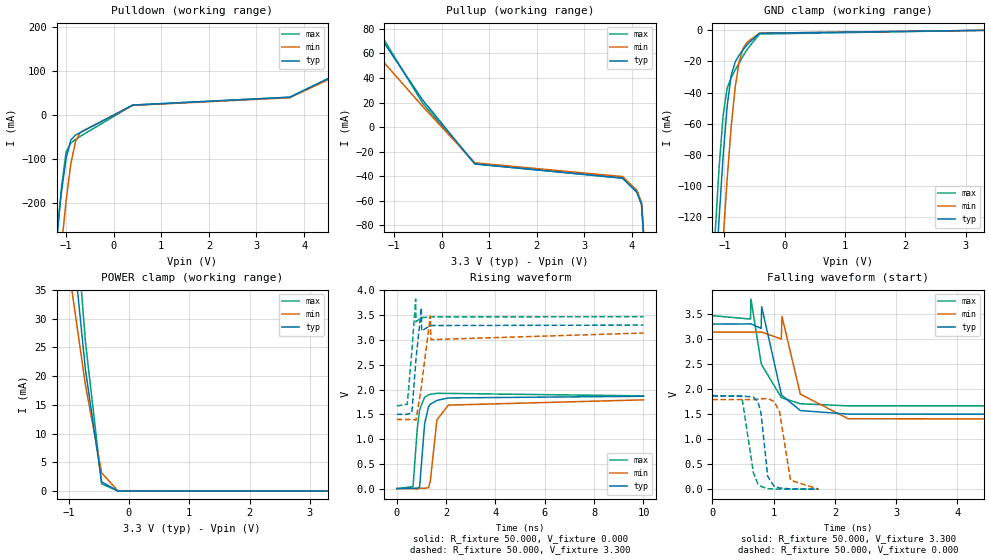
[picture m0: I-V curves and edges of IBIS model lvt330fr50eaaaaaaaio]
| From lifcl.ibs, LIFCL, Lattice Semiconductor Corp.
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[Model] lvt330fr50eaaaaaaaio
Model_type I/O
Polarity   Non-Inverting
Enable   Active-Low
Vinl =  0.800V
Vinh =  2.000V
Vmeas =  1.650V
Cref =  0.0F
Rref =  1.000M
Vref =  0.0V
C_comp   5.000pF   4.000pF   5.500pF
[Temperature Range]   25.000   0.125k   -40.000
[Voltage Range]   3.300V   3.140V   3.470V
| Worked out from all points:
|   slope of the pulldown table from 0 to 0.495 V, typ, clamps not added: 18.8 ohm
|   slope of the pullup table from 0 to 0.495 V, typ, clamps not added: 21.2 ohm
|   GND clamp passes 1 mA (typ) near -0.37 V on its own axis
|   POWER clamp passes 1 mA (typ) near -0.42 V on its own axis
|   rising waveform, R_fixture 50.000, V_fixture 0.000: 20-80 % time 189ps typ, 251ps min, 172ps max; typ from 0 V to 1.86 V
|   rising waveform, R_fixture 50.000, V_fixture 3.300: 20-80 % time 158ps typ, 181ps min, 159ps max; typ from 1.5 V to 3.3 V
|   falling waveform, R_fixture 50.000, V_fixture 3.300: 20-80 % time 246ps typ, 273ps min, 273ps max; typ from 3.3 V to 1.5 V
|   falling waveform, R_fixture 50.000, V_fixture 0.000: 20-80 % time 90.5ps typ, 117ps min, 120ps max; typ from 1.86 V to 0 V
[GND_clamp]
|Voltage   I(typ)   I(min)   I(max)
-3.3V     -1.887A    -1.873A    -1.902A
-1.156V   -166.9mA   -224mA     -132.1mA
-1.089V   -121.5mA   -178.4mA   -88.64mA
-1.022V   -81.05mA   -135.2mA   -54.94mA
-955mV    -48.98mA   -95.79mA   -37.15mA
-888mV    -28.98mA   -62.05mA   -30.42mA
-821mV    -20.23mA   -36.35mA   -25.49mA
-754mV    -15.89mA   -19.89mA   -20.81mA
-687mV    -12.34mA   -11.44mA   -16.31mA
-620mV    -9.094mA   -7.515mA   -12.09mA
-419mV    -1.869mA   -1.836mA   -2.383mA
3.3V      0A         0A         0A
[POWER_clamp]
|Voltage   I(typ)   I(min)   I(max)
-3.3V     170.3mA    115.9mA    227.4mA
-2.998V   139.6mA    100.3mA    196.3mA
-2.797V   125.9mA    92.2mA     179.4mA
-2.596V   123.5mA    86.45mA    171.5mA
-1.993V   123.5mA    84.93mA    171.5mA
-1.792V   123.5mA    84.93mA    159.6mA
-1.658V   116.4mA    83.68mA    147.1mA
-1.457V   98.28mA    72.65mA    124.1mA
-720mV    21.08mA    18.41mA    25.96mA
-452mV    1.573mA    3.148mA    1.229mA
-184mV    5.589uA    37.85uA    1.612uA
3.3V      0A         0A         0A
[Pulldown]
|Voltage   I(typ)   I(min)   I(max)
-3.3V     -2.705A    -3.161A    -3.578A
-1.2V     -276.6mA   -417.7mA   -294.4mA
-1.1V     -178.2mA   -301.6mA   -167mA
-1V       -98.8mA    -195.7mA   -84.47mA
-900mV    -56.61mA   -110.6mA   -63.45mA
-800mV    -45.22mA   -59.56mA   -55.68mA
-700mV    -39.68mA   -39.07mA   -48.23mA
400mV     22.65mA    21.97mA    22.65mA
3.7V      40.5mA     39.29mA    40.5mA
5.4V      129.6mA    125.7mA    129.6mA
6.1V      147.3mA    142.9mA    147.3mA
6.6V      199.6mA    193.6mA    199.6mA
[Pullup]
|Voltage   I(typ)   I(min)   I(max)
-3.3V     145.8mA    91.6mA     185mA
-2.8V     101.3mA    78.1mA     135.2mA
-2.7V     97.9mA     76.3mA     125.2mA
-2.5V     97mA       74.2mA     108.2mA
-1.7V     97mA       74.2mA     102.6mA
-400mV    22.21mA    16.98mA    19.58mA
700mV     -29.95mA   -29.05mA   -29.95mA
3.8V      -41.5mA    -40.26mA   -41.5mA
4.1V      -52.86mA   -51.28mA   -52.86mA
4.2V      -62.95mA   -61.07mA   -62.95mA
4.4V      -181.4mA   -176mA     -181.4mA
6.6V      -2.716A    -2.634A    -2.716A
[Ramp]
| variable   typ   min   max
dV/dt_r   1.114/0.188n   1.042/0.252n   1.122/0.171n
dV/dt_f   1.080/0.258n   1.047/0.280n   1.051/0.261n
R_load = 50.000
[Rising Waveform]
R_fixture = 50.000
V_fixture = 0.000
V_fixture_min = 0.000
V_fixture_max = 0.000
|  time   V(typ)   V(min)   V(max)
0s        377.2uV    1.038mV    347.4uV
659ps     7.312mV    1.207mV    39.78mV
830ps     10.37mV    -11.19mV   1.209V
925ps     30.48mV    9.316mV    1.594V
1.129ns   1.308V     5.562mV    1.843V
1.285ns   1.649V     19.08mV    1.892V
1.358ns   1.702V     145.7mV    1.904V
1.627ns   1.78V      1.387V     1.922V
2.092ns   1.83V      1.685V     1.921V
10ns      1.863V     1.791V     1.871V
[Rising Waveform]
R_fixture = 50.000
V_fixture = 3.300
V_fixture_min = 3.140
V_fixture_max = 3.470
|  time   V(typ)   V(min)   V(max)
0s        1.499V     1.395V     1.668V
425ps     1.5V       1.395V     1.702V
609ps     1.528V     1.396V     2.758V
766ps     2.524V     1.387V     3.825V
776ps     2.601V     1.382V     3.365V
996ps     3.649V     2.042V     3.449V
1.006ns   3.184V     2.104V     3.45V
1.361ns   3.291V     3.482V     3.464V
1.381ns   3.291V     3.007V     3.464V
10ns      3.3V       3.14V      3.47V
[Falling Waveform]
R_fixture = 50.000
V_fixture = 3.300
V_fixture_min = 3.140
V_fixture_max = 3.470
|  time   V(typ)   V(min)   V(max)
0s        3.3V       3.14V      3.47V
622ps     3.305V     3.141V     3.401V
630ps     3.305V     3.141V     3.801V
796ps     3.215V     3.141V     2.519V
805ps     3.648V     3.142V     2.487V
1.126ns   1.898V     3.002V     1.832V
1.136ns   1.875V     3.455V     1.825V
1.436ns   1.572V     1.9V       1.708V
2.215ns   1.501V     1.409V     1.666V
10ns      1.499V     1.395V     1.668V
[Falling Waveform]
R_fixture = 50.000
V_fixture = 0.000
V_fixture_min = 0.000
V_fixture_max = 0.000
|  time   V(typ)   V(min)   V(max)
0s        1.863V     1.791V     1.871V
480ps     1.864V     1.791V     1.854V
671ps     1.839V     1.792V     324mV
744ps     1.749V     1.798V     101.3mV
794ps     1.52V      1.806V     54.95mV
903ps     259mV      1.812V     11.54mV
1.006ns   60.22mV    1.757V     3.574mV
1.096ns   24.66mV    1.552V     1.787mV
1.276ns   4.022mV    178.9mV    677.5uV
1.731ns   377.2uV    1.038mV    347.4uV
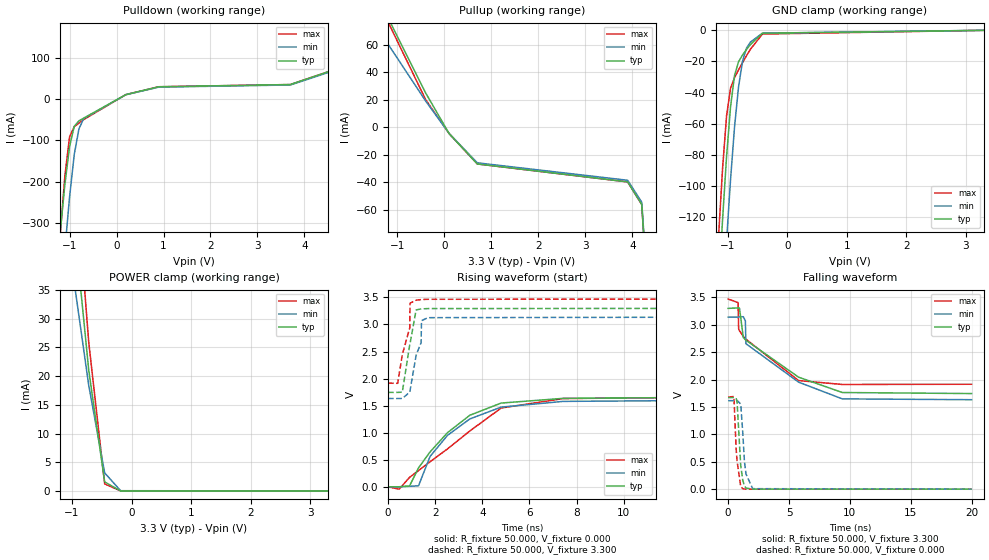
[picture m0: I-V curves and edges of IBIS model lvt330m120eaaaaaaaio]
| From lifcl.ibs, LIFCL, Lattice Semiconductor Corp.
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[Model] lvt330m120eaaaaaaaio
Model_type I/O
Polarity   Non-Inverting
Enable   Active-Low
Vinl =  0.800V
Vinh =  2.000V
Vmeas =  1.650V
Cref =  0.0F
Rref =  1.000M
Vref =  0.0V
C_comp   5.000pF   4.000pF   5.500pF
[Temperature Range]   25.000   0.125k   -40.000
[Voltage Range]   3.300V   3.140V   3.470V
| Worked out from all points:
|   slope of the pulldown table from 0 to 0.495 V, typ, clamps not added: 21.8 ohm
|   slope of the pullup table from 0 to 0.495 V, typ, clamps not added: 23.8 ohm
|   GND clamp passes 1 mA (typ) near -0.37 V on its own axis
|   POWER clamp passes 1 mA (typ) near -0.42 V on its own axis
|   rising waveform, R_fixture 50.000, V_fixture 0.000: 20-80 % time 2.26ns typ, 2.11ns min, 3ns max; typ from 0 V to 1.67 V
|   rising waveform, R_fixture 50.000, V_fixture 3.300: 20-80 % time 367ps typ, 414ps min, 378ps max; typ from 1.75 V to 3.3 V
|   falling waveform, R_fixture 50.000, V_fixture 3.300: 20-80 % time 4.62ns typ, 4.49ns min, 3.17ns max; typ from 3.3 V to 1.75 V
|   falling waveform, R_fixture 50.000, V_fixture 0.000: 20-80 % time 264ps typ, 296ps min, 268ps max; typ from 1.67 V to 0 V
[GND_clamp]
|Voltage   I(typ)   I(min)   I(max)
-3.3V     -1.887A    -1.873A    -1.902A
-1.156V   -166.9mA   -224mA     -132.1mA
-1.089V   -121.5mA   -178.4mA   -88.64mA
-1.022V   -81.05mA   -135.2mA   -54.94mA
-955mV    -48.98mA   -95.79mA   -37.15mA
-888mV    -28.98mA   -62.05mA   -30.42mA
-821mV    -20.23mA   -36.35mA   -25.49mA
-754mV    -15.89mA   -19.89mA   -20.81mA
-687mV    -12.34mA   -11.44mA   -16.31mA
-620mV    -9.094mA   -7.515mA   -12.09mA
-419mV    -1.869mA   -1.836mA   -2.383mA
3.3V      0A         0A         0A
[POWER_clamp]
|Voltage   I(typ)   I(min)   I(max)
-3.3V     170.3mA    115.9mA    227.4mA
-2.998V   139.6mA    100.3mA    196.3mA
-2.797V   125.9mA    92.2mA     179.4mA
-2.596V   123.5mA    86.45mA    171.5mA
-1.993V   123.5mA    84.93mA    171.5mA
-1.792V   123.5mA    84.93mA    159.6mA
-1.658V   116.4mA    83.68mA    147.1mA
-1.457V   98.28mA    72.65mA    124.1mA
-720mV    21.08mA    18.41mA    25.96mA
-452mV    1.573mA    3.148mA    1.229mA
-184mV    5.589uA    37.85uA    1.612uA
3.3V      0A         0A         0A
[Pulldown]
|Voltage   I(typ)   I(min)   I(max)
-3.3V     -3.149A    -3.823A    -4.032A
-1.2V     -321.9mA   -505.2mA   -330.2mA
-1.1V     -207.3mA   -364.7mA   -186.1mA
-1V       -114.9mA   -236.7mA   -91.33mA
-900mV    -65.88mA   -133.8mA   -66.67mA
-800mV    -52.62mA   -72.03mA   -57.94mA
-700mV    -46.18mA   -47.25mA   -49.68mA
200mV     10.72mA    10.4mA     10.72mA
900mV     29.61mA    28.72mA    29.61mA
3.7V      34.93mA    33.89mA    34.93mA
6.1V      127.1mA    123.3mA    127.1mA
6.6V      172.1mA    166.9mA    172.1mA
[Pullup]
|Voltage   I(typ)   I(min)   I(max)
-3.3V     163.1mA    102.5mA    206.9mA
-2.9V     119.9mA    89.7mA     162.7mA
-2.6V     108.3mA    84mA       129.4mA
-1.8V     108.3mA    83mA       117.8mA
-1.5V     99.9mA     75.77mA    97.6mA
-400mV    24.85mA    19mA       19.99mA
100mV     -4.725mA   -4.584mA   -4.725mA
700mV     -26.75mA   -25.94mA   -26.75mA
3.9V      -39.8mA    -38.61mA   -39.8mA
4.2V      -56.21mA   -54.53mA   -56.21mA
4.4V      -161.9mA   -157mA     -161.9mA
6.6V      -2.425A    -2.352A    -2.425A
[Ramp]
| variable   typ   min   max
dV/dt_r   1.003/2.268n   0.993/2.123n   1.008/3.000n
dV/dt_f   0.933/4.538n   0.904/4.241n   0.901/3.309n
R_load = 50.000
[Rising Waveform]
R_fixture = 50.000
V_fixture = 0.000
V_fixture_min = 0.000
V_fixture_max = 0.000
|  time   V(typ)   V(min)   V(max)
0s        336.5uV    1.157mV    387.9uV
472ps     567.3uV    1.185mV    -43.33mV
913ps     16.38mV    9.563mV    175.1mV
1.293ns   350.5mV    18.77mV    300.4mV
1.783ns   645.1mV    561.7mV    463.4mV
2.523ns   1.001V     951.4mV    700.8mV
3.472ns   1.323V     1.255V     1.032V
4.8ns     1.548V     1.473V     1.456V
7.436ns   1.635V     1.579V     1.631V
20ns      1.672V     1.615V     1.681V
[Rising Waveform]
R_fixture = 50.000
V_fixture = 3.300
V_fixture_min = 3.140
V_fixture_max = 3.470
|  time   V(typ)   V(min)   V(max)
0s        1.745V     1.633V     1.915V
408ps     1.745V     1.632V     1.913V
605ps     1.75V      1.633V     2.443V
921ps     2.629V     1.75V      2.94V
933ps     2.648V     1.776V     3.394V
1.191ns   3.269V     2.433V     3.449V
1.401ns   3.288V     2.663V     3.46V
1.421ns   3.289V     3.071V     3.461V
1.691ns   3.294V     3.126V     3.466V
20ns      3.3V       3.14V      3.47V
[Falling Waveform]
R_fixture = 50.000
V_fixture = 3.300
V_fixture_min = 3.140
V_fixture_max = 3.470
|  time   V(typ)   V(min)   V(max)
0s        3.3V       3.14V      3.47V
812ps     3.308V     3.141V     3.406V
863ps     3.31V      3.142V     2.926V
933ps     3.302V     3.145V     2.89V
1.246ns   2.767V     3.148V     2.789V
1.416ns   2.727V     3.071V     2.748V
1.456ns   2.719V     2.656V     2.738V
5.79ns    2.044V     1.953V     1.982V
9.38ns    1.764V     1.648V     1.911V
20ns      1.745V     1.633V     1.915V
[Falling Waveform]
R_fixture = 50.000
V_fixture = 0.000
V_fixture_min = 0.000
V_fixture_max = 0.000
|  time   V(typ)   V(min)   V(max)
0s        1.672V     1.615V     1.681V
470ps     1.673V     1.615V     1.691V
657ps     1.661V     1.615V     728mV
733ps     1.586V     1.62V      514.9mV
1.033ns   427.1mV    1.554V     47.86mV
1.199ns   165mV      1.034V     9.178mV
1.337ns   58.39mV    506.5mV    2.487mV
1.466ns   19.86mV    276.8mV    860.1uV
2.014ns   960.8uV    8.907mV    -151.5uV
20ns      336.5uV    1.157mV    387.9uV
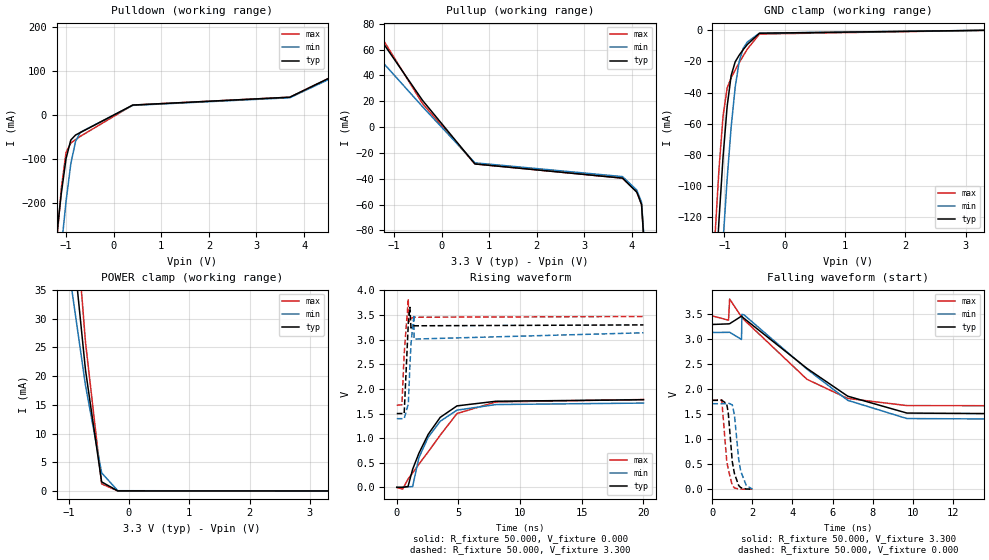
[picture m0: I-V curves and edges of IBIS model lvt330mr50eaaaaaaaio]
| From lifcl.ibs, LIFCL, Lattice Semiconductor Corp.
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[Model] lvt330mr50eaaaaaaaio
Model_type I/O
Polarity   Non-Inverting
Enable   Active-Low
Vinl =  0.800V
Vinh =  2.000V
Vmeas =  1.650V
Cref =  0.0F
Rref =  1.000M
Vref =  0.0V
C_comp   5.000pF   4.000pF   5.500pF
[Temperature Range]   25.000   0.125k   -40.000
[Voltage Range]   3.300V   3.140V   3.470V
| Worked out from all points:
|   slope of the pulldown table from 0 to 0.495 V, typ, clamps not added: 18.8 ohm
|   slope of the pullup table from 0 to 0.495 V, typ, clamps not added: 22.3 ohm
|   GND clamp passes 1 mA (typ) near -0.37 V on its own axis
|   POWER clamp passes 1 mA (typ) near -0.42 V on its own axis
|   rising waveform, R_fixture 50.000, V_fixture 0.000: 20-80 % time 2.26ns typ, 2.11ns min, 3.15ns max; typ from 0 V to 1.78 V
|   rising waveform, R_fixture 50.000, V_fixture 3.300: 20-80 % time 157ps typ, 180ps min, 164ps max; typ from 1.5 V to 3.3 V
|   falling waveform, R_fixture 50.000, V_fixture 3.300: 20-80 % time 3.71ns typ, 3.34ns min, 3.1ns max; typ from 3.3 V to 1.5 V
|   falling waveform, R_fixture 50.000, V_fixture 0.000: 20-80 % time 264ps typ, 292ps min, 265ps max; typ from 1.78 V to 0 V
[GND_clamp]
|Voltage   I(typ)   I(min)   I(max)
-3.3V     -1.887A    -1.873A    -1.902A
-1.156V   -166.9mA   -224mA     -132.1mA
-1.089V   -121.5mA   -178.4mA   -88.64mA
-1.022V   -81.05mA   -135.2mA   -54.94mA
-955mV    -48.98mA   -95.79mA   -37.15mA
-888mV    -28.98mA   -62.05mA   -30.42mA
-821mV    -20.23mA   -36.35mA   -25.49mA
-754mV    -15.89mA   -19.89mA   -20.81mA
-687mV    -12.34mA   -11.44mA   -16.31mA
-620mV    -9.094mA   -7.515mA   -12.09mA
-419mV    -1.869mA   -1.836mA   -2.383mA
3.3V      0A         0A         0A
[POWER_clamp]
|Voltage   I(typ)   I(min)   I(max)
-3.3V     170.3mA    115.9mA    227.4mA
-2.998V   139.6mA    100.3mA    196.3mA
-2.797V   125.9mA    92.2mA     179.4mA
-2.596V   123.5mA    86.45mA    171.5mA
-1.993V   123.5mA    84.93mA    171.5mA
-1.792V   123.5mA    84.93mA    159.6mA
-1.658V   116.4mA    83.68mA    147.1mA
-1.457V   98.28mA    72.65mA    124.1mA
-720mV    21.08mA    18.41mA    25.96mA
-452mV    1.573mA    3.148mA    1.229mA
-184mV    5.589uA    37.85uA    1.612uA
3.3V      0A         0A         0A
[Pulldown]
|Voltage   I(typ)   I(min)   I(max)
-3.3V     -2.705A    -3.161A    -3.578A
-1.2V     -276.6mA   -417.7mA   -294.4mA
-1.1V     -178.2mA   -301.6mA   -167mA
-1V       -98.8mA    -195.7mA   -84.47mA
-900mV    -56.61mA   -110.6mA   -63.45mA
-800mV    -45.22mA   -59.56mA   -55.68mA
-700mV    -39.68mA   -39.07mA   -48.23mA
400mV     22.65mA    21.97mA    22.65mA
3.7V      40.5mA     39.29mA    40.5mA
5.4V      129.6mA    125.7mA    129.6mA
6.1V      147.3mA    142.9mA    147.3mA
6.6V      199.6mA    193.6mA    199.6mA
[Pullup]
|Voltage   I(typ)   I(min)   I(max)
-3.3V     136mA      85.3mA     172.6mA
-2.8V     94.6mA     72.8mA     126.2mA
-2.7V     91.3mA     71.2mA     116.8mA
-2.5V     90.4mA     69.2mA     101mA
-1.7V     90.4mA     69.2mA     95.8mA
-400mV    20.72mA    15.84mA    18.27mA
700mV     -28.48mA   -27.62mA   -28.48mA
3.8V      -39.46mA   -38.28mA   -39.46mA
4.1V      -50.26mA   -48.75mA   -50.26mA
4.2V      -59.86mA   -58.06mA   -59.86mA
4.4V      -172.4mA   -167.2mA   -172.4mA
6.6V      -2.582A    -2.504A    -2.582A
[Ramp]
| variable   typ   min   max
dV/dt_r   1.064/2.268n   0.993/2.123n   1.109/3.147n
dV/dt_f   1.080/4.540n   1.047/4.241n   1.047/3.644n
R_load = 50.000
[Rising Waveform]
R_fixture = 50.000
V_fixture = 0.000
V_fixture_min = 0.000
V_fixture_max = 0.000
|  time   V(typ)   V(min)   V(max)
0s        377.2uV    1.038mV    347.4uV
472ps     569.5uV    1.068mV    -36.95mV
913ps     17.54mV    9.945mV    168.9mV
1.283ns   365.4mV    16.3mV     292.9mV
1.794ns   692.8mV    603.6mV    470.4mV
2.547ns   1.077V     1.018V     721.3mV
3.522ns   1.422V     1.342V     1.06V
4.883ns   1.655V     1.569V     1.5V
8.039ns   1.749V     1.682V     1.735V
20ns      1.78V      1.712V     1.784V
[Rising Waveform]
R_fixture = 50.000
V_fixture = 3.300
V_fixture_min = 3.140
V_fixture_max = 3.470
|  time   V(typ)   V(min)   V(max)
0s        1.499V     1.395V     1.668V
416ps     1.5V       1.395V     1.678V
599ps     1.496V     1.396V     2.705V
934ps     3.327V     1.697V     3.825V
951ps     3.383V     1.779V     3.361V
1.064ns   3.657V     2.476V     3.413V
1.152ns   3.238V     2.912V     3.433V
1.387ns   3.281V     3.506V     3.455V
1.401ns   3.282V     3.012V     3.456V
20ns      3.3V       3.14V      3.47V
[Falling Waveform]
R_fixture = 50.000
V_fixture = 3.300
V_fixture_min = 3.140
V_fixture_max = 3.470
|  time   V(typ)   V(min)   V(max)
0s        3.3V       3.14V      3.47V
808ps     3.312V     3.142V     3.386V
863ps     3.315V     3.144V     3.809V
1.456ns   3.467V     2.999V     3.45V
1.476ns   3.459V     3.503V     3.441V
1.576ns   3.423V     3.494V     3.396V
4.724ns   2.42V      2.405V     2.201V
6.76ns    1.863V     1.78V      1.818V
9.716ns   1.525V     1.415V     1.675V
20ns      1.499V     1.395V     1.668V
[Falling Waveform]
R_fixture = 50.000
V_fixture = 0.000
V_fixture_min = 0.000
V_fixture_max = 0.000
|  time   V(typ)   V(min)   V(max)
0s        1.78V      1.712V     1.784V
469ps     1.78V      1.712V     1.79V
713ps     1.715V     1.715V     584.9mV
793ps     1.533V     1.726V     397.6mV
996ps     547.3mV    1.689V     74.47mV
1.103ns   312.5mV    1.486V     24.8mV
1.314ns   74.44mV    601.1mV    3.478mV
1.414ns   31.93mV    363.3mV    1.641mV
1.694ns   3.358mV    75.28mV    435.7uV
2.005ns   377.2uV    1.038mV    347.4uV
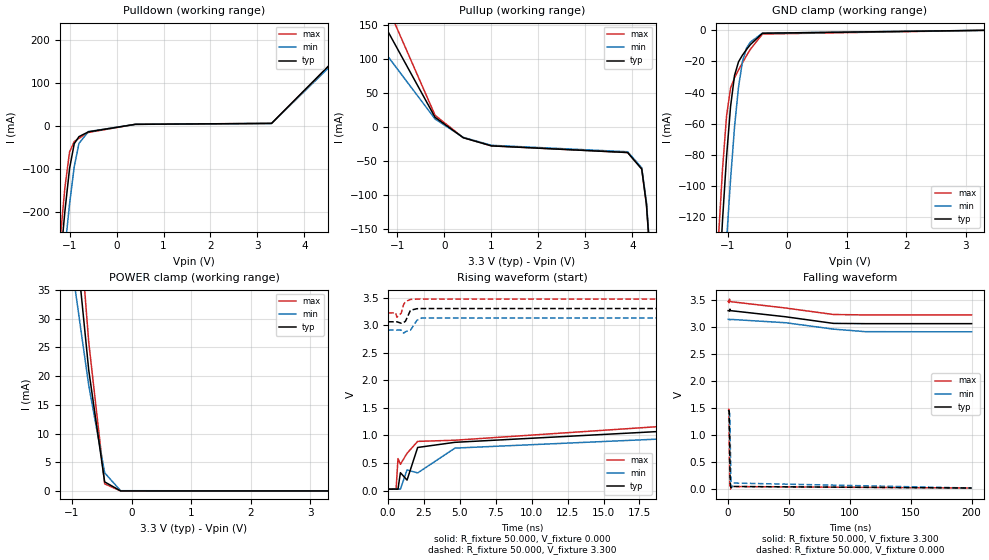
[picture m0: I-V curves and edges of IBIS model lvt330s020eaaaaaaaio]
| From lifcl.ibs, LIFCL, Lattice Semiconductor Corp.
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[Model] lvt330s020eaaaaaaaio
Model_type I/O
Polarity   Non-Inverting
Enable   Active-Low
Vinl =  0.800V
Vinh =  2.000V
Vmeas =  1.650V
Cref =  0.0F
Rref =  1.000M
Vref =  0.0V
C_comp   5.000pF   4.000pF   5.500pF
[Temperature Range]   25.000   0.125k   -40.000
[Voltage Range]   3.300V   3.140V   3.470V
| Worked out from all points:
|   slope of the pulldown table from 0 to 0.495 V, typ, clamps not added: 109 ohm
|   slope of the pullup table from 0 to 0.495 V, typ, clamps not added: 26.9 ohm
|   GND clamp passes 1 mA (typ) near -0.37 V on its own axis
|   POWER clamp passes 1 mA (typ) near -0.42 V on its own axis
|   rising waveform, R_fixture 50.000, V_fixture 0.000: 20-80 % time 24ns typ, 34.7ns min, 18.7ns max; typ from 0.025 V to 1.45 V
|   rising waveform, R_fixture 50.000, V_fixture 3.300: 20-80 % time 218ps typ, 298ps min, 218ps max; typ from 3.06 V to 3.3 V
|   falling waveform, R_fixture 50.000, V_fixture 3.300: 20-80 % time 42.3ns typ, 48.9ns min, 46.8ns max; typ from 3.3 V to 3.06 V
|   falling waveform, R_fixture 50.000, V_fixture 0.000: 20-80 % time 480ps typ, 680ps min, 393ps max; typ from 1.45 V to 0.025 V
[GND_clamp]
|Voltage   I(typ)   I(min)   I(max)
-3.3V     -1.887A    -1.873A    -1.902A
-1.156V   -166.9mA   -224mA     -132.1mA
-1.089V   -121.5mA   -178.4mA   -88.64mA
-1.022V   -81.05mA   -135.2mA   -54.94mA
-955mV    -48.98mA   -95.79mA   -37.15mA
-888mV    -28.98mA   -62.05mA   -30.42mA
-821mV    -20.23mA   -36.35mA   -25.49mA
-754mV    -15.89mA   -19.89mA   -20.81mA
-687mV    -12.34mA   -11.44mA   -16.31mA
-620mV    -9.094mA   -7.515mA   -12.09mA
-419mV    -1.869mA   -1.836mA   -2.383mA
3.3V      0A         0A         0A
[POWER_clamp]
|Voltage   I(typ)   I(min)   I(max)
-3.3V     170.3mA    115.9mA    227.4mA
-2.998V   139.6mA    100.3mA    196.3mA
-2.797V   125.9mA    92.2mA     179.4mA
-2.596V   123.5mA    86.45mA    171.5mA
-1.993V   123.5mA    84.93mA    171.5mA
-1.792V   123.5mA    84.93mA    159.6mA
-1.658V   116.4mA    83.68mA    147.1mA
-1.457V   98.28mA    72.65mA    124.1mA
-720mV    21.08mA    18.41mA    25.96mA
-452mV    1.573mA    3.148mA    1.229mA
-184mV    5.589uA    37.85uA    1.612uA
3.3V      0A         0A         0A
[Pulldown]
|Voltage   I(typ)   I(min)   I(max)
-3.3V     -3.198A    -3.088A    -3.286A
-1.2V     -320.1mA   -403.9mA   -266.3mA
-1.1V     -200.2mA   -288.6mA   -145.1mA
-1V       -99.68mA   -182.4mA   -61.1mA
-900mV    -41.7mA    -95.18mA   -37.11mA
-800mV    -25.46mA   -41.35mA   -29.28mA
-600mV    -14.31mA   -13.67mA   -15.59mA
400mV     3.234mA    3.137mA    3.234mA
3.3V      5.419mA    5.256mA    5.419mA
5V        192.3mA    186.5mA    192.3mA
6.3V      201.8mA    195.7mA    201.8mA
6.6V      230.5mA    223.6mA    230.5mA
[Pullup]
|Voltage   I(typ)   I(min)   I(max)
-3.3V     225.4mA    159.1mA    289.5mA
-2.6V     172mA      126.4mA    227.2mA
-1.5V     172mA      124.8mA    215mA
-1.3V     152.6mA    112.6mA    190.7mA
-200mV    14.46mA    11.99mA    17.47mA
400mV     -15.49mA   -15.03mA   -15.49mA
1V        -27.48mA   -26.65mA   -27.48mA
3.9V      -37.26mA   -36.14mA   -37.26mA
4.2V      -61.49mA   -59.65mA   -61.49mA
4.3V      -113.5mA   -110.1mA   -113.5mA
4.4V      -210.4mA   -204.1mA   -210.4mA
6.6V      -3.205A    -3.109A    -3.205A
[Ramp]
| variable   typ   min   max
dV/dt_r   0.841/24.619n   0.828/35.559n   0.858/18.674n
dV/dt_f   0.144/42.436n   0.139/49.064n   0.150/46.882n
R_load = 50.000
[Rising Waveform]
R_fixture = 50.000
V_fixture = 0.000
V_fixture_min = 0.000
V_fixture_max = 0.000
|  time   V(typ)   V(min)   V(max)
0s        25.4mV     24.94mV    25.4mV
560ps     25.54mV    25.03mV    26.53mV
690ps     24.52mV    24.64mV    578.7mV
860ps     323.5mV    25.32mV    475.7mV
1.32ns    188.9mV    373.3mV    675.2mV
2.06ns    780.8mV    319.1mV    890.8mV
4.66ns    874.3mV    769.4mV    912.3mV
31.5ns    1.245V     1.079V     1.38V
72.96ns   1.432V     1.372V     1.44V
200ns     1.452V     1.405V     1.455V
[Rising Waveform]
R_fixture = 50.000
V_fixture = 3.300
V_fixture_min = 3.140
V_fixture_max = 3.470
|  time   V(typ)   V(min)   V(max)
0s        3.06V      2.909V     3.221V
530ps     3.06V      2.909V     3.223V
610ps     3.06V      2.909V     3.142V
910ps     3.034V     2.91V      3.213V
1.08ns    3.045V     2.854V     3.371V
1.21ns    3.07V      2.88V      3.426V
1.56ns    3.269V     2.908V     3.465V
2.01ns    3.297V     3.087V     3.471V
2.33ns    3.3V       3.128V     3.472V
200ns     3.3V       3.14V      3.47V
[Falling Waveform]
R_fixture = 50.000
V_fixture = 3.300
V_fixture_min = 3.140
V_fixture_max = 3.470
|  time   V(typ)   V(min)   V(max)
0s        3.3V       3.14V      3.47V
680ps     3.3V       3.139V     3.48V
760ps     3.3V       3.141V     3.443V
1.09ns    3.29V      3.14V      3.514V
1.49ns    3.328V     3.126V     3.472V
1.97ns    3.3V       3.139V     3.466V
47.18ns   3.187V     3.077V     3.349V
86.45ns   3.065V     2.959V     3.229V
112.8ns   3.06V      2.912V     3.221V
200ns     3.06V      2.909V     3.221V
[Falling Waveform]
R_fixture = 50.000
V_fixture = 0.000
V_fixture_min = 0.000
V_fixture_max = 0.000
|  time   V(typ)   V(min)   V(max)
0s        1.452V     1.405V     1.455V
630ps     1.452V     1.405V     1.479V
880ps     1.449V     1.406V     916.2mV
1.26ns    742mV      1.407V     205.3mV
1.57ns    250.8mV    1.07V      42.33mV
1.91ns    56.56mV    667mV      4.242mV
2.35ns    33.6mV     130mV      28.17mV
2.71ns    47.45mV    31.11mV    55.71mV
4.91ns    53.88mV    117mV      51.82mV
200ns     25.15mV    24.94mV    25.4mV
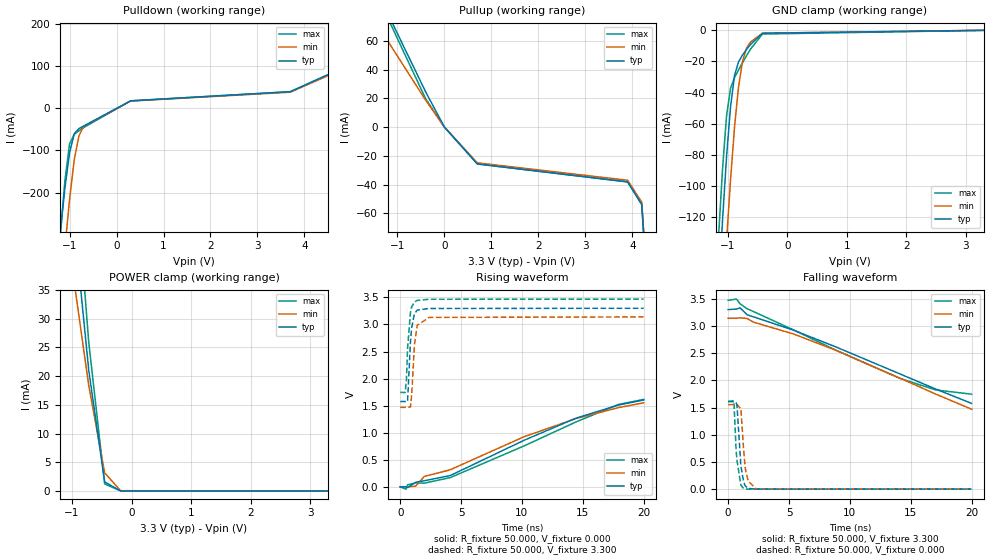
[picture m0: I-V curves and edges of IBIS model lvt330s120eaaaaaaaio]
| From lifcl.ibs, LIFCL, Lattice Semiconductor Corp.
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[Model] lvt330s120eaaaaaaaio
Model_type I/O
Polarity   Non-Inverting
Enable   Active-Low
Vinl =  0.800V
Vinh =  2.000V
Vmeas =  1.650V
Cref =  0.0F
Rref =  1.000M
Vref =  0.0V
C_comp   5.000pF   4.000pF   5.500pF
[Temperature Range]   25.000   0.125k   -40.000
[Voltage Range]   3.300V   3.140V   3.470V
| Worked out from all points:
|   slope of the pulldown table from 0 to 0.495 V, typ, clamps not added: 19.6 ohm
|   slope of the pullup table from 0 to 0.495 V, typ, clamps not added: 24.8 ohm
|   GND clamp passes 1 mA (typ) near -0.37 V on its own axis
|   POWER clamp passes 1 mA (typ) near -0.42 V on its own axis
|   rising waveform, R_fixture 50.000, V_fixture 0.000: 20-80 % time 9.3ns typ, 10.1ns min, 9.69ns max; typ from 0 V to 1.6 V
|   rising waveform, R_fixture 50.000, V_fixture 3.300: 20-80 % time 253ps typ, 287ps min, 249ps max; typ from 1.58 V to 3.3 V
|   falling waveform, R_fixture 50.000, V_fixture 3.300: 20-80 % time 11.2ns typ, 10.5ns min, 10ns max; typ from 3.3 V to 1.58 V
|   falling waveform, R_fixture 50.000, V_fixture 0.000: 20-80 % time 287ps typ, 322ps min, 284ps max; typ from 1.6 V to 0 V
[GND_clamp]
|Voltage   I(typ)   I(min)   I(max)
-3.3V     -1.887A    -1.873A    -1.902A
-1.156V   -166.9mA   -224mA     -132.1mA
-1.089V   -121.5mA   -178.4mA   -88.64mA
-1.022V   -81.05mA   -135.2mA   -54.94mA
-955mV    -48.98mA   -95.79mA   -37.15mA
-888mV    -28.98mA   -62.05mA   -30.42mA
-821mV    -20.23mA   -36.35mA   -25.49mA
-754mV    -15.89mA   -19.89mA   -20.81mA
-687mV    -12.34mA   -11.44mA   -16.31mA
-620mV    -9.094mA   -7.515mA   -12.09mA
-419mV    -1.869mA   -1.836mA   -2.383mA
3.3V      0A         0A         0A
[POWER_clamp]
|Voltage   I(typ)   I(min)   I(max)
-3.3V     170.3mA    115.9mA    227.4mA
-2.998V   139.6mA    100.3mA    196.3mA
-2.797V   125.9mA    92.2mA     179.4mA
-2.596V   123.5mA    86.45mA    171.5mA
-1.993V   123.5mA    84.93mA    171.5mA
-1.792V   123.5mA    84.93mA    159.6mA
-1.658V   116.4mA    83.68mA    147.1mA
-1.457V   98.28mA    72.65mA    124.1mA
-720mV    21.08mA    18.41mA    25.96mA
-452mV    1.573mA    3.148mA    1.229mA
-184mV    5.589uA    37.85uA    1.612uA
3.3V      0A         0A         0A
[Pulldown]
|Voltage   I(typ)   I(min)   I(max)
-3.3V     -2.9A      -3.494A    -3.741A
-1.2V     -296.5mA   -461.8mA   -306.4mA
-1.1V     -190.9mA   -333.3mA   -172.7mA
-1V       -105.8mA   -216.3mA   -84.75mA
-900mV    -60.68mA   -122.3mA   -61.87mA
-800mV    -48.47mA   -65.84mA   -53.77mA
-700mV    -42.53mA   -43.19mA   -46.1mA
300mV     17.14mA    16.62mA    17.14mA
3.7V      38.76mA    37.6mA     38.76mA
5.4V      124mA      120.3mA    124mA
6.1V      141mA      136.8mA    141mA
6.6V      191mA      185.3mA    191mA
[Pullup]
|Voltage   I(typ)   I(min)   I(max)
-3.3V     161.5mA    101.5mA    205mA
-2.9V     118.7mA    88.9mA     161.2mA
-2.6V     107.3mA    83.1mA     128.2mA
-1.8V     107.3mA    82.2mA     116.7mA
-1.5V     99mA       75.05mA    96.6mA
-400mV    24.61mA    18.82mA    19.8mA
0V        28.23nA    226.3nA    28.23nA
700mV     -25.65mA   -24.88mA   -25.65mA
3.9V      -38.17mA   -37.03mA   -38.17mA
4.2V      -53.91mA   -52.29mA   -53.91mA
4.4V      -155.3mA   -150.6mA   -155.3mA
6.6V      -2.325A    -2.256A    -2.325A
[Ramp]
| variable   typ   min   max
dV/dt_r   0.964/9.286n   0.893/10.057n   0.969/9.681n
dV/dt_f   0.993/11.242n   1.003/10.537n   1.035/10.055n
R_load = 50.000
[Rising Waveform]
R_fixture = 50.000
V_fixture = 0.000
V_fixture_min = 0.000
V_fixture_max = 0.000
|  time   V(typ)   V(min)   V(max)
0s        358.2uV    1.072mV    359.1uV
471ps     602.5uV    1.1mV      -43.61mV
605ps     -14.7mV    1.213mV    37.39mV
1.263ns   83.32mV    11.75mV    71.54mV
1.983ns   112.5mV    192.8mV    68.28mV
4.088ns   205.9mV    313.2mV    168.3mV
10.15ns   857.2mV    923.2mV    753.4mV
14.43ns   1.268V     1.261V     1.198V
17.91ns   1.51V      1.462V     1.521V
20ns      1.605V     1.553V     1.615V
[Rising Waveform]
R_fixture = 50.000
V_fixture = 3.300
V_fixture_min = 3.140
V_fixture_max = 3.470
|  time   V(typ)   V(min)   V(max)
0s        1.576V     1.469V     1.745V
408ps     1.576V     1.468V     1.743V
510ps     1.577V     1.469V     1.988V
602ps     1.576V     1.47V      2.565V
843ps     2.692V     1.476V     3.229V
941ps     2.946V     1.712V     3.325V
1.171ns   3.2V       2.634V     3.416V
1.391ns   3.265V     2.984V     3.445V
2.368ns   3.296V     3.131V     3.466V
20ns      3.3V       3.14V      3.47V
[Falling Waveform]
R_fixture = 50.000
V_fixture = 3.300
V_fixture_min = 3.140
V_fixture_max = 3.470
|  time   V(typ)   V(min)   V(max)
0s        3.3V       3.14V      3.47V
688ps     3.309V     3.14V      3.493V
973ps     3.332V     3.149V     3.407V
1.567ns   3.204V     3.136V     3.314V
2.067ns   3.167V     3.07V      3.265V
5.387ns   2.92V      2.85V      2.924V
8.879ns   2.611V     2.549V     2.551V
14.12ns   2.117V     2.039V     2.035V
17.05ns   1.84V      1.747V     1.823V
20ns      1.576V     1.469V     1.745V
[Falling Waveform]
R_fixture = 50.000
V_fixture = 0.000
V_fixture_min = 0.000
V_fixture_max = 0.000
|  time   V(typ)   V(min)   V(max)
0s        1.605V     1.553V     1.615V
471ps     1.606V     1.553V     1.623V
657ps     1.595V     1.553V     704.6mV
726ps     1.532V     1.557V     528.2mV
1.046ns   422.9mV    1.475V     70.42mV
1.278ns   127mV      701mV      10.29mV
1.406ns   59.54mV    380mV      3.453mV
1.636ns   13.28mV    152.4mV    334uV
2.293ns   1.016mV    5.7mV      -310.3uV
20ns      358.2uV    1.072mV    359.1uV
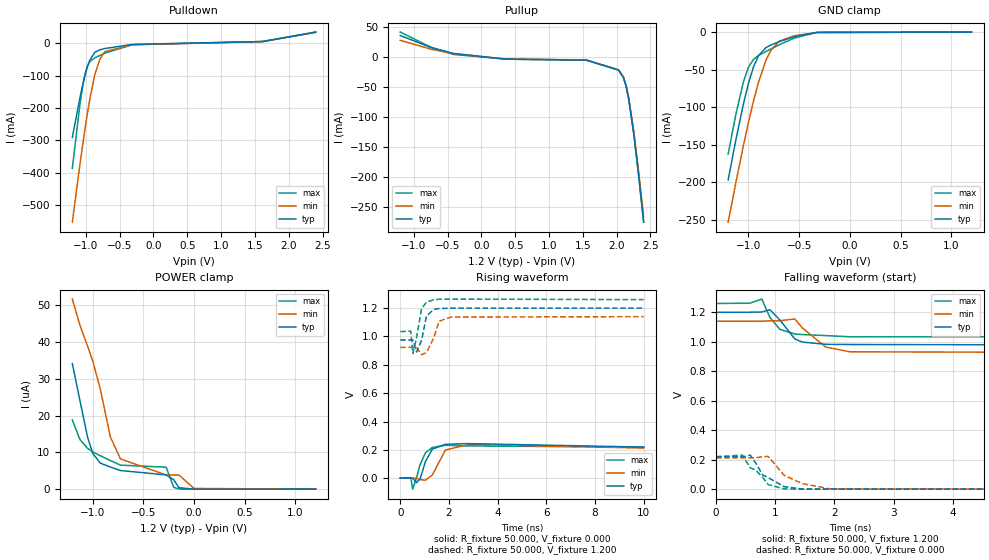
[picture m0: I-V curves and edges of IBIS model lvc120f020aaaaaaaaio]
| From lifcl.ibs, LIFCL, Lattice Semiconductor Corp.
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|Model lvc120f020aaaaaaaaio
[Model] lvc120f020aaaaaaaaio
Model_type I/O
Polarity   Non-Inverting
Enable   Active-Low
Vinl =  0.420V
Vinh =  0.780V
Vmeas =  0.600V
Cref =  0.0F
Rref =  1.000M
Vref =  0.0V
C_comp   5.000pF   4.000pF   5.500pF
[Temperature Range]   25.000   0.125k   -40.000
[Voltage Range]   1.200V   1.140V   1.260V
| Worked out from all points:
|   slope of the pulldown table from 0 to 0.18 V, typ, clamps not added: 97.7 ohm
|   slope of the pullup table from 0 to 0.18 V, typ, clamps not added: 89 ohm
|   GND clamp passes 1 mA (typ) near -0.37 V on its own axis
|   rising waveform, R_fixture 50.000, V_fixture 0.000: 20-80 % time 253ps typ, 327ps min, 285ps max; typ from 0 V to 0.219 V
|   rising waveform, R_fixture 50.000, V_fixture 1.200: 20-80 % time 174ps typ, 208ps min, 198ps max; typ from 0.975 V to 1.2 V
|   falling waveform, R_fixture 50.000, V_fixture 1.200: 20-80 % time 261ps typ, 389ps min, 241ps max; typ from 1.2 V to 0.975 V
|   falling waveform, R_fixture 50.000, V_fixture 0.000: 20-80 % time 370ps typ, 425ps min, 307ps max; typ from 0.219 V to 0 V
[GND_clamp]
|Voltage   I(typ)   I(min)   I(max)
-1.2V     -197mA     -253.2mA   -162.4mA
-1.125V   -144.2mA   -201.1mA   -110.1mA
-1.05V    -95.99mA   -151.4mA   -66.59mA
-1V       -68.36mA   -120.3mA   -46.7mA
-950mV    -46.27mA   -91.66mA   -36.22mA
-900mV    -31.17mA   -66.32mA   -31.23mA
-825mV    -20.42mA   -36.76mA   -25.67mA
-775mV    -17.01mA   -23.52mA   -22.16mA
-700mV    -12.93mA   -12.4mA    -17.08mA
-550mV    -6.031mA   -4.974mA   -8.039mA
-325mV    -407uA     -583.3uA   -420.6uA
1.2V      0A         0A         0A
[POWER_clamp]
|Voltage   I(typ)   I(min)   I(max)
-1.2V     34.12uA    51.64uA    18.84uA
-1.125V   24.08uA    44.51uA    13.48uA
-1.05V    14.15uA    38.9uA     11.09uA
-1V       9.797uA    34.91uA    10.18uA
-925mV    7.083uA    27.3uA     9.093uA
-825mV    6.019uA    14.19uA    7.781uA
-725mV    5.062uA    8.208uA    6.524uA
-275mV    3.872uA    3.86uA     5.968uA
-200mV    2.568uA    3.86uA     486.4nA
-150mV    410.4nA    3.86uA     46.48nA
0V        5.44nA     194.2nA    358.2pA
1.2V      0A         0A         0A
[Pulldown]
|Voltage   I(typ)   I(min)   I(max)
-1.2V     -291.3mA   -552.3mA   -386.2mA
-1.089V   -169.9mA   -376.3mA   -191.3mA
-1.052V   -133.7mA   -320.9mA   -138.7mA
-1.015V   -101mA     -267.7mA   -97.62mA
-978mV    -73.34mA   -217.5mA   -70.42mA
-941mV    -51.81mA   -171.5mA   -56.14mA
-867mV    -27.81mA   -96.38mA   -45.05mA
-793mV    -20.11mA   -48.94mA   -37.59mA
-719mV    -16.32mA   -25.85mA   -30.51mA
-312mV    -3.502mA   -4.516mA   -4.47mA
1.612V    5.286mA    5.127mA    5.286mA
2.4V      34.45mA    33.42mA    34.45mA
[Pullup]
|Voltage   I(typ)   I(min)   I(max)
-1.2V     36.04mA    28.03mA    41.8mA
-745mV    16.04mA    13.23mA    16.4mA
-412mV    6.21mA     5.595mA    4.51mA
365mV     -3.438mA   -3.335mA   -3.438mA
1.549V    -4.915mA   -4.768mA   -4.915mA
2.03V     -21.71mA   -21.06mA   -21.71mA
2.104V    -34.91mA   -33.87mA   -34.91mA
2.141V    -49.04mA   -47.57mA   -49.04mA
2.178V    -69.41mA   -67.32mA   -69.41mA
2.252V    -126.5mA   -122.7mA   -126.5mA
2.326V    -197.6mA   -191.7mA   -197.6mA
2.4V      -275.7mA   -267.4mA   -275.7mA
[Ramp]
| variable   typ   min   max
dV/dt_r   0.132/0.254n   0.127/0.330n   0.131/0.288n
dV/dt_f   0.134/0.264n   0.130/0.386n   0.135/0.242n
R_load = 50.000
[Rising Waveform]
R_fixture = 50.000
V_fixture = 0.000
V_fixture_min = 0.000
V_fixture_max = 0.000
|  time   V(typ)   V(min)   V(max)
0s        23.11uV    696.4uV    1mV
430ps     49.23uV    580.4uV    3.947mV
514ps     57.3uV     684.8uV    -77.41mV
663ps     -31.34mV   774.8uV    -595.1uV
814ps     -6.45mV    -9.582mV   94.96mV
1.033ns   115.9mV    -14.38mV   178.6mV
1.315ns   204.5mV    21.93mV    216.4mV
1.855ns   239.4mV    198.8mV    232.3mV
2.815ns   244.1mV    238.1mV    227.5mV
10ns      219.4mV    212.6mV    219.6mV
[Rising Waveform]
R_fixture = 50.000
V_fixture = 1.200
V_fixture_min = 1.140
V_fixture_max = 1.260
|  time   V(typ)   V(min)   V(max)
0s        975.4mV    923.3mV    1.034V
431ps     975.4mV    923.2mV    1.038V
519ps     975.4mV    923.3mV    879.5mV
667ps     890.2mV    923.4mV    988.8mV
876ps     972mV      871.7mV    1.196V
1.075ns   1.143V     885.7mV    1.242V
1.376ns   1.191V     989.3mV    1.259V
1.596ns   1.197V     1.108V     1.263V
2.085ns   1.2V       1.137V     1.264V
10ns      1.2V       1.14V      1.26V
[Falling Waveform]
R_fixture = 50.000
V_fixture = 1.200
V_fixture_min = 1.140
V_fixture_max = 1.260
|  time   V(typ)   V(min)   V(max)
0s        1.2V       1.14V      1.26V
574ps     1.201V     1.14V      1.262V
774ps     1.202V     1.139V     1.29V
910ps     1.218V     1.143V     1.166V
1.08ns    1.148V     1.143V     1.084V
1.332ns   1.019V     1.155V     1.053V
1.462ns   997.7mV    1.093V     1.049V
1.852ns   982.9mV    964.6mV    1.042V
2.262ns   981.4mV    932mV      1.034V
10ns      975.4mV    923.3mV    1.034V
[Falling Waveform]
R_fixture = 50.000
V_fixture = 0.000
V_fixture_min = 0.000
V_fixture_max = 0.000
|  time   V(typ)   V(min)   V(max)
0s        219.4mV    212.6mV    219.6mV
449ps     218.8mV    212.5mV    230.3mV
580ps     230.7mV    212.3mV    143.8mV
664ps     181mV      211.9mV    131.1mV
789ps     95.53mV    219.8mV    79.36mV
883ps     77.29mV    221.5mV    29.69mV
1.15ns    16.22mV    93.54mV    1.117mV
1.463ns   -280.5uV   36.09mV    -840.7uV
1.932ns   -886.1uV   1.117mV    -695uV
10ns      23.11uV    696.4uV    1mV
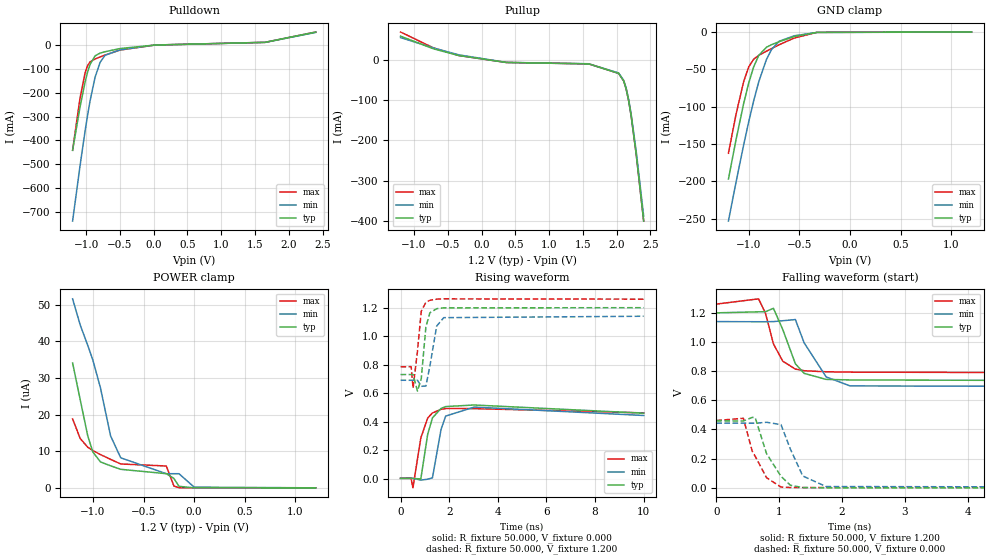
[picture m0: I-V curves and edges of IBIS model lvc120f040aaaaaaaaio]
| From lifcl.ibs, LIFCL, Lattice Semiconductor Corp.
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[Model] lvc120f040aaaaaaaaio
Model_type I/O
Polarity   Non-Inverting
Enable   Active-Low
Vinl =  0.420V
Vinh =  0.780V
Vmeas =  0.600V
Cref =  0.0F
Rref =  1.000M
Vref =  0.0V
C_comp   5.000pF   4.000pF   5.500pF
[Temperature Range]   25.000   0.125k   -40.000
[Voltage Range]   1.200V   1.140V   1.260V
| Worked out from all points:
|   slope of the pulldown table from 0 to 0.18 V, typ, clamps not added: 45.6 ohm
|   slope of the pullup table from 0 to 0.18 V, typ, clamps not added: 43.3 ohm
|   GND clamp passes 1 mA (typ) near -0.37 V on its own axis
|   rising waveform, R_fixture 50.000, V_fixture 0.000: 20-80 % time 246ps typ, 243ps min, 274ps max; typ from 0 V to 0.459 V
|   rising waveform, R_fixture 50.000, V_fixture 1.200: 20-80 % time 156ps typ, 259ps min, 149ps max; typ from 0.731 V to 1.2 V
|   falling waveform, R_fixture 50.000, V_fixture 1.200: 20-80 % time 264ps typ, 350ps min, 232ps max; typ from 1.2 V to 0.731 V
|   falling waveform, R_fixture 50.000, V_fixture 0.000: 20-80 % time 286ps typ, 251ps min, 271ps max; typ from 0.459 V to 0 V
[GND_clamp]
|Voltage   I(typ)   I(min)   I(max)
-1.2V     -197mA     -253.2mA   -162.4mA
-1.125V   -144.2mA   -201.1mA   -110.1mA
-1.05V    -95.99mA   -151.4mA   -66.59mA
-1V       -68.36mA   -120.3mA   -46.7mA
-950mV    -46.27mA   -91.66mA   -36.22mA
-900mV    -31.17mA   -66.32mA   -31.23mA
-825mV    -20.42mA   -36.76mA   -25.67mA
-775mV    -17.01mA   -23.52mA   -22.16mA
-700mV    -12.93mA   -12.4mA    -17.08mA
-550mV    -6.031mA   -4.974mA   -8.039mA
-325mV    -407uA     -583.3uA   -420.6uA
1.2V      0A         0A         0A
[POWER_clamp]
|Voltage   I(typ)   I(min)   I(max)
-1.2V     34.12uA    51.64uA    18.84uA
-1.125V   24.08uA    44.51uA    13.48uA
-1.05V    14.15uA    38.9uA     11.09uA
-1V       9.797uA    34.91uA    10.18uA
-925mV    7.083uA    27.3uA     9.093uA
-825mV    6.019uA    14.19uA    7.781uA
-725mV    5.062uA    8.208uA    6.524uA
-275mV    3.872uA    3.86uA     5.968uA
-200mV    2.568uA    3.86uA     486.4nA
-150mV    410.4nA    3.86uA     46.48nA
0V        5.44nA     194.2nA    358.2pA
1.2V      0A         0A         0A
[Pulldown]
|Voltage   I(typ)   I(min)   I(max)
-1.2V     -441.6mA   -738mA     -440.6mA
-1.089V   -258.3mA   -504.2mA   -220.2mA
-1.015V   -154.4mA   -360.1mA   -115.5mA
-978mV    -112.8mA   -293.7mA   -85.62mA
-941mV    -80.57mA   -233mA     -70.15mA
-867mV    -44.83mA   -134.2mA   -57.93mA
-793mV    -33.38mA   -72.24mA   -49.48mA
-719mV    -27.62mA   -42.24mA   -41.41mA
-497mV    -14.12mA   -19.88mA   -20.43mA
21mV      490.7uA    476uA      490.7uA
1.649V    11.87mA    11.51mA    11.87mA
2.4V      55.07mA    53.42mA    55.07mA
[Pullup]
|Voltage   I(typ)   I(min)   I(max)
-1.2V     57.93mA    54.4mA     68.11mA
-708mV    26.38mA    28.5mA     28.67mA
-338mV    9.973mA    11.7mA     10.05mA
365mV     -7.17mA    -6.955mA   -7.17mA
1.586V    -10.69mA   -10.37mA   -10.69mA
2.03V     -34.23mA   -33.21mA   -34.23mA
2.104V    -52.91mA   -51.32mA   -52.91mA
2.141V    -73.01mA   -70.82mA   -73.01mA
2.178V    -102.1mA   -99.05mA   -102.1mA
2.215V    -139.7mA   -135.5mA   -139.7mA
2.289V    -233.6mA   -226.6mA   -233.6mA
2.4V      -399.4mA   -387.4mA   -399.4mA
[Ramp]
| variable   typ   min   max
dV/dt_r   0.275/0.246n   0.275/0.244n   0.275/0.276n
dV/dt_f   0.282/0.265n   0.267/0.351n   0.285/0.237n
R_load = 50.000
[Rising Waveform]
R_fixture = 50.000
V_fixture = 0.000
V_fixture_min = 0.000
V_fixture_max = 0.000
|  time   V(typ)   V(min)   V(max)
0s        37.02uV    2.19mV     2.165mV
430ps     71.45uV    2.081mV    4.903mV
510ps     14.78uV    2.198mV    -65.43mV
835ps     -2.479mV   -11.13mV   285.2mV
1.117ns   310.6mV    -4.693mV   425.2mV
1.313ns   426.1mV    4.967mV    460.6mV
1.667ns   492.6mV    345.5mV    486.3mV
1.857ns   505.5mV    438.6mV    491.4mV
3.03ns    516.5mV    501.8mV    491.2mV
10ns      458.9mV    442.9mV    461mV
[Rising Waveform]
R_fixture = 50.000
V_fixture = 1.200
V_fixture_min = 1.140
V_fixture_max = 1.260
|  time   V(typ)   V(min)   V(max)
0s        730.5mV    690.3mV    784.2mV
437ps     730.5mV    690.2mV    786mV
517ps     730.5mV    690.3mV    635.7mV
697ps     614.1mV    690.2mV    895.3mV
853ps     701.5mV    647.6mV    1.175V
1.043ns   1.065V     649.8mV    1.238V
1.207ns   1.164V     789.1mV    1.252V
1.487ns   1.193V     1.071V     1.26V
1.777ns   1.199V     1.13V      1.262V
10ns      1.2V       1.14V      1.26V
[Falling Waveform]
R_fixture = 50.000
V_fixture = 1.200
V_fixture_min = 1.140
V_fixture_max = 1.260
|  time   V(typ)   V(min)   V(max)
0s        1.2V       1.14V      1.26V
673ps     1.207V     1.139V     1.296V
783ps     1.208V     1.139V     1.198V
910ps     1.231V     1.14V      986.9mV
1.059ns   1.085V     1.146V     868.1mV
1.259ns   850.8mV    1.154V     814.1mV
1.399ns   784.7mV    994.1mV    802.8mV
1.749ns   743.4mV    760.5mV    795.5mV
2.129ns   739.6mV    698.7mV    793.3mV
10ns      730.5mV    690.3mV    784.2mV
[Falling Waveform]
R_fixture = 50.000
V_fixture = 0.000
V_fixture_min = 0.000
V_fixture_max = 0.000
|  time   V(typ)   V(min)   V(max)
0s        458.9mV    442.9mV    461mV
431ps     457.6mV    442.8mV    476.6mV
573ps     482.8mV    442.7mV    249.8mV
620ps     480.2mV    442.3mV    215.6mV
800ps     234.2mV    449.2mV    68.79mV
1.03ns    78.3mV     433mV      4.543mV
1.179ns   17.01mV    265.5mV    1.624mV
1.377ns   1.122mV    80.43mV    1.049mV
1.747ns   -887.5uV   8.025mV    1.054mV
10ns      37.02uV    2.19mV     2.165mV
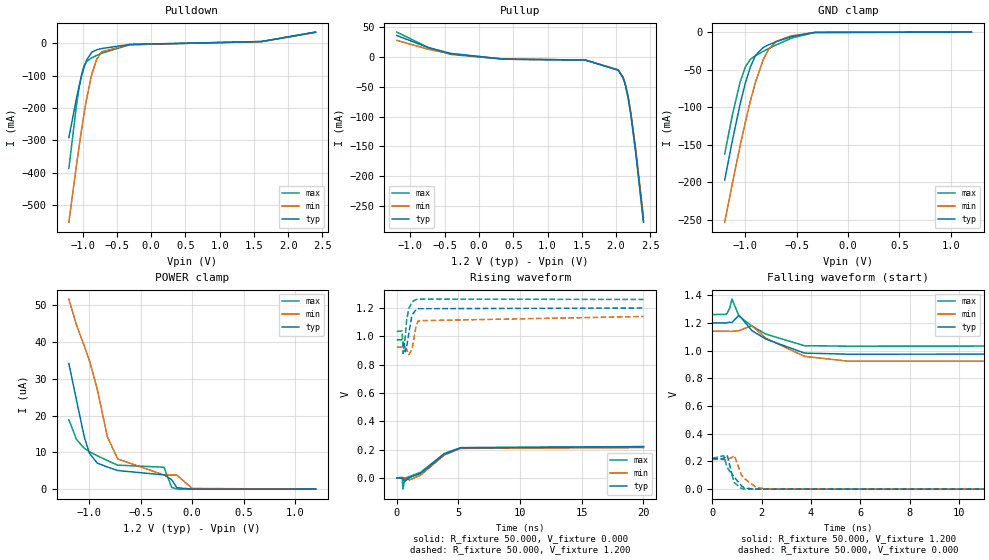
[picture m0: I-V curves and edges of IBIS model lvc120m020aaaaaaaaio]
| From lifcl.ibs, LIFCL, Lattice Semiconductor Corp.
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[Model] lvc120m020aaaaaaaaio
Model_type I/O
Polarity   Non-Inverting
Enable   Active-Low
Vinl =  0.420V
Vinh =  0.780V
Vmeas =  0.600V
Cref =  0.0F
Rref =  1.000M
Vref =  0.0V
C_comp   5.000pF   4.000pF   5.500pF
[Temperature Range]   25.000   0.125k   -40.000
[Voltage Range]   1.200V   1.140V   1.260V
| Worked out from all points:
|   slope of the pulldown table from 0 to 0.18 V, typ, clamps not added: 97.7 ohm
|   slope of the pullup table from 0 to 0.18 V, typ, clamps not added: 88.3 ohm
|   GND clamp passes 1 mA (typ) near -0.37 V on its own axis
|   rising waveform, R_fixture 50.000, V_fixture 0.000: 20-80 % time 1.87ns typ, 1.7ns min, 1.89ns max; typ from 0 V to 0.221 V
|   rising waveform, R_fixture 50.000, V_fixture 1.200: 20-80 % time 290ps typ, 278ps min, 292ps max; typ from 0.975 V to 1.2 V
|   falling waveform, R_fixture 50.000, V_fixture 1.200: 20-80 % time 1.33ns typ, 1.48ns min, 1.34ns max; typ from 1.2 V to 0.975 V
|   falling waveform, R_fixture 50.000, V_fixture 0.000: 20-80 % time 396ps typ, 491ps min, 337ps max; typ from 0.221 V to 0 V
[GND_clamp]
|Voltage   I(typ)   I(min)   I(max)
-1.2V     -197mA     -253.2mA   -162.4mA
-1.125V   -144.2mA   -201.1mA   -110.1mA
-1.05V    -95.99mA   -151.4mA   -66.59mA
-1V       -68.36mA   -120.3mA   -46.7mA
-950mV    -46.27mA   -91.66mA   -36.22mA
-900mV    -31.17mA   -66.32mA   -31.23mA
-825mV    -20.42mA   -36.76mA   -25.67mA
-775mV    -17.01mA   -23.52mA   -22.16mA
-700mV    -12.93mA   -12.4mA    -17.08mA
-550mV    -6.031mA   -4.974mA   -8.039mA
-325mV    -407uA     -583.3uA   -420.6uA
1.2V      0A         0A         0A
[POWER_clamp]
|Voltage   I(typ)   I(min)   I(max)
-1.2V     34.12uA    51.64uA    18.84uA
-1.125V   24.08uA    44.51uA    13.48uA
-1.05V    14.15uA    38.9uA     11.09uA
-1V       9.797uA    34.91uA    10.18uA
-925mV    7.083uA    27.3uA     9.093uA
-825mV    6.019uA    14.19uA    7.781uA
-725mV    5.062uA    8.208uA    6.524uA
-275mV    3.872uA    3.86uA     5.968uA
-200mV    2.568uA    3.86uA     486.4nA
-150mV    410.4nA    3.86uA     46.48nA
0V        5.44nA     194.2nA    358.2pA
1.2V      0A         0A         0A
[Pulldown]
|Voltage   I(typ)   I(min)   I(max)
-1.2V     -291.3mA   -552.3mA   -386.2mA
-1.089V   -169.9mA   -376.3mA   -191.3mA
-1.052V   -133.7mA   -320.9mA   -138.7mA
-1.015V   -101mA     -267.7mA   -97.62mA
-978mV    -73.34mA   -217.5mA   -70.42mA
-941mV    -51.81mA   -171.5mA   -56.14mA
-867mV    -27.81mA   -96.38mA   -45.05mA
-793mV    -20.11mA   -48.94mA   -37.59mA
-719mV    -16.32mA   -25.85mA   -30.51mA
-312mV    -3.502mA   -4.516mA   -4.47mA
1.612V    5.286mA    5.127mA    5.286mA
2.4V      34.45mA    33.42mA    34.45mA
[Pullup]
|Voltage   I(typ)   I(min)   I(max)
-1.2V     36.33mA    28.26mA    42.13mA
-745mV    16.17mA    13.34mA    16.53mA
-412mV    6.26mA     5.639mA    4.545mA
365mV     -3.465mA   -3.361mA   -3.465mA
1.549V    -4.954mA   -4.806mA   -4.954mA
2.03V     -21.89mA   -21.23mA   -21.89mA
2.104V    -35.19mA   -34.14mA   -35.19mA
2.141V    -49.43mA   -47.94mA   -49.43mA
2.178V    -69.96mA   -67.86mA   -69.96mA
2.215V    -96.3mA    -93.4mA    -96.3mA
2.289V    -162.1mA   -157.2mA   -162.1mA
2.4V      -277.9mA   -269.6mA   -277.9mA
[Ramp]
| variable   typ   min   max
dV/dt_r   0.133/1.891n   0.134/1.734n   0.132/1.945n
dV/dt_f   0.134/1.360n   0.130/1.493n   0.135/1.342n
R_load = 50.000
[Rising Waveform]
R_fixture = 50.000
V_fixture = 0.000
V_fixture_min = 0.000
V_fixture_max = 0.000
|  time   V(typ)   V(min)   V(max)
0s        23.11uV    696.4uV    1mV
430ps     49.47uV    576.9uV    3.974mV
504ps     12.32uV    675.6uV    -79.11mV
620ps     -24.34mV   745.3uV    -16.61mV
746ps     -17.36mV   1.473mV    474.1uV
1.026ns   1.478mV    -14.9mV    10.72mV
1.926ns   32.39mV    19.74mV    39.41mV
3.856ns   168.8mV    162.2mV    173.1mV
5.18ns    212.4mV    208.9mV    214.4mV
20ns      221.1mV    214.2mV    221.4mV
[Rising Waveform]
R_fixture = 50.000
V_fixture = 1.200
V_fixture_min = 1.140
V_fixture_max = 1.260
|  time   V(typ)   V(min)   V(max)
0s        975.4mV    923.3mV    1.034V
431ps     975.4mV    923.2mV    1.038V
519ps     975.4mV    923.3mV    879.1mV
683ps     890.9mV    923.3mV    996.2mV
804ps     929.2mV    906mV      1.117V
974ps     1.021V     870.3mV    1.196V
1.239ns   1.15V      908.1mV    1.243V
1.543ns   1.187V     1.062V     1.259V
1.746ns   1.195V     1.11V      1.263V
20ns      1.2V       1.14V      1.26V
[Falling Waveform]
R_fixture = 50.000
V_fixture = 1.200
V_fixture_min = 1.140
V_fixture_max = 1.260
|  time   V(typ)   V(min)   V(max)
0s        1.2V       1.14V      1.26V
574ps     1.2V       1.14V      1.262V
701ps     1.205V     1.139V     1.305V
794ps     1.202V     1.139V     1.372V
1.08ns    1.256V     1.144V     1.249V
1.602ns   1.144V     1.18V      1.177V
2.171ns   1.083V     1.089V     1.119V
3.732ns   982mV      958.1mV    1.035V
5.501ns   973.9mV    923.7mV    1.032V
20ns      975.4mV    923.3mV    1.034V
[Falling Waveform]
R_fixture = 50.000
V_fixture = 0.000
V_fixture_min = 0.000
V_fixture_max = 0.000
|  time   V(typ)   V(min)   V(max)
0s        221.1mV    214.2mV    221.4mV
459ps     220.3mV    214.1mV    241.4mV
600ps     244.4mV    213.7mV    156.5mV
788ps     113.1mV    228mV      105.8mV
893ps     85.36mV    241.1mV    45.8mV
1.183ns   22.38mV    99.22mV    3.626mV
1.323ns   6.618mV    72.68mV    523.7uV
1.783ns   -606.9uV   11.09mV    -712.9uV
2.17ns    -682.9uV   462.8uV    -459.2uV
20ns      23.11uV    696.4uV    1mV
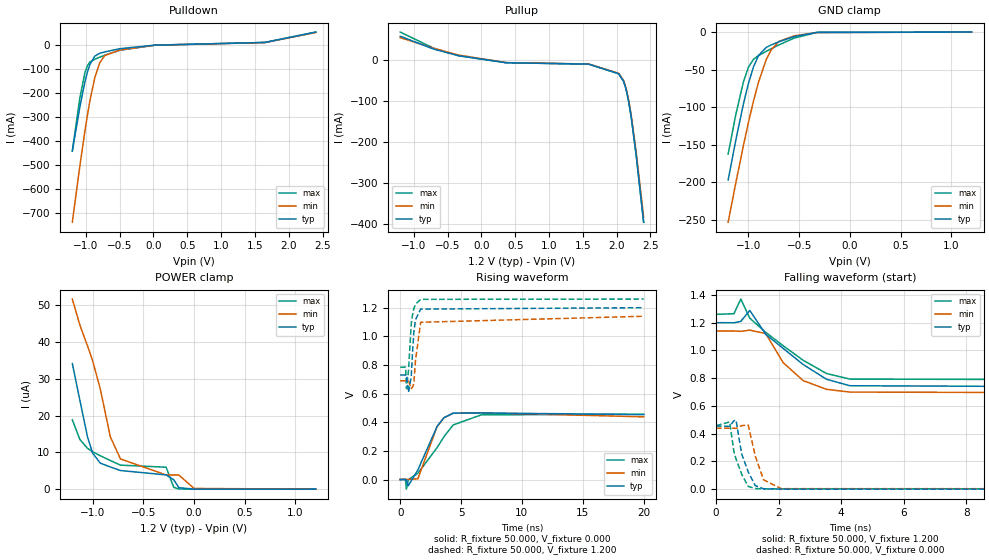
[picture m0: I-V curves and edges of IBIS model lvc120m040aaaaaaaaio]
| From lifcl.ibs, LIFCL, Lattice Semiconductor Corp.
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[Model] lvc120m040aaaaaaaaio
Model_type I/O
Polarity   Non-Inverting
Enable   Active-Low
Vinl =  0.420V
Vinh =  0.780V
Vmeas =  0.600V
Cref =  0.0F
Rref =  1.000M
Vref =  0.0V
C_comp   5.000pF   4.000pF   5.500pF
[Temperature Range]   25.000   0.125k   -40.000
[Voltage Range]   1.200V   1.140V   1.260V
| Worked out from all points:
|   slope of the pulldown table from 0 to 0.18 V, typ, clamps not added: 45.6 ohm
|   slope of the pullup table from 0 to 0.18 V, typ, clamps not added: 43.8 ohm
|   GND clamp passes 1 mA (typ) near -0.37 V on its own axis
|   rising waveform, R_fixture 50.000, V_fixture 0.000: 20-80 % time 1.39ns typ, 1.08ns min, 2.16ns max; typ from 0 V to 0.455 V
|   rising waveform, R_fixture 50.000, V_fixture 1.200: 20-80 % time 259ps typ, 339ps min, 301ps max; typ from 0.731 V to 1.2 V
|   falling waveform, R_fixture 50.000, V_fixture 1.200: 20-80 % time 1.61ns typ, 1.03ns min, 1.73ns max; typ from 1.2 V to 0.731 V
|   falling waveform, R_fixture 50.000, V_fixture 0.000: 20-80 % time 342ps typ, 292ps min, 320ps max; typ from 0.455 V to 0 V
[GND_clamp]
|Voltage   I(typ)   I(min)   I(max)
-1.2V     -197mA     -253.2mA   -162.4mA
-1.125V   -144.2mA   -201.1mA   -110.1mA
-1.05V    -95.99mA   -151.4mA   -66.59mA
-1V       -68.36mA   -120.3mA   -46.7mA
-950mV    -46.27mA   -91.66mA   -36.22mA
-900mV    -31.17mA   -66.32mA   -31.23mA
-825mV    -20.42mA   -36.76mA   -25.67mA
-775mV    -17.01mA   -23.52mA   -22.16mA
-700mV    -12.93mA   -12.4mA    -17.08mA
-550mV    -6.031mA   -4.974mA   -8.039mA
-325mV    -407uA     -583.3uA   -420.6uA
1.2V      0A         0A         0A
[POWER_clamp]
|Voltage   I(typ)   I(min)   I(max)
-1.2V     34.12uA    51.64uA    18.84uA
-1.125V   24.08uA    44.51uA    13.48uA
-1.05V    14.15uA    38.9uA     11.09uA
-1V       9.797uA    34.91uA    10.18uA
-925mV    7.083uA    27.3uA     9.093uA
-825mV    6.019uA    14.19uA    7.781uA
-725mV    5.062uA    8.208uA    6.524uA
-275mV    3.872uA    3.86uA     5.968uA
-200mV    2.568uA    3.86uA     486.4nA
-150mV    410.4nA    3.86uA     46.48nA
0V        5.44nA     194.2nA    358.2pA
1.2V      0A         0A         0A
[Pulldown]
|Voltage   I(typ)   I(min)   I(max)
-1.2V     -441.6mA   -738mA     -440.6mA
-1.089V   -258.3mA   -504.2mA   -220.2mA
-1.015V   -154.4mA   -360.1mA   -115.5mA
-978mV    -112.8mA   -293.7mA   -85.62mA
-941mV    -80.57mA   -233mA     -70.15mA
-867mV    -44.83mA   -134.2mA   -57.93mA
-793mV    -33.38mA   -72.24mA   -49.48mA
-719mV    -27.62mA   -42.24mA   -41.41mA
-497mV    -14.12mA   -19.88mA   -20.43mA
21mV      490.7uA    476uA      490.7uA
1.649V    11.87mA    11.51mA    11.87mA
2.4V      55.07mA    53.42mA    55.07mA
[Pullup]
|Voltage   I(typ)   I(min)   I(max)
-1.2V     57.35mA    53.86mA    67.44mA
-708mV    26.12mA    28.22mA    28.39mA
-338mV    9.874mA    11.59mA    9.954mA
365mV     -7.099mA   -6.886mA   -7.099mA
1.586V    -10.59mA   -10.27mA   -10.59mA
2.03V     -33.9mA    -32.88mA   -33.9mA
2.104V    -52.39mA   -50.81mA   -52.39mA
2.141V    -72.29mA   -70.12mA   -72.29mA
2.178V    -101.1mA   -98.08mA   -101.1mA
2.215V    -138.3mA   -134.2mA   -138.3mA
2.289V    -231.3mA   -224.4mA   -231.3mA
2.4V      -395.4mA   -383.5mA   -395.4mA
[Ramp]
| variable   typ   min   max
dV/dt_r   0.273/1.400n   0.265/1.097n   0.273/2.216n
dV/dt_f   0.282/1.622n   0.266/1.040n   0.285/1.733n
R_load = 50.000
[Rising Waveform]
R_fixture = 50.000
V_fixture = 0.000
V_fixture_min = 0.000
V_fixture_max = 0.000
|  time   V(typ)   V(min)   V(max)
0s        37.02uV    2.19mV     2.165mV
430ps     71.23uV    2.078mV    4.885mV
502ps     33.16uV    2.193mV    -65.77mV
663ps     -41.54mV   2.252mV    518uV
1.447ns   67.82mV    6.419mV    44.92mV
3.03ns    372.5mV    370.8mV    224.1mV
3.59ns    432.6mV    432.7mV    300mV
4.357ns   464.3mV    464.4mV    382.4mV
6.66ns    465.5mV    467.3mV    452.5mV
20ns      454.5mV    438.7mV    456.6mV
[Rising Waveform]
R_fixture = 50.000
V_fixture = 1.200
V_fixture_min = 1.140
V_fixture_max = 1.260
|  time   V(typ)   V(min)   V(max)
0s        730.5mV    690.3mV    784.2mV
437ps     730.5mV    690.2mV    786mV
517ps     730.5mV    690.3mV    635.3mV
682ps     608.9mV    690.3mV    763.7mV
904ps     718.9mV    635.7mV    1.085V
1.002ns   878.4mV    645.2mV    1.146V
1.117ns   1.026V     668.8mV    1.192V
1.252ns   1.115V     830.3mV    1.224V
1.677ns   1.19V      1.098V     1.258V
20ns      1.2V       1.14V      1.26V
[Falling Waveform]
R_fixture = 50.000
V_fixture = 1.200
V_fixture_min = 1.140
V_fixture_max = 1.260
|  time   V(typ)   V(min)   V(max)
0s        1.2V       1.14V      1.26V
573ps     1.199V     1.14V      1.264V
793ps     1.209V     1.137V     1.37V
1.08ns    1.288V     1.146V     1.232V
1.59ns    1.116V     1.121V     1.13V
2.149ns   1.014V     911.2mV    1.033V
2.788ns   897.9mV    781.8mV    928.3mV
3.531ns   792mV      719.3mV    833.4mV
4.279ns   745.1mV    699.3mV    793.1mV
20ns      730.5mV    690.3mV    784.2mV
[Falling Waveform]
R_fixture = 50.000
V_fixture = 0.000
V_fixture_min = 0.000
V_fixture_max = 0.000
|  time   V(typ)   V(min)   V(max)
0s        454.5mV    438.7mV    456.6mV
437ps     452.6mV    438.7mV    484.1mV
573ps     492.8mV    438.5mV    270.2mV
640ps     497.5mV    437.6mV    217.8mV
820ps     254.3mV    457.4mV    107.5mV
1.029ns   124.8mV    462.4mV    19.59mV
1.257ns   24.46mV    237.2mV    3.63mV
1.52ns    2.452mV    66.81mV    1.267mV
2.087ns   -667.8uV   3.037mV    1.259mV
20ns      37.02uV    2.19mV     2.165mV
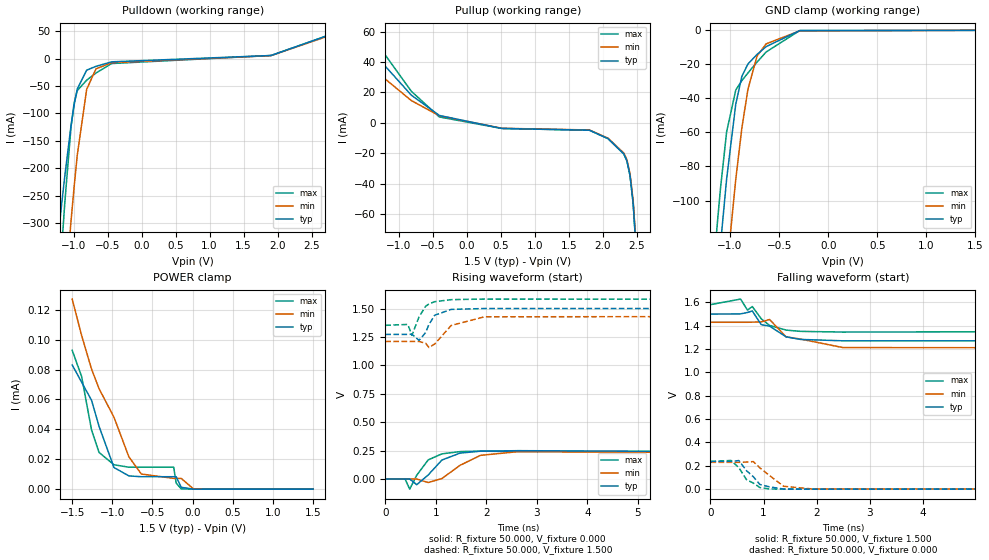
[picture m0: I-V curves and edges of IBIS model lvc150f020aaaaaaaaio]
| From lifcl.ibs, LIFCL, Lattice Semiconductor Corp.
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[Model] lvc150f020aaaaaaaaio
Model_type I/O
Polarity   Non-Inverting
Enable   Active-Low
Vinl =  0.375V
Vinh =  1.125V
Vmeas =  0.750V
Cref =  0.0F
Rref =  1.000M
Vref =  0.0V
C_comp   5.000pF   4.000pF   5.500pF
[Temperature Range]   25.000   0.125k   -40.000
[Voltage Range]   1.500V   1.430V   1.580V
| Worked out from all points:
|   slope of the pulldown table from 0 to 0.225 V, typ, clamps not added: 101 ohm
|   slope of the pullup table from 0 to 0.225 V, typ, clamps not added: 113 ohm
|   GND clamp passes 1 mA (typ) near -0.37 V on its own axis
|   rising waveform, R_fixture 50.000, V_fixture 0.000: 20-80 % time 332ps typ, 430ps min, 283ps max; typ from 0 V to 0.236 V
|   rising waveform, R_fixture 50.000, V_fixture 1.500: 20-80 % time 188ps typ, 227ps min, 198ps max; typ from 1.27 V to 1.5 V
|   falling waveform, R_fixture 50.000, V_fixture 1.500: 20-80 % time 457ps typ, 561ps min, 286ps max; typ from 1.5 V to 1.27 V
|   falling waveform, R_fixture 50.000, V_fixture 0.000: 20-80 % time 274ps typ, 348ps min, 342ps max; typ from 0.236 V to 0 V
[GND_clamp]
|Voltage   I(typ)   I(min)   I(max)
-1.5V     -426.4mA   -473.4mA   -397.9mA
-1.159V   -167.8mA   -224.7mA   -133.2mA
-1.128V   -146.3mA   -203.3mA   -112.2mA
-1.097V   -125.6mA   -182.4mA   -92.52mA
-1.035V   -87.33mA   -142.1mA   -59.66mA
-942mV    -43.38mA   -87.52mA   -35.08mA
-880mV    -27.07mA   -57.47mA   -29.54mA
-818mV    -19.78mA   -34.65mA   -25.05mA
-725mV    -14.16mA   -15.11mA   -18.65mA
-632mV    -9.546mA   -7.937mA   -12.69mA
-291mV    -178.2uA   -331.3uA   -151.3uA
1.5V      0A         0A         0A
[POWER_clamp]
|Voltage   I(typ)   I(min)   I(max)
-1.5V     83.04uA    127.1uA    92.85uA
-1.383V   71.55uA    102.8uA    75.37uA
-1.259V   59.42uA    80.29uA    39.53uA
-1.166V   42.09uA    67.25uA    24.57uA
-980mV    14.48uA    48.12uA    16.31uA
-794mV    8.868uA    21.59uA    14.7uA
-639mV    8.318uA    10.13uA    14.7uA
-236mV    8.318uA    7.207uA    14.7uA
-205mV    8.318uA    7.207uA    4.033uA
-143mV    1.253uA    7.207uA    225nA
12mV      3.591nA    119.8nA    333.5pA
1.5V      0A         0A         0A
[Pulldown]
|Voltage   I(typ)   I(min)   I(max)
-1.5V     -652.2mA   -1.036A    -999mA
-1.224V   -318.3mA   -578.1mA   -434.5mA
-1.178V   -265.7mA   -504.8mA   -346.6mA
-1.132V   -214.8mA   -433.1mA   -263.5mA
-1.04V    -122.4mA   -296.4mA   -124.8mA
-994mV    -84.5mA    -233.5mA   -80.91mA
-948mV    -55.33mA   -176mA     -58.34mA
-810mV    -21.18mA   -56.2mA    -39.43mA
-672mV    -14.17mA   -18.72mA   -26.31mA
-442mV    -5.972mA   -7.548mA   -9.089mA
1.904V    5.551mA    5.384mA    5.551mA
3V        53.44mA    51.84mA    53.44mA
[Pullup]
|Voltage   I(typ)   I(min)   I(max)
-1.5V     52.08mA    39.77mA    63.11mA
-818mV    18.17mA    14.6mA     20.75mA
-404mV    4.77mA     4.559mA    3.77mA
516mV     -3.782mA   -3.668mA   -3.782mA
1.804V    -4.928mA   -4.781mA   -4.928mA
2.08V     -10.53mA   -10.21mA   -10.53mA
2.31V     -20.54mA   -19.93mA   -20.54mA
2.356V    -25.06mA   -24.31mA   -25.06mA
2.402V    -34.81mA   -33.76mA   -34.81mA
2.448V    -53.02mA   -51.42mA   -53.02mA
2.54V     -117mA     -113.5mA   -117mA
3V        -622.5mA   -603.8mA   -622.5mA
[Ramp]
| variable   typ   min   max
dV/dt_r   0.142/0.336n   0.137/0.437n   0.141/0.283n
dV/dt_f   0.137/0.459n   0.132/0.563n   0.137/0.438n
R_load = 50.000
[Rising Waveform]
R_fixture = 50.000
V_fixture = 0.000
V_fixture_min = 0.000
V_fixture_max = 0.000
|  time   V(typ)   V(min)   V(max)
0s        33.82uV    761.7uV    1.217mV
390ps     14.99uV    589.3uV    3.108mV
483ps     112.7uV    722.6uV    -88.44mV
623ps     -48.92mV   815.8uV    34.47mV
850ps     36.61mV    -30.21mV   169mV
1.121ns   167.6mV    5.028mV    222mV
1.481ns   228.8mV    121.4mV    241.9mV
1.884ns   245.4mV    208.7mV    246.2mV
2.624ns   250mV      241.2mV    241.3mV
10ns      236.3mV    229.1mV    236.5mV
[Rising Waveform]
R_fixture = 50.000
V_fixture = 1.500
V_fixture_min = 1.430
V_fixture_max = 1.580
|  time   V(typ)   V(min)   V(max)
0s        1.272V     1.21V      1.352V
446ps     1.272V     1.21V      1.36V
527ps     1.274V     1.21V      1.264V
668ps     1.22V      1.21V      1.426V
798ps     1.288V     1.195V     1.519V
864ps     1.359V     1.157V     1.54V
978ps     1.441V     1.188V     1.56V
1.305ns   1.492V     1.351V     1.578V
1.964ns   1.5V       1.427V     1.583V
10ns      1.5V       1.43V      1.581V
[Falling Waveform]
R_fixture = 50.000
V_fixture = 1.500
V_fixture_min = 1.430
V_fixture_max = 1.580
|  time   V(typ)   V(min)   V(max)
0s        1.5V       1.43V      1.581V
567ps     1.502V     1.43V      1.629V
697ps     1.514V     1.43V      1.534V
787ps     1.527V     1.431V     1.565V
958ps     1.409V     1.433V     1.459V
1.113ns   1.397V     1.454V     1.403V
1.423ns   1.305V     1.305V     1.363V
1.693ns   1.283V     1.286V     1.352V
2.493ns   1.271V     1.213V     1.346V
10ns      1.272V     1.21V      1.352V
[Falling Waveform]
R_fixture = 50.000
V_fixture = 0.000
V_fixture_min = 0.000
V_fixture_max = 0.000
|  time   V(typ)   V(min)   V(max)
0s        236.3mV    229.1mV    236.5mV
388ps     236.1mV    228.9mV    245.2mV
535ps     244.4mV    229mV      182.9mV
680ps     157.2mV    231.3mV    79.78mV
808ps     105.2mV    235.5mV    51.05mV
930ps     39.2mV     182.1mV    12.89mV
1.108ns   19.11mV    117.1mV    857.1uV
1.378ns   113.7uV    23.6mV     -986uV
1.907ns   -939.5uV   1.14mV     -717.3uV
10ns      33.82uV    761.7uV    1.217mV
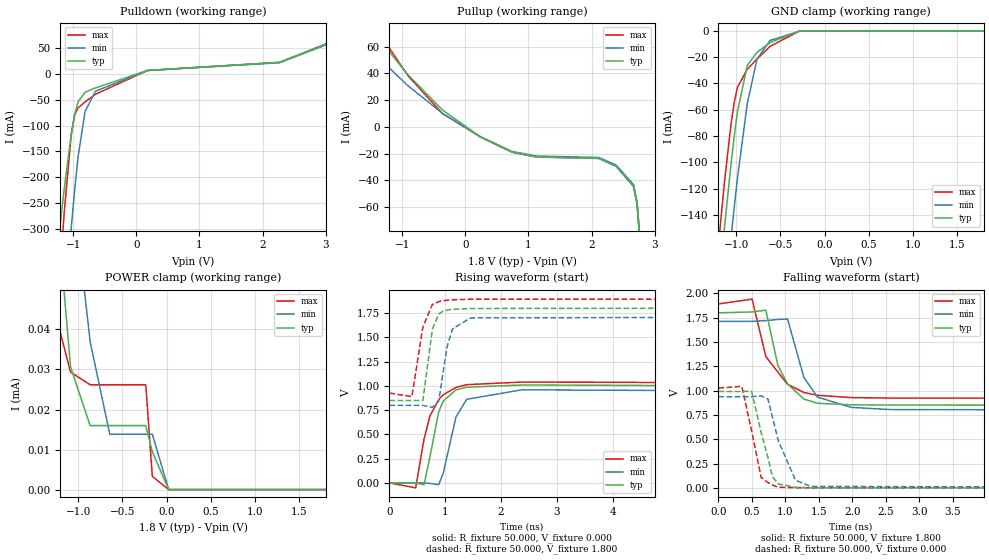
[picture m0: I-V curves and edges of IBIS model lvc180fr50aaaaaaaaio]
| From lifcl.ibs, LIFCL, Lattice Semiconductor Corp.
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[Model] lvc180fr50aaaaaaaaio
Model_type I/O
Polarity   Non-Inverting
Enable   Active-Low
Vinl =  0.630V
Vinh =  1.170V
Vmeas =  0.900V
Cref =  0.0F
Rref =  1.000M
Vref =  0.0V
C_comp   5.000pF   4.000pF   5.500pF
[Temperature Range]   25.000   0.125k   -40.000
[Voltage Range]   1.800V   1.710V   1.890V
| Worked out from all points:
|   slope of the pulldown table from 0 to 0.27 V, typ, clamps not added: 27 ohm
|   slope of the pullup table from 0 to 0.27 V, typ, clamps not added: 32.4 ohm
|   GND clamp passes 1 mA (typ) near -0.37 V on its own axis
|   rising waveform, R_fixture 50.000, V_fixture 0.000: 20-80 % time 217ps typ, 243ps min, 285ps max; typ from 0 V to 0.992 V
|   rising waveform, R_fixture 50.000, V_fixture 1.800: 20-80 % time 128ps typ, 165ps min, 157ps max; typ from 0.849 V to 1.8 V
|   falling waveform, R_fixture 50.000, V_fixture 1.800: 20-80 % time 309ps typ, 273ps min, 374ps max; typ from 1.8 V to 0.849 V
|   falling waveform, R_fixture 50.000, V_fixture 0.000: 20-80 % time 209ps typ, 278ps min, 184ps max; typ from 0.992 V to 0 V
[GND_clamp]
|Voltage   I(typ)   I(min)   I(max)
-1.8V     -665.5mA   -701.9mA   -644.7mA
-1.208V   -203.2mA   -259.3mA   -168.6mA
-1.171V   -176.5mA   -233.3mA   -141.8mA
-1.134V   -150.7mA   -207.7mA   -116.3mA
-1.06V    -102.3mA   -158.3mA   -71.8mA
-1.023V   -80.78mA   -134.8mA   -54.83mA
-986mV    -61.78mA   -112.4mA   -42.93mA
-875mV    -26.33mA   -55.53mA   -29.29mA
-764mV    -16.38mA   -21.41mA   -21.4mA
-616mV    -8.858mA   -7.288mA   -11.79mA
-283mV    -142.7uA   -287uA     -113.6uA
1.8V      1.806nA    0A         -451.7pA
[POWER_clamp]
|Voltage   I(typ)   I(min)   I(max)
-1.8V     186.1uA    259.3uA    183.5uA
-1.382V   94.44uA    136.9uA    91.49uA
-1.345V   89.56uA    127.8uA    77.5uA
-1.308V   84.02uA    119.2uA    62.8uA
-1.234V   68.87uA    103.6uA    41.99uA
-1.086V   30.66uA    80.57uA    29.36uA
-864mV    15.99uA    36.92uA    26.17uA
-642mV    15.99uA    13.83uA    26.17uA
-235mV    15.99uA    13.83uA    26.17uA
-161mV    9.477uA    13.83uA    3.316uA
24mV      0A         0A         261.1pA
1.8V      0A         0A         0A
[Pulldown]
|Voltage   I(typ)   I(min)   I(max)
-1.8V     -1A        -1.601A    -1.545A
-1.25V    -342.7mA   -644.6mA   -462.3mA
-1.195V   -281.2mA   -554mA     -362.1mA
-1.14V    -222.3mA   -465.4mA   -267.8mA
-1.03V    -118.1mA   -298.9mA   -117.7mA
-975mV    -79.04mA   -224.5mA   -79.65mA
-920mV    -53.51mA   -159.6mA   -65.53mA
-810mV    -35.31mA   -72.41mA   -54.01mA
-645mV    -26.81mA   -33.2mA    -39.09mA
180mV     6.979mA    6.77mA     6.979mA
2.27V     22.59mA    21.91mA    22.59mA
3.6V      86.9mA     84.3mA     86.9mA
[Pullup]
|Voltage   I(typ)   I(min)   I(max)
-1.8V     91.5mA     70.91mA    100.9mA
-910mV    39.09mA    30.91mA    38.48mA
-360mV    12.66mA    10.15mA    9.954mA
245mV     -7.622mA   -7.393mA   -7.622mA
740mV     -18.86mA   -18.3mA    -18.86mA
1.125V    -22.44mA   -21.77mA   -22.44mA
2.115V    -23.52mA   -22.82mA   -23.52mA
2.39V     -29.43mA   -28.54mA   -29.43mA
2.665V    -44.52mA   -43.19mA   -44.52mA
2.72V     -57.41mA   -55.69mA   -57.41mA
2.83V     -123.4mA   -119.7mA   -123.4mA
3.6V      -1.037A    -1.006A    -1.037A
[Ramp]
| variable   typ   min   max
dV/dt_r   0.595/0.217n   0.538/0.245n   0.614/0.284n
dV/dt_f   0.570/0.306n   0.533/0.274n   0.580/0.376n
R_load = 50.000
[Rising Waveform]
R_fixture = 50.000
V_fixture = 0.000
V_fixture_min = 0.000
V_fixture_max = 0.000
|  time   V(typ)   V(min)   V(max)
0s        59.69uV    1.079mV    2.375mV
470ps     907.7uV    1.028mV    -49.41mV
620ps     -17.53mV   1.33mV     453.6mV
724ps     264.6mV    -3.623mV   686.6mV
883ps     732.3mV    -17.08mV   858.9mV
964ps     843.2mV    101.8mV    908mV
1.193ns   958.9mV    680.6mV    983.4mV
1.384ns   985.7mV    861.6mV    1.012V
2.378ns   1.009V     959.4mV    1.039V
10ns      991.6mV    937.7mV    1.026V
[Rising Waveform]
R_fixture = 50.000
V_fixture = 1.800
V_fixture_min = 1.710
V_fixture_max = 1.890
|  time   V(typ)   V(min)   V(max)
0s        849.2mV    799.3mV    925.4mV
402ps     849.3mV    798.9mV    889.2mV
599ps     849.7mV    799.5mV    1.605V
770ps     1.584V     778.3mV    1.838V
884ps     1.739V     842.2mV    1.867V
953ps     1.766V     1.105V     1.875V
1.034ns   1.78V      1.405V     1.88V
1.13ns    1.787V     1.586V     1.885V
1.454ns   1.796V     1.698V     1.891V
10ns      1.8V       1.712V     1.892V
[Falling Waveform]
R_fixture = 50.000
V_fixture = 1.800
V_fixture_min = 1.710
V_fixture_max = 1.890
|  time   V(typ)   V(min)   V(max)
0s        1.8V       1.712V     1.892V
502ps     1.809V     1.712V     1.941V
708ps     1.827V     1.72V      1.35V
888ps     1.258V     1.732V     1.191V
1.032ns   1.069V     1.736V     1.065V
1.277ns   913.1mV    1.134V     980.4mV
1.481ns   869.7mV    933mV      951.6mV
1.982ns   854.4mV    827.7mV    928.5mV
2.571ns   851.8mV    804.9mV    923.5mV
10ns      849.2mV    799.3mV    925.4mV
[Falling Waveform]
R_fixture = 50.000
V_fixture = 0.000
V_fixture_min = 0.000
V_fixture_max = 0.000
|  time   V(typ)   V(min)   V(max)
0s        991.6mV    937.7mV    1.026V
349ps     991.3mV    937.4mV    1.044V
495ps     994.2mV    937.5mV    585.2mV
638ps     568.3mV    946mV      107.3mV
738ps     315.4mV    914.7mV    54.74mV
807ps     112.3mV    725.6mV    28.7mV
897ps     38.98mV    478.3mV    6.953mV
1.152ns   5.386mV    78.09mV    1.947mV
1.381ns   417.4uV    14.86mV    1.725mV
10ns      59.69uV    1.079mV    2.375mV
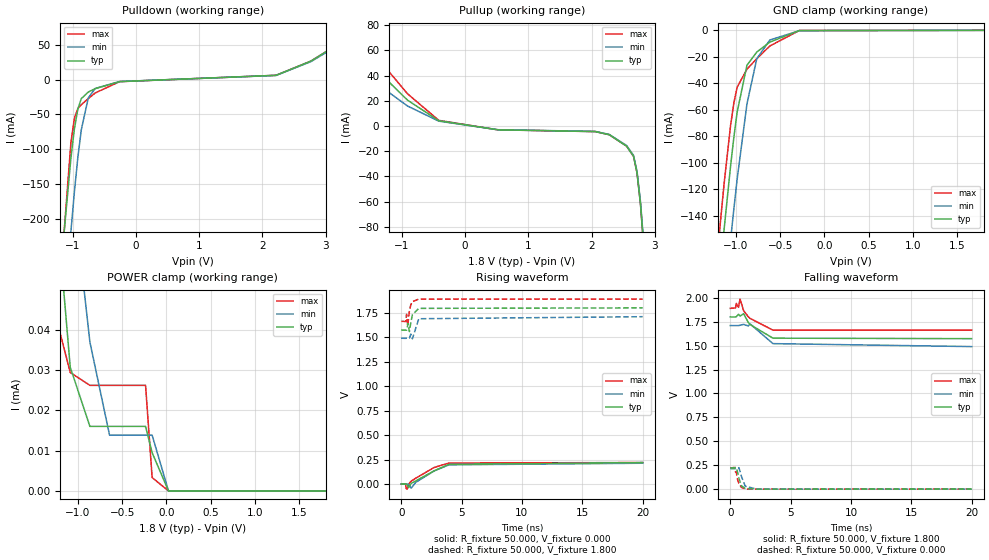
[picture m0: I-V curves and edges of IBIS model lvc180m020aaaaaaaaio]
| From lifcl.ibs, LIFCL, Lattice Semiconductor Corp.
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[Model] lvc180m020aaaaaaaaio
Model_type I/O
Polarity   Non-Inverting
Enable   Active-Low
Vinl =  0.630V
Vinh =  1.170V
Vmeas =  0.900V
Cref =  0.0F
Rref =  1.000M
Vref =  0.0V
C_comp   5.000pF   4.000pF   5.500pF
[Temperature Range]   25.000   0.125k   -40.000
[Voltage Range]   1.800V   1.710V   1.890V
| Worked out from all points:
|   slope of the pulldown table from 0 to 0.27 V, typ, clamps not added: 105 ohm
|   slope of the pullup table from 0 to 0.27 V, typ, clamps not added: 152 ohm
|   GND clamp passes 1 mA (typ) near -0.37 V on its own axis
|   rising waveform, R_fixture 50.000, V_fixture 0.000: 20-80 % time 1.93ns typ, 1.75ns min, 1.83ns max; typ from 0 V to 0.22 V
|   rising waveform, R_fixture 50.000, V_fixture 1.800: 20-80 % time 240ps typ, 265ps min, 221ps max; typ from 1.57 V to 1.8 V
|   falling waveform, R_fixture 50.000, V_fixture 1.800: 20-80 % time 1.23ns typ, 1.36ns min, 1.27ns max; typ from 1.8 V to 1.57 V
|   falling waveform, R_fixture 50.000, V_fixture 0.000: 20-80 % time 306ps typ, 353ps min, 316ps max; typ from 0.22 V to 0 V
[GND_clamp]
|Voltage   I(typ)   I(min)   I(max)
-1.8V     -665.5mA   -701.9mA   -644.7mA
-1.208V   -203.2mA   -259.3mA   -168.6mA
-1.171V   -176.5mA   -233.3mA   -141.8mA
-1.134V   -150.7mA   -207.7mA   -116.3mA
-1.06V    -102.3mA   -158.3mA   -71.8mA
-1.023V   -80.78mA   -134.8mA   -54.83mA
-986mV    -61.78mA   -112.4mA   -42.93mA
-875mV    -26.33mA   -55.53mA   -29.29mA
-764mV    -16.38mA   -21.41mA   -21.4mA
-616mV    -8.858mA   -7.288mA   -11.79mA
-283mV    -142.7uA   -287uA     -113.6uA
1.8V      1.806nA    0A         -451.7pA
[POWER_clamp]
|Voltage   I(typ)   I(min)   I(max)
-1.8V     186.1uA    259.3uA    183.5uA
-1.382V   94.44uA    136.9uA    91.49uA
-1.345V   89.56uA    127.8uA    77.5uA
-1.308V   84.02uA    119.2uA    62.8uA
-1.234V   68.87uA    103.6uA    41.99uA
-1.086V   30.66uA    80.57uA    29.36uA
-864mV    15.99uA    36.92uA    26.17uA
-642mV    15.99uA    13.83uA    26.17uA
-235mV    15.99uA    13.83uA    26.17uA
-161mV    9.477uA    13.83uA    3.316uA
24mV      0A         0A         261.1pA
1.8V      0A         0A         0A
[Pulldown]
|Voltage   I(typ)   I(min)   I(max)
-1.8V     -1.023A    -1.199A    -1.31A
-1.14V    -222.4mA   -344.6mA   -222.3mA
-1.03V    -113.2mA   -218.6mA   -90.97mA
-975mV    -71.04mA   -161.9mA   -55.48mA
-920mV    -42.35mA   -112mA     -41.66mA
-865mV    -27.27mA   -71.92mA   -36.05mA
-755mV    -17.88mA   -26.29mA   -27.26mA
-645mV    -12.94mA   -12.68mA   -19.14mA
-260mV    -2.838mA   -2.717mA   -2.912mA
2.215V    6.236mA    6.049mA    6.236mA
2.765V    26.66mA    25.86mA    26.66mA
3.6V      73.71mA    71.5mA     73.71mA
[Pullup]
|Voltage   I(typ)   I(min)   I(max)
-1.8V     64.13mA    48.54mA    78.9mA
-910mV    20.55mA    15.86mA    25.57mA
-415mV    4.154mA    3.826mA    4.468mA
520mV     -3.053mA   -2.961mA   -3.053mA
2.06V     -4.457mA   -4.323mA   -4.457mA
2.28V     -6.921mA   -6.713mA   -6.921mA
2.555V    -16.01mA   -15.53mA   -16.01mA
2.665V    -24.11mA   -23.39mA   -24.11mA
2.72V     -37.19mA   -36.07mA   -37.19mA
2.775V    -62.11mA   -60.25mA   -62.11mA
2.83V     -98.7mA    -95.7mA    -98.7mA
3.6V      -890.9mA   -864.2mA   -890.9mA
[Ramp]
| variable   typ   min   max
dV/dt_r   0.132/2.002n   0.128/1.818n   0.132/1.853n
dV/dt_f   0.136/1.257n   0.133/1.388n   0.136/1.264n
R_load = 50.000
[Rising Waveform]
R_fixture = 50.000
V_fixture = 0.000
V_fixture_min = 0.000
V_fixture_max = 0.000
|  time   V(typ)   V(min)   V(max)
0s        37.31uV    -194.3uV   289.1uV
354ps     -20.13uV   -323.6uV   1.499mV
407ps     92.33uV    -356.7uV   -45.78mV
482ps     -3.354mV   -246.7uV   -51.59mV
607ps     -36.59mV   -112.9uV   -859.2uV
824ps     7.343mV    -41.53mV   31.18mV
1.204ns   33mV       18.09mV    60.37mV
2.737ns   136.3mV    135.6mV    170.9mV
3.953ns   202.1mV    196.8mV    215.3mV
20ns      220.1mV    213.5mV    220.2mV
[Rising Waveform]
R_fixture = 50.000
V_fixture = 1.800
V_fixture_min = 1.710
V_fixture_max = 1.890
|  time   V(typ)   V(min)   V(max)
0s        1.573V     1.49V      1.663V
363ps     1.573V     1.489V     1.661V
444ps     1.573V     1.49V      1.733V
530ps     1.618V     1.49V      1.616V
566ps     1.642V     1.49V      1.648V
675ps     1.558V     1.49V      1.77V
794ps     1.65V      1.532V     1.832V
924ps     1.73V      1.484V     1.863V
1.454ns   1.795V     1.689V     1.89V
20ns      1.8V       1.71V      1.89V
[Falling Waveform]
R_fixture = 50.000
V_fixture = 1.800
V_fixture_min = 1.710
V_fixture_max = 1.890
|  time   V(typ)   V(min)   V(max)
0s        1.8V       1.71V      1.89V
435ps     1.8V       1.71V      1.894V
501ps     1.802V     1.71V      1.941V
681ps     1.828V     1.71V      1.901V
811ps     1.809V     1.713V     1.987V
1.106ns   1.835V     1.722V     1.866V
1.492ns   1.742V     1.706V     1.802V
1.642ns   1.721V     1.727V     1.785V
3.535ns   1.578V     1.521V     1.662V
20ns      1.573V     1.49V      1.663V
[Falling Waveform]
R_fixture = 50.000
V_fixture = 0.000
V_fixture_min = 0.000
V_fixture_max = 0.000
|  time   V(typ)   V(min)   V(max)
0s        220.1mV    213.5mV    220.2mV
367ps     219.9mV    213.3mV    226.5mV
444ps     226.2mV    213.3mV    176.2mV
492ps     225.4mV    213.3mV    179.2mV
633ps     163.8mV    217mV      83.43mV
717ps     114.2mV    224.2mV    60.12mV
913ps     36.12mV    136.9mV    18.48mV
1.237ns   6.819mV    30.27mV    -86.2uV
2.229ns   -716uV     -981.7uV   -846.4uV
20ns      37.31uV    -194.3uV   289.1uV
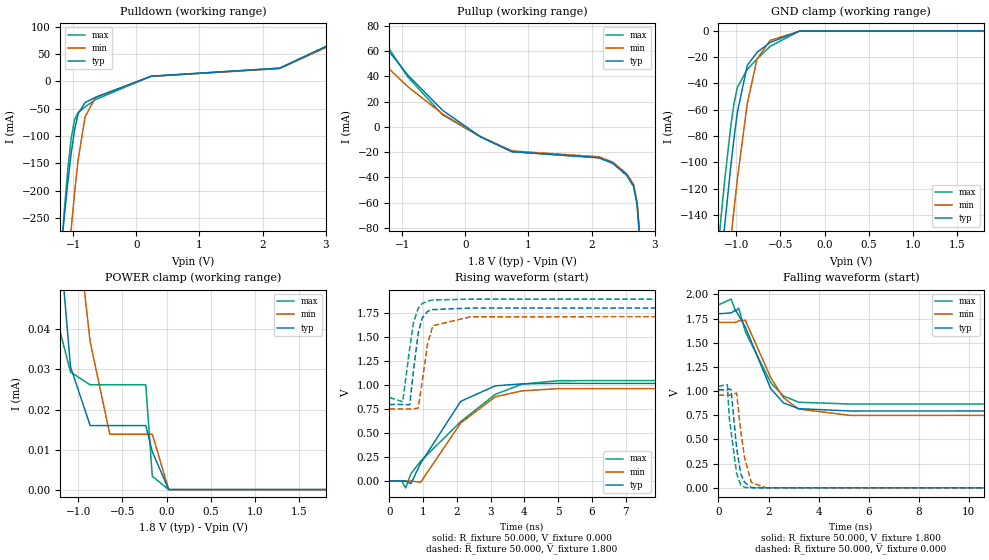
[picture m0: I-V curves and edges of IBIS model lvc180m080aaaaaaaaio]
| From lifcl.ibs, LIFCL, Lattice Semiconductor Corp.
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[Model] lvc180m080aaaaaaaaio
Model_type I/O
Polarity   Non-Inverting
Enable   Active-Low
Vinl =  0.630V
Vinh =  1.170V
Vmeas =  0.900V
Cref =  0.0F
Rref =  1.000M
Vref =  0.0V
C_comp   5.000pF   4.000pF   5.500pF
[Temperature Range]   25.000   0.125k   -40.000
[Voltage Range]   1.800V   1.710V   1.890V
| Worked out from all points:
|   slope of the pulldown table from 0 to 0.27 V, typ, clamps not added: 25.1 ohm
|   slope of the pullup table from 0 to 0.27 V, typ, clamps not added: 31.2 ohm
|   GND clamp passes 1 mA (typ) near -0.37 V on its own axis
|   rising waveform, R_fixture 50.000, V_fixture 0.000: 20-80 % time 1.11ns typ, 1.28ns min, 1.93ns max; typ from 0 V to 1.01 V
|   rising waveform, R_fixture 50.000, V_fixture 1.800: 20-80 % time 215ps typ, 245ps min, 255ps max; typ from 0.796 V to 1.8 V
|   falling waveform, R_fixture 50.000, V_fixture 1.800: 20-80 % time 997ps typ, 1.13ns min, 1.14ns max; typ from 1.8 V to 0.796 V
|   falling waveform, R_fixture 50.000, V_fixture 0.000: 20-80 % time 278ps typ, 308ps min, 261ps max; typ from 1.01 V to 0 V
[GND_clamp]
|Voltage   I(typ)   I(min)   I(max)
-1.8V     -665.5mA   -701.9mA   -644.7mA
-1.208V   -203.2mA   -259.3mA   -168.6mA
-1.171V   -176.5mA   -233.3mA   -141.8mA
-1.134V   -150.7mA   -207.7mA   -116.3mA
-1.06V    -102.3mA   -158.3mA   -71.8mA
-1.023V   -80.78mA   -134.8mA   -54.83mA
-986mV    -61.78mA   -112.4mA   -42.93mA
-875mV    -26.33mA   -55.53mA   -29.29mA
-764mV    -16.38mA   -21.41mA   -21.4mA
-616mV    -8.858mA   -7.288mA   -11.79mA
-283mV    -142.7uA   -287uA     -113.6uA
1.8V      1.806nA    0A         -451.7pA
[POWER_clamp]
|Voltage   I(typ)   I(min)   I(max)
-1.8V     186.1uA    259.3uA    183.5uA
-1.382V   94.44uA    136.9uA    91.49uA
-1.345V   89.56uA    127.8uA    77.5uA
-1.308V   84.02uA    119.2uA    62.8uA
-1.234V   68.87uA    103.6uA    41.99uA
-1.086V   30.66uA    80.57uA    29.36uA
-864mV    15.99uA    36.92uA    26.17uA
-642mV    15.99uA    13.83uA    26.17uA
-235mV    15.99uA    13.83uA    26.17uA
-161mV    9.477uA    13.83uA    3.316uA
24mV      0A         0A         261.1pA
1.8V      0A         0A         0A
[Pulldown]
|Voltage   I(typ)   I(min)   I(max)
-1.8V     -1.123A    -1.448A    -1.379A
-1.195V   -315.4mA   -500.8mA   -322.9mA
-1.14V    -249.2mA   -420.7mA   -238.5mA
-1.085V   -187mA     -343.4mA   -163mA
-1.03V    -131.9mA   -270mA     -104mA
-975mV    -88.04mA   -202.5mA   -69.67mA
-920mV    -59.22mA   -143.8mA   -56.86mA
-810mV    -38.63mA   -64.78mA   -46.55mA
-645mV    -29.15mA   -29.22mA   -33.27mA
235mV     9.566mA    9.279mA    9.566mA
2.27V     24.3mA     23.57mA    24.3mA
3.6V      96.4mA     93.5mA     96.4mA
[Pullup]
|Voltage   I(typ)   I(min)   I(max)
-1.8V     97mA       74.36mA    106.2mA
-910mV    41.1mA     31.86mA    39.59mA
-360mV    13.18mA    10.28mA    9.638mA
245mV     -7.923mA   -7.685mA   -7.923mA
740mV     -19.57mA   -18.99mA   -19.57mA
2.115V    -24.37mA   -23.64mA   -24.37mA
2.335V    -28.69mA   -27.83mA   -28.69mA
2.555V    -38.07mA   -36.93mA   -38.07mA
2.665V    -46.88mA   -45.47mA   -46.88mA
2.72V     -60.75mA   -58.92mA   -60.75mA
2.83V     -131.6mA   -127.7mA   -131.6mA
3.6V      -1.109A    -1.075A    -1.109A
[Ramp]
| variable   typ   min   max
dV/dt_r   0.608/1.109n   0.575/1.282n   0.630/1.934n
dV/dt_f   0.602/0.994n   0.577/1.126n   0.614/1.145n
R_load = 50.000
[Rising Waveform]
R_fixture = 50.000
V_fixture = 0.000
V_fixture_min = 0.000
V_fixture_max = 0.000
|  time   V(typ)   V(min)   V(max)
0s        66.63uV    -469.7uV   428.7uV
355ps     61.49uV    -736.6uV   2.42mV
480ps     -2.166mV   -490.2uV   -72.3mV
634ps     -28.55mV   -238uV     73.73mV
924ps     183.7mV    -13.97mV   206mV
2.111ns   828.7mV    602.8mV    617.7mV
3.134ns   989.9mV    875.9mV    900.7mV
3.931ns   1.011V     937.7mV    1.008V
5.01ns    1.016V     961.2mV    1.044V
20ns      1.014V     958.1mV    1.05V
[Rising Waveform]
R_fixture = 50.000
V_fixture = 1.800
V_fixture_min = 1.710
V_fixture_max = 1.890
|  time   V(typ)   V(min)   V(max)
0s        796mV      750.1mV    868.6mV
393ps     796.1mV    749.8mV    824.2mV
600ps     793.3mV    750.3mV    1.382V
713ps     1.155V     749mV      1.651V
853ps     1.544V     760.2mV    1.799V
970ps     1.697V     1.036V     1.847V
1.13ns    1.766V     1.427V     1.873V
1.284ns   1.784V     1.616V     1.884V
2.403ns   1.8V       1.709V     1.893V
20ns      1.8V       1.712V     1.893V
[Falling Waveform]
R_fixture = 50.000
V_fixture = 1.800
V_fixture_min = 1.710
V_fixture_max = 1.890
|  time   V(typ)   V(min)   V(max)
0s        1.8V       1.712V     1.893V
505ps     1.81V      1.712V     1.952V
684ps     1.837V     1.712V     1.827V
807ps     1.784V     1.727V     1.859V
1.072ns   1.663V     1.733V     1.614V
2.083ns   1.027V     1.141V     1.089V
2.594ns   879.3mV    931.6mV    949.4mV
3.202ns   818.6mV    814.8mV    885.3mV
5.297ns   794.4mV    748.6mV    866.4mV
20ns      796mV      750.1mV    868.6mV
[Falling Waveform]
R_fixture = 50.000
V_fixture = 0.000
V_fixture_min = 0.000
V_fixture_max = 0.000
|  time   V(typ)   V(min)   V(max)
0s        1.014V     958.1mV    1.05V
354ps     1.013V     957.8mV    1.068V
434ps     1.022V     957.9mV    716.1mV
502ps     1.015V     957.8mV    582mV
723ps     413.2mV    979.4mV    149.4mV
887ps     146.4mV    589mV      30.6mV
1.042ns   56.54mV    312.8mV    4.503mV
1.313ns   2.891mV    54.1mV     45.02uV
1.903ns   152uV      808.8uV    -125uV
20ns      66.63uV    -469.7uV   428.7uV
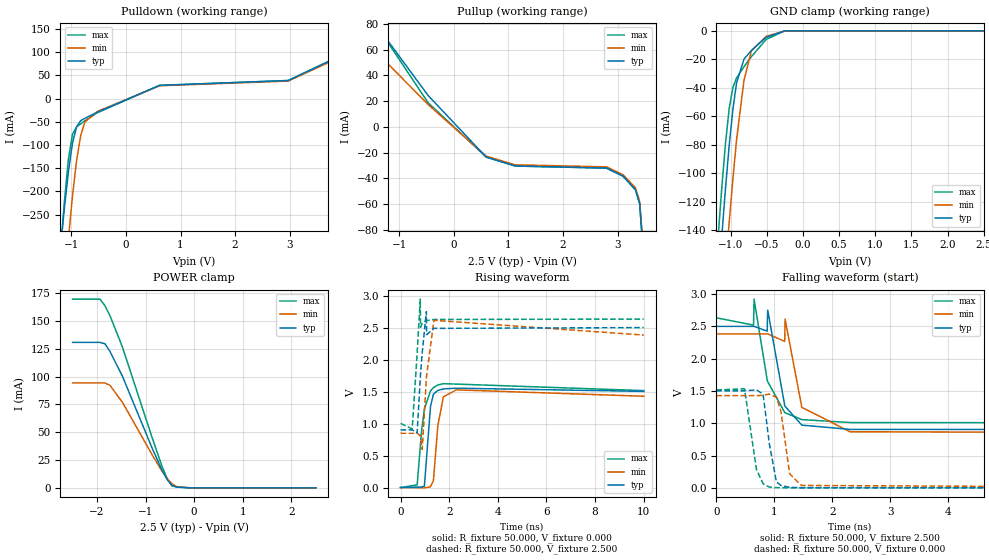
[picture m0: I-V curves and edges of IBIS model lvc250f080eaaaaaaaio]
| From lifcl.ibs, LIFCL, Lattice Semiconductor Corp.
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[Model] lvc250f080eaaaaaaaio
Model_type I/O
Polarity   Non-Inverting
Enable   Active-Low
Vinl =  0.700V
Vinh =  1.700V
Vmeas =  1.250V
Cref =  0.0F
Rref =  1.000M
Vref =  0.0V
C_comp   5.000pF   4.000pF   5.500pF
[Temperature Range]   25.000   0.125k   -40.000
[Voltage Range]   2.500V   2.380V   2.630V
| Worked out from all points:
|   slope of the pulldown table from 0 to 0.375 V, typ, clamps not added: 18.1 ohm
|   slope of the pullup table from 0 to 0.375 V, typ, clamps not added: 23 ohm
|   GND clamp passes 1 mA (typ) near -0.37 V on its own axis
|   POWER clamp passes 1 mA (typ) near -0.40 V on its own axis
|   rising waveform, R_fixture 50.000, V_fixture 0.000: 20-80 % time 157ps typ, 192ps min, 221ps max; typ from 0 V to 1.5 V
|   rising waveform, R_fixture 50.000, V_fixture 2.500: 20-80 % time 161ps typ, 188ps min, 161ps max; typ from 0.901 V to 2.5 V
|   falling waveform, R_fixture 50.000, V_fixture 2.500: 20-80 % time 243ps typ, 310ps min, 317ps max; typ from 2.5 V to 0.901 V
|   falling waveform, R_fixture 50.000, V_fixture 0.000: 20-80 % time 96.4ps typ, 124ps min, 134ps max; typ from 1.5 V to 0 V
[GND_clamp]
|Voltage   I(typ)   I(min)   I(max)
-2.5V     -1.233A    -1.246A    -1.23A
-1.174V   -179.1mA   -235.9mA   -144.4mA
-1.123V   -143.6mA   -200.7mA   -109.5mA
-1.072V   -110.2mA   -166.6mA   -78.57mA
-1.021V   -80.08mA   -134.1mA   -54.34mA
-970mV    -54.89mA   -103.7mA   -39.63mA
-919mV    -36.41mA   -76.3mA    -32.99mA
-817mV    -19.89mA   -34.81mA   -25.2mA
-715mV    -13.78mA   -14.11mA   -18.16mA
-511mV    -4.596mA   -3.904mA   -6.102mA
-256mV    -63.21uA   -177.9uA   -38.32uA
2.5V      -23.56nA   0A         -150.9nA
[POWER_clamp]
|Voltage   I(typ)   I(min)   I(max)
-2.5V     130.9mA    94.41mA    169.8mA
-1.937V   130.9mA    94.41mA    169.8mA
-1.835V   129.6mA    94.41mA    163.9mA
-1.733V   122.8mA    92.29mA    155mA
-1.478V   100.7mA    77.18mA    127mA
-866mV    35.87mA    29.9mA     45.33mA
-662mV    16.03mA    15.02mA    19.46mA
-560mV    7.73mA     8.668mA    8.662mA
-458mV    2.143mA    3.687mA    1.896mA
-356mV    647.1uA    1.015mA    754.8uA
-101mV    23.95uA    66.65uA    14.28uA
2.5V      0A         0A         0A
[Pulldown]
|Voltage   I(typ)   I(min)   I(max)
-2.5V     -2.07A     -2.558A    -2.62A
-1.208V   -331mA     -517.3mA   -342.6mA
-1.132V   -240.7mA   -408mA     -227.5mA
-1.056V   -159.5mA   -304.5mA   -132.1mA
-980mV    -96.2mA    -210.4mA   -76.81mA
-904mV    -60.38mA   -132.7mA   -61.04mA
-828mV    -47.63mA   -79.05mA   -54.22mA
-752mV    -42.4mA    -50.32mA   -47.9mA
-524mV    -29.41mA   -27.7mA    -30.45mA
616mV     28.4mA     27.55mA    28.4mA
2.972V    38.82mA    37.66mA    38.82mA
5V        151.4mA    146.9mA    151.4mA
[Pullup]
|Voltage   I(typ)   I(min)   I(max)
-2.5V     108.7mA    81.9mA     123.6mA
-2.068V   108.3mA    80.8mA     117.5mA
-1.764V   98.8mA     72.95mA    101mA
-472mV    24.44mA    17.38mA    18.79mA
592mV     -23.41mA   -22.7mA    -23.41mA
1.124V    -30.34mA   -29.43mA   -30.34mA
2.796V    -31.97mA   -31.01mA   -31.97mA
3.1V      -38.25mA   -37.1mA    -38.25mA
3.328V    -48.86mA   -47.39mA   -48.86mA
3.404V    -59.62mA   -57.83mA   -59.62mA
3.556V    -147.9mA   -143.5mA   -147.9mA
5V        -1.89A     -1.833A    -1.89A
[Ramp]
| variable   typ   min   max
dV/dt_r   0.894/0.158n   0.857/0.194n   0.909/0.221n
dV/dt_f   0.951/0.249n   0.921/0.263n   0.978/0.297n
R_load = 50.000
[Rising Waveform]
R_fixture = 50.000
V_fixture = 0.000
V_fixture_min = 0.000
V_fixture_max = 0.000
|  time   V(typ)   V(min)   V(max)
0s        64.19uV    -979.4uV   -305.7uV
685ps     7.74mV     -918.2uV   42.65mV
865ps     7.497mV    -5.018mV   880.1mV
982ps     23.58mV    -3.723mV   1.228V
1.232ns   1.266V     10.96mV    1.51V
1.354ns   1.46V      110.3mV    1.562V
1.535ns   1.518V     968mV      1.603V
1.764ns   1.541V     1.418V     1.623V
2.295ns   1.553V     1.527V     1.617V
10ns      1.503V     1.427V     1.515V
[Rising Waveform]
R_fixture = 50.000
V_fixture = 2.500
V_fixture_min = 2.380
V_fixture_max = 2.630
|  time   V(typ)   V(min)   V(max)
0s        901.2mV    848.2mV    1.003V
480ps     901.4mV    847.9mV    916.3mV
684ps     851.6mV    848.6mV    2.099V
812ps     1.707V     810.4mV    2.945V
823ps     1.775V     794.8mV    2.504V
893ps     2.108V     597.7mV    2.57V
1.063ns   2.751V     1.706V     2.609V
1.072ns   2.39V      1.749V     2.61V
1.374ns   2.488V     2.614V     2.627V
10ns      2.5V       2.383V     2.633V
[Falling Waveform]
R_fixture = 50.000
V_fixture = 2.500
V_fixture_min = 2.380
V_fixture_max = 2.630
|  time   V(typ)   V(min)   V(max)
0s        2.5V       2.383V     2.633V
642ps     2.5V       2.384V     2.519V
651ps     2.5V       2.384V     2.922V
876ps     2.426V     2.384V     1.675V
886ps     2.753V     2.384V     1.644V
1.179ns   1.276V     2.267V     1.166V
1.185ns   1.262V     2.614V     1.162V
1.474ns   970.7mV    1.246V     1.056V
2.304ns   904.5mV    868.1mV    1.011V
10ns      901.2mV    848.2mV    1.003V
[Falling Waveform]
R_fixture = 50.000
V_fixture = 0.000
V_fixture_min = 0.000
V_fixture_max = 0.000
|  time   V(typ)   V(min)   V(max)
0s        1.503V     1.427V     1.515V
486ps     1.502V     1.427V     1.534V
693ps     1.516V     1.427V     282.2mV
806ps     1.451V     1.433V     62.77mV
915ps     676.7mV    1.451V     11.28mV
1.036ns   92.02mV    1.403V     2.318mV
1.115ns   34.96mV    1.179V     721.1uV
1.264ns   6.342mV    217.9mV    -309.9uV
1.464ns   1.612mV    36.6mV     -679uV
10ns      64.19uV    -979.4uV   -305.7uV
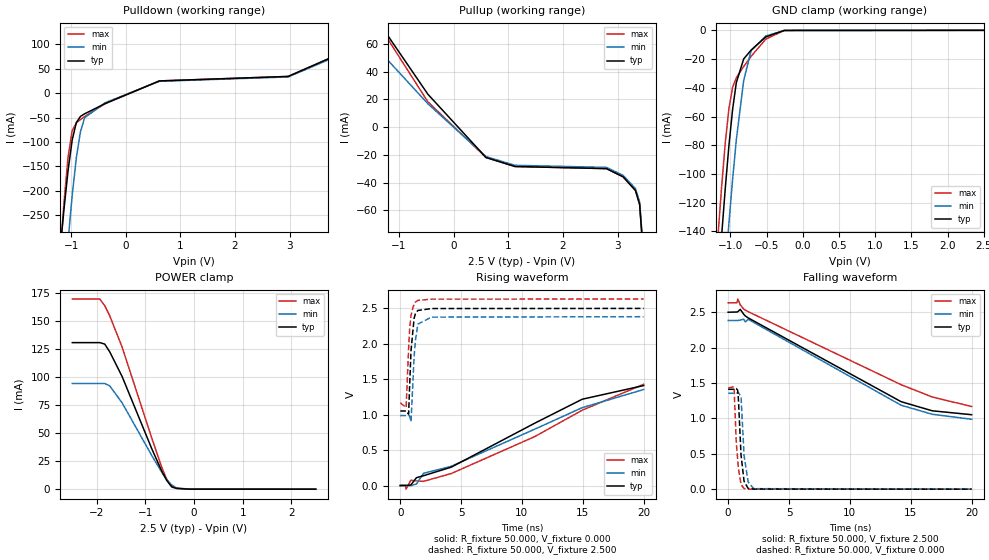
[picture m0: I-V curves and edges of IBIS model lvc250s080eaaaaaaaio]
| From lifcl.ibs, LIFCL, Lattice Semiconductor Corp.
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[Model] lvc250s080eaaaaaaaio
Model_type I/O
Polarity   Non-Inverting
Enable   Active-Low
Vinl =  0.700V
Vinh =  1.700V
Vmeas =  1.250V
Cref =  0.0F
Rref =  1.000M
Vref =  0.0V
C_comp   5.000pF   4.000pF   5.500pF
[Temperature Range]   25.000   0.125k   -40.000
[Voltage Range]   2.500V   2.380V   2.630V
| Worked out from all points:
|   slope of the pulldown table from 0 to 0.375 V, typ, clamps not added: 20.3 ohm
|   slope of the pullup table from 0 to 0.375 V, typ, clamps not added: 24.5 ohm
|   GND clamp passes 1 mA (typ) near -0.37 V on its own axis
|   POWER clamp passes 1 mA (typ) near -0.40 V on its own axis
|   rising waveform, R_fixture 50.000, V_fixture 0.000: 20-80 % time 9.28ns typ, 10.6ns min, 10ns max; typ from 0 V to 1.41 V
|   rising waveform, R_fixture 50.000, V_fixture 2.500: 20-80 % time 263ps typ, 298ps min, 275ps max; typ from 1.05 V to 2.5 V
|   falling waveform, R_fixture 50.000, V_fixture 2.500: 20-80 % time 8.81ns typ, 8.29ns min, 10.6ns max; typ from 2.5 V to 1.05 V
|   falling waveform, R_fixture 50.000, V_fixture 0.000: 20-80 % time 281ps typ, 298ps min, 288ps max; typ from 1.41 V to 0 V
[GND_clamp]
|Voltage   I(typ)   I(min)   I(max)
-2.5V     -1.233A    -1.246A    -1.23A
-1.174V   -179.1mA   -235.9mA   -144.4mA
-1.123V   -143.6mA   -200.7mA   -109.5mA
-1.072V   -110.2mA   -166.6mA   -78.57mA
-1.021V   -80.08mA   -134.1mA   -54.34mA
-970mV    -54.89mA   -103.7mA   -39.63mA
-919mV    -36.41mA   -76.3mA    -32.99mA
-817mV    -19.89mA   -34.81mA   -25.2mA
-715mV    -13.78mA   -14.11mA   -18.16mA
-511mV    -4.596mA   -3.904mA   -6.102mA
-256mV    -63.21uA   -177.9uA   -38.32uA
2.5V      -23.56nA   0A         -150.9nA
[POWER_clamp]
|Voltage   I(typ)   I(min)   I(max)
-2.5V     130.9mA    94.41mA    169.8mA
-1.937V   130.9mA    94.41mA    169.8mA
-1.835V   129.6mA    94.41mA    163.9mA
-1.733V   122.8mA    92.29mA    155mA
-1.478V   100.7mA    77.18mA    127mA
-866mV    35.87mA    29.9mA     45.33mA
-662mV    16.03mA    15.02mA    19.46mA
-560mV    7.73mA     8.668mA    8.662mA
-458mV    2.143mA    3.687mA    1.896mA
-356mV    647.1uA    1.015mA    754.8uA
-101mV    23.95uA    66.65uA    14.28uA
2.5V      0A         0A         0A
[Pulldown]
|Voltage   I(typ)   I(min)   I(max)
-2.5V     -2.07A     -2.558A    -2.62A
-1.208V   -331mA     -517.3mA   -342.6mA
-1.132V   -240.7mA   -408mA     -227.5mA
-1.056V   -159.5mA   -304.5mA   -132.1mA
-980mV    -96.2mA    -210.4mA   -76.81mA
-904mV    -60.38mA   -132.7mA   -61.04mA
-828mV    -47.63mA   -79.05mA   -54.22mA
-752mV    -42.4mA    -50.32mA   -47.9mA
-372mV    -21.13mA   -19.43mA   -21.22mA
616mV     25.13mA    24.38mA    25.13mA
2.972V    34.35mA    33.32mA    34.35mA
5V        134mA      130mA      134mA
[Pullup]
|Voltage   I(typ)   I(min)   I(max)
-2.5V     105.7mA    79.6mA     120.1mA
-1.992V   103.8mA    77.3mA     110.7mA
-1.536V   85mA       62.39mA    83.9mA
-472mV    23.75mA    16.9mA     18.26mA
592mV     -21.87mA   -21.22mA   -21.87mA
1.124V    -28.36mA   -27.51mA   -28.36mA
2.796V    -29.88mA   -28.99mA   -29.88mA
3.1V      -35.75mA   -34.68mA   -35.75mA
3.328V    -45.66mA   -44.29mA   -45.66mA
3.404V    -55.72mA   -54.05mA   -55.72mA
3.556V    -138.2mA   -134.1mA   -138.2mA
5V        -1.766A    -1.713A    -1.766A
[Ramp]
| variable   typ   min   max
dV/dt_r   0.847/9.273n   0.813/10.559n   0.857/10.016n
dV/dt_f   0.868/8.811n   0.837/8.301n   0.878/10.585n
R_load = 50.000
[Rising Waveform]
R_fixture = 50.000
V_fixture = 0.000
V_fixture_min = 0.000
V_fixture_max = 0.000
|  time   V(typ)   V(min)   V(max)
0s        64.19uV    -272.3uV   349.5uV
436ps     151.5uV    -457.7uV   2.678mV
479ps     187.8uV    -278.7uV   -51.51mV
874ps     8.061mV    -1.916mV   74.2mV
1.334ns   110.4mV    21.91mV    65.41mV
1.914ns   138.3mV    172mV      58.59mV
4.194ns   259.4mV    271.8mV    169.3mV
11.03ns   877.9mV    793.8mV    688.9mV
14.95ns   1.218V     1.099V     1.063V
20ns      1.411V     1.355V     1.429V
[Rising Waveform]
R_fixture = 50.000
V_fixture = 2.500
V_fixture_min = 2.380
V_fixture_max = 2.630
|  time   V(typ)   V(min)   V(max)
0s        1.052V     987.3mV    1.168V
483ps     1.052V     987.1mV    1.101V
688ps     1.007V     987.6mV    1.935V
777ps     1.435V     984.6mV    2.221V
887ps     1.908V     899.9mV    2.408V
1.139ns   2.36V      1.82V      2.565V
1.257ns   2.433V     2.059V     2.591V
1.447ns   2.471V     2.278V     2.613V
2.567ns   2.498V     2.377V     2.631V
20ns      2.5V       2.383V     2.632V
[Falling Waveform]
R_fixture = 50.000
V_fixture = 2.500
V_fixture_min = 2.380
V_fixture_max = 2.630
|  time   V(typ)   V(min)   V(max)
0s        2.5V       2.383V     2.632V
721ps     2.503V     2.383V     2.635V
800ps     2.509V     2.383V     2.686V
998ps     2.54V      2.39V      2.603V
1.274ns   2.472V     2.403V     2.546V
1.414ns   2.447V     2.362V     2.529V
1.644ns   2.42V      2.4V       2.508V
14.21ns   1.236V     1.186V     1.476V
16.77ns   1.107V     1.058V     1.302V
20ns      1.052V     987.3mV    1.168V
[Falling Waveform]
R_fixture = 50.000
V_fixture = 0.000
V_fixture_min = 0.000
V_fixture_max = 0.000
|  time   V(typ)   V(min)   V(max)
0s        1.411V     1.355V     1.429V
486ps     1.411V     1.355V     1.449V
657ps     1.421V     1.355V     685.4mV
778ps     1.4V       1.359V     428.4mV
838ps     1.285V     1.367V     297.2mV
1.058ns   482.1mV    1.305V     63.92mV
1.308ns   110.5mV    473.9mV    9.185mV
1.644ns   10.41mV    100.8mV    404.4uV
2.104ns   775.5uV    6.884mV    -241.6uV
20ns      64.19uV    -272.3uV   349.5uV
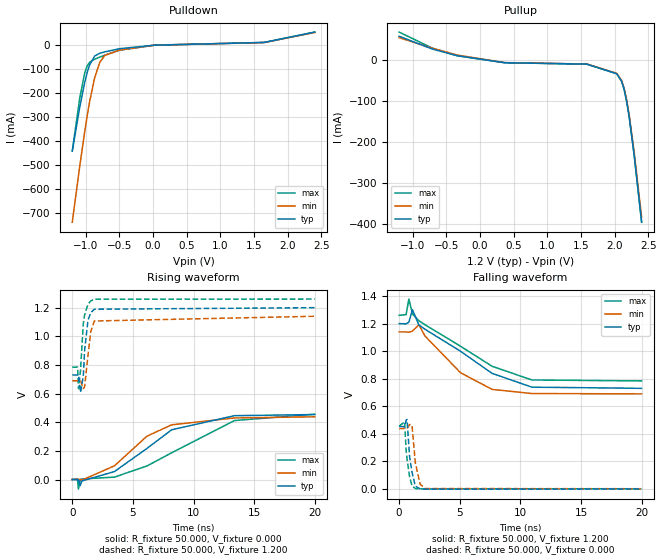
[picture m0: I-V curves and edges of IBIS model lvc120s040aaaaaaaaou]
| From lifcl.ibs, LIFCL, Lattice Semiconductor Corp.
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[Model] lvc120s040aaaaaaaaou
Model_type Output
Polarity   Non-Inverting
Enable   Active-High
Vmeas =  0.600V
Cref =  0.0F
Rref =  1.000M
Vref =  0.0V
C_comp   5.000pF   4.000pF   5.500pF
[Temperature Range]   25.000   0.125k   -40.000
[Voltage Range]   1.200V   1.140V   1.260V
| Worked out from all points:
|   slope of the pulldown table from 0 to 0.18 V, typ, clamps not added: 45.6 ohm
|   slope of the pullup table from 0 to 0.18 V, typ, clamps not added: 43.8 ohm
|   rising waveform, R_fixture 50.000, V_fixture 0.000: 20-80 % time 4.35ns typ, 3.77ns min, 5.72ns max; typ from 0 V to 0.455 V
|   rising waveform, R_fixture 50.000, V_fixture 1.200: 20-80 % time 302ps typ, 365ps min, 312ps max; typ from 0.731 V to 1.2 V
|   falling waveform, R_fixture 50.000, V_fixture 1.200: 20-80 % time 4.76ns typ, 3.21ns min, 5.22ns max; typ from 1.2 V to 0.731 V
|   falling waveform, R_fixture 50.000, V_fixture 0.000: 20-80 % time 350ps typ, 351ps min, 330ps max; typ from 0.455 V to 0 V
[Pulldown]
|Voltage   I(typ)   I(min)   I(max)
-1.2V     -441.6mA   -738mA     -440.6mA
-1.089V   -258.3mA   -504.2mA   -220.2mA
-1.015V   -154.4mA   -360.1mA   -115.5mA
-978mV    -112.8mA   -293.7mA   -85.62mA
-941mV    -80.57mA   -233mA     -70.15mA
-867mV    -44.83mA   -134.2mA   -57.93mA
-793mV    -33.38mA   -72.24mA   -49.48mA
-719mV    -27.62mA   -42.24mA   -41.41mA
-497mV    -14.12mA   -19.88mA   -20.43mA
21mV      490.7uA    476uA      490.7uA
1.649V    11.87mA    11.51mA    11.87mA
2.4V      55.07mA    53.42mA    55.07mA
[Pullup]
|Voltage   I(typ)   I(min)   I(max)
-1.2V     57.35mA    53.86mA    67.44mA
-708mV    26.12mA    28.22mA    28.39mA
-338mV    9.874mA    11.59mA    9.954mA
365mV     -7.099mA   -6.886mA   -7.099mA
1.586V    -10.59mA   -10.27mA   -10.59mA
2.03V     -33.9mA    -32.88mA   -33.9mA
2.104V    -52.39mA   -50.81mA   -52.39mA
2.141V    -72.29mA   -70.12mA   -72.29mA
2.178V    -101.1mA   -98.08mA   -101.1mA
2.215V    -138.3mA   -134.2mA   -138.3mA
2.289V    -231.3mA   -224.4mA   -231.3mA
2.4V      -395.4mA   -383.5mA   -395.4mA
[Ramp]
| variable   typ   min   max
dV/dt_r   0.273/4.348n   0.263/3.796n   0.273/5.783n
dV/dt_f   0.282/4.764n   0.266/3.242n   0.285/5.224n
R_load = 50.000
[Rising Waveform]
R_fixture = 50.000
V_fixture = 0.000
V_fixture_min = 0.000
V_fixture_max = 0.000
|  time   V(typ)   V(min)   V(max)
0s        37.02uV    2.187mV    2.165mV
430ps     71.28uV    2.075mV    4.898mV
503ps     28.81uV    2.191mV    -66.02mV
654ps     -41.63mV   2.252mV    -105.1uV
791ps     -8.962mV   -3.289mV   5.09mV
3.484ns   56.91mV    97.1mV     18.19mV
6.16ns    218.3mV    303.8mV    95.86mV
8.2ns     348.3mV    382.9mV    187.9mV
13.38ns   446.6mV    430.8mV    412.7mV
20ns      454.5mV    438.7mV    456.6mV
[Rising Waveform]
R_fixture = 50.000
V_fixture = 1.200
V_fixture_min = 1.140
V_fixture_max = 1.260
|  time   V(typ)   V(min)   V(max)
0s        730.5mV    690.3mV    784.2mV
437ps     730.5mV    690.2mV    786mV
518ps     730.5mV    690.3mV    635.4mV
683ps     609.3mV    690.3mV    766.3mV
907ps     722.1mV    635.7mV    1.087V
1.017ns   900mV      647.2mV    1.15V
1.297ns   1.113V     866.9mV    1.224V
1.527ns   1.165V     1.033V     1.247V
1.816ns   1.189V     1.107V     1.259V
20ns      1.2V       1.14V      1.26V
[Falling Waveform]
R_fixture = 50.000
V_fixture = 1.200
V_fixture_min = 1.140
V_fixture_max = 1.260
|  time   V(typ)   V(min)   V(max)
0s        1.2V       1.14V      1.26V
573ps     1.198V     1.14V      1.265V
802ps     1.21V      1.137V     1.378V
1.093ns   1.301V     1.146V     1.271V
1.629ns   1.19V      1.191V     1.221V
2.129ns   1.159V     1.11V      1.192V
5.06ns    999.6mV    843.8mV    1.036V
7.66ns    839.3mV    722.9mV    890.6mV
10.95ns   739mV      692.7mV    791.1mV
20ns      730.5mV    690.3mV    784.2mV
[Falling Waveform]
R_fixture = 50.000
V_fixture = 0.000
V_fixture_min = 0.000
V_fixture_max = 0.000
|  time   V(typ)   V(min)   V(max)
0s        454.5mV    438.7mV    456.6mV
446ps     452.4mV    438.7mV    486.7mV
583ps     500.3mV    438.4mV    271.2mV
650ps     504.5mV    437.5mV    220.5mV
860ps     236.3mV    468.2mV    91.09mV
1.057ns   123.5mV    462.9mV    23.24mV
1.336ns   20.59mV    189.9mV    3.681mV
1.737ns   581.3uV    33.02mV    843.7uV
2.177ns   -929.9uV   3.657mV    930.9uV
20ns      37.02uV    2.187mV    2.165mV
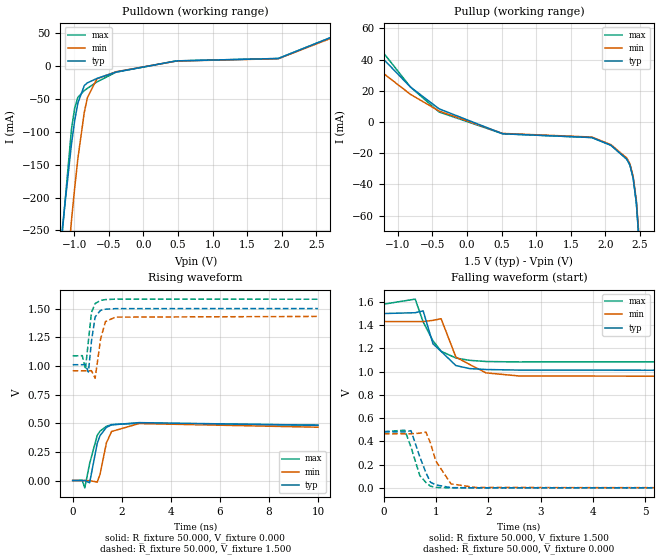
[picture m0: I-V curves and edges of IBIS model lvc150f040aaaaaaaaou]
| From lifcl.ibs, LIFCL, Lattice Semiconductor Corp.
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[Model] lvc150f040aaaaaaaaou
Model_type Output
Polarity   Non-Inverting
Enable   Active-High
Vmeas =  0.750V
Cref =  0.0F
Rref =  1.000M
Vref =  0.0V
C_comp   5.000pF   4.000pF   5.500pF
[Temperature Range]   25.000   0.125k   -40.000
[Voltage Range]   1.500V   1.430V   1.580V
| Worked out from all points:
|   slope of the pulldown table from 0 to 0.225 V, typ, clamps not added: 48.6 ohm
|   slope of the pullup table from 0 to 0.225 V, typ, clamps not added: 58 ohm
|   rising waveform, R_fixture 50.000, V_fixture 0.000: 20-80 % time 298ps typ, 290ps min, 329ps max; typ from 0 V to 0.481 V
|   rising waveform, R_fixture 50.000, V_fixture 1.500: 20-80 % time 165ps typ, 222ps min, 153ps max; typ from 1.01 V to 1.5 V
|   falling waveform, R_fixture 50.000, V_fixture 1.500: 20-80 % time 378ps typ, 479ps min, 385ps max; typ from 1.5 V to 1.01 V
|   falling waveform, R_fixture 50.000, V_fixture 0.000: 20-80 % time 231ps typ, 273ps min, 212ps max; typ from 0.481 V to 0 V
[Pulldown]
|Voltage   I(typ)   I(min)   I(max)
-1.5V     -615.2mA   -812.9mA   -743.9mA
-1.178V   -251.8mA   -397.1mA   -259.2mA
-1.04V    -117.9mA   -234.3mA   -95.39mA
-994mV    -82.8mA    -185.2mA   -63.6mA
-948mV    -56.07mA   -140.5mA   -47.52mA
-856mV    -29.67mA   -70.63mA   -37.24mA
-810mV    -25.39mA   -47.96mA   -33.78mA
-672mV    -18.7mA    -19.23mA   -23.99mA
-396mV    -9.008mA   -8.485mA   -9.129mA
478mV     7.981mA    7.741mA    7.981mA
1.95V     11.62mA    11.28mA    11.62mA
3V        55.78mA    54.1mA     55.78mA
[Pullup]
|Voltage   I(typ)   I(min)   I(max)
-1.5V     53.63mA    41.21mA    60.73mA
-818mV    22.45mA    17.76mA    22.46mA
-404mV    8.467mA    7.042mA    6.425mA
516mV     -7.537mA   -7.311mA   -7.537mA
1.804V    -9.941mA   -9.642mA   -9.941mA
2.08V     -14.9mA    -14.45mA   -14.9mA
2.31V     -23.81mA   -23.09mA   -23.81mA
2.356V    -27.64mA   -26.81mA   -27.64mA
2.402V    -35.88mA   -34.81mA   -35.88mA
2.448V    -51.56mA   -50.02mA   -51.56mA
2.54V     -107.9mA   -104.7mA   -107.9mA
3V        -561.8mA   -544.9mA   -561.8mA
[Ramp]
| variable   typ   min   max
dV/dt_r   0.289/0.299n   0.279/0.291n   0.288/0.329n
dV/dt_f   0.294/0.378n   0.286/0.480n   0.296/0.384n
R_load = 50.000
[Rising Waveform]
R_fixture = 50.000
V_fixture = 0.000
V_fixture_min = 0.000
V_fixture_max = 0.000
|  time   V(typ)   V(min)   V(max)
0s        47.12uV    -564uV     138.4uV
390ps     56.71uV    -860.1uV   1.652mV
492ps     168.6uV    -580.2uV   -64.12mV
690ps     -19.21mV   -465.5uV   147.6mV
1ns       324.1mV    -13.78mV   394.2mV
1.114ns   392.1mV    53.46mV    430.5mV
1.375ns   463.1mV    328.5mV    472.8mV
1.584ns   485.2mV    427.5mV    487.5mV
2.705ns   504.8mV    496.9mV    499.3mV
10ns      481.4mV    464.8mV    483.4mV
[Rising Waveform]
R_fixture = 50.000
V_fixture = 1.500
V_fixture_min = 1.430
V_fixture_max = 1.580
|  time   V(typ)   V(min)   V(max)
0s        1.01V      957.2mV    1.087V
390ps     1.01V      956.9mV    1.089V
519ps     1.011V     957.2mV    970.9mV
640ps     946.2mV    957.3mV    1.217V
765ps     1.216V     957.8mV    1.466V
915ps     1.427V     892.2mV    1.544V
1.139ns   1.485V     1.236V     1.571V
1.335ns   1.494V     1.386V     1.578V
1.745ns   1.499V     1.425V     1.582V
10ns      1.5V       1.431V     1.581V
[Falling Waveform]
R_fixture = 50.000
V_fixture = 1.500
V_fixture_min = 1.430
V_fixture_max = 1.580
|  time   V(typ)   V(min)   V(max)
0s        1.5V       1.431V     1.581V
597ps     1.507V     1.431V     1.624V
750ps     1.523V     1.431V     1.428V
937ps     1.24V      1.441V     1.266V
1.094ns   1.174V     1.455V     1.175V
1.377ns   1.052V     1.125V     1.117V
1.638ns   1.026V     1.062V     1.097V
1.953ns   1.018V     989.2mV    1.087V
2.584ns   1.013V     962.5mV    1.083V
10ns      1.01V      957.2mV    1.087V
[Falling Waveform]
R_fixture = 50.000
V_fixture = 0.000
V_fixture_min = 0.000
V_fixture_max = 0.000
|  time   V(typ)   V(min)   V(max)
0s        481.4mV    464.8mV    483.4mV
398ps     480.9mV    464.5mV    495.4mV
517ps     491.5mV    464.6mV    350.5mV
685ps     267mV      469.6mV    105.5mV
804ps     129mV      479mV      44.91mV
889ps     47.67mV    385.2mV    13.67mV
993ps     24.81mV    229.8mV    2.776mV
1.283ns   700.9uV    33.25mV    -959.9uV
1.763ns   -372.3uV   2.083mV    -984.9uV
10ns      47.12uV    -564uV     138.4uV
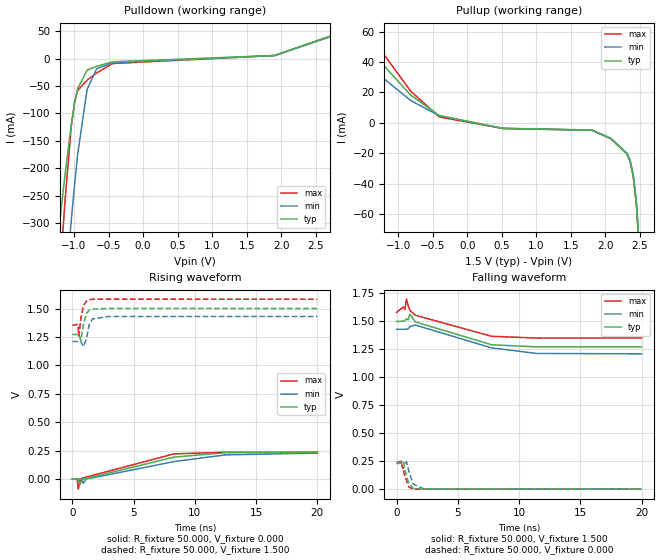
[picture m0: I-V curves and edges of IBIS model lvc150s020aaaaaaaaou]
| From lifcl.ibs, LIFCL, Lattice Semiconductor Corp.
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[Model] lvc150s020aaaaaaaaou
Model_type Output
Polarity   Non-Inverting
Enable   Active-High
Vmeas =  0.750V
Cref =  0.0F
Rref =  1.000M
Vref =  0.0V
C_comp   5.000pF   4.000pF   5.500pF
[Temperature Range]   25.000   0.125k   -40.000
[Voltage Range]   1.500V   1.430V   1.580V
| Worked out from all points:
|   slope of the pulldown table from 0 to 0.225 V, typ, clamps not added: 101 ohm
|   slope of the pullup table from 0 to 0.225 V, typ, clamps not added: 113 ohm
|   rising waveform, R_fixture 50.000, V_fixture 0.000: 20-80 % time 4.36ns typ, 5.38ns min, 3.84ns max; typ from 0 V to 0.236 V
|   rising waveform, R_fixture 50.000, V_fixture 1.500: 20-80 % time 278ps typ, 290ps min, 268ps max; typ from 1.27 V to 1.5 V
|   falling waveform, R_fixture 50.000, V_fixture 1.500: 20-80 % time 4.03ns typ, 4.46ns min, 4.42ns max; typ from 1.5 V to 1.27 V
|   falling waveform, R_fixture 50.000, V_fixture 0.000: 20-80 % time 422ps typ, 384ps min, 321ps max; typ from 0.236 V to 0 V
[Pulldown]
|Voltage   I(typ)   I(min)   I(max)
-1.5V     -652.2mA   -1.036A    -999mA
-1.224V   -318.3mA   -578.1mA   -434.5mA
-1.178V   -265.7mA   -504.8mA   -346.6mA
-1.132V   -214.8mA   -433.1mA   -263.5mA
-1.04V    -122.4mA   -296.4mA   -124.8mA
-994mV    -84.5mA    -233.5mA   -80.91mA
-948mV    -55.33mA   -176mA     -58.34mA
-810mV    -21.18mA   -56.2mA    -39.43mA
-672mV    -14.17mA   -18.72mA   -26.31mA
-442mV    -5.972mA   -7.548mA   -9.089mA
1.904V    5.551mA    5.384mA    5.551mA
3V        53.44mA    51.84mA    53.44mA
[Pullup]
|Voltage   I(typ)   I(min)   I(max)
-1.5V     52.08mA    39.77mA    63.11mA
-818mV    18.17mA    14.6mA     20.75mA
-404mV    4.77mA     4.559mA    3.77mA
516mV     -3.782mA   -3.668mA   -3.782mA
1.804V    -4.928mA   -4.781mA   -4.928mA
2.08V     -10.53mA   -10.21mA   -10.53mA
2.31V     -20.54mA   -19.93mA   -20.54mA
2.356V    -25.06mA   -24.31mA   -25.06mA
2.402V    -34.81mA   -33.76mA   -34.81mA
2.448V    -53.02mA   -51.42mA   -53.02mA
2.54V     -117mA     -113.5mA   -117mA
3V        -622.5mA   -603.8mA   -622.5mA
[Ramp]
| variable   typ   min   max
dV/dt_r   0.142/4.376n   0.137/5.392n   0.141/3.839n
dV/dt_f   0.137/4.046n   0.132/4.463n   0.137/4.421n
R_load = 50.000
[Rising Waveform]
R_fixture = 50.000
V_fixture = 0.000
V_fixture_min = 0.000
V_fixture_max = 0.000
|  time   V(typ)   V(min)   V(max)
0s        33.82uV    750.8uV    1.217mV
390ps     14.96uV    575.7uV    3.108mV
482ps     116.7uV    710uV      -88.07mV
617ps     -48.91mV   799.3uV    -12.89mV
795ps     -3.649mV   -5.2mV     8.069mV
884ps     1.09mV     -36.1mV    11.39mV
1.134ns   5.412mV    669.3uV    18.47mV
8.3ns     193.6mV    154.5mV    222.2mV
12.48ns   232.3mV    213.1mV    236.2mV
20ns      236.3mV    229.1mV    236.5mV
[Rising Waveform]
R_fixture = 50.000
V_fixture = 1.500
V_fixture_min = 1.430
V_fixture_max = 1.580
|  time   V(typ)   V(min)   V(max)
0s        1.272V     1.21V      1.352V
446ps     1.272V     1.21V      1.36V
527ps     1.274V     1.21V      1.258V
685ps     1.219V     1.21V      1.409V
898ps     1.357V     1.165V     1.524V
1.148ns   1.458V     1.232V     1.564V
1.364ns   1.484V     1.355V     1.576V
1.634ns   1.495V     1.408V     1.581V
2.965ns   1.501V     1.43V      1.583V
20ns      1.5V       1.43V      1.581V
[Falling Waveform]
R_fixture = 50.000
V_fixture = 1.500
V_fixture_min = 1.430
V_fixture_max = 1.580
|  time   V(typ)   V(min)   V(max)
0s        1.5V       1.43V      1.581V
555ps     1.502V     1.43V      1.629V
678ps     1.506V     1.43V      1.608V
805ps     1.524V     1.431V     1.7V
948ps     1.515V     1.433V     1.639V
1.098ns   1.565V     1.454V     1.597V
1.543ns   1.495V     1.467V     1.555V
7.76ns    1.291V     1.263V     1.367V
11.46ns   1.272V     1.213V     1.351V
20ns      1.272V     1.21V      1.352V
[Falling Waveform]
R_fixture = 50.000
V_fixture = 0.000
V_fixture_min = 0.000
V_fixture_max = 0.000
|  time   V(typ)   V(min)   V(max)
0s        236.3mV    229.1mV    236.5mV
397ps     235.9mV    228.9mV    248.5mV
495ps     246.6mV    229mV      184mV
545ps     249.1mV    228.9mV    191.8mV
675ps     173.6mV    231.1mV    105.1mV
808ps     115mV      244.2mV    79.55mV
998ps     54.89mV    161.8mV    17.97mV
1.348ns   6.169mV    44.98mV    -69.51uV
2.268ns   -975.2uV   148.4uV    -825.5uV
20ns      33.82uV    750.8uV    1.217mV
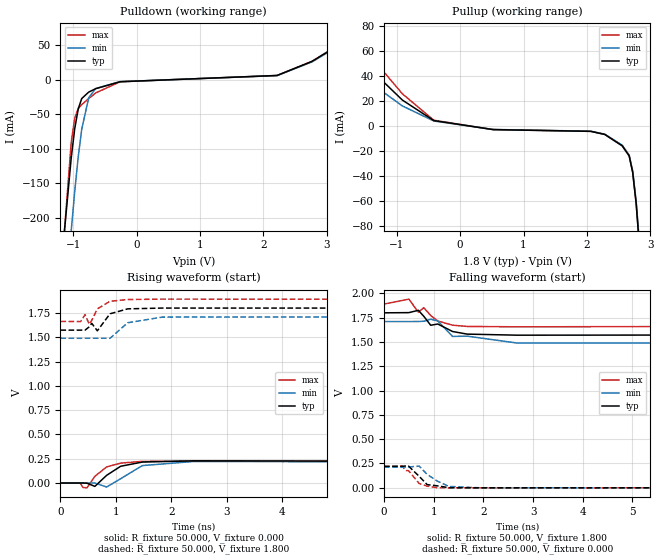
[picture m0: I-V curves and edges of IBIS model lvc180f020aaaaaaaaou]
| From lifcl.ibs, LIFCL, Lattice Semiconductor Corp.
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[Model] lvc180f020aaaaaaaaou
Model_type Output
Polarity   Non-Inverting
Enable   Active-High
Vmeas =  0.900V
Cref =  0.0F
Rref =  1.000M
Vref =  0.0V
C_comp   5.000pF   4.000pF   5.500pF
[Temperature Range]   25.000   0.125k   -40.000
[Voltage Range]   1.800V   1.710V   1.890V
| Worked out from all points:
|   slope of the pulldown table from 0 to 0.27 V, typ, clamps not added: 105 ohm
|   slope of the pullup table from 0 to 0.27 V, typ, clamps not added: 152 ohm
|   rising waveform, R_fixture 50.000, V_fixture 0.000: 20-80 % time 330ps typ, 349ps min, 287ps max; typ from 0 V to 0.22 V
|   rising waveform, R_fixture 50.000, V_fixture 1.800: 20-80 % time 195ps typ, 243ps min, 180ps max; typ from 1.57 V to 1.8 V
|   falling waveform, R_fixture 50.000, V_fixture 1.800: 20-80 % time 511ps typ, 654ps min, 289ps max; typ from 1.8 V to 1.57 V
|   falling waveform, R_fixture 50.000, V_fixture 0.000: 20-80 % time 264ps typ, 330ps min, 201ps max; typ from 0.22 V to 0 V
[Pulldown]
|Voltage   I(typ)   I(min)   I(max)
-1.8V     -1.023A    -1.199A    -1.31A
-1.14V    -222.4mA   -344.6mA   -222.3mA
-1.03V    -113.2mA   -218.6mA   -90.97mA
-975mV    -71.04mA   -161.9mA   -55.48mA
-920mV    -42.35mA   -112mA     -41.66mA
-865mV    -27.27mA   -71.92mA   -36.05mA
-755mV    -17.88mA   -26.29mA   -27.26mA
-645mV    -12.94mA   -12.68mA   -19.14mA
-260mV    -2.838mA   -2.717mA   -2.912mA
2.215V    6.236mA    6.049mA    6.236mA
2.765V    26.66mA    25.86mA    26.66mA
3.6V      73.71mA    71.5mA     73.71mA
[Pullup]
|Voltage   I(typ)   I(min)   I(max)
-1.8V     64.13mA    48.54mA    78.9mA
-910mV    20.55mA    15.86mA    25.57mA
-415mV    4.154mA    3.826mA    4.468mA
520mV     -3.053mA   -2.961mA   -3.053mA
2.06V     -4.457mA   -4.323mA   -4.457mA
2.28V     -6.921mA   -6.713mA   -6.921mA
2.555V    -16.01mA   -15.53mA   -16.01mA
2.665V    -24.11mA   -23.39mA   -24.11mA
2.72V     -37.19mA   -36.07mA   -37.19mA
2.775V    -62.11mA   -60.25mA   -62.11mA
2.83V     -98.7mA    -95.7mA    -98.7mA
3.6V      -890.9mA   -864.2mA   -890.9mA
[Ramp]
| variable   typ   min   max
dV/dt_r   0.132/0.330n   0.128/0.351n   0.132/0.285n
dV/dt_f   0.136/0.509n   0.133/0.659n   0.136/0.475n
R_load = 50.000
[Rising Waveform]
R_fixture = 50.000
V_fixture = 0.000
V_fixture_min = 0.000
V_fixture_max = 0.000
|  time   V(typ)   V(min)   V(max)
0s        42.3uV     -225.7uV   288.9uV
354ps     -15.04uV   -354.2uV   1.5mV
407ps     97.17uV    -387.2uV   -45.82mV
478ps     -1.26mV    -282.2uV   -49.6mV
621ps     -34.38mV   -128.8uV   69.04mV
834ps     79.41mV    -40.9mV    166mV
1.087ns   172.7mV    44.65mV    205mV
1.477ns   215.7mV    179.4mV    222.8mV
2.404ns   228.6mV    221.8mV    226.3mV
10ns      220.1mV    213.4mV    220.2mV
[Rising Waveform]
R_fixture = 50.000
V_fixture = 1.800
V_fixture_min = 1.710
V_fixture_max = 1.890
|  time   V(typ)   V(min)   V(max)
0s        1.573V     1.49V      1.663V
363ps     1.573V     1.489V     1.661V
444ps     1.573V     1.49V      1.733V
520ps     1.607V     1.49V      1.633V
565ps     1.643V     1.49V      1.674V
666ps     1.566V     1.49V      1.792V
894ps     1.741V     1.489V     1.87V
1.214ns   1.792V     1.649V     1.888V
1.834ns   1.8V       1.707V     1.892V
10ns      1.8V       1.71V      1.89V
[Falling Waveform]
R_fixture = 50.000
V_fixture = 1.800
V_fixture_min = 1.710
V_fixture_max = 1.890
|  time   V(typ)   V(min)   V(max)
0s        1.8V       1.71V      1.89V
501ps     1.802V     1.71V      1.941V
691ps     1.826V     1.711V     1.806V
801ps     1.764V     1.713V     1.853V
940ps     1.672V     1.734V     1.772V
1.082ns   1.685V     1.717V     1.716V
1.379ns   1.608V     1.557V     1.673V
1.672ns   1.581V     1.56V      1.66V
2.681ns   1.57V      1.489V     1.656V
10ns      1.573V     1.49V      1.663V
[Falling Waveform]
R_fixture = 50.000
V_fixture = 0.000
V_fixture_min = 0.000
V_fixture_max = 0.000
|  time   V(typ)   V(min)   V(max)
0s        220.1mV    213.4mV    220.2mV
368ps     220mV      213.3mV    224.6mV
436ps     224.7mV    213.3mV    175.9mV
491ps     223.7mV    213.3mV    177mV
708ps     117.6mV    222.8mV    43.57mV
868ps     32.23mV    137.4mV    16.57mV
1.076ns   19.53mV    67.52mV    605.3uV
1.308ns   713.3uV    13.62mV    -1.114mV
1.917ns   -885.1uV   -266.9uV   -1.004mV
10ns      42.3uV     -225.7uV   288.9uV
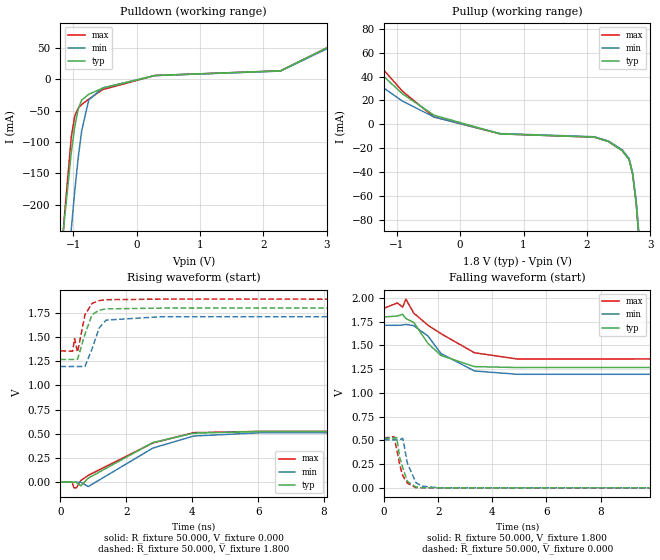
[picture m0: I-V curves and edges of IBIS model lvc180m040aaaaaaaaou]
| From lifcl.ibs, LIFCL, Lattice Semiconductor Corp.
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[Model] lvc180m040aaaaaaaaou
Model_type Output
Polarity   Non-Inverting
Enable   Active-High
Vmeas =  0.900V
Cref =  0.0F
Rref =  1.000M
Vref =  0.0V
C_comp   5.000pF   4.000pF   5.500pF
[Temperature Range]   25.000   0.125k   -40.000
[Voltage Range]   1.800V   1.710V   1.890V
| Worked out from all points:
|   slope of the pulldown table from 0 to 0.27 V, typ, clamps not added: 46.9 ohm
|   slope of the pullup table from 0 to 0.27 V, typ, clamps not added: 66.8 ohm
|   rising waveform, R_fixture 50.000, V_fixture 0.000: 20-80 % time 1.71ns typ, 1.7ns min, 1.85ns max; typ from 0 V to 0.523 V
|   rising waveform, R_fixture 50.000, V_fixture 1.800: 20-80 % time 284ps typ, 313ps min, 217ps max; typ from 1.27 V to 1.8 V
|   falling waveform, R_fixture 50.000, V_fixture 1.800: 20-80 % time 1ns typ, 1.23ns min, 1.73ns max; typ from 1.8 V to 1.27 V
|   falling waveform, R_fixture 50.000, V_fixture 0.000: 20-80 % time 276ps typ, 311ps min, 332ps max; typ from 0.523 V to 0 V
[Pulldown]
|Voltage   I(typ)   I(min)   I(max)
-1.8V     -1.035A    -1.307A    -1.293A
-1.195V   -288.5mA   -449.6mA   -300.7mA
-1.14V    -227mA     -377mA     -221mA
-1.03V    -117.3mA   -240.3mA   -92.67mA
-975mV    -75.6mA    -178.7mA   -58.7mA
-920mV    -47.57mA   -124.9mA   -45.7mA
-865mV    -33.08mA   -81.93mA   -40.28mA
-755mV    -23.91mA   -33.27mA   -31.62mA
-535mV    -14.21mA   -13.63mA   -16.41mA
290mV     6.108mA    5.925mA    6.108mA
2.27V     13.56mA    13.15mA    13.56mA
3.6V      80.37mA    77.96mA    80.37mA
[Pullup]
|Voltage   I(typ)   I(min)   I(max)
-1.8V     69.64mA    52.58mA    81.3mA
-910mV    25.55mA    19.41mA    27.74mA
-415mV    7.654mA    6.149mA    6.163mA
630mV     -8.033mA   -7.792mA   -8.033mA
2.115V    -10.77mA   -10.45mA   -10.77mA
2.335V    -14.38mA   -13.95mA   -14.38mA
2.555V    -22.02mA   -21.36mA   -22.02mA
2.665V    -29.69mA   -28.8mA    -29.69mA
2.72V     -41.99mA   -40.73mA   -41.99mA
2.775V    -65.96mA   -63.98mA   -65.96mA
2.83V     -101.9mA   -98.8mA    -101.9mA
3.6V      -893.2mA   -866.4mA   -893.2mA
[Ramp]
| variable   typ   min   max
dV/dt_r   0.314/1.709n   0.306/1.769n   0.315/1.891n
dV/dt_f   0.319/1.004n   0.309/1.224n   0.320/1.734n
R_load = 50.000
[Rising Waveform]
R_fixture = 50.000
V_fixture = 0.000
V_fixture_min = 0.000
V_fixture_max = 0.000
|  time   V(typ)   V(min)   V(max)
0s        56.24uV    -535uV     108.4uV
354ps     72nV       -803.8uV   1.708mV
407ps     201.7uV    -841uV     -58.31mV
482ps     -2.336mV   -605.5uV   -59mV
616ps     -38.21mV   -321.8uV   16.06mV
844ps     41.49mV    -45.45mV   70.75mV
2.804ns   409.4mV    352.4mV    405.2mV
4.043ns   506.9mV    477mV      512.2mV
6.08ns    524.6mV    511.1mV    525.2mV
20ns      522.7mV    504.6mV    524.5mV
[Rising Waveform]
R_fixture = 50.000
V_fixture = 1.800
V_fixture_min = 1.710
V_fixture_max = 1.890
|  time   V(typ)   V(min)   V(max)
0s        1.269V     1.196V     1.358V
371ps     1.269V     1.196V     1.354V
429ps     1.269V     1.196V     1.486V
520ps     1.272V     1.196V     1.346V
744ps     1.53V      1.197V     1.732V
959ps     1.731V     1.378V     1.848V
1.174ns   1.779V     1.594V     1.878V
1.384ns   1.792V     1.676V     1.887V
3.043ns   1.8V       1.711V     1.893V
20ns      1.8V       1.712V     1.892V
[Falling Waveform]
R_fixture = 50.000
V_fixture = 1.800
V_fixture_min = 1.710
V_fixture_max = 1.890
|  time   V(typ)   V(min)   V(max)
0s        1.8V       1.712V     1.892V
496ps     1.81V      1.712V     1.948V
687ps     1.828V     1.715V     1.903V
807ps     1.783V     1.722V     1.988V
1.1ns     1.743V     1.708V     1.84V
1.623ns   1.521V     1.599V     1.713V
2.102ns   1.395V     1.415V     1.624V
3.339ns   1.277V     1.231V     1.423V
4.92ns    1.267V     1.196V     1.357V
20ns      1.269V     1.196V     1.358V
[Falling Waveform]
R_fixture = 50.000
V_fixture = 0.000
V_fixture_min = 0.000
V_fixture_max = 0.000
|  time   V(typ)   V(min)   V(max)
0s        522.7mV    504.6mV    524.5mV
367ps     522.3mV    504.3mV    538.7mV
472ps     529.7mV    504.4mV    400.4mV
580ps     318.9mV    504.8mV    241.8mV
693ps     212.1mV    521.3mV    125.6mV
863ps     67.55mV    258.2mV    49.8mV
1.173ns   9.54mV     56.67mV    1.575mV
1.383ns   730.6uV    16.96mV    -982.2uV
2.082ns   -248.3uV   -758.8uV   -1.016mV
20ns      56.24uV    -535uV     108.4uV
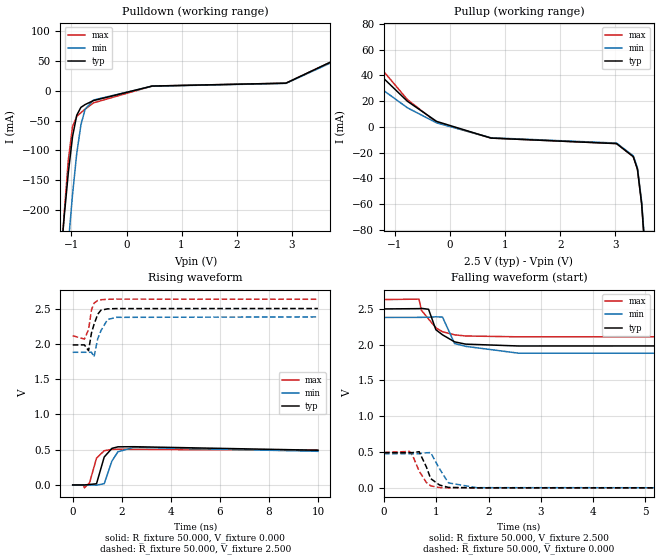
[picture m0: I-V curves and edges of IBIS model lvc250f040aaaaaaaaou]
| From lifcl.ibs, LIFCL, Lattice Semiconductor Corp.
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[Model] lvc250f040aaaaaaaaou
Model_type Output
Polarity   Non-Inverting
Enable   Active-High
Vmeas =  1.250V
Cref =  0.0F
Rref =  1.000M
Vref =  0.0V
C_comp   5.000pF   4.000pF   5.500pF
[Temperature Range]   25.000   0.125k   -40.000
[Voltage Range]   2.500V   2.380V   2.630V
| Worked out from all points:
|   slope of the pulldown table from 0 to 0.375 V, typ, clamps not added: 52.7 ohm
|   slope of the pullup table from 0 to 0.375 V, typ, clamps not added: 69.7 ohm
|   rising waveform, R_fixture 50.000, V_fixture 0.000: 20-80 % time 228ps typ, 265ps min, 242ps max; typ from 0 V to 0.492 V
|   rising waveform, R_fixture 50.000, V_fixture 2.500: 20-80 % time 262ps typ, 325ps min, 146ps max; typ from 1.98 V to 2.5 V
|   falling waveform, R_fixture 50.000, V_fixture 2.500: 20-80 % time 306ps typ, 212ps min, 324ps max; typ from 2.5 V to 1.98 V
|   falling waveform, R_fixture 50.000, V_fixture 0.000: 20-80 % time 162ps typ, 211ps min, 205ps max; typ from 0.492 V to 0 V
[Pulldown]
|Voltage   I(typ)   I(min)   I(max)
-2.5V     -1.868A    -2.199A    -2.434A
-1.208V   -294mA     -440.4mA   -314.4mA
-1.132V   -211.6mA   -345.9mA   -206.4mA
-1.056V   -136.7mA   -256.1mA   -115.2mA
-980mV    -76.7mA    -174.1mA   -59.83mA
-904mV    -40.93mA   -105.3mA   -43.08mA
-828mV    -27.68mA   -57.09mA   -36.64mA
-752mV    -23.03mA   -30.86mA   -30.85mA
-600mV    -16.3mA    -15.39mA   -20.14mA
464mV     8.11mA     7.866mA    8.11mA
2.896V    13.01mA    12.62mA    13.01mA
5V        105mA      101.8mA    105mA
[Pullup]
|Voltage   I(typ)   I(min)   I(max)
-2.5V     75.5mA     58.83mA    92.7mA
-2.22V    74.5mA     56.29mA    90.2mA
-1.84V    63.7mA     47.92mA    75.2mA
-776mV    19.95mA    14.88mA    21.25mA
-244mV    4.29mA     3.122mA    3.448mA
744mV     -8.658mA   -8.398mA   -8.658mA
3.024V    -12.92mA   -12.53mA   -12.92mA
3.328V    -23.07mA   -22.38mA   -23.07mA
3.404V    -32.83mA   -31.85mA   -32.83mA
3.48V     -59.56mA   -57.78mA   -59.56mA
3.556V    -104.9mA   -101.8mA   -104.9mA
5V        -1.421A    -1.378A    -1.421A
[Ramp]
| variable   typ   min   max
dV/dt_r   0.295/0.228n   0.287/0.265n   0.296/0.242n
dV/dt_f   0.309/0.309n   0.297/0.213n   0.310/0.324n
R_load = 50.000
[Rising Waveform]
R_fixture = 50.000
V_fixture = 0.000
V_fixture_min = 0.000
V_fixture_max = 0.000
|  time   V(typ)   V(min)   V(max)
0s        57.33uV    -402.4uV   129.6uV
434ps     110.5uV    -629.6uV   2.083mV
477ps     154.3uV    -480.1uV   -40.68mV
686ps     7.391mV    -357.8uV   30.39mV
970ps     16.91mV    -2.685mV   379.2mV
1.285ns   396.7mV    18.5mV     485.6mV
1.599ns   518.5mV    339.4mV    504.7mV
1.845ns   540.7mV    470.5mV    507.3mV
2.504ns   542.2mV    533mV      504.8mV
10ns      492.3mV    477.1mV    492.8mV
[Rising Waveform]
R_fixture = 50.000
V_fixture = 2.500
V_fixture_min = 2.380
V_fixture_max = 2.630
|  time   V(typ)   V(min)   V(max)
0s        1.984V     1.88V      2.114V
477ps     1.985V     1.88V      2.067V
646ps     1.903V     1.88V      2.201V
766ps     2.155V     1.88V      2.482V
869ps     2.275V     1.816V     2.576V
1.019ns   2.418V     2.071V     2.614V
1.15ns    2.476V     2.185V     2.624V
1.419ns   2.495V     2.343V     2.631V
1.779ns   2.499V     2.375V     2.633V
10ns      2.5V       2.381V     2.631V
[Falling Waveform]
R_fixture = 50.000
V_fixture = 2.500
V_fixture_min = 2.380
V_fixture_max = 2.630
|  time   V(typ)   V(min)   V(max)
0s        2.5V       2.381V     2.631V
668ps     2.504V     2.382V     2.637V
716ps     2.508V     2.382V     2.481V
852ps     2.495V     2.384V     2.359V
992ps     2.209V     2.39V      2.235V
1.119ns   2.138V     2.386V     2.181V
1.349ns   2.04V      2.017V     2.138V
1.56ns    2.008V     1.977V     2.122V
2.579ns   1.982V     1.881V     2.11V
10ns      1.984V     1.88V      2.114V
[Falling Waveform]
R_fixture = 50.000
V_fixture = 0.000
V_fixture_min = 0.000
V_fixture_max = 0.000
|  time   V(typ)   V(min)   V(max)
0s        492.3mV    477.1mV    492.8mV
488ps     491.6mV    477mV      509mV
548ps     491.9mV    477mV      449.8mV
672ps     504.6mV    476.8mV    232.7mV
811ps     290.6mV    489.9mV    73.93mV
892ps     128.7mV    492mV      27.22mV
1.062ns   38.76mV    265.4mV    3.621mV
1.232ns   5.797mV    68.64mV    111.3uV
1.772ns   -112.8uV   2.259mV    -674.1uV
10ns      57.33uV    -402.4uV   129.6uV
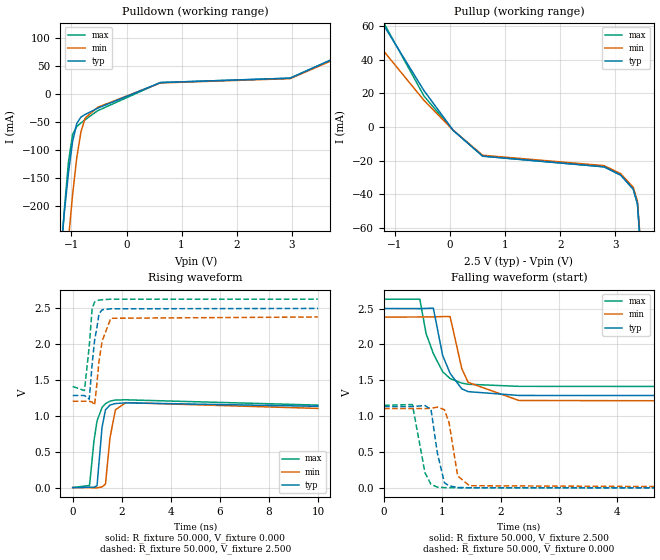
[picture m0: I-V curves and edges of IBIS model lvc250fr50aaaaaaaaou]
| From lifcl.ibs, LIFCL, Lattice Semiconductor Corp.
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[Model] lvc250fr50aaaaaaaaou
Model_type Output
Polarity   Non-Inverting
Enable   Active-High
Vmeas =  1.250V
Cref =  0.0F
Rref =  1.000M
Vref =  0.0V
C_comp   5.000pF   4.000pF   5.500pF
[Temperature Range]   25.000   0.125k   -40.000
[Voltage Range]   2.500V   2.380V   2.630V
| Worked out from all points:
|   slope of the pulldown table from 0 to 0.375 V, typ, clamps not added: 24.3 ohm
|   slope of the pullup table from 0 to 0.375 V, typ, clamps not added: 30.8 ohm
|   rising waveform, R_fixture 50.000, V_fixture 0.000: 20-80 % time 163ps typ, 194ps min, 228ps max; typ from 0 V to 1.13 V
|   rising waveform, R_fixture 50.000, V_fixture 2.500: 20-80 % time 241ps typ, 291ps min, 190ps max; typ from 1.28 V to 2.5 V
|   falling waveform, R_fixture 50.000, V_fixture 2.500: 20-80 % time 257ps typ, 261ps min, 294ps max; typ from 2.5 V to 1.28 V
|   falling waveform, R_fixture 50.000, V_fixture 0.000: 20-80 % time 97ps typ, 122ps min, 138ps max; typ from 1.13 V to 0 V
[Pulldown]
|Voltage   I(typ)   I(min)   I(max)
-2.5V     -1.843A    -2.192A    -2.4A
-1.208V   -294.1mA   -443.2mA   -314.4mA
-1.132V   -213.6mA   -349.4mA   -209mA
-1.056V   -141.1mA   -260.6mA   -121.9mA
-980mV    -84.5mA    -179.9mA   -71.68mA
-904mV    -52.19mA   -113.2mA   -57.43mA
-828mV    -40.67mA   -67.16mA   -51.18mA
-752mV    -36.04mA   -42.47mA   -45.38mA
-524mV    -24.76mA   -23.17mA   -29.26mA
616mV     20.9mA     20.28mA    20.9mA
2.972V    28.74mA    27.88mA    28.74mA
5V        117.5mA    114mA      117.5mA
[Pullup]
|Voltage   I(typ)   I(min)   I(max)
-2.5V     99.5mA     75.5mA     115.7mA
-1.84V    92.3mA     69.19mA    99.1mA
-1.688V   85.9mA     64.27mA    90.6mA
-472mV    21.47mA    15.7mA     18.26mA
60mV      -2.133mA   -2.069mA   -2.133mA
592mV     -17.34mA   -16.82mA   -17.34mA
2.796V    -23.67mA   -22.96mA   -23.67mA
3.1V      -28.61mA   -27.75mA   -28.61mA
3.328V    -36.96mA   -35.85mA   -36.96mA
3.404V    -45.58mA   -44.21mA   -45.58mA
3.556V    -115.5mA   -112mA     -115.5mA
5V        -1.485A    -1.44A     -1.485A
[Ramp]
| variable   typ   min   max
dV/dt_r   0.687/0.163n   0.663/0.195n   0.690/0.228n
dV/dt_f   0.728/0.258n   0.715/0.261n   0.755/0.294n
R_load = 50.000
[Rising Waveform]
R_fixture = 50.000
V_fixture = 0.000
V_fixture_min = 0.000
V_fixture_max = 0.000
|  time   V(typ)   V(min)   V(max)
0s        62.93uV    -430.5uV   1.022mV
686ps     6.027mV    -375uV     29.77mV
866ps     6.205mV    -3.637mV   649.8mV
992ps     25.54mV    -3.202mV   930.5mV
1.196ns   841.3mV    9.582mV    1.118V
1.336ns   1.086V     49.17mV    1.171V
1.521ns   1.152V     696.7mV    1.206V
1.742ns   1.173V     1.085V     1.222V
2.161ns   1.183V     1.185V     1.225V
10ns      1.134V     1.105V     1.151V
[Rising Waveform]
R_fixture = 50.000
V_fixture = 2.500
V_fixture_min = 2.380
V_fixture_max = 2.630
|  time   V(typ)   V(min)   V(max)
0s        1.285V     1.205V     1.411V
480ps     1.285V     1.205V     1.354V
674ps     1.233V     1.205V     1.972V
793ps     1.723V     1.194V     2.499V
893ps     2.056V     1.152V     2.59V
982ps     2.221V     1.436V     2.608V
1.073ns   2.426V     1.77V      2.616V
1.203ns   2.482V     2.048V     2.622V
1.553ns   2.495V     2.363V     2.629V
10ns      2.5V       2.381V     2.63V
[Falling Waveform]
R_fixture = 50.000
V_fixture = 2.500
V_fixture_min = 2.380
V_fixture_max = 2.630
|  time   V(typ)   V(min)   V(max)
0s        2.5V       2.381V     2.63V
615ps     2.499V     2.382V     2.631V
721ps     2.502V     2.382V     2.153V
846ps     2.506V     2.382V     1.872V
1.006ns   1.846V     2.388V     1.619V
1.134ns   1.596V     2.388V     1.524V
1.334ns   1.381V     1.663V     1.46V
1.444ns   1.341V     1.47V      1.444V
2.314ns   1.288V     1.218V     1.415V
10ns      1.285V     1.205V     1.411V
[Falling Waveform]
R_fixture = 50.000
V_fixture = 0.000
V_fixture_min = 0.000
V_fixture_max = 0.000
|  time   V(typ)   V(min)   V(max)
0s        1.134V     1.105V     1.151V
487ps     1.133V     1.105V     1.161V
703ps     1.147V     1.105V     210.9mV
806ps     1.094V     1.11V      48.66mV
916ps     482.8mV    1.125V     9.398mV
1.036ns   71.12mV    1.09V      2.969mV
1.115ns   27.68mV    912.9mV    1.953mV
1.264ns   5.124mV    166.3mV    1.053mV
1.464ns   1.289mV    29.18mV    732.4uV
10ns      62.93uV    -430.5uV   1.022mV
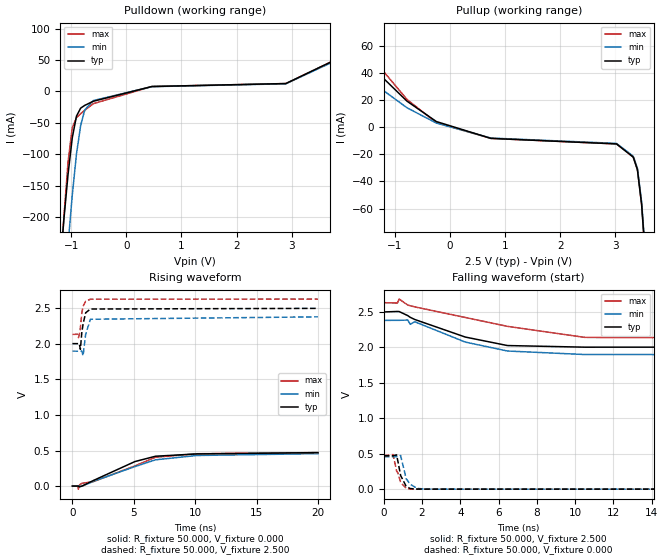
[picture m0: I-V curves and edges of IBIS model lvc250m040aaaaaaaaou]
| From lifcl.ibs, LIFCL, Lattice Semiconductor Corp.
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[Model] lvc250m040aaaaaaaaou
Model_type Output
Polarity   Non-Inverting
Enable   Active-High
Vmeas =  1.250V
Cref =  0.0F
Rref =  1.000M
Vref =  0.0V
C_comp   5.000pF   4.000pF   5.500pF
[Temperature Range]   25.000   0.125k   -40.000
[Voltage Range]   2.500V   2.380V   2.630V
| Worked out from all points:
|   slope of the pulldown table from 0 to 0.375 V, typ, clamps not added: 54.8 ohm
|   slope of the pullup table from 0 to 0.375 V, typ, clamps not added: 72.8 ohm
|   rising waveform, R_fixture 50.000, V_fixture 0.000: 20-80 % time 3.65ns typ, 4.48ns min, 4.05ns max; typ from 0 V to 0.471 V
|   rising waveform, R_fixture 50.000, V_fixture 2.500: 20-80 % time 273ps typ, 326ps min, 218ps max; typ from 2 V to 2.5 V
|   falling waveform, R_fixture 50.000, V_fixture 2.500: 20-80 % time 3.24ns typ, 3.33ns min, 5.31ns max; typ from 2.5 V to 2 V
|   falling waveform, R_fixture 50.000, V_fixture 0.000: 20-80 % time 304ps typ, 319ps min, 303ps max; typ from 0.471 V to 0 V
[Pulldown]
|Voltage   I(typ)   I(min)   I(max)
-2.5V     -1.797A    -2.087A    -2.358A
-1.208V   -282.8mA   -417.9mA   -304.7mA
-1.132V   -203.6mA   -328.3mA   -200mA
-1.056V   -131.5mA   -243mA     -111.6mA
-980mV    -73.79mA   -165.2mA   -57.97mA
-904mV    -39.38mA   -99.9mA    -41.75mA
-828mV    -26.63mA   -54.18mA   -35.5mA
-752mV    -22.15mA   -29.28mA   -29.89mA
-600mV    -15.68mA   -14.6mA    -19.52mA
464mV     7.801mA    7.567mA    7.801mA
2.896V    12.52mA    12.14mA    12.52mA
5V        101mA      98mA       101mA
[Pullup]
|Voltage   I(typ)   I(min)   I(max)
-2.5V     72.2mA     56.29mA    88.7mA
-2.144V   70mA       52.74mA    84.1mA
-1.84V    61mA       45.84mA    71.9mA
-776mV    19.08mA    14.23mA    20.33mA
-244mV    4.104mA    2.987mA    3.299mA
744mV     -8.283mA   -8.035mA   -8.283mA
3.024V    -12.36mA   -11.99mA   -12.36mA
3.328V    -22.07mA   -21.41mA   -22.07mA
3.404V    -31.41mA   -30.47mA   -31.41mA
3.48V     -56.99mA   -55.28mA   -56.99mA
3.556V    -100.3mA   -97.3mA    -100.3mA
5V        -1.359A    -1.318A    -1.359A
[Ramp]
| variable   typ   min   max
dV/dt_r   0.283/3.655n   0.274/4.514n   0.291/4.056n
dV/dt_f   0.298/3.245n   0.295/3.345n   0.298/5.313n
R_load = 50.000
[Rising Waveform]
R_fixture = 50.000
V_fixture = 0.000
V_fixture_min = 0.000
V_fixture_max = 0.000
|  time   V(typ)   V(min)   V(max)
0s        55.81uV    -445uV     154.1uV
434ps     110uV      -669.6uV   2.257mV
486ps     143uV      -502.6uV   -42.96mV
588ps     -10.37mV   -391.9uV   19.5mV
775ps     708.8uV    -2.428mV   39.12mV
1.745ns   81.96mV    69.22mV    65.14mV
5.09ns    345.3mV    274.5mV    284.2mV
6.77ns    420.4mV    369.9mV    406.7mV
10.15ns   452.8mV    430.9mV    455.3mV
20ns      471.1mV    456.6mV    471.6mV
[Rising Waveform]
R_fixture = 50.000
V_fixture = 2.500
V_fixture_min = 2.380
V_fixture_max = 2.630
|  time   V(typ)   V(min)   V(max)
0s        2.004V     1.899V     2.134V
425ps     2.004V     1.898V     2.136V
487ps     2.004V     1.899V     2.089V
557ps     2.004V     1.899V     2.125V
648ps     1.924V     1.899V     2.224V
761ps     2.154V     1.9V       2.431V
869ps     2.282V     1.834V     2.531V
1.079ns   2.438V     2.137V     2.6V
1.468ns   2.491V     2.347V     2.629V
20ns      2.5V       2.381V     2.631V
[Falling Waveform]
R_fixture = 50.000
V_fixture = 2.500
V_fixture_min = 2.380
V_fixture_max = 2.630
|  time   V(typ)   V(min)   V(max)
0s        2.5V       2.381V     2.631V
714ps     2.507V     2.382V     2.626V
804ps     2.506V     2.382V     2.682V
1.252ns   2.449V     2.386V     2.598V
1.389ns   2.424V     2.326V     2.587V
1.621ns   2.394V     2.362V     2.572V
4.261ns   2.146V     2.075V     2.422V
6.463ns   2.026V     1.949V     2.297V
10.52ns   2.003V     1.899V     2.141V
20ns      2.004V     1.899V     2.134V
[Falling Waveform]
R_fixture = 50.000
V_fixture = 0.000
V_fixture_min = 0.000
V_fixture_max = 0.000
|  time   V(typ)   V(min)   V(max)
0s        471.1mV    456.6mV    471.6mV
487ps     470.4mV    456.4mV    487.6mV
672ps     483.4mV    456.3mV    257.2mV
748ps     384.1mV    459.6mV    225.1mV
884ps     191.6mV    474.3mV    95.32mV
1.172ns   40.67mV    147.3mV    11.5mV
1.384ns   7.514mV    67.43mV    1.774mV
1.764ns   392.6uV    8.896mV    -740.8uV
2.251ns   -178.9uV   -277.5uV   -683.3uV
20ns      55.81uV    -445uV     154.1uV
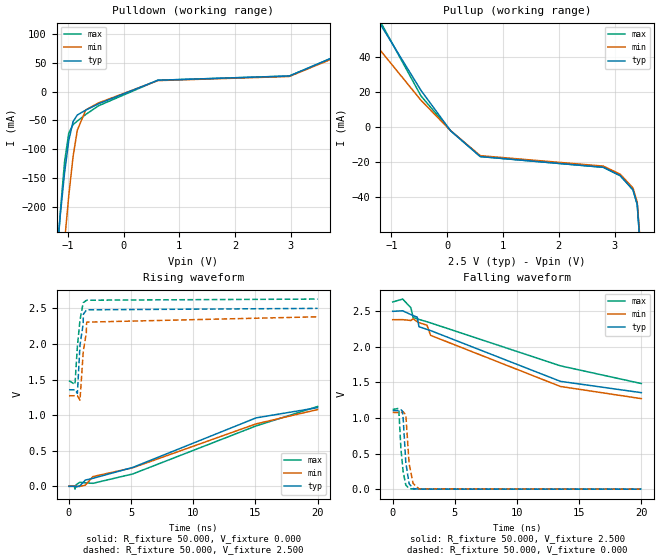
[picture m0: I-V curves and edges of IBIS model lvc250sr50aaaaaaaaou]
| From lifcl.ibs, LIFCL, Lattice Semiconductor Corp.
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[Model] lvc250sr50aaaaaaaaou
Model_type Output
Polarity   Non-Inverting
Enable   Active-High
Vmeas =  1.250V
Cref =  0.0F
Rref =  1.000M
Vref =  0.0V
C_comp   5.000pF   4.000pF   5.500pF
[Temperature Range]   25.000   0.125k   -40.000
[Voltage Range]   2.500V   2.380V   2.630V
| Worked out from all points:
|   slope of the pulldown table from 0 to 0.375 V, typ, clamps not added: 25.8 ohm
|   slope of the pullup table from 0 to 0.375 V, typ, clamps not added: 31.6 ohm
|   rising waveform, R_fixture 50.000, V_fixture 0.000: 20-80 % time 9.37ns typ, 10.6ns min, 9.7ns max; typ from 0 V to 1.11 V
|   rising waveform, R_fixture 50.000, V_fixture 2.500: 20-80 % time 364ps typ, 401ps min, 418ps max; typ from 1.36 V to 2.5 V
|   falling waveform, R_fixture 50.000, V_fixture 2.500: 20-80 % time 10ns typ, 9.58ns min, 12ns max; typ from 2.5 V to 1.36 V
|   falling waveform, R_fixture 50.000, V_fixture 0.000: 20-80 % time 277ps typ, 297ps min, 292ps max; typ from 1.11 V to 0 V
[Pulldown]
|Voltage   I(typ)   I(min)   I(max)
-2.5V     -1.843A    -2.192A    -2.4A
-1.208V   -294.1mA   -443.2mA   -314.4mA
-1.132V   -213.6mA   -349.4mA   -209mA
-1.056V   -141.1mA   -260.6mA   -121.9mA
-980mV    -84.5mA    -179.9mA   -71.68mA
-904mV    -52.18mA   -113.2mA   -57.43mA
-828mV    -40.67mA   -67.16mA   -51.18mA
-676mV    -32.17mA   -31.88mA   -39.73mA
-448mV    -21.22mA   -19.65mA   -24.67mA
616mV     19.65mA    19.06mA    19.65mA
2.972V    27.02mA    26.21mA    27.02mA
5V        110.4mA    107.1mA    110.4mA
[Pullup]
|Voltage   I(typ)   I(min)   I(max)
-2.5V     97.92mA    74.3mA     113.9mA
-2.068V   97.1mA     73.2mA     108.5mA
-1.688V   84.5mA     63.28mA    89.2mA
-472mV    21.14mA    15.46mA    17.98mA
60mV      -2.076mA   -2.014mA   -2.076mA
592mV     -16.88mA   -16.37mA   -16.88mA
2.796V    -23.04mA   -22.35mA   -23.04mA
3.1V      -27.85mA   -27.02mA   -27.85mA
3.328V    -35.98mA   -34.9mA    -35.98mA
3.404V    -44.37mA   -43.04mA   -44.37mA
3.556V    -112.4mA   -109mA     -112.4mA
5V        -1.445A    -1.402A    -1.445A
[Ramp]
| variable   typ   min   max
dV/dt_r   0.669/9.369n   0.647/10.550n   0.672/9.703n
dV/dt_f   0.686/8.733n   0.698/8.218n   0.688/10.584n
R_load = 50.000
[Rising Waveform]
R_fixture = 50.000
V_fixture = 0.000
V_fixture_min = 0.000
V_fixture_max = 0.000
|  time   V(typ)   V(min)   V(max)
0s        62.93uV    -116.1uV   1.29mV
436ps     146uV      -296.7uV   3.128mV
478ps     181.3uV    -127.6uV   -39.95mV
586ps     -9.085mV   -27.91uV   23.37mV
875ps     6.972mV    -1.617mV   56.52mV
1.324ns   88.19mV    16.56mV    48.33mV
1.924ns   112.3mV    137.1mV    42.1mV
5.13ns    265.1mV    260.3mV    173.6mV
15.05ns   961.1mV    876.9mV    848mV
20ns      1.105V     1.078V     1.121V
[Rising Waveform]
R_fixture = 50.000
V_fixture = 2.500
V_fixture_min = 2.380
V_fixture_max = 2.630
|  time   V(typ)   V(min)   V(max)
0s        1.356V     1.272V     1.484V
483ps     1.356V     1.272V     1.431V
678ps     1.305V     1.273V     1.964V
887ps     1.983V     1.21V      2.333V
1.144ns   2.28V      1.879V     2.577V
1.158ns   2.416V     1.903V     2.58V
1.395ns   2.474V     2.152V     2.611V
1.418ns   2.476V     2.292V     2.612V
1.445ns   2.479V     2.306V     2.614V
20ns      2.499V     2.381V     2.63V
[Falling Waveform]
R_fixture = 50.000
V_fixture = 2.500
V_fixture_min = 2.380
V_fixture_max = 2.630
|  time   V(typ)   V(min)   V(max)
0s        2.499V     2.381V     2.63V
800ps     2.506V     2.382V     2.671V
1.464ns   2.453V     2.37V      2.549V
1.644ns   2.438V     2.394V     2.411V
1.974ns   2.417V     2.352V     2.393V
2.114ns   2.282V     2.34V      2.385V
2.758ns   2.245V     2.303V     2.352V
3.05ns    2.228V     2.161V     2.336V
13.49ns   1.515V     1.443V     1.733V
20ns      1.356V     1.272V     1.484V
[Falling Waveform]
R_fixture = 50.000
V_fixture = 0.000
V_fixture_min = 0.000
V_fixture_max = 0.000
|  time   V(typ)   V(min)   V(max)
0s        1.105V     1.078V     1.121V
486ps     1.105V     1.078V     1.135V
661ps     1.115V     1.077V     565.9mV
778ps     1.099V     1.08V      355mV
838ps     1.003V     1.087V     247.3mV
1.055ns   372.3mV    1.045V     56.94mV
1.321ns   76.37mV    352.7mV    8.172mV
1.644ns   8.043mV    79.64mV    1.491mV
2.112ns   653.4uV    5.231mV    837.2uV
20ns      62.93uV    -116.1uV   1.29mV
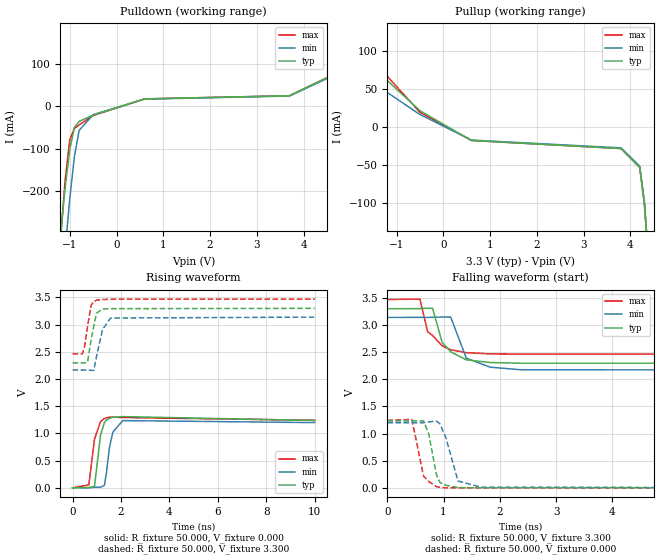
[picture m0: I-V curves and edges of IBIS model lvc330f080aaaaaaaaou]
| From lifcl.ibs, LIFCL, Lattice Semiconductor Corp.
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[Model] lvc330f080aaaaaaaaou
Model_type Output
Polarity   Non-Inverting
Enable   Active-High
Vmeas =  1.650V
Cref =  0.0F
Rref =  1.000M
Vref =  0.0V
C_comp   5.000pF   4.000pF   5.500pF
[Temperature Range]   25.000   0.125k   -40.000
[Voltage Range]   3.300V   3.140V   3.470V
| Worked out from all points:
|   slope of the pulldown table from 0 to 0.495 V, typ, clamps not added: 31.5 ohm
|   slope of the pullup table from 0 to 0.495 V, typ, clamps not added: 32.3 ohm
|   rising waveform, R_fixture 50.000, V_fixture 0.000: 20-80 % time 189ps typ, 233ps min, 215ps max; typ from 0 V to 1.24 V
|   rising waveform, R_fixture 50.000, V_fixture 3.300: 20-80 % time 231ps typ, 297ps min, 205ps max; typ from 2.3 V to 3.3 V
|   falling waveform, R_fixture 50.000, V_fixture 3.300: 20-80 % time 274ps typ, 223ps min, 282ps max; typ from 3.3 V to 2.3 V
|   falling waveform, R_fixture 50.000, V_fixture 0.000: 20-80 % time 135ps typ, 175ps min, 139ps max; typ from 1.23 V to 0 V
[Pulldown]
|Voltage   I(typ)   I(min)   I(max)
-3.3V     -3.025A    -3.614A    -3.918A
-1.2V     -304.3mA   -472.8mA   -317.2mA
-1.1V     -192.9mA   -339.3mA   -175.3mA
-1V       -101.2mA   -217mA     -78.95mA
-900mV    -49.86mA   -117.7mA   -52.21mA
-800mV    -35.81mA   -56.74mA   -43.74mA
-500mV    -20.71mA   -19.77mA   -22.12mA
600mV     17.27mA    16.75mA    17.27mA
3.7V      24.69mA    23.95mA    24.69mA
5.3V      109.4mA    106.1mA    109.4mA
6.1V      131.6mA    127.7mA    131.6mA
6.6V      184.5mA    179mA      184.5mA
[Pullup]
|Voltage   I(typ)   I(min)   I(max)
-3.3V     161.3mA    100.5mA    206.1mA
-3V       127.5mA    90.4mA     173.2mA
-2.7V     107.3mA    82.8mA     139.1mA
-2.4V     105.4mA    78.79mA    116.8mA
-1.9V     100.3mA    74.11mA    113.5mA
-500mV    21.21mA    16.16mA    19.08mA
600mV     -17.75mA   -17.22mA   -17.75mA
3.8V      -28.32mA   -27.47mA   -28.32mA
4.2V      -53.08mA   -51.48mA   -53.08mA
4.3V      -100.7mA   -97.7mA    -100.7mA
4.4V      -187.8mA   -182.2mA   -187.8mA
6.6V      -2.91A     -2.822A    -2.91A
[Ramp]
| variable   typ   min   max
dV/dt_r   0.743/0.189n   0.719/0.239n   0.745/0.215n
dV/dt_f   0.602/0.274n   0.584/0.222n   0.602/0.283n
R_load = 50.000
[Rising Waveform]
R_fixture = 50.000
V_fixture = 0.000
V_fixture_min = 0.000
V_fixture_max = 0.000
|  time   V(typ)   V(min)   V(max)
0s        488.9uV    1.443mV    488.9uV
672ps     6.388mV    1.588mV    55.41mV
906ps     28.26mV    10.39mV    899.6mV
1.155ns   971.4mV    11.11mV    1.218V
1.316ns   1.203V     46.63mV    1.276V
1.396ns   1.246V     271.7mV    1.289V
1.526ns   1.28V      749.1mV    1.299V
1.666ns   1.297V     1.028V     1.302V
2.076ns   1.31V      1.237V     1.294V
10ns      1.239V     1.2V       1.242V
[Rising Waveform]
R_fixture = 50.000
V_fixture = 3.300
V_fixture_min = 3.140
V_fixture_max = 3.470
|  time   V(typ)   V(min)   V(max)
0s        2.297V     2.167V     2.467V
409ps     2.297V     2.166V     2.466V
497ps     2.298V     2.167V     2.603V
618ps     2.305V     2.168V     2.966V
768ps     2.735V     2.161V     3.359V
876ps     2.969V     2.159V     3.429V
988ps     3.213V     2.413V     3.449V
1.236ns   3.288V     2.909V     3.463V
1.566ns   3.295V     3.122V     3.468V
10ns      3.3V       3.14V      3.47V
[Falling Waveform]
R_fixture = 50.000
V_fixture = 3.300
V_fixture_min = 3.140
V_fixture_max = 3.470
|  time   V(typ)   V(min)   V(max)
0s        3.3V       3.14V      3.47V
579ps     3.302V     3.141V     3.477V
716ps     3.309V     3.14V      2.878V
804ps     3.307V     3.142V     2.807V
974ps     2.682V     3.148V     2.618V
1.126ns   2.507V     3.147V     2.545V
1.404ns   2.358V     2.389V     2.491V
1.829ns   2.309V     2.223V     2.468V
2.368ns   2.296V     2.176V     2.463V
10ns      2.297V     2.167V     2.467V
[Falling Waveform]
R_fixture = 50.000
V_fixture = 0.000
V_fixture_min = 0.000
V_fixture_max = 0.000
|  time   V(typ)   V(min)   V(max)
0s        1.234V     1.2V       1.242V
437ps     1.233V     1.199V     1.261V
644ps     1.234V     1.2V       214.2mV
735ps     997.4mV    1.213V     117.2mV
874ps     239.6mV    1.23V      21.7mV
936ps     97.28mV    1.179V     8.907mV
1.042ns   48.18mV    920mV      2.164mV
1.256ns   4.638mV    125.9mV    -164.9uV
1.666ns   265.6uV    11.55mV    -511.1uV
10ns      342.9uV    1.443mV    488.9uV
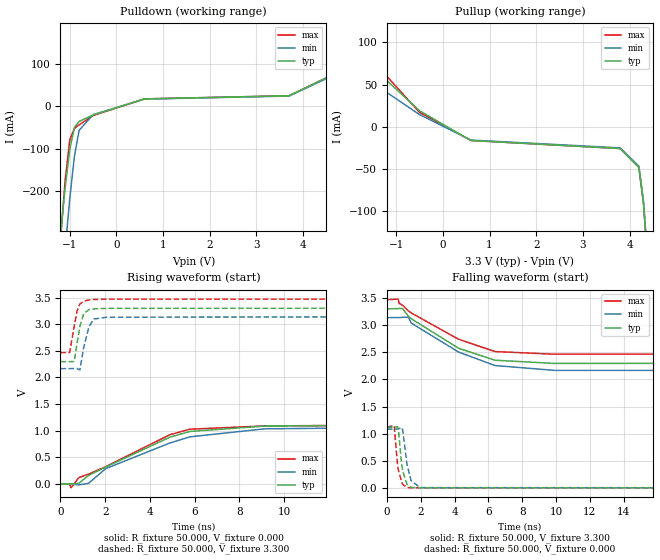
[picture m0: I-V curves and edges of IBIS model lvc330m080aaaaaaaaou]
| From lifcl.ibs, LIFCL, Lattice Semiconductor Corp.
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[Model] lvc330m080aaaaaaaaou
Model_type Output
Polarity   Non-Inverting
Enable   Active-High
Vmeas =  1.650V
Cref =  0.0F
Rref =  1.000M
Vref =  0.0V
C_comp   5.000pF   4.000pF   5.500pF
[Temperature Range]   25.000   0.125k   -40.000
[Voltage Range]   3.300V   3.140V   3.470V
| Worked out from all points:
|   slope of the pulldown table from 0 to 0.495 V, typ, clamps not added: 31.5 ohm
|   slope of the pullup table from 0 to 0.495 V, typ, clamps not added: 35.9 ohm
|   rising waveform, R_fixture 50.000, V_fixture 0.000: 20-80 % time 3.47ns typ, 3.91ns min, 3.27ns max; typ from 0 V to 1.12 V
|   rising waveform, R_fixture 50.000, V_fixture 3.300: 20-80 % time 248ps typ, 295ps min, 236ps max; typ from 2.3 V to 3.3 V
|   falling waveform, R_fixture 50.000, V_fixture 3.300: 20-80 % time 3.22ns typ, 3.2ns min, 3.51ns max; typ from 3.3 V to 2.3 V
|   falling waveform, R_fixture 50.000, V_fixture 0.000: 20-80 % time 273ps typ, 284ps min, 288ps max; typ from 1.12 V to 0 V
[Pulldown]
|Voltage   I(typ)   I(min)   I(max)
-3.3V     -3.025A    -3.614A    -3.918A
-1.2V     -304.3mA   -472.8mA   -317.2mA
-1.1V     -192.9mA   -339.3mA   -175.3mA
-1V       -101.2mA   -217mA     -78.95mA
-900mV    -49.86mA   -117.7mA   -52.21mA
-800mV    -35.81mA   -56.74mA   -43.74mA
-500mV    -20.71mA   -19.77mA   -22.12mA
600mV     17.27mA    16.75mA    17.27mA
3.7V      24.69mA    23.95mA    24.69mA
5.3V      109.4mA    106.1mA    109.4mA
6.1V      131.6mA    127.7mA    131.6mA
6.6V      184.5mA    179mA      184.5mA
[Pullup]
|Voltage   I(typ)   I(min)   I(max)
-3.3V     145.5mA    90.7mA     185.8mA
-3V       114.9mA    81.5mA     156.2mA
-2.7V     96.8mA     74.7mA     125.4mA
-2.4V     95.1mA     71.05mA    105.4mA
-1.9V     90.5mA     66.84mA    102.4mA
-500mV    19.13mA    14.57mA    17.21mA
600mV     -16.01mA   -15.53mA   -16.01mA
3.8V      -25.54mA   -24.77mA   -25.54mA
4.2V      -47.87mA   -46.43mA   -47.87mA
4.3V      -90.8mA    -88.1mA    -90.8mA
4.4V      -169.3mA   -164.2mA   -169.3mA
6.6V      -2.624A    -2.545A    -2.624A
[Ramp]
| variable   typ   min   max
dV/dt_r   0.671/3.474n   0.650/3.936n   0.673/3.276n
dV/dt_f   0.602/3.253n   0.584/3.212n   0.602/3.516n
R_load = 50.000
[Rising Waveform]
R_fixture = 50.000
V_fixture = 0.000
V_fixture_min = 0.000
V_fixture_max = 0.000
|  time   V(typ)   V(min)   V(max)
0s        488.9uV    1.443mV    488.9uV
395ps     637.6uV    952.2uV    3.901mV
475ps     718.1uV    1.451mV    -70.63mV
816ps     13.72mV    -15.69mV   120.4mV
1.256ns   162.7mV    14.22mV    187.3mV
2.016ns   319.3mV    288.2mV    325.9mV
4.885ns   878.7mV    769.5mV    924.9mV
5.78ns    987.4mV    886.1mV    1.03V
9.109ns   1.088V     1.036V     1.091V
20ns      1.119V     1.084V     1.122V
[Rising Waveform]
R_fixture = 50.000
V_fixture = 3.300
V_fixture_min = 3.140
V_fixture_max = 3.470
|  time   V(typ)   V(min)   V(max)
0s        2.297V     2.167V     2.467V
409ps     2.297V     2.166V     2.466V
616ps     2.299V     2.168V     2.961V
734ps     2.622V     2.168V     3.237V
866ps     2.953V     2.141V     3.375V
1.036ns   3.197V     2.555V     3.43V
1.276ns   3.274V     2.953V     3.455V
1.486ns   3.287V     3.096V     3.463V
2.077ns   3.297V     3.131V     3.469V
20ns      3.3V       3.14V      3.47V
[Falling Waveform]
R_fixture = 50.000
V_fixture = 3.300
V_fixture_min = 3.140
V_fixture_max = 3.470
|  time   V(typ)   V(min)   V(max)
0s        3.3V       3.14V      3.47V
666ps     3.307V     3.141V     3.481V
726ps     3.309V     3.14V      3.403V
924ps     3.306V     3.147V     3.369V
1.275ns   3.165V     3.146V     3.261V
1.436ns   3.12V      3.04V      3.227V
4.236ns   2.575V     2.505V     2.741V
6.39ns    2.354V     2.256V     2.514V
9.897ns   2.295V     2.167V     2.465V
20ns      2.297V     2.167V     2.467V
[Falling Waveform]
R_fixture = 50.000
V_fixture = 0.000
V_fixture_min = 0.000
V_fixture_max = 0.000
|  time   V(typ)   V(min)   V(max)
0s        1.119V     1.084V     1.122V
432ps     1.119V     1.083V     1.146V
635ps     1.128V     1.083V     395.6mV
704ps     1.006V     1.09V      298.1mV
846ps     510.1mV    1.117V     138.5mV
936ps     308.8mV    1.065V     61.56mV
1.193ns   62.15mV    421.9mV    5.671mV
1.432ns   8.25mV     133.1mV    217.4uV
1.966ns   398.9uV    4.682mV    -527.1uV
20ns      488.9uV    1.443mV    488.9uV
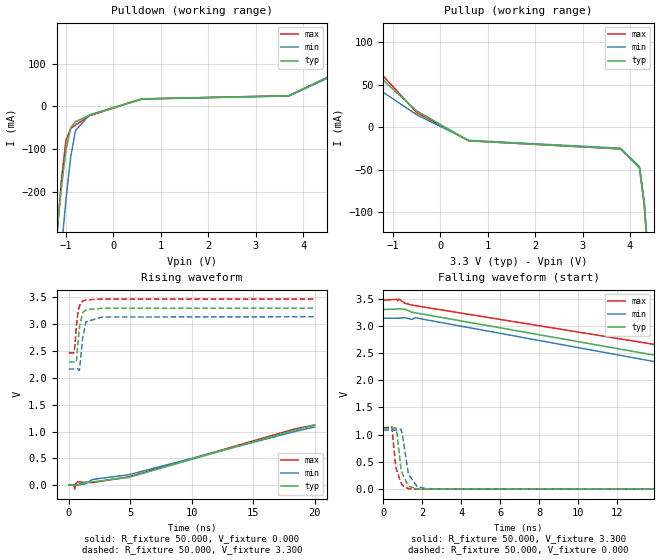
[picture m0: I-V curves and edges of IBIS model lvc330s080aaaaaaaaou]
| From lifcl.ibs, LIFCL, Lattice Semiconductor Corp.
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[Model] lvc330s080aaaaaaaaou
Model_type Output
Polarity   Non-Inverting
Enable   Active-High
Vmeas =  1.650V
Cref =  0.0F
Rref =  1.000M
Vref =  0.0V
C_comp   5.000pF   4.000pF   5.500pF
[Temperature Range]   25.000   0.125k   -40.000
[Voltage Range]   3.300V   3.140V   3.470V
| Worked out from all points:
|   slope of the pulldown table from 0 to 0.495 V, typ, clamps not added: 31.5 ohm
|   slope of the pullup table from 0 to 0.495 V, typ, clamps not added: 35.9 ohm
|   rising waveform, R_fixture 50.000, V_fixture 0.000: 20-80 % time 10.1ns typ, 10.8ns min, 10.1ns max; typ from 0 V to 1.12 V
|   rising waveform, R_fixture 50.000, V_fixture 3.300: 20-80 % time 265ps typ, 295ps min, 259ps max; typ from 2.3 V to 3.3 V
|   falling waveform, R_fixture 50.000, V_fixture 3.300: 20-80 % time 9.12ns typ, 8.53ns min, 10.2ns max; typ from 3.3 V to 2.3 V
|   falling waveform, R_fixture 50.000, V_fixture 0.000: 20-80 % time 306ps typ, 322ps min, 315ps max; typ from 1.12 V to 0 V
[Pulldown]
|Voltage   I(typ)   I(min)   I(max)
-3.3V     -3.025A    -3.614A    -3.918A
-1.2V     -304.3mA   -472.8mA   -317.2mA
-1.1V     -192.9mA   -339.3mA   -175.3mA
-1V       -101.2mA   -217mA     -78.95mA
-900mV    -49.86mA   -117.7mA   -52.21mA
-800mV    -35.81mA   -56.74mA   -43.74mA
-500mV    -20.71mA   -19.76mA   -22.12mA
600mV     17.27mA    16.75mA    17.27mA
3.7V      24.69mA    23.95mA    24.69mA
5.3V      109.4mA    106.1mA    109.4mA
6.1V      131.6mA    127.7mA    131.6mA
6.6V      184.5mA    179mA      184.5mA
[Pullup]
|Voltage   I(typ)   I(min)   I(max)
-3.3V     145.5mA    90.7mA     185.8mA
-3V       114.9mA    81.5mA     156.2mA
-2.7V     96.8mA     74.7mA     125.4mA
-2.4V     95.1mA     71.05mA    105.4mA
-1.9V     90.5mA     66.84mA    102.4mA
-500mV    19.13mA    14.57mA    17.21mA
600mV     -16.01mA   -15.53mA   -16.01mA
3.8V      -25.54mA   -24.77mA   -25.54mA
4.2V      -47.87mA   -46.43mA   -47.87mA
4.3V      -90.8mA    -88.1mA    -90.8mA
4.4V      -169.3mA   -164.2mA   -169.3mA
6.6V      -2.624A    -2.545A    -2.624A
[Ramp]
| variable   typ   min   max
dV/dt_r   0.690/10.154n   0.650/10.738n   0.673/10.105n
dV/dt_f   0.602/9.145n   0.584/8.567n   0.602/10.251n
R_load = 50.000
[Rising Waveform]
R_fixture = 50.000
V_fixture = 0.000
V_fixture_min = 0.000
V_fixture_max = 0.000
|  time   V(typ)   V(min)   V(max)
0s        488.9uV    1.443mV    488.9uV
395ps     658.9uV    831.3uV    4.121mV
476ps     748.1uV    1.458mV    -75.06mV
567ps     -9.748mV   1.629mV    30.57mV
756ps     9.529mV    3.988mV    63.46mV
1.276ns   53.06mV    19.21mV    47.44mV
1.915ns   60.52mV    105.6mV    47.56mV
4.871ns   145.2mV    193.8mV    154.5mV
18.34ns   1.028V     996.8mV    1.045V
20ns      1.119V     1.084V     1.122V
[Rising Waveform]
R_fixture = 50.000
V_fixture = 3.300
V_fixture_min = 3.140
V_fixture_max = 3.470
|  time   V(typ)   V(min)   V(max)
0s        2.297V     2.167V     2.467V
409ps     2.297V     2.166V     2.466V
495ps     2.298V     2.167V     2.59V
617ps     2.297V     2.168V     2.964V
732ps     2.615V     2.168V     3.208V
866ps     2.954V     2.137V     3.345V
1.122ns   3.215V     2.737V     3.43V
1.393ns   3.272V     3.045V     3.454V
2.705ns   3.298V     3.135V     3.469V
20ns      3.3V       3.14V      3.47V
[Falling Waveform]
R_fixture = 50.000
V_fixture = 3.300
V_fixture_min = 3.140
V_fixture_max = 3.470
|  time   V(typ)   V(min)   V(max)
0s        3.3V       3.14V      3.47V
688ps     3.308V     3.14V      3.488V
728ps     3.309V     3.14V      3.458V
798ps     3.311V     3.142V     3.492V
1.104ns   3.305V     3.151V     3.415V
1.456ns   3.252V     3.118V     3.382V
1.635ns   3.24V      3.148V     3.371V
14.38ns   2.432V     2.313V     2.632V
17.15ns   2.336V     2.218V     2.518V
20ns      2.297V     2.167V     2.467V
[Falling Waveform]
R_fixture = 50.000
V_fixture = 0.000
V_fixture_min = 0.000
V_fixture_max = 0.000
|  time   V(typ)   V(min)   V(max)
0s        1.119V     1.084V     1.122V
432ps     1.119V     1.083V     1.146V
635ps     1.128V     1.083V     409.9mV
704ps     1.006V     1.09V      325.8mV
894ps     392.5mV    1.102V     128.6mV
976ps     284.1mV    1.002V     70.9mV
1.286ns   53.13mV    272.9mV    6.471mV
1.736ns   2.839mV    45mV       -635.9uV
2.289ns   60.46uV    2.344mV    -757.1uV
20ns      488.9uV    1.443mV    488.9uV
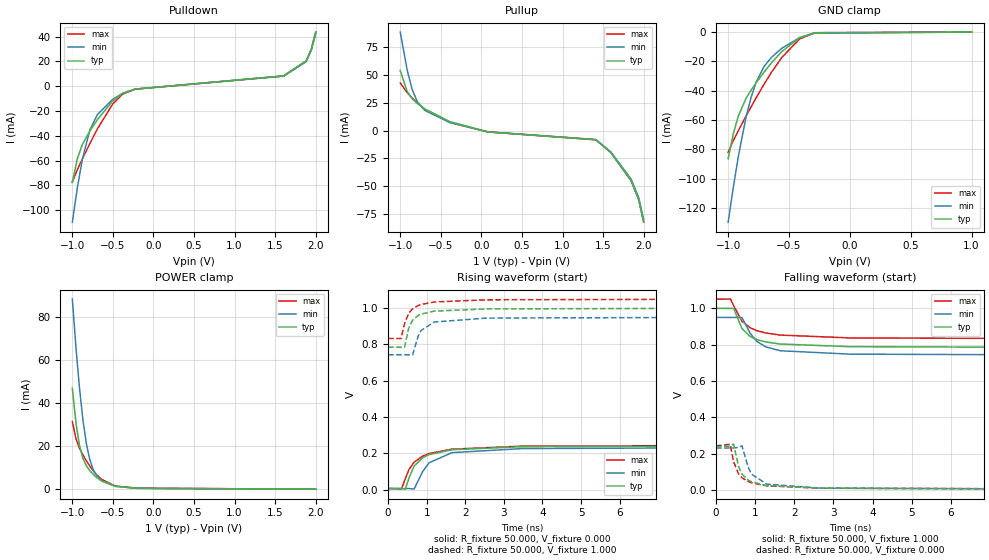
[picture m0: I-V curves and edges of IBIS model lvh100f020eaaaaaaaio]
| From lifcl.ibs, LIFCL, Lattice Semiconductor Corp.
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[Model] lvh100f020eaaaaaaaio
Model_type I/O
Polarity   Non-Inverting
Enable   Active-Low
Vinl =  0.350V
Vinh =  0.650V
Vmeas =  0.500V
Cref =  0.0F
Rref =  1.000M
Vref =  0.0V
C_comp   5.000pF   4.000pF   5.500pF
[Temperature Range]   25.000   0.125k   -40.000
[Voltage Range]   1.000V   0.950V   1.050V
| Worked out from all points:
|   slope of the pulldown table from 0 to 0.15 V, typ, clamps not added: 107 ohm
|   slope of the pullup table from 0 to 0.15 V, typ, clamps not added: 74.6 ohm
|   GND clamp passes 1 mA (typ) near -0.32 V on its own axis
|   POWER clamp passes 1 mA (typ) near -0.46 V on its own axis
|   rising waveform, R_fixture 50.000, V_fixture 0.000: 20-80 % time 556ps typ, 572ps min, 594ps max; typ from 0.006 V to 0.242 V
|   rising waveform, R_fixture 50.000, V_fixture 1.000: 20-80 % time 284ps typ, 317ps min, 313ps max; typ from 0.784 V to 1 V
|   falling waveform, R_fixture 50.000, V_fixture 1.000: 20-80 % time 528ps typ, 552ps min, 590ps max; typ from 1 V to 0.784 V
|   falling waveform, R_fixture 50.000, V_fixture 0.000: 20-80 % time 330ps typ, 348ps min, 350ps max; typ from 0.242 V to 0.006 V
[GND_clamp]
|Voltage   I(typ)   I(min)   I(max)
-1V       -86.39mA   -129.8mA   -82.1mA
-958mV    -69.62mA   -106.1mA   -74.12mA
-916mV    -57.21mA   -84.7mA    -67.22mA
-853mV    -45.26mA   -58.07mA   -57.38mA
-811mV    -39.58mA   -44.43mA   -50.99mA
-769mV    -34.5mA    -34.04mA   -44.75mA
-706mV    -27.42mA   -23.61mA   -35.76mA
-643mV    -20.91mA   -17.14mA   -27.32mA
-559mV    -13.28mA   -11.04mA   -17.29mA
-412mV    -3.804mA   -3.723mA   -4.655mA
-286mV    -477.7uA   -703.7uA   -396.2uA
1V        0A         0A         0A
[POWER_clamp]
|Voltage   I(typ)   I(min)   I(max)
-1V       46.74mA    88.29mA    31.25mA
-953mV    29.96mA    64.69mA    22.99mA
-911mV    20.02mA    46.58mA    18.81mA
-869mV    14.14mA    31.9mA     15.73mA
-827mV    10.71mA    20.96mA    13.03mA
-785mV    8.459mA    13.56mA    10.59mA
-743mV    6.733mA    8.952mA    8.425mA
-701mV    5.305mA    6.142mA    6.561mA
-638mV    3.604mA    3.771mA    4.35mA
-470mV    1.11mA     1.202mA    1.272mA
-197mV    214.8uA    168.4uA    281.4uA
2V        -171.9uA   -171.2uA   -177.1uA
[Pulldown]
|Voltage   I(typ)   I(min)   I(max)
-1V       -77.67mA   -109.7mA   -77.1mA
-938mV    -58.53mA   -81.92mA   -67.33mA
-876mV    -46.89mA   -58.86mA   -58.63mA
-783mV    -36mA      -35.1mA    -46.09mA
-690mV    -26.86mA   -22.73mA   -34.26mA
-504mV    -11.96mA   -10.67mA   -14.5mA
-380mV    -5.675mA   -5.627mA   -6.286mA
-225mV    -2.256mA   -2.289mA   -2.368mA
1.604V    8.365mA    8.114mA    8.365mA
1.883V    20.45mA    19.84mA    20.45mA
1.945V    29.87mA    28.98mA    29.87mA
2V        43.72mA    42.41mA    43.72mA
[Pullup]
|Voltage   I(typ)   I(min)   I(max)
-1V       54.04mA    88.72mA    42.94mA
-914mV    35.21mA    54.31mA    34.1mA
-852mV    28.59mA    36.79mA    29.36mA
-790mV    24.45mA    26.08mA    25.03mA
-697mV    19.52mA    18.1mA     19.35mA
-387mV    8.066mA    7.264mA    7.319mA
78mV      -1.134mA   -1.1mA     -1.134mA
1.411V    -8.238mA   -7.991mA   -8.238mA
1.597V    -19.87mA   -19.28mA   -19.87mA
1.845V    -45.03mA   -43.68mA   -45.03mA
1.938V    -61.85mA   -59.99mA   -61.85mA
2V        -82.45mA   -79.98mA   -82.45mA
[Ramp]
| variable   typ   min   max
dV/dt_r   0.142/0.565n   0.132/0.577n   0.146/0.602n
dV/dt_f   0.129/0.532n   0.125/0.548n   0.130/0.585n
R_load = 50.000
[Rising Waveform]
R_fixture = 50.000
V_fixture = 0.000
V_fixture_min = 0.000
V_fixture_max = 0.000
|  time   V(typ)   V(min)   V(max)
0s        5.984mV    5.696mV    6.291mV
345ps     6.254mV    5.807mV    3.656mV
446ps     2.414mV    5.732mV    58.64mV
548ps     66.86mV    6.059mV    112.9mV
675ps     129.5mV    2.671mV    150.7mV
895ps     175.2mV    99.39mV    184.5mV
1.065ns   193.1mV    148mV      199.1mV
1.656ns   219.8mV    203.7mV    222.9mV
3.469ns   236.5mV    226mV      239.7mV
10ns      241.9mV    232.1mV    244.4mV
[Rising Waveform]
R_fixture = 50.000
V_fixture = 1.000
V_fixture_min = 0.950
V_fixture_max = 1.050
|  time   V(typ)   V(min)   V(max)
0s        784.5mV    743.1mV    833mV
336ps     784.7mV    743.2mV    832.7mV
424ps     783.4mV    743.2mV    911.7mV
534ps     888.7mV    742.9mV    972.1mV
635ps     933.4mV    742mV      996.3mV
775ps     959mV      842.6mV    1.014V
855ps     967.2mV    876.7mV    1.02V
1.195ns   983.7mV    923.6mV    1.034V
2.555ns   995.8mV    945.2mV    1.046V
10ns      999.9mV    949.9mV    1.05V
[Falling Waveform]
R_fixture = 50.000
V_fixture = 1.000
V_fixture_min = 0.950
V_fixture_max = 1.050
|  time   V(typ)   V(min)   V(max)
0s        999.9mV    949.9mV    1.05V
370ps     999.5mV    949.8mV    1.051V
452ps     999.2mV    949.9mV    1.014V
663ps     888.8mV    949.3mV    929.6mV
873ps     845.5mV    863.2mV    893.2mV
1.043ns   828.3mV    818.2mV    877.3mV
1.274ns   814.9mV    788mV      864.4mV
1.641ns   803.8mV    766.8mV    853mV
3.421ns   789.3mV    748.1mV    837.3mV
10ns      784.5mV    743.1mV    833mV
[Falling Waveform]
R_fixture = 50.000
V_fixture = 0.000
V_fixture_min = 0.000
V_fixture_max = 0.000
|  time   V(typ)   V(min)   V(max)
0s        241.9mV    232.1mV    244.4mV
362ps     242mV      231.8mV    252.3mV
449ps     253.7mV    232mV      156.8mV
577ps     130.8mV    235.6mV    89.72mV
664ps     88.64mV    243.9mV    68.83mV
814ps     56.93mV    131.4mV    48.28mV
904ps     46.47mV    88.93mV    40.72mV
1.297ns   25.42mV    33.48mV    24.16mV
2.673ns   11.24mV    11.27mV    10.69mV
10ns      5.984mV    5.696mV    6.291mV
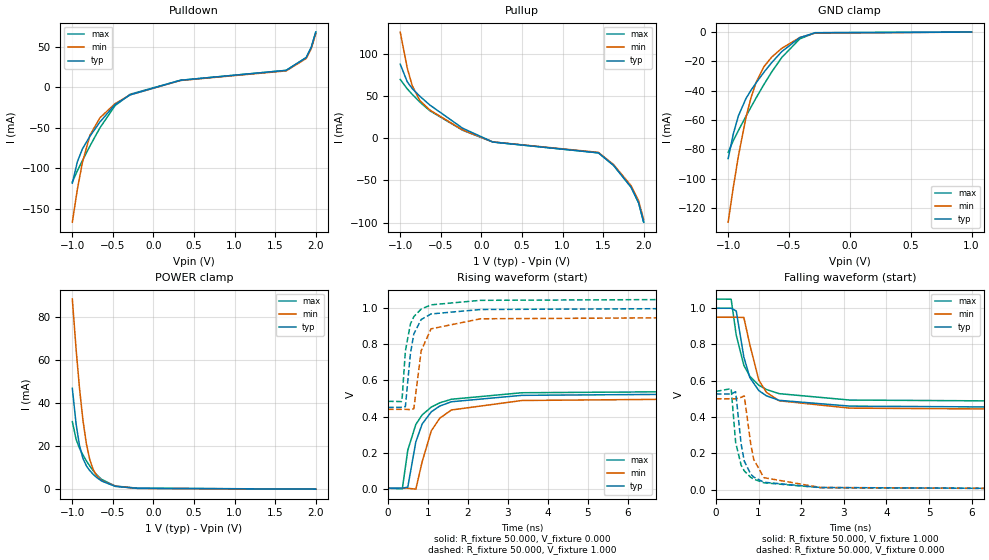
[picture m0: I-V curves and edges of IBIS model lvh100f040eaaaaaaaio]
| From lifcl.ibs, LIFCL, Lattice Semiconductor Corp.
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[Model] lvh100f040eaaaaaaaio
Model_type I/O
Polarity   Non-Inverting
Enable   Active-Low
Vinl =  0.350V
Vinh =  0.650V
Vmeas =  0.500V
Cref =  0.0F
Rref =  1.000M
Vref =  0.0V
C_comp   5.000pF   4.000pF   5.500pF
[Temperature Range]   25.000   0.125k   -40.000
[Voltage Range]   1.000V   0.950V   1.050V
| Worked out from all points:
|   slope of the pulldown table from 0 to 0.15 V, typ, clamps not added: 34.6 ohm
|   slope of the pullup table from 0 to 0.15 V, typ, clamps not added: 29.9 ohm
|   GND clamp passes 1 mA (typ) near -0.32 V on its own axis
|   POWER clamp passes 1 mA (typ) near -0.46 V on its own axis
|   rising waveform, R_fixture 50.000, V_fixture 0.000: 20-80 % time 496ps typ, 533ps min, 542ps max; typ from 0.003 V to 0.527 V
|   rising waveform, R_fixture 50.000, V_fixture 1.000: 20-80 % time 210ps typ, 247ps min, 226ps max; typ from 0.451 V to 1 V
|   falling waveform, R_fixture 50.000, V_fixture 1.000: 20-80 % time 403ps typ, 408ps min, 468ps max; typ from 1 V to 0.451 V
|   falling waveform, R_fixture 50.000, V_fixture 0.000: 20-80 % time 229ps typ, 255ps min, 244ps max; typ from 0.527 V to 0.003 V
[GND_clamp]
|Voltage   I(typ)   I(min)   I(max)
-1V       -86.39mA   -129.8mA   -82.1mA
-958mV    -69.62mA   -106.1mA   -74.12mA
-916mV    -57.21mA   -84.7mA    -67.22mA
-853mV    -45.26mA   -58.07mA   -57.38mA
-811mV    -39.58mA   -44.43mA   -50.99mA
-769mV    -34.5mA    -34.04mA   -44.75mA
-706mV    -27.42mA   -23.61mA   -35.76mA
-643mV    -20.91mA   -17.14mA   -27.32mA
-559mV    -13.28mA   -11.04mA   -17.29mA
-412mV    -3.804mA   -3.723mA   -4.655mA
-286mV    -477.7uA   -703.7uA   -396.2uA
1V        0A         0A         0A
[POWER_clamp]
|Voltage   I(typ)   I(min)   I(max)
-1V       46.74mA    88.29mA    31.25mA
-953mV    29.96mA    64.69mA    22.99mA
-911mV    20.02mA    46.58mA    18.81mA
-869mV    14.14mA    31.9mA     15.73mA
-827mV    10.71mA    20.96mA    13.03mA
-785mV    8.459mA    13.56mA    10.59mA
-743mV    6.733mA    8.952mA    8.425mA
-701mV    5.305mA    6.142mA    6.561mA
-638mV    3.604mA    3.771mA    4.35mA
-470mV    1.11mA     1.202mA    1.272mA
-197mV    214.8uA    168.4uA    281.4uA
2V        -171.9uA   -171.2uA   -177.1uA
[Pulldown]
|Voltage   I(typ)   I(min)   I(max)
-1V       -118.4mA   -166.7mA   -117mA
-938mV    -92.07mA   -126.1mA   -103.2mA
-876mV    -76.13mA   -92.99mA   -90.66mA
-783mV    -60.46mA   -59.19mA   -72.49mA
-659mV    -42.67mA   -37.52mA   -49.88mA
-473mV    -21.27mA   -20.11mA   -22.48mA
-287mV    -9.194mA   -9.165mA   -8.478mA
333mV     8.82mA     8.556mA    8.82mA
1.635V    21.06mA    20.43mA    21.06mA
1.883V    36.89mA    35.78mA    36.89mA
1.945V    49.53mA    48.04mA    49.53mA
2V        68.4mA     66.35mA    68.4mA
[Pullup]
|Voltage   I(typ)   I(min)   I(max)
-1V       87.31mA    125.4mA    69.34mA
-914mV    66.65mA    82.99mA    58.26mA
-852mV    58.48mA    61.88mA    51.68mA
-759mV    49.52mA    44.49mA    42.61mA
-635mV    39.08mA    33.14mA    32.31mA
-232mV    11.7mA     9.634mA    9.279mA
140mV     -4.706mA   -4.564mA   -4.706mA
1.442V    -17.51mA   -16.98mA   -17.51mA
1.628V    -32.26mA   -31.3mA    -32.26mA
1.845V    -58.14mA   -56.4mA    -58.14mA
1.938V    -76.72mA   -74.42mA   -76.72mA
2V        -99.59mA   -96.6mA    -99.59mA
[Ramp]
| variable   typ   min   max
dV/dt_r   0.314/0.491n   0.299/0.534n   0.323/0.551n
dV/dt_f   0.326/0.404n   0.308/0.408n   0.340/0.474n
R_load = 50.000
[Rising Waveform]
R_fixture = 50.000
V_fixture = 0.000
V_fixture_min = 0.000
V_fixture_max = 0.000
|  time   V(typ)   V(min)   V(max)
0s        3.422mV    3.197mV    3.396mV
356ps     4.108mV    3.258mV    -999.8nV
493ps     9.225mV    3.496mV    214mV
695ps     260.3mV    -1.669mV   356.6mV
853ps     358.7mV    150.1mV    409.1mV
1.082ns   426.3mV    321.2mV    452.5mV
1.293ns   458.1mV    390.9mV    476mV
1.585ns   481.9mV    436.4mV    495.8mV
3.35ns    517.4mV    488.9mV    531.8mV
10ns      527.4mV    501mV      541.5mV
[Rising Waveform]
R_fixture = 50.000
V_fixture = 1.000
V_fixture_min = 0.950
V_fixture_max = 1.050
|  time   V(typ)   V(min)   V(max)
0s        450.7mV    439.9mV    484.3mV
336ps     451mV      440mV      482.9mV
355ps     450.7mV    440mV      510.2mV
433ps     454.8mV    440mV      762.4mV
559ps     747.6mV    438.5mV    912.4mV
645ps     857.3mV    443.6mV    953mV
829ps     937mV      764.5mV    994.8mV
1.075ns   967.6mV    885.3mV    1.018V
2.317ns   992.3mV    940.9mV    1.043V
10ns      999.9mV    949.9mV    1.05V
[Falling Waveform]
R_fixture = 50.000
V_fixture = 1.000
V_fixture_min = 0.950
V_fixture_max = 1.050
|  time   V(typ)   V(min)   V(max)
0s        999.9mV    949.9mV    1.05V
356ps     999.5mV    949.8mV    1.049V
475ps     984.4mV    949.9mV    851.6mV
654ps     730.5mV    948.7mV    685mV
795ps     617.2mV    798.1mV    624.5mV
1.004ns   546.5mV    604.4mV    575.6mV
1.184ns   517.1mV    536.1mV    551.9mV
1.484ns   492.3mV    489.8mV    529mV
3.142ns   460.5mV    449.4mV    493.9mV
10ns      450.7mV    439.9mV    484.3mV
[Falling Waveform]
R_fixture = 50.000
V_fixture = 0.000
V_fixture_min = 0.000
V_fixture_max = 0.000
|  time   V(typ)   V(min)   V(max)
0s        527.4mV    501mV      541.5mV
356ps     527.1mV    500.7mV    556.7mV
461ps     539.9mV    500.7mV    261.2mV
590ps     251.9mV    509.1mV    135mV
664ps     158mV      516.8mV    103.8mV
814ps     86.18mV    254.6mV    68.39mV
884ps     70.05mV    168.3mV    58.45mV
1.124ns   41.21mV    66.45mV    38.33mV
2.453ns   12.39mV    12.44mV    11.37mV
10ns      3.422mV    3.197mV    3.396mV
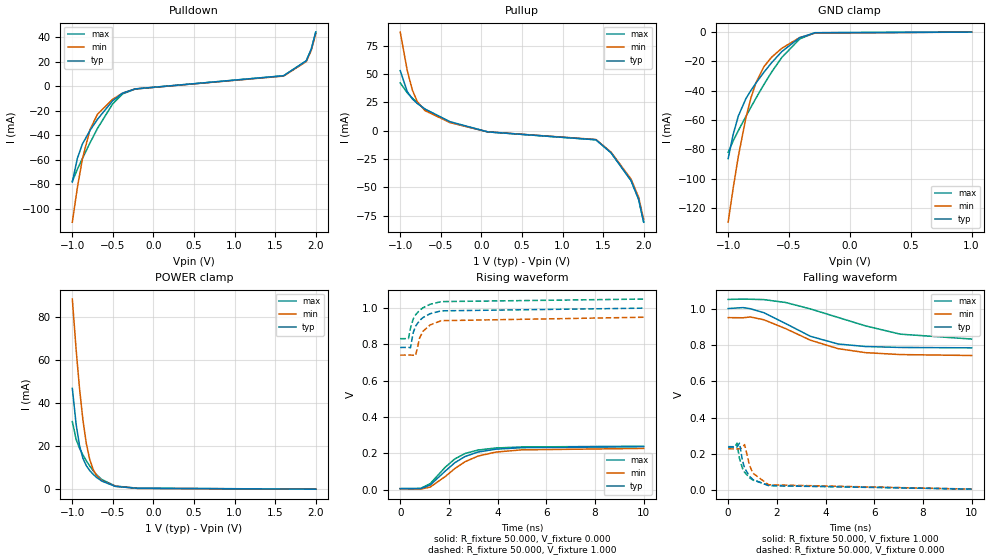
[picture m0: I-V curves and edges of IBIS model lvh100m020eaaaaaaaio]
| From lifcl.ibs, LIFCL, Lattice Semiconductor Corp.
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[Model] lvh100m020eaaaaaaaio
Model_type I/O
Polarity   Non-Inverting
Enable   Active-Low
Vinl =  0.350V
Vinh =  0.650V
Vmeas =  0.500V
Cref =  0.0F
Rref =  1.000M
Vref =  0.0V
C_comp   5.000pF   4.000pF   5.500pF
[Temperature Range]   25.000   0.125k   -40.000
[Voltage Range]   1.000V   0.950V   1.050V
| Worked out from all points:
|   slope of the pulldown table from 0 to 0.15 V, typ, clamps not added: 107 ohm
|   slope of the pullup table from 0 to 0.15 V, typ, clamps not added: 76.2 ohm
|   GND clamp passes 1 mA (typ) near -0.32 V on its own axis
|   POWER clamp passes 1 mA (typ) near -0.46 V on its own axis
|   rising waveform, R_fixture 50.000, V_fixture 0.000: 20-80 % time 1.33ns typ, 1.5ns min, 1.17ns max; typ from 0.006 V to 0.237 V
|   rising waveform, R_fixture 50.000, V_fixture 1.000: 20-80 % time 550ps typ, 523ps min, 586ps max; typ from 0.783 V to 1 V
|   falling waveform, R_fixture 50.000, V_fixture 1.000: 20-80 % time 1.99ns typ, 2.32ns min, 3.29ns max; typ from 1 V to 0.783 V
|   falling waveform, R_fixture 50.000, V_fixture 0.000: 20-80 % time 532ps typ, 524ps min, 612ps max; typ from 0.237 V to 0.006 V
[GND_clamp]
|Voltage   I(typ)   I(min)   I(max)
-1V       -86.39mA   -129.8mA   -82.1mA
-958mV    -69.62mA   -106.1mA   -74.12mA
-916mV    -57.21mA   -84.7mA    -67.22mA
-853mV    -45.26mA   -58.07mA   -57.38mA
-811mV    -39.58mA   -44.43mA   -50.99mA
-769mV    -34.5mA    -34.04mA   -44.75mA
-706mV    -27.42mA   -23.61mA   -35.76mA
-643mV    -20.91mA   -17.14mA   -27.32mA
-559mV    -13.28mA   -11.04mA   -17.29mA
-412mV    -3.804mA   -3.723mA   -4.655mA
-286mV    -477.7uA   -703.7uA   -396.2uA
1V        0A         0A         0A
[POWER_clamp]
|Voltage   I(typ)   I(min)   I(max)
-1V       46.74mA    88.29mA    31.25mA
-953mV    29.96mA    64.69mA    22.99mA
-911mV    20.02mA    46.58mA    18.81mA
-869mV    14.14mA    31.9mA     15.73mA
-827mV    10.71mA    20.96mA    13.03mA
-785mV    8.459mA    13.56mA    10.59mA
-743mV    6.733mA    8.952mA    8.425mA
-701mV    5.305mA    6.142mA    6.561mA
-638mV    3.604mA    3.771mA    4.35mA
-470mV    1.11mA     1.202mA    1.272mA
-197mV    214.8uA    168.4uA    281.4uA
2V        -171.9uA   -171.2uA   -177.1uA
[Pulldown]
|Voltage   I(typ)   I(min)   I(max)
-1V       -78.05mA   -110.7mA   -77.47mA
-938mV    -58.82mA   -82.64mA   -67.66mA
-876mV    -47.13mA   -59.37mA   -58.92mA
-783mV    -36.18mA   -35.41mA   -46.31mA
-690mV    -27mA      -22.92mA   -34.43mA
-504mV    -12.02mA   -10.77mA   -14.57mA
-380mV    -5.703mA   -5.676mA   -6.316mA
-225mV    -2.268mA   -2.309mA   -2.379mA
1.604V    8.407mA    8.155mA    8.407mA
1.883V    20.55mA    19.94mA    20.55mA
1.945V    30.02mA    29.12mA    30.02mA
2V        43.93mA    42.62mA    43.93mA
[Pullup]
|Voltage   I(typ)   I(min)   I(max)
-1V       52.89mA    86.84mA    42.03mA
-914mV    34.47mA    53.16mA    33.37mA
-852mV    27.99mA    36.01mA    28.73mA
-790mV    23.94mA    25.53mA    24.5mA
-697mV    19.11mA    17.71mA    18.94mA
-387mV    7.895mA    7.11mA     7.164mA
78mV      -1.11mA    -1.077mA   -1.11mA
1.411V    -8.064mA   -7.822mA   -8.064mA
1.597V    -19.45mA   -18.87mA   -19.45mA
1.845V    -44.07mA   -42.75mA   -44.07mA
1.938V    -60.54mA   -58.72mA   -60.54mA
2V        -80.71mA   -78.29mA   -80.71mA
[Ramp]
| variable   typ   min   max
dV/dt_r   0.139/1.333n   0.132/1.513n   0.146/1.189n
dV/dt_f   0.130/2.036n   0.125/2.409n   0.131/3.308n
R_load = 50.000
[Rising Waveform]
R_fixture = 50.000
V_fixture = 0.000
V_fixture_min = 0.000
V_fixture_max = 0.000
|  time   V(typ)   V(min)   V(max)
0s        5.967mV    5.681mV    6.274mV
834ps     6.138mV    3.185mV    7.337mV
1.232ns   26.08mV    14.74mV    33.46mV
1.852ns   103.2mV    73.07mV    124.6mV
2.244ns   149mV      116.8mV    169.8mV
2.662ns   182.9mV    154.1mV    199.5mV
3.189ns   207.5mV    185.1mV    218.6mV
3.933ns   223.4mV    207.5mV    229.9mV
4.991ns   231.5mV    219.7mV    235.6mV
10ns      237.2mV    227.6mV    239.6mV
[Rising Waveform]
R_fixture = 50.000
V_fixture = 1.000
V_fixture_min = 0.950
V_fixture_max = 1.050
|  time   V(typ)   V(min)   V(max)
0s        783.5mV    741.4mV    831.9mV
336ps     783.8mV    741.5mV    832.2mV
422ps     782mV      741.5mV    890.4mV
530ps     864.1mV    741.2mV    939.3mV
632ps     901.1mV    739mV      963.5mV
795ps     931.8mV    835.5mV    987.9mV
934ps     948.1mV    872.3mV    1.002V
1.225ns   969.2mV    907.4mV    1.021V
1.681ns   985.1mV    931mV      1.036V
10ns      999.9mV    949.9mV    1.05V
[Falling Waveform]
R_fixture = 50.000
V_fixture = 1.000
V_fixture_min = 0.950
V_fixture_max = 1.050
|  time   V(typ)   V(min)   V(max)
0s        999.9mV    949.9mV    1.05V
613ps     1.005V     949mV      1.052V
904ps     999.1mV    953.6mV    1.051V
1.464ns   977mV      938.2mV    1.049V
2.365ns   916.9mV    889.1mV    1.033V
3.377ns   847.2mV    825.7mV    997.8mV
4.519ns   804.6mV    778.9mV    950.7mV
5.641ns   790.8mV    757.1mV    904.5mV
7.067ns   785.7mV    746.5mV    858.9mV
10ns      783.5mV    741.4mV    831.9mV
[Falling Waveform]
R_fixture = 50.000
V_fixture = 0.000
V_fixture_min = 0.000
V_fixture_max = 0.000
|  time   V(typ)   V(min)   V(max)
0s        237.2mV    227.6mV    239.6mV
283ps     237.1mV    227.3mV    239.2mV
362ps     237.2mV    227.3mV    259.4mV
466ps     258.6mV    227.3mV    174.5mV
586ps     164.7mV    234.5mV    121.2mV
676ps     121.8mV    251.4mV    98.67mV
874ps     77.02mV    138.7mV    68.69mV
1.013ns   59.05mV    93.9mV     55.91mV
1.664ns   24.68mV    29.74mV    27.51mV
10ns      5.967mV    5.681mV    6.274mV
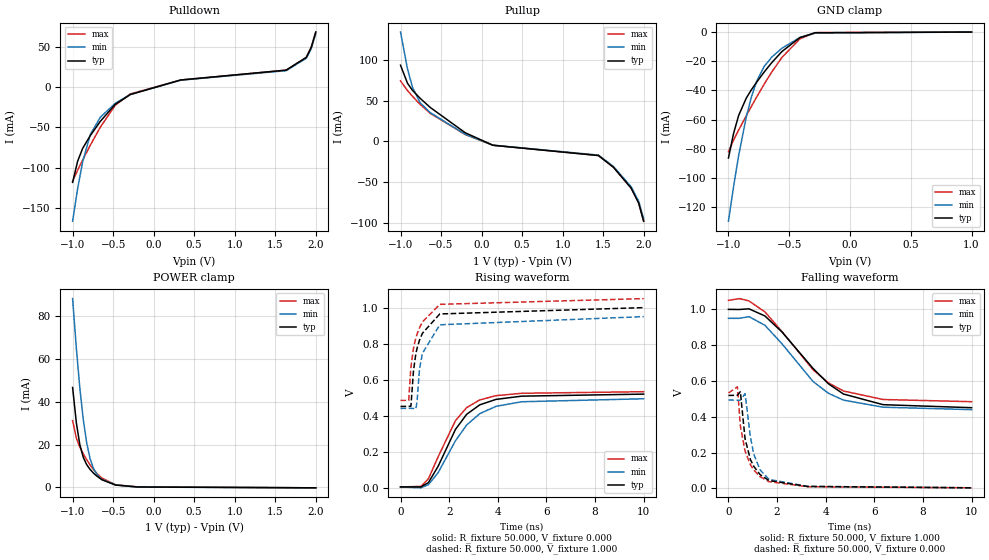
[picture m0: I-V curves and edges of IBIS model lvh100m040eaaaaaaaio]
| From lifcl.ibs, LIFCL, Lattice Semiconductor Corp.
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[Model] lvh100m040eaaaaaaaio
Model_type I/O
Polarity   Non-Inverting
Enable   Active-Low
Vinl =  0.350V
Vinh =  0.650V
Vmeas =  0.500V
Cref =  0.0F
Rref =  1.000M
Vref =  0.0V
C_comp   5.000pF   4.000pF   5.500pF
[Temperature Range]   25.000   0.125k   -40.000
[Voltage Range]   1.000V   0.950V   1.050V
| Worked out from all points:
|   slope of the pulldown table from 0 to 0.15 V, typ, clamps not added: 34.6 ohm
|   slope of the pullup table from 0 to 0.15 V, typ, clamps not added: 30.4 ohm
|   GND clamp passes 1 mA (typ) near -0.32 V on its own axis
|   POWER clamp passes 1 mA (typ) near -0.46 V on its own axis
|   rising waveform, R_fixture 50.000, V_fixture 0.000: 20-80 % time 1.28ns typ, 1.47ns min, 1.22ns max; typ from 0.003 V to 0.519 V
|   rising waveform, R_fixture 50.000, V_fixture 1.000: 20-80 % time 550ps typ, 509ps min, 584ps max; typ from 0.451 V to 1 V
|   falling waveform, R_fixture 50.000, V_fixture 1.000: 20-80 % time 2.25ns typ, 2.03ns min, 2.19ns max; typ from 1 V to 0.451 V
|   falling waveform, R_fixture 50.000, V_fixture 0.000: 20-80 % time 544ps typ, 498ps min, 565ps max; typ from 0.519 V to 0.003 V
[GND_clamp]
|Voltage   I(typ)   I(min)   I(max)
-1V       -86.39mA   -129.8mA   -82.1mA
-958mV    -69.62mA   -106.1mA   -74.12mA
-916mV    -57.21mA   -84.7mA    -67.22mA
-853mV    -45.26mA   -58.07mA   -57.38mA
-811mV    -39.58mA   -44.43mA   -50.99mA
-769mV    -34.5mA    -34.04mA   -44.75mA
-706mV    -27.42mA   -23.61mA   -35.76mA
-643mV    -20.91mA   -17.14mA   -27.32mA
-559mV    -13.28mA   -11.04mA   -17.29mA
-412mV    -3.804mA   -3.723mA   -4.655mA
-286mV    -477.7uA   -703.7uA   -396.2uA
1V        0A         0A         0A
[POWER_clamp]
|Voltage   I(typ)   I(min)   I(max)
-1V       46.74mA    88.29mA    31.25mA
-953mV    29.96mA    64.69mA    22.99mA
-911mV    20.02mA    46.58mA    18.81mA
-869mV    14.14mA    31.9mA     15.73mA
-827mV    10.71mA    20.96mA    13.03mA
-785mV    8.459mA    13.56mA    10.59mA
-743mV    6.733mA    8.952mA    8.425mA
-701mV    5.305mA    6.142mA    6.561mA
-638mV    3.604mA    3.771mA    4.35mA
-470mV    1.11mA     1.202mA    1.272mA
-197mV    214.8uA    168.4uA    281.4uA
2V        -171.9uA   -171.2uA   -177.1uA
[Pulldown]
|Voltage   I(typ)   I(min)   I(max)
-1V       -118.4mA   -166.7mA   -117mA
-938mV    -92.07mA   -126.1mA   -103.2mA
-876mV    -76.13mA   -92.99mA   -90.66mA
-783mV    -60.46mA   -59.19mA   -72.49mA
-659mV    -42.67mA   -37.52mA   -49.88mA
-473mV    -21.27mA   -20.11mA   -22.48mA
-287mV    -9.194mA   -9.165mA   -8.478mA
333mV     8.82mA     8.556mA    8.82mA
1.635V    21.06mA    20.43mA    21.06mA
1.883V    36.89mA    35.78mA    36.89mA
1.945V    49.53mA    48.04mA    49.53mA
2V        68.4mA     66.35mA    68.4mA
[Pullup]
|Voltage   I(typ)   I(min)   I(max)
-1V       93.11mA    133.6mA    73.95mA
-914mV    71.08mA    88.51mA    62.13mA
-852mV    62.37mA    66mA       55.11mA
-759mV    52.81mA    47.45mA    45.45mA
-635mV    41.68mA    35.34mA    34.45mA
-201mV    10.63mA    8.725mA    8.452mA
140mV     -4.601mA   -4.463mA   -4.601mA
1.442V    -17.12mA   -16.61mA   -17.12mA
1.628V    -31.55mA   -30.6mA    -31.55mA
1.845V    -56.85mA   -55.15mA   -56.85mA
1.938V    -75.02mA   -72.77mA   -75.02mA
2V        -97.38mA   -94.46mA   -97.38mA
[Ramp]
| variable   typ   min   max
dV/dt_r   0.297/1.289n   0.294/1.487n   0.318/1.225n
dV/dt_f   0.326/2.344n   0.308/2.071n   0.339/2.247n
R_load = 50.000
[Rising Waveform]
R_fixture = 50.000
V_fixture = 0.000
V_fixture_min = 0.000
V_fixture_max = 0.000
|  time   V(typ)   V(min)   V(max)
0s        3.422mV    3.194mV    3.396mV
837ps     3.285mV    -1.744mV   5.956mV
1.147ns   27.21mV    15.71mV    48.46mV
1.548ns   118.4mV    82.85mV    171.2mV
2.258ns   322.7mV    259.8mV    371.5mV
2.721ns   407.1mV    347.8mV    444.3mV
3.261ns   459.7mV    410.9mV    487.2mV
3.93ns    489.9mV    451.3mV    510.5mV
4.981ns   507.8mV    476.7mV    523.8mV
10ns      519.2mV    493.3mV    532.6mV
[Rising Waveform]
R_fixture = 50.000
V_fixture = 1.000
V_fixture_min = 0.950
V_fixture_max = 1.050
|  time   V(typ)   V(min)   V(max)
0s        450.7mV    439.9mV    484.3mV
336ps     451.1mV    440mV      484mV
427ps     451.9mV    440.1mV    668.7mV
534ps     650.5mV    439.2mV    775.3mV
630ps     743.5mV    436.7mV    830.7mV
681ps     774.4mV    478.8mV    852.9mV
781ps     819.3mV    659.5mV    887.8mV
901ps     857.4mV    746.3mV    920.1mV
1.615ns   964.7mV    904.4mV    1.018V
10ns      999.9mV    949.9mV    1.05V
[Falling Waveform]
R_fixture = 50.000
V_fixture = 1.000
V_fixture_min = 0.950
V_fixture_max = 1.050
|  time   V(typ)   V(min)   V(max)
0s        999.9mV    949.9mV    1.05V
449ps     999.2mV    949.9mV    1.06V
844ps     1.003V     959.3mV    1.047V
1.501ns   962.9mV    911mV      985.7mV
2.2ns     873.8mV    808mV      876.5mV
3.481ns   669.8mV    596.8mV    662.4mV
4.121ns   583.3mV    530.5mV    588.6mV
4.73ns    527.2mV    493.1mV    544.1mV
6.36ns    467.6mV    453.5mV    496.5mV
10ns      450.7mV    439.9mV    484.3mV
[Falling Waveform]
R_fixture = 50.000
V_fixture = 0.000
V_fixture_min = 0.000
V_fixture_max = 0.000
|  time   V(typ)   V(min)   V(max)
0s        519.2mV    493.3mV    532.6mV
369ps     520mV      492.8mV    567.8mV
490ps     540.4mV    492.4mV    349.4mV
684ps     276mV      528.5mV    207.6mV
904ps     161.2mV    287.2mV    132.8mV
1.041ns   123.2mV    191.5mV    102.6mV
1.304ns   76.64mV    102.9mV    65.14mV
1.671ns   43.79mV    50.26mV    37.77mV
3.251ns   11.07mV    11.23mV    9.382mV
10ns      3.422mV    3.194mV    3.396mV
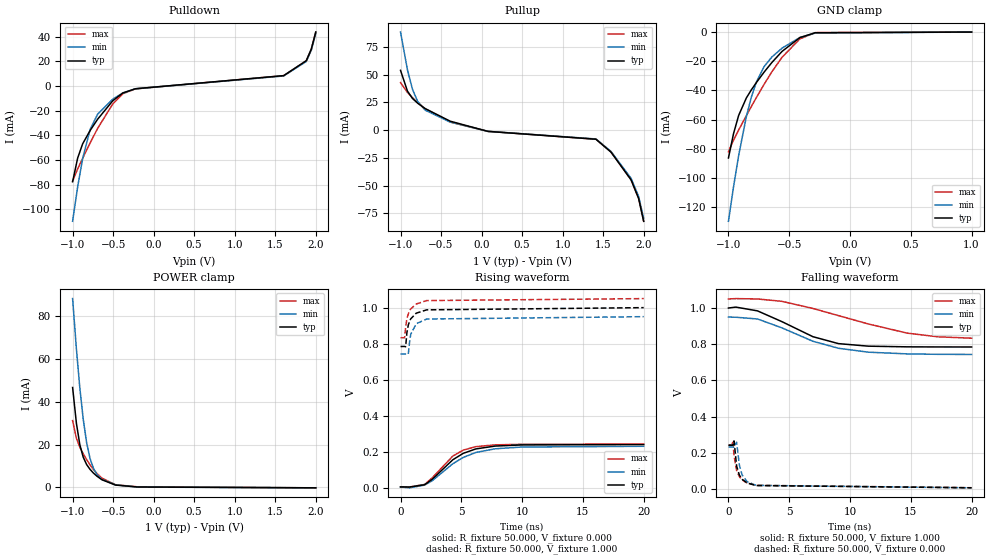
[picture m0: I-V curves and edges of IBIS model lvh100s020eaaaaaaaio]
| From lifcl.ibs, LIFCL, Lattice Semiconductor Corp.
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[Model] lvh100s020eaaaaaaaio
Model_type I/O
Polarity   Non-Inverting
Enable   Active-Low
Vinl =  0.350V
Vinh =  0.650V
Vmeas =  0.500V
Cref =  0.0F
Rref =  1.000M
Vref =  0.0V
C_comp   5.000pF   4.000pF   5.500pF
[Temperature Range]   25.000   0.125k   -40.000
[Voltage Range]   1.000V   0.950V   1.050V
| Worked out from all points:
|   slope of the pulldown table from 0 to 0.15 V, typ, clamps not added: 107 ohm
|   slope of the pullup table from 0 to 0.15 V, typ, clamps not added: 74.9 ohm
|   GND clamp passes 1 mA (typ) near -0.32 V on its own axis
|   POWER clamp passes 1 mA (typ) near -0.46 V on its own axis
|   rising waveform, R_fixture 50.000, V_fixture 0.000: 20-80 % time 2.54ns typ, 2.91ns min, 2.16ns max; typ from 0.006 V to 0.241 V
|   rising waveform, R_fixture 50.000, V_fixture 1.000: 20-80 % time 573ps typ, 548ps min, 612ps max; typ from 0.784 V to 1 V
|   falling waveform, R_fixture 50.000, V_fixture 1.000: 20-80 % time 4.1ns typ, 4.79ns min, 7.13ns max; typ from 1 V to 0.784 V
|   falling waveform, R_fixture 50.000, V_fixture 0.000: 20-80 % time 570ps typ, 561ps min, 616ps max; typ from 0.241 V to 0.006 V
[GND_clamp]
|Voltage   I(typ)   I(min)   I(max)
-1V       -86.39mA   -129.8mA   -82.1mA
-958mV    -69.62mA   -106.1mA   -74.12mA
-916mV    -57.21mA   -84.7mA    -67.22mA
-853mV    -45.26mA   -58.07mA   -57.38mA
-811mV    -39.58mA   -44.43mA   -50.99mA
-769mV    -34.5mA    -34.04mA   -44.75mA
-706mV    -27.42mA   -23.61mA   -35.76mA
-643mV    -20.91mA   -17.14mA   -27.32mA
-559mV    -13.28mA   -11.04mA   -17.29mA
-412mV    -3.804mA   -3.723mA   -4.655mA
-286mV    -477.7uA   -703.7uA   -396.2uA
1V        0A         0A         0A
[POWER_clamp]
|Voltage   I(typ)   I(min)   I(max)
-1V       46.74mA    88.29mA    31.25mA
-953mV    29.96mA    64.69mA    22.99mA
-911mV    20.02mA    46.58mA    18.81mA
-869mV    14.14mA    31.9mA     15.73mA
-827mV    10.71mA    20.96mA    13.03mA
-785mV    8.459mA    13.56mA    10.59mA
-743mV    6.733mA    8.952mA    8.425mA
-701mV    5.305mA    6.142mA    6.561mA
-638mV    3.604mA    3.771mA    4.35mA
-470mV    1.11mA     1.202mA    1.272mA
-197mV    214.8uA    168.4uA    281.4uA
2V        -171.9uA   -171.2uA   -177.1uA
[Pulldown]
|Voltage   I(typ)   I(min)   I(max)
-1V       -77.67mA   -109.7mA   -77.1mA
-938mV    -58.53mA   -81.92mA   -67.33mA
-876mV    -46.89mA   -58.86mA   -58.63mA
-783mV    -36mA      -35.1mA    -46.09mA
-690mV    -26.86mA   -22.73mA   -34.26mA
-504mV    -11.96mA   -10.67mA   -14.5mA
-380mV    -5.675mA   -5.626mA   -6.286mA
-225mV    -2.256mA   -2.289mA   -2.368mA
1.604V    8.365mA    8.114mA    8.365mA
1.883V    20.45mA    19.84mA    20.45mA
1.945V    29.87mA    28.98mA    29.87mA
2V        43.72mA    42.41mA    43.72mA
[Pullup]
|Voltage   I(typ)   I(min)   I(max)
-1V       53.82mA    88.35mA    42.77mA
-914mV    35.07mA    54.09mA    33.96mA
-852mV    28.48mA    36.64mA    29.23mA
-790mV    24.35mA    25.97mA    24.93mA
-697mV    19.44mA    18.02mA    19.27mA
-387mV    8.033mA    7.234mA    7.289mA
78mV      -1.129mA   -1.095mA   -1.129mA
1.411V    -8.204mA   -7.958mA   -8.204mA
1.597V    -19.79mA   -19.2mA    -19.79mA
1.845V    -44.84mA   -43.5mA    -44.84mA
1.938V    -61.59mA   -59.75mA   -61.59mA
2V        -82.12mA   -79.65mA   -82.12mA
[Ramp]
| variable   typ   min   max
dV/dt_r   0.141/2.514n   0.132/2.889n   0.146/2.208n
dV/dt_f   0.129/4.122n   0.125/4.816n   0.130/7.146n
R_load = 50.000
[Rising Waveform]
R_fixture = 50.000
V_fixture = 0.000
V_fixture_min = 0.000
V_fixture_max = 0.000
|  time   V(typ)   V(min)   V(max)
0s        5.984mV    5.696mV    6.291mV
725ps     5.05mV     803uV      5.603mV
1.979ns   17.88mV    15.91mV    19.37mV
2.6ns     47.79mV    39.88mV    55.67mV
4.301ns   156.4mV    134.3mV    176.9mV
5.159ns   192.1mV    169.6mV    210mV
6.191ns   216.5mV    196.8mV    229.2mV
7.787ns   232.4mV    217.3mV    239.1mV
9.95ns    238.6mV    227mV      242.1mV
20ns      241mV      231.3mV    243.4mV
[Rising Waveform]
R_fixture = 50.000
V_fixture = 1.000
V_fixture_min = 0.950
V_fixture_max = 1.050
|  time   V(typ)   V(min)   V(max)
0s        784.5mV    743.1mV    833mV
336ps     784.8mV    743.3mV    833.3mV
422ps     782.9mV    743.2mV    891.2mV
523ps     860.8mV    743.1mV    937.7mV
640ps     903.7mV    741.6mV    965.4mV
761ps     927.1mV    819.9mV    983.8mV
841ps     937.9mV    852mV      992.7mV
1.29ns    969.1mV    910.6mV    1.02V
2.143ns   987.6mV    936.7mV    1.039V
20ns      999.9mV    949.9mV    1.05V
[Falling Waveform]
R_fixture = 50.000
V_fixture = 1.000
V_fixture_min = 0.950
V_fixture_max = 1.050
|  time   V(typ)   V(min)   V(max)
0s        999.9mV    949.9mV    1.05V
613ps     1.005V     948.9mV    1.052V
2.39ns    984.2mV    939.4mV    1.05V
4.39ns    924.9mV    890.5mV    1.037V
6.945ns   841.5mV    816.2mV    997.6mV
9.049ns   803.1mV    777.4mV    958mV
11.51ns   789mV      755.8mV    911.8mV
14.7ns    785.3mV    746.3mV    861.1mV
17.19ns   784.7mV    744mV      841.1mV
20ns      784.5mV    743.1mV    833mV
[Falling Waveform]
R_fixture = 50.000
V_fixture = 0.000
V_fixture_min = 0.000
V_fixture_max = 0.000
|  time   V(typ)   V(min)   V(max)
0s        241mV      231.3mV    243.4mV
283ps     240.9mV    230.9mV    243.1mV
369ps     241.7mV    230.9mV    264.5mV
461ps     265.4mV    231mV      182.5mV
673ps     125.8mV    257.9mV    101.6mV
903ps     75.57mV    130.2mV    67.11mV
1.123ns   53.11mV    76.88mV    49.59mV
1.534ns   32.68mV    39.59mV    32.46mV
2.274ns   18.42mV    19.47mV    19.3mV
20ns      5.984mV    5.696mV    6.291mV
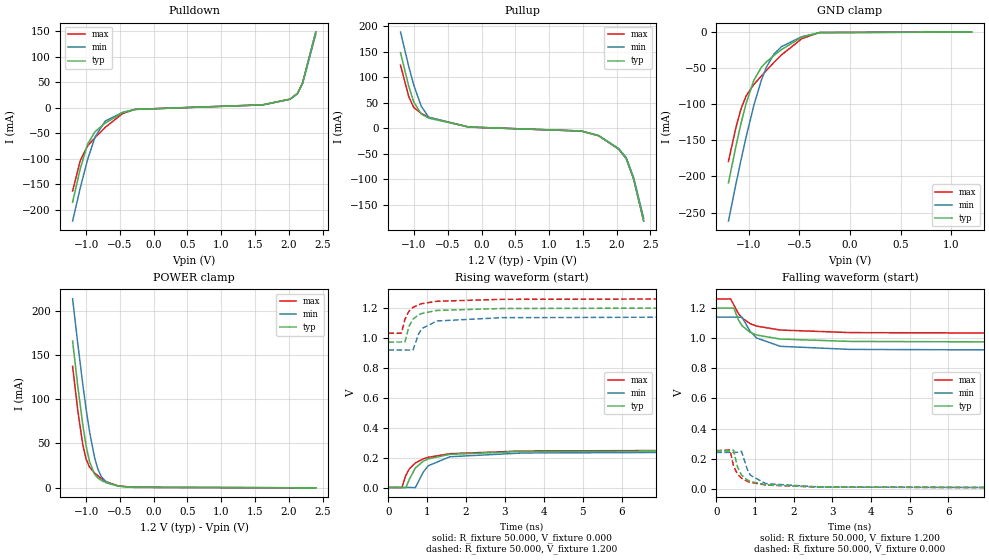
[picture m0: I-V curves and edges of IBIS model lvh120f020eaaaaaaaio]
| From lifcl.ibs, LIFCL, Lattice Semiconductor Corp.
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[Model] lvh120f020eaaaaaaaio
Model_type I/O
Polarity   Non-Inverting
Enable   Active-Low
Vinl =  0.420V
Vinh =  0.780V
Vmeas =  0.600V
Cref =  0.0F
Rref =  1.000M
Vref =  0.0V
C_comp   5.000pF   4.000pF   5.500pF
[Temperature Range]   25.000   0.125k   -40.000
[Voltage Range]   1.200V   1.140V   1.260V
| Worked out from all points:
|   slope of the pulldown table from 0 to 0.18 V, typ, clamps not added: 107 ohm
|   slope of the pullup table from 0 to 0.18 V, typ, clamps not added: 92.2 ohm
|   GND clamp passes 1 mA (typ) near -0.32 V on its own axis
|   POWER clamp passes 1 mA (typ) near -0.45 V on its own axis
|   rising waveform, R_fixture 50.000, V_fixture 0.000: 20-80 % time 558ps typ, 540ps min, 580ps max; typ from 0.006 V to 0.251 V
|   rising waveform, R_fixture 50.000, V_fixture 1.200: 20-80 % time 310ps typ, 328ps min, 324ps max; typ from 0.973 V to 1.2 V
|   falling waveform, R_fixture 50.000, V_fixture 1.200: 20-80 % time 553ps typ, 574ps min, 613ps max; typ from 1.2 V to 0.973 V
|   falling waveform, R_fixture 50.000, V_fixture 0.000: 20-80 % time 332ps typ, 335ps min, 346ps max; typ from 0.251 V to 0.006 V
[GND_clamp]
|Voltage   I(typ)   I(min)   I(max)
-1.2V     -208.9mA   -261.7mA   -179.3mA
-1.125V   -157.4mA   -209.8mA   -131.5mA
-1.075V   -126mA     -176.6mA   -106.1mA
-1.025V   -98.42mA   -145mA     -88.28mA
-950mV    -66.96mA   -101.9mA   -72.76mA
-875mV    -48.78mA   -66.64mA   -60.78mA
-825mV    -41.38mA   -48.67mA   -53.1mA
-750mV    -32.3mA    -30.34mA   -41.99mA
-675mV    -24.14mA   -20.11mA   -31.53mA
-475mV    -7.155mA   -6.375mA   -9.116mA
-300mV    -673.7uA   -900.4uA   -619.4uA
1.2V      0A         0A         0A
[POWER_clamp]
|Voltage   I(typ)   I(min)   I(max)
-1.2V     165.7mA    213.3mA    137.1mA
-1.125V   115.8mA    163.7mA    88.19mA
-1.05V    71.42mA    117.1mA    48.87mA
-1V       47.37mA    88.79mA    32.13mA
-950mV    29.54mA    63.68mA    23.24mA
-875mV    15.17mA    34.1mA     16.62mA
-825mV    10.91mA    20.81mA    13.34mA
-775mV    8.283mA    12.48mA    10.42mA
-700mV    5.463mA    6.247mA    6.777mA
-525mV    1.711mA    1.811mA    1.978mA
-300mV    395.7uA    364.9uA    500.6uA
2.4V      -178.9uA   -186.1uA   -181.3uA
[Pulldown]
|Voltage   I(typ)   I(min)   I(max)
-1.2V     -185.3mA   -222.1mA   -163.3mA
-1.089V   -120.6mA   -158.4mA   -104.5mA
-978mV    -71.42mA   -101.4mA   -74.7mA
-867mV    -46.58mA   -57.11mA   -58.45mA
-719mV    -30.22mA   -26.19mA   -38.55mA
-460mV    -9.51mA    -8.803mA   -11.2mA
-275mV    -3.015mA   -3.114mA   -3.102mA
1.612V    5.843mA    5.667mA    5.843mA
2.019V    17.03mA    16.52mA    17.03mA
2.13V     28.43mA    27.57mA    28.43mA
2.204V    48.5mA     47.04mA    48.5mA
2.4V      148.7mA    144.2mA    148.7mA
[Pullup]
|Voltage   I(typ)   I(min)   I(max)
-1.2V     147.9mA    188.3mA    123.4mA
-1.078V   81.98mA    120.7mA    61.86mA
-1.004V   51.59mA    84.61mA    40.82mA
-893mV    27.85mA    43mA       29.06mA
-782mV    19.86mA    21.61mA    21.61mA
-190mV    2.572mA    2.372mA    2.456mA
1.475V    -5.352mA   -5.192mA   -5.352mA
1.734V    -14.51mA   -14.08mA   -14.51mA
2.03V     -40.75mA   -39.53mA   -40.75mA
2.141V    -58.9mA    -57.14mA   -58.9mA
2.252V    -99.4mA    -96.4mA    -99.4mA
2.4V      -181.3mA   -175.9mA   -181.3mA
[Ramp]
| variable   typ   min   max
dV/dt_r   0.147/0.561n   0.141/0.547n   0.148/0.579n
dV/dt_f   0.136/0.556n   0.132/0.571n   0.136/0.621n
R_load = 50.000
[Rising Waveform]
R_fixture = 50.000
V_fixture = 0.000
V_fixture_min = 0.000
V_fixture_max = 0.000
|  time   V(typ)   V(min)   V(max)
0s        5.991mV    5.971mV    6.261mV
346ps     6.193mV    6.085mV    4.321mV
445ps     3.349mV    6.021mV    83.51mV
543ps     61.25mV    6.205mV    131.1mV
694ps     135.5mV    4.519mV    168.6mV
895ps     180.3mV    107.3mV    195.7mV
1.024ns   196mV      149.9mV    206.6mV
1.584ns   226.3mV    210.2mV    230.5mV
3.44ns    245.5mV    235.1mV    248.7mV
10ns      251.2mV    241.5mV    253.5mV
[Rising Waveform]
R_fixture = 50.000
V_fixture = 1.200
V_fixture_min = 1.140
V_fixture_max = 1.260
|  time   V(typ)   V(min)   V(max)
0s        973mV      919.7mV    1.032V
336ps     973.2mV    919.9mV    1.032V
427ps     974.1mV    919.9mV    1.125V
528ps     1.076V     919.5mV    1.178V
634ps     1.125V     919.7mV    1.203V
775ps     1.153V     1.025V     1.221V
858ps     1.163V     1.062V     1.228V
1.245ns   1.183V     1.113V     1.244V
2.933ns   1.196V     1.135V     1.257V
10ns      1.2V       1.14V      1.26V
[Falling Waveform]
R_fixture = 50.000
V_fixture = 1.200
V_fixture_min = 1.140
V_fixture_max = 1.260
|  time   V(typ)   V(min)   V(max)
0s        1.2V       1.14V      1.26V
370ps     1.2V       1.14V      1.261V
454ps     1.199V     1.14V      1.22V
574ps     1.121V     1.139V     1.163V
663ps     1.083V     1.14V      1.135V
873ps     1.039V     1.047V     1.097V
1.043ns   1.021V     1.001V     1.08V
1.655ns   994.1mV    945.9mV    1.054V
3.459ns   978.4mV    925.3mV    1.037V
10ns      973mV      919.7mV    1.032V
[Falling Waveform]
R_fixture = 50.000
V_fixture = 0.000
V_fixture_min = 0.000
V_fixture_max = 0.000
|  time   V(typ)   V(min)   V(max)
0s        251.2mV    241.5mV    253.5mV
356ps     251mV      241.2mV    257.2mV
446ps     256.5mV    241.4mV    150.9mV
548ps     145.4mV    242mV      97mV
653ps     91.1mV     248.3mV    70.07mV
803ps     58.58mV    127.7mV    49.22mV
883ps     48.74mV    89.75mV    42.28mV
1.278ns   26.22mV    34.2mV     24.85mV
2.673ns   11.39mV    11.62mV    10.76mV
10ns      5.991mV    5.971mV    6.261mV
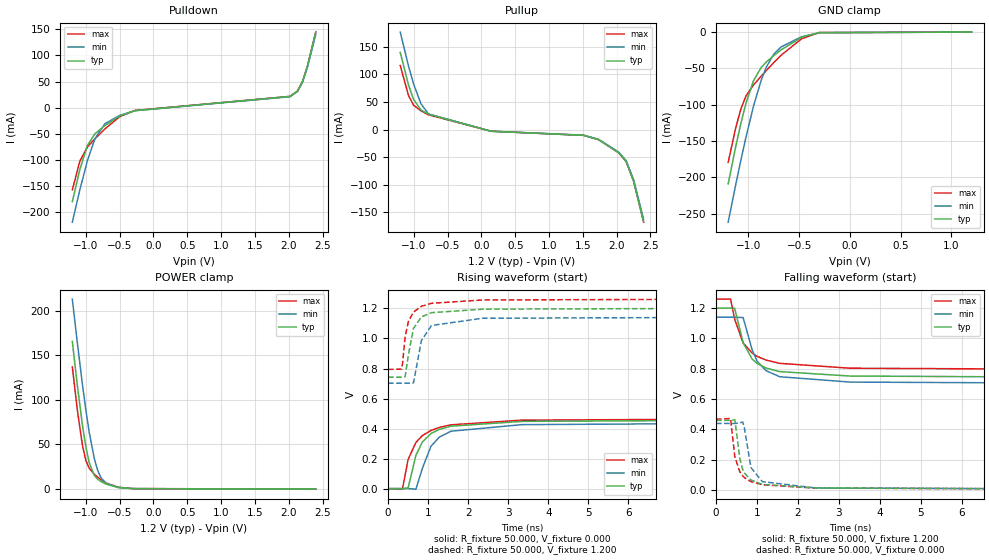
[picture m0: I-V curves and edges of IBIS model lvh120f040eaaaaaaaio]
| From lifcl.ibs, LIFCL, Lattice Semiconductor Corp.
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[Model] lvh120f040eaaaaaaaio
Model_type I/O
Polarity   Non-Inverting
Enable   Active-Low
Vinl =  0.420V
Vinh =  0.780V
Vmeas =  0.600V
Cref =  0.0F
Rref =  1.000M
Vref =  0.0V
C_comp   5.000pF   4.000pF   5.500pF
[Temperature Range]   25.000   0.125k   -40.000
[Voltage Range]   1.200V   1.140V   1.260V
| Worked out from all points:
|   slope of the pulldown table from 0 to 0.18 V, typ, clamps not added: 51.8 ohm
|   slope of the pullup table from 0 to 0.18 V, typ, clamps not added: 47.9 ohm
|   GND clamp passes 1 mA (typ) near -0.32 V on its own axis
|   POWER clamp passes 1 mA (typ) near -0.45 V on its own axis
|   rising waveform, R_fixture 50.000, V_fixture 0.000: 20-80 % time 490ps typ, 501ps min, 533ps max; typ from 0.004 V to 0.459 V
|   rising waveform, R_fixture 50.000, V_fixture 1.200: 20-80 % time 229ps typ, 250ps min, 235ps max; typ from 0.742 V to 1.2 V
|   falling waveform, R_fixture 50.000, V_fixture 1.200: 20-80 % time 467ps typ, 449ps min, 541ps max; typ from 1.2 V to 0.742 V
|   falling waveform, R_fixture 50.000, V_fixture 0.000: 20-80 % time 221ps typ, 234ps min, 242ps max; typ from 0.459 V to 0.004 V
[GND_clamp]
|Voltage   I(typ)   I(min)   I(max)
-1.2V     -208.9mA   -261.7mA   -179.3mA
-1.125V   -157.4mA   -209.8mA   -131.5mA
-1.075V   -126mA     -176.6mA   -106.1mA
-1.025V   -98.42mA   -145mA     -88.28mA
-950mV    -66.96mA   -101.9mA   -72.76mA
-875mV    -48.78mA   -66.64mA   -60.78mA
-825mV    -41.38mA   -48.67mA   -53.1mA
-750mV    -32.3mA    -30.34mA   -41.99mA
-675mV    -24.14mA   -20.11mA   -31.53mA
-475mV    -7.155mA   -6.375mA   -9.116mA
-300mV    -673.7uA   -900.4uA   -619.4uA
1.2V      0A         0A         0A
[POWER_clamp]
|Voltage   I(typ)   I(min)   I(max)
-1.2V     165.7mA    213.3mA    137.1mA
-1.125V   115.8mA    163.7mA    88.19mA
-1.05V    71.42mA    117.1mA    48.87mA
-1V       47.37mA    88.79mA    32.13mA
-950mV    29.54mA    63.68mA    23.24mA
-875mV    15.17mA    34.1mA     16.62mA
-825mV    10.91mA    20.81mA    13.34mA
-775mV    8.283mA    12.48mA    10.42mA
-700mV    5.463mA    6.247mA    6.777mA
-525mV    1.711mA    1.811mA    1.978mA
-300mV    395.7uA    364.9uA    500.6uA
2.4V      -178.9uA   -186.1uA   -181.3uA
[Pulldown]
|Voltage   I(typ)   I(min)   I(max)
-1.2V     -180.2mA   -219.5mA   -157.6mA
-1.089V   -118.7mA   -157.5mA   -102.6mA
-978mV    -72.85mA   -102.3mA   -75.46mA
-867mV    -50.28mA   -60.01mA   -59.99mA
-719mV    -34.47mA   -30.88mA   -40.86mA
-497mV    -15.93mA   -14.83mA   -17.14mA
-275mV    -5.882mA   -5.851mA   -5.411mA
2.019V    21.52mA    20.87mA    21.52mA
2.13V     31.72mA    30.77mA    31.72mA
2.204V    49.93mA    48.43mA    49.93mA
2.278V    79.85mA    77.46mA    79.85mA
2.4V      144.7mA    140.4mA    144.7mA
[Pullup]
|Voltage   I(typ)   I(min)   I(max)
-1.2V     139.7mA    176.6mA    116.1mA
-1.078V   80.9mA     115.4mA    61.64mA
-1.004V   54.85mA    83mA       44.23mA
-893mV    35.47mA    46.56mA    33.97mA
-782mV    27.9mA     28.22mA    26.69mA
143mV     -3.072mA   -2.98mA    -3.072mA
1.512V    -10.52mA   -10.21mA   -10.52mA
1.734V    -18.28mA   -17.73mA   -18.28mA
2.03V     -42.1mA    -40.84mA   -42.1mA
2.141V    -57.94mA   -56.2mA    -57.94mA
2.252V    -93.7mA    -90.9mA    -93.7mA
2.4V      -167.9mA   -162.9mA   -167.9mA
[Ramp]
| variable   typ   min   max
dV/dt_r   0.273/0.491n   0.260/0.509n   0.277/0.541n
dV/dt_f   0.275/0.468n   0.262/0.448n   0.280/0.541n
R_load = 50.000
[Rising Waveform]
R_fixture = 50.000
V_fixture = 0.000
V_fixture_min = 0.000
V_fixture_max = 0.000
|  time   V(typ)   V(min)   V(max)
0s        4.45mV     4.4mV      4.331mV
359ps     4.834mV    4.454mV    803.7uV
500ps     8.303mV    4.561mV    197.2mV
695ps     225mV      816.3uV    310.3mV
855ps     312.6mV    137.3mV    355mV
1.07ns    368.7mV    284.7mV    389.7mV
1.281ns   397.1mV    345.9mV    410mV
1.571ns   418.1mV    384.7mV    427mV
3.343ns   449.7mV    428.2mV    458.1mV
10ns      458.7mV    438.4mV    466.4mV
[Rising Waveform]
R_fixture = 50.000
V_fixture = 1.200
V_fixture_min = 1.140
V_fixture_max = 1.260
|  time   V(typ)   V(min)   V(max)
0s        742.2mV    702.7mV    794.3mV
336ps     742.4mV    702.8mV    795.8mV
359ps     741.7mV    702.8mV    826.3mV
426ps     746.2mV    702.9mV    1.011V
509ps     893.1mV    702.6mV    1.113V
635ps     1.066V     705.1mV    1.174V
832ps     1.142V     985mV      1.212V
1.085ns   1.17V      1.085V     1.232V
2.365ns   1.193V     1.133V     1.254V
10ns      1.2V       1.14V      1.26V
[Falling Waveform]
R_fixture = 50.000
V_fixture = 1.200
V_fixture_min = 1.140
V_fixture_max = 1.260
|  time   V(typ)   V(min)   V(max)
0s        1.2V       1.14V      1.26V
356ps     1.2V       1.14V      1.26V
457ps     1.199V     1.14V      1.126V
663ps     971.5mV    1.138V     970.3mV
883ps     864mV      924.8mV    903.4mV
1.007ns   834.6mV    848.6mV    881.6mV
1.223ns   804.2mV    787.1mV    857mV
1.557ns   780.9mV    747mV      835.4mV
3.271ns   751.6mV    711.7mV    803.3mV
10ns      742.2mV    702.7mV    794.3mV
[Falling Waveform]
R_fixture = 50.000
V_fixture = 0.000
V_fixture_min = 0.000
V_fixture_max = 0.000
|  time   V(typ)   V(min)   V(max)
0s        458.7mV    438.4mV    466.4mV
356ps     458.7mV    438.2mV    471mV
461ps     462.1mV    438.2mV    216.9mV
581ps     208.8mV    442.1mV    119mV
653ps     134mV      448mV      92.05mV
693ps     111.6mV    410.2mV    81.29mV
854ps     64.8mV     147.2mV    54.16mV
1.133ns   35.65mV    53.95mV    33.56mV
2.433ns   12.27mV    12.37mV    11.27mV
10ns      4.45mV     4.4mV      4.331mV
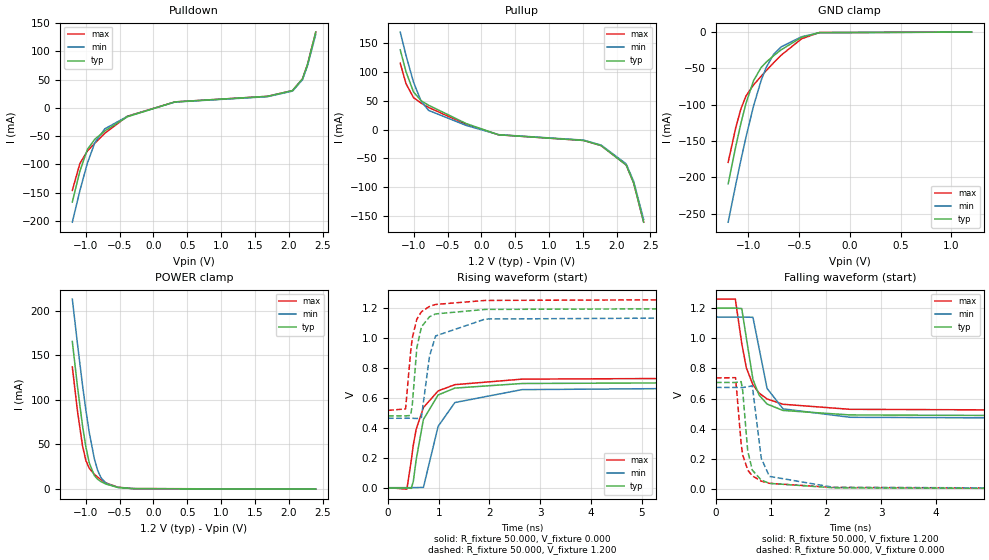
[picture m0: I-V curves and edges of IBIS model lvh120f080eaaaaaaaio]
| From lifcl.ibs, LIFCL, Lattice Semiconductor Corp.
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[Model] lvh120f080eaaaaaaaio
Model_type I/O
Polarity   Non-Inverting
Enable   Active-Low
Vinl =  0.420V
Vinh =  0.780V
Vmeas =  0.600V
Cref =  0.0F
Rref =  1.000M
Vref =  0.0V
C_comp   5.000pF   4.000pF   5.500pF
[Temperature Range]   25.000   0.125k   -40.000
[Voltage Range]   1.200V   1.140V   1.260V
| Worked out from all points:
|   slope of the pulldown table from 0 to 0.18 V, typ, clamps not added: 28.1 ohm
|   slope of the pullup table from 0 to 0.18 V, typ, clamps not added: 26.4 ohm
|   GND clamp passes 1 mA (typ) near -0.32 V on its own axis
|   POWER clamp passes 1 mA (typ) near -0.45 V on its own axis
|   rising waveform, R_fixture 50.000, V_fixture 0.000: 20-80 % time 298ps typ, 418ps min, 351ps max; typ from 0 V to 0.707 V
|   rising waveform, R_fixture 50.000, V_fixture 1.200: 20-80 % time 145ps typ, 200ps min, 165ps max; typ from 0.481 V to 1.2 V
|   falling waveform, R_fixture 50.000, V_fixture 1.200: 20-80 % time 247ps typ, 262ps min, 297ps max; typ from 1.2 V to 0.481 V
|   falling waveform, R_fixture 50.000, V_fixture 0.000: 20-80 % time 137ps typ, 156ps min, 148ps max; typ from 0.707 V to 0 V
[GND_clamp]
|Voltage   I(typ)   I(min)   I(max)
-1.2V     -208.9mA   -261.7mA   -179.3mA
-1.125V   -157.4mA   -209.8mA   -131.5mA
-1.075V   -126mA     -176.6mA   -106.1mA
-1.025V   -98.42mA   -145mA     -88.28mA
-950mV    -66.96mA   -101.9mA   -72.76mA
-875mV    -48.78mA   -66.64mA   -60.78mA
-825mV    -41.38mA   -48.67mA   -53.1mA
-750mV    -32.3mA    -30.34mA   -41.99mA
-675mV    -24.14mA   -20.11mA   -31.53mA
-475mV    -7.155mA   -6.375mA   -9.116mA
-300mV    -673.7uA   -900.4uA   -619.4uA
1.2V      0A         0A         0A
[POWER_clamp]
|Voltage   I(typ)   I(min)   I(max)
-1.2V     165.7mA    213.3mA    137.1mA
-1.125V   115.8mA    163.7mA    88.19mA
-1.05V    71.42mA    117.1mA    48.87mA
-1V       47.37mA    88.79mA    32.13mA
-950mV    29.54mA    63.68mA    23.24mA
-875mV    15.17mA    34.1mA     16.62mA
-825mV    10.91mA    20.81mA    13.34mA
-775mV    8.283mA    12.48mA    10.42mA
-700mV    5.463mA    6.247mA    6.777mA
-525mV    1.711mA    1.811mA    1.978mA
-300mV    395.7uA    364.9uA    500.6uA
2.4V      -178.9uA   -186.1uA   -181.3uA
[Pulldown]
|Voltage   I(typ)   I(min)   I(max)
-1.2V     -166.9mA   -202.6mA   -146.3mA
-1.089V   -112.5mA   -147.1mA   -98.8mA
-978mV    -73.85mA   -98.2mA    -76.62mA
-867mV    -55.49mA   -61.71mA   -62.62mA
-719mV    -40.9mA    -37.09mA   -45mA
-386mV    -15.77mA   -15.06mA   -14.81mA
317mV     10.59mA    10.27mA    10.59mA
1.686V    20.44mA    19.83mA    20.44mA
2.056V    30.64mA    29.72mA    30.64mA
2.204V    51.44mA    49.9mA     51.44mA
2.278V    76.9mA     74.6mA     76.9mA
2.4V      134.3mA    130.3mA    134.3mA
[Pullup]
|Voltage   I(typ)   I(min)   I(max)
-1.2V     138.9mA    169.7mA    115.5mA
-1.115V   100.8mA    129.1mA    80mA
-1.004V   65.58mA    82.7mA     55.68mA
-893mV    50.42mA    49.87mA    46.37mA
-782mV    42.45mA    33.45mA    38.57mA
-227mV    10.6mA     7.326mA    9.265mA
254mV     -9.081mA   -8.809mA   -9.081mA
1.512V    -18.91mA   -18.34mA   -18.91mA
1.771V    -27.88mA   -27.05mA   -27.88mA
2.141V    -61.54mA   -59.7mA    -61.54mA
2.252V    -92.9mA    -90.1mA    -92.9mA
2.4V      -161.2mA   -156.4mA   -161.2mA
[Ramp]
| variable   typ   min   max
dV/dt_r   0.426/0.301n   0.403/0.422n   0.441/0.351n
dV/dt_f   0.428/0.249n   0.405/0.264n   0.445/0.295n
R_load = 50.000
[Rising Waveform]
R_fixture = 50.000
V_fixture = 0.000
V_fixture_min = 0.000
V_fixture_max = 0.000
|  time   V(typ)   V(min)   V(max)
0s        40.99uV    2.932mV    2.858mV
371ps     692.1uV    2.939mV    -7.158mV
457ps     -1.61mV    2.968mV    183.2mV
497ps     43.23mV    3.125mV    285.6mV
554ps     188.2mV    3.515mV    391.8mV
697ps     457.9mV    4.569mV    537mV
987ps     620.8mV    411.5mV    647.7mV
1.317ns   666.6mV    570.2mV    689.4mV
2.64ns    697.2mV    656.3mV    726.2mV
10ns      707.3mV    674.3mV    737.3mV
[Rising Waveform]
R_fixture = 50.000
V_fixture = 1.200
V_fixture_min = 1.140
V_fixture_max = 1.260
|  time   V(typ)   V(min)   V(max)
0s        481.2mV    465.4mV    518mV
345ps     481.3mV    465.5mV    527.6mV
444ps     484.1mV    465.6mV    904mV
477ps     552.1mV    465.6mV    999.8mV
567ps     933.7mV    463.8mV    1.126V
657ps     1.074V     470.6mV    1.175V
817ps     1.142V     878.9mV    1.211V
937ps     1.161V     1.014V     1.224V
1.918ns   1.191V     1.127V     1.251V
10ns      1.2V       1.141V     1.26V
[Falling Waveform]
R_fixture = 50.000
V_fixture = 1.200
V_fixture_min = 1.140
V_fixture_max = 1.260
|  time   V(typ)   V(min)   V(max)
0s        1.2V       1.141V     1.26V
351ps     1.2V       1.141V     1.26V
468ps     1.197V     1.141V     966mV
552ps     1.001V     1.14V      803.5mV
671ps     727.8mV    1.139V     691.8mV
782ps     623.9mV    935.8mV    637.1mV
928ps     564.3mV    667.7mV    597.7mV
1.218ns   521.7mV    532.5mV    562.8mV
2.432ns   492.1mV    476.4mV    529.3mV
10ns      481.2mV    465.4mV    518mV
[Falling Waveform]
R_fixture = 50.000
V_fixture = 0.000
V_fixture_min = 0.000
V_fixture_max = 0.000
|  time   V(typ)   V(min)   V(max)
0s        707.3mV    674.3mV    737.3mV
356ps     707.1mV    674mV      739.1mV
457ps     712.9mV    674.1mV    301mV
486ps     650.5mV    673.8mV    226.7mV
576ps     254.8mV    678.5mV    127.1mV
660ps     126.3mV    684.8mV    87.93mV
822ps     60.22mV    205.5mV    53.22mV
970ps     38.53mV    84.65mV    38.77mV
2.141ns   8.943mV    12.01mV    11.26mV
10ns      40.99uV    2.932mV    2.858mV
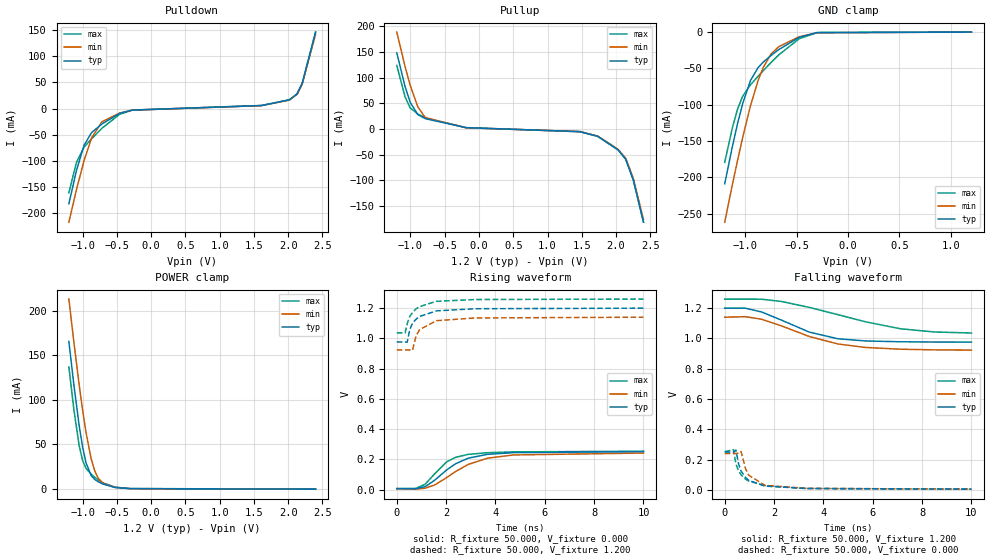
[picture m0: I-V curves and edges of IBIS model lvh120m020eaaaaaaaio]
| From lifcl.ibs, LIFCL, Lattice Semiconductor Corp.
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[Model] lvh120m020eaaaaaaaio
Model_type I/O
Polarity   Non-Inverting
Enable   Active-Low
Vinl =  0.420V
Vinh =  0.780V
Vmeas =  0.600V
Cref =  0.0F
Rref =  1.000M
Vref =  0.0V
C_comp   5.000pF   4.000pF   5.500pF
[Temperature Range]   25.000   0.125k   -40.000
[Voltage Range]   1.200V   1.140V   1.260V
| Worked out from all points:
|   slope of the pulldown table from 0 to 0.18 V, typ, clamps not added: 108 ohm
|   slope of the pullup table from 0 to 0.18 V, typ, clamps not added: 92.2 ohm
|   GND clamp passes 1 mA (typ) near -0.32 V on its own axis
|   POWER clamp passes 1 mA (typ) near -0.45 V on its own axis
|   rising waveform, R_fixture 50.000, V_fixture 0.000: 20-80 % time 1.31ns typ, 1.57ns min, 962ps max; typ from 0.006 V to 0.251 V
|   rising waveform, R_fixture 50.000, V_fixture 1.200: 20-80 % time 547ps typ, 530ps min, 570ps max; typ from 0.976 V to 1.2 V
|   falling waveform, R_fixture 50.000, V_fixture 1.200: 20-80 % time 2.04ns typ, 2.4ns min, 3.35ns max; typ from 1.2 V to 0.976 V
|   falling waveform, R_fixture 50.000, V_fixture 0.000: 20-80 % time 536ps typ, 516ps min, 606ps max; typ from 0.251 V to 0.006 V
[GND_clamp]
|Voltage   I(typ)   I(min)   I(max)
-1.2V     -208.9mA   -261.7mA   -179.3mA
-1.125V   -157.4mA   -209.8mA   -131.5mA
-1.075V   -126mA     -176.6mA   -106.1mA
-1.025V   -98.42mA   -145mA     -88.28mA
-950mV    -66.96mA   -101.9mA   -72.76mA
-875mV    -48.78mA   -66.64mA   -60.78mA
-825mV    -41.38mA   -48.67mA   -53.1mA
-750mV    -32.3mA    -30.34mA   -41.99mA
-675mV    -24.14mA   -20.11mA   -31.53mA
-475mV    -7.155mA   -6.375mA   -9.116mA
-300mV    -673.7uA   -900.4uA   -619.4uA
1.2V      0A         0A         0A
[POWER_clamp]
|Voltage   I(typ)   I(min)   I(max)
-1.2V     165.7mA    213.3mA    137.1mA
-1.125V   115.8mA    163.7mA    88.19mA
-1.05V    71.42mA    117.1mA    48.87mA
-1V       47.37mA    88.79mA    32.13mA
-950mV    29.54mA    63.68mA    23.24mA
-875mV    15.17mA    34.1mA     16.62mA
-825mV    10.91mA    20.81mA    13.34mA
-775mV    8.283mA    12.48mA    10.42mA
-700mV    5.463mA    6.247mA    6.777mA
-525mV    1.711mA    1.811mA    1.978mA
-300mV    395.7uA    364.9uA    500.6uA
2.4V      -178.9uA   -186.1uA   -181.3uA
[Pulldown]
|Voltage   I(typ)   I(min)   I(max)
-1.2V     -182.9mA   -218.3mA   -161.8mA
-1.089V   -119mA     -155.7mA   -103.5mA
-978mV    -70.5mA    -99.7mA    -73.97mA
-867mV    -45.98mA   -56.14mA   -57.88mA
-719mV    -29.83mA   -25.74mA   -38.17mA
-460mV    -9.387mA   -8.653mA   -11.09mA
-275mV    -2.976mA   -3.061mA   -3.072mA
1.612V    5.767mA    5.594mA    5.767mA
2.019V    16.81mA    16.3mA     16.81mA
2.13V     28.06mA    27.22mA    28.06mA
2.204V    47.87mA    46.44mA    47.87mA
2.4V      146.8mA    142.4mA    146.8mA
[Pullup]
|Voltage   I(typ)   I(min)   I(max)
-1.2V     147.9mA    188.3mA    123.4mA
-1.078V   81.98mA    120.7mA    61.86mA
-1.004V   51.59mA    84.61mA    40.82mA
-893mV    27.85mA    43mA       29.06mA
-782mV    19.86mA    21.61mA    21.61mA
-190mV    2.572mA    2.372mA    2.456mA
1.475V    -5.352mA   -5.192mA   -5.352mA
1.734V    -14.51mA   -14.08mA   -14.51mA
2.03V     -40.75mA   -39.53mA   -40.75mA
2.141V    -58.9mA    -57.14mA   -58.9mA
2.252V    -99.4mA    -96.4mA    -99.4mA
2.4V      -181.3mA   -175.9mA   -181.3mA
[Ramp]
| variable   typ   min   max
dV/dt_r   0.147/1.318n   0.141/1.595n   0.148/1.021n
dV/dt_f   0.134/2.068n   0.130/2.485n   0.135/3.372n
R_load = 50.000
[Rising Waveform]
R_fixture = 50.000
V_fixture = 0.000
V_fixture_min = 0.000
V_fixture_max = 0.000
|  time   V(typ)   V(min)   V(max)
0s        6.015mV    5.985mV    6.29mV
775ps     5.907mV    2.681mV    7.694mV
1.145ns   19.23mV    8.986mV    34.91mV
1.534ns   61.43mV    29.97mV    103.8mV
2.029ns   130.8mV    80.02mV    184.2mV
2.39ns    171.2mV    120.1mV    213.7mV
2.903ns   208mV      166.8mV    232.9mV
3.684ns   233.2mV    207.8mV    244mV
4.731ns   244.2mV    229mV      249.3mV
10ns      251.2mV    241.5mV    253.5mV
[Rising Waveform]
R_fixture = 50.000
V_fixture = 1.200
V_fixture_min = 1.140
V_fixture_max = 1.260
|  time   V(typ)   V(min)   V(max)
0s        975.9mV    923.4mV    1.036V
336ps     976.2mV    923.6mV    1.036V
423ps     974.6mV    923.6mV    1.097V
525ps     1.057V     923.2mV    1.144V
635ps     1.099V     921.2mV    1.171V
781ps     1.127V     1.016V     1.195V
925ps     1.145V     1.058V     1.21V
1.605ns   1.182V     1.117V     1.245V
3.169ns   1.196V     1.135V     1.257V
10ns      1.2V       1.14V      1.26V
[Falling Waveform]
R_fixture = 50.000
V_fixture = 1.200
V_fixture_min = 1.140
V_fixture_max = 1.260
|  time   V(typ)   V(min)   V(max)
0s        1.2V       1.14V      1.26V
834ps     1.2V       1.144V     1.26V
1.493ns   1.175V     1.127V     1.259V
2.303ns   1.121V     1.083V     1.244V
3.43ns    1.042V     1.013V     1.205V
4.59ns    998mV      963.7mV    1.157V
5.708ns   983.7mV    940.7mV    1.11V
7.125ns   978.3mV    929.1mV    1.064V
8.487ns   976.6mV    925.1mV    1.043V
10ns      975.9mV    923.4mV    1.036V
[Falling Waveform]
R_fixture = 50.000
V_fixture = 0.000
V_fixture_min = 0.000
V_fixture_max = 0.000
|  time   V(typ)   V(min)   V(max)
0s        251.2mV    241.5mV    253.5mV
356ps     250.7mV    241.2mV    266.4mV
454ps     264.3mV    241.4mV    173.4mV
563ps     172.5mV    243.2mV    125.8mV
663ps     125.3mV    255mV      100.5mV
843ps     82.8mV     141.9mV    72.45mV
973ps     64.39mV    98.32mV    59.61mV
1.633ns   26.07mV    31.11mV    28.91mV
3.31ns    10.29mV    10.9mV     10.61mV
10ns      6.015mV    5.985mV    6.29mV
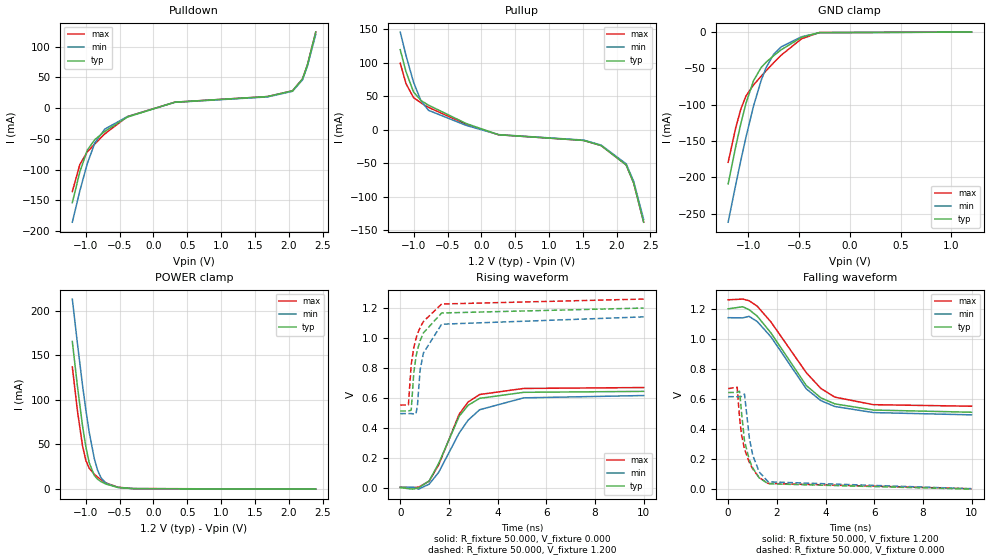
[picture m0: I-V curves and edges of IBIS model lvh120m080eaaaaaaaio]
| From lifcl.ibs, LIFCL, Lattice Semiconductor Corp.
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[Model] lvh120m080eaaaaaaaio
Model_type I/O
Polarity   Non-Inverting
Enable   Active-Low
Vinl =  0.420V
Vinh =  0.780V
Vmeas =  0.600V
Cref =  0.0F
Rref =  1.000M
Vref =  0.0V
C_comp   5.000pF   4.000pF   5.500pF
[Temperature Range]   25.000   0.125k   -40.000
[Voltage Range]   1.200V   1.140V   1.260V
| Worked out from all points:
|   slope of the pulldown table from 0 to 0.18 V, typ, clamps not added: 30.5 ohm
|   slope of the pullup table from 0 to 0.18 V, typ, clamps not added: 30.7 ohm
|   GND clamp passes 1 mA (typ) near -0.32 V on its own axis
|   POWER clamp passes 1 mA (typ) near -0.45 V on its own axis
|   rising waveform, R_fixture 50.000, V_fixture 0.000: 20-80 % time 1.1ns typ, 1.38ns min, 1.06ns max; typ from 0 V to 0.643 V
|   rising waveform, R_fixture 50.000, V_fixture 1.200: 20-80 % time 536ps typ, 505ps min, 594ps max; typ from 0.512 V to 1.2 V
|   falling waveform, R_fixture 50.000, V_fixture 1.200: 20-80 % time 1.8ns typ, 1.73ns min, 1.92ns max; typ from 1.2 V to 0.512 V
|   falling waveform, R_fixture 50.000, V_fixture 0.000: 20-80 % time 502ps typ, 464ps min, 560ps max; typ from 0.643 V to 0 V
[GND_clamp]
|Voltage   I(typ)   I(min)   I(max)
-1.2V     -208.9mA   -261.7mA   -179.3mA
-1.125V   -157.4mA   -209.8mA   -131.5mA
-1.075V   -126mA     -176.6mA   -106.1mA
-1.025V   -98.42mA   -145mA     -88.28mA
-950mV    -66.96mA   -101.9mA   -72.76mA
-875mV    -48.78mA   -66.64mA   -60.78mA
-825mV    -41.38mA   -48.67mA   -53.1mA
-750mV    -32.3mA    -30.34mA   -41.99mA
-675mV    -24.14mA   -20.11mA   -31.53mA
-475mV    -7.155mA   -6.375mA   -9.116mA
-300mV    -673.7uA   -900.4uA   -619.4uA
1.2V      0A         0A         0A
[POWER_clamp]
|Voltage   I(typ)   I(min)   I(max)
-1.2V     165.7mA    213.3mA    137.1mA
-1.125V   115.8mA    163.7mA    88.19mA
-1.05V    71.42mA    117.1mA    48.87mA
-1V       47.37mA    88.79mA    32.13mA
-950mV    29.54mA    63.68mA    23.24mA
-875mV    15.17mA    34.1mA     16.62mA
-825mV    10.91mA    20.81mA    13.34mA
-775mV    8.283mA    12.48mA    10.42mA
-700mV    5.463mA    6.247mA    6.777mA
-525mV    1.711mA    1.811mA    1.978mA
-300mV    395.7uA    364.9uA    500.6uA
2.4V      -178.9uA   -186.1uA   -181.3uA
[Pulldown]
|Voltage   I(typ)   I(min)   I(max)
-1.2V     -153.9mA   -185.6mA   -135.8mA
-1.089V   -103.8mA   -134.7mA   -91.7mA
-978mV    -68.12mA   -90mA      -71.13mA
-867mV    -51.18mA   -56.52mA   -58.14mA
-719mV    -37.72mA   -33.97mA   -41.78mA
-386mV    -14.55mA   -13.79mA   -13.75mA
317mV     9.765mA    9.472mA    9.765mA
1.686V    18.86mA    18.29mA    18.86mA
2.056V    28.26mA    27.41mA    28.26mA
2.204V    47.45mA    46.03mA    47.45mA
2.278V    70.9mA     68.8mA     70.9mA
2.4V      123.8mA    120.1mA    123.8mA
[Pullup]
|Voltage   I(typ)   I(min)   I(max)
-1.2V     119.2mA    145.5mA    99mA
-1.115V   86.4mA     110.6mA    68.6mA
-1.004V   56.25mA    70.9mA     47.76mA
-893mV    43.25mA    42.77mA    39.77mA
-782mV    36.41mA    28.69mA    33.08mA
-227mV    9.091mA    6.284mA    7.947mA
254mV     -7.789mA   -7.556mA   -7.789mA
1.512V    -16.22mA   -15.73mA   -16.22mA
1.771V    -23.91mA   -23.2mA    -23.91mA
2.141V    -52.78mA   -51.2mA    -52.78mA
2.252V    -79.7mA    -77.3mA    -79.7mA
2.4V      -138.3mA   -134.2mA   -138.3mA
[Ramp]
| variable   typ   min   max
dV/dt_r   0.388/1.117n   0.383/1.394n   0.399/1.083n
dV/dt_f   0.410/1.839n   0.388/1.780n   0.425/1.960n
R_load = 50.000
[Rising Waveform]
R_fixture = 50.000
V_fixture = 0.000
V_fixture_min = 0.000
V_fixture_max = 0.000
|  time   V(typ)   V(min)   V(max)
0s        38.48uV    3.07mV     3.068mV
517ps     -10.18mV   3.445mV    -297.1uV
757ps     -781.2uV   -9.905mV   3.294mV
1.187ns   44.7mV     23.19mV    43.29mV
1.576ns   161mV      101.3mV    151.3mV
2.425ns   477.9mV    366.1mV    491.6mV
2.791ns   550.5mV    451.3mV    572.3mV
3.26ns    596.5mV    520.4mV    622.2mV
5.07ns    636.9mV    599.9mV    662.8mV
10ns      643.2mV    615.5mV    668.8mV
[Rising Waveform]
R_fixture = 50.000
V_fixture = 1.200
V_fixture_min = 1.140
V_fixture_max = 1.260
|  time   V(typ)   V(min)   V(max)
0s        511.9mV    494.5mV    551.9mV
336ps     512.2mV    494.6mV    552.6mV
450ps     517.5mV    494.8mV    822.1mV
557ps     767.1mV    492.8mV    936.1mV
647ps     875.8mV    493.9mV    996mV
707ps     921.4mV    549.7mV    1.027V
817ps     981.7mV    786.9mV    1.07V
952ps     1.034V     899mV      1.11V
1.701ns   1.167V     1.092V     1.227V
10ns      1.2V       1.141V     1.26V
[Falling Waveform]
R_fixture = 50.000
V_fixture = 1.200
V_fixture_min = 1.140
V_fixture_max = 1.260
|  time   V(typ)   V(min)   V(max)
0s        1.2V       1.141V     1.26V
601ps     1.214V     1.14V      1.265V
861ps     1.194V     1.15V      1.254V
1.197ns   1.151V     1.115V     1.217V
1.761ns   1.039V     1.013V     1.112V
3.211ns   689.1mV    667.3mV    774.9mV
3.811ns   607.3mV    589mV      669.9mV
4.381ns   567.7mV    550.3mV    612.5mV
5.965ns   526.6mV    509.7mV    562.3mV
10ns      511.9mV    494.5mV    551.9mV
[Falling Waveform]
R_fixture = 50.000
V_fixture = 0.000
V_fixture_min = 0.000
V_fixture_max = 0.000
|  time   V(typ)   V(min)   V(max)
0s        643.2mV    615.5mV    668.8mV
370ps     643.8mV    615.2mV    678.8mV
468ps     651.9mV    615.2mV    477.7mV
548ps     513.4mV    616.7mV    362.6mV
670ps     321.6mV    633.5mV    267mV
871ps     194.4mV    339.7mV    176.8mV
1.011ns   140.9mV    225.3mV    134.2mV
1.277ns   74.91mV    114.3mV    76.61mV
1.647ns   35.83mV    48.79mV    38.23mV
10ns      38.48uV    3.07mV     3.068mV
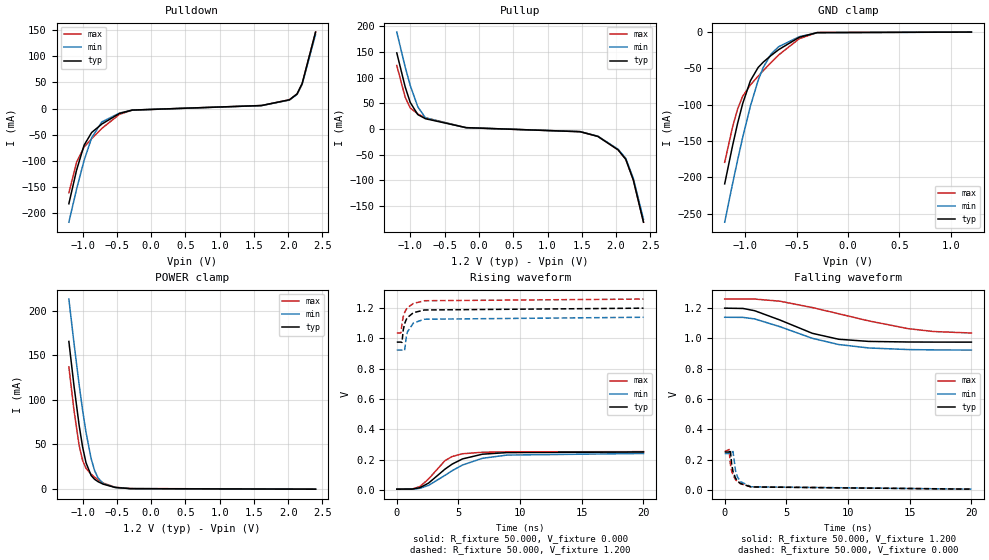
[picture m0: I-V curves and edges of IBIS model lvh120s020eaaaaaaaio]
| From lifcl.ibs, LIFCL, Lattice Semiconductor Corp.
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[Model] lvh120s020eaaaaaaaio
Model_type I/O
Polarity   Non-Inverting
Enable   Active-Low
Vinl =  0.420V
Vinh =  0.780V
Vmeas =  0.600V
Cref =  0.0F
Rref =  1.000M
Vref =  0.0V
C_comp   5.000pF   4.000pF   5.500pF
[Temperature Range]   25.000   0.125k   -40.000
[Voltage Range]   1.200V   1.140V   1.260V
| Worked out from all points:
|   slope of the pulldown table from 0 to 0.18 V, typ, clamps not added: 108 ohm
|   slope of the pullup table from 0 to 0.18 V, typ, clamps not added: 92.2 ohm
|   GND clamp passes 1 mA (typ) near -0.32 V on its own axis
|   POWER clamp passes 1 mA (typ) near -0.45 V on its own axis
|   rising waveform, R_fixture 50.000, V_fixture 0.000: 20-80 % time 2.51ns typ, 3.16ns min, 1.7ns max; typ from 0.006 V to 0.251 V
|   rising waveform, R_fixture 50.000, V_fixture 1.200: 20-80 % time 571ps typ, 548ps min, 611ps max; typ from 0.976 V to 1.2 V
|   falling waveform, R_fixture 50.000, V_fixture 1.200: 20-80 % time 4.2ns typ, 4.96ns min, 7.24ns max; typ from 1.2 V to 0.976 V
|   falling waveform, R_fixture 50.000, V_fixture 0.000: 20-80 % time 571ps typ, 549ps min, 610ps max; typ from 0.251 V to 0.006 V
[GND_clamp]
|Voltage   I(typ)   I(min)   I(max)
-1.2V     -208.9mA   -261.7mA   -179.3mA
-1.125V   -157.4mA   -209.8mA   -131.5mA
-1.075V   -126mA     -176.6mA   -106.1mA
-1.025V   -98.42mA   -145mA     -88.28mA
-950mV    -66.96mA   -101.9mA   -72.76mA
-875mV    -48.78mA   -66.64mA   -60.78mA
-825mV    -41.38mA   -48.67mA   -53.1mA
-750mV    -32.3mA    -30.34mA   -41.99mA
-675mV    -24.14mA   -20.11mA   -31.53mA
-475mV    -7.155mA   -6.375mA   -9.116mA
-300mV    -673.7uA   -900.4uA   -619.4uA
1.2V      0A         0A         0A
[POWER_clamp]
|Voltage   I(typ)   I(min)   I(max)
-1.2V     165.7mA    213.3mA    137.1mA
-1.125V   115.8mA    163.7mA    88.19mA
-1.05V    71.42mA    117.1mA    48.87mA
-1V       47.37mA    88.79mA    32.13mA
-950mV    29.54mA    63.68mA    23.24mA
-875mV    15.17mA    34.1mA     16.62mA
-825mV    10.91mA    20.81mA    13.34mA
-775mV    8.283mA    12.48mA    10.42mA
-700mV    5.463mA    6.247mA    6.777mA
-525mV    1.711mA    1.811mA    1.978mA
-300mV    395.7uA    364.9uA    500.6uA
2.4V      -178.9uA   -186.1uA   -181.3uA
[Pulldown]
|Voltage   I(typ)   I(min)   I(max)
-1.2V     -182.9mA   -218.3mA   -161.8mA
-1.089V   -119mA     -155.7mA   -103.5mA
-978mV    -70.5mA    -99.7mA    -73.97mA
-867mV    -45.98mA   -56.14mA   -57.88mA
-719mV    -29.83mA   -25.74mA   -38.17mA
-460mV    -9.387mA   -8.653mA   -11.09mA
-275mV    -2.976mA   -3.061mA   -3.072mA
1.612V    5.767mA    5.594mA    5.767mA
2.019V    16.81mA    16.3mA     16.81mA
2.13V     28.06mA    27.22mA    28.06mA
2.204V    47.87mA    46.44mA    47.87mA
2.4V      146.8mA    142.4mA    146.8mA
[Pullup]
|Voltage   I(typ)   I(min)   I(max)
-1.2V     147.9mA    188.3mA    123.4mA
-1.078V   81.98mA    120.7mA    61.86mA
-1.004V   51.59mA    84.61mA    40.82mA
-893mV    27.85mA    43mA       29.06mA
-782mV    19.86mA    21.61mA    21.61mA
-190mV    2.572mA    2.372mA    2.456mA
1.475V    -5.352mA   -5.192mA   -5.352mA
1.734V    -14.51mA   -14.08mA   -14.51mA
2.03V     -40.75mA   -39.53mA   -40.75mA
2.141V    -58.9mA    -57.14mA   -58.9mA
2.252V    -99.4mA    -96.4mA    -99.4mA
2.4V      -181.3mA   -175.9mA   -181.3mA
[Ramp]
| variable   typ   min   max
dV/dt_r   0.147/2.498n   0.141/3.174n   0.148/1.768n
dV/dt_f   0.134/4.209n   0.130/4.974n   0.135/7.255n
R_load = 50.000
[Rising Waveform]
R_fixture = 50.000
V_fixture = 0.000
V_fixture_min = 0.000
V_fixture_max = 0.000
|  time   V(typ)   V(min)   V(max)
0s        6.015mV    5.985mV    6.29mV
1.275ns   6.764mV    6.253mV    7.748mV
1.87ns    15.55mV    11.63mV    23.03mV
2.578ns   46.21mV    31.06mV    73.47mV
3.911ns   138.3mV    97.3mV     194.5mV
4.49ns    171.3mV    127.9mV    221.4mV
5.33ns    205.6mV    165.5mV    239.6mV
6.945ns   236.7mV    209.6mV    249.6mV
8.925ns   247.2mV    230.8mV    252mV
20ns      251.2mV    241.5mV    253.5mV
[Rising Waveform]
R_fixture = 50.000
V_fixture = 1.200
V_fixture_min = 1.140
V_fixture_max = 1.260
|  time   V(typ)   V(min)   V(max)
0s        975.9mV    923.5mV    1.036V
335ps     976.2mV    923.6mV    1.036V
421ps     974mV      923.6mV    1.095V
522ps     1.055V     923.3mV    1.143V
635ps     1.098V     921mV      1.171V
774ps     1.126V     1.012V     1.193V
866ps     1.138V     1.044V     1.203V
1.345ns   1.17V      1.102V     1.231V
2.236ns   1.188V     1.127V     1.249V
20ns      1.2V       1.14V      1.26V
[Falling Waveform]
R_fixture = 50.000
V_fixture = 1.200
V_fixture_min = 1.140
V_fixture_max = 1.260
|  time   V(typ)   V(min)   V(max)
0s        1.2V       1.14V      1.26V
1.493ns   1.198V     1.139V     1.26V
2.434ns   1.183V     1.129V     1.26V
4.47ns    1.122V     1.078V     1.246V
7.107ns   1.034V     1.001V     1.204V
9.239ns   994.9mV    960.1mV    1.163V
11.68ns   980.6mV    937.4mV    1.116V
14.86ns   976.8mV    926.9mV    1.065V
16.91ns   976.2mV    924.7mV    1.046V
20ns      975.9mV    923.5mV    1.036V
[Falling Waveform]
R_fixture = 50.000
V_fixture = 0.000
V_fixture_min = 0.000
V_fixture_max = 0.000
|  time   V(typ)   V(min)   V(max)
0s        251.2mV    241.5mV    253.5mV
356ps     250.7mV    241.2mV    267.8mV
454ps     265.7mV    241.4mV    174.5mV
562ps     174.4mV    243.1mV    126.7mV
673ps     122.7mV    254.5mV    98.99mV
874ps     79.14mV    129.4mV    69.38mV
1.043ns   59.62mV    85.45mV    54.62mV
1.273ns   43.74mV    56.43mV    41.8mV
2.123ns   20.56mV    21.88mV    21.29mV
20ns      6.015mV    5.985mV    6.29mV
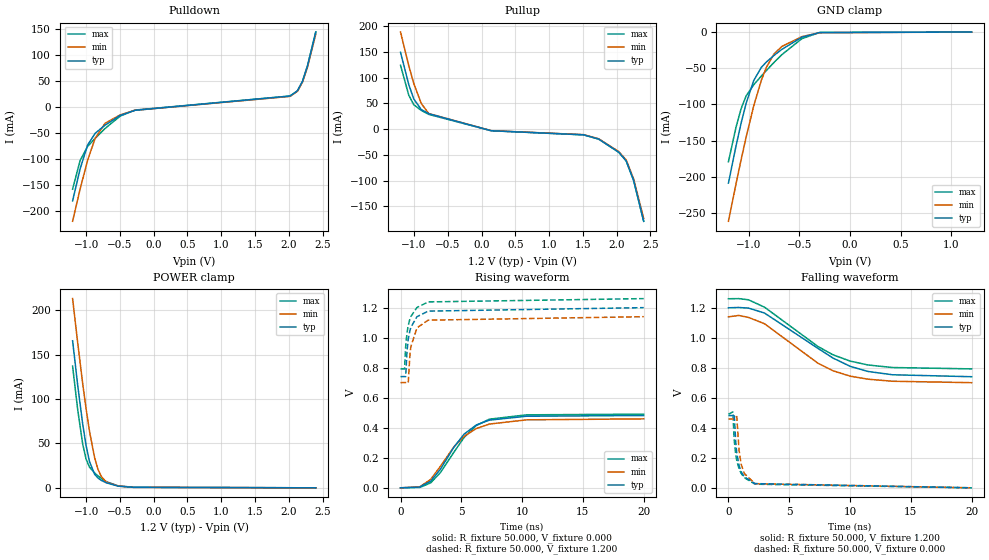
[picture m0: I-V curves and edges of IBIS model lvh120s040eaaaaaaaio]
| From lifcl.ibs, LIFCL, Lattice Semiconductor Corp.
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[Model] lvh120s040eaaaaaaaio
Model_type I/O
Polarity   Non-Inverting
Enable   Active-Low
Vinl =  0.420V
Vinh =  0.780V
Vmeas =  0.600V
Cref =  0.0F
Rref =  1.000M
Vref =  0.0V
C_comp   5.000pF   4.000pF   5.500pF
[Temperature Range]   25.000   0.125k   -40.000
[Voltage Range]   1.200V   1.140V   1.260V
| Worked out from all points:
|   slope of the pulldown table from 0 to 0.18 V, typ, clamps not added: 51.8 ohm
|   slope of the pullup table from 0 to 0.18 V, typ, clamps not added: 44.9 ohm
|   GND clamp passes 1 mA (typ) near -0.32 V on its own axis
|   POWER clamp passes 1 mA (typ) near -0.45 V on its own axis
|   rising waveform, R_fixture 50.000, V_fixture 0.000: 20-80 % time 2.56ns typ, 2.79ns min, 2.63ns max; typ from 0.004 V to 0.484 V
|   rising waveform, R_fixture 50.000, V_fixture 1.200: 20-80 % time 569ps typ, 544ps min, 614ps max; typ from 0.742 V to 1.2 V
|   falling waveform, R_fixture 50.000, V_fixture 1.200: 20-80 % time 5.14ns typ, 4.61ns min, 4.94ns max; typ from 1.2 V to 0.742 V
|   falling waveform, R_fixture 50.000, V_fixture 0.000: 20-80 % time 563ps typ, 547ps min, 607ps max; typ from 0.484 V to 0.004 V
[GND_clamp]
|Voltage   I(typ)   I(min)   I(max)
-1.2V     -208.9mA   -261.7mA   -179.3mA
-1.125V   -157.4mA   -209.8mA   -131.5mA
-1.075V   -126mA     -176.6mA   -106.1mA
-1.025V   -98.42mA   -145mA     -88.28mA
-950mV    -66.96mA   -101.9mA   -72.76mA
-875mV    -48.78mA   -66.64mA   -60.78mA
-825mV    -41.38mA   -48.67mA   -53.1mA
-750mV    -32.3mA    -30.34mA   -41.99mA
-675mV    -24.14mA   -20.11mA   -31.53mA
-475mV    -7.155mA   -6.375mA   -9.116mA
-300mV    -673.7uA   -900.4uA   -619.4uA
1.2V      0A         0A         0A
[POWER_clamp]
|Voltage   I(typ)   I(min)   I(max)
-1.2V     165.7mA    213.3mA    137.1mA
-1.125V   115.8mA    163.7mA    88.19mA
-1.05V    71.42mA    117.1mA    48.87mA
-1V       47.37mA    88.79mA    32.13mA
-950mV    29.54mA    63.68mA    23.24mA
-875mV    15.17mA    34.1mA     16.62mA
-825mV    10.91mA    20.81mA    13.34mA
-775mV    8.283mA    12.48mA    10.42mA
-700mV    5.463mA    6.247mA    6.777mA
-525mV    1.711mA    1.811mA    1.978mA
-300mV    395.7uA    364.9uA    500.6uA
2.4V      -178.9uA   -186.1uA   -181.3uA
[Pulldown]
|Voltage   I(typ)   I(min)   I(max)
-1.2V     -180.2mA   -219.5mA   -157.6mA
-1.089V   -118.7mA   -157.5mA   -102.6mA
-978mV    -72.85mA   -102.3mA   -75.46mA
-867mV    -50.28mA   -60.01mA   -59.99mA
-719mV    -34.47mA   -30.88mA   -40.86mA
-497mV    -15.93mA   -14.83mA   -17.14mA
-275mV    -5.882mA   -5.85mA    -5.411mA
2.019V    21.52mA    20.87mA    21.52mA
2.13V     31.72mA    30.77mA    31.72mA
2.204V    49.93mA    48.43mA    49.93mA
2.278V    79.85mA    77.46mA    79.85mA
2.4V      144.7mA    140.4mA    144.7mA
[Pullup]
|Voltage   I(typ)   I(min)   I(max)
-1.2V     149.1mA    188.4mA    123.9mA
-1.078V   86.3mA     123.1mA    65.77mA
-1.004V   58.53mA    88.6mA     47.2mA
-893mV    37.85mA    49.68mA    36.25mA
-782mV    29.77mA    30.11mA    28.48mA
143mV     -3.278mA   -3.179mA   -3.278mA
1.512V    -11.23mA   -10.89mA   -11.23mA
1.734V    -19.5mA    -18.92mA   -19.5mA
2.03V     -44.92mA   -43.58mA   -44.92mA
2.141V    -61.82mA   -59.96mA   -61.82mA
2.252V    -100mA     -97mA      -100mA
2.4V      -179.1mA   -173.7mA   -179.1mA
[Ramp]
| variable   typ   min   max
dV/dt_r   0.288/2.573n   0.275/2.778n   0.301/2.658n
dV/dt_f   0.275/5.201n   0.262/4.617n   0.280/4.965n
R_load = 50.000
[Rising Waveform]
R_fixture = 50.000
V_fixture = 0.000
V_fixture_min = 0.000
V_fixture_max = 0.000
|  time   V(typ)   V(min)   V(max)
0s        4.45mV     4.4mV      4.331mV
1.585ns   9.495mV    11.23mV    7.008mV
2.478ns   48.39mV    59.93mV    37.2mV
3.275ns   127.2mV    146.5mV    105.2mV
4.391ns   274.2mV    276.4mV    240.9mV
5.23ns    360.8mV    346.6mV    338.8mV
6.234ns   421.6mV    397.9mV    418mV
7.305ns   453.6mV    427.5mV    459.8mV
10.37ns   479.5mV    455.5mV    488.8mV
20ns      484.3mV    462.1mV    493.1mV
[Rising Waveform]
R_fixture = 50.000
V_fixture = 1.200
V_fixture_min = 1.140
V_fixture_max = 1.260
|  time   V(typ)   V(min)   V(max)
0s        742.2mV    702.7mV    794.3mV
333ps     742.6mV    702.8mV    793.1mV
423ps     742.2mV    702.9mV    942.5mV
534ps     911.6mV    701.7mV    1.034V
635ps     990.5mV    701.2mV    1.082V
765ps     1.045V     878.1mV    1.123V
847ps     1.069V     940.7mV    1.141V
1.354ns   1.14V      1.066V     1.201V
2.273ns   1.177V     1.117V     1.238V
20ns      1.2V       1.14V      1.26V
[Falling Waveform]
R_fixture = 50.000
V_fixture = 1.200
V_fixture_min = 1.140
V_fixture_max = 1.260
|  time   V(typ)   V(min)   V(max)
0s        1.2V       1.14V      1.26V
843ps     1.202V     1.149V     1.261V
1.653ns   1.198V     1.136V     1.253V
2.969ns   1.165V     1.094V     1.204V
7.353ns   931.1mV    832.4mV    943.5mV
8.594ns   866.5mV    781.9mV    887.9mV
10.01ns   811.2mV    746.2mV    846.1mV
11.47ns   777.3mV    725.9mV    820.3mV
13.5ns    755.2mV    712.2mV    803.3mV
20ns      742.2mV    702.7mV    794.3mV
[Falling Waveform]
R_fixture = 50.000
V_fixture = 0.000
V_fixture_min = 0.000
V_fixture_max = 0.000
|  time   V(typ)   V(min)   V(max)
0s        484.3mV    462.1mV    493.1mV
362ps     484.5mV    461.8mV    508.6mV
473ps     496mV      461.7mV    323.9mV
603ps     306.6mV    472.5mV    223.1mV
683ps     236mV      478mV      186.4mV
874ps     151.9mV    253.6mV    130.4mV
1.033ns   113.9mV    165.6mV    102.1mV
1.294ns   77.99mV    100.7mV    72.76mV
2.183ns   32.38mV    32.04mV    28.51mV
20ns      4.45mV     4.4mV      4.331mV
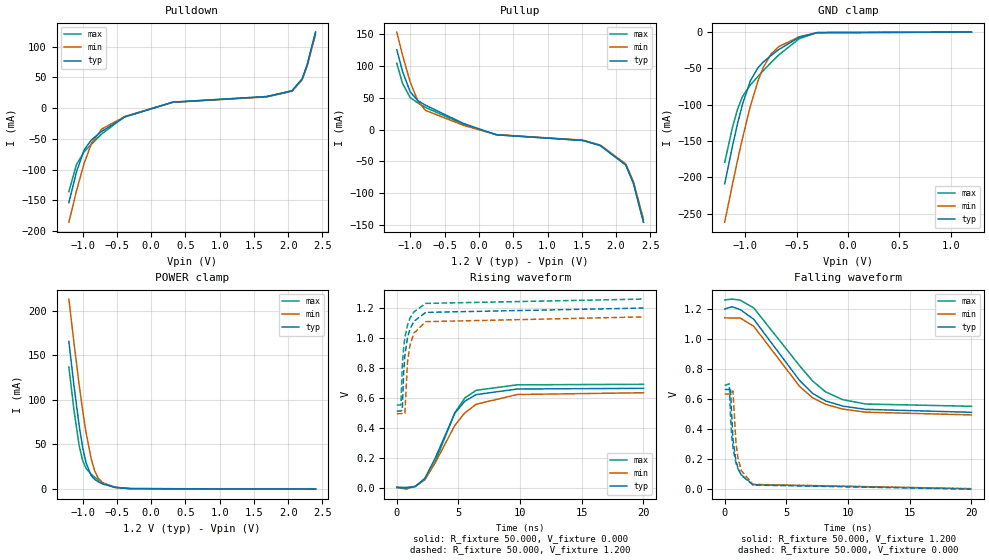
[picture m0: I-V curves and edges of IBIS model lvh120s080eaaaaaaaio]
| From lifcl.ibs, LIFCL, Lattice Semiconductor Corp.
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[Model] lvh120s080eaaaaaaaio
Model_type I/O
Polarity   Non-Inverting
Enable   Active-Low
Vinl =  0.420V
Vinh =  0.780V
Vmeas =  0.600V
Cref =  0.0F
Rref =  1.000M
Vref =  0.0V
C_comp   5.000pF   4.000pF   5.500pF
[Temperature Range]   25.000   0.125k   -40.000
[Voltage Range]   1.200V   1.140V   1.260V
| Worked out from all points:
|   slope of the pulldown table from 0 to 0.18 V, typ, clamps not added: 30.5 ohm
|   slope of the pullup table from 0 to 0.18 V, typ, clamps not added: 29.3 ohm
|   GND clamp passes 1 mA (typ) near -0.32 V on its own axis
|   POWER clamp passes 1 mA (typ) near -0.45 V on its own axis
|   rising waveform, R_fixture 50.000, V_fixture 0.000: 20-80 % time 2.22ns typ, 2.74ns min, 2.13ns max; typ from 0 V to 0.664 V
|   rising waveform, R_fixture 50.000, V_fixture 1.200: 20-80 % time 569ps typ, 542ps min, 612ps max; typ from 0.512 V to 1.2 V
|   falling waveform, R_fixture 50.000, V_fixture 1.200: 20-80 % time 3.85ns typ, 3.69ns min, 4.12ns max; typ from 1.2 V to 0.512 V
|   falling waveform, R_fixture 50.000, V_fixture 0.000: 20-80 % time 561ps typ, 546ps min, 604ps max; typ from 0.664 V to 0 V
[GND_clamp]
|Voltage   I(typ)   I(min)   I(max)
-1.2V     -208.9mA   -261.7mA   -179.3mA
-1.125V   -157.4mA   -209.8mA   -131.5mA
-1.075V   -126mA     -176.6mA   -106.1mA
-1.025V   -98.42mA   -145mA     -88.28mA
-950mV    -66.96mA   -101.9mA   -72.76mA
-875mV    -48.78mA   -66.64mA   -60.78mA
-825mV    -41.38mA   -48.67mA   -53.1mA
-750mV    -32.3mA    -30.34mA   -41.99mA
-675mV    -24.14mA   -20.11mA   -31.53mA
-475mV    -7.155mA   -6.375mA   -9.116mA
-300mV    -673.7uA   -900.4uA   -619.4uA
1.2V      0A         0A         0A
[POWER_clamp]
|Voltage   I(typ)   I(min)   I(max)
-1.2V     165.7mA    213.3mA    137.1mA
-1.125V   115.8mA    163.7mA    88.19mA
-1.05V    71.42mA    117.1mA    48.87mA
-1V       47.37mA    88.79mA    32.13mA
-950mV    29.54mA    63.68mA    23.24mA
-875mV    15.17mA    34.1mA     16.62mA
-825mV    10.91mA    20.81mA    13.34mA
-775mV    8.283mA    12.48mA    10.42mA
-700mV    5.463mA    6.247mA    6.777mA
-525mV    1.711mA    1.811mA    1.978mA
-300mV    395.7uA    364.9uA    500.6uA
2.4V      -178.9uA   -186.1uA   -181.3uA
[Pulldown]
|Voltage   I(typ)   I(min)   I(max)
-1.2V     -153.9mA   -185.6mA   -135.8mA
-1.089V   -103.8mA   -134.7mA   -91.7mA
-978mV    -68.12mA   -90mA      -71.13mA
-867mV    -51.18mA   -56.52mA   -58.14mA
-719mV    -37.72mA   -33.97mA   -41.78mA
-386mV    -14.55mA   -13.79mA   -13.75mA
317mV     9.765mA    9.472mA    9.765mA
1.686V    18.86mA    18.29mA    18.86mA
2.056V    28.26mA    27.41mA    28.26mA
2.204V    47.45mA    46.03mA    47.45mA
2.278V    70.9mA     68.8mA     70.9mA
2.4V      123.8mA    120.1mA    123.8mA
[Pullup]
|Voltage   I(typ)   I(min)   I(max)
-1.2V     125.1mA    152.7mA    103.9mA
-1.115V   90.7mA     116.1mA    72mA
-1.004V   59.02mA    74.4mA     50.12mA
-893mV    45.38mA    44.88mA    41.74mA
-782mV    38.2mA     30.11mA    34.71mA
-227mV    9.539mA    6.593mA    8.339mA
254mV     -8.173mA   -7.928mA   -8.173mA
1.512V    -17.02mA   -16.51mA   -17.02mA
1.771V    -25.09mA   -24.34mA   -25.09mA
2.141V    -55.39mA   -53.73mA   -55.39mA
2.252V    -83.6mA    -81.1mA    -83.6mA
2.4V      -145.1mA   -140.7mA   -145.1mA
[Ramp]
| variable   typ   min   max
dV/dt_r   0.399/2.229n   0.384/2.743n   0.412/2.141n
dV/dt_f   0.410/3.886n   0.388/3.715n   0.425/4.132n
R_load = 50.000
[Rising Waveform]
R_fixture = 50.000
V_fixture = 0.000
V_fixture_min = 0.000
V_fixture_max = 0.000
|  time   V(typ)   V(min)   V(max)
0s        38.48uV    3.07mV     3.068mV
756ps     -2.344mV   -10.02mV   1.596mV
1.497ns   7.524mV    9.694mV    8.288mV
2.277ns   63.05mV    56.24mV    52.8mV
3.098ns   194.8mV    163.5mV    169.1mV
4.711ns   498.2mV    416.8mV    501.2mV
5.516ns   577.9mV    500.1mV    599.5mV
6.435ns   621.7mV    557.3mV    650.6mV
9.776ns   659.2mV    622.4mV    687.1mV
20ns      663.6mV    634.2mV    690.5mV
[Rising Waveform]
R_fixture = 50.000
V_fixture = 1.200
V_fixture_min = 1.140
V_fixture_max = 1.260
|  time   V(typ)   V(min)   V(max)
0s        511.9mV    494.5mV    551.9mV
336ps     512.2mV    494.6mV    552.5mV
449ps     516.9mV    494.8mV    820.6mV
557ps     767.3mV    492.8mV    936.1mV
657ps     884.7mV    497.4mV    1.002V
867ps     1.002V     839.4mV    1.085V
1.069ns   1.06V      951.7mV    1.132V
1.387ns   1.111V     1.032V     1.174V
2.346ns   1.171V     1.109V     1.231V
20ns      1.2V       1.141V     1.26V
[Falling Waveform]
R_fixture = 50.000
V_fixture = 1.200
V_fixture_min = 1.140
V_fixture_max = 1.260
|  time   V(typ)   V(min)   V(max)
0s        1.2V       1.141V     1.26V
592ps     1.215V     1.14V      1.266V
1.252ns   1.196V     1.14V      1.259V
2.351ns   1.132V     1.085V     1.207V
6.09ns    721.9mV    682.6mV    820.2mV
7.133ns   637.3mV    608mV      719.9mV
8.186ns   587.5mV    564.6mV    647.8mV
9.562ns   553.4mV    533.5mV    596.1mV
11.44ns   531.5mV    512.7mV    567.1mV
20ns      511.9mV    494.5mV    551.9mV
[Falling Waveform]
R_fixture = 50.000
V_fixture = 0.000
V_fixture_min = 0.000
V_fixture_max = 0.000
|  time   V(typ)   V(min)   V(max)
0s        663.6mV    634.2mV    690.5mV
370ps     664.1mV    633.9mV    701.6mV
467ps     674.3mV    633.9mV    496.5mV
550ps     526.7mV    635.7mV    372.9mV
670ps     332.8mV    654.3mV    276.2mV
911ps     188.9mV    310.3mV    173.9mV
1.08ns    139.3mV    204.9mV    134.2mV
1.351ns   92.77mV    123mV      94.68mV
2.297ns   27.41mV    31.9mV     30.5mV
20ns      38.48uV    3.07mV     3.068mV
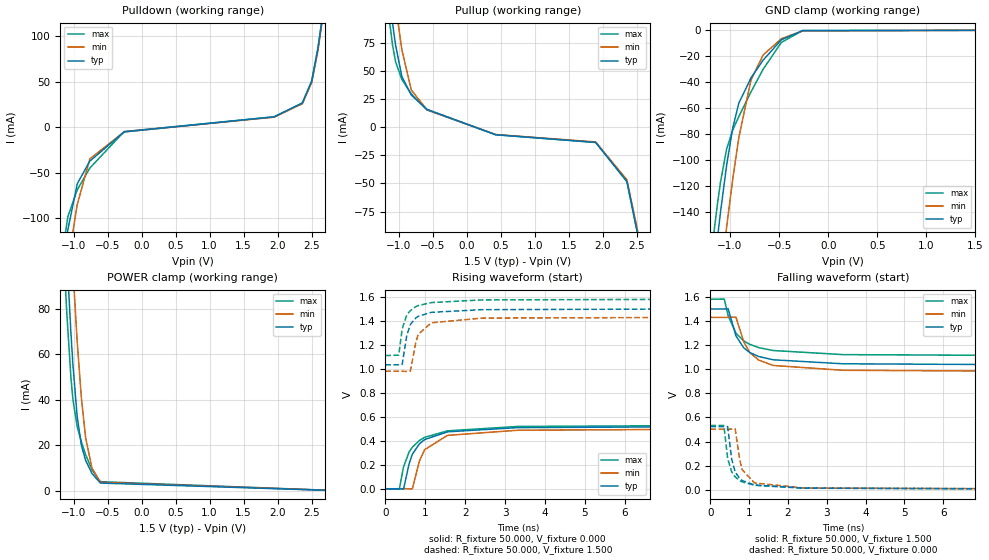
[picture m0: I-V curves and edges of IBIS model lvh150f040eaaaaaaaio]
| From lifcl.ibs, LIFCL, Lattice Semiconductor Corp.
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[Model] lvh150f040eaaaaaaaio
Model_type I/O
Polarity   Non-Inverting
Enable   Active-Low
Vinl =  0.375V
Vinh =  1.125V
Vmeas =  0.750V
Cref =  0.0F
Rref =  1.000M
Vref =  0.0V
C_comp   5.000pF   4.000pF   5.500pF
[Temperature Range]   25.000   0.125k   -40.000
[Voltage Range]   1.500V   1.430V   1.580V
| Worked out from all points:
|   slope of the pulldown table from 0 to 0.225 V, typ, clamps not added: 54.8 ohm
|   slope of the pullup table from 0 to 0.225 V, typ, clamps not added: 56 ohm
|   GND clamp passes 1 mA (typ) near -0.32 V on its own axis
|   POWER clamp passes 1 mA (typ) near -0.45 V on its own axis
|   rising waveform, R_fixture 50.000, V_fixture 0.000: 20-80 % time 484ps typ, 460ps min, 544ps max; typ from 0.005 V to 0.524 V
|   rising waveform, R_fixture 50.000, V_fixture 1.500: 20-80 % time 234ps typ, 238ps min, 259ps max; typ from 1.03 V to 1.5 V
|   falling waveform, R_fixture 50.000, V_fixture 1.500: 20-80 % time 536ps typ, 520ps min, 594ps max; typ from 1.5 V to 1.03 V
|   falling waveform, R_fixture 50.000, V_fixture 0.000: 20-80 % time 220ps typ, 226ps min, 243ps max; typ from 0.524 V to 0.005 V
[GND_clamp]
|Voltage   I(typ)   I(min)   I(max)
-1.5V     -437mA     -482.5mA   -410.7mA
-1.159V   -180.3mA   -233.3mA   -152.2mA
-1.128V   -159.5mA   -212mA     -133.3mA
-1.097V   -139.6mA   -191.2mA   -116.5mA
-1.035V   -103.7mA   -151.3mA   -91.23mA
-973mV    -75.24mA   -114.6mA   -76.75mA
-911mV    -56.05mA   -82.58mA   -66.41mA
-787mV    -36.61mA   -38.2mA    -47.39mA
-663mV    -22.9mA    -18.92mA   -29.92mA
-477mV    -7.274mA   -6.461mA   -9.278mA
-260mV    -227.6uA   -429.8uA   -148.6uA
1.5V      0A         0A         0A
[POWER_clamp]
|Voltage   I(typ)   I(min)   I(max)
-1.5V     391.3mA    429.6mA    369.7mA
-1.166V   144.6mA    192.2mA    117.1mA
-1.135V   124.2mA    171.8mA    97.3mA
-1.104V   104.7mA    152mA      79.15mA
-1.042V   69.75mA    114.3mA    49.91mA
-1.011V   54.95mA    96.78mA    39.84mA
-949mV    32.47mA    65.46mA    28.02mA
-887mV    19.82mA    40.53mA    21.37mA
-825mV    13.31mA    23.23mA    15.79mA
-732mV    7.53mA     9.888mA    9.145mA
-608mV    3.278mA    3.592mA    3.895mA
3V        -183uA     -190.7uA   -185.3uA
[Pulldown]
|Voltage   I(typ)   I(min)   I(max)
-1.5V     -358.2mA   -381.8mA   -344.9mA
-1.224V   -187.6mA   -222.6mA   -167mA
-1.086V   -112.9mA   -148.8mA   -98.5mA
-948mV    -62.28mA   -85.2mA    -69.02mA
-764mV    -37.5mA    -35.09mA   -45.15mA
-258mV    -5.249mA   -5.157mA   -4.87mA
1.95V     11.37mA    11.03mA    11.37mA
2.364V    26.55mA    25.75mA    26.55mA
2.502V    50.62mA    49.1mA     50.62mA
2.594V    86.8mA     84.2mA     86.8mA
2.732V    159.4mA    154.6mA    159.4mA
3V        321.9mA    312.2mA    321.9mA
[Pullup]
|Voltage   I(typ)   I(min)   I(max)
-1.5V     334.2mA    366.8mA    315.2mA
-1.186V   140.5mA    179.9mA    117.2mA
-1.094V   92.7mA     130.5mA    73.11mA
-1.048V   72.68mA    107.9mA    57.95mA
-956mV    44.92mA    68.74mA    42.37mA
-818mV    28.55mA    33.04mA    29.55mA
-588mV    15.88mA    15.55mA    15.32mA
424mV     -6.746mA   -6.543mA   -6.746mA
1.896V    -13.58mA   -13.17mA   -13.58mA
2.356V    -48.31mA   -46.87mA   -48.31mA
2.586V    -116.3mA   -112.8mA   -116.3mA
3V        -369.7mA   -358.6mA   -369.7mA
[Ramp]
| variable   typ   min   max
dV/dt_r   0.311/0.493n   0.298/0.462n   0.332/0.551n
dV/dt_f   0.280/0.532n   0.270/0.520n   0.281/0.596n
R_load = 50.000
[Rising Waveform]
R_fixture = 50.000
V_fixture = 0.000
V_fixture_min = 0.000
V_fixture_max = 0.000
|  time   V(typ)   V(min)   V(max)
0s        4.663mV    5.072mV    4.538mV
351ps     4.928mV    5.131mV    1.564mV
457ps     1.861mV    5.116mV    186.6mV
597ps     213.2mV    4.537mV    310.5mV
677ps     290.3mV    3.722mV    350mV
856ps     378.3mV    236.3mV    406.4mV
988ps     413.9mV    329.8mV    432.3mV
1.557ns   477.6mV    448.1mV    485.7mV
3.321ns   512.7mV    490.9mV    522.3mV
10ns      523.5mV    502.5mV    532.4mV
[Rising Waveform]
R_fixture = 50.000
V_fixture = 1.500
V_fixture_min = 1.430
V_fixture_max = 1.580
|  time   V(typ)   V(min)   V(max)
0s        1.034V     980.4mV    1.111V
336ps     1.034V     980.5mV    1.114V
424ps     1.038V     980.5mV    1.333V
537ps     1.275V     979.1mV    1.446V
627ps     1.369V     981mV      1.484V
766ps     1.423V     1.223V     1.517V
827ps     1.437V     1.288V     1.526V
1.156ns   1.47V      1.383V     1.551V
2.427ns   1.492V     1.422V     1.573V
10ns      1.5V       1.43V      1.58V
[Falling Waveform]
R_fixture = 50.000
V_fixture = 1.500
V_fixture_min = 1.430
V_fixture_max = 1.580
|  time   V(typ)   V(min)   V(max)
0s        1.5V       1.43V      1.58V
356ps     1.5V       1.43V      1.582V
457ps     1.501V     1.43V      1.444V
657ps     1.277V     1.432V     1.299V
857ps     1.178V     1.229V     1.235V
1.01ns    1.139V     1.14V      1.207V
1.246ns   1.105V     1.075V     1.179V
1.619ns   1.078V     1.031V     1.155V
3.416ns   1.045V     991mV      1.121V
10ns      1.034V     980.4mV    1.111V
[Falling Waveform]
R_fixture = 50.000
V_fixture = 0.000
V_fixture_min = 0.000
V_fixture_max = 0.000
|  time   V(typ)   V(min)   V(max)
0s        523.5mV    502.5mV    532.4mV
346ps     523.2mV    502.2mV    533mV
444ps     523.6mV    502.4mV    258.8mV
547ps     255mV      503.4mV    149.5mV
637ps     147.4mV    505.3mV    106.6mV
757ps     92mV       246.5mV    75.11mV
817ps     76.38mV    165.7mV    65mV
1.137ns   38.39mV    56.36mV    37.09mV
2.407ns   13.61mV    14.08mV    12.57mV
10ns      4.663mV    5.072mV    4.538mV
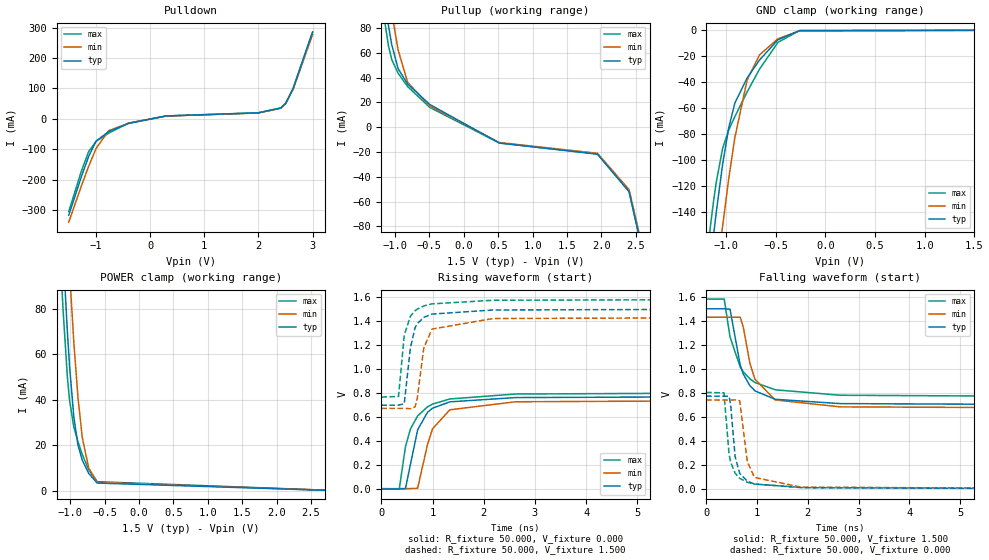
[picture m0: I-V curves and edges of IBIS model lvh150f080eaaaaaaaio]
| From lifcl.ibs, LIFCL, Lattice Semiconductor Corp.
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[Model] lvh150f080eaaaaaaaio
Model_type I/O
Polarity   Non-Inverting
Enable   Active-Low
Vinl =  0.375V
Vinh =  1.125V
Vmeas =  0.750V
Cref =  0.0F
Rref =  1.000M
Vref =  0.0V
C_comp   5.000pF   4.000pF   5.500pF
[Temperature Range]   25.000   0.125k   -40.000
[Voltage Range]   1.500V   1.430V   1.580V
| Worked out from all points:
|   slope of the pulldown table from 0 to 0.225 V, typ, clamps not added: 30.7 ohm
|   slope of the pullup table from 0 to 0.225 V, typ, clamps not added: 34 ohm
|   GND clamp passes 1 mA (typ) near -0.32 V on its own axis
|   POWER clamp passes 1 mA (typ) near -0.45 V on its own axis
|   rising waveform, R_fixture 50.000, V_fixture 0.000: 20-80 % time 311ps typ, 333ps min, 377ps max; typ from 0 V to 0.774 V
|   rising waveform, R_fixture 50.000, V_fixture 1.500: 20-80 % time 163ps typ, 184ps min, 167ps max; typ from 0.698 V to 1.5 V
|   falling waveform, R_fixture 50.000, V_fixture 1.500: 20-80 % time 328ps typ, 329ps min, 417ps max; typ from 1.5 V to 0.698 V
|   falling waveform, R_fixture 50.000, V_fixture 0.000: 20-80 % time 135ps typ, 149ps min, 147ps max; typ from 0.774 V to 0 V
[GND_clamp]
|Voltage   I(typ)   I(min)   I(max)
-1.5V     -437mA     -482.5mA   -410.7mA
-1.159V   -180.3mA   -233.3mA   -152.2mA
-1.128V   -159.5mA   -212mA     -133.3mA
-1.097V   -139.6mA   -191.2mA   -116.5mA
-1.035V   -103.7mA   -151.3mA   -91.23mA
-973mV    -75.24mA   -114.6mA   -76.75mA
-911mV    -56.05mA   -82.58mA   -66.41mA
-787mV    -36.61mA   -38.2mA    -47.39mA
-663mV    -22.9mA    -18.92mA   -29.92mA
-477mV    -7.274mA   -6.461mA   -9.278mA
-260mV    -227.6uA   -429.8uA   -148.6uA
1.5V      0A         0A         0A
[POWER_clamp]
|Voltage   I(typ)   I(min)   I(max)
-1.5V     391.3mA    429.6mA    369.7mA
-1.166V   144.6mA    192.2mA    117.1mA
-1.135V   124.2mA    171.8mA    97.3mA
-1.104V   104.7mA    152mA      79.15mA
-1.042V   69.75mA    114.3mA    49.91mA
-1.011V   54.95mA    96.78mA    39.84mA
-949mV    32.47mA    65.46mA    28.02mA
-887mV    19.82mA    40.53mA    21.37mA
-825mV    13.31mA    23.23mA    15.79mA
-732mV    7.53mA     9.888mA    9.145mA
-608mV    3.278mA    3.592mA    3.895mA
3V        -183uA     -190.7uA   -185.3uA
[Pulldown]
|Voltage   I(typ)   I(min)   I(max)
-1.5V     -317.3mA   -339.9mA   -305.2mA
-1.27V    -191.9mA   -222.5mA   -173.7mA
-1.132V   -123.7mA   -156.1mA   -107.8mA
-994mV    -73mA      -97.2mA    -74.1mA
-764mV    -42.16mA   -39.16mA   -47.27mA
-396mV    -15.24mA   -14.44mA   -14.48mA
294mV     9.291mA    9.012mA    9.291mA
1.996V    19.65mA    19.06mA    19.65mA
2.41V     35.42mA    34.35mA    35.42mA
2.502V    50.45mA    48.93mA    50.45mA
2.64V     99.5mA     96.5mA     99.5mA
3V        285mA      276.4mA    285mA
[Pullup]
|Voltage   I(typ)   I(min)   I(max)
-1.5V     270.5mA    296.8mA    254.1mA
-1.186V   117.5mA    148.3mA    97.8mA
-1.094V   81mA       109.7mA    64.93mA
-1.048V   66.37mA    92mA       54.42mA
-956mV    47.16mA    62.34mA    43.5mA
-818mV    34.79mA    36.11mA    32.74mA
-496mV    18.28mA    17.11mA    15.93mA
516mV     -12.8mA    -12.42mA   -12.8mA
1.942V    -21.71mA   -21.06mA   -21.71mA
2.402V    -51.93mA   -50.37mA   -51.93mA
2.586V    -97.2mA    -94.3mA    -97.2mA
3V        -297.4mA   -288.5mA   -297.4mA
[Ramp]
| variable   typ   min   max
dV/dt_r   0.466/0.312n   0.443/0.337n   0.481/0.376n
dV/dt_f   0.477/0.334n   0.456/0.332n   0.489/0.414n
R_load = 50.000
[Rising Waveform]
R_fixture = 50.000
V_fixture = 0.000
V_fixture_min = 0.000
V_fixture_max = 0.000
|  time   V(typ)   V(min)   V(max)
0s        65.26uV    3.155mV    3.08mV
351ps     378.8uV    3.178mV    -1.352mV
471ps     3.114mV    3.231mV    352.1mV
569ps     205.1mV    3.481mV    499.7mV
710ps     493.4mV    6.335mV    609.1mV
901ps     637.9mV    368.7mV    683.8mV
1ns       672.5mV    501.1mV    706.6mV
1.339ns   725.5mV    659.5mV    749.4mV
2.62ns    761mV      726.2mV    790.6mV
10ns      773.6mV    741.1mV    804.9mV
[Rising Waveform]
R_fixture = 50.000
V_fixture = 1.500
V_fixture_min = 1.430
V_fixture_max = 1.580
|  time   V(typ)   V(min)   V(max)
0s        697.7mV    671mV      765.1mV
336ps     697.8mV    671.1mV    770.5mV
448ps     710.1mV    671.2mV    1.28V
568ps     1.175V     668.4mV    1.438V
659ps     1.342V     683mV      1.484V
701ps     1.376V     753.2mV    1.497V
830ps     1.429V     1.176V     1.524V
990ps     1.456V     1.331V     1.541V
2.179ns   1.49V      1.419V     1.571V
10ns      1.5V       1.43V      1.581V
[Falling Waveform]
R_fixture = 50.000
V_fixture = 1.500
V_fixture_min = 1.430
V_fixture_max = 1.580
|  time   V(typ)   V(min)   V(max)
0s        1.5V       1.43V      1.581V
356ps     1.5V       1.43V      1.581V
471ps     1.496V     1.43V      1.266V
671ps     1.032V     1.43V      1.016V
732ps     957.5mV    1.347V     976.5mV
862ps     860.2mV    1.047V     917.4mV
961ps     817.2mV    913.9mV    887.4mV
1.361ns   747.4mV    741.9mV    826.5mV
2.64ns    711.6mV    684.5mV    781mV
10ns      697.7mV    671mV      765.1mV
[Falling Waveform]
R_fixture = 50.000
V_fixture = 0.000
V_fixture_min = 0.000
V_fixture_max = 0.000
|  time   V(typ)   V(min)   V(max)
0s        773.6mV    741.1mV    804.9mV
351ps     773.5mV    740.9mV    801.3mV
451ps     772.6mV    741mV      295.2mV
481ps     708.1mV    740.8mV    227.5mV
571ps     270.1mV    742.9mV    132.2mV
661ps     131.5mV    735.9mV    90.17mV
811ps     66.54mV    229mV      57.24mV
951ps     43.14mV    97.8mV     42.44mV
1.891ns   12.01mV    15.39mV    14.66mV
10ns      65.26uV    3.155mV    3.08mV
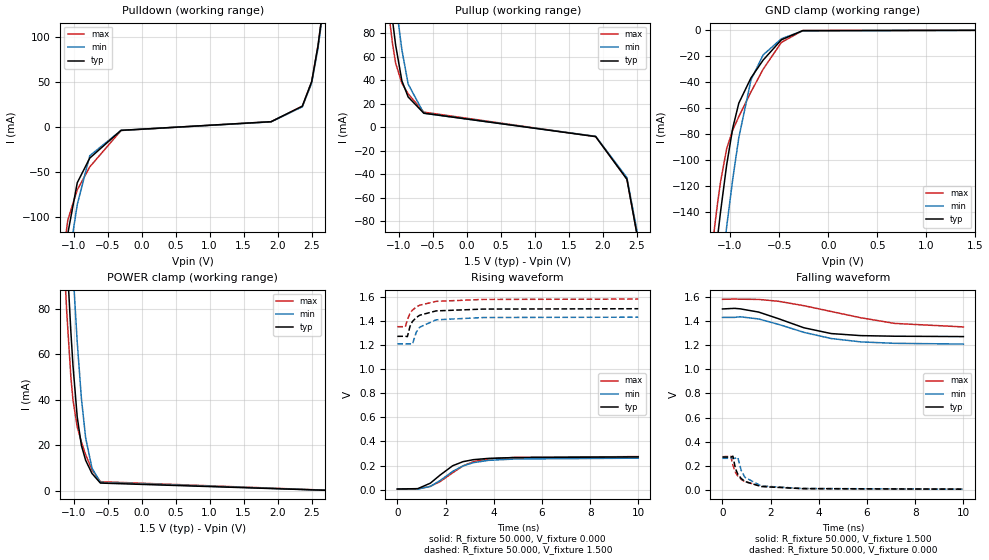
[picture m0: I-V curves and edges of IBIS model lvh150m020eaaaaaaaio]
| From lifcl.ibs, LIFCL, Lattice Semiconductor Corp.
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[Model] lvh150m020eaaaaaaaio
Model_type I/O
Polarity   Non-Inverting
Enable   Active-Low
Vinl =  0.375V
Vinh =  1.125V
Vmeas =  0.750V
Cref =  0.0F
Rref =  1.000M
Vref =  0.0V
C_comp   5.000pF   4.000pF   5.500pF
[Temperature Range]   25.000   0.125k   -40.000
[Voltage Range]   1.500V   1.430V   1.580V
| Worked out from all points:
|   slope of the pulldown table from 0 to 0.225 V, typ, clamps not added: 110 ohm
|   slope of the pullup table from 0 to 0.225 V, typ, clamps not added: 114 ohm
|   GND clamp passes 1 mA (typ) near -0.32 V on its own axis
|   POWER clamp passes 1 mA (typ) near -0.45 V on its own axis
|   rising waveform, R_fixture 50.000, V_fixture 0.000: 20-80 % time 1.11ns typ, 1.27ns min, 1.27ns max; typ from 0.006 V to 0.272 V
|   rising waveform, R_fixture 50.000, V_fixture 1.500: 20-80 % time 536ps typ, 515ps min, 594ps max; typ from 1.27 V to 1.5 V
|   falling waveform, R_fixture 50.000, V_fixture 1.500: 20-80 % time 2.06ns typ, 2.45ns min, 3.37ns max; typ from 1.5 V to 1.27 V
|   falling waveform, R_fixture 50.000, V_fixture 0.000: 20-80 % time 533ps typ, 522ps min, 603ps max; typ from 0.272 V to 0.006 V
[GND_clamp]
|Voltage   I(typ)   I(min)   I(max)
-1.5V     -437mA     -482.5mA   -410.7mA
-1.159V   -180.3mA   -233.3mA   -152.2mA
-1.128V   -159.5mA   -212mA     -133.3mA
-1.097V   -139.6mA   -191.2mA   -116.5mA
-1.035V   -103.7mA   -151.3mA   -91.23mA
-973mV    -75.24mA   -114.6mA   -76.75mA
-911mV    -56.05mA   -82.58mA   -66.41mA
-787mV    -36.61mA   -38.2mA    -47.39mA
-663mV    -22.9mA    -18.92mA   -29.92mA
-477mV    -7.274mA   -6.461mA   -9.278mA
-260mV    -227.6uA   -429.8uA   -148.6uA
1.5V      0A         0A         0A
[POWER_clamp]
|Voltage   I(typ)   I(min)   I(max)
-1.5V     391.3mA    429.6mA    369.7mA
-1.166V   144.6mA    192.2mA    117.1mA
-1.135V   124.2mA    171.8mA    97.3mA
-1.104V   104.7mA    152mA      79.15mA
-1.042V   69.75mA    114.3mA    49.91mA
-1.011V   54.95mA    96.78mA    39.84mA
-949mV    32.47mA    65.46mA    28.02mA
-887mV    19.82mA    40.53mA    21.37mA
-825mV    13.31mA    23.23mA    15.79mA
-732mV    7.53mA     9.888mA    9.145mA
-608mV    3.278mA    3.592mA    3.895mA
3V        -183uA     -190.7uA   -185.3uA
[Pulldown]
|Voltage   I(typ)   I(min)   I(max)
-1.5V     -381.2mA   -398.5mA   -369.5mA
-1.224V   -198.4mA   -231.2mA   -177.7mA
-1.086V   -117.9mA   -153.6mA   -102.9mA
-948mV    -61.75mA   -86mA      -69.76mA
-764mV    -34.4mA    -31.77mA   -44.22mA
-304mV    -3.563mA   -3.619mA   -3.717mA
1.904V    6.038mA    5.856mA    6.038mA
2.364V    23.29mA    22.59mA    23.29mA
2.502V    50.57mA    49.05mA    50.57mA
2.594V    90.1mA     87.4mA     90.1mA
2.732V    168.6mA    163.5mA    168.6mA
3V        342.5mA    332.2mA    342.5mA
[Pullup]
|Voltage   I(typ)   I(min)   I(max)
-1.5V     341.5mA    374.7mA    322.6mA
-1.186V   141.4mA    182mA      117.9mA
-1.14V    115.3mA    155.9mA    92.8mA
-1.094V   91.2mA     130.7mA    71.23mA
-1.048V   69.93mA    107mA      54.61mA
-956mV    39.5mA     65.87mA    37.33mA
-864mV    25.74mA    36.76mA    28.41mA
-634mV    11.91mA    11.82mA    12.78mA
1.896V    -8.049mA   -7.808mA   -8.049mA
2.356V    -44.37mA   -43.04mA   -44.37mA
2.586V    -117.1mA   -113.6mA   -117.1mA
3V        -379mA     -367.6mA   -379mA
[Ramp]
| variable   typ   min   max
dV/dt_r   0.160/1.150n   0.154/1.295n   0.161/1.302n
dV/dt_f   0.137/2.117n   0.133/2.528n   0.137/3.392n
R_load = 50.000
[Rising Waveform]
R_fixture = 50.000
V_fixture = 0.000
V_fixture_min = 0.000
V_fixture_max = 0.000
|  time   V(typ)   V(min)   V(max)
0s        6.181mV    6.231mV    6.466mV
848ps     9.393mV    5.085mV    7.627mV
1.367ns   54.3mV     27.79mV    28.32mV
1.777ns   122.1mV    76.29mV    68.12mV
2.297ns   199.2mV    152.2mV    140.8mV
2.729ns   233.1mV    198mV      198.2mV
3.16ns    249.5mV    224.9mV    233.2mV
3.781ns   260.1mV    243.8mV    255.8mV
4.868ns   266.9mV    255mV      268.2mV
10ns      272.3mV    262.1mV    275mV
[Rising Waveform]
R_fixture = 50.000
V_fixture = 1.500
V_fixture_min = 1.430
V_fixture_max = 1.580
|  time   V(typ)   V(min)   V(max)
0s        1.271V     1.209V     1.351V
334ps     1.272V     1.209V     1.351V
417ps     1.269V     1.209V     1.409V
527ps     1.355V     1.209V     1.463V
626ps     1.394V     1.206V     1.488V
786ps     1.427V     1.306V     1.514V
927ps     1.446V     1.347V     1.529V
1.607ns   1.482V     1.408V     1.561V
3.556ns   1.497V     1.427V     1.577V
10ns      1.5V       1.43V      1.58V
[Falling Waveform]
R_fixture = 50.000
V_fixture = 1.500
V_fixture_min = 1.430
V_fixture_max = 1.580
|  time   V(typ)   V(min)   V(max)
0s        1.5V       1.43V      1.58V
497ps     1.505V     1.43V      1.582V
735ps     1.501V     1.435V     1.581V
1.504ns   1.474V     1.417V     1.579V
2.315ns   1.42V      1.373V     1.564V
3.381ns   1.344V     1.306V     1.527V
4.511ns   1.296V     1.255V     1.479V
5.741ns   1.279V     1.227V     1.427V
7.154ns   1.274V     1.215V     1.38V
10ns      1.271V     1.209V     1.351V
[Falling Waveform]
R_fixture = 50.000
V_fixture = 0.000
V_fixture_min = 0.000
V_fixture_max = 0.000
|  time   V(typ)   V(min)   V(max)
0s        272.3mV    262.1mV    275mV
346ps     271.9mV    261.9mV    278.9mV
433ps     279.7mV    262.1mV    205.6mV
537ps     177.3mV    262.3mV    145.6mV
635ps     130.6mV    269.9mV    115.1mV
779ps     94.03mV    160.3mV    86.91mV
934ps     69.75mV    104mV      67.79mV
1.606ns   27.78mV    32.9mV     31.73mV
3.301ns   10.73mV    11.44mV    11.18mV
10ns      6.181mV    6.231mV    6.466mV
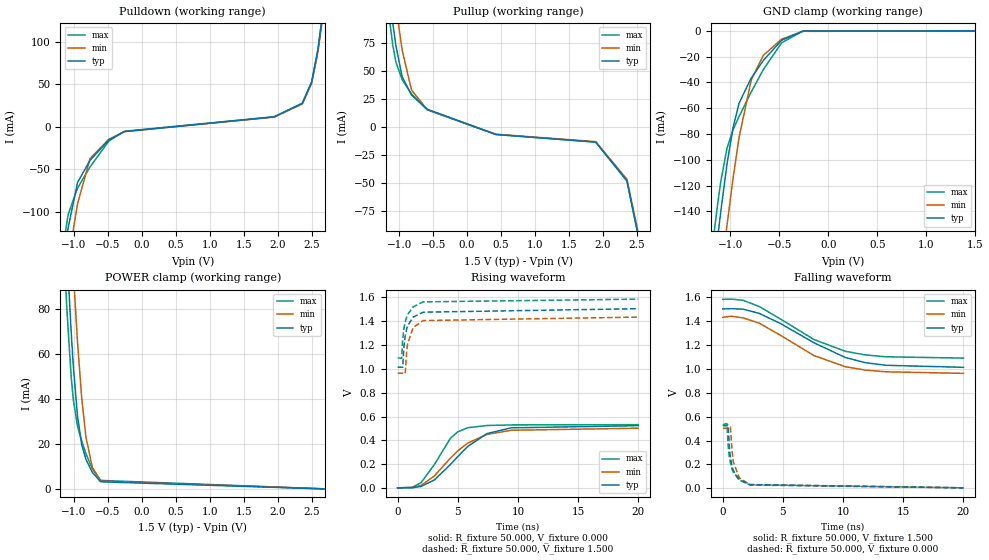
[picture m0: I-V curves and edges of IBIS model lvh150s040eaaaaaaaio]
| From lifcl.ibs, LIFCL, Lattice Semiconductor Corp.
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[Model] lvh150s040eaaaaaaaio
Model_type I/O
Polarity   Non-Inverting
Enable   Active-Low
Vinl =  0.375V
Vinh =  1.125V
Vmeas =  0.750V
Cref =  0.0F
Rref =  1.000M
Vref =  0.0V
C_comp   5.000pF   4.000pF   5.500pF
[Temperature Range]   25.000   0.125k   -40.000
[Voltage Range]   1.500V   1.430V   1.580V
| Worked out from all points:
|   slope of the pulldown table from 0 to 0.225 V, typ, clamps not added: 52.2 ohm
|   slope of the pullup table from 0 to 0.225 V, typ, clamps not added: 56 ohm
|   GND clamp passes 1 mA (typ) near -0.32 V on its own axis
|   POWER clamp passes 1 mA (typ) near -0.45 V on its own axis
|   rising waveform, R_fixture 50.000, V_fixture 0.000: 20-80 % time 3.21ns typ, 3.19ns min, 1.97ns max; typ from 0.005 V to 0.524 V
|   rising waveform, R_fixture 50.000, V_fixture 1.500: 20-80 % time 568ps typ, 544ps min, 610ps max; typ from 1.01 V to 1.5 V
|   falling waveform, R_fixture 50.000, V_fixture 1.500: 20-80 % time 5.43ns typ, 4.98ns min, 5.13ns max; typ from 1.5 V to 1.01 V
|   falling waveform, R_fixture 50.000, V_fixture 0.000: 20-80 % time 559ps typ, 544ps min, 606ps max; typ from 0.524 V to 0.005 V
[GND_clamp]
|Voltage   I(typ)   I(min)   I(max)
-1.5V     -437mA     -482.5mA   -410.7mA
-1.159V   -180.3mA   -233.3mA   -152.2mA
-1.128V   -159.5mA   -212mA     -133.3mA
-1.097V   -139.6mA   -191.2mA   -116.5mA
-1.035V   -103.7mA   -151.3mA   -91.23mA
-973mV    -75.24mA   -114.6mA   -76.75mA
-911mV    -56.05mA   -82.58mA   -66.41mA
-787mV    -36.61mA   -38.2mA    -47.39mA
-663mV    -22.9mA    -18.92mA   -29.92mA
-477mV    -7.274mA   -6.461mA   -9.278mA
-260mV    -227.6uA   -429.8uA   -148.6uA
1.5V      0A         0A         0A
[POWER_clamp]
|Voltage   I(typ)   I(min)   I(max)
-1.5V     391.3mA    429.6mA    369.7mA
-1.166V   144.6mA    192.2mA    117.1mA
-1.135V   124.2mA    171.8mA    97.3mA
-1.104V   104.7mA    152mA      79.15mA
-1.042V   69.75mA    114.3mA    49.91mA
-1.011V   54.95mA    96.78mA    39.84mA
-949mV    32.47mA    65.46mA    28.02mA
-887mV    19.82mA    40.53mA    21.37mA
-825mV    13.31mA    23.23mA    15.79mA
-732mV    7.53mA     9.888mA    9.145mA
-608mV    3.278mA    3.592mA    3.895mA
3V        -183uA     -190.7uA   -185.3uA
[Pulldown]
|Voltage   I(typ)   I(min)   I(max)
-1.5V     -375.9mA   -405mA     -360mA
-1.224V   -196.9mA   -236.1mA   -174.2mA
-1.086V   -118.5mA   -157.8mA   -102.9mA
-948mV    -65.35mA   -90.4mA    -72.03mA
-764mV    -39.35mA   -37.22mA   -47.13mA
-488mV    -15.5mA    -14.51mA   -16.6mA
-258mV    -5.508mA   -5.47mA    -5.083mA
1.95V     11.93mA    11.57mA    11.93mA
2.364V    27.86mA    27.03mA    27.86mA
2.502V    53.11mA    51.52mA    53.11mA
2.594V    91mA       88.3mA     91mA
3V        337.8mA    327.7mA    337.8mA
[Pullup]
|Voltage   I(typ)   I(min)   I(max)
-1.5V     334.2mA    366.8mA    315.2mA
-1.186V   140.5mA    179.9mA    117.2mA
-1.094V   92.7mA     130.5mA    73.11mA
-1.048V   72.68mA    107.9mA    57.95mA
-956mV    44.92mA    68.74mA    42.37mA
-818mV    28.55mA    33.04mA    29.55mA
-588mV    15.88mA    15.55mA    15.32mA
424mV     -6.746mA   -6.543mA   -6.746mA
1.896V    -13.58mA   -13.17mA   -13.58mA
2.356V    -48.31mA   -46.87mA   -48.31mA
2.586V    -116.3mA   -112.8mA   -116.3mA
3V        -369.7mA   -358.6mA   -369.7mA
[Ramp]
| variable   typ   min   max
dV/dt_r   0.311/3.231n   0.298/3.213n   0.333/2.014n
dV/dt_f   0.293/5.467n   0.283/4.991n   0.295/5.158n
R_load = 50.000
[Rising Waveform]
R_fixture = 50.000
V_fixture = 0.000
V_fixture_min = 0.000
V_fixture_max = 0.000
|  time   V(typ)   V(min)   V(max)
0s        4.554mV    4.949mV    4.4mV
1.227ns   5.329mV    6.507mV    9.257mV
1.946ns   16.1mV     24.42mV    47.76mV
3.051ns   70.72mV    103.7mV    198.4mV
4.381ns   198.4mV    251.8mV    417.5mV
4.989ns   264.6mV    312.4mV    471.9mV
5.83ns    350.4mV    378.4mV    506.5mV
7.435ns   457.8mV    450.8mV    525.1mV
9.441ns   505.4mV    485.2mV    529.7mV
20ns      523.5mV    502.5mV    532.4mV
[Rising Waveform]
R_fixture = 50.000
V_fixture = 1.500
V_fixture_min = 1.430
V_fixture_max = 1.580
|  time   V(typ)   V(min)   V(max)
0s        1.012V     961.3mV    1.089V
334ps     1.012V     961.4mV    1.087V
421ps     1.011V     961.5mV    1.243V
527ps     1.185V     960.3mV    1.338V
627ps     1.272V     956.3mV    1.389V
756ps     1.332V     1.142V     1.433V
837ps     1.358V     1.211V     1.453V
1.286ns   1.43V      1.342V     1.515V
2.116ns   1.471V     1.401V     1.557V
20ns      1.5V       1.43V      1.58V
[Falling Waveform]
R_fixture = 50.000
V_fixture = 1.500
V_fixture_min = 1.430
V_fixture_max = 1.580
|  time   V(typ)   V(min)   V(max)
0s        1.5V       1.43V      1.58V
727ps     1.502V     1.439V     1.582V
1.695ns   1.498V     1.425V     1.572V
3.031ns   1.463V     1.381V     1.52V
4.79ns    1.378V     1.28V      1.416V
7.583ns   1.217V     1.11V      1.244V
10.19ns   1.094V     1.017V     1.146V
11.83ns   1.051V     989.3mV    1.116V
13.55ns   1.029V     974.6mV    1.1V
20ns      1.012V     961.3mV    1.089V
[Falling Waveform]
R_fixture = 50.000
V_fixture = 0.000
V_fixture_min = 0.000
V_fixture_max = 0.000
|  time   V(typ)   V(min)   V(max)
0s        523.5mV    502.5mV    532.4mV
346ps     523mV      502.2mV    541.9mV
444ps     530mV      502.4mV    358.6mV
547ps     348.8mV    503.5mV    261.8mV
637ps     257.2mV    513.3mV    211.4mV
780ps     182.2mV    303.5mV    159mV
879ps     149.4mV    222.2mV    134.1mV
1.367ns   72.89mV    88.32mV    70mV
2.257ns   31.91mV    31.47mV    28.2mV
20ns      4.554mV    4.949mV    4.4mV
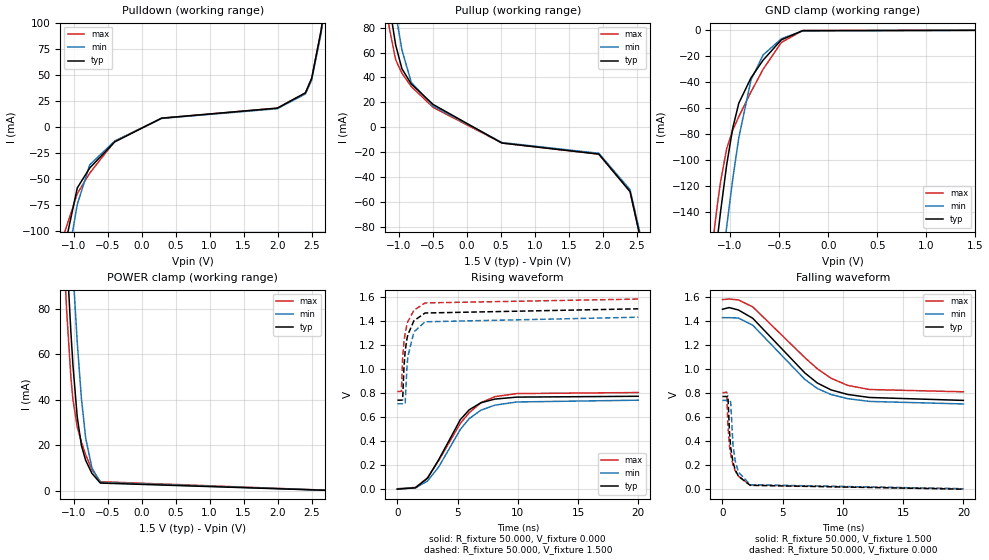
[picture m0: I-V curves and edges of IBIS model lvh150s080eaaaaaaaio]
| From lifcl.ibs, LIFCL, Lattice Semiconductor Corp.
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[Model] lvh150s080eaaaaaaaio
Model_type I/O
Polarity   Non-Inverting
Enable   Active-Low
Vinl =  0.375V
Vinh =  1.125V
Vmeas =  0.750V
Cref =  0.0F
Rref =  1.000M
Vref =  0.0V
C_comp   5.000pF   4.000pF   5.500pF
[Temperature Range]   25.000   0.125k   -40.000
[Voltage Range]   1.500V   1.430V   1.580V
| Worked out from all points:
|   slope of the pulldown table from 0 to 0.225 V, typ, clamps not added: 32.9 ohm
|   slope of the pullup table from 0 to 0.225 V, typ, clamps not added: 34.1 ohm
|   GND clamp passes 1 mA (typ) near -0.32 V on its own axis
|   POWER clamp passes 1 mA (typ) near -0.45 V on its own axis
|   rising waveform, R_fixture 50.000, V_fixture 0.000: 20-80 % time 2.61ns typ, 2.82ns min, 3.04ns max; typ from 0 V to 0.773 V
|   rising waveform, R_fixture 50.000, V_fixture 1.500: 20-80 % time 568ps typ, 545ps min, 610ps max; typ from 0.74 V to 1.5 V
|   falling waveform, R_fixture 50.000, V_fixture 1.500: 20-80 % time 4.42ns typ, 4.22ns min, 4.78ns max; typ from 1.5 V to 0.74 V
|   falling waveform, R_fixture 50.000, V_fixture 0.000: 20-80 % time 555ps typ, 545ps min, 601ps max; typ from 0.773 V to 0 V
[GND_clamp]
|Voltage   I(typ)   I(min)   I(max)
-1.5V     -437mA     -482.5mA   -410.7mA
-1.159V   -180.3mA   -233.3mA   -152.2mA
-1.128V   -159.5mA   -212mA     -133.3mA
-1.097V   -139.6mA   -191.2mA   -116.5mA
-1.035V   -103.7mA   -151.3mA   -91.23mA
-973mV    -75.24mA   -114.6mA   -76.75mA
-911mV    -56.05mA   -82.58mA   -66.41mA
-787mV    -36.61mA   -38.2mA    -47.39mA
-663mV    -22.9mA    -18.92mA   -29.92mA
-477mV    -7.274mA   -6.461mA   -9.278mA
-260mV    -227.6uA   -429.8uA   -148.6uA
1.5V      0A         0A         0A
[POWER_clamp]
|Voltage   I(typ)   I(min)   I(max)
-1.5V     391.3mA    429.6mA    369.7mA
-1.166V   144.6mA    192.2mA    117.1mA
-1.135V   124.2mA    171.8mA    97.3mA
-1.104V   104.7mA    152mA      79.15mA
-1.042V   69.75mA    114.3mA    49.91mA
-1.011V   54.95mA    96.78mA    39.84mA
-949mV    32.47mA    65.46mA    28.02mA
-887mV    19.82mA    40.53mA    21.37mA
-825mV    13.31mA    23.23mA    15.79mA
-732mV    7.53mA     9.888mA    9.145mA
-608mV    3.278mA    3.592mA    3.895mA
3V        -183uA     -190.7uA   -185.3uA
[Pulldown]
|Voltage   I(typ)   I(min)   I(max)
-1.5V     -295.2mA   -313.9mA   -285.3mA
-1.27V    -178.5mA   -205.5mA   -162.4mA
-1.132V   -115.1mA   -144.2mA   -100.7mA
-948mV    -58.46mA   -74.4mA    -63.98mA
-764mV    -39.23mA   -36.17mA   -44.18mA
-396mV    -14.18mA   -13.34mA   -13.53mA
294mV     8.644mA    8.385mA    8.644mA
1.996V    18.29mA    17.74mA    18.29mA
2.41V     32.95mA    31.96mA    32.95mA
2.502V    46.94mA    45.53mA    46.94mA
2.64V     92.7mA     89.9mA     92.7mA
3V        265.2mA    257.2mA    265.2mA
[Pullup]
|Voltage   I(typ)   I(min)   I(max)
-1.5V     270mA      296.1mA    253.6mA
-1.186V   117.3mA    148mA      97.6mA
-1.14V    98.1mA     128.2mA    79.5mA
-1.048V   66.23mA    91.8mA     54.31mA
-956mV    47.06mA    62.21mA    43.41mA
-818mV    34.72mA    36.03mA    32.67mA
-496mV    18.24mA    17.08mA    15.9mA
516mV     -12.78mA   -12.39mA   -12.78mA
1.942V    -21.67mA   -21.02mA   -21.67mA
2.402V    -51.82mA   -50.27mA   -51.82mA
2.586V    -97mA      -94.1mA    -97mA
3V        -296.8mA   -287.9mA   -296.8mA
[Ramp]
| variable   typ   min   max
dV/dt_r   0.465/2.622n   0.442/2.853n   0.480/3.051n
dV/dt_f   0.452/4.427n   0.432/4.230n   0.461/4.797n
R_load = 50.000
[Rising Waveform]
R_fixture = 50.000
V_fixture = 0.000
V_fixture_min = 0.000
V_fixture_max = 0.000
|  time   V(typ)   V(min)   V(max)
0s        63.14uV    3.278mV    3.271mV
1.51ns    11.48mV    11.11mV    14.62mV
2.508ns   91.9mV     68.18mV    94.09mV
3.432ns   244.6mV    184.5mV    238.2mV
5.23ns    578.3mV    496.9mV    547.7mV
5.965ns   660.1mV    586.7mV    636.1mV
6.941ns   718.6mV    657.1mV    719.1mV
8.097ns   749.2mV    698.6mV    769.4mV
9.915ns   765.6mV    725.2mV    795mV
20ns      772.6mV    740.1mV    803.7mV
[Rising Waveform]
R_fixture = 50.000
V_fixture = 1.500
V_fixture_min = 1.430
V_fixture_max = 1.580
|  time   V(typ)   V(min)   V(max)
0s        740.1mV    710.5mV    811.8mV
336ps     740.4mV    710.5mV    814.1mV
441ps     742.7mV    710.8mV    1.094V
549ps     1.014V     708.3mV    1.224V
651ps     1.149V     712.3mV    1.298V
791ps     1.247V     1.003V     1.365V
871ps     1.284V     1.103V     1.393V
1.378ns   1.401V     1.308V     1.488V
2.299ns   1.465V     1.392V     1.549V
20ns      1.5V       1.43V      1.581V
[Falling Waveform]
R_fixture = 50.000
V_fixture = 1.500
V_fixture_min = 1.430
V_fixture_max = 1.580
|  time   V(typ)   V(min)   V(max)
0s        1.5V       1.43V      1.581V
551ps     1.514V     1.43V      1.585V
1.32ns    1.494V     1.427V     1.578V
2.51ns    1.425V     1.367V     1.52V
6.835ns   969.3mV    915.2mV    1.097V
7.875ns   885.1mV    839.7mV    1.004V
9.007ns   827.8mV    789mV      925.1mV
10.4ns    789.6mV    754.4mV    865.2mV
12.2ns    764.5mV    731.6mV    831mV
20ns      740.1mV    710.5mV    811.8mV
[Falling Waveform]
R_fixture = 50.000
V_fixture = 0.000
V_fixture_min = 0.000
V_fixture_max = 0.000
|  time   V(typ)   V(min)   V(max)
0s        772.6mV    740.1mV    803.7mV
351ps     772.3mV    739.9mV    808.7mV
451ps     776.2mV    740mV      527.9mV
580ps     481.2mV    743.7mV    362.7mV
681ps     349mV      726.8mV    288.7mV
871ps     226mV      366.8mV    202.4mV
1.06ns    160.2mV    232.4mV    151.7mV
1.331ns   107.5mV    141.4mV    107.8mV
2.299ns   32.04mV    37.17mV    34.99mV
20ns      63.14uV    3.278mV    3.271mV
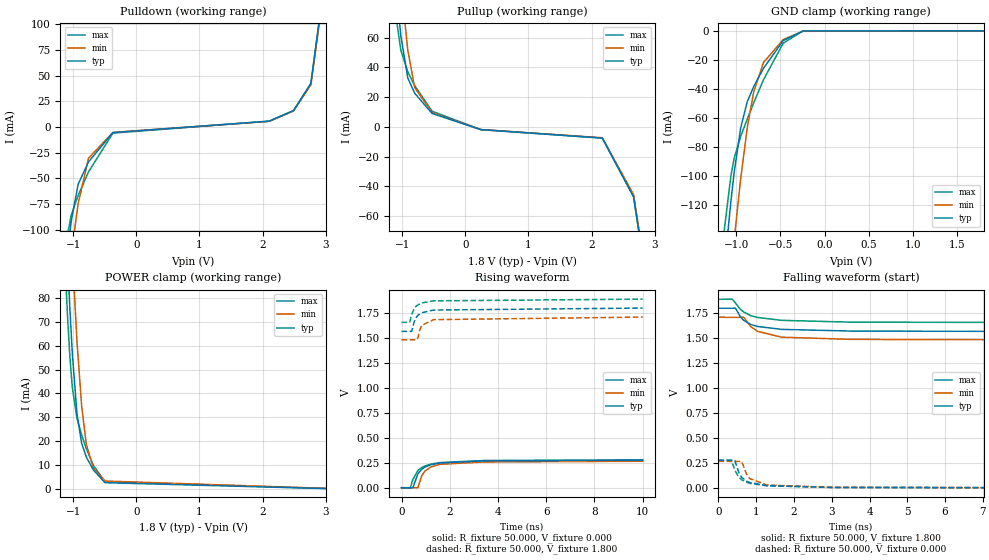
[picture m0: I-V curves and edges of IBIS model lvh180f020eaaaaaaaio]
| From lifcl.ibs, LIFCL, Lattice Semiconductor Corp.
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[Model] lvh180f020eaaaaaaaio
Model_type I/O
Polarity   Non-Inverting
Enable   Active-Low
Vinl =  0.630V
Vinh =  1.170V
Vmeas =  0.900V
Cref =  0.0F
Rref =  1.000M
Vref =  0.0V
C_comp   5.000pF   4.000pF   5.500pF
[Temperature Range]   25.000   0.125k   -40.000
[Voltage Range]   1.800V   1.710V   1.890V
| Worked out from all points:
|   slope of the pulldown table from 0 to 0.27 V, typ, clamps not added: 111 ohm
|   slope of the pullup table from 0 to 0.27 V, typ, clamps not added: 137 ohm
|   GND clamp passes 1 mA (typ) near -0.32 V on its own axis
|   POWER clamp passes 1 mA (typ) near -0.38 V on its own axis
|   rising waveform, R_fixture 50.000, V_fixture 0.000: 20-80 % time 548ps typ, 506ps min, 585ps max; typ from 0.006 V to 0.281 V
|   rising waveform, R_fixture 50.000, V_fixture 1.800: 20-80 % time 370ps typ, 353ps min, 370ps max; typ from 1.57 V to 1.8 V
|   falling waveform, R_fixture 50.000, V_fixture 1.800: 20-80 % time 569ps typ, 600ps min, 628ps max; typ from 1.8 V to 1.57 V
|   falling waveform, R_fixture 50.000, V_fixture 0.000: 20-80 % time 329ps typ, 334ps min, 346ps max; typ from 0.281 V to 0.006 V
[GND_clamp]
|Voltage   I(typ)   I(min)   I(max)
-1.8V     -676.5mA   -711.8mA   -657.4mA
-1.171V   -188.8mA   -241.8mA   -160mA
-1.134V   -163.6mA   -216.3mA   -136.9mA
-1.06V    -117.6mA   -167.3mA   -100mA
-1.023V   -97.67mA   -144.1mA   -87.78mA
-949mV    -66.77mA   -101.8mA   -72.6mA
-875mV    -48.8mA    -66.89mA   -60.78mA
-801mV    -38.33mA   -41.86mA   -49.49mA
-690mV    -25.71mA   -21.72mA   -33.55mA
-468mV    -6.724mA   -6.036mA   -8.541mA
-246mV    -145.3uA   -325.1uA   -81.62uA
1.8V      0A         0A         0A
[POWER_clamp]
|Voltage   I(typ)   I(min)   I(max)
-1.8V     627.7mA    654.9mA    614.1mA
-1.16V    141.5mA    189mA      114.4mA
-1.123V   117.5mA    164.8mA    91.5mA
-1.086V   95.05mA    141.5mA    71.26mA
-1.049V   74.59mA    119.2mA    54.66mA
-1.012V   56.78mA    98.27mA    42.5mA
-938mV    31.33mA    61.69mA    29.59mA
-864mV    19.12mA    34.68mA    22.65mA
-790mV    13.42mA    18.68mA    16.91mA
-679mV    8.018mA    8.826mA    9.955mA
-494mV    2.695mA    3.4mA      3.109mA
3.6V      -185.9uA   -195.7uA   -188.2uA
[Pulldown]
|Voltage   I(typ)   I(min)   I(max)
-1.8V     -596.9mA   -586.3mA   -599.1mA
-1.14V    -149.8mA   -183.1mA   -130.3mA
-1.085V   -119mA     -153mA     -104.1mA
-1.03V    -92.1mA    -124.4mA   -85.91mA
-920mV    -55.83mA   -74.71mA   -66.66mA
-755mV    -33.93mA   -30.38mA   -43.67mA
-370mV    -5.457mA   -5.328mA   -6.03mA
2.105V    5.615mA    5.447mA    5.615mA
2.49V     15.9mA     15.42mA    15.9mA
2.765V    42.22mA    40.96mA    42.22mA
2.985V    143.4mA    139.1mA    143.4mA
3.6V      555.3mA    538.6mA    555.3mA
[Pullup]
|Voltage   I(typ)   I(min)   I(max)
-1.8V     561.9mA    586.2mA    549.8mA
-1.13V    113.6mA    155.2mA    92.2mA
-1.075V   85.04mA    124.6mA    67.76mA
-1.02V    61.14mA    96.8mA     51.55mA
-910mV    32.88mA    51.58mA    37.04mA
-800mV    22.6mA     26.38mA    27.65mA
-525mV    9.027mA    9.575mA    10.54mA
245mV     -1.8mA     -1.746mA   -1.8mA
2.17V     -7.494mA   -7.269mA   -7.494mA
2.665V    -46.88mA   -45.48mA   -46.88mA
2.83V     -93mA      -90.2mA    -93mA
3.6V      -603.4mA   -585.3mA   -603.4mA
[Ramp]
| variable   typ   min   max
dV/dt_r   0.165/0.563n   0.159/0.513n   0.166/0.586n
dV/dt_f   0.140/0.572n   0.136/0.594n   0.140/0.636n
R_load = 50.000
[Rising Waveform]
R_fixture = 50.000
V_fixture = 0.000
V_fixture_min = 0.000
V_fixture_max = 0.000
|  time   V(typ)   V(min)   V(max)
0s        6.341mV    6.41mV     6.598mV
364ps     6.595mV    6.496mV    6.058mV
467ps     5.01mV     6.471mV    86.4mV
677ps     144.2mV    5.078mV    177.7mV
837ps     190.7mV    125.2mV    207.5mV
966ps     211.9mV    172.6mV    222.9mV
1.226ns   236.5mV    214.5mV    242.2mV
1.607ns   253.7mV    240.1mV    257.4mV
3.441ns   274.8mV    263.7mV    278.1mV
10ns      281.3mV    270.7mV    283.7mV
[Rising Waveform]
R_fixture = 50.000
V_fixture = 1.800
V_fixture_min = 1.710
V_fixture_max = 1.890
|  time   V(typ)   V(min)   V(max)
0s        1.567V     1.483V     1.657V
336ps     1.567V     1.483V     1.658V
420ps     1.567V     1.483V     1.734V
527ps     1.665V     1.483V     1.796V
626ps     1.712V     1.482V     1.823V
677ps     1.726V     1.504V     1.831V
776ps     1.744V     1.597V     1.844V
857ps     1.754V     1.63V      1.852V
1.328ns   1.78V      1.684V     1.872V
10ns      1.8V       1.71V      1.889V
[Falling Waveform]
R_fixture = 50.000
V_fixture = 1.800
V_fixture_min = 1.710
V_fixture_max = 1.890
|  time   V(typ)   V(min)   V(max)
0s        1.8V       1.71V      1.889V
362ps     1.8V       1.709V     1.891V
450ps     1.801V     1.709V     1.852V
577ps     1.717V     1.709V     1.79V
665ps     1.68V      1.712V     1.763V
855ps     1.638V     1.617V     1.726V
1.035ns   1.618V     1.569V     1.708V
1.675ns   1.589V     1.511V     1.679V
3.513ns   1.572V     1.489V     1.661V
10ns      1.567V     1.483V     1.657V
[Falling Waveform]
R_fixture = 50.000
V_fixture = 0.000
V_fixture_min = 0.000
V_fixture_max = 0.000
|  time   V(typ)   V(min)   V(max)
0s        281.3mV    270.7mV    283.7mV
346ps     281.1mV    270.5mV    280.9mV
433ps     278.8mV    270.7mV    182.8mV
537ps     161.3mV    270.9mV    112.8mV
615ps     111.1mV    269.9mV    86.92mV
745ps     72.87mV    142mV      61.8mV
829ps     58.98mV    98.85mV    51.72mV
1.285ns   28.2mV     34.74mV    27.13mV
2.98ns    11.16mV    11.33mV    10.56mV
10ns      6.341mV    6.41mV     6.598mV
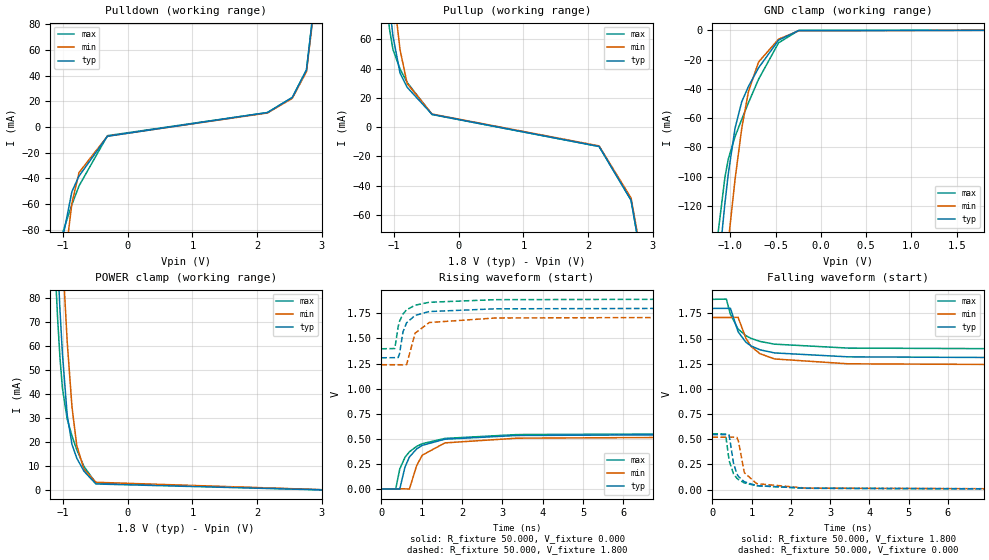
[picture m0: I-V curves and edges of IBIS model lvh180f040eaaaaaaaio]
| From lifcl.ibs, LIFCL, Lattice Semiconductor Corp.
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[Model] lvh180f040eaaaaaaaio
Model_type I/O
Polarity   Non-Inverting
Enable   Active-Low
Vinl =  0.630V
Vinh =  1.170V
Vmeas =  0.900V
Cref =  0.0F
Rref =  1.000M
Vref =  0.0V
C_comp   5.000pF   4.000pF   5.500pF
[Temperature Range]   25.000   0.125k   -40.000
[Voltage Range]   1.800V   1.710V   1.890V
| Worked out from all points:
|   slope of the pulldown table from 0 to 0.27 V, typ, clamps not added: 53.8 ohm
|   slope of the pullup table from 0 to 0.27 V, typ, clamps not added: 67.5 ohm
|   GND clamp passes 1 mA (typ) near -0.32 V on its own axis
|   POWER clamp passes 1 mA (typ) near -0.38 V on its own axis
|   rising waveform, R_fixture 50.000, V_fixture 0.000: 20-80 % time 499ps typ, 474ps min, 552ps max; typ from 0.005 V to 0.547 V
|   rising waveform, R_fixture 50.000, V_fixture 1.800: 20-80 % time 258ps typ, 274ps min, 277ps max; typ from 1.31 V to 1.8 V
|   falling waveform, R_fixture 50.000, V_fixture 1.800: 20-80 % time 561ps typ, 554ps min, 608ps max; typ from 1.8 V to 1.31 V
|   falling waveform, R_fixture 50.000, V_fixture 0.000: 20-80 % time 224ps typ, 229ps min, 243ps max; typ from 0.547 V to 0.005 V
[GND_clamp]
|Voltage   I(typ)   I(min)   I(max)
-1.8V     -676.5mA   -711.8mA   -657.4mA
-1.171V   -188.8mA   -241.8mA   -160mA
-1.134V   -163.6mA   -216.3mA   -136.9mA
-1.06V    -117.6mA   -167.3mA   -100mA
-1.023V   -97.67mA   -144.1mA   -87.78mA
-949mV    -66.77mA   -101.8mA   -72.6mA
-875mV    -48.8mA    -66.89mA   -60.78mA
-801mV    -38.33mA   -41.86mA   -49.49mA
-690mV    -25.71mA   -21.72mA   -33.55mA
-468mV    -6.724mA   -6.036mA   -8.541mA
-246mV    -145.3uA   -325.1uA   -81.62uA
1.8V      0A         0A         0A
[POWER_clamp]
|Voltage   I(typ)   I(min)   I(max)
-1.8V     627.7mA    654.9mA    614.1mA
-1.16V    141.5mA    189mA      114.4mA
-1.123V   117.5mA    164.8mA    91.5mA
-1.086V   95.05mA    141.5mA    71.26mA
-1.049V   74.59mA    119.2mA    54.66mA
-1.012V   56.78mA    98.27mA    42.5mA
-938mV    31.33mA    61.69mA    29.59mA
-864mV    19.12mA    34.68mA    22.65mA
-790mV    13.42mA    18.68mA    16.91mA
-679mV    8.018mA    8.826mA    9.955mA
-494mV    2.695mA    3.4mA      3.109mA
3.6V      -185.9uA   -195.7uA   -188.2uA
[Pulldown]
|Voltage   I(typ)   I(min)   I(max)
-1.8V     -575.4mA   -586.4mA   -572mA
-1.195V   -177.9mA   -215.9mA   -156.2mA
-1.14V    -146.3mA   -184.9mA   -126.3mA
-1.03V    -92.1mA    -126.8mA   -85.63mA
-865mV    -50.17mA   -59.32mA   -60.26mA
-755mV    -38.12mA   -35.34mA   -45.76mA
-315mV    -7.094mA   -7.021mA   -6.651mA
2.16V     11.37mA    11.03mA    11.37mA
2.545V    23.1mA     22.41mA    23.1mA
2.765V    44.6mA     43.26mA    44.6mA
2.985V    139.6mA    135.4mA    139.6mA
3.6V      535.2mA    519.1mA    535.2mA
[Pullup]
|Voltage   I(typ)   I(min)   I(max)
-1.8V     534.2mA    557.6mA    522.2mA
-1.185V   140.4mA    179.7mA    117.9mA
-1.13V    110.7mA    149.4mA    89.8mA
-1.075V   83.98mA    120.8mA    67.47mA
-1.02V    62.09mA    94.5mA     52.97mA
-910mV    36.84mA    52.76mA    39.66mA
-800mV    27.16mA    29.72mA    30.5mA
-415mV    8.725mA    8.931mA    8.602mA
2.17V     -13.19mA   -12.79mA   -13.19mA
2.665V    -49.83mA   -48.33mA   -49.83mA
2.83V     -91.4mA    -88.7mA    -91.4mA
3.6V      -573.4mA   -556.2mA   -573.4mA
[Ramp]
| variable   typ   min   max
dV/dt_r   0.325/0.504n   0.311/0.476n   0.330/0.552n
dV/dt_f   0.296/0.559n   0.286/0.556n   0.296/0.601n
R_load = 50.000
[Rising Waveform]
R_fixture = 50.000
V_fixture = 0.000
V_fixture_min = 0.000
V_fixture_max = 0.000
|  time   V(typ)   V(min)   V(max)
0s        4.71mV     5.471mV    4.581mV
356ps     4.971mV    5.528mV    2.151mV
457ps     4.322mV    5.516mV    202.8mV
587ps     222.7mV    5.384mV    319.1mV
696ps     321.5mV    3.924mV    373mV
877ps     402.5mV    237.9mV    427.6mV
1.016ns   437.6mV    340.3mV    454mV
1.577ns   498.4mV    461.7mV    506.2mV
3.362ns   535.3mV    508.5mV    544.3mV
10ns      546.9mV    521.2mV    554.8mV
[Rising Waveform]
R_fixture = 50.000
V_fixture = 1.800
V_fixture_min = 1.710
V_fixture_max = 1.890
|  time   V(typ)   V(min)   V(max)
0s        1.307V     1.238V     1.396V
334ps     1.308V     1.238V     1.399V
419ps     1.31V      1.238V     1.619V
451ps     1.346V     1.238V     1.669V
537ps     1.565V     1.236V     1.742V
626ps     1.654V     1.239V     1.783V
837ps     1.728V     1.551V     1.829V
1.187ns   1.766V     1.657V     1.858V
2.82ns    1.793V     1.702V     1.884V
10ns      1.8V       1.71V      1.89V
[Falling Waveform]
R_fixture = 50.000
V_fixture = 1.800
V_fixture_min = 1.710
V_fixture_max = 1.890
|  time   V(typ)   V(min)   V(max)
0s        1.8V       1.71V      1.89V
356ps     1.8V       1.71V      1.893V
460ps     1.802V     1.71V      1.742V
655ps     1.569V     1.712V     1.596V
855ps     1.464V     1.504V     1.529V
989ps     1.427V     1.421V     1.502V
1.215ns   1.389V     1.35V      1.472V
1.585ns   1.358V     1.298V     1.445V
3.459ns   1.319V     1.25V      1.406V
10ns      1.307V     1.238V     1.396V
[Falling Waveform]
R_fixture = 50.000
V_fixture = 0.000
V_fixture_min = 0.000
V_fixture_max = 0.000
|  time   V(typ)   V(min)   V(max)
0s        546.9mV    521.2mV    554.8mV
336ps     546.5mV    521mV      552.4mV
428ps     542.4mV    521.2mV    286.9mV
539ps     262.5mV    521.4mV    156.4mV
625ps     156.1mV    519.3mV    112.9mV
665ps     130.2mV    480.9mV    99.19mV
815ps     77.62mV    168.5mV    66.77mV
1.129ns   39.68mV    59.57mV    38.53mV
2.395ns   14.06mV    14.72mV    13mV
10ns      4.71mV     5.471mV    4.581mV
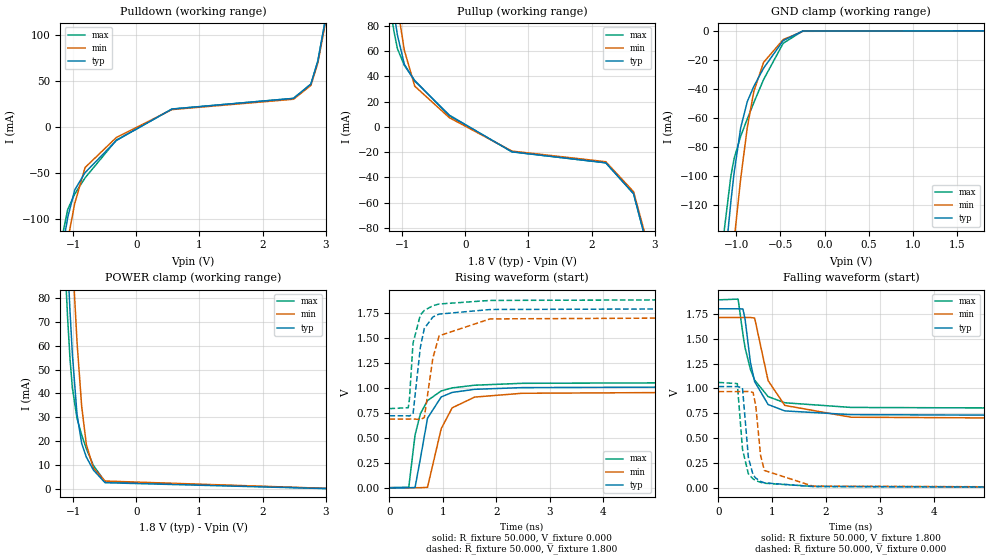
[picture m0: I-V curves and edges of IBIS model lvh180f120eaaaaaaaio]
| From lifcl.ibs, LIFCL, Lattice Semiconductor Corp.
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[Model] lvh180f120eaaaaaaaio
Model_type I/O
Polarity   Non-Inverting
Enable   Active-Low
Vinl =  0.630V
Vinh =  1.170V
Vmeas =  0.900V
Cref =  0.0F
Rref =  1.000M
Vref =  0.0V
C_comp   5.000pF   4.000pF   5.500pF
[Temperature Range]   25.000   0.125k   -40.000
[Voltage Range]   1.800V   1.710V   1.890V
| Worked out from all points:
|   slope of the pulldown table from 0 to 0.27 V, typ, clamps not added: 23.9 ohm
|   slope of the pullup table from 0 to 0.27 V, typ, clamps not added: 30.4 ohm
|   GND clamp passes 1 mA (typ) near -0.32 V on its own axis
|   POWER clamp passes 1 mA (typ) near -0.38 V on its own axis
|   rising waveform, R_fixture 50.000, V_fixture 0.000: 20-80 % time 245ps typ, 320ps min, 266ps max; typ from 0 V to 1.02 V
|   rising waveform, R_fixture 50.000, V_fixture 1.800: 20-80 % time 155ps typ, 197ps min, 133ps max; typ from 0.722 V to 1.8 V
|   falling waveform, R_fixture 50.000, V_fixture 1.800: 20-80 % time 249ps typ, 350ps min, 321ps max; typ from 1.8 V to 0.722 V
|   falling waveform, R_fixture 50.000, V_fixture 0.000: 20-80 % time 101ps typ, 134ps min, 111ps max; typ from 1.02 V to 0 V
[GND_clamp]
|Voltage   I(typ)   I(min)   I(max)
-1.8V     -676.5mA   -711.8mA   -657.4mA
-1.171V   -188.8mA   -241.8mA   -160mA
-1.134V   -163.6mA   -216.3mA   -136.9mA
-1.06V    -117.6mA   -167.3mA   -100mA
-1.023V   -97.67mA   -144.1mA   -87.78mA
-949mV    -66.77mA   -101.8mA   -72.6mA
-875mV    -48.8mA    -66.89mA   -60.78mA
-801mV    -38.33mA   -41.86mA   -49.49mA
-690mV    -25.71mA   -21.72mA   -33.55mA
-468mV    -6.724mA   -6.036mA   -8.541mA
-246mV    -145.3uA   -325.1uA   -81.62uA
1.8V      0A         0A         0A
[POWER_clamp]
|Voltage   I(typ)   I(min)   I(max)
-1.8V     627.7mA    654.9mA    614.1mA
-1.16V    141.5mA    189mA      114.4mA
-1.123V   117.5mA    164.8mA    91.5mA
-1.086V   95.05mA    141.5mA    71.26mA
-1.049V   74.59mA    119.2mA    54.66mA
-1.012V   56.78mA    98.27mA    42.5mA
-938mV    31.33mA    61.69mA    29.59mA
-864mV    19.12mA    34.68mA    22.65mA
-790mV    13.42mA    18.68mA    16.91mA
-679mV    8.018mA    8.826mA    9.955mA
-494mV    2.695mA    3.4mA      3.109mA
3.6V      -185.9uA   -195.7uA   -188.2uA
[Pulldown]
|Voltage   I(typ)   I(min)   I(max)
-1.8V     -446.5mA   -453mA     -445.9mA
-1.195V   -143mA     -169.9mA   -127.2mA
-1.085V   -98.6mA    -123.8mA   -89.9mA
-975mV    -68.8mA    -83.6mA    -73.2mA
-810mV    -49.78mA   -44.19mA   -55.42mA
-315mV    -14.76mA   -11.51mA   -14.36mA
565mV     19.49mA    18.9mA     19.49mA
2.49V     31.09mA    30.16mA    31.09mA
2.765V    46.6mA     45.2mA     46.6mA
2.875V    71.6mA     69.5mA     71.6mA
2.985V    112.9mA    109.5mA    112.9mA
3.6V      415mA      402.5mA    415mA
[Pullup]
|Voltage   I(typ)   I(min)   I(max)
-1.8V     403.7mA    420.1mA    393.5mA
-1.185V   112.1mA    139mA      94.9mA
-1.13V    91mA       116.8mA    76mA
-1.075V   73mA       96mA       62.13mA
-965mV    49.72mA    60.86mA    48.81mA
-800mV    36.34mA    32.32mA    36.85mA
-250mV    9.276mA    7.286mA    8.704mA
740mV     -19.74mA   -19.15mA   -19.74mA
2.225V    -28.43mA   -27.58mA   -28.43mA
2.665V    -52.94mA   -51.36mA   -52.94mA
2.885V    -95mA      -92.1mA    -95mA
3.6V      -431.6mA   -418.7mA   -431.6mA
[Ramp]
| variable   typ   min   max
dV/dt_r   0.612/0.244n   0.580/0.318n   0.634/0.269n
dV/dt_f   0.643/0.253n   0.613/0.355n   0.659/0.325n
R_load = 50.000
[Rising Waveform]
R_fixture = 50.000
V_fixture = 0.000
V_fixture_min = 0.000
V_fixture_max = 0.000
|  time   V(typ)   V(min)   V(max)
0s        101.1uV    1.478mV    2.915mV
361ps     612.1uV    1.493mV    6.625mV
478ps     3.691mV    1.582mV    528.9mV
578ps     293.1mV    1.637mV    743.1mV
711ps     697.8mV    5.707mV    873.8mV
967ps     910.4mV    592.5mV    970.8mV
1.172ns   955.8mV    801.5mV    1.001V
1.592ns   986.9mV    909.1mV    1.028V
2.479ns   1.004V     947.2mV    1.047V
10ns      1.018V     967.9mV    1.06V
[Rising Waveform]
R_fixture = 50.000
V_fixture = 1.800
V_fixture_min = 1.710
V_fixture_max = 1.890
|  time   V(typ)   V(min)   V(max)
0s        721.7mV    689.3mV    793.7mV
351ps     721.3mV    689.3mV    802.9mV
373ps     719.7mV    689.3mV    888.3mV
440ps     738.6mV    689.6mV    1.448V
577ps     1.407V     684.6mV    1.731V
651ps     1.596V     703.5mV    1.777V
811ps     1.711V     1.3V       1.824V
928ps     1.74V      1.523V     1.841V
1.881ns   1.786V     1.692V     1.877V
10ns      1.8V       1.712V     1.89V
[Falling Waveform]
R_fixture = 50.000
V_fixture = 1.800
V_fixture_min = 1.710
V_fixture_max = 1.890
|  time   V(typ)   V(min)   V(max)
0s        1.8V       1.712V     1.89V
365ps     1.8V       1.712V     1.897V
455ps     1.798V     1.712V     1.54V
495ps     1.692V     1.712V     1.406V
594ps     1.26V      1.712V     1.19V
672ps     1.068V     1.707V     1.083V
922ps     837.7mV    1.078V     917.2mV
1.232ns   773.5mV    828.8mV    855.3mV
2.465ns   735.9mV    710.1mV    808.4mV
10ns      721.7mV    689.3mV    793.7mV
[Falling Waveform]
R_fixture = 50.000
V_fixture = 0.000
V_fixture_min = 0.000
V_fixture_max = 0.000
|  time   V(typ)   V(min)   V(max)
0s        1.018V     967.9mV    1.06V
350ps     1.018V     967.7mV    1.048V
446ps     1.005V     967.9mV    388.7mV
555ps     307.4mV    968.8mV    141.7mV
642ps     131.6mV    959mV      90.3mV
692ps     98.24mV    830.8mV    73.97mV
782ps     65.34mV    326.3mV    55.56mV
852ps     50.83mV    175.2mV    46.63mV
1.754ns   12.83mV    17.29mV    15.24mV
10ns      101.1uV    1.478mV    2.915mV
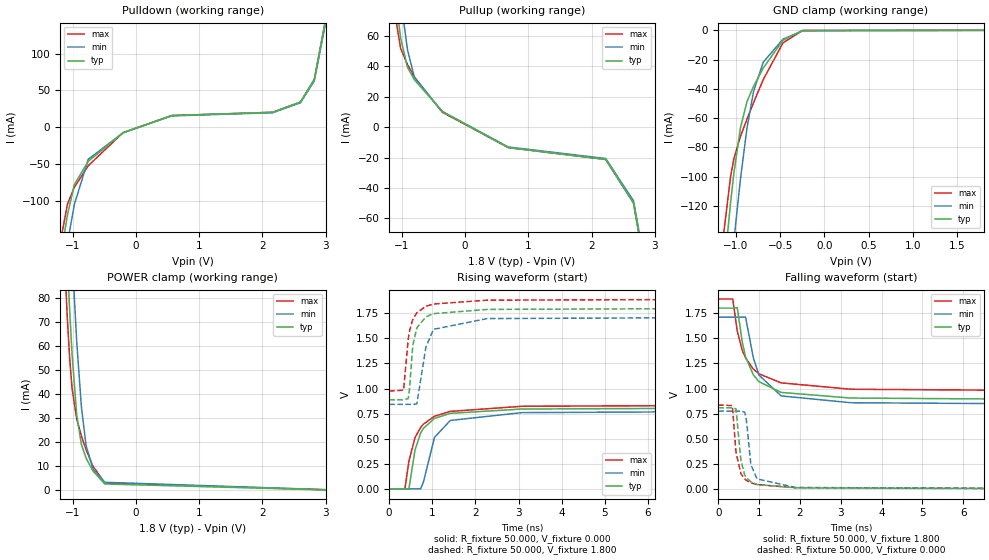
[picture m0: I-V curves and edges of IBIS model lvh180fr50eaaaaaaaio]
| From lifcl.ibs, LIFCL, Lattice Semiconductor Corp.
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[Model] lvh180fr50eaaaaaaaio
Model_type I/O
Polarity   Non-Inverting
Enable   Active-Low
Vinl =  0.630V
Vinh =  1.170V
Vmeas =  0.900V
Cref =  0.0F
Rref =  1.000M
Vref =  0.0V
C_comp   5.000pF   4.000pF   5.500pF
[Temperature Range]   25.000   0.125k   -40.000
[Voltage Range]   1.800V   1.710V   1.890V
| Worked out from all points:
|   slope of the pulldown table from 0 to 0.27 V, typ, clamps not added: 29.1 ohm
|   slope of the pullup table from 0 to 0.27 V, typ, clamps not added: 42.2 ohm
|   GND clamp passes 1 mA (typ) near -0.32 V on its own axis
|   POWER clamp passes 1 mA (typ) near -0.38 V on its own axis
|   rising waveform, R_fixture 50.000, V_fixture 0.000: 20-80 % time 356ps typ, 375ps min, 428ps max; typ from 0 V to 0.809 V
|   rising waveform, R_fixture 50.000, V_fixture 1.800: 20-80 % time 172ps typ, 228ps min, 192ps max; typ from 0.888 V to 1.8 V
|   falling waveform, R_fixture 50.000, V_fixture 1.800: 20-80 % time 458ps typ, 431ps min, 538ps max; typ from 1.8 V to 0.888 V
|   falling waveform, R_fixture 50.000, V_fixture 0.000: 20-80 % time 145ps typ, 152ps min, 153ps max; typ from 0.809 V to 0 V
[GND_clamp]
|Voltage   I(typ)   I(min)   I(max)
-1.8V     -676.5mA   -711.8mA   -657.4mA
-1.171V   -188.8mA   -241.8mA   -160mA
-1.134V   -163.6mA   -216.3mA   -136.9mA
-1.06V    -117.6mA   -167.3mA   -100mA
-1.023V   -97.67mA   -144.1mA   -87.78mA
-949mV    -66.77mA   -101.8mA   -72.6mA
-875mV    -48.8mA    -66.89mA   -60.78mA
-801mV    -38.33mA   -41.86mA   -49.49mA
-690mV    -25.71mA   -21.72mA   -33.55mA
-468mV    -6.724mA   -6.036mA   -8.541mA
-246mV    -145.3uA   -325.1uA   -81.62uA
1.8V      0A         0A         0A
[POWER_clamp]
|Voltage   I(typ)   I(min)   I(max)
-1.8V     627.7mA    654.9mA    614.1mA
-1.16V    141.5mA    189mA      114.4mA
-1.123V   117.5mA    164.8mA    91.5mA
-1.086V   95.05mA    141.5mA    71.26mA
-1.049V   74.59mA    119.2mA    54.66mA
-1.012V   56.78mA    98.27mA    42.5mA
-938mV    31.33mA    61.69mA    29.59mA
-864mV    19.12mA    34.68mA    22.65mA
-790mV    13.42mA    18.68mA    16.91mA
-679mV    8.018mA    8.826mA    9.955mA
-494mV    2.695mA    3.4mA      3.109mA
3.6V      -185.9uA   -195.7uA   -188.2uA
[Pulldown]
|Voltage   I(typ)   I(min)   I(max)
-1.8V     -567.1mA   -586mA     -558.7mA
-1.195V   -178.1mA   -218.3mA   -155.6mA
-1.085V   -119.7mA   -158.2mA   -105.2mA
-975mV    -78.23mA   -105.4mA   -81.84mA
-755mV    -46.51mA   -43.76mA   -52.55mA
-205mV    -7.828mA   -7.588mA   -7.437mA
565mV     15.8mA     15.33mA    15.8mA
2.16V     20.23mA    19.62mA    20.23mA
2.6V      34.17mA    33.15mA    34.17mA
2.82V     64.99mA    63.04mA    64.99mA
2.985V    140.2mA    136mA      140.2mA
3.6V      527.4mA    511.6mA    527.4mA
[Pullup]
|Voltage   I(typ)   I(min)   I(max)
-1.8V     453.6mA    473.7mA    442.9mA
-1.185V   122.1mA    155.2mA    102.9mA
-1.13V    97.6mA     130mA      80.2mA
-1.02V    58.64mA    84.5mA     51.83mA
-910mV    39.35mA    50.82mA    41.1mA
-800mV    31.1mA     32.59mA    32.9mA
-360mV    10.31mA    10.26mA    9.806mA
685mV     -13.45mA   -13.04mA   -13.45mA
2.225V    -21.23mA   -20.6mA    -21.23mA
2.665V    -49.94mA   -48.45mA   -49.94mA
2.885V    -102.4mA   -99.3mA    -102.4mA
3.6V      -485.9mA   -471.3mA   -485.9mA
[Ramp]
| variable   typ   min   max
dV/dt_r   0.488/0.355n   0.463/0.374n   0.500/0.428n
dV/dt_f   0.542/0.463n   0.520/0.435n   0.549/0.543n
R_load = 50.000
[Rising Waveform]
R_fixture = 50.000
V_fixture = 0.000
V_fixture_min = 0.000
V_fixture_max = 0.000
|  time   V(typ)   V(min)   V(max)
0s        116.5uV    3.325mV    3.164mV
364ps     481.2uV    3.348mV    60.15uV
458ps     2.746mV    3.369mV    278.7mV
599ps     389.2mV    2.87mV     512.7mV
732ps     560.7mV    5.075mV    614.5mV
792ps     603.9mV    67.86mV    645.3mV
1.052ns   703.6mV    515.1mV    725.2mV
1.418ns   753.8mV    683.3mV    773.4mV
3.08ns    796.8mV    761.1mV    824.1mV
10ns      809.3mV    775.7mV    836.9mV
[Rising Waveform]
R_fixture = 50.000
V_fixture = 1.800
V_fixture_min = 1.710
V_fixture_max = 1.890
|  time   V(typ)   V(min)   V(max)
0s        888.3mV    843.3mV    975.6mV
334ps     888.5mV    843.4mV    984.4mV
441ps     900.2mV    843.7mV    1.488V
468ps     978.1mV    843.6mV    1.566V
548ps     1.428V     840.6mV    1.688V
642ps     1.605V     849.5mV    1.754V
852ps     1.713V     1.412V     1.818V
1.028ns   1.745V     1.589V     1.841V
2.271ns   1.787V     1.696V     1.879V
10ns      1.8V       1.71V      1.89V
[Falling Waveform]
R_fixture = 50.000
V_fixture = 1.800
V_fixture_min = 1.710
V_fixture_max = 1.890
|  time   V(typ)   V(min)   V(max)
0s        1.8V       1.71V      1.89V
356ps     1.8V       1.71V      1.89V
466ps     1.805V     1.71V      1.575V
586ps     1.471V     1.71V      1.384V
670ps     1.315V     1.711V     1.305V
860ps     1.137V     1.306V     1.194V
996ps     1.069V     1.135V     1.147V
1.54ns    962mV      927.2mV    1.057V
3.25ns    905.8mV    859.3mV    993.4mV
10ns      888.3mV    843.3mV    975.6mV
[Falling Waveform]
R_fixture = 50.000
V_fixture = 0.000
V_fixture_min = 0.000
V_fixture_max = 0.000
|  time   V(typ)   V(min)   V(max)
0s        809.3mV    775.7mV    836.9mV
346ps     809.1mV    775.6mV    830.8mV
436ps     797.7mV    775.7mV    366.7mV
556ps     283.9mV    776.6mV    153.4mV
650ps     139.9mV    763.9mV    101mV
690ps     113.6mV    689.5mV    87.39mV
800ps     72.19mV    244.2mV    63.14mV
950ps     46.06mV    102.4mV    45.57mV
1.896ns   13.18mV    16.49mV    15.59mV
10ns      116.5uV    3.325mV    3.164mV
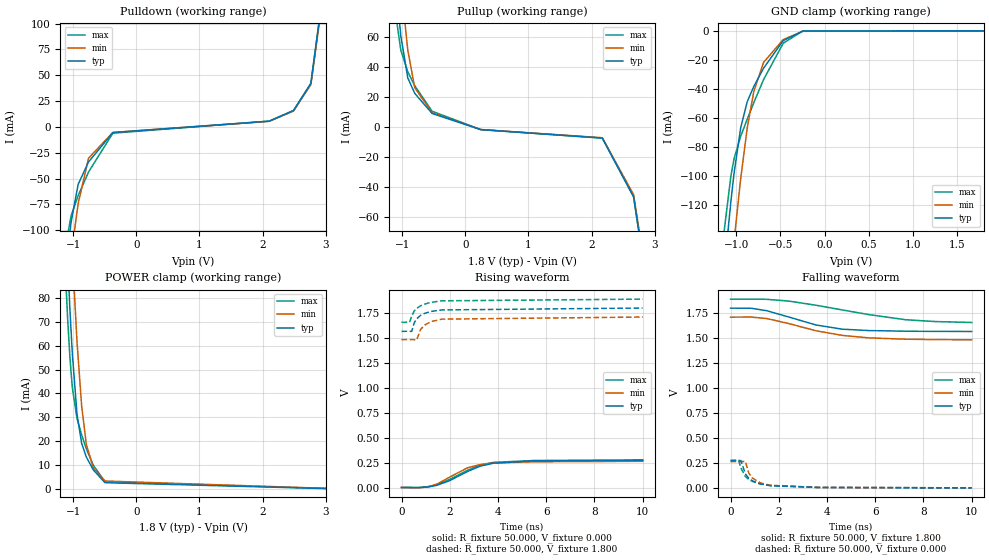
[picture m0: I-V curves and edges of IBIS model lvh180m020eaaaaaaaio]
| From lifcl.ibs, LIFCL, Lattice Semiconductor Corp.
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[Model] lvh180m020eaaaaaaaio
Model_type I/O
Polarity   Non-Inverting
Enable   Active-Low
Vinl =  0.630V
Vinh =  1.170V
Vmeas =  0.900V
Cref =  0.0F
Rref =  1.000M
Vref =  0.0V
C_comp   5.000pF   4.000pF   5.500pF
[Temperature Range]   25.000   0.125k   -40.000
[Voltage Range]   1.800V   1.710V   1.890V
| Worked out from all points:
|   slope of the pulldown table from 0 to 0.27 V, typ, clamps not added: 112 ohm
|   slope of the pullup table from 0 to 0.27 V, typ, clamps not added: 139 ohm
|   GND clamp passes 1 mA (typ) near -0.32 V on its own axis
|   POWER clamp passes 1 mA (typ) near -0.38 V on its own axis
|   rising waveform, R_fixture 50.000, V_fixture 0.000: 20-80 % time 1.46ns typ, 1.27ns min, 1.43ns max; typ from 0.006 V to 0.279 V
|   rising waveform, R_fixture 50.000, V_fixture 1.800: 20-80 % time 555ps typ, 517ps min, 590ps max; typ from 1.57 V to 1.8 V
|   falling waveform, R_fixture 50.000, V_fixture 1.800: 20-80 % time 2.07ns typ, 2.46ns min, 3.38ns max; typ from 1.8 V to 1.57 V
|   falling waveform, R_fixture 50.000, V_fixture 0.000: 20-80 % time 534ps typ, 526ps min, 602ps max; typ from 0.279 V to 0.006 V
[GND_clamp]
|Voltage   I(typ)   I(min)   I(max)
-1.8V     -676.5mA   -711.8mA   -657.4mA
-1.171V   -188.8mA   -241.8mA   -160mA
-1.134V   -163.6mA   -216.3mA   -136.9mA
-1.06V    -117.6mA   -167.3mA   -100mA
-1.023V   -97.67mA   -144.1mA   -87.78mA
-949mV    -66.77mA   -101.8mA   -72.6mA
-875mV    -48.8mA    -66.89mA   -60.78mA
-801mV    -38.33mA   -41.86mA   -49.49mA
-690mV    -25.71mA   -21.72mA   -33.55mA
-468mV    -6.724mA   -6.036mA   -8.541mA
-246mV    -145.3uA   -325.1uA   -81.62uA
1.8V      0A         0A         0A
[POWER_clamp]
|Voltage   I(typ)   I(min)   I(max)
-1.8V     627.7mA    654.9mA    614.1mA
-1.16V    141.5mA    189mA      114.4mA
-1.123V   117.5mA    164.8mA    91.5mA
-1.086V   95.05mA    141.5mA    71.26mA
-1.049V   74.59mA    119.2mA    54.66mA
-1.012V   56.78mA    98.27mA    42.5mA
-938mV    31.33mA    61.69mA    29.59mA
-864mV    19.12mA    34.68mA    22.65mA
-790mV    13.42mA    18.68mA    16.91mA
-679mV    8.018mA    8.826mA    9.955mA
-494mV    2.695mA    3.4mA      3.109mA
3.6V      -185.9uA   -195.7uA   -188.2uA
[Pulldown]
|Voltage   I(typ)   I(min)   I(max)
-1.8V     -594.7mA   -582.9mA   -597.6mA
-1.14V    -149.2mA   -182.1mA   -130mA
-1.085V   -118.6mA   -152.1mA   -103.8mA
-1.03V    -91.8mA    -123.7mA   -85.71mA
-920mV    -55.62mA   -74.28mA   -66.5mA
-755mV    -33.8mA    -30.2mA    -43.57mA
-370mV    -5.436mA   -5.297mA   -6.016mA
2.105V    5.594mA    5.426mA    5.594mA
2.49V     15.84mA    15.37mA    15.84mA
2.765V    42.06mA    40.8mA     42.06mA
2.985V    142.9mA    138.6mA    142.9mA
3.6V      553.2mA    536.6mA    553.2mA
[Pullup]
|Voltage   I(typ)   I(min)   I(max)
-1.8V     556.2mA    580.5mA    544.4mA
-1.13V    112.6mA    153.6mA    91.2mA
-1.075V   84.2mA     123.5mA    67.08mA
-1.02V    60.53mA    95.7mA     51.03mA
-910mV    32.55mA    51.07mA    36.67mA
-800mV    22.37mA    26.11mA    27.37mA
-525mV    8.937mA    9.48mA     10.43mA
245mV     -1.782mA   -1.729mA   -1.782mA
2.17V     -7.419mA   -7.197mA   -7.419mA
2.665V    -46.41mA   -45.02mA   -46.41mA
2.83V     -92.1mA    -89.3mA    -92.1mA
3.6V      -597.4mA   -579.5mA   -597.4mA
[Ramp]
| variable   typ   min   max
dV/dt_r   0.163/1.489n   0.157/1.294n   0.165/1.457n
dV/dt_f   0.139/2.108n   0.135/2.538n   0.139/3.399n
R_load = 50.000
[Rising Waveform]
R_fixture = 50.000
V_fixture = 0.000
V_fixture_min = 0.000
V_fixture_max = 0.000
|  time   V(typ)   V(min)   V(max)
0s        6.347mV    6.412mV    6.606mV
736ps     5.96mV     2.772mV    6.763mV
1.127ns   12.47mV    14.21mV    15.83mV
1.467ns   28.57mV    40.12mV    35.79mV
1.988ns   73.91mV    108.8mV    85.78mV
2.731ns   165.9mV    202.8mV    178.2mV
3.259ns   219.6mV    235.6mV    231mV
3.821ns   249.6mV    251.2mV    257.4mV
5.476ns   272.6mV    263.5mV    276.1mV
10ns      278.7mV    268.2mV    281mV
[Rising Waveform]
R_fixture = 50.000
V_fixture = 1.800
V_fixture_min = 1.710
V_fixture_max = 1.890
|  time   V(typ)   V(min)   V(max)
0s        1.567V     1.484V     1.657V
334ps     1.568V     1.484V     1.658V
421ps     1.566V     1.484V     1.72V
527ps     1.653V     1.484V     1.771V
626ps     1.692V     1.48V      1.796V
786ps     1.726V     1.583V     1.822V
927ps     1.744V     1.625V     1.837V
1.207ns   1.765V     1.663V     1.856V
1.666ns   1.781V     1.689V     1.872V
10ns      1.8V       1.71V      1.889V
[Falling Waveform]
R_fixture = 50.000
V_fixture = 1.800
V_fixture_min = 1.710
V_fixture_max = 1.890
|  time   V(typ)   V(min)   V(max)
0s        1.8V       1.71V      1.889V
855ps     1.799V     1.711V     1.89V
1.507ns   1.774V     1.696V     1.888V
2.434ns   1.71V      1.645V     1.87V
3.543ns   1.632V     1.574V     1.829V
4.634ns   1.59V      1.528V     1.782V
5.747ns   1.576V     1.503V     1.735V
7.276ns   1.57V      1.49V      1.684V
8.506ns   1.568V     1.486V     1.666V
10ns      1.567V     1.484V     1.657V
[Falling Waveform]
R_fixture = 50.000
V_fixture = 0.000
V_fixture_min = 0.000
V_fixture_max = 0.000
|  time   V(typ)   V(min)   V(max)
0s        278.7mV    268.2mV    281mV
336ps     278.3mV    268mV      281.6mV
428ps     278.7mV    268.2mV    205mV
615ps     145.6mV    270.2mV    119.7mV
755ps     103.1mV    154.7mV    90.71mV
905ps     76.33mV    104.1mV    70.99mV
1.23ns    44.7mV     56.62mV    46.93mV
1.655ns   27.27mV    30.99mV    30.73mV
3.661ns   9.963mV    10.53mV    10.2mV
10ns      6.347mV    6.412mV    6.606mV
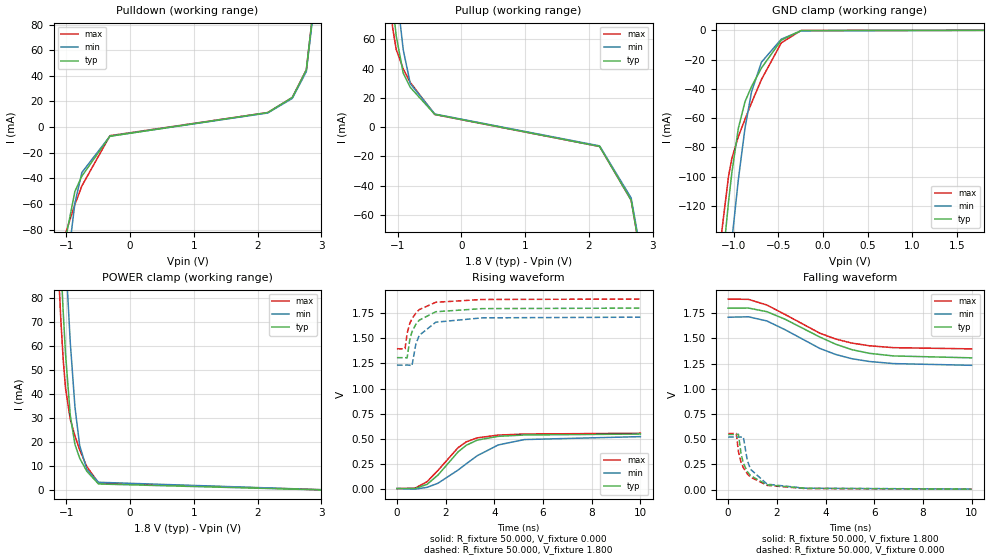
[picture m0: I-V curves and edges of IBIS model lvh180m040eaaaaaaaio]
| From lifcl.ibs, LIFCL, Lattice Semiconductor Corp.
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[Model] lvh180m040eaaaaaaaio
Model_type I/O
Polarity   Non-Inverting
Enable   Active-Low
Vinl =  0.630V
Vinh =  1.170V
Vmeas =  0.900V
Cref =  0.0F
Rref =  1.000M
Vref =  0.0V
C_comp   5.000pF   4.000pF   5.500pF
[Temperature Range]   25.000   0.125k   -40.000
[Voltage Range]   1.800V   1.710V   1.890V
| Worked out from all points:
|   slope of the pulldown table from 0 to 0.27 V, typ, clamps not added: 53.8 ohm
|   slope of the pullup table from 0 to 0.27 V, typ, clamps not added: 67.5 ohm
|   GND clamp passes 1 mA (typ) near -0.32 V on its own axis
|   POWER clamp passes 1 mA (typ) near -0.38 V on its own axis
|   rising waveform, R_fixture 50.000, V_fixture 0.000: 20-80 % time 1.29ns typ, 1.9ns min, 1.26ns max; typ from 0.005 V to 0.547 V
|   rising waveform, R_fixture 50.000, V_fixture 1.800: 20-80 % time 534ps typ, 527ps min, 561ps max; typ from 1.31 V to 1.8 V
|   falling waveform, R_fixture 50.000, V_fixture 1.800: 20-80 % time 2.61ns typ, 2.46ns min, 2.47ns max; typ from 1.8 V to 1.31 V
|   falling waveform, R_fixture 50.000, V_fixture 0.000: 20-80 % time 550ps typ, 515ps min, 575ps max; typ from 0.547 V to 0.005 V
[GND_clamp]
|Voltage   I(typ)   I(min)   I(max)
-1.8V     -676.5mA   -711.8mA   -657.4mA
-1.171V   -188.8mA   -241.8mA   -160mA
-1.134V   -163.6mA   -216.3mA   -136.9mA
-1.06V    -117.6mA   -167.3mA   -100mA
-1.023V   -97.67mA   -144.1mA   -87.78mA
-949mV    -66.77mA   -101.8mA   -72.6mA
-875mV    -48.8mA    -66.89mA   -60.78mA
-801mV    -38.33mA   -41.86mA   -49.49mA
-690mV    -25.71mA   -21.72mA   -33.55mA
-468mV    -6.724mA   -6.036mA   -8.541mA
-246mV    -145.3uA   -325.1uA   -81.62uA
1.8V      0A         0A         0A
[POWER_clamp]
|Voltage   I(typ)   I(min)   I(max)
-1.8V     627.7mA    654.9mA    614.1mA
-1.16V    141.5mA    189mA      114.4mA
-1.123V   117.5mA    164.8mA    91.5mA
-1.086V   95.05mA    141.5mA    71.26mA
-1.049V   74.59mA    119.2mA    54.66mA
-1.012V   56.78mA    98.27mA    42.5mA
-938mV    31.33mA    61.69mA    29.59mA
-864mV    19.12mA    34.68mA    22.65mA
-790mV    13.42mA    18.68mA    16.91mA
-679mV    8.018mA    8.826mA    9.955mA
-494mV    2.695mA    3.4mA      3.109mA
3.6V      -185.9uA   -195.7uA   -188.2uA
[Pulldown]
|Voltage   I(typ)   I(min)   I(max)
-1.8V     -575.9mA   -586.4mA   -572.6mA
-1.195V   -178.2mA   -215.9mA   -156.4mA
-1.14V    -146.4mA   -184.9mA   -126.5mA
-1.03V    -92.1mA    -126.8mA   -85.71mA
-865mV    -50.21mA   -59.31mA   -60.31mA
-755mV    -38.15mA   -35.33mA   -45.8mA
-315mV    -7.101mA   -7.02mA    -6.657mA
2.16V     11.38mA    11.04mA    11.38mA
2.545V    23.12mA    22.43mA    23.12mA
2.765V    44.64mA    43.3mA     44.64mA
2.985V    139.8mA    135.6mA    139.8mA
3.6V      535.8mA    519.7mA    535.8mA
[Pullup]
|Voltage   I(typ)   I(min)   I(max)
-1.8V     534.8mA    558.2mA    522.8mA
-1.185V   140.5mA    179.8mA    117.9mA
-1.13V    110.8mA    149.6mA    89.9mA
-1.075V   84.06mA    120.9mA    67.53mA
-1.02V    62.15mA    94.7mA     53.03mA
-910mV    36.88mA    52.81mA    39.7mA
-800mV    27.18mA    29.74mA    30.53mA
-415mV    8.734mA    8.94mA     8.611mA
2.17V     -13.2mA    -12.8mA    -13.2mA
2.665V    -49.88mA   -48.38mA   -49.88mA
2.83V     -91.5mA    -88.8mA    -91.5mA
3.6V      -573.8mA   -556.6mA   -573.8mA
[Ramp]
| variable   typ   min   max
dV/dt_r   0.326/1.324n   0.312/1.932n   0.330/1.278n
dV/dt_f   0.296/2.656n   0.286/2.535n   0.297/2.563n
R_load = 50.000
[Rising Waveform]
R_fixture = 50.000
V_fixture = 0.000
V_fixture_min = 0.000
V_fixture_max = 0.000
|  time   V(typ)   V(min)   V(max)
0s        4.708mV    5.471mV    4.578mV
746ps     5.245mV    -1.066mV   9.064mV
1.237ns   46.47mV    16.94mV    72.93mV
1.687ns   139.7mV    57.87mV    186.2mV
2.516ns   370.5mV    189.8mV    412.6mV
2.85ns    435.7mV    251.5mV    469.6mV
3.3ns     487mV      331.9mV    509.3mV
4.161ns   524.4mV    438.6mV    536.8mV
5.234ns   537.8mV    492.4mV    547.4mV
10ns      547.4mV    521.6mV    555.3mV
[Rising Waveform]
R_fixture = 50.000
V_fixture = 1.800
V_fixture_min = 1.710
V_fixture_max = 1.890
|  time   V(typ)   V(min)   V(max)
0s        1.307V     1.233V     1.396V
333ps     1.307V     1.233V     1.395V
419ps     1.305V     1.234V     1.549V
528ps     1.485V     1.232V     1.647V
616ps     1.563V     1.225V     1.694V
776ps     1.639V     1.441V     1.75V
917ps     1.68V      1.529V     1.785V
1.597ns   1.764V     1.66V      1.858V
3.499ns   1.795V     1.703V     1.886V
10ns      1.8V       1.71V      1.89V
[Falling Waveform]
R_fixture = 50.000
V_fixture = 1.800
V_fixture_min = 1.710
V_fixture_max = 1.890
|  time   V(typ)   V(min)   V(max)
0s        1.8V       1.71V      1.89V
835ps     1.801V     1.714V     1.887V
1.59ns    1.765V     1.673V     1.831V
2.338ns   1.69V      1.586V     1.737V
3.761ns   1.514V     1.401V     1.552V
4.411ns   1.443V     1.341V     1.494V
5.07ns    1.389V     1.299V     1.454V
5.794ns   1.352V     1.271V     1.427V
6.786ns   1.326V     1.25V      1.408V
10ns      1.307V     1.233V     1.396V
[Falling Waveform]
R_fixture = 50.000
V_fixture = 0.000
V_fixture_min = 0.000
V_fixture_max = 0.000
|  time   V(typ)   V(min)   V(max)
0s        547.4mV    521.6mV    555.3mV
333ps     546.9mV    521.4mV    557.1mV
421ps     549.9mV    521.6mV    379.1mV
529ps     358mV      521.4mV    271.9mV
625ps     261.9mV    522.3mV    216.7mV
785ps     179.5mV    291.2mV    157.5mV
919ps     138.5mV    201.7mV    123.6mV
1.604ns   47.49mV    54mV       42.2mV
3.154ns   12.96mV    13.89mV    11.08mV
10ns      4.708mV    5.471mV    4.578mV
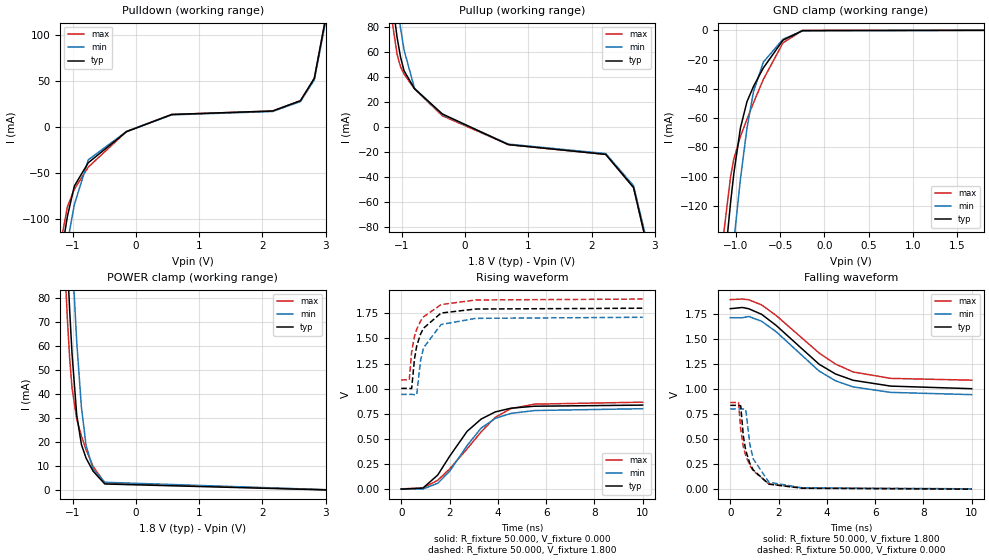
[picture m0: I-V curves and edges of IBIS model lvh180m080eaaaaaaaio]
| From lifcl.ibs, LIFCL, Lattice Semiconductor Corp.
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[Model] lvh180m080eaaaaaaaio
Model_type I/O
Polarity   Non-Inverting
Enable   Active-Low
Vinl =  0.630V
Vinh =  1.170V
Vmeas =  0.900V
Cref =  0.0F
Rref =  1.000M
Vref =  0.0V
C_comp   5.000pF   4.000pF   5.500pF
[Temperature Range]   25.000   0.125k   -40.000
[Voltage Range]   1.800V   1.710V   1.890V
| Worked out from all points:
|   slope of the pulldown table from 0 to 0.27 V, typ, clamps not added: 33.5 ohm
|   slope of the pullup table from 0 to 0.27 V, typ, clamps not added: 40.5 ohm
|   GND clamp passes 1 mA (typ) near -0.32 V on its own axis
|   POWER clamp passes 1 mA (typ) near -0.38 V on its own axis
|   rising waveform, R_fixture 50.000, V_fixture 0.000: 20-80 % time 1.56ns typ, 1.52ns min, 1.89ns max; typ from 0 V to 0.836 V
|   rising waveform, R_fixture 50.000, V_fixture 1.800: 20-80 % time 531ps typ, 527ps min, 591ps max; typ from 1 V to 1.8 V
|   falling waveform, R_fixture 50.000, V_fixture 1.800: 20-80 % time 2.38ns typ, 2.27ns min, 2.45ns max; typ from 1.8 V to 1 V
|   falling waveform, R_fixture 50.000, V_fixture 0.000: 20-80 % time 525ps typ, 497ps min, 574ps max; typ from 0.836 V to 0 V
[GND_clamp]
|Voltage   I(typ)   I(min)   I(max)
-1.8V     -676.5mA   -711.8mA   -657.4mA
-1.171V   -188.8mA   -241.8mA   -160mA
-1.134V   -163.6mA   -216.3mA   -136.9mA
-1.06V    -117.6mA   -167.3mA   -100mA
-1.023V   -97.67mA   -144.1mA   -87.78mA
-949mV    -66.77mA   -101.8mA   -72.6mA
-875mV    -48.8mA    -66.89mA   -60.78mA
-801mV    -38.33mA   -41.86mA   -49.49mA
-690mV    -25.71mA   -21.72mA   -33.55mA
-468mV    -6.724mA   -6.036mA   -8.541mA
-246mV    -145.3uA   -325.1uA   -81.62uA
1.8V      0A         0A         0A
[POWER_clamp]
|Voltage   I(typ)   I(min)   I(max)
-1.8V     627.7mA    654.9mA    614.1mA
-1.16V    141.5mA    189mA      114.4mA
-1.123V   117.5mA    164.8mA    91.5mA
-1.086V   95.05mA    141.5mA    71.26mA
-1.049V   74.59mA    119.2mA    54.66mA
-1.012V   56.78mA    98.27mA    42.5mA
-938mV    31.33mA    61.69mA    29.59mA
-864mV    19.12mA    34.68mA    22.65mA
-790mV    13.42mA    18.68mA    16.91mA
-679mV    8.018mA    8.826mA    9.955mA
-494mV    2.695mA    3.4mA      3.109mA
3.6V      -185.9uA   -195.7uA   -188.2uA
[Pulldown]
|Voltage   I(typ)   I(min)   I(max)
-1.8V     -455.8mA   -464.1mA   -455.9mA
-1.195V   -143.5mA   -173.1mA   -127.2mA
-1.085V   -96.8mA    -125.7mA   -86.3mA
-975mV    -63.89mA   -84mA      -67.31mA
-755mV    -38.62mA   -35.5mA    -43.42mA
-150mV    -4.956mA   -4.596mA   -4.633mA
565mV     13.74mA    13.32mA    13.74mA
2.16V     17.52mA    17mA       17.52mA
2.6V      28.66mA    27.8mA     28.66mA
2.82V     53mA       51.41mA    53mA
2.985V    113.1mA    109.7mA    113.1mA
3.6V      423.8mA    411.1mA    423.8mA
[Pullup]
|Voltage   I(typ)   I(min)   I(max)
-1.8V     423.8mA    442.4mA    413.3mA
-1.185V   114.8mA    145.2mA    96mA
-1.075V   72.1mA     99.6mA     58.48mA
-1.02V    56.22mA    79.4mA     48.37mA
-965mV    45.28mA    62.08mA    42.62mA
-800mV    30.91mA    31.23mA    30.7mA
-360mV    10.61mA    10.03mA    9.151mA
685mV     -14.03mA   -13.61mA   -14.03mA
2.225V    -21.86mA   -21.2mA    -21.86mA
2.665V    -48.46mA   -47.01mA   -48.46mA
2.885V    -96.4mA    -93.5mA    -96.4mA
3.6V      -453.8mA   -440.2mA   -453.8mA
[Ramp]
| variable   typ   min   max
dV/dt_r   0.504/1.570n   0.478/1.567n   0.517/1.928n
dV/dt_f   0.479/2.463n   0.460/2.370n   0.483/2.551n
R_load = 50.000
[Rising Waveform]
R_fixture = 50.000
V_fixture = 0.000
V_fixture_min = 0.000
V_fixture_max = 0.000
|  time   V(typ)   V(min)   V(max)
0s        109.1uV    3.437mV    3.367mV
899ps     11.2mV     1.921mV    11.35mV
1.512ns   140.7mV    59.14mV    88.7mV
2.002ns   326.5mV    177.6mV    200.7mV
2.729ns   575.5mV    434.3mV    401.4mV
3.311ns   697.6mV    608.1mV    570.5mV
3.898ns   768.8mV    704.6mV    714.5mV
4.541ns   805.3mV    753.5mV    801.4mV
5.52ns    825.2mV    782.4mV    845.8mV
10ns      836.2mV    800.5mV    865.4mV
[Rising Waveform]
R_fixture = 50.000
V_fixture = 1.800
V_fixture_min = 1.710
V_fixture_max = 1.890
|  time   V(typ)   V(min)   V(max)
0s        1.002V     942.8mV    1.087V
333ps     1.003V     943mV      1.088V
431ps     1V         943.1mV    1.367V
548ps     1.294V     939.8mV    1.519V
639ps     1.423V     939.5mV    1.589V
798ps     1.542V     1.275V     1.671V
922ps     1.601V     1.406V     1.714V
1.65ns    1.752V     1.638V     1.836V
3.085ns   1.792V     1.699V     1.882V
10ns      1.8V       1.71V      1.891V
[Falling Waveform]
R_fixture = 50.000
V_fixture = 1.800
V_fixture_min = 1.710
V_fixture_max = 1.890
|  time   V(typ)   V(min)   V(max)
0s        1.8V       1.71V      1.891V
502ps     1.812V     1.71V      1.896V
770ps     1.799V     1.722V     1.889V
1.298ns   1.744V     1.675V     1.838V
1.901ns   1.633V     1.57V      1.732V
3.68ns    1.246V     1.178V     1.358V
4.358ns   1.149V     1.081V     1.248V
5.09ns    1.086V     1.02V      1.169V
6.644ns   1.028V     965.4mV    1.105V
10ns      1.002V     942.8mV    1.087V
[Falling Waveform]
R_fixture = 50.000
V_fixture = 0.000
V_fixture_min = 0.000
V_fixture_max = 0.000
|  time   V(typ)   V(min)   V(max)
0s        836.2mV    800.5mV    865.4mV
343ps     835.8mV    800.4mV    863.1mV
433ps     831.4mV    800.5mV    595.8mV
541ps     530.8mV    800.8mV    424.1mV
641ps     384.7mV    795.6mV    333.7mV
811ps     256.9mV    448.4mV    237.2mV
951ps     191.8mV    302.4mV    183.8mV
1.599ns   49.92mV    69.56mV    52.61mV
2.989ns   9.162mV    13.43mV    11.19mV
10ns      109.1uV    3.437mV    3.367mV
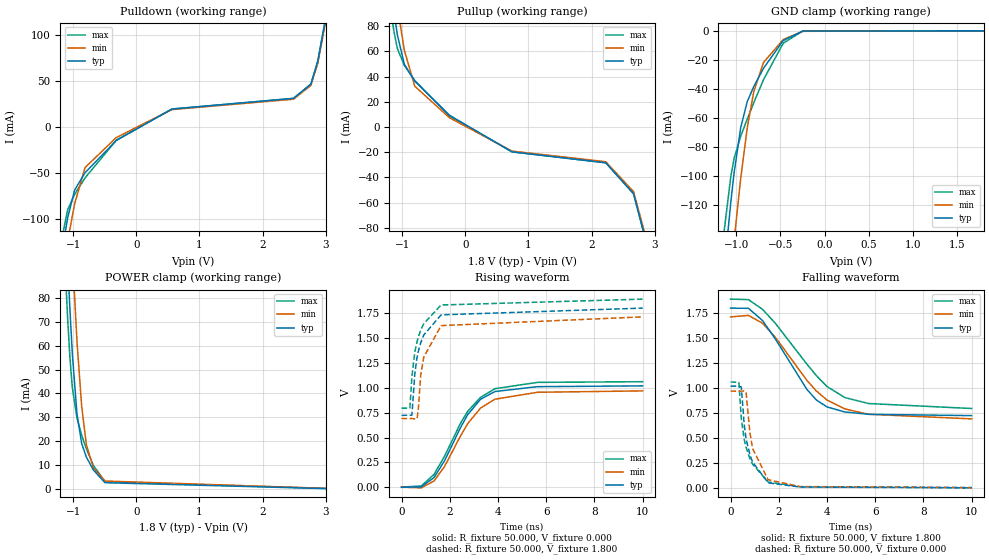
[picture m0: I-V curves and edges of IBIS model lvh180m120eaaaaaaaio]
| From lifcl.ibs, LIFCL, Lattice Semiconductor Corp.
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[Model] lvh180m120eaaaaaaaio
Model_type I/O
Polarity   Non-Inverting
Enable   Active-Low
Vinl =  0.630V
Vinh =  1.170V
Vmeas =  0.900V
Cref =  0.0F
Rref =  1.000M
Vref =  0.0V
C_comp   5.000pF   4.000pF   5.500pF
[Temperature Range]   25.000   0.125k   -40.000
[Voltage Range]   1.800V   1.710V   1.890V
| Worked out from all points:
|   slope of the pulldown table from 0 to 0.27 V, typ, clamps not added: 23.9 ohm
|   slope of the pullup table from 0 to 0.27 V, typ, clamps not added: 30.4 ohm
|   GND clamp passes 1 mA (typ) near -0.32 V on its own axis
|   POWER clamp passes 1 mA (typ) near -0.38 V on its own axis
|   rising waveform, R_fixture 50.000, V_fixture 0.000: 20-80 % time 1.35ns typ, 1.44ns min, 1.46ns max; typ from 0 V to 1.02 V
|   rising waveform, R_fixture 50.000, V_fixture 1.800: 20-80 % time 545ps typ, 513ps min, 576ps max; typ from 0.723 V to 1.8 V
|   falling waveform, R_fixture 50.000, V_fixture 1.800: 20-80 % time 1.72ns typ, 2.05ns min, 2.23ns max; typ from 1.8 V to 0.723 V
|   falling waveform, R_fixture 50.000, V_fixture 0.000: 20-80 % time 505ps typ, 489ps min, 566ps max; typ from 1.02 V to 0 V
[GND_clamp]
|Voltage   I(typ)   I(min)   I(max)
-1.8V     -676.5mA   -711.8mA   -657.4mA
-1.171V   -188.8mA   -241.8mA   -160mA
-1.134V   -163.6mA   -216.3mA   -136.9mA
-1.06V    -117.6mA   -167.3mA   -100mA
-1.023V   -97.67mA   -144.1mA   -87.78mA
-949mV    -66.77mA   -101.8mA   -72.6mA
-875mV    -48.8mA    -66.89mA   -60.78mA
-801mV    -38.33mA   -41.86mA   -49.49mA
-690mV    -25.71mA   -21.72mA   -33.55mA
-468mV    -6.724mA   -6.036mA   -8.541mA
-246mV    -145.3uA   -325.1uA   -81.62uA
1.8V      0A         0A         0A
[POWER_clamp]
|Voltage   I(typ)   I(min)   I(max)
-1.8V     627.7mA    654.9mA    614.1mA
-1.16V    141.5mA    189mA      114.4mA
-1.123V   117.5mA    164.8mA    91.5mA
-1.086V   95.05mA    141.5mA    71.26mA
-1.049V   74.59mA    119.2mA    54.66mA
-1.012V   56.78mA    98.27mA    42.5mA
-938mV    31.33mA    61.69mA    29.59mA
-864mV    19.12mA    34.68mA    22.65mA
-790mV    13.42mA    18.68mA    16.91mA
-679mV    8.018mA    8.826mA    9.955mA
-494mV    2.695mA    3.4mA      3.109mA
3.6V      -185.9uA   -195.7uA   -188.2uA
[Pulldown]
|Voltage   I(typ)   I(min)   I(max)
-1.8V     -445.4mA   -451.9mA   -445.5mA
-1.195V   -142.7mA   -169.4mA   -127mA
-1.085V   -98.4mA    -123.5mA   -89.8mA
-975mV    -68.5mA    -83.4mA    -73.1mA
-810mV    -49.66mA   -44.08mA   -55.35mA
-315mV    -14.72mA   -11.48mA   -14.34mA
565mV     19.44mA    18.86mA    19.44mA
2.49V     31.02mA    30.09mA    31.02mA
2.765V    46.49mA    45.09mA    46.49mA
2.875V    71.4mA     69.3mA     71.4mA
2.985V    112.7mA    109.3mA    112.7mA
3.6V      414.1mA    401.7mA    414.1mA
[Pullup]
|Voltage   I(typ)   I(min)   I(max)
-1.8V     404.1mA    420.6mA    393.9mA
-1.185V   112.3mA    139.1mA    95mA
-1.13V    91.1mA     116.9mA    76mA
-1.075V   73.1mA     96.1mA     62.2mA
-965mV    49.78mA    60.93mA    48.87mA
-800mV    36.38mA    32.35mA    36.89mA
-250mV    9.287mA    7.294mA    8.714mA
740mV     -19.76mA   -19.17mA   -19.76mA
2.225V    -28.46mA   -27.61mA   -28.46mA
2.665V    -53.01mA   -51.41mA   -53.01mA
2.885V    -95.1mA    -92.2mA    -95.1mA
3.6V      -432.1mA   -419.1mA   -432.1mA
[Ramp]
| variable   typ   min   max
dV/dt_r   0.613/1.362n   0.580/1.458n   0.635/1.480n
dV/dt_f   0.642/1.755n   0.613/2.076n   0.657/2.257n
R_load = 50.000
[Rising Waveform]
R_fixture = 50.000
V_fixture = 0.000
V_fixture_min = 0.000
V_fixture_max = 0.000
|  time   V(typ)   V(min)   V(max)
0s        101.8uV    1.484mV    2.928mV
819ps     4.658mV    -5.147mV   13.33mV
1.348ns   98.19mV    63.57mV    130mV
1.788ns   268.4mV    211mV      313.8mV
2.428ns   591.4mV    508.3mV    635.1mV
2.741ns   729mV      638.7mV    762.6mV
3.279ns   884.8mV    796.6mV    904.2mV
3.875ns   962.3mV    885.2mV    990.7mV
5.635ns   1.011V     954.7mV    1.054V
10ns      1.019V     968.6mV    1.061V
[Rising Waveform]
R_fixture = 50.000
V_fixture = 1.800
V_fixture_min = 1.710
V_fixture_max = 1.890
|  time   V(typ)   V(min)   V(max)
0s        723.4mV    690.9mV    794.7mV
346ps     723.3mV    691mV      796.8mV
431ps     725.6mV    691.3mV    1.112V
549ps     1.135V     687.5mV    1.356V
641ps     1.302V     689.4mV    1.461V
691ps     1.361V     768.7mV    1.505V
798ps     1.454V     1.133V     1.579V
922ps     1.53V      1.308V     1.644V
1.641ns   1.732V     1.624V     1.831V
10ns      1.8V       1.712V     1.89V
[Falling Waveform]
R_fixture = 50.000
V_fixture = 1.800
V_fixture_min = 1.710
V_fixture_max = 1.890
|  time   V(typ)   V(min)   V(max)
0s        1.8V       1.712V     1.89V
742ps     1.798V     1.727V     1.885V
1.325ns   1.676V     1.649V     1.788V
1.855ns   1.492V     1.509V     1.649V
3.17ns    984.9mV    1.075V     1.238V
3.561ns   879.5mV    969.6mV    1.123V
3.999ns   810.6mV    880.2mV    1.015V
4.739ns   760mV      790.6mV    904.3mV
5.725ns   736.8mV    736.8mV    844.5mV
10ns      723.4mV    690.9mV    794.7mV
[Falling Waveform]
R_fixture = 50.000
V_fixture = 0.000
V_fixture_min = 0.000
V_fixture_max = 0.000
|  time   V(typ)   V(min)   V(max)
0s        1.019V     968.6mV    1.061V
346ps     1.018V     968.4mV    1.055V
446ps     1.01V      968.5mV    691.4mV
565ps     637.6mV    970.4mV    487.1mV
642ps     493.6mV    961.6mV    406.4mV
800ps     333.4mV    557.6mV    294.4mV
915ps     258.1mV    394.2mV    236.8mV
1.562ns   49.91mV    81.31mV    58.53mV
2.879ns   8.742mV    13.08mV    11.19mV
10ns      101.8uV    1.484mV    2.928mV
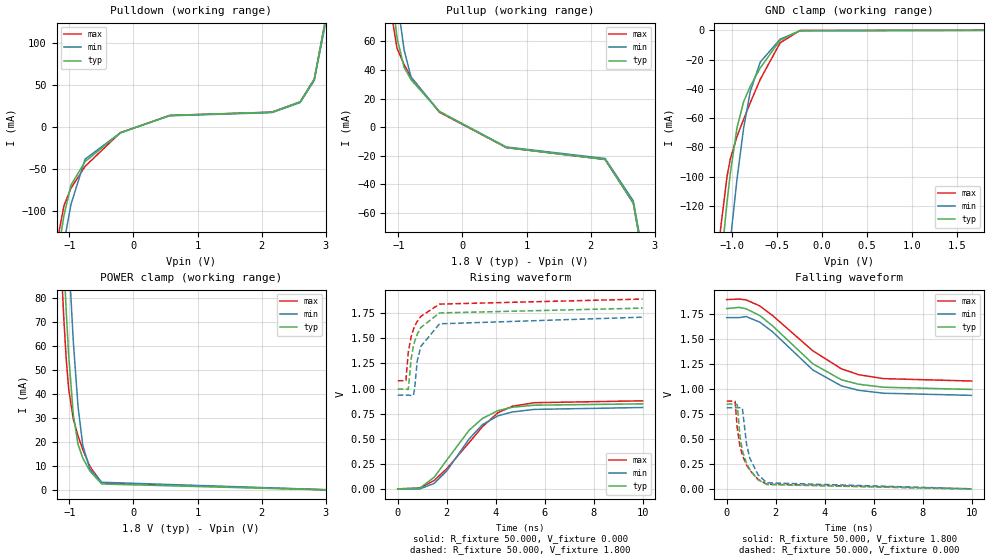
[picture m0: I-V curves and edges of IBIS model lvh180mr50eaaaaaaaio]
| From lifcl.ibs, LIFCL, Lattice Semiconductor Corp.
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[Model] lvh180mr50eaaaaaaaio
Model_type I/O
Polarity   Non-Inverting
Enable   Active-Low
Vinl =  0.630V
Vinh =  1.170V
Vmeas =  0.900V
Cref =  0.0F
Rref =  1.000M
Vref =  0.0V
C_comp   5.000pF   4.000pF   5.500pF
[Temperature Range]   25.000   0.125k   -40.000
[Voltage Range]   1.800V   1.710V   1.890V
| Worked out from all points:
|   slope of the pulldown table from 0 to 0.27 V, typ, clamps not added: 33.1 ohm
|   slope of the pullup table from 0 to 0.27 V, typ, clamps not added: 39.6 ohm
|   GND clamp passes 1 mA (typ) near -0.32 V on its own axis
|   POWER clamp passes 1 mA (typ) near -0.38 V on its own axis
|   rising waveform, R_fixture 50.000, V_fixture 0.000: 20-80 % time 1.67ns typ, 1.56ns min, 1.89ns max; typ from 0 V to 0.848 V
|   rising waveform, R_fixture 50.000, V_fixture 1.800: 20-80 % time 535ps typ, 526ps min, 591ps max; typ from 0.994 V to 1.8 V
|   falling waveform, R_fixture 50.000, V_fixture 1.800: 20-80 % time 2.26ns typ, 2.18ns min, 2.46ns max; typ from 1.8 V to 0.994 V
|   falling waveform, R_fixture 50.000, V_fixture 0.000: 20-80 % time 522ps typ, 494ps min, 574ps max; typ from 0.848 V to 0 V
[GND_clamp]
|Voltage   I(typ)   I(min)   I(max)
-1.8V     -676.5mA   -711.8mA   -657.4mA
-1.171V   -188.8mA   -241.8mA   -160mA
-1.134V   -163.6mA   -216.3mA   -136.9mA
-1.06V    -117.6mA   -167.3mA   -100mA
-1.023V   -97.67mA   -144.1mA   -87.78mA
-949mV    -66.77mA   -101.8mA   -72.6mA
-875mV    -48.8mA    -66.89mA   -60.78mA
-801mV    -38.33mA   -41.86mA   -49.49mA
-690mV    -25.71mA   -21.72mA   -33.55mA
-468mV    -6.724mA   -6.036mA   -8.541mA
-246mV    -145.3uA   -325.1uA   -81.62uA
1.8V      0A         0A         0A
[POWER_clamp]
|Voltage   I(typ)   I(min)   I(max)
-1.8V     627.7mA    654.9mA    614.1mA
-1.16V    141.5mA    189mA      114.4mA
-1.123V   117.5mA    164.8mA    91.5mA
-1.086V   95.05mA    141.5mA    71.26mA
-1.049V   74.59mA    119.2mA    54.66mA
-1.012V   56.78mA    98.27mA    42.5mA
-938mV    31.33mA    61.69mA    29.59mA
-864mV    19.12mA    34.68mA    22.65mA
-790mV    13.42mA    18.68mA    16.91mA
-679mV    8.018mA    8.826mA    9.955mA
-494mV    2.695mA    3.4mA      3.109mA
3.6V      -185.9uA   -195.7uA   -188.2uA
[Pulldown]
|Voltage   I(typ)   I(min)   I(max)
-1.8V     -499.1mA   -510.8mA   -495.9mA
-1.195V   -156.8mA   -190.3mA   -138.1mA
-1.085V   -105.4mA   -137.9mA   -93.5mA
-975mV    -68.84mA   -91.9mA    -72.63mA
-755mV    -40.93mA   -38.14mA   -46.64mA
-205mV    -6.889mA   -6.613mA   -6.6mA
565mV     13.91mA    13.49mA    13.91mA
2.16V     17.8mA     17.27mA    17.8mA
2.6V      30.07mA    29.17mA    30.07mA
2.82V     57.19mA    55.48mA    57.19mA
2.985V    123.3mA    119.6mA    123.3mA
3.6V      464mA      450.1mA    464mA
[Pullup]
|Voltage   I(typ)   I(min)   I(max)
-1.8V     483.2mA    504.5mA    471.7mA
-1.185V   130mA      165.3mA    109.6mA
-1.13V    103.9mA    138.4mA    85.4mA
-1.02V    62.46mA    90.1mA     55.21mA
-910mV    41.91mA    54.13mA    43.78mA
-800mV    33.13mA    34.71mA    35.04mA
-360mV    10.98mA    10.93mA    10.45mA
685mV     -14.32mA   -13.89mA   -14.32mA
2.225V    -22.62mA   -21.94mA   -22.62mA
2.665V    -53.2mA    -51.6mA    -53.2mA
2.885V    -109mA     -105.7mA   -109mA
3.6V      -517.6mA   -502.1mA   -517.6mA
[Ramp]
| variable   typ   min   max
dV/dt_r   0.511/1.671n   0.485/1.607n   0.525/1.927n
dV/dt_f   0.483/2.308n   0.465/2.265n   0.487/2.476n
R_load = 50.000
[Rising Waveform]
R_fixture = 50.000
V_fixture = 0.000
V_fixture_min = 0.000
V_fixture_max = 0.000
|  time   V(typ)   V(min)   V(max)
0s        106.1uV    3.545mV    3.492mV
899ps     9.928mV    2.246mV    11.64mV
1.492ns   119.2mV    57.4mV     86.21mV
2.011ns   292.2mV    184mV      206.1mV
2.915ns   585.7mV    499.4mV    462.9mV
3.459ns   702.8mV    641.2mV    620.4mV
4.095ns   781.2mV    729.4mV    760.3mV
4.679ns   814.6mV    767.6mV    824.2mV
5.581ns   835.1mV    793.2mV    859.7mV
10ns      848.4mV    811.9mV    878.4mV
[Rising Waveform]
R_fixture = 50.000
V_fixture = 1.800
V_fixture_min = 1.710
V_fixture_max = 1.890
|  time   V(typ)   V(min)   V(max)
0s        994.3mV    935.1mV    1.078V
333ps     994.8mV    935.1mV    1.079V
431ps     991.1mV    935.4mV    1.362V
548ps     1.294V     931.7mV    1.515V
639ps     1.421V     931.2mV    1.586V
692ps     1.469V     998.7mV    1.618V
792ps     1.536V     1.266V     1.666V
942ps     1.607V     1.419V     1.718V
1.708ns   1.752V     1.644V     1.84V
10ns      1.8V       1.71V      1.89V
[Falling Waveform]
R_fixture = 50.000
V_fixture = 1.800
V_fixture_min = 1.710
V_fixture_max = 1.890
|  time   V(typ)   V(min)   V(max)
0s        1.8V       1.71V      1.89V
512ps     1.812V     1.71V      1.895V
791ps     1.798V     1.721V     1.887V
1.35ns    1.731V     1.665V     1.827V
1.873ns   1.628V     1.569V     1.731V
3.519ns   1.25V      1.188V     1.379V
4.69ns    1.09V      1.029V     1.199V
5.39ns    1.046V     985.6mV    1.141V
6.404ns   1.016V     956.5mV    1.102V
10ns      994.3mV    935.1mV    1.078V
[Falling Waveform]
R_fixture = 50.000
V_fixture = 0.000
V_fixture_min = 0.000
V_fixture_max = 0.000
|  time   V(typ)   V(min)   V(max)
0s        848.4mV    811.9mV    878.4mV
343ps     847.9mV    811.7mV    876mV
432ps     843.6mV    811.9mV    607.3mV
542ps     526.7mV    812.3mV    429.4mV
641ps     385.3mV    806.5mV    338.8mV
811ps     258.1mV    449mV      240.8mV
941ps     196.5mV    311.1mV    189.9mV
1.281ns   93.32mV    143.7mV    97.75mV
1.641ns   46.25mV    63.85mV    50.04mV
10ns      106.1uV    3.545mV    3.492mV
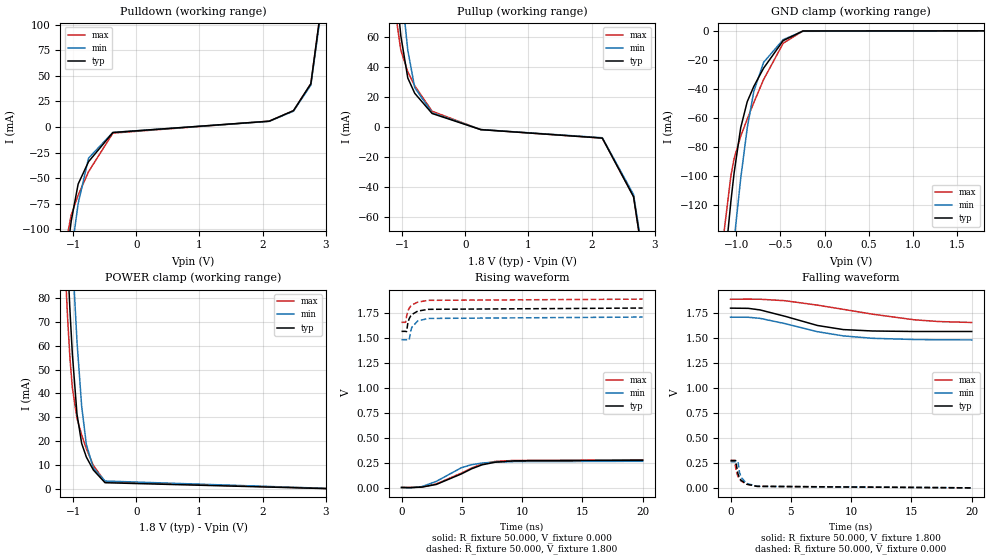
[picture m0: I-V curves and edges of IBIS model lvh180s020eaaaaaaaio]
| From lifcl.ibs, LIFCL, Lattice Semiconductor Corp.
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[Model] lvh180s020eaaaaaaaio
Model_type I/O
Polarity   Non-Inverting
Enable   Active-Low
Vinl =  0.630V
Vinh =  1.170V
Vmeas =  0.900V
Cref =  0.0F
Rref =  1.000M
Vref =  0.0V
C_comp   5.000pF   4.000pF   5.500pF
[Temperature Range]   25.000   0.125k   -40.000
[Voltage Range]   1.800V   1.710V   1.890V
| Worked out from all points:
|   slope of the pulldown table from 0 to 0.27 V, typ, clamps not added: 112 ohm
|   slope of the pullup table from 0 to 0.27 V, typ, clamps not added: 139 ohm
|   GND clamp passes 1 mA (typ) near -0.32 V on its own axis
|   POWER clamp passes 1 mA (typ) near -0.38 V on its own axis
|   rising waveform, R_fixture 50.000, V_fixture 0.000: 20-80 % time 2.97ns typ, 2.5ns min, 2.94ns max; typ from 0.006 V to 0.279 V
|   rising waveform, R_fixture 50.000, V_fixture 1.800: 20-80 % time 569ps typ, 543ps min, 612ps max; typ from 1.57 V to 1.8 V
|   falling waveform, R_fixture 50.000, V_fixture 1.800: 20-80 % time 4.25ns typ, 5.07ns min, 7.3ns max; typ from 1.8 V to 1.57 V
|   falling waveform, R_fixture 50.000, V_fixture 0.000: 20-80 % time 563ps typ, 550ps min, 605ps max; typ from 0.279 V to 0.006 V
[GND_clamp]
|Voltage   I(typ)   I(min)   I(max)
-1.8V     -676.5mA   -711.8mA   -657.4mA
-1.171V   -188.8mA   -241.8mA   -160mA
-1.134V   -163.6mA   -216.3mA   -136.9mA
-1.06V    -117.6mA   -167.3mA   -100mA
-1.023V   -97.67mA   -144.1mA   -87.78mA
-949mV    -66.77mA   -101.8mA   -72.6mA
-875mV    -48.8mA    -66.89mA   -60.78mA
-801mV    -38.33mA   -41.86mA   -49.49mA
-690mV    -25.71mA   -21.72mA   -33.55mA
-468mV    -6.724mA   -6.036mA   -8.541mA
-246mV    -145.3uA   -325.1uA   -81.62uA
1.8V      0A         0A         0A
[POWER_clamp]
|Voltage   I(typ)   I(min)   I(max)
-1.8V     627.7mA    654.9mA    614.1mA
-1.16V    141.5mA    189mA      114.4mA
-1.123V   117.5mA    164.8mA    91.5mA
-1.086V   95.05mA    141.5mA    71.26mA
-1.049V   74.59mA    119.2mA    54.66mA
-1.012V   56.78mA    98.27mA    42.5mA
-938mV    31.33mA    61.69mA    29.59mA
-864mV    19.12mA    34.68mA    22.65mA
-790mV    13.42mA    18.68mA    16.91mA
-679mV    8.018mA    8.826mA    9.955mA
-494mV    2.695mA    3.4mA      3.109mA
3.6V      -185.9uA   -195.7uA   -188.2uA
[Pulldown]
|Voltage   I(typ)   I(min)   I(max)
-1.8V     -596.5mA   -588.3mA   -599.3mA
-1.14V    -149.6mA   -183.8mA   -130.4mA
-1.085V   -118.9mA   -153.6mA   -104mA
-1.03V    -92.1mA    -124.8mA   -85.94mA
-920mV    -55.8mA    -74.97mA   -66.68mA
-755mV    -33.91mA   -30.48mA   -43.69mA
-370mV    -5.454mA   -5.346mA   -6.032mA
2.105V    5.612mA    5.443mA    5.612mA
2.49V     15.89mA    15.41mA    15.89mA
2.765V    42.2mA     40.93mA    42.2mA
2.985V    143.4mA    139.1mA    143.4mA
3.6V      555mA      538.3mA    555mA
[Pullup]
|Voltage   I(typ)   I(min)   I(max)
-1.8V     556.2mA    580.5mA    544.4mA
-1.13V    112.6mA    153.6mA    91.2mA
-1.075V   84.2mA     123.5mA    67.08mA
-1.02V    60.53mA    95.7mA     51.03mA
-910mV    32.55mA    51.06mA    36.67mA
-800mV    22.37mA    26.11mA    27.37mA
-525mV    8.937mA    9.479mA    10.43mA
245mV     -1.782mA   -1.729mA   -1.782mA
2.17V     -7.419mA   -7.197mA   -7.419mA
2.665V    -46.41mA   -45.02mA   -46.41mA
2.83V     -92.1mA    -89.3mA    -92.1mA
3.6V      -597.4mA   -579.5mA   -597.4mA
[Ramp]
| variable   typ   min   max
dV/dt_r   0.163/3.011n   0.157/2.520n   0.165/2.968n
dV/dt_f   0.140/4.262n   0.136/5.079n   0.140/7.314n
R_load = 50.000
[Rising Waveform]
R_fixture = 50.000
V_fixture = 0.000
V_fixture_min = 0.000
V_fixture_max = 0.000
|  time   V(typ)   V(min)   V(max)
0s        6.342mV    6.42mV     6.602mV
726ps     5.666mV    2.619mV    6.141mV
1.678ns   9.978mV    15.06mV    10.91mV
2.88ns    36.55mV    66.93mV    41.63mV
4.957ns   141.6mV    203.4mV    149.8mV
5.794ns   192.2mV    234mV      200.3mV
6.68ns    232.8mV    250.8mV    242.3mV
7.795ns   259.5mV    260.3mV    267.1mV
9.425ns   272.9mV    265.2mV    277.2mV
20ns      278.7mV    268.2mV    281mV
[Rising Waveform]
R_fixture = 50.000
V_fixture = 1.800
V_fixture_min = 1.710
V_fixture_max = 1.890
|  time   V(typ)   V(min)   V(max)
0s        1.567V     1.483V     1.657V
334ps     1.567V     1.483V     1.657V
420ps     1.564V     1.483V     1.718V
528ps     1.653V     1.483V     1.77V
636ps     1.694V     1.481V     1.798V
766ps     1.722V     1.572V     1.819V
858ps     1.735V     1.608V     1.83V
1.337ns   1.769V     1.67V      1.859V
2.207ns   1.787V     1.696V     1.877V
20ns      1.8V       1.71V      1.889V
[Falling Waveform]
R_fixture = 50.000
V_fixture = 1.800
V_fixture_min = 1.710
V_fixture_max = 1.890
|  time   V(typ)   V(min)   V(max)
0s        1.8V       1.71V      1.889V
1.478ns   1.798V     1.709V     1.89V
2.458ns   1.782V     1.698V     1.889V
4.539ns   1.718V     1.645V     1.874V
7.206ns   1.627V     1.565V     1.83V
9.356ns   1.586V     1.523V     1.788V
11.77ns   1.572V     1.499V     1.74V
15.21ns   1.567V     1.487V     1.684V
17.31ns   1.567V     1.484V     1.666V
20ns      1.567V     1.483V     1.657V
[Falling Waveform]
R_fixture = 50.000
V_fixture = 0.000
V_fixture_min = 0.000
V_fixture_max = 0.000
|  time   V(typ)   V(min)   V(max)
0s        278.7mV    268.2mV    281mV
336ps     278.2mV    268mV      281.8mV
426ps     279.2mV    268.2mV    206.8mV
499ps     223.6mV    267.8mV    160.4mV
615ps     145.8mV    270.5mV    120mV
745ps     105.7mV    160.8mV    92.59mV
874ps     82.09mV    112mV      74.67mV
1.32ns    43.83mV    51.73mV    43.03mV
2.195ns   21.07mV    21.87mV    22.03mV
20ns      6.342mV    6.42mV     6.602mV
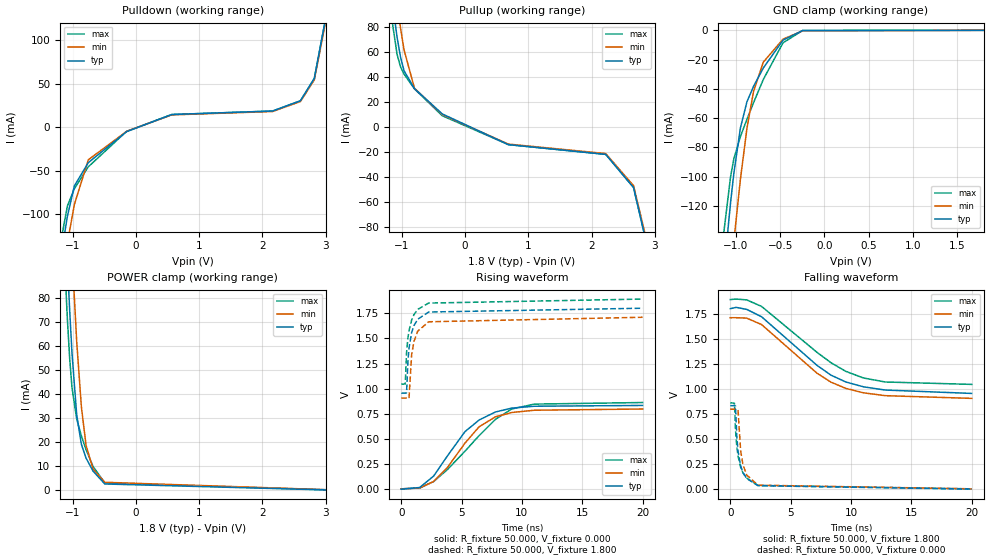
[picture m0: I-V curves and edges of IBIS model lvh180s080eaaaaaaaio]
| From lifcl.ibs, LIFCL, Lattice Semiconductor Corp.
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[Model] lvh180s080eaaaaaaaio
Model_type I/O
Polarity   Non-Inverting
Enable   Active-Low
Vinl =  0.630V
Vinh =  1.170V
Vmeas =  0.900V
Cref =  0.0F
Rref =  1.000M
Vref =  0.0V
C_comp   5.000pF   4.000pF   5.500pF
[Temperature Range]   25.000   0.125k   -40.000
[Voltage Range]   1.800V   1.710V   1.890V
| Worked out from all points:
|   slope of the pulldown table from 0 to 0.27 V, typ, clamps not added: 31.8 ohm
|   slope of the pullup table from 0 to 0.27 V, typ, clamps not added: 40.7 ohm
|   GND clamp passes 1 mA (typ) near -0.32 V on its own axis
|   POWER clamp passes 1 mA (typ) near -0.38 V on its own axis
|   rising waveform, R_fixture 50.000, V_fixture 0.000: 20-80 % time 3.27ns typ, 3.18ns min, 4.11ns max; typ from 0 V to 0.833 V
|   rising waveform, R_fixture 50.000, V_fixture 1.800: 20-80 % time 567ps typ, 550ps min, 610ps max; typ from 0.955 V to 1.8 V
|   falling waveform, R_fixture 50.000, V_fixture 1.800: 20-80 % time 5ns typ, 4.76ns min, 5.23ns max; typ from 1.8 V to 0.955 V
|   falling waveform, R_fixture 50.000, V_fixture 0.000: 20-80 % time 555ps typ, 548ps min, 599ps max; typ from 0.833 V to 0 V
[GND_clamp]
|Voltage   I(typ)   I(min)   I(max)
-1.8V     -676.5mA   -711.8mA   -657.4mA
-1.171V   -188.8mA   -241.8mA   -160mA
-1.134V   -163.6mA   -216.3mA   -136.9mA
-1.06V    -117.6mA   -167.3mA   -100mA
-1.023V   -97.67mA   -144.1mA   -87.78mA
-949mV    -66.77mA   -101.8mA   -72.6mA
-875mV    -48.8mA    -66.89mA   -60.78mA
-801mV    -38.33mA   -41.86mA   -49.49mA
-690mV    -25.71mA   -21.72mA   -33.55mA
-468mV    -6.724mA   -6.036mA   -8.541mA
-246mV    -145.3uA   -325.1uA   -81.62uA
1.8V      0A         0A         0A
[POWER_clamp]
|Voltage   I(typ)   I(min)   I(max)
-1.8V     627.7mA    654.9mA    614.1mA
-1.16V    141.5mA    189mA      114.4mA
-1.123V   117.5mA    164.8mA    91.5mA
-1.086V   95.05mA    141.5mA    71.26mA
-1.049V   74.59mA    119.2mA    54.66mA
-1.012V   56.78mA    98.27mA    42.5mA
-938mV    31.33mA    61.69mA    29.59mA
-864mV    19.12mA    34.68mA    22.65mA
-790mV    13.42mA    18.68mA    16.91mA
-679mV    8.018mA    8.826mA    9.955mA
-494mV    2.695mA    3.4mA      3.109mA
3.6V      -185.9uA   -195.7uA   -188.2uA
[Pulldown]
|Voltage   I(typ)   I(min)   I(max)
-1.8V     -480.5mA   -490mA     -478mA
-1.195V   -151.2mA   -182.8mA   -133.3mA
-1.085V   -102.1mA   -132.8mA   -90.4mA
-975mV    -67.35mA   -88.7mA    -70.58mA
-755mV    -40.72mA   -37.48mA   -45.52mA
-150mV    -5.225mA   -4.853mA   -4.857mA
565mV     14.48mA    14.05mA    14.48mA
2.16V     18.47mA    17.92mA    18.47mA
2.6V      30.21mA    29.31mA    30.21mA
2.82V     55.87mA    54.2mA     55.87mA
2.985V    119.2mA    115.6mA    119.2mA
3.6V      446.7mA    433.3mA    446.7mA
[Pullup]
|Voltage   I(typ)   I(min)   I(max)
-1.8V     421.6mA    440.1mA    411.1mA
-1.185V   114.2mA    144.4mA    95.5mA
-1.075V   71.7mA     99.1mA     58.18mA
-1.02V    55.92mA    79mA       48.12mA
-965mV    45.05mA    61.76mA    42.4mA
-800mV    30.75mA    31.07mA    30.54mA
-360mV    10.55mA    9.977mA    9.103mA
685mV     -13.96mA   -13.54mA   -13.96mA
2.225V    -21.74mA   -21.09mA   -21.74mA
2.665V    -48.21mA   -46.76mA   -48.21mA
2.885V    -95.9mA    -93mA      -95.9mA
3.6V      -451.4mA   -437.9mA   -451.4mA
[Ramp]
| variable   typ   min   max
dV/dt_r   0.502/3.285n   0.477/3.227n   0.515/4.120n
dV/dt_f   0.502/5.030n   0.483/4.778n   0.507/5.240n
R_load = 50.000
[Rising Waveform]
R_fixture = 50.000
V_fixture = 0.000
V_fixture_min = 0.000
V_fixture_max = 0.000
|  time   V(typ)   V(min)   V(max)
0s        110.8uV    3.327mV    3.216mV
1.528ns   16.44mV    11.44mV    12.02mV
2.684ns   130.7mV    76.52mV    75.91mV
3.829ns   331.5mV    216.3mV    195.6mV
5.28ns    572.3mV    458.1mV    377.6mV
6.454ns   688.4mV    620.9mV    533.2mV
7.806ns   768.1mV    719.8mV    695.1mV
9.159ns   806.4mV    762.5mV    797.5mV
11.02ns   825mV      785.2mV    846.2mV
20ns      832.9mV    797.5mV    862mV
[Rising Waveform]
R_fixture = 50.000
V_fixture = 1.800
V_fixture_min = 1.710
V_fixture_max = 1.890
|  time   V(typ)   V(min)   V(max)
0s        954.9mV    905.5mV    1.045V
333ps     955.3mV    905.6mV    1.046V
441ps     959mV      906mV      1.359V
548ps     1.264V     902.2mV    1.499V
642ps     1.403V     902.7mV    1.575V
861ps     1.557V     1.337V     1.682V
1.052ns   1.626V     1.469V     1.736V
1.362ns   1.69V      1.571V     1.788V
2.268ns   1.762V     1.665V     1.851V
20ns      1.8V       1.71V      1.891V
[Falling Waveform]
R_fixture = 50.000
V_fixture = 1.800
V_fixture_min = 1.710
V_fixture_max = 1.890
|  time   V(typ)   V(min)   V(max)
0s        1.8V       1.71V      1.891V
491ps     1.813V     1.71V      1.896V
1.36ns    1.793V     1.706V     1.888V
2.59ns    1.72V      1.642V     1.823V
7.184ns   1.235V     1.157V     1.365V
8.347ns   1.137V     1.067V     1.261V
9.575ns   1.069V     1.005V     1.175V
11.03ns   1.021V     961.1mV    1.109V
12.84ns   988.6mV    932.6mV    1.069V
20ns      954.9mV    905.5mV    1.045V
[Falling Waveform]
R_fixture = 50.000
V_fixture = 0.000
V_fixture_min = 0.000
V_fixture_max = 0.000
|  time   V(typ)   V(min)   V(max)
0s        832.9mV    797.5mV    862mV
346ps     832.5mV    797.3mV    857.5mV
432ps     829.6mV    797.5mV    596.2mV
541ps     529mV      797.8mV    422.6mV
642ps     382.4mV    792.2mV    331.9mV
861ps     232.4mV    381mV      217.9mV
1.052ns   165.5mV    244.5mV    162.6mV
1.362ns   107mV      141mV      110.4mV
2.3ns     34.55mV    40.06mV    37.56mV
20ns      110.8uV    3.327mV    3.216mV
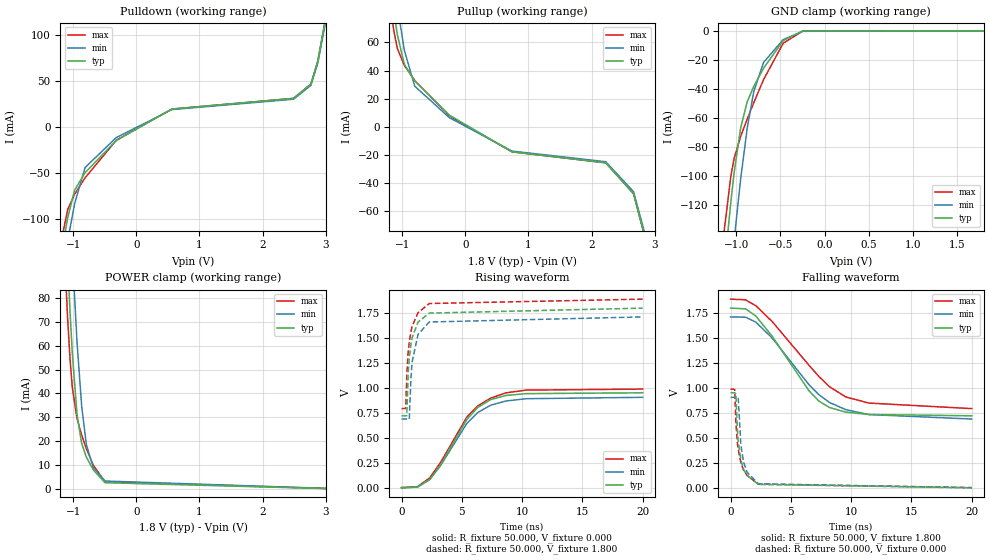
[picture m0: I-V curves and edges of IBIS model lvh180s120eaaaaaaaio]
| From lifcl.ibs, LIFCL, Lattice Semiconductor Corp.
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[Model] lvh180s120eaaaaaaaio
Model_type I/O
Polarity   Non-Inverting
Enable   Active-Low
Vinl =  0.630V
Vinh =  1.170V
Vmeas =  0.900V
Cref =  0.0F
Rref =  1.000M
Vref =  0.0V
C_comp   5.000pF   4.000pF   5.500pF
[Temperature Range]   25.000   0.125k   -40.000
[Voltage Range]   1.800V   1.710V   1.890V
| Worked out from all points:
|   slope of the pulldown table from 0 to 0.27 V, typ, clamps not added: 23.9 ohm
|   slope of the pullup table from 0 to 0.27 V, typ, clamps not added: 33.9 ohm
|   GND clamp passes 1 mA (typ) near -0.32 V on its own axis
|   POWER clamp passes 1 mA (typ) near -0.38 V on its own axis
|   rising waveform, R_fixture 50.000, V_fixture 0.000: 20-80 % time 2.91ns typ, 3.03ns min, 3.08ns max; typ from 0 V to 0.952 V
|   rising waveform, R_fixture 50.000, V_fixture 1.800: 20-80 % time 567ps typ, 549ps min, 609ps max; typ from 0.722 V to 1.8 V
|   falling waveform, R_fixture 50.000, V_fixture 1.800: 20-80 % time 3.69ns typ, 4.32ns min, 4.79ns max; typ from 1.8 V to 0.722 V
|   falling waveform, R_fixture 50.000, V_fixture 0.000: 20-80 % time 553ps typ, 548ps min, 597ps max; typ from 0.952 V to 0 V
[GND_clamp]
|Voltage   I(typ)   I(min)   I(max)
-1.8V     -676.5mA   -711.8mA   -657.4mA
-1.171V   -188.8mA   -241.8mA   -160mA
-1.134V   -163.6mA   -216.3mA   -136.9mA
-1.06V    -117.6mA   -167.3mA   -100mA
-1.023V   -97.67mA   -144.1mA   -87.78mA
-949mV    -66.77mA   -101.8mA   -72.6mA
-875mV    -48.8mA    -66.89mA   -60.78mA
-801mV    -38.33mA   -41.86mA   -49.49mA
-690mV    -25.71mA   -21.72mA   -33.55mA
-468mV    -6.724mA   -6.036mA   -8.541mA
-246mV    -145.3uA   -325.1uA   -81.62uA
1.8V      0A         0A         0A
[POWER_clamp]
|Voltage   I(typ)   I(min)   I(max)
-1.8V     627.7mA    654.9mA    614.1mA
-1.16V    141.5mA    189mA      114.4mA
-1.123V   117.5mA    164.8mA    91.5mA
-1.086V   95.05mA    141.5mA    71.26mA
-1.049V   74.59mA    119.2mA    54.66mA
-1.012V   56.78mA    98.27mA    42.5mA
-938mV    31.33mA    61.69mA    29.59mA
-864mV    19.12mA    34.68mA    22.65mA
-790mV    13.42mA    18.68mA    16.91mA
-679mV    8.018mA    8.826mA    9.955mA
-494mV    2.695mA    3.4mA      3.109mA
3.6V      -185.9uA   -195.7uA   -188.2uA
[Pulldown]
|Voltage   I(typ)   I(min)   I(max)
-1.8V     -446.5mA   -453mA     -445.9mA
-1.195V   -143mA     -169.9mA   -127.2mA
-1.085V   -98.6mA    -123.8mA   -89.9mA
-975mV    -68.8mA    -83.6mA    -73.2mA
-810mV    -49.78mA   -44.19mA   -55.42mA
-315mV    -14.76mA   -11.51mA   -14.36mA
565mV     19.49mA    18.9mA     19.49mA
2.49V     31.09mA    30.16mA    31.09mA
2.765V    46.6mA     45.2mA     46.6mA
2.875V    71.6mA     69.5mA     71.6mA
2.985V    112.9mA    109.5mA    112.9mA
3.6V      415mA      402.5mA    415mA
[Pullup]
|Voltage   I(typ)   I(min)   I(max)
-1.8V     361.7mA    376.4mA    352.5mA
-1.185V   100.5mA    124.5mA    85mA
-1.13V    81.5mA     104.6mA    68mA
-1.075V   65.4mA     86mA       55.66mA
-965mV    44.55mA    54.52mA    43.73mA
-800mV    32.55mA    28.95mA    33.01mA
-250mV    8.31mA     6.527mA    7.798mA
740mV     -17.68mA   -17.15mA   -17.68mA
2.225V    -25.47mA   -24.71mA   -25.47mA
2.665V    -47.43mA   -46.01mA   -47.43mA
2.885V    -85.1mA    -82.5mA    -85.1mA
3.6V      -386.6mA   -375mA     -386.6mA
[Ramp]
| variable   typ   min   max
dV/dt_r   0.573/2.926n   0.543/3.041n   0.592/3.099n
dV/dt_f   0.643/3.715n   0.613/4.333n   0.659/4.805n
R_load = 50.000
[Rising Waveform]
R_fixture = 50.000
V_fixture = 0.000
V_fixture_min = 0.000
V_fixture_max = 0.000
|  time   V(typ)   V(min)   V(max)
0s        102.6uV    1.478mV    2.915mV
1.327ns   7.795mV    8.304mV    12.06mV
2.337ns   84.91mV    82mV       100mV
3.249ns   232.3mV    225.7mV    256.3mV
5.417ns   685.5mV    645.3mV    708.8mV
6.304ns   803.6mV    752.8mV    819.5mV
7.374ns   883.2mV    827.1mV    897.7mV
8.655ns   925mV      869.9mV    951.4mV
10.34ns   943.7mV    892.8mV    979.1mV
20ns      952mV      906.8mV    989.2mV
[Rising Waveform]
R_fixture = 50.000
V_fixture = 1.800
V_fixture_min = 1.710
V_fixture_max = 1.890
|  time   V(typ)   V(min)   V(max)
0s        721.7mV    689.3mV    793.7mV
346ps     721.6mV    689.3mV    795.6mV
431ps     723.4mV    689.6mV    1.111V
549ps     1.134V     685.7mV    1.356V
642ps     1.302V     687.6mV    1.461V
791ps     1.447V     1.116V     1.572V
881ps     1.505V     1.262V     1.618V
1.369ns   1.66V      1.537V     1.754V
2.303ns   1.75V      1.661V     1.846V
20ns      1.8V       1.712V     1.89V
[Falling Waveform]
R_fixture = 50.000
V_fixture = 1.800
V_fixture_min = 1.710
V_fixture_max = 1.890
|  time   V(typ)   V(min)   V(max)
0s        1.8V       1.712V     1.89V
1.245ns   1.793V     1.709V     1.883V
2.108ns   1.72V      1.659V     1.823V
3.47ns    1.515V     1.498V     1.663V
6.51ns    971.5mV    1.032V     1.227V
7.325ns   869.4mV    933mV      1.116V
8.215ns   804.3mV    854.5mV    1.012V
9.549ns   758.8mV    783.6mV    910.9mV
11.47ns   734.5mV    734.1mV    849.2mV
20ns      721.7mV    689.3mV    793.7mV
[Falling Waveform]
R_fixture = 50.000
V_fixture = 0.000
V_fixture_min = 0.000
V_fixture_max = 0.000
|  time   V(typ)   V(min)   V(max)
0s        952mV      906.8mV    989.2mV
344ps     951.7mV    906.6mV    985.9mV
446ps     943.6mV    906.8mV    644.8mV
565ps     595.9mV    908.6mV    454.4mV
632ps     474.9mV    905.8mV    387.7mV
862ps     275.4mV    426.5mV    247.9mV
1.075ns   187.8mV    262.2mV    179.2mV
1.361ns   125mV      157.7mV    125.7mV
2.305ns   34.49mV    40.92mV    37.77mV
20ns      102.6uV    1.478mV    2.915mV
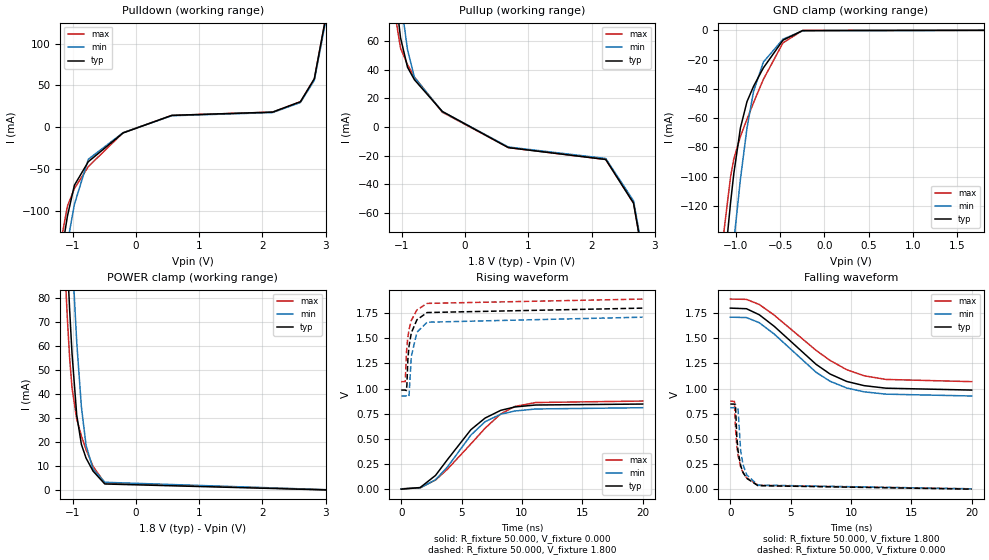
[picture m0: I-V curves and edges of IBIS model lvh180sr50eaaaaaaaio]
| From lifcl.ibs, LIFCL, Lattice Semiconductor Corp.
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[Model] lvh180sr50eaaaaaaaio
Model_type I/O
Polarity   Non-Inverting
Enable   Active-Low
Vinl =  0.630V
Vinh =  1.170V
Vmeas =  0.900V
Cref =  0.0F
Rref =  1.000M
Vref =  0.0V
C_comp   5.000pF   4.000pF   5.500pF
[Temperature Range]   25.000   0.125k   -40.000
[Voltage Range]   1.800V   1.710V   1.890V
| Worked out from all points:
|   slope of the pulldown table from 0 to 0.27 V, typ, clamps not added: 32.7 ohm
|   slope of the pullup table from 0 to 0.27 V, typ, clamps not added: 39.8 ohm
|   GND clamp passes 1 mA (typ) near -0.32 V on its own axis
|   POWER clamp passes 1 mA (typ) near -0.38 V on its own axis
|   rising waveform, R_fixture 50.000, V_fixture 0.000: 20-80 % time 3.53ns typ, 3.26ns min, 4.11ns max; typ from 0 V to 0.846 V
|   rising waveform, R_fixture 50.000, V_fixture 1.800: 20-80 % time 567ps typ, 549ps min, 610ps max; typ from 0.985 V to 1.8 V
|   falling waveform, R_fixture 50.000, V_fixture 1.800: 20-80 % time 4.76ns typ, 4.57ns min, 5.22ns max; typ from 1.8 V to 0.985 V
|   falling waveform, R_fixture 50.000, V_fixture 0.000: 20-80 % time 555ps typ, 547ps min, 599ps max; typ from 0.846 V to 0 V
[GND_clamp]
|Voltage   I(typ)   I(min)   I(max)
-1.8V     -676.5mA   -711.8mA   -657.4mA
-1.171V   -188.8mA   -241.8mA   -160mA
-1.134V   -163.6mA   -216.3mA   -136.9mA
-1.06V    -117.6mA   -167.3mA   -100mA
-1.023V   -97.67mA   -144.1mA   -87.78mA
-949mV    -66.77mA   -101.8mA   -72.6mA
-875mV    -48.8mA    -66.89mA   -60.78mA
-801mV    -38.33mA   -41.86mA   -49.49mA
-690mV    -25.71mA   -21.72mA   -33.55mA
-468mV    -6.724mA   -6.036mA   -8.541mA
-246mV    -145.3uA   -325.1uA   -81.62uA
1.8V      0A         0A         0A
[POWER_clamp]
|Voltage   I(typ)   I(min)   I(max)
-1.8V     627.7mA    654.9mA    614.1mA
-1.16V    141.5mA    189mA      114.4mA
-1.123V   117.5mA    164.8mA    91.5mA
-1.086V   95.05mA    141.5mA    71.26mA
-1.049V   74.59mA    119.2mA    54.66mA
-1.012V   56.78mA    98.27mA    42.5mA
-938mV    31.33mA    61.69mA    29.59mA
-864mV    19.12mA    34.68mA    22.65mA
-790mV    13.42mA    18.68mA    16.91mA
-679mV    8.018mA    8.826mA    9.955mA
-494mV    2.695mA    3.4mA      3.109mA
3.6V      -185.9uA   -195.7uA   -188.2uA
[Pulldown]
|Voltage   I(typ)   I(min)   I(max)
-1.8V     -505.2mA   -515.5mA   -503.2mA
-1.195V   -158.7mA   -192mA     -140.2mA
-1.085V   -106.7mA   -139.2mA   -94.7mA
-975mV    -69.7mA    -92.7mA    -73.71mA
-755mV    -41.44mA   -38.5mA    -47.33mA
-205mV    -6.974mA   -6.675mA   -6.699mA
565mV     14.08mA    13.66mA    14.08mA
2.16V     18.02mA    17.48mA    18.02mA
2.6V      30.45mA    29.53mA    30.45mA
2.82V     57.91mA    56.17mA    57.91mA
2.985V    124.9mA    121.2mA    124.9mA
3.6V      469.8mA    455.7mA    469.8mA
[Pullup]
|Voltage   I(typ)   I(min)   I(max)
-1.8V     481.4mA    502.8mA    470.1mA
-1.185V   129.6mA    164.8mA    109.2mA
-1.13V    103.6mA    138mA      85.1mA
-1.02V    62.25mA    89.7mA     55.02mA
-910mV    41.77mA    53.95mA    43.63mA
-800mV    33.02mA    34.6mA     34.93mA
-360mV    10.94mA    10.9mA     10.41mA
685mV     -14.28mA   -13.85mA   -14.28mA
2.225V    -22.54mA   -21.86mA   -22.54mA
2.665V    -53.02mA   -51.43mA   -53.02mA
2.885V    -108.6mA   -105.3mA   -108.6mA
3.6V      -515.8mA   -500.3mA   -515.8mA
[Ramp]
| variable   typ   min   max
dV/dt_r   0.510/3.546n   0.484/3.296n   0.524/4.120n
dV/dt_f   0.489/4.772n   0.470/4.589n   0.493/5.233n
R_load = 50.000
[Rising Waveform]
R_fixture = 50.000
V_fixture = 0.000
V_fixture_min = 0.000
V_fixture_max = 0.000
|  time   V(typ)   V(min)   V(max)
0s        114.2uV    3.504mV    3.477mV
1.569ns   16.32mV    12.96mV    13.56mV
2.839ns   136.8mV    93.66mV    91.12mV
3.828ns   294.2mV    220.7mV    198.9mV
5.77ns    591.5mV    537.8mV    450.1mV
6.945ns   706.9mV    670.8mV    605.8mV
8.246ns   784mV      745.5mV    748.9mV
9.428ns   817.7mV    777.3mV    822.8mV
11.14ns   836.8mV    797.3mV    861.4mV
20ns      846.3mV    810mV      876.2mV
[Rising Waveform]
R_fixture = 50.000
V_fixture = 1.800
V_fixture_min = 1.710
V_fixture_max = 1.890
|  time   V(typ)   V(min)   V(max)
0s        985.2mV    926.4mV    1.069V
333ps     985.6mV    926.5mV    1.069V
429ps     980.4mV    926.7mV    1.352V
468ps     1.036V     927mV      1.417V
548ps     1.287V     922.8mV    1.51V
642ps     1.419V     923.1mV    1.583V
832ps     1.553V     1.318V     1.677V
1.298ns   1.684V     1.56V      1.782V
2.142ns   1.756V     1.66V      1.847V
20ns      1.8V       1.71V      1.89V
[Falling Waveform]
R_fixture = 50.000
V_fixture = 1.800
V_fixture_min = 1.710
V_fixture_max = 1.890
|  time   V(typ)   V(min)   V(max)
0s        1.8V       1.71V      1.89V
1.341ns   1.794V     1.706V     1.887V
2.402ns   1.734V     1.655V     1.836V
3.632ns   1.62V      1.543V     1.731V
7.111ns   1.241V     1.162V     1.38V
8.267ns   1.145V     1.073V     1.28V
9.645ns   1.071V     1.006V     1.188V
11.1ns    1.029V     967.5mV    1.127V
12.9ns    1.004V     944.7mV    1.091V
20ns      985.2mV    926.4mV    1.069V
[Falling Waveform]
R_fixture = 50.000
V_fixture = 0.000
V_fixture_min = 0.000
V_fixture_max = 0.000
|  time   V(typ)   V(min)   V(max)
0s        846.3mV    810mV      876.2mV
346ps     845.9mV    809.8mV    871.6mV
429ps     844mV      810mV      613.7mV
542ps     525.6mV    810.4mV    428.5mV
641ps     384.6mV    804.8mV    338.2mV
861ps     234.3mV    382.5mV    221.7mV
1.051ns   167.4mV    247mV      165.7mV
1.362ns   108.1mV    142.5mV    112.4mV
2.291ns   34.92mV    40.84mV    38.64mV
20ns      114.2uV    3.504mV    3.477mV
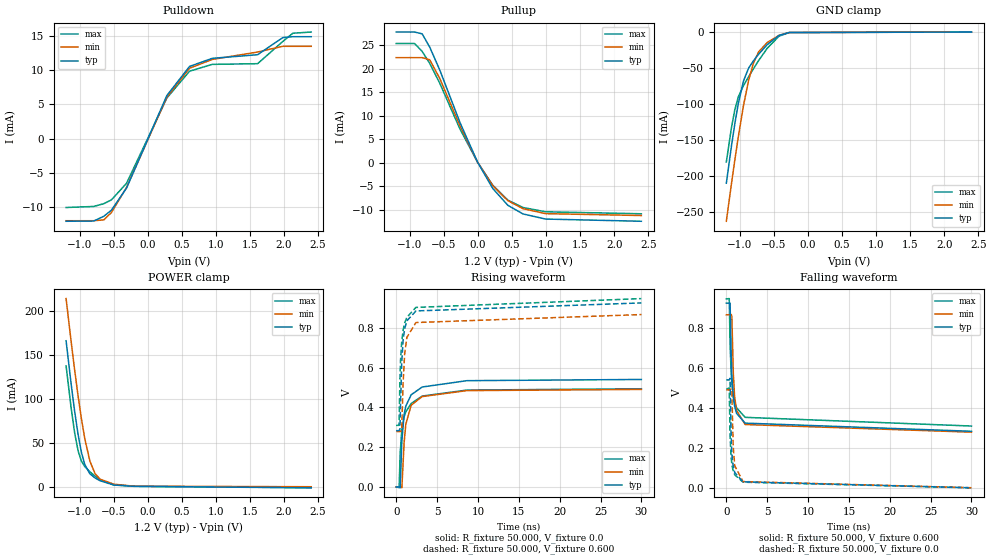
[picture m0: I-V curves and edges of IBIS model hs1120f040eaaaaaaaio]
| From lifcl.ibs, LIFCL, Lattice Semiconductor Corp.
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|Model hs1120f040eaaaaaaaio
[Model] hs1120f040eaaaaaaaio
| Clamp models do not include dynamic input termination. Please refer to
| the hs1120axxxeaaaaaaain model for input termination.
Model_type I/O
Polarity   Non-Inverting
Enable   Active-Low
Vinl =  0.500V
Vinh =  0.700V
Vmeas =  0.600V
Cref =  20.000pF
Rref =  50.000
Vref =  0.600V
C_comp   5.000pF   4.000pF   5.500pF
[Temperature Range]   25.000   0.125k   -40.000
[Voltage Range]   1.200V   1.140V   1.260V
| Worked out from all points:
|   slope of the pulldown table from 0 to 0.18 V, typ, clamps not added: 43.8 ohm
|   slope of the pullup table from 0 to 0.18 V, typ, clamps not added: 38.9 ohm
|   GND clamp passes 1 mA (typ) near -0.31 V on its own axis
|   POWER clamp passes 1 mA (typ) near -0.43 V on its own axis
|   rising waveform, R_fixture 50.000, V_fixture 0.0: 20-80 % time 799ps typ, 788ps min, 953ps max; typ from 0 V to 0.541 V
|   rising waveform, R_fixture 50.000, V_fixture 0.600: 20-80 % time 513ps typ, 542ps min, 600ps max; typ from 0.283 V to 0.926 V
|   falling waveform, R_fixture 50.000, V_fixture 0.600: 20-80 % time 469ps typ, 461ps min, 546ps max; typ from 0.926 V to 0.284 V
|   falling waveform, R_fixture 50.000, V_fixture 0.0: 20-80 % time 336ps typ, 355ps min, 366ps max; typ from 0.541 V to 0 V
[Pulldown]
|Voltage   I(typ)   I(min)   I(max)
-1.2V     -12.07mA   -11.99mA   -10.06mA
-793mV    -12.03mA   -11.99mA   -9.906mA
-645mV    -11.33mA   -11.86mA   -9.494mA
-534mV    -10.45mA   -10.79mA   -8.945mA
-312mV    -7.217mA   -7.127mA   -6.523mA
280mV     6.293mA    6.052mA    5.931mA
613mV     10.54mA    10.28mA    9.842mA
946mV     11.72mA    11.56mA    10.84mA
1.612V    12.25mA    12.64mA    10.94mA
1.982V    14.75mA    13.48mA    14.18mA
2.13V     14.88mA    13.48mA    15.39mA
2.4V      14.88mA    13.48mA    15.56mA
[Pullup]
|Voltage   I(typ)   I(min)   I(max)
-1.2V     27.75mA    22.32mA    25.31mA
-930mV    27.75mA    22.32mA    25.31mA
-819mV    27.37mA    22.32mA    23.64mA
-708mV    24.55mA    21.87mA    21.12mA
-560mV    19.68mA    17.9mA     16.88mA
-264mV    8.564mA    7.863mA    7.174mA
-5mV      140.3uA    130.8uA    120.6uA
217mV     -5.427mA   -4.833mA   -4.748mA
439mV     -9.005mA   -8.022mA   -7.904mA
661mV     -10.84mA   -9.72mA    -9.477mA
994mV     -11.93mA   -10.78mA   -10.39mA
2.4V      -12.4mA    -11.18mA   -10.81mA
[GND_clamp]
|Voltage   I(typ)   I(min)   I(max)
-1.2V     -209.6mA   -262.4mA   -180.2mA
-1.125V   -158.2mA   -210.5mA   -132.7mA
-1.075V   -127mA     -177.3mA   -107.7mA
-1.025V   -99.59mA   -145.8mA   -90.14mA
-950mV    -68.44mA   -102.9mA   -74.64mA
-875mV    -50.37mA   -67.7mA    -62.38mA
-800mV    -39.61mA   -42.62mA   -50.65mA
-725mV    -30.63mA   -27.35mA   -39.46mA
-600mV    -17.53mA   -14.58mA   -22.59mA
-425mV    -4.657mA   -4.485mA   -5.636mA
-275mV    -627.9uA   -616.8uA   -678.4uA
2.4V      0A         0A         0A
[POWER_clamp]
|Voltage   I(typ)   I(min)   I(max)
-1.2V     166.3mA    214.4mA    137.7mA
-1.125V   116.5mA    164.9mA    89.12mA
-1.075V   86.21mA    133.5mA    61.64mA
-1.025V   59.86mA    104mA      41.12mA
-975mV    39.03mA    77.38mA    28.98mA
-925mV    24.95mA    54.44mA    22.72mA
-850mV    14.48mA    28.92mA    16.81mA
-775mV    9.774mA    14.73mA    11.95mA
-700mV    6.595mA    8.327mA    7.924mA
-500mV    1.71mA     2.674mA    1.891mA
-200mV    207.6uA    329.9uA    277.5uA
2.4V      -1.508mA   -253.4uA   -1.296mA
[Ramp]
| variable   typ   min   max
dV/dt_r   0.324/0.805n   0.294/0.785n   0.296/0.952n
dV/dt_f   0.322/0.819n   0.306/0.732n   0.310/1.007n
R_load = 50.000
[Rising Waveform]
R_fixture= 50.000
V_fixture= 0.0
V_fixture_min= 0.0
V_fixture_max= 0.0
|time   V(typ)   V(min)   V(max)
0s        4.858uV    227uV      477.5nV
359ps     483.6uV    328uV      -3.417mV
482ps     -4.35mV    376.7uV    168.6mV
693ps     231.8mV    -3.668mV   290.1mV
964ps     362.4mV    221.3mV    352.2mV
1.173ns   406.4mV    315mV      377.8mV
1.828ns   463.6mV    411mV      419.6mV
3.181ns   502.6mV    454.5mV    457.1mV
8.649ns   534.5mV    484.5mV    487.2mV
30ns      540.6mV    490.5mV    493.8mV
[Rising Waveform]
R_fixture= 50.000
V_fixture= 0.600
V_fixture_min= 0.571
V_fixture_max= 0.631
|time   V(typ)   V(min)   V(max)
0s        283mV      278.6mV    309.6mV
348ps     283.2mV    278.7mV    310.1mV
453ps     290.5mV    278.7mV    541.3mV
534ps     420.1mV    278.6mV    640.4mV
673ps     625.1mV    288.7mV    729.4mV
848ps     739.2mV    526.6mV    788.9mV
1.033ns   795.2mV    669.1mV    823.9mV
1.303ns   835.1mV    751.8mV    853.1mV
2.413ns   885mV      826.8mV    902.8mV
30ns      925.5mV    866.9mV    947.1mV
[Falling Waveform]
R_fixture= 50.000
V_fixture= 0.600
V_fixture_min= 0.571
V_fixture_max= 0.631
|time   V(typ)   V(min)   V(max)
0s        926.2mV    867.7mV    947.6mV
356ps     926mV      867.5mV    949mV
458ps     926.9mV    867.6mV    721.4mV
597ps     655.5mV    869.8mV    570mV
673ps     560.3mV    861.2mV    525.1mV
855ps     454.6mV    572.7mV    460.1mV
1.015ns   409.3mV    456.3mV    428.6mV
1.253ns   373.4mV    388mV      401.4mV
2.307ns   324.7mV    317.6mV    353.7mV
30ns      283.8mV    279.4mV    310.1mV
[Falling Waveform]
R_fixture= 50.000
V_fixture= 0.0
V_fixture_min= 0.0
V_fixture_max= 0.0
|time   V(typ)   V(min)   V(max)
0s        541.4mV    491.5mV    494.4mV
351ps     541.2mV    491.2mV    501.3mV
453ps     549.4mV    491.4mV    262.7mV
593ps     252.2mV    496.8mV    150.4mV
663ps     184.5mV    496.4mV    124.1mV
724ps     150.7mV    400.7mV    107.5mV
843ps     110.4mV    205.3mV    85.5mV
1.033ns   76.48mV    110.7mV    65.25mV
2.044ns   30.35mV    31.72mV    28.62mV
30ns      478.9uV    861.5uV    282.2uV
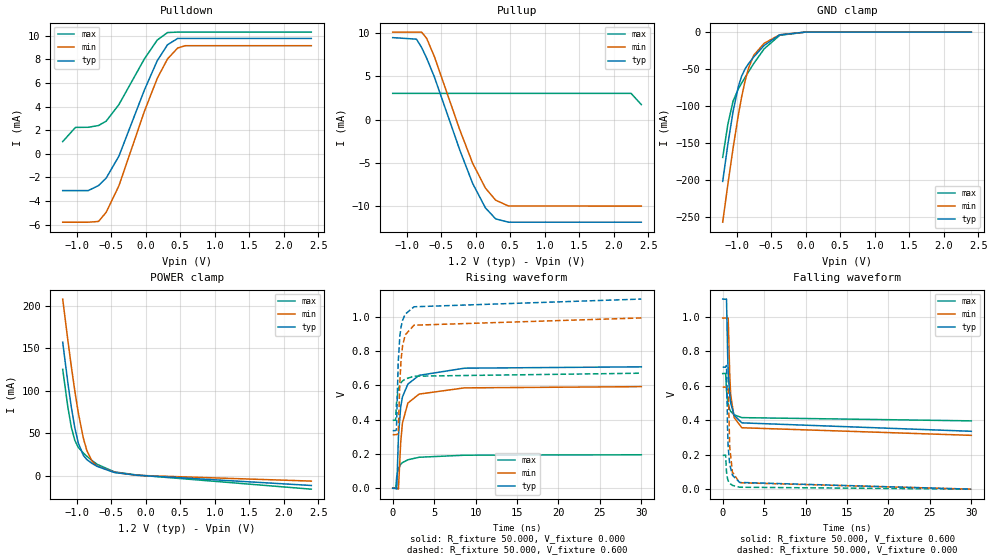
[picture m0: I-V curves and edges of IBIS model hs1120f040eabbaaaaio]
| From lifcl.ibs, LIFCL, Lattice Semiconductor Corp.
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|Model hs1120f040eabbaaaaio
[Model] hs1120f040eabbaaaaio
| Clamp models do not include dynamic input termination. Please refer to
| the hs1120axxxeabbaaaain model for input termination.
Model_type I/O
Polarity   Non-Inverting
Enable   Active-Low
Vinl =  0.500V
Vinh =  0.700V
Vmeas =  0.600V
Cref =  20.000pF
Rref =  50.000
Vref =  0.600V
C_comp   5.000pF   4.000pF   5.500pF
[Temperature Range]   25.000   0.125k   -40.000
[Voltage Range]   1.200V   1.140V   1.260V
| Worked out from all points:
|   slope of the pulldown table from 0 to 0.18 V, typ, clamps not added: 76.5 ohm
|   slope of the pullup table from 0 to 0.18 V, typ, clamps not added: 72.6 ohm
|   GND clamp passes 1 mA (typ) near -0.14 V on its own axis
|   POWER clamp passes 1 mA (typ) near -0.17 V on its own axis
|   rising waveform, R_fixture 50.000, V_fixture 0.000: 20-80 % time 799ps typ, 788ps min, 953ps max; typ from 0 V to 0.709 V
|   rising waveform, R_fixture 50.000, V_fixture 0.600: 20-80 % time 513ps typ, 541ps min, 600ps max; typ from 0.336 V to 1.1 V
|   falling waveform, R_fixture 50.000, V_fixture 0.600: 20-80 % time 469ps typ, 461ps min, 546ps max; typ from 1.1 V to 0.336 V
|   falling waveform, R_fixture 50.000, V_fixture 0.000: 20-80 % time 336ps typ, 355ps min, 366ps max; typ from 0.709 V to 0 V
[Pulldown]
|Voltage   I(typ)   I(min)   I(max)
-1.2V     -3.123mA   -5.801mA   1.03mA
-1.015V   -3.123mA   -5.801mA   2.234mA
-830mV    -3.123mA   -5.801mA   2.243mA
-682mV    -2.698mA   -5.74mA    2.39mA
-571mV    -2.069mA   -4.966mA   2.76mA
-386mV    -203uA     -2.713mA   4.166mA
-16mV     5.416mA    3.614mA    8.05mA
169mV     7.885mA    6.388mA    9.635mA
317mV     9.232mA    8.029mA    10.27mA
465mV     9.772mA    8.963mA    10.31mA
576mV     9.772mA    9.157mA    10.31mA
2.4V      9.772mA    9.157mA    10.31mA
[Pullup]
|Voltage   I(typ)   I(min)   I(max)
-1.2V     9.47mA     10.11mA    3.025mA
-856mV    9.293mA    10.11mA    3.025mA
-782mV    8.341mA    10.11mA    3.025mA
-708mV    7.09mA     9.383mA    3.025mA
-597mV    4.933mA    7.285mA    3.025mA
-227mV    -3.562mA   -1.227mA   3.025mA
-42mV     -7.389mA   -5.053mA   3.025mA
143mV     -10.21mA   -7.924mA   3.025mA
291mV     -11.48mA   -9.317mA   3.025mA
476mV     -11.86mA   -9.987mA   3.025mA
2.252V    -11.86mA   -9.996mA   3.025mA
2.4V      -11.86mA   -9.996mA   1.728mA
[GND_clamp]
|Voltage   I(typ)   I(min)   I(max)
-1.2V     -201.8mA   -257mA     -169.4mA
-1.125V   -151.4mA   -205.6mA   -124.4mA
-1.05V    -107.4mA   -157mA     -93.36mA
-975mV    -74.07mA   -112.9mA   -77.04mA
-925mV    -59.28mA   -87.24mA   -68.87mA
-875mV    -49.6mA    -65.58mA   -61.06mA
-825mV    -42.58mA   -48.49mA   -53.44mA
-750mV    -33.57mA   -31.23mA   -42.41mA
-600mV    -18.06mA   -15.21mA   -22.68mA
-375mV    -3.74mA    -3.594mA   -4.332mA
0V        0A         0A         0A
2.4V      0A         0A         0A
[POWER_clamp]
|Voltage   I(typ)   I(min)   I(max)
-1.2V     156.9mA    207.6mA    125mA
-1.125V   109.1mA    159mA      80.51mA
-1.075V   80.57mA    128.3mA    57.13mA
-1.025V   56.63mA    99.87mA    41.73mA
-975mV    38.74mA    74.4mA     33.51mA
-900mV    23.86mA    43.88mA    26.68mA
-850mV    19.08mA    29.7mA     22.97mA
-775mV    14.57mA    17.25mA    17.9mA
-700mV    11.09mA    11.42mA    13.53mA
-450mV    3.875mA    4.163mA    4.676mA
-125mV    735.3uA    624.3uA    974.1uA
2.4V      -11.3mA    -6.156mA   -15.63mA
[Ramp]
| variable   typ   min   max
dV/dt_r   0.425/0.803n   0.356/0.785n   0.117/0.952n
dV/dt_f   0.344/0.825n   0.306/0.727n   0.165/1.007n
R_load = 50.000
[Rising Waveform]
R_fixture = 50.000
V_fixture = 0.000
V_fixture_min = 0.000
V_fixture_max = 0.000
|  time   V(typ)   V(min)   V(max)
0s        59.19uV    77.17uV    50.5uV
359ps     686.7uV    199.3uV    -1.302mV
483ps     -5.264mV   259.1uV    67.2mV
693ps     303.9mV    -4.633mV   114.8mV
963ps     474.7mV    266.6mV    139.4mV
1.172ns   532.6mV    380.4mV    149.5mV
1.828ns   607.7mV    496.9mV    166.1mV
3.181ns   658.9mV    549.5mV    180.9mV
8.655ns   700.7mV    585.8mV    192.9mV
30ns      708.6mV    593mV      195.4mV
[Rising Waveform]
R_fixture = 50.000
V_fixture = 0.600
V_fixture_min = 0.571
V_fixture_max = 0.631
|  time   V(typ)   V(min)   V(max)
0s        336.2mV    312.6mV    396.7mV
348ps     336.5mV    312.8mV    396.9mV
448ps     341.8mV    312.8mV    492.8mV
663ps     732.5mV    318.1mV    575.6mV
863ps     888.5mV    619mV      604.8mV
1.003ns   939.9mV    746.7mV    616.4mV
1.193ns   980.4mV    832.1mV    626.6mV
1.514ns   1.016V     895.4mV    637.3mV
2.574ns   1.059V     951.5mV    654mV
30ns      1.104V     993.9mV    671.4mV
[Falling Waveform]
R_fixture = 50.000
V_fixture = 0.600
V_fixture_min = 0.571
V_fixture_max = 0.631
|  time   V(typ)   V(min)   V(max)
0s        1.104V     993.9mV    671.4mV
356ps     1.103V     993.7mV    672.1mV
459ps     1.104V     993.8mV    573.2mV
598ps     778.3mV    996.4mV    508.4mV
664ps     676.8mV    993.2mV    491.3mV
844ps     545.4mV    668.4mV    462.6mV
964ps     500.3mV    547mV      451.4mV
1.379ns   429.7mV    415.7mV    431.9mV
2.308ns   385.1mV    356.7mV    415.5mV
30ns      336.2mV    312.6mV    396.7mV
[Falling Waveform]
R_fixture = 50.000
V_fixture = 0.000
V_fixture_min = 0.000
V_fixture_max = 0.000
|  time   V(typ)   V(min)   V(max)
0s        708.6mV    593mV      195.4mV
351ps     708.3mV    592.7mV    198.2mV
454ps     718.6mV    592.8mV    103.2mV
484ps     668.2mV    592.5mV    88.5mV
574ps     369.5mV    596.8mV    63.04mV
663ps     241.2mV    599mV      49mV
843ps     144.1mV    247.1mV    33.75mV
1.173ns   81.25mV    98.62mV    22.09mV
2.043ns   39.22mV    37.39mV    11.27mV
30ns      59.19uV    77.17uV    50.5uV
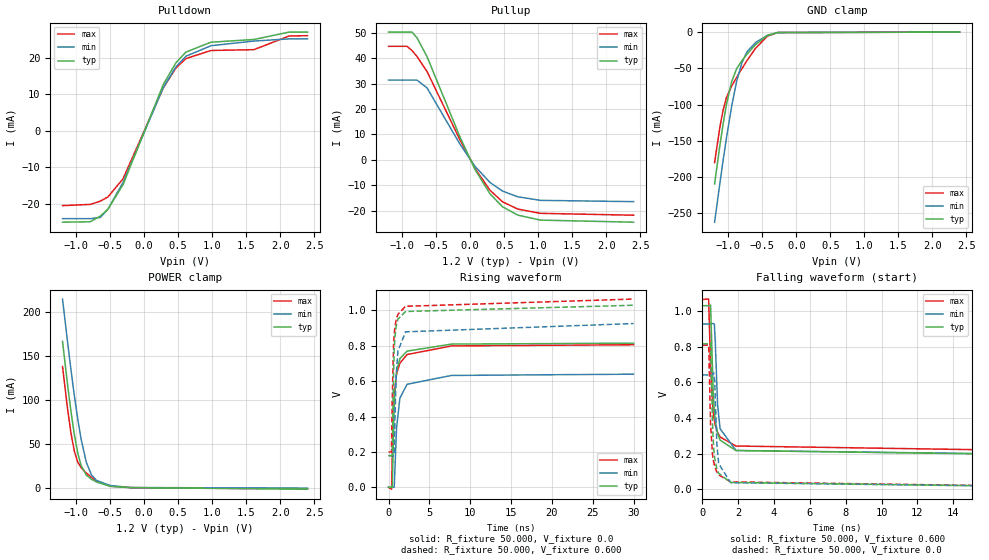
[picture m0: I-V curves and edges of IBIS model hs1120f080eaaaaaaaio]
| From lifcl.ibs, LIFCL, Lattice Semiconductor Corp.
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|Model hs1120f080eaaaaaaaio
[Model] hs1120f080eaaaaaaaio
| Clamp models do not include dynamic input termination. Please refer to
| the hs1120axxxeaaaaaaain model for input termination.
Model_type I/O
Polarity   Non-Inverting
Enable   Active-Low
Vinl =  0.500V
Vinh =  0.700V
Vmeas =  0.600V
Cref =  20.000pF
Rref =  50.000
Vref =  0.600V
C_comp   5.000pF   4.000pF   5.500pF
[Temperature Range]   25.000   0.125k   -40.000
[Voltage Range]   1.200V   1.140V   1.260V
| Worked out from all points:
|   slope of the pulldown table from 0 to 0.18 V, typ, clamps not added: 21.5 ohm
|   slope of the pullup table from 0 to 0.18 V, typ, clamps not added: 19.9 ohm
|   GND clamp passes 1 mA (typ) near -0.31 V on its own axis
|   POWER clamp passes 1 mA (typ) near -0.43 V on its own axis
|   rising waveform, R_fixture 50.000, V_fixture 0.0: 20-80 % time 431ps typ, 626ps min, 545ps max; typ from 0 V to 0.815 V
|   rising waveform, R_fixture 50.000, V_fixture 0.600: 20-80 % time 284ps typ, 413ps min, 326ps max; typ from 0.178 V to 1.03 V
|   falling waveform, R_fixture 50.000, V_fixture 0.600: 20-80 % time 253ps typ, 270ps min, 285ps max; typ from 1.03 V to 0.179 V
|   falling waveform, R_fixture 50.000, V_fixture 0.0: 20-80 % time 198ps typ, 218ps min, 217ps max; typ from 0.815 V to 0 V
[Pulldown]
|Voltage   I(typ)   I(min)   I(max)
-1.2V     -25.09mA   -24.12mA   -20.55mA
-793mV    -24.97mA   -24.12mA   -20.21mA
-645mV    -23.43mA   -23.79mA   -19.33mA
-534mV    -21.55mA   -21.57mA   -18.19mA
-312mV    -14.84mA   -14.22mA   -13.23mA
280mV     12.64mA    11.82mA    11.7mA
465mV     18.58mA    17.46mA    17.14mA
613mV     21.55mA    20.41mA    19.76mA
983mV     24.25mA    23.29mA    21.98mA
1.612V    24.99mA    24.56mA    22.2mA
2.13V     27.02mA    25.16mA    25.95mA
2.4V      27.02mA    25.16mA    26.05mA
[Pullup]
|Voltage   I(typ)   I(min)   I(max)
-1.2V     50.36mA    31.45mA    44.76mA
-930mV    50.36mA    31.45mA    44.76mA
-856mV    50.36mA    31.45mA    43.12mA
-782mV    48.12mA    31.45mA    40.73mA
-634mV    40.64mA    28.35mA    34.8mA
-153mV    9.173mA    6.276mA    7.995mA
69mV      -3.747mA   -2.513mA   -3.327mA
291mV     -13.4mA    -8.918mA   -12mA
476mV     -18.51mA   -12.32mA   -16.55mA
698mV     -21.77mA   -14.55mA   -19.39mA
1.031V    -23.74mA   -15.96mA   -21.07mA
2.4V      -24.56mA   -16.46mA   -21.81mA
[GND_clamp]
|Voltage   I(typ)   I(min)   I(max)
-1.2V     -209.6mA   -262.4mA   -180.2mA
-1.125V   -158.2mA   -210.5mA   -132.7mA
-1.075V   -127mA     -177.3mA   -107.7mA
-1.025V   -99.59mA   -145.8mA   -90.14mA
-950mV    -68.44mA   -102.9mA   -74.64mA
-875mV    -50.37mA   -67.7mA    -62.38mA
-800mV    -39.61mA   -42.62mA   -50.65mA
-725mV    -30.63mA   -27.35mA   -39.46mA
-600mV    -17.53mA   -14.58mA   -22.59mA
-425mV    -4.657mA   -4.485mA   -5.636mA
-275mV    -627.9uA   -616.8uA   -678.4uA
2.4V      0A         0A         0A
[POWER_clamp]
|Voltage   I(typ)   I(min)   I(max)
-1.2V     166.3mA    214.4mA    137.7mA
-1.125V   116.5mA    164.9mA    89.12mA
-1.075V   86.21mA    133.5mA    61.64mA
-1.025V   59.86mA    104mA      41.12mA
-975mV    39.03mA    77.38mA    28.98mA
-925mV    24.95mA    54.44mA    22.72mA
-850mV    14.48mA    28.92mA    16.81mA
-775mV    9.774mA    14.73mA    11.95mA
-700mV    6.595mA    8.327mA    7.924mA
-500mV    1.71mA     2.674mA    1.891mA
-200mV    207.6uA    329.9uA    277.5uA
2.4V      -1.508mA   -253.4uA   -1.296mA
[Ramp]
| variable   typ   min   max
dV/dt_r   0.489/0.431n   0.384/0.629n   0.484/0.547n
dV/dt_f   0.487/0.375n   0.452/0.385n   0.492/0.475n
R_load = 50.000
[Rising Waveform]
R_fixture= 50.000
V_fixture= 0.0
V_fixture_min= 0.0
V_fixture_max= 0.0
|time   V(typ)   V(min)   V(max)
0s        3.068uV    145.7uV    310.1nV
370ps     742.9uV    201.5uV    -10.35mV
457ps     -1.549mV   220.3uV    181.9mV
557ps     206mV      708.6uV    386.6mV
696ps     470mV      1.449mV    524.1mV
977ps     653.5mV    334.7mV    640.6mV
1.386ns   727.5mV    503.8mV    701.6mV
2.27ns    769.8mV    582.6mV    750.6mV
7.728ns   809.6mV    632.4mV    799.2mV
30ns      814.7mV    639.5mV    805.9mV
[Rising Waveform]
R_fixture= 50.000
V_fixture= 0.600
V_fixture_min= 0.571
V_fixture_max= 0.631
|time   V(typ)   V(min)   V(max)
0s        178.2mV    180mV      198.9mV
354ps     178.6mV    180.1mV    200.3mV
457ps     184.7mV    180.1mV    514.6mV
617ps     660mV      177.2mV    807.6mV
697ps     780.2mV    203.6mV    867.5mV
767ps     839.9mV    359.8mV    901.6mV
928ps     910.3mV    630.8mV    947.7mV
1.147ns   950.4mV    769.2mV    978.2mV
2.078ns   993.8mV    878.8mV    1.023V
30ns      1.029V     925.6mV    1.064V
[Falling Waveform]
R_fixture= 50.000
V_fixture= 0.600
V_fixture_min= 0.571
V_fixture_max= 0.631
|time   V(typ)   V(min)   V(max)
0s        1.029V     926.4mV    1.064V
351ps     1.029V     926.2mV    1.066V
458ps     1.033V     926.3mV    689.7mV
607ps     542.5mV    929.1mV    430.9mV
670ps     434.5mV    925.1mV    386.1mV
721ps     384.1mV    829.4mV    360.2mV
851ps     313mV      473.5mV    318mV
990ps     275.3mV    338.9mV    292.9mV
1.88ns    216.6mV    217.3mV    242.1mV
30ns      178.8mV    180.7mV    199.3mV
[Falling Waveform]
R_fixture= 50.000
V_fixture= 0.0
V_fixture_min= 0.0
V_fixture_max= 0.0
|time   V(typ)   V(min)   V(max)
0s        815.4mV    640.6mV    806.4mV
356ps     815.2mV    640.3mV    807.9mV
457ps     821.1mV    640.4mV    367.6mV
568ps     363mV      643.4mV    193.9mV
638ps     221.4mV    652.4mV    149.8mV
690ps     173.6mV    608.2mV    128mV
810ps     115.1mV    252.3mV    96.09mV
910ps     89.13mV    144mV      80.23mV
1.581ns   37.98mV    36.59mV    41.05mV
30ns      459.7uV    673.2uV    304.5uV
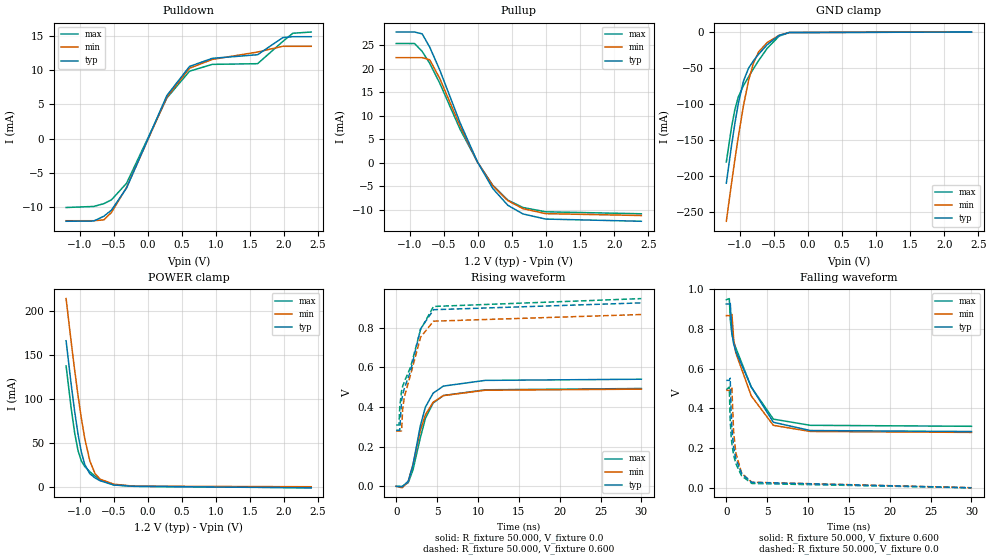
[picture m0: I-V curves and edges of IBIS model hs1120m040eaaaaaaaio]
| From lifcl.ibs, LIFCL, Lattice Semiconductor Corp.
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|Model hs1120m040eaaaaaaaio
[Model] hs1120m040eaaaaaaaio
| Clamp models do not include dynamic input termination. Please refer to
| the hs1120axxxeaaaaaaain model for input termination.
Model_type I/O
Polarity   Non-Inverting
Enable   Active-Low
Vinl =  0.500V
Vinh =  0.700V
Vmeas =  0.600V
Cref =  20.000pF
Rref =  50.000
Vref =  0.600V
C_comp   5.000pF   4.000pF   5.500pF
[Temperature Range]   25.000   0.125k   -40.000
[Voltage Range]   1.200V   1.140V   1.260V
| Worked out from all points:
|   slope of the pulldown table from 0 to 0.18 V, typ, clamps not added: 43.8 ohm
|   slope of the pullup table from 0 to 0.18 V, typ, clamps not added: 38.9 ohm
|   GND clamp passes 1 mA (typ) near -0.31 V on its own axis
|   POWER clamp passes 1 mA (typ) near -0.43 V on its own axis
|   rising waveform, R_fixture 50.000, V_fixture 0.0: 20-80 % time 1.86ns typ, 1.95ns min, 1.95ns max; typ from 0 V to 0.54 V
|   rising waveform, R_fixture 50.000, V_fixture 0.600: 20-80 % time 2.4ns typ, 2.15ns min, 2.7ns max; typ from 0.283 V to 0.925 V
|   falling waveform, R_fixture 50.000, V_fixture 0.600: 20-80 % time 3.46ns typ, 2.89ns min, 3.26ns max; typ from 0.926 V to 0.284 V
|   falling waveform, R_fixture 50.000, V_fixture 0.0: 20-80 % time 893ps typ, 823ps min, 933ps max; typ from 0.541 V to 0 V
[Pulldown]
|Voltage   I(typ)   I(min)   I(max)
-1.2V     -12.07mA   -11.99mA   -10.06mA
-793mV    -12.03mA   -11.99mA   -9.906mA
-645mV    -11.33mA   -11.86mA   -9.494mA
-534mV    -10.45mA   -10.79mA   -8.945mA
-312mV    -7.217mA   -7.127mA   -6.523mA
280mV     6.293mA    6.052mA    5.931mA
613mV     10.54mA    10.28mA    9.842mA
946mV     11.72mA    11.56mA    10.84mA
1.612V    12.25mA    12.64mA    10.94mA
1.982V    14.75mA    13.48mA    14.18mA
2.13V     14.88mA    13.48mA    15.39mA
2.4V      14.88mA    13.48mA    15.56mA
[Pullup]
|Voltage   I(typ)   I(min)   I(max)
-1.2V     27.75mA    22.32mA    25.31mA
-930mV    27.75mA    22.32mA    25.31mA
-819mV    27.37mA    22.32mA    23.64mA
-708mV    24.55mA    21.87mA    21.12mA
-560mV    19.68mA    17.9mA     16.88mA
-264mV    8.564mA    7.863mA    7.174mA
-5mV      140.3uA    130.8uA    120.6uA
217mV     -5.427mA   -4.833mA   -4.748mA
439mV     -9.005mA   -8.022mA   -7.904mA
661mV     -10.84mA   -9.72mA    -9.477mA
994mV     -11.93mA   -10.78mA   -10.39mA
2.4V      -12.4mA    -11.18mA   -10.81mA
[GND_clamp]
|Voltage   I(typ)   I(min)   I(max)
-1.2V     -209.6mA   -262.4mA   -180.2mA
-1.125V   -158.2mA   -210.5mA   -132.7mA
-1.075V   -127mA     -177.3mA   -107.7mA
-1.025V   -99.59mA   -145.8mA   -90.14mA
-950mV    -68.44mA   -102.9mA   -74.64mA
-875mV    -50.37mA   -67.7mA    -62.38mA
-800mV    -39.61mA   -42.62mA   -50.65mA
-725mV    -30.63mA   -27.35mA   -39.46mA
-600mV    -17.53mA   -14.58mA   -22.59mA
-425mV    -4.657mA   -4.485mA   -5.636mA
-275mV    -627.9uA   -616.8uA   -678.4uA
2.4V      0A         0A         0A
[POWER_clamp]
|Voltage   I(typ)   I(min)   I(max)
-1.2V     166.3mA    214.4mA    137.7mA
-1.125V   116.5mA    164.9mA    89.12mA
-1.075V   86.21mA    133.5mA    61.64mA
-1.025V   59.86mA    104mA      41.12mA
-975mV    39.03mA    77.38mA    28.98mA
-925mV    24.95mA    54.44mA    22.72mA
-850mV    14.48mA    28.92mA    16.81mA
-775mV    9.774mA    14.73mA    11.95mA
-700mV    6.595mA    8.327mA    7.924mA
-500mV    1.71mA     2.674mA    1.891mA
-200mV    207.6uA    329.9uA    277.5uA
2.4V      -1.508mA   -253.4uA   -1.296mA
[Ramp]
| variable   typ   min   max
dV/dt_r   0.324/1.897n   0.294/1.948n   0.296/1.961n
dV/dt_f   0.322/3.392n   0.306/3.061n   0.310/3.409n
R_load = 50.000
[Rising Waveform]
R_fixture= 50.000
V_fixture= 0.0
V_fixture_min= 0.0
V_fixture_max= 0.0
|time   V(typ)   V(min)   V(max)
0s        4.858uV    227uV      477.5nV
733ps     -1.454mV   -7.495mV   -878.4uV
1.473ns   25.7mV     24.87mV    18.39mV
2.052ns   108mV      110.1mV    83.23mV
2.949ns   304.6mV    281.1mV    244.5mV
3.569ns   399.5mV    360.9mV    342.6mV
4.517ns   470mV      424.3mV    420.5mV
5.771ns   505.7mV    457.8mV    458.1mV
10.89ns   534.5mV    484.8mV    487mV
30ns      540.4mV    490.4mV    493.6mV
[Rising Waveform]
R_fixture= 50.000
V_fixture= 0.600
V_fixture_min= 0.571
V_fixture_max= 0.631
|time   V(typ)   V(min)   V(max)
0s        283mV      278.6mV    309.6mV
343ps     283.3mV    278.7mV    309.6mV
431ps     283.1mV    278.7mV    399.6mV
653ps     430.2mV    279.9mV    480.3mV
793ps     463.7mV    390.8mV    504.9mV
1.002ns   495mV      451.4mV    528.8mV
1.753ns   581mV      562.5mV    600.9mV
2.979ns   794.3mV    752mV      790.4mV
4.569ns   891mV      833.1mV    907.4mV
30ns      925.5mV    866.8mV    947mV
[Falling Waveform]
R_fixture= 50.000
V_fixture= 0.600
V_fixture_min= 0.571
V_fixture_max= 0.631
|time   V(typ)   V(min)   V(max)
0s        926.2mV    867.7mV    947.6mV
365ps     926.1mV    867.5mV    953.3mV
483ps     929.2mV    867.5mV    846.1mV
686ps     781.2mV    873.6mV    773.3mV
907ps     723.1mV    744.2mV    734.7mV
1.163ns   687.1mV    679.5mV    704.6mV
3.049ns   508.8mV    463.5mV    507.6mV
5.755ns   330.6mV    315mV      346.3mV
10.27ns   288.9mV    284.2mV    315.2mV
30ns      283.8mV    279.5mV    310.2mV
[Falling Waveform]
R_fixture= 50.000
V_fixture= 0.0
V_fixture_min= 0.0
V_fixture_max= 0.0
|time   V(typ)   V(min)   V(max)
0s        541.4mV    491.5mV    494.4mV
362ps     541.6mV    491.2mV    507.7mV
473ps     552.3mV    491.1mV    339mV
593ps     372.4mV    499.4mV    258.3mV
675ps     300.6mV    507.8mV    223.9mV
886ps     208.6mV    286.7mV    166.7mV
1.156ns   148mV      177.8mV    122.6mV
1.875ns   71.78mV    73.6mV     60.61mV
3.119ns   27.74mV    28.5mV     22.31mV
30ns      481.1uV    870.6uV    290.3uV
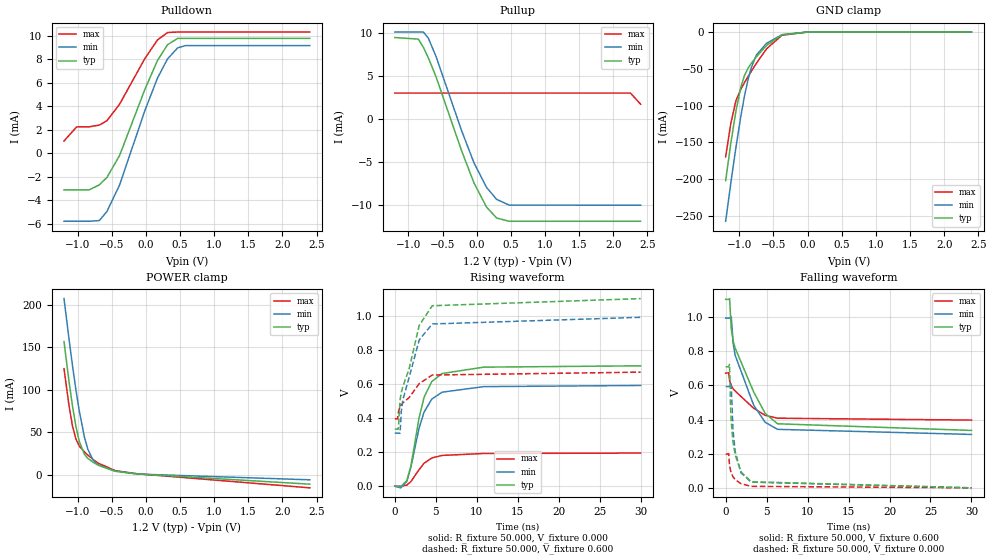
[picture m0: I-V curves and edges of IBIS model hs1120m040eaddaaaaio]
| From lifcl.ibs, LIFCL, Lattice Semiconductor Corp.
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|Model hs1120m040eaddaaaaio
[Model] hs1120m040eaddaaaaio
| Clamp models do not include dynamic input termination. Please refer to
| the hs1120axxxeaddaaaain model for input termination.
Model_type I/O
Polarity   Non-Inverting
Enable   Active-Low
Vinl =  0.500V
Vinh =  0.700V
Vmeas =  0.600V
Cref =  20.000pF
Rref =  50.000
Vref =  0.600V
C_comp   5.000pF   4.000pF   5.500pF
[Temperature Range]   25.000   0.125k   -40.000
[Voltage Range]   1.200V   1.140V   1.260V
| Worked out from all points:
|   slope of the pulldown table from 0 to 0.18 V, typ, clamps not added: 76.5 ohm
|   slope of the pullup table from 0 to 0.18 V, typ, clamps not added: 72.6 ohm
|   GND clamp passes 1 mA (typ) near -0.14 V on its own axis
|   POWER clamp passes 1 mA (typ) near -0.17 V on its own axis
|   rising waveform, R_fixture 50.000, V_fixture 0.000: 20-80 % time 1.86ns typ, 1.95ns min, 1.95ns max; typ from 0 V to 0.709 V
|   rising waveform, R_fixture 50.000, V_fixture 0.600: 20-80 % time 2.4ns typ, 2.15ns min, 2.7ns max; typ from 0.336 V to 1.1 V
|   falling waveform, R_fixture 50.000, V_fixture 0.600: 20-80 % time 3.46ns typ, 2.89ns min, 3.26ns max; typ from 1.1 V to 0.336 V
|   falling waveform, R_fixture 50.000, V_fixture 0.000: 20-80 % time 893ps typ, 822ps min, 933ps max; typ from 0.709 V to 0 V
[Pulldown]
|Voltage   I(typ)   I(min)   I(max)
-1.2V     -3.123mA   -5.801mA   1.03mA
-1.015V   -3.123mA   -5.801mA   2.234mA
-830mV    -3.123mA   -5.801mA   2.243mA
-682mV    -2.698mA   -5.74mA    2.39mA
-571mV    -2.069mA   -4.966mA   2.76mA
-386mV    -203uA     -2.713mA   4.166mA
-16mV     5.416mA    3.613mA    8.05mA
169mV     7.885mA    6.387mA    9.635mA
317mV     9.232mA    8.028mA    10.27mA
465mV     9.772mA    8.963mA    10.31mA
576mV     9.772mA    9.156mA    10.31mA
2.4V      9.772mA    9.156mA    10.31mA
[Pullup]
|Voltage   I(typ)   I(min)   I(max)
-1.2V     9.47mA     10.11mA    3.025mA
-856mV    9.293mA    10.11mA    3.025mA
-782mV    8.341mA    10.11mA    3.025mA
-708mV    7.09mA     9.384mA    3.025mA
-597mV    4.933mA    7.286mA    3.025mA
-227mV    -3.562mA   -1.226mA   3.025mA
-42mV     -7.389mA   -5.052mA   3.025mA
143mV     -10.21mA   -7.923mA   3.025mA
291mV     -11.48mA   -9.316mA   3.025mA
476mV     -11.86mA   -9.987mA   3.025mA
2.252V    -11.86mA   -9.996mA   3.025mA
2.4V      -11.86mA   -9.996mA   1.728mA
[GND_clamp]
|Voltage   I(typ)   I(min)   I(max)
-1.2V     -201.8mA   -257mA     -169.4mA
-1.125V   -151.4mA   -205.6mA   -124.4mA
-1.05V    -107.4mA   -157mA     -93.36mA
-975mV    -74.07mA   -112.9mA   -77.04mA
-925mV    -59.28mA   -87.24mA   -68.87mA
-875mV    -49.6mA    -65.58mA   -61.06mA
-825mV    -42.58mA   -48.49mA   -53.44mA
-750mV    -33.57mA   -31.23mA   -42.41mA
-600mV    -18.06mA   -15.21mA   -22.68mA
-375mV    -3.74mA    -3.594mA   -4.332mA
0V        0A         0A         0A
2.4V      0A         0A         0A
[POWER_clamp]
|Voltage   I(typ)   I(min)   I(max)
-1.2V     156.9mA    207.6mA    125mA
-1.125V   109.1mA    159mA      80.51mA
-1.075V   80.57mA    128.3mA    57.13mA
-1.025V   56.63mA    99.87mA    41.73mA
-975mV    38.74mA    74.4mA     33.51mA
-900mV    23.86mA    43.88mA    26.68mA
-850mV    19.08mA    29.7mA     22.97mA
-775mV    14.57mA    17.25mA    17.9mA
-700mV    11.09mA    11.42mA    13.53mA
-450mV    3.875mA    4.163mA    4.676mA
-125mV    735.3uA    624.3uA    974.1uA
2.4V      -11.3mA    -6.156mA   -15.63mA
[Ramp]
| variable   typ   min   max
dV/dt_r   0.425/1.862n   0.356/1.948n   0.117/1.961n
dV/dt_f   0.344/3.392n   0.306/3.061n   0.165/3.407n
R_load = 50.000
[Rising Waveform]
R_fixture = 50.000
V_fixture = 0.000
V_fixture_min = 0.000
V_fixture_max = 0.000
|  time   V(typ)   V(min)   V(max)
0s        59.14uV    79.73uV    50.5uV
733ps     -1.853mV   -9.262mV   -297.4uV
1.473ns   33.75mV    29.9mV     7.33mV
1.964ns   119.9mV    113.1mV    27.82mV
2.949ns   399.4mV    339.9mV    96.85mV
3.569ns   523.9mV    436.4mV    135.7mV
4.519ns   616.5mV    513.2mV    166.5mV
5.77ns    663.1mV    553.6mV    181.4mV
10.86ns   700.8mV    586.2mV    192.8mV
30ns      708.6mV    593mV      195.4mV
[Rising Waveform]
R_fixture = 50.000
V_fixture = 0.600
V_fixture_min = 0.571
V_fixture_max = 0.631
|  time   V(typ)   V(min)   V(max)
0s        336.2mV    312.7mV    396.7mV
343ps     336.6mV    312.8mV    396.7mV
431ps     336.3mV    312.8mV    435.5mV
641ps     507.6mV    311.9mV    469.1mV
793ps     552.1mV    442.6mV    480.9mV
1.001ns   589.2mV    512.5mV    491.2mV
1.75ns    691.7mV    640.9mV    522.1mV
2.979ns   947mV      860.8mV    603.9mV
4.568ns   1.062V     954.8mV    654.4mV
30ns      1.104V     993.9mV    671.4mV
[Falling Waveform]
R_fixture = 50.000
V_fixture = 0.600
V_fixture_min = 0.571
V_fixture_max = 0.631
|  time   V(typ)   V(min)   V(max)
0s        1.104V     993.9mV    671.4mV
365ps     1.103V     993.6mV    673.9mV
482ps     1.108V     993.6mV    627.9mV
683ps     931.9mV    1.001V     596.6mV
924ps     857.4mV    843mV      578.7mV
1.162ns   818.1mV    776.1mV    566.8mV
3.422ns   560.9mV    483.5mV    465.7mV
4.824ns   435.8mV    383.8mV    424.7mV
6.335ns   375.1mV    342.5mV    407.7mV
30ns      336.2mV    312.7mV    396.7mV
[Falling Waveform]
R_fixture = 50.000
V_fixture = 0.000
V_fixture_min = 0.000
V_fixture_max = 0.000
|  time   V(typ)   V(min)   V(max)
0s        708.6mV    593mV      195.4mV
362ps     708.9mV    592.6mV    200.7mV
473ps     722.8mV    592.5mV    134mV
593ps     487.2mV    602.5mV    102.1mV
673ps     394.8mV    613.4mV    88.75mV
884ps     273.4mV    347.1mV    66.01mV
1.154ns   193.7mV    214.5mV    48.53mV
1.873ns   93.61mV    88.15mV    23.95mV
3.12ns    35.74mV    33.44mV    8.752mV
30ns      59.14uV    79.73uV    50.5uV
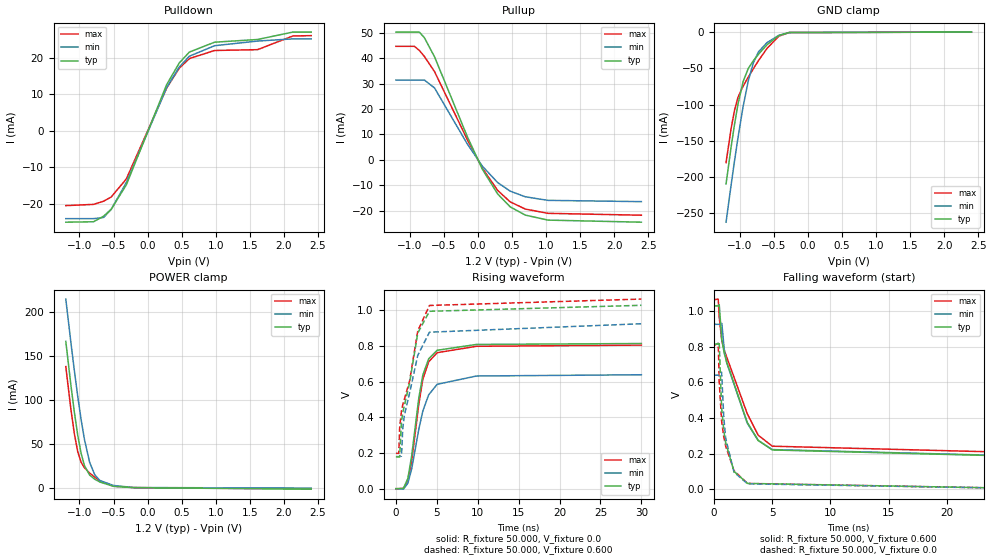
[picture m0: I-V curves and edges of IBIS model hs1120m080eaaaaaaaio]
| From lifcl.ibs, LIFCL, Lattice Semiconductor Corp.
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|Model hs1120m080eaaaaaaaio
[Model] hs1120m080eaaaaaaaio
| Clamp models do not include dynamic input termination. Please refer to
| the hs1120axxxeaaaaaaain model for input termination.
Model_type I/O
Polarity   Non-Inverting
Enable   Active-Low
Vinl =  0.500V
Vinh =  0.700V
Vmeas =  0.600V
Cref =  20.000pF
Rref =  50.000
Vref =  0.600V
C_comp   5.000pF   4.000pF   5.500pF
[Temperature Range]   25.000   0.125k   -40.000
[Voltage Range]   1.200V   1.140V   1.260V
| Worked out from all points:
|   slope of the pulldown table from 0 to 0.18 V, typ, clamps not added: 21.5 ohm
|   slope of the pullup table from 0 to 0.18 V, typ, clamps not added: 19.9 ohm
|   GND clamp passes 1 mA (typ) near -0.31 V on its own axis
|   POWER clamp passes 1 mA (typ) near -0.43 V on its own axis
|   rising waveform, R_fixture 50.000, V_fixture 0.0: 20-80 % time 1.51ns typ, 1.85ns min, 1.5ns max; typ from 0 V to 0.815 V
|   rising waveform, R_fixture 50.000, V_fixture 0.600: 20-80 % time 1.98ns typ, 2.02ns min, 2.19ns max; typ from 0.178 V to 1.03 V
|   falling waveform, R_fixture 50.000, V_fixture 0.600: 20-80 % time 2.4ns typ, 2.26ns min, 2.64ns max; typ from 1.03 V to 0.179 V
|   falling waveform, R_fixture 50.000, V_fixture 0.0: 20-80 % time 811ps typ, 747ps min, 929ps max; typ from 0.815 V to 0 V
[Pulldown]
|Voltage   I(typ)   I(min)   I(max)
-1.2V     -25.09mA   -24.12mA   -20.55mA
-793mV    -24.97mA   -24.12mA   -20.21mA
-645mV    -23.43mA   -23.79mA   -19.33mA
-534mV    -21.55mA   -21.57mA   -18.19mA
-312mV    -14.84mA   -14.22mA   -13.23mA
280mV     12.64mA    11.82mA    11.7mA
465mV     18.58mA    17.46mA    17.14mA
613mV     21.55mA    20.41mA    19.76mA
983mV     24.25mA    23.29mA    21.98mA
1.612V    24.99mA    24.56mA    22.2mA
2.13V     27.02mA    25.16mA    25.95mA
2.4V      27.02mA    25.16mA    26.05mA
[Pullup]
|Voltage   I(typ)   I(min)   I(max)
-1.2V     50.36mA    31.45mA    44.76mA
-930mV    50.36mA    31.45mA    44.76mA
-856mV    50.36mA    31.45mA    43.12mA
-782mV    48.12mA    31.45mA    40.73mA
-634mV    40.64mA    28.35mA    34.8mA
-153mV    9.173mA    6.276mA    7.995mA
69mV      -3.747mA   -2.513mA   -3.327mA
291mV     -13.4mA    -8.918mA   -12mA
476mV     -18.51mA   -12.32mA   -16.55mA
698mV     -21.77mA   -14.55mA   -19.39mA
1.031V    -23.74mA   -15.96mA   -21.07mA
2.4V      -24.56mA   -16.46mA   -21.81mA
[GND_clamp]
|Voltage   I(typ)   I(min)   I(max)
-1.2V     -209.6mA   -262.4mA   -180.2mA
-1.125V   -158.2mA   -210.5mA   -132.7mA
-1.075V   -127mA     -177.3mA   -107.7mA
-1.025V   -99.59mA   -145.8mA   -90.14mA
-950mV    -68.44mA   -102.9mA   -74.64mA
-875mV    -50.37mA   -67.7mA    -62.38mA
-800mV    -39.61mA   -42.62mA   -50.65mA
-725mV    -30.63mA   -27.35mA   -39.46mA
-600mV    -17.53mA   -14.58mA   -22.59mA
-425mV    -4.657mA   -4.485mA   -5.636mA
-275mV    -627.9uA   -616.8uA   -678.4uA
2.4V      0A         0A         0A
[POWER_clamp]
|Voltage   I(typ)   I(min)   I(max)
-1.2V     166.3mA    214.4mA    137.7mA
-1.125V   116.5mA    164.9mA    89.12mA
-1.075V   86.21mA    133.5mA    61.64mA
-1.025V   59.86mA    104mA      41.12mA
-975mV    39.03mA    77.38mA    28.98mA
-925mV    24.95mA    54.44mA    22.72mA
-850mV    14.48mA    28.92mA    16.81mA
-775mV    9.774mA    14.73mA    11.95mA
-700mV    6.595mA    8.327mA    7.924mA
-500mV    1.71mA     2.674mA    1.891mA
-200mV    207.6uA    329.9uA    277.5uA
2.4V      -1.508mA   -253.4uA   -1.296mA
[Ramp]
| variable   typ   min   max
dV/dt_r   0.489/1.542n   0.384/1.854n   0.483/1.545n
dV/dt_f   0.487/2.539n   0.452/2.421n   0.492/2.708n
R_load = 50.000
[Rising Waveform]
R_fixture= 50.000
V_fixture= 0.0
V_fixture_min= 0.0
V_fixture_max= 0.0
|time   V(typ)   V(min)   V(max)
0s        3.068uV    145.7uV    310.1nV
917ps     1.677mV    -2.535mV   1.602mV
1.461ns   58.08mV    31.26mV    46.44mV
1.928ns   185.6mV    111.6mV    154.3mV
2.799ns   509.9mV    333.8mV    475.4mV
3.291ns   637.9mV    436.1mV    614.2mV
4.001ns   728.7mV    526.7mV    711.9mV
5.04ns    776.7mV    585.8mV    763.1mV
9.845ns   809.5mV    632.3mV    799.1mV
30ns      814.6mV    639.4mV    805.7mV
[Rising Waveform]
R_fixture= 50.000
V_fixture= 0.600
V_fixture_min= 0.571
V_fixture_max= 0.631
|time   V(typ)   V(min)   V(max)
0s        178.2mV    180mV      198.9mV
346ps     178.6mV    180.1mV    198.2mV
457ps     179.1mV    180.2mV    341.4mV
677ps     376.6mV    183mV      437mV
837ps     426.8mV    339mV      471.8mV
1.027ns   465.7mV    410.7mV    500.6mV
1.671ns   594.2mV    536.7mV    605.4mV
2.672ns   873.4mV    748.8mV    885.9mV
4.1ns     995.3mV    878.1mV    1.028V
30ns      1.029V     925.5mV    1.064V
[Falling Waveform]
R_fixture= 50.000
V_fixture= 0.600
V_fixture_min= 0.571
V_fixture_max= 0.631
|time   V(typ)   V(min)   V(max)
0s        1.029V     926.4mV    1.064V
380ps     1.03V      926.2mV    1.068V
469ps     1.036V     926.3mV    963.8mV
690ps     839.2mV    931.2mV    833.1mV
899ps     763.5mV    785.2mV    779.9mV
1.1ns     715.9mV    712.1mV    743.8mV
2.869ns   375.5mV    371.2mV    424.4mV
3.809ns   274.1mV    273.5mV    303.3mV
5.02ns    220.5mV    222.7mV    241.6mV
30ns      178.8mV    180.7mV    199.4mV
[Falling Waveform]
R_fixture= 50.000
V_fixture= 0.0
V_fixture_min= 0.0
V_fixture_max= 0.0
|time   V(typ)   V(min)   V(max)
0s        815.4mV    640.6mV    806.4mV
365ps     815.6mV    640.2mV    819.2mV
400ps     821.6mV    640.4mV    778.1mV
462ps     828.5mV    640.3mV    608.7mV
670ps     460.3mV    657.5mV    384.1mV
861ps     328.3mV    400.3mV    291.8mV
1.021ns   260.7mV    286.2mV    241.5mV
1.736ns   100.2mV    95.82mV    104mV
2.893ns   32.68mV    30.32mV    32.28mV
30ns      473uV      681.9uV    315.5uV
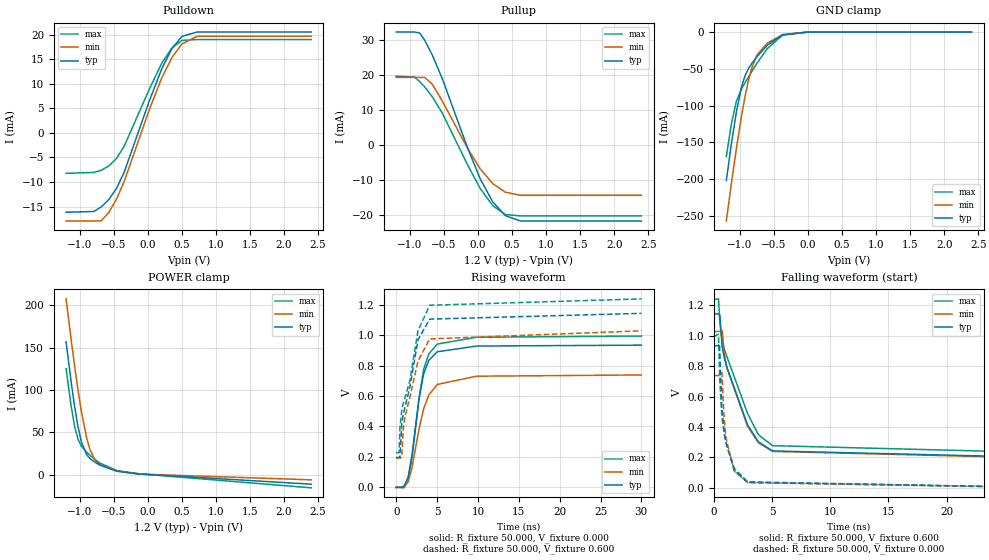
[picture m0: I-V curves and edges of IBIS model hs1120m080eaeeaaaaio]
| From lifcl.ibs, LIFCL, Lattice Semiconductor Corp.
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|Model hs1120m080eaeeaaaaio
[Model] hs1120m080eaeeaaaaio
| Clamp models do not include dynamic input termination. Please refer to
| the hs1120axxxeaeeaaaain model for input termination.
Model_type I/O
Polarity   Non-Inverting
Enable   Active-Low
Vinl =  0.500V
Vinh =  0.700V
Vmeas =  0.600V
Cref =  20.000pF
Rref =  50.000
Vref =  0.600V
C_comp   5.000pF   4.000pF   5.500pF
[Temperature Range]   25.000   0.125k   -40.000
[Voltage Range]   1.200V   1.140V   1.260V
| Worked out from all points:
|   slope of the pulldown table from 0 to 0.18 V, typ, clamps not added: 27.3 ohm
|   slope of the pullup table from 0 to 0.18 V, typ, clamps not added: 26.1 ohm
|   GND clamp passes 1 mA (typ) near -0.14 V on its own axis
|   POWER clamp passes 1 mA (typ) near -0.17 V on its own axis
|   rising waveform, R_fixture 50.000, V_fixture 0.000: 20-80 % time 1.51ns typ, 1.85ns min, 1.5ns max; typ from 0 V to 0.934 V
|   rising waveform, R_fixture 50.000, V_fixture 0.600: 20-80 % time 1.98ns typ, 2.02ns min, 2.19ns max; typ from 0.197 V to 1.14 V
|   falling waveform, R_fixture 50.000, V_fixture 0.600: 20-80 % time 2.4ns typ, 2.26ns min, 2.64ns max; typ from 1.14 V to 0.197 V
|   falling waveform, R_fixture 50.000, V_fixture 0.000: 20-80 % time 812ps typ, 748ps min, 929ps max; typ from 0.934 V to 0 V
[Pulldown]
|Voltage   I(typ)   I(min)   I(max)
-1.2V     -16.15mA   -17.94mA   -8.219mA
-793mV    -16mA      -17.94mA   -8.053mA
-682mV    -15.05mA   -17.87mA   -7.595mA
-571mV    -13.55mA   -16.18mA   -6.715mA
-460mV    -11.3mA    -13.49mA   -5.195mA
-349mV    -8.077mA   -9.972mA   -2.767mA
21mV      6.472mA    4.689mA    8.875mA
206mV     13.1mA     11.24mA    14.23mA
354mV     17.17mA    15.36mA    17.32mA
502mV     19.67mA    18.13mA    18.86mA
724mV     20.55mA    19.68mA    19.01mA
2.4V      20.55mA    19.69mA    19.01mA
[Pullup]
|Voltage   I(typ)   I(min)   I(max)
-1.2V     32.18mA    19.26mA    19.61mA
-930mV    32.18mA    19.26mA    19.34mA
-856mV    31.91mA    19.26mA    18.1mA
-782mV    29.87mA    19.26mA    16.56mA
-671mV    25.67mA    17.34mA    13.8mA
-523mV    18.91mA    12.54mA    9.103mA
-153mV    -749.4uA   -893.4uA   -5.584mA
32mV      -9.535mA   -6.719mA   -12.3mA
217mV     -16.14mA   -10.96mA   -17.24mA
402mV     -20.07mA   -13.4mA    -19.78mA
624mV     -21.6mA    -14.29mA   -20.15mA
2.4V      -21.61mA   -14.29mA   -20.15mA
[GND_clamp]
|Voltage   I(typ)   I(min)   I(max)
-1.2V     -201.8mA   -257mA     -169.4mA
-1.125V   -151.4mA   -205.6mA   -124.4mA
-1.05V    -107.4mA   -157mA     -93.36mA
-975mV    -74.07mA   -112.9mA   -77.04mA
-925mV    -59.28mA   -87.24mA   -68.87mA
-875mV    -49.6mA    -65.58mA   -61.06mA
-825mV    -42.58mA   -48.49mA   -53.44mA
-750mV    -33.57mA   -31.23mA   -42.41mA
-600mV    -18.06mA   -15.21mA   -22.68mA
-375mV    -3.74mA    -3.594mA   -4.332mA
0V        0A         0A         0A
2.4V      0A         0A         0A
[POWER_clamp]
|Voltage   I(typ)   I(min)   I(max)
-1.2V     156.9mA    207.6mA    125mA
-1.125V   109.1mA    159mA      80.51mA
-1.075V   80.57mA    128.3mA    57.13mA
-1.025V   56.63mA    99.87mA    41.73mA
-975mV    38.74mA    74.4mA     33.51mA
-900mV    23.86mA    43.88mA    26.68mA
-850mV    19.08mA    29.7mA     22.97mA
-775mV    14.57mA    17.25mA    17.9mA
-700mV    11.09mA    11.42mA    13.53mA
-450mV    3.875mA    4.163mA    4.676mA
-125mV    735.3uA    624.3uA    974.1uA
2.4V      -11.3mA    -6.156mA   -15.63mA
[Ramp]
| variable   typ   min   max
dV/dt_r   0.560/1.541n   0.443/1.854n   0.596/1.545n
dV/dt_f   0.523/2.542n   0.493/2.421n   0.533/2.707n
R_load = 50.000
[Rising Waveform]
R_fixture = 50.000
V_fixture = 0.000
V_fixture_min = 0.000
V_fixture_max = 0.000
|  time   V(typ)   V(min)   V(max)
0s        56.51uV    73.7uV     44.61uV
917ps     1.976mV    -3.022mV   2.02mV
1.461ns   66.65mV    36.01mV    57.34mV
1.928ns   212.9mV    128.8mV    190.4mV
2.799ns   584.7mV    385.4mV    586.6mV
3.361ns   746.4mV    517.1mV    775.2mV
4.001ns   835.6mV    608.2mV    878.2mV
5.04ns    890.6mV    676.4mV    941.4mV
9.834ns   928.2mV    730.1mV    985.9mV
30ns      934.1mV    738.4mV    994mV
[Rising Waveform]
R_fixture = 50.000
V_fixture = 0.600
V_fixture_min = 0.571
V_fixture_max = 0.631
|  time   V(typ)   V(min)   V(max)
0s        196.7mV    192.5mV    228.3mV
346ps     197.1mV    192.6mV    227.4mV
457ps     197.7mV    192.7mV    394.5mV
677ps     417.3mV    195.9mV    506.1mV
837ps     473.1mV    370.8mV    546.7mV
1.027ns   516.4mV    451.1mV    580.3mV
1.671ns   659.3mV    592.4mV    702.6mV
2.672ns   969.7mV    830.2mV    1.03V
4.099ns   1.105V     975.1mV    1.196V
30ns      1.143V     1.028V     1.238V
[Falling Waveform]
R_fixture = 50.000
V_fixture = 0.600
V_fixture_min = 0.571
V_fixture_max = 0.631
|  time   V(typ)   V(min)   V(max)
0s        1.143V     1.028V     1.238V
379ps     1.143V     1.028V     1.242V
496ps     1.137V     1.028V     1.086V
690ps     931.2mV    1.034V     967.8mV
896ps     847.8mV    871.9mV    906.4mV
1.1ns     794mV      788.1mV    863.5mV
2.87ns    415.4mV    405.9mV    490.6mV
3.811ns   302.5mV    296.4mV    349.3mV
5.027ns   242.9mV    239.4mV    277.3mV
30ns      196.7mV    192.5mV    228.3mV
[Falling Waveform]
R_fixture = 50.000
V_fixture = 0.000
V_fixture_min = 0.000
V_fixture_max = 0.000
|  time   V(typ)   V(min)   V(max)
0s        934.1mV    738.4mV    994mV
365ps     934.3mV    738mV      1.01V
400ps     941.2mV    738.2mV    959.2mV
466ps     947.1mV    738mV      739.9mV
671ps     526.1mV    757.5mV    472.5mV
870ps     370.7mV    450.2mV    355.4mV
1.026ns   296.3mV    326.6mV    295.8mV
1.736ns   114.4mV    109.8mV    127.8mV
2.899ns   36.81mV    34.11mV    39.25mV
30ns      56.51uV    73.7uV     44.61uV
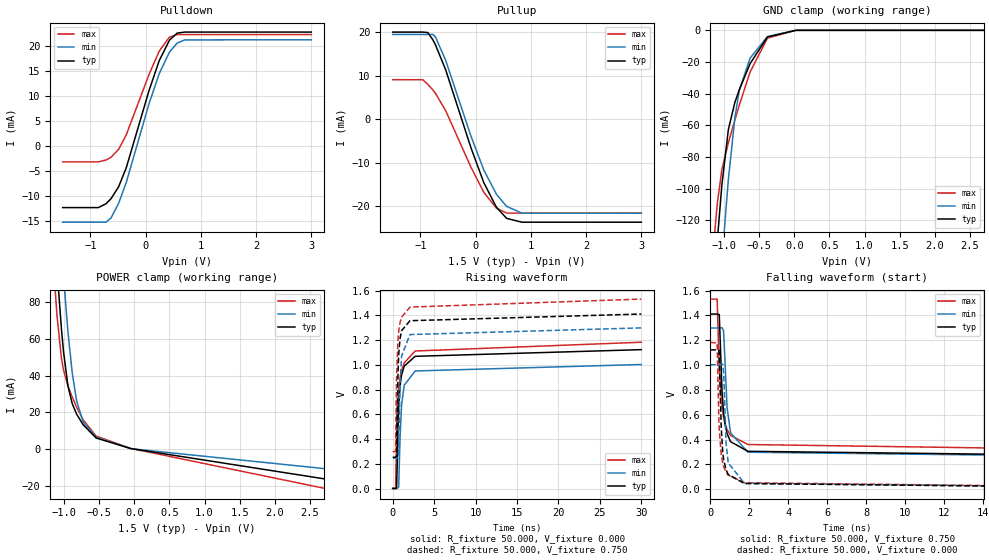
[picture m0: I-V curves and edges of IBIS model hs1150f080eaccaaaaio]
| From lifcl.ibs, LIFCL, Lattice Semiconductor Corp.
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|Model hs1150f080eaccaaaaio
[Model] hs1150f080eaccaaaaio
| Clamp models do not include dynamic input termination. Please refer to
| the hs1150axxxeaccaaaain model for input termination.
Model_type I/O
Polarity   Non-Inverting
Enable   Active-Low
Vinl =  0.650V
Vinh =  0.850V
Vmeas =  0.750V
Cref =  30.000pF
Rref =  50.000
Vref =  0.750V
C_comp   5.000pF   4.000pF   5.500pF
[Temperature Range]   25.000   0.125k   -40.000
[Voltage Range]   1.500V   1.430V   1.580V
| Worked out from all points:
|   slope of the pulldown table from 0 to 0.225 V, typ, clamps not added: 29.5 ohm
|   slope of the pullup table from 0 to 0.225 V, typ, clamps not added: 31.7 ohm
|   GND clamp passes 1 mA (typ) near -0.15 V on its own axis
|   POWER clamp passes 1 mA (typ) near -0.17 V on its own axis
|   rising waveform, R_fixture 50.000, V_fixture 0.000: 20-80 % time 460ps typ, 485ps min, 623ps max; typ from 0.001 V to 1.12 V
|   rising waveform, R_fixture 50.000, V_fixture 0.750: 20-80 % time 309ps typ, 341ps min, 359ps max; typ from 0.253 V to 1.41 V
|   falling waveform, R_fixture 50.000, V_fixture 0.750: 20-80 % time 286ps typ, 296ps min, 332ps max; typ from 1.41 V to 0.253 V
|   falling waveform, R_fixture 50.000, V_fixture 0.000: 20-80 % time 200ps typ, 217ps min, 219ps max; typ from 1.12 V to 0.001 V
[Pulldown]
|Voltage   I(typ)   I(min)   I(max)
-1.5V     -12.24mA   -15.16mA   -3.116mA
-856mV    -12.24mA   -15.16mA   -3.091mA
-718mV    -11.49mA   -15.16mA   -2.735mA
-626mV    -10.47mA   -14.32mA   -2.18mA
-488mV    -8.076mA   -11.39mA   -594uA
-350mV    -4.287mA   -7.226mA   2.301mA
64mV      11.22mA    8.592mA    14.42mA
248mV     17.18mA    14.57mA    19.07mA
432mV     21.23mA    18.85mA    21.86mA
570mV     22.65mA    20.65mA    22.36mA
708mV     22.86mA    21.3mA     22.36mA
3V        22.86mA    21.32mA    22.36mA
[Pullup]
|Voltage   I(typ)   I(min)   I(max)
-1.5V     20.07mA    19.53mA    9.104mA
-956mV    20.07mA    19.53mA    9.085mA
-864mV    19.97mA    19.53mA    8.033mA
-772mV    18.26mA    19.53mA    6.731mA
-726mV    17.12mA    18.95mA    5.952mA
-542mV    11.4mA     13.59mA    2.002mA
-82mV     -6.636mA   -3.946mA   -11.1mA
148mV     -14.59mA   -11.68mA   -16.81mA
378mV     -20.28mA   -17.3mA    -20.52mA
562mV     -22.84mA   -20.08mA   -21.61mA
838mV     -23.72mA   -21.63mA   -21.62mA
3V        -23.72mA   -21.65mA   -21.62mA
[GND_clamp]
|Voltage   I(typ)   I(min)   I(max)
-1.5V     -423.6mA   -473.4mA   -391.3mA
-1.159V   -170.8mA   -226.4mA   -140.1mA
-1.128V   -150.6mA   -205.4mA   -123mA
-1.097V   -131.5mA   -185mA     -108.4mA
-1.035V   -97.76mA   -145.9mA   -88.03mA
-942mV    -62.68mA   -94.08mA   -70.99mA
-849mV    -45.44mA   -55.18mA   -56.59mA
-787mV    -37.67mA   -38mA      -47.37mA
-632mV    -20.99mA   -17.55mA   -26.32mA
-384mV    -4.202mA   -3.934mA   -4.89mA
19mV      0A         0A         0A
3V        0A         0A         0A
[POWER_clamp]
|Voltage   I(typ)   I(min)   I(max)
-1.5V     377.8mA    420.9mA    350.6mA
-1.166V   135.9mA    186.4mA    106mA
-1.104V   98.02mA    147mA      72.63mA
-1.042V   66.02mA    110.5mA    49.91mA
-1.011V   53.08mA    93.78mA    43.04mA
-949mV    34.63mA    64.31mA    34.62mA
-887mV    24.77mA    41.57mA    28.48mA
-825mV    19.16mA    26.4mA     22.89mA
-732mV    13.32mA    14.81mA    16.07mA
-546mV    6.068mA    6.58mA     7.125mA
-50mV     295.8uA    241.2uA    397.5uA
3V        -17.93mA   -11.75mA   -23.64mA
[Ramp]
| variable   typ   min   max
dV/dt_r   0.673/0.463n   0.601/0.484n   0.710/0.627n
dV/dt_f   0.590/0.525n   0.550/0.505n   0.623/0.732n
R_load = 50.000
[Rising Waveform]
R_fixture = 50.000
V_fixture = 0.000
V_fixture_min = 0.000
V_fixture_max = 0.000
|  time   V(typ)   V(min)   V(max)
0s        830.8uV    1.004mV    853.1uV
351ps     1.303mV    1.073mV    -5.138mV
470ps     4.469mV    1.126mV    461.8mV
568ps     268mV      1.442mV    651.2mV
719ps     652.8mV    12.94mV    804.8mV
887ps     828.5mV    410.7mV    897.7mV
1.068ns   918mV      672.7mV    956.4mV
1.388ns   989.5mV    834.6mV    1.016V
2.705ns   1.069V     950.5mV    1.112V
30ns      1.123V     1.003V     1.183V
[Rising Waveform]
R_fixture = 50.000
V_fixture = 0.750
V_fixture_min = 0.713
V_fixture_max = 0.789
|  time   V(typ)   V(min)   V(max)
0s        253.1mV    246.4mV    297.3mV
346ps     253.4mV    246.5mV    299.6mV
456ps     260mV      246.6mV    876mV
617ps     866.4mV    243.9mV    1.182V
690ps     1.031V     266.9mV    1.247V
741ps     1.101V     390.8mV    1.28V
890ps     1.214V     852mV      1.343V
1.07ns    1.276V     1.071V     1.385V
2.081ns   1.357V     1.245V     1.467V
30ns      1.411V     1.299V     1.532V
[Falling Waveform]
R_fixture = 50.000
V_fixture = 0.750
V_fixture_min = 0.713
V_fixture_max = 0.789
|  time   V(typ)   V(min)   V(max)
0s        1.411V     1.299V     1.532V
351ps     1.411V     1.299V     1.532V
461ps     1.407V     1.299V     971.6mV
601ps     796.6mV    1.301V     667.7mV
681ps     618.1mV    1.278V     583.1mV
751ps     530.6mV    1.045V     532.9mV
861ps     449.7mV    660.3mV    480.9mV
1.041ns   383.2mV    454.5mV    433.4mV
1.931ns   305.8mV    298.4mV    360.5mV
30ns      253.1mV    246.4mV    297.3mV
[Falling Waveform]
R_fixture = 50.000
V_fixture = 0.000
V_fixture_min = 0.000
V_fixture_max = 0.000
|  time   V(typ)   V(min)   V(max)
0s        1.123V     1.003V     1.183V
351ps     1.122V     1.003V     1.178V
451ps     1.12V      1.003V     500.3mV
561ps     500.5mV    1.005V     279.4mV
641ps     293mV      1.008V     210.2mV
691ps     234.7mV    928.9mV    181.8mV
811ps     156.8mV    371.7mV    137.8mV
921ps     119.1mV    212.3mV    114mV
1.754ns   46.22mV    47.94mV    53.11mV
30ns      830.8uV    1.004mV    853.1uV
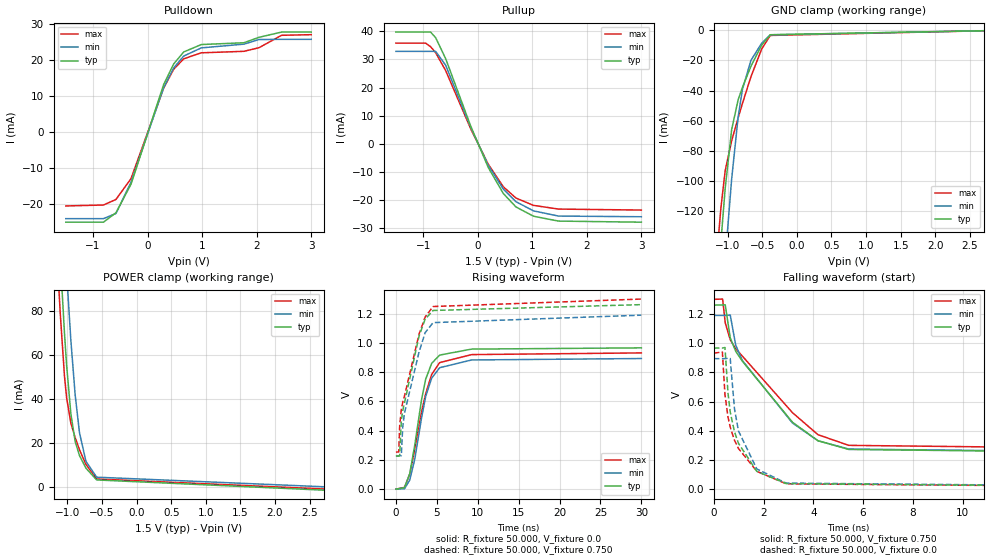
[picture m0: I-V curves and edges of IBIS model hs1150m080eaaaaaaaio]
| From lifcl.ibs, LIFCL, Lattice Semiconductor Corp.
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|Model hs1150m080eaaaaaaaio
[Model] hs1150m080eaaaaaaaio
Model_type I/O
Polarity   Non-Inverting
Enable   Active-Low
Vinl =  0.650V
Vinh =  0.850V
Vmeas =  0.750V
Cref =  30.000pF
Rref =  50.000
Vref =  0.750V
C_comp   5.000pF   4.000pF   5.500pF
[Temperature Range]   25.000   0.125k   -40.000
[Voltage Range]   1.500V   1.430V   1.580V
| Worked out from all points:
|   slope of the pulldown table from 0 to 0.225 V, typ, clamps not added: 21.9 ohm
|   slope of the pullup table from 0 to 0.225 V, typ, clamps not added: 23.2 ohm
|   GND clamp passes 1 mA (typ) near -0.31 V on its own axis
|   POWER clamp passes 1 mA (typ) near -0.43 V on its own axis
|   rising waveform, R_fixture 50.000, V_fixture 0.0: 20-80 % time 1.74ns typ, 1.83ns min, 2.09ns max; typ from 0 V to 0.966 V
|   rising waveform, R_fixture 50.000, V_fixture 0.750: 20-80 % time 2.25ns typ, 2.27ns min, 2.48ns max; typ from 0.226 V to 1.26 V
|   falling waveform, R_fixture 50.000, V_fixture 0.750: 20-80 % time 2.68ns typ, 2.49ns min, 2.98ns max; typ from 1.26 V to 0.227 V
|   falling waveform, R_fixture 50.000, V_fixture 0.0: 20-80 % time 840ps typ, 789ps min, 963ps max; typ from 0.967 V to 0.001 V
[Pulldown]
|Voltage   I(typ)   I(min)   I(max)
-1.5V     -25.05mA   -24.07mA   -20.54mA
-810mV    -25.05mA   -24.07mA   -20.28mA
-580mV    -22.42mA   -22.63mA   -18.73mA
-304mV    -14.5mA    -13.9mA    -12.94mA
294mV     13.17mA    12.32mA    12.19mA
478mV     18.9mA     17.77mA    17.43mA
662mV     22.23mA    21.1mA     20.33mA
984mV     24.29mA    23.36mA    21.99mA
1.766V    24.79mA    24.4mA     22.41mA
2.042V    26.3mA     25.68mA    23.41mA
2.456V    27.75mA    25.74mA    26.86mA
3V        27.75mA    25.74mA    27.03mA
[Pullup]
|Voltage   I(typ)   I(min)   I(max)
-1.5V     39.75mA    32.88mA    35.82mA
-956mV    39.75mA    32.88mA    35.82mA
-864mV    39.75mA    32.88mA    34.55mA
-772mV    37.76mA    32.88mA    32.41mA
-588mV    30.29mA    27.95mA    26.05mA
-128mV    6.218mA    5.776mA    5.269mA
194mV     -8.502mA   -7.753mA   -7.355mA
470mV     -17.76mA   -16.17mA   -15.37mA
700mV     -22.51mA   -20.65mA   -19.34mA
1.022V    -25.82mA   -23.92mA   -21.96mA
1.482V    -27.56mA   -25.77mA   -23.28mA
3V        -27.95mA   -26.01mA   -23.63mA
[GND_clamp]
|Voltage   I(typ)   I(min)   I(max)
-1.5V     -437.6mA   -483.1mA   -411.3mA
-1.159V   -181.2mA   -234mA     -153.2mA
-1.128V   -160.4mA   -212.8mA   -134.5mA
-1.097V   -140.5mA   -192mA     -117.9mA
-1.035V   -104.9mA   -152.2mA   -93.08mA
-942mV    -66.01mA   -98.88mA   -73.31mA
-849mV    -46.26mA   -57.94mA   -58.29mA
-787mV    -38.01mA   -39.4mA    -48.69mA
-663mV    -23.84mA   -19.92mA   -30.76mA
-508mV    -9.791mA   -8.549mA   -12.41mA
-384mV    -2.92mA    -2.99mA    -3.391mA
3V        0A         0A         0A
[POWER_clamp]
|Voltage   I(typ)   I(min)   I(max)
-1.5V     391.5mA    430.3mA    369.8mA
-1.166V   144.9mA    193mA      117.4mA
-1.135V   124.5mA    172.6mA    97.69mA
-1.104V   105.1mA    152.8mA    79.63mA
-1.042V   70.22mA    115.2mA    50.64mA
-1.011V   55.5mA     97.74mA    40.7mA
-949mV    33.19mA    66.57mA    29.05mA
-887mV    20.7mA     41.83mA    22.48mA
-825mV    14.31mA    24.76mA    16.96mA
-732mV    8.59mA     11.69mA    10.31mA
-577mV    3.202mA    4.456mA    3.639mA
3V        -1.88mA    -305.7uA   -1.328mA
[Ramp]
| variable   typ   min   max
dV/dt_r   0.579/1.756n   0.535/1.849n   0.559/2.110n
dV/dt_f   0.589/2.905n   0.550/2.745n   0.585/3.155n
R_load = 50.000
[Rising Waveform]
R_fixture= 50.000
V_fixture= 0.0
V_fixture_min= 0.0
V_fixture_max= 0.0
|time   V(typ)   V(min)   V(max)
0s        13.61uV    415.9uV    2.157uV
1.051ns   11.01mV    3.23mV     12.37mV
1.69ns    106.3mV    62.38mV    102.5mV
2.301ns   300.6mV    203.2mV    271.5mV
3.129ns   611mV      485.7mV    527.5mV
3.641ns   752.1mV    634mV      653.4mV
4.371ns   860mV      758.9mV    784.3mV
5.346ns   916.2mV    830mV      864.9mV
9.254ns   957.1mV    882.9mV    919.5mV
30ns      965.6mV    892.7mV    931.1mV
[Rising Waveform]
R_fixture= 50.000
V_fixture= 0.750
V_fixture_min= 0.713
V_fixture_max= 0.789
|time   V(typ)   V(min)   V(max)
0s        226.1mV    228.1mV    253.1mV
346ps     226.4mV    228.1mV    254.4mV
458ps     229.8mV    228.3mV    433.3mV
658ps     464.5mV    228.5mV    543.3mV
821ps     531.9mV    416.2mV    590.4mV
1.03ns    585.7mV    516mV      632.5mV
2.825ns   1.046V     937.1mV    1.059V
3.581ns   1.163V     1.07V      1.177V
4.546ns   1.221V     1.138V     1.248V
30ns      1.261V     1.189V     1.299V
[Falling Waveform]
R_fixture= 50.000
V_fixture= 0.750
V_fixture_min= 0.713
V_fixture_max= 0.789
|time   V(typ)   V(min)   V(max)
0s        1.261V     1.19V      1.3V
356ps     1.261V     1.19V      1.302V
460ps     1.263V     1.19V      1.14V
662ps     1.036V     1.193V     1.023V
881ps     944.6mV    987.1mV    961.7mV
1.149ns   876.6mV    881.1mV    911.3mV
3.165ns   458.4mV    453.1mV    523.9mV
4.189ns   332.1mV    331.6mV    373.3mV
5.426ns   272.3mV    275mV      300.3mV
30ns      226.9mV    229.1mV    253.7mV
[Falling Waveform]
R_fixture= 50.000
V_fixture= 0.0
V_fixture_min= 0.0
V_fixture_max= 0.0
|time   V(typ)   V(min)   V(max)
0s        966.6mV    894mV      932mV
346ps     966.2mV    893.7mV    939.3mV
450ps     970.2mV    893.9mV    645.9mV
571ps     659.6mV    896.9mV    495.1mV
661ps     527.9mV    894.8mV    425.2mV
831ps     394.4mV    552mV      335.6mV
991ps     314.9mV    399.7mV    279.4mV
1.73ns    122.3mV    138.5mV    122.4mV
2.911ns   38.55mV    41.94mV    36.85mV
30ns      590.5uV    1.181mV    373.1uV
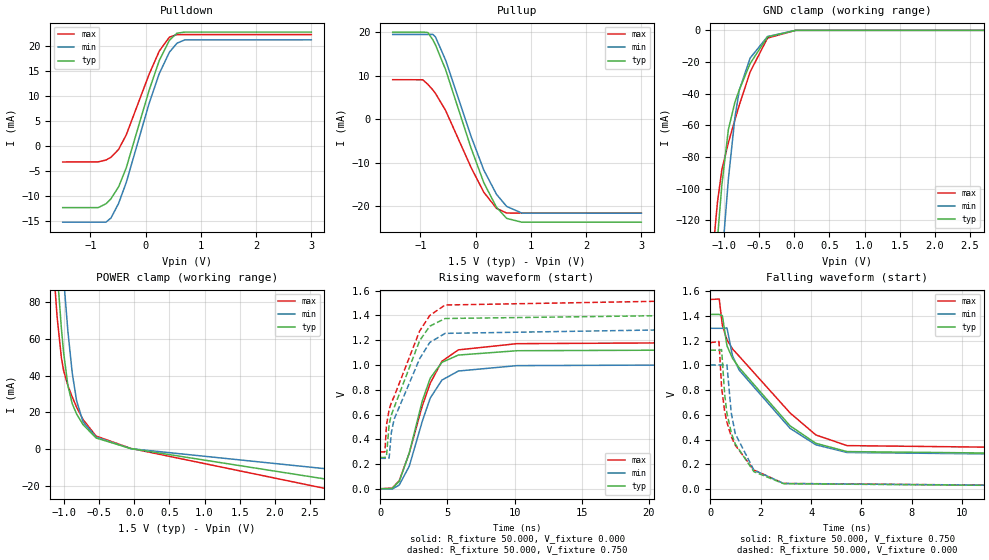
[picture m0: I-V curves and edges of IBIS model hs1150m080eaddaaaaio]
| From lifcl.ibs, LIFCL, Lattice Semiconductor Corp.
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|Model hs1150m080eaddaaaaio
[Model] hs1150m080eaddaaaaio
Model_type I/O
Polarity   Non-Inverting
Enable   Active-Low
Vinl =  0.650V
Vinh =  0.850V
Vmeas =  0.750V
Cref =  30.000pF
Rref =  50.000
Vref =  0.750V
C_comp   5.000pF   4.000pF   5.500pF
[Temperature Range]   25.000   0.125k   -40.000
[Voltage Range]   1.500V   1.430V   1.580V
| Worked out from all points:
|   slope of the pulldown table from 0 to 0.225 V, typ, clamps not added: 29.5 ohm
|   slope of the pullup table from 0 to 0.225 V, typ, clamps not added: 31.7 ohm
|   GND clamp passes 1 mA (typ) near -0.15 V on its own axis
|   POWER clamp passes 1 mA (typ) near -0.17 V on its own axis
|   rising waveform, R_fixture 50.000, V_fixture 0.000: 20-80 % time 1.74ns typ, 1.83ns min, 2.09ns max; typ from 0.001 V to 1.12 V
|   rising waveform, R_fixture 50.000, V_fixture 0.750: 20-80 % time 2.25ns typ, 2.27ns min, 2.48ns max; typ from 0.253 V to 1.41 V
|   falling waveform, R_fixture 50.000, V_fixture 0.750: 20-80 % time 2.68ns typ, 2.5ns min, 2.98ns max; typ from 1.41 V to 0.253 V
|   falling waveform, R_fixture 50.000, V_fixture 0.000: 20-80 % time 840ps typ, 789ps min, 963ps max; typ from 1.12 V to 0.001 V
[Pulldown]
|Voltage   I(typ)   I(min)   I(max)
-1.5V     -12.24mA   -15.16mA   -3.116mA
-856mV    -12.24mA   -15.16mA   -3.091mA
-718mV    -11.49mA   -15.16mA   -2.735mA
-626mV    -10.47mA   -14.32mA   -2.18mA
-488mV    -8.076mA   -11.39mA   -594uA
-350mV    -4.287mA   -7.226mA   2.301mA
64mV      11.22mA    8.592mA    14.42mA
248mV     17.18mA    14.57mA    19.07mA
432mV     21.23mA    18.85mA    21.86mA
570mV     22.65mA    20.65mA    22.36mA
708mV     22.86mA    21.3mA     22.36mA
3V        22.86mA    21.31mA    22.36mA
[Pullup]
|Voltage   I(typ)   I(min)   I(max)
-1.5V     20.07mA    19.53mA    9.104mA
-956mV    20.07mA    19.53mA    9.085mA
-864mV    19.97mA    19.53mA    8.033mA
-772mV    18.26mA    19.53mA    6.731mA
-726mV    17.12mA    18.95mA    5.952mA
-542mV    11.4mA     13.6mA     2.002mA
-82mV     -6.636mA   -3.945mA   -11.1mA
148mV     -14.59mA   -11.68mA   -16.81mA
378mV     -20.28mA   -17.29mA   -20.52mA
562mV     -22.84mA   -20.08mA   -21.61mA
838mV     -23.72mA   -21.63mA   -21.62mA
3V        -23.72mA   -21.65mA   -21.62mA
[GND_clamp]
|Voltage   I(typ)   I(min)   I(max)
-1.5V     -423.6mA   -473.4mA   -391.3mA
-1.159V   -170.8mA   -226.4mA   -140.1mA
-1.128V   -150.6mA   -205.4mA   -123mA
-1.097V   -131.5mA   -185mA     -108.4mA
-1.035V   -97.76mA   -145.9mA   -88.03mA
-942mV    -62.68mA   -94.08mA   -70.99mA
-849mV    -45.44mA   -55.18mA   -56.59mA
-787mV    -37.67mA   -38mA      -47.37mA
-632mV    -20.99mA   -17.55mA   -26.32mA
-384mV    -4.202mA   -3.933mA   -4.89mA
19mV      0A         0A         0A
3V        0A         0A         0A
[POWER_clamp]
|Voltage   I(typ)   I(min)   I(max)
-1.5V     377.8mA    420.9mA    350.6mA
-1.166V   135.9mA    186.4mA    106mA
-1.104V   98.02mA    147mA      72.63mA
-1.042V   66.02mA    110.5mA    49.91mA
-1.011V   53.08mA    93.78mA    43.04mA
-949mV    34.63mA    64.31mA    34.62mA
-887mV    24.77mA    41.57mA    28.48mA
-825mV    19.16mA    26.4mA     22.89mA
-732mV    13.32mA    14.81mA    16.07mA
-546mV    6.068mA    6.58mA     7.125mA
-50mV     295.8uA    241.2uA    397.5uA
3V        -17.93mA   -11.75mA   -23.64mA
[Ramp]
| variable   typ   min   max
dV/dt_r   0.673/1.755n   0.601/1.850n   0.710/2.096n
dV/dt_f   0.619/2.905n   0.550/2.745n   0.623/3.154n
R_load = 50.000
[Rising Waveform]
R_fixture = 50.000
V_fixture = 0.000
V_fixture_min = 0.000
V_fixture_max = 0.000
|  time   V(typ)   V(min)   V(max)
0s        830.8uV    1.003mV    853.1uV
878ps     3.411mV    -2.546mV   5.516mV
1.41ns    59.51mV    30.67mV    65.34mV
2.161ns   290.1mV    184mV      289.8mV
3.129ns   710.6mV    545.9mV    670.8mV
3.72ns    893.6mV    732.9mV    852.6mV
4.588ns   1.021V     877.8mV    1.03V
5.814ns   1.08V      951.2mV    1.122V
10.18ns   1.115V     994.7mV    1.172V
30ns      1.123V     1.003V     1.183V
[Rising Waveform]
R_fixture = 50.000
V_fixture = 0.750
V_fixture_min = 0.713
V_fixture_max = 0.789
|  time   V(typ)   V(min)   V(max)
0s        253.1mV    246.4mV    297.3mV
346ps     253.5mV    246.5mV    298.8mV
458ps     257.4mV    246.7mV    509.9mV
658ps     520.1mV    247mV      639.8mV
821ps     595.4mV    452.6mV    695.4mV
1.03ns    655.7mV    562mV      745mV
2.929ns   1.196V     1.05V      1.274V
3.686ns   1.313V     1.182V     1.4V
4.826ns   1.375V     1.255V     1.484V
30ns      1.411V     1.299V     1.532V
[Falling Waveform]
R_fixture = 50.000
V_fixture = 0.750
V_fixture_min = 0.713
V_fixture_max = 0.789
|  time   V(typ)   V(min)   V(max)
0s        1.411V     1.299V     1.532V
356ps     1.411V     1.299V     1.535V
480ps     1.401V     1.299V     1.322V
662ps     1.158V     1.302V     1.206V
881ps     1.057V     1.077V     1.133V
1.149ns   980.5mV    961mV      1.073V
3.165ns   512.3mV    492mV      616.2mV
4.188ns   371mV      358.9mV    438.5mV
5.426ns   304mV      296.8mV    352.3mV
30ns      253.1mV    246.4mV    297.3mV
[Falling Waveform]
R_fixture = 50.000
V_fixture = 0.000
V_fixture_min = 0.000
V_fixture_max = 0.000
|  time   V(typ)   V(min)   V(max)
0s        1.123V     1.003V     1.183V
346ps     1.122V     1.003V     1.193V
450ps     1.127V     1.003V     820.2mV
571ps     766mV      1.006V     628.8mV
661ps     613mV      1.004V     540.1mV
831ps     458.1mV    619.2mV    426.3mV
991ps     365.8mV    448.3mV    355mV
1.73ns    142.1mV    155.1mV    155.7mV
2.911ns   44.91mV    46.75mV    47.15mV
30ns      830.8uV    1.003mV    853.1uV
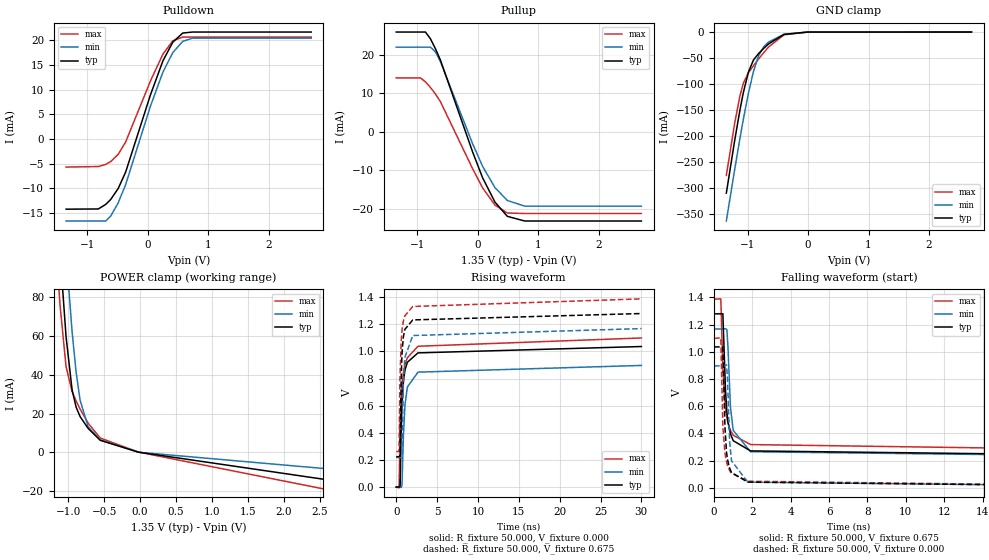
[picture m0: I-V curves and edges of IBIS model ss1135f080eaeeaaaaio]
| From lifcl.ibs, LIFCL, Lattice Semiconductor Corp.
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|Model ss1135f080eaeeaaaaio
[Model] ss1135f080eaeeaaaaio
| Clamp models do not include dynamic input termination. Please refer to
| the ss1135axxxeaeeaaaain model for input termination.
Model_type I/O
Polarity   Non-Inverting
Enable   Active-Low
Vinl =  0.575V
Vinh =  0.775V
Vmeas =  0.675V
Cref =  30.000pF
Rref =  50.000
Vref =  0.675V
C_comp   5.000pF   4.000pF   5.500pF
[Temperature Range]   25.000   0.125k   -40.000
[Voltage Range]   1.350V   1.280V   1.420V
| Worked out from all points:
|   slope of the pulldown table from 0 to 0.203 V, typ, clamps not added: 28.4 ohm
|   slope of the pullup table from 0 to 0.203 V, typ, clamps not added: 28.3 ohm
|   GND clamp passes 1 mA (typ) near -0.15 V on its own axis
|   POWER clamp passes 1 mA (typ) near -0.17 V on its own axis
|   rising waveform, R_fixture 50.000, V_fixture 0.000: 20-80 % time 433ps typ, 506ps min, 565ps max; typ from 0.001 V to 1.04 V
|   rising waveform, R_fixture 50.000, V_fixture 0.675: 20-80 % time 289ps typ, 346ps min, 331ps max; typ from 0.225 V to 1.28 V
|   falling waveform, R_fixture 50.000, V_fixture 0.675: 20-80 % time 267ps typ, 282ps min, 307ps max; typ from 1.28 V to 0.225 V
|   falling waveform, R_fixture 50.000, V_fixture 0.000: 20-80 % time 198ps typ, 217ps min, 218ps max; typ from 1.04 V to 0.001 V
[Pulldown]
|Voltage   I(typ)   I(min)   I(max)
-1.35V    -14.2mA    -16.6mA    -5.668mA
-817mV    -14.16mA   -16.6mA    -5.567mA
-694mV    -13.22mA   -16.6mA    -5.12mA
-612mV    -12.22mA   -15.6mA    -4.552mA
-489mV    -10.01mA   -12.91mA   -3.091mA
-366mV    -6.687mA   -9.216mA   -589.5uA
44mV      8.961mA    6.685mA    11.78mA
249mV     15.83mA    13.54mA    17.2mA
413mV     19.64mA    17.53mA    19.91mA
577mV     21.48mA    19.8mA     20.67mA
741mV     21.69mA    20.46mA    20.67mA
2.7V      21.69mA    20.46mA    20.67mA
[Pullup]
|Voltage   I(typ)   I(min)   I(max)
-1.35V    25.87mA    21.95mA    13.97mA
-949mV    25.87mA    21.95mA    13.97mA
-867mV    25.87mA    21.95mA    12.94mA
-785mV    24.13mA    21.95mA    11.5mA
-703mV    21.57mA    20.76mA    9.813mA
-621mV    18.65mA    18.25mA    7.842mA
-88mV     -5.238mA   -3.1mA     -9.59mA
76mV      -11.91mA   -8.954mA   -14.53mA
281mV     -18.25mA   -14.49mA   -19.03mA
486mV     -21.96mA   -17.84mA   -21.09mA
773mV     -23.17mA   -19.31mA   -21.22mA
2.7V      -23.17mA   -19.31mA   -21.22mA
[GND_clamp]
|Voltage   I(typ)   I(min)   I(max)
-1.35V    -309.8mA   -363.4mA   -275.8mA
-1.21V    -207.1mA   -262.8mA   -173.9mA
-1.126V   -150.5mA   -205.1mA   -123.2mA
-1.07V    -117mA     -168.5mA   -98.8mA
-986mV    -77.25mA   -118.1mA   -78.4mA
-902mV    -53.89mA   -76.04mA   -64.81mA
-818mV    -41.42mA   -46.02mA   -52mA
-734mV    -31.56mA   -28.41mA   -39.82mA
-650mV    -22.69mA   -19.03mA   -28.57mA
-398mV    -4.585mA   -4.332mA   -5.35mA
-6mV      -40.55uA   -29.88uA   -52.89uA
2.7V      0A         0A         0A
[POWER_clamp]
|Voltage   I(typ)   I(min)   I(max)
-1.35V    264.6mA    312.3mA    234.2mA
-1.17V    138mA      188.5mA    107.5mA
-1.142V   120.1mA    170.4mA    90.88mA
-1.114V   103.1mA    152.7mA    75.88mA
-1.03V    59.59mA    103.2mA    44.19mA
-946mV    32.22mA    62.05mA    31.33mA
-890mV    23.29mA    41.28mA    26.5mA
-834mV    18.42mA    26.8mA     22.3mA
-722mV    12.33mA    13.1mA     15mA
-554mV    6.226mA    6.542mA    7.404mA
-22mV     128.8uA    103.1uA    167.9uA
2.7V      -14.6mA    -8.747mA   -19.86mA
[Ramp]
| variable   typ   min   max
dV/dt_r   0.621/0.435n   0.538/0.507n   0.659/0.567n
dV/dt_f   0.575/0.441n   0.534/0.436n   0.576/0.591n
R_load = 50.000
[Rising Waveform]
R_fixture = 50.000
V_fixture = 0.000
V_fixture_min = 0.000
V_fixture_max = 0.000
|  time   V(typ)   V(min)   V(max)
0s        509uV      510.9uV    705uV
351ps     1.026mV    578.6uV    -4.828mV
477ps     7.393mV    662.4uV    446.2mV
619ps     434.2mV    -2.387mV   676.5mV
707ps     608.8mV    14.98mV    754mV
887ps     781.7mV    385.8mV    849.6mV
1.075ns   862.7mV    607.7mV    904.7mV
1.366ns   919.9mV    737.6mV    953.1mV
2.663ns   989.1mV    847.4mV    1.038V
30ns      1.036V     896.7mV    1.099V
[Rising Waveform]
R_fixture = 50.000
V_fixture = 0.675
V_fixture_min = 0.642
V_fixture_max = 0.710
|  time   V(typ)   V(min)   V(max)
0s        224.5mV    219mV      262.1mV
346ps     224.8mV    219.1mV    262.6mV
457ps     228.5mV    219.2mV    795.3mV
607ps     783.8mV    216.6mV    1.073V
687ps     949.4mV    238.8mV    1.14V
737ps     1.011V     358mV      1.17V
877ps     1.107V     755.8mV    1.224V
1.057ns   1.162V     955.9mV    1.262V
2.027ns   1.232V     1.117V     1.331V
30ns      1.279V     1.168V     1.387V
[Falling Waveform]
R_fixture = 50.000
V_fixture = 0.675
V_fixture_min = 0.642
V_fixture_max = 0.710
|  time   V(typ)   V(min)   V(max)
0s        1.279V     1.168V     1.387V
351ps     1.279V     1.168V     1.389V
458ps     1.28V      1.168V     875.1mV
597ps     714.8mV    1.17V      584.6mV
670ps     554.6mV    1.164V     514.5mV
727ps     484.7mV    1.026V     476.3mV
854ps     397.1mV    593.7mV    421.6mV
1ns       346.7mV    421.9mV    386.7mV
1.903ns   272mV      265.7mV    318.5mV
30ns      224.5mV    219mV      262.1mV
[Falling Waveform]
R_fixture = 50.000
V_fixture = 0.000
V_fixture_min = 0.000
V_fixture_max = 0.000
|  time   V(typ)   V(min)   V(max)
0s        1.036V     896.7mV    1.099V
351ps     1.036V     896.5mV    1.102V
457ps     1.036V     896.5mV    454.5mV
567ps     447.7mV    899.4mV    255.3mV
650ps     260.4mV    904.2mV    191mV
701ps     209mV      801.8mV    165.2mV
810ps     145.4mV    342.4mV    128.7mV
910ps     112.8mV    199mV      107.9mV
1.758ns   42.39mV    42.56mV    49.14mV
30ns      509uV      510.9uV    705uV
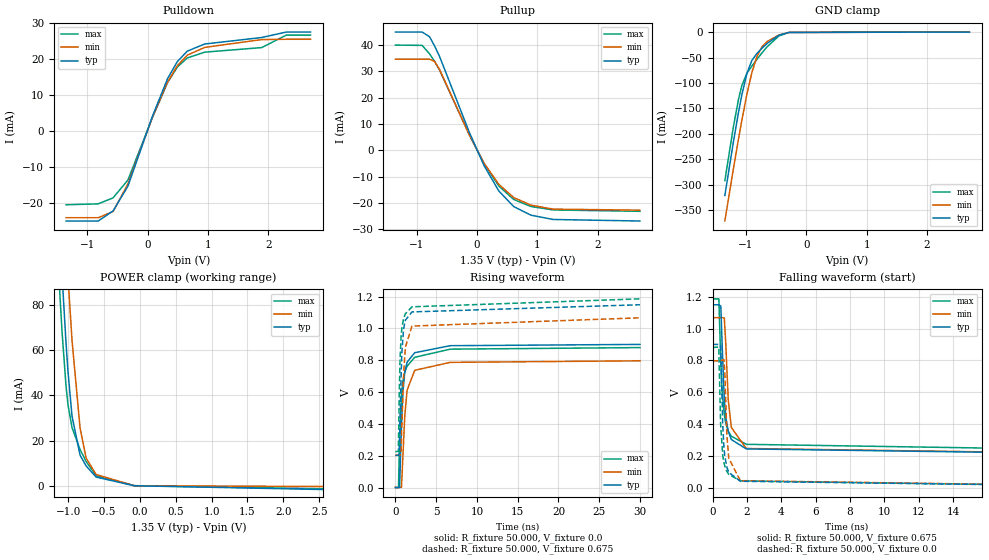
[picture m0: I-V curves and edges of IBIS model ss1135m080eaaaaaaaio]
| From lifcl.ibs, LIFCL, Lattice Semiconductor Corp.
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|Model ss1135m080eaaaaaaaio
[Model] ss1135m080eaaaaaaaio
| Clamp models do not include dynamic input termination. Please refer to
| the ss1135axxxeaaaaaaain model for input termination.
Model_type I/O
Polarity   Non-Inverting
Enable   Active-Low
Vinl =  0.575V
Vinh =  0.775V
Vmeas =  0.675V
Cref =  30.000pF
Rref =  50.000
Vref =  0.675V
C_comp   5.000pF   4.000pF   5.500pF
[Temperature Range]   25.000   0.125k   -40.000
[Voltage Range]   1.350V   1.280V   1.420V
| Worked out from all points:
|   slope of the pulldown table from 0 to 0.203 V, typ, clamps not added: 21.7 ohm
|   slope of the pullup table from 0 to 0.203 V, typ, clamps not added: 21.2 ohm
|   GND clamp passes 1 mA (typ) near -0.31 V on its own axis
|   POWER clamp passes 1 mA (typ) near -0.43 V on its own axis
|   rising waveform, R_fixture 50.000, V_fixture 0.0: 20-80 % time 506ps typ, 623ps min, 585ps max; typ from 0 V to 0.9 V
|   rising waveform, R_fixture 50.000, V_fixture 0.675: 20-80 % time 367ps typ, 462ps min, 354ps max; typ from 0.202 V to 1.15 V
|   falling waveform, R_fixture 50.000, V_fixture 0.675: 20-80 % time 295ps typ, 326ps min, 323ps max; typ from 1.15 V to 0.203 V
|   falling waveform, R_fixture 50.000, V_fixture 0.0: 20-80 % time 215ps typ, 242ps min, 228ps max; typ from 0.9 V to 0.001 V
[Pulldown]
|Voltage   I(typ)   I(min)   I(max)
-1.35V    -25.07mA   -24.15mA   -20.55mA
-817mV    -25.07mA   -24.15mA   -20.3mA
-571mV    -22.26mA   -22.44mA   -18.63mA
-325mV    -15.37mA   -14.75mA   -13.67mA
85mV      4.241mA    3.989mA    3.92mA
331mV     14.51mA    13.58mA    13.43mA
495mV     19.31mA    18.17mA    17.79mA
659mV     22.19mA    21.07mA    20.3mA
946mV     24.17mA    23.22mA    21.9mA
1.889V    25.97mA    25.4mA     23.17mA
2.299V    27.5mA     25.49mA    26.65mA
2.7V      27.5mA     25.49mA    26.65mA
[Pullup]
|Voltage   I(typ)   I(min)   I(max)
-1.35V    45.01mA    34.66mA    40.04mA
-908mV    45.01mA    34.66mA    39.93mA
-785mV    43.22mA    34.66mA    36.71mA
-703mV    39.77mA    33.84mA    33.89mA
-621mV    35.8mA     30.83mA    30.63mA
-129mV    7.011mA    6.007mA    6.017mA
117mV     -5.804mA   -4.887mA   -5.07mA
363mV     -15.5mA    -12.97mA   -13.61mA
609mV     -21.42mA   -17.99mA   -18.71mA
896mV     -24.7mA    -20.88mA   -21.4mA
1.265V    -26.33mA   -22.4mA    -22.71mA
2.7V      -26.91mA   -22.78mA   -23.22mA
[GND_clamp]
|Voltage   I(typ)   I(min)   I(max)
-1.35V    -320.9mA   -371mA     -291.7mA
-1.21V    -216.8mA   -269.5mA   -187.2mA
-1.126V   -159mA     -211.3mA   -133.3mA
-1.07V    -124.2mA   -174.2mA   -105.6mA
-986mV    -81.78mA   -122.8mA   -81.18mA
-902mV    -55.61mA   -79.36mA   -66.72mA
-818mV    -41.95mA   -47.73mA   -53.44mA
-734mV    -31.67mA   -28.77mA   -40.78mA
-650mV    -22.47mA   -18.69mA   -29.01mA
-454mV    -6.221mA   -5.753mA   -7.69mA
-286mV    -734.4uA   -759.2uA   -785.5uA
2.7V      0A         0A         0A
[POWER_clamp]
|Voltage   I(typ)   I(min)   I(max)
-1.35V    276.5mA    320.5mA    251mA
-1.142V   128.3mA    176.6mA    100.9mA
-1.114V   110.5mA    158.5mA    83.9mA
-1.086V   93.5mA     140.9mA    68.53mA
-1.03V    63.21mA    107.6mA    44.18mA
-1.002V   50.42mA    92.11mA    35.83mA
-946mV    30.82mA    64.28mA    25.76mA
-834mV    13.57mA    25.52mA    16.1mA
-750mV    8.839mA    12.31mA    10.8mA
-610mV    3.896mA    5.035mA    4.505mA
-78mV     75.17uA    92.3uA     98.29uA
2.7V      -1.695mA   -291.3uA   -1.333mA
[Ramp]
| variable   typ   min   max
dV/dt_r   0.540/0.512n   0.478/0.626n   0.528/0.588n
dV/dt_f   0.540/0.479n   0.501/0.498n   0.542/0.600n
R_load = 50.000
[Rising Waveform]
R_fixture= 50.000
V_fixture= 0.0
V_fixture_min= 0.0
V_fixture_max= 0.0
|time   V(typ)   V(min)   V(max)
0s        6.451uV    244.9uV    812.4nV
373ps     745.4uV    301.2uV    -2.155mV
507ps     -259.3uV   523.9uV    299.3mV
737ps     385.4mV    1.458mV    582.1mV
918ps     601.7mV    199.3mV    669.3mV
1.146ns   724.9mV    452.9mV    725.4mV
1.43ns    788mV      612.1mV    762.9mV
2.36ns    847.3mV    736.8mV    818.6mV
6.715ns   891.6mV    786.8mV    869.8mV
30ns      899.7mV    796.6mV    879.7mV
[Rising Waveform]
R_fixture= 50.000
V_fixture= 0.675
V_fixture_min= 0.642
V_fixture_max= 0.710
|time   V(typ)   V(min)   V(max)
0s        201.9mV    203.8mV    225.7mV
351ps     202.2mV    203.9mV    227.3mV
467ps     208.4mV    204mV      589.7mV
557ps     404.6mV    203.4mV    797.2mV
687ps     694.2mV    213.6mV    944.5mV
787ps     849.2mV    386.5mV    1.002V
1.006ns   1V         716.9mV    1.064V
1.217ns   1.052V     881.7mV    1.092V
2.027ns   1.104V     1.015V     1.136V
30ns      1.149V     1.067V     1.186V
[Falling Waveform]
R_fixture= 50.000
V_fixture= 0.675
V_fixture_min= 0.642
V_fixture_max= 0.710
|time   V(typ)   V(min)   V(max)
0s        1.149V     1.068V     1.186V
362ps     1.149V     1.068V     1.186V
477ps     1.141V     1.068V     782mV
561ps     878mV      1.068V     592.9mV
680ps     555.5mV    1.066V     458.2mV
770ps     441.5mV    892.7mV    403.9mV
910ps     354.2mV    550.5mV    356mV
1.091ns   303.2mV    379mV      324mV
1.957ns   244.7mV    247.3mV    273.4mV
30ns      202.6mV    204.6mV    226.2mV
[Falling Waveform]
R_fixture= 50.000
V_fixture= 0.0
V_fixture_min= 0.0
V_fixture_max= 0.0
|time   V(typ)   V(min)   V(max)
0s        900.4mV    797.6mV    880.3mV
356ps     900.2mV    797.4mV    883.9mV
467ps     895.7mV    797.3mV    396mV
587ps     402.7mV    803mV      205.5mV
660ps     250.7mV    804.3mV    157.8mV
710ps     198.1mV    727.6mV    136.1mV
830ps     129.7mV    332.5mV    102.7mV
940ps     97.5mV     186.3mV    84.72mV
1.613ns   41.66mV    45.45mV    44.02mV
30ns      519.9uV    911.7uV    337.3uV
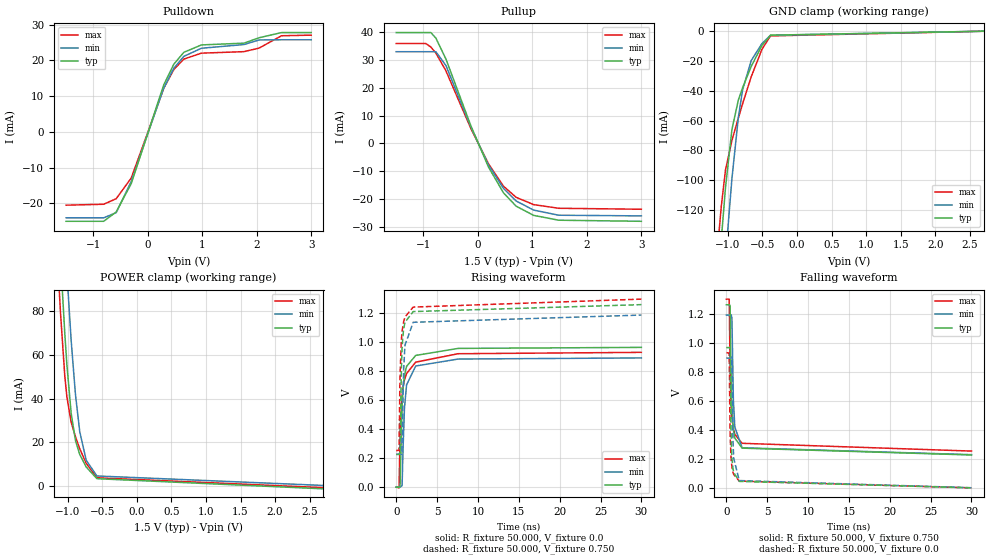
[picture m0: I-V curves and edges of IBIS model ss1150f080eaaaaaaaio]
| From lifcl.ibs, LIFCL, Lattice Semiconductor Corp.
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|Model ss1150f080eaaaaaaaio
[Model] ss1150f080eaaaaaaaio
| Clamp models do not include dynamic input termination. Please refer to
| the ss1150axxxeaaaaaaain model for input termination.
Model_type I/O
Polarity   Non-Inverting
Enable   Active-Low
Vinl =  0.650V
Vinh =  0.850V
Vmeas =  0.750V
Cref =  30.000pF
Rref =  50.000
Vref =  0.750V
C_comp   5.000pF   4.000pF   5.500pF
[Temperature Range]   25.000   0.125k   -40.000
[Voltage Range]   1.500V   1.430V   1.580V
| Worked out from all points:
|   slope of the pulldown table from 0 to 0.225 V, typ, clamps not added: 21.9 ohm
|   slope of the pullup table from 0 to 0.225 V, typ, clamps not added: 23.2 ohm
|   GND clamp passes 1 mA (typ) near -0.31 V on its own axis
|   POWER clamp passes 1 mA (typ) near -0.43 V on its own axis
|   rising waveform, R_fixture 50.000, V_fixture 0.0: 20-80 % time 460ps typ, 485ps min, 623ps max; typ from 0 V to 0.966 V
|   rising waveform, R_fixture 50.000, V_fixture 0.750: 20-80 % time 309ps typ, 341ps min, 359ps max; typ from 0.226 V to 1.26 V
|   falling waveform, R_fixture 50.000, V_fixture 0.750: 20-80 % time 285ps typ, 296ps min, 332ps max; typ from 1.26 V to 0.227 V
|   falling waveform, R_fixture 50.000, V_fixture 0.0: 20-80 % time 200ps typ, 217ps min, 219ps max; typ from 0.967 V to 0.001 V
[Pulldown]
|Voltage   I(typ)   I(min)   I(max)
-1.5V     -25.05mA   -24.07mA   -20.54mA
-810mV    -25.05mA   -24.07mA   -20.28mA
-580mV    -22.42mA   -22.64mA   -18.73mA
-304mV    -14.5mA    -13.9mA    -12.94mA
294mV     13.17mA    12.32mA    12.19mA
478mV     18.91mA    17.77mA    17.43mA
662mV     22.23mA    21.1mA     20.33mA
984mV     24.29mA    23.36mA    21.99mA
1.766V    24.79mA    24.4mA     22.41mA
2.042V    26.3mA     25.68mA    23.41mA
2.456V    27.75mA    25.74mA    26.86mA
3V        27.75mA    25.74mA    27.03mA
[Pullup]
|Voltage   I(typ)   I(min)   I(max)
-1.5V     39.75mA    32.88mA    35.82mA
-956mV    39.75mA    32.88mA    35.82mA
-864mV    39.75mA    32.88mA    34.55mA
-772mV    37.76mA    32.88mA    32.41mA
-588mV    30.29mA    27.95mA    26.05mA
-128mV    6.218mA    5.776mA    5.269mA
194mV     -8.502mA   -7.753mA   -7.355mA
470mV     -17.76mA   -16.17mA   -15.37mA
700mV     -22.51mA   -20.65mA   -19.34mA
1.022V    -25.82mA   -23.92mA   -21.96mA
1.482V    -27.56mA   -25.77mA   -23.28mA
3V        -27.95mA   -26.01mA   -23.63mA
[GND_clamp]
|Voltage   I(typ)   I(min)   I(max)
-1.5V     -437.6mA   -483.1mA   -411.3mA
-1.159V   -181.2mA   -234mA     -153.2mA
-1.128V   -160.4mA   -212.8mA   -134.5mA
-1.097V   -140.5mA   -192mA     -117.9mA
-1.035V   -104.9mA   -152.2mA   -93.08mA
-942mV    -66.01mA   -98.88mA   -73.31mA
-849mV    -46.26mA   -57.94mA   -58.29mA
-787mV    -38.01mA   -39.4mA    -48.69mA
-663mV    -23.84mA   -19.92mA   -30.76mA
-508mV    -9.791mA   -8.549mA   -12.41mA
-384mV    -2.92mA    -2.99mA    -3.392mA
3V        0A         0A         0A
[POWER_clamp]
|Voltage   I(typ)   I(min)   I(max)
-1.5V     391.5mA    430.3mA    369.8mA
-1.166V   144.9mA    193mA      117.4mA
-1.135V   124.5mA    172.6mA    97.69mA
-1.104V   105.1mA    152.8mA    79.63mA
-1.042V   70.22mA    115.2mA    50.64mA
-1.011V   55.5mA     97.74mA    40.7mA
-949mV    33.19mA    66.57mA    29.05mA
-887mV    20.7mA     41.83mA    22.48mA
-825mV    14.31mA    24.76mA    16.96mA
-732mV    8.589mA    11.69mA    10.31mA
-577mV    3.202mA    4.456mA    3.639mA
3V        -1.88mA    -305.7uA   -1.33mA
[Ramp]
| variable   typ   min   max
dV/dt_r   0.579/0.465n   0.535/0.484n   0.559/0.628n
dV/dt_f   0.590/0.525n   0.550/0.505n   0.585/0.732n
R_load = 50.000
[Rising Waveform]
R_fixture= 50.000
V_fixture= 0.0
V_fixture_min= 0.0
V_fixture_max= 0.0
|time   V(typ)   V(min)   V(max)
0s        13.61uV    415.9uV    2.157uV
351ps     419.7uV    477.2uV    -4.683mV
470ps     3.227mV    524.9uV    363.4mV
719ps     561.9mV    11.21mV    633.2mV
851ps     689.8mV    289.5mV    693.9mV
1.011ns   770.9mV    547.5mV    740.3mV
1.268ns   834.4mV    707mV      784.8mV
2.388ns   910.2mV    837mV      863.7mV
7.577ns   958.6mV    885.1mV    921.9mV
30ns      965.7mV    892.9mV    931.3mV
[Rising Waveform]
R_fixture= 50.000
V_fixture= 0.750
V_fixture_min= 0.713
V_fixture_max= 0.789
|time   V(typ)   V(min)   V(max)
0s        226.1mV    228.1mV    253.1mV
346ps     226.3mV    228.1mV    255mV
456ps     232.2mV    228.2mV    743.8mV
617ps     774.7mV    225.8mV    1.003V
690ps     921.1mV    246.8mV    1.058V
741ps     984mV      360.2mV    1.086V
900ps     1.089V     799.8mV    1.142V
1.07ns    1.139V     980.4mV    1.175V
2.08ns    1.213V     1.139V     1.244V
30ns      1.261V     1.189V     1.299V
[Falling Waveform]
R_fixture= 50.000
V_fixture= 0.750
V_fixture_min= 0.713
V_fixture_max= 0.789
|time   V(typ)   V(min)   V(max)
0s        1.261V     1.19V      1.3V
351ps     1.261V     1.19V      1.3V
461ps     1.257V     1.19V      824.9mV
601ps     711.9mV    1.192V     567.4mV
681ps     552.5mV    1.17V      495.8mV
751ps     474.5mV    956.6mV    453.2mV
861ps     402.3mV    606.1mV    409.1mV
1.041ns   343mV      418.7mV    368.9mV
1.931ns   273.9mV    276.4mV    307.1mV
30ns      226.8mV    229mV      253.6mV
[Falling Waveform]
R_fixture= 50.000
V_fixture= 0.0
V_fixture_min= 0.0
V_fixture_max= 0.0
|time   V(typ)   V(min)   V(max)
0s        966.6mV    894mV      932mV
351ps     966.4mV    893.8mV    927.4mV
451ps     964.8mV    893.9mV    393.7mV
561ps     430.5mV    895.4mV    219.8mV
627ps     271.2mV    899.6mV    172.9mV
691ps     201.9mV    827.7mV    142.9mV
811ps     134.9mV    331.1mV    108.2mV
901ps     107.1mV    204.8mV    92.29mV
1.581ns   44.97mV    50.65mV    47.07mV
30ns      570.6uV    1.17mV     360.9uV
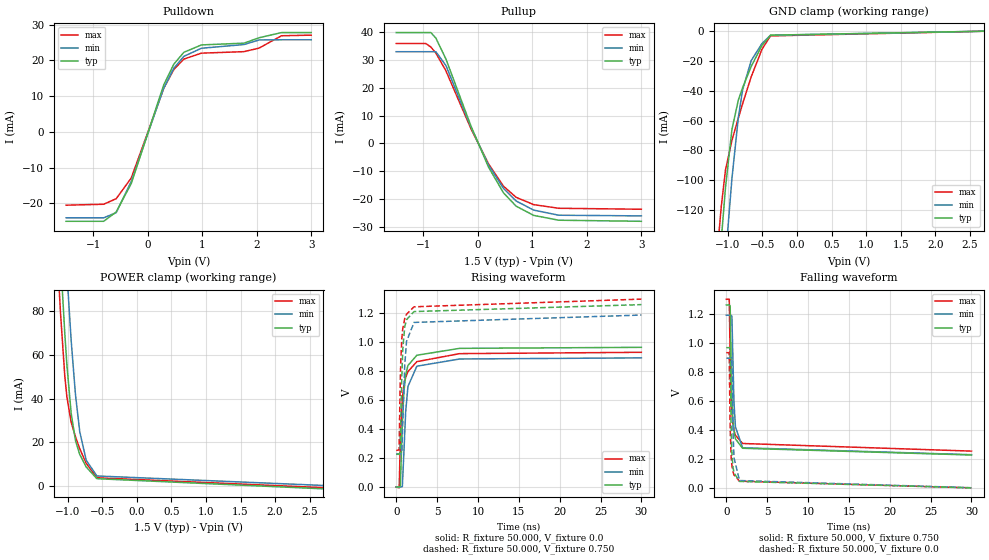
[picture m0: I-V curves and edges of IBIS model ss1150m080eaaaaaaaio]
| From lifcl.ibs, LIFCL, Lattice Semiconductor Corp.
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|Model ss1150m080eaaaaaaaio
[Model] ss1150m080eaaaaaaaio
| Clamp models do not include dynamic input termination. Please refer to
| the ss1150axxxeaaaaaaain model for input termination.
Model_type I/O
Polarity   Non-Inverting
Enable   Active-Low
Vinl =  0.650V
Vinh =  0.850V
Vmeas =  0.750V
Cref =  30.000pF
Rref =  50.000
Vref =  0.750V
C_comp   5.000pF   4.000pF   5.500pF
[Temperature Range]   25.000   0.125k   -40.000
[Voltage Range]   1.500V   1.430V   1.580V
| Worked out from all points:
|   slope of the pulldown table from 0 to 0.225 V, typ, clamps not added: 21.9 ohm
|   slope of the pullup table from 0 to 0.225 V, typ, clamps not added: 23.2 ohm
|   GND clamp passes 1 mA (typ) near -0.31 V on its own axis
|   POWER clamp passes 1 mA (typ) near -0.43 V on its own axis
|   rising waveform, R_fixture 50.000, V_fixture 0.0: 20-80 % time 528ps typ, 592ps min, 641ps max; typ from 0 V to 0.966 V
|   rising waveform, R_fixture 50.000, V_fixture 0.750: 20-80 % time 382ps typ, 455ps min, 381ps max; typ from 0.226 V to 1.26 V
|   falling waveform, R_fixture 50.000, V_fixture 0.750: 20-80 % time 317ps typ, 345ps min, 350ps max; typ from 1.26 V to 0.227 V
|   falling waveform, R_fixture 50.000, V_fixture 0.0: 20-80 % time 219ps typ, 245ps min, 231ps max; typ from 0.967 V to 0.001 V
[Pulldown]
|Voltage   I(typ)   I(min)   I(max)
-1.5V     -25.05mA   -24.07mA   -20.54mA
-810mV    -25.05mA   -24.07mA   -20.28mA
-580mV    -22.42mA   -22.64mA   -18.73mA
-304mV    -14.5mA    -13.9mA    -12.94mA
294mV     13.17mA    12.32mA    12.19mA
478mV     18.91mA    17.77mA    17.43mA
662mV     22.23mA    21.1mA     20.33mA
984mV     24.29mA    23.36mA    21.99mA
1.766V    24.79mA    24.4mA     22.41mA
2.042V    26.3mA     25.68mA    23.41mA
2.456V    27.75mA    25.74mA    26.86mA
3V        27.75mA    25.74mA    27.03mA
[Pullup]
|Voltage   I(typ)   I(min)   I(max)
-1.5V     39.75mA    32.88mA    35.82mA
-956mV    39.75mA    32.88mA    35.82mA
-864mV    39.75mA    32.88mA    34.55mA
-772mV    37.76mA    32.88mA    32.41mA
-588mV    30.29mA    27.95mA    26.05mA
-128mV    6.218mA    5.776mA    5.269mA
194mV     -8.502mA   -7.753mA   -7.355mA
470mV     -17.76mA   -16.17mA   -15.37mA
700mV     -22.51mA   -20.65mA   -19.34mA
1.022V    -25.82mA   -23.92mA   -21.96mA
1.482V    -27.56mA   -25.77mA   -23.28mA
3V        -27.95mA   -26.01mA   -23.63mA
[GND_clamp]
|Voltage   I(typ)   I(min)   I(max)
-1.5V     -437.6mA   -483.1mA   -411.3mA
-1.159V   -181.2mA   -234mA     -153.2mA
-1.128V   -160.4mA   -212.8mA   -134.5mA
-1.097V   -140.5mA   -192mA     -117.9mA
-1.035V   -104.9mA   -152.2mA   -93.08mA
-942mV    -66.01mA   -98.88mA   -73.31mA
-849mV    -46.26mA   -57.94mA   -58.29mA
-787mV    -38.01mA   -39.4mA    -48.69mA
-663mV    -23.84mA   -19.92mA   -30.76mA
-508mV    -9.791mA   -8.549mA   -12.41mA
-384mV    -2.92mA    -2.99mA    -3.392mA
3V        0A         0A         0A
[POWER_clamp]
|Voltage   I(typ)   I(min)   I(max)
-1.5V     391.5mA    430.3mA    369.8mA
-1.166V   144.9mA    193mA      117.4mA
-1.135V   124.5mA    172.6mA    97.69mA
-1.104V   105.1mA    152.8mA    79.63mA
-1.042V   70.22mA    115.2mA    50.64mA
-1.011V   55.5mA     97.74mA    40.7mA
-949mV    33.19mA    66.57mA    29.05mA
-887mV    20.7mA     41.83mA    22.48mA
-825mV    14.31mA    24.76mA    16.96mA
-732mV    8.589mA    11.69mA    10.31mA
-577mV    3.202mA    4.456mA    3.639mA
3V        -1.88mA    -305.7uA   -1.33mA
[Ramp]
| variable   typ   min   max
dV/dt_r   0.579/0.530n   0.535/0.595n   0.559/0.641n
dV/dt_f   0.590/0.563n   0.550/0.566n   0.585/0.735n
R_load = 50.000
[Rising Waveform]
R_fixture= 50.000
V_fixture= 0.0
V_fixture_min= 0.0
V_fixture_max= 0.0
|time   V(typ)   V(min)   V(max)
0s        13.61uV    415.9uV    2.157uV
364ps     648.2uV    472.9uV    -5.867mV
508ps     8.008mV    686.2uV    322mV
748ps     433.4mV    1.951mV    613mV
927ps     649.1mV    222mV      699.1mV
1.157ns   775.4mV    520.6mV    758mV
1.437ns   840.3mV    695.3mV    797.9mV
2.526ns   911mV      835.3mV    866.8mV
7.765ns   958.7mV    885.1mV    922.2mV
30ns      965.7mV    892.9mV    931.3mV
[Rising Waveform]
R_fixture= 50.000
V_fixture= 0.750
V_fixture_min= 0.713
V_fixture_max= 0.789
|time   V(typ)   V(min)   V(max)
0s        226.1mV    228.1mV    253.1mV
351ps     226.3mV    228.1mV    257mV
468ps     237.2mV    228.3mV    657.7mV
559ps     467.4mV    227.5mV    872.4mV
690ps     772.9mV    242.1mV    1.027V
810ps     957.7mV    462.9mV    1.098V
1.041ns   1.106V     837.9mV    1.164V
1.26ns    1.157V     1.006V     1.194V
2.18ns    1.213V     1.138V     1.246V
30ns      1.261V     1.189V     1.299V
[Falling Waveform]
R_fixture= 50.000
V_fixture= 0.750
V_fixture_min= 0.713
V_fixture_max= 0.789
|time   V(typ)   V(min)   V(max)
0s        1.261V     1.19V      1.3V
356ps     1.261V     1.19V      1.301V
471ps     1.254V     1.19V      888.9mV
569ps     931.9mV    1.19V      660.9mV
681ps     631.7mV    1.183V     523.2mV
789ps     485.7mV    927.6mV    450.9mV
931ps     392.8mV    595.6mV    398.3mV
1.111ns   338.3mV    421.8mV    363.1mV
1.988ns   273.3mV    276.7mV    306.1mV
30ns      226.8mV    229mV      253.6mV
[Falling Waveform]
R_fixture= 50.000
V_fixture= 0.0
V_fixture_min= 0.0
V_fixture_max= 0.0
|time   V(typ)   V(min)   V(max)
0s        966.6mV    894mV      932mV
351ps     966.3mV    893.7mV    932.4mV
461ps     957.6mV    893.8mV    429.3mV
581ps     443.9mV    897.5mV    221.2mV
651ps     280.1mV    897.2mV    170.9mV
711ps     210.6mV    799.9mV    142.8mV
832ps     137.8mV    361.2mV    107.8mV
941ps     104mV      207.1mV    89.24mV
1.611ns   44.68mV    50.9mV     46.6mV
30ns      570.1uV    1.171mV    361.4uV
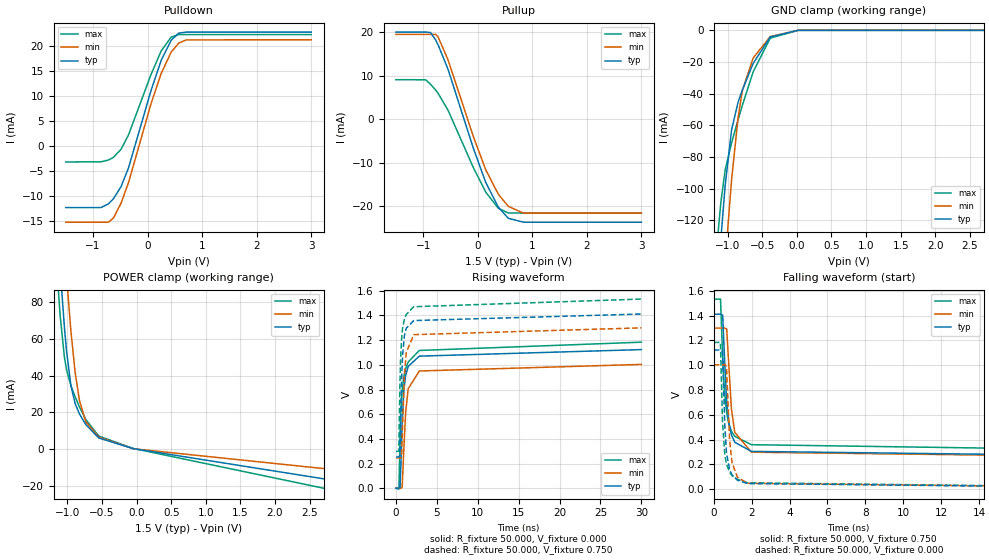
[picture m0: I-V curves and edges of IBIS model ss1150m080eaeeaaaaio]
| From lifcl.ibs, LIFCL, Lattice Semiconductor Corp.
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|Model ss1150m080eaeeaaaaio
[Model] ss1150m080eaeeaaaaio
| Clamp models do not include dynamic input termination. Please refer to
| the ss1150axxxeaeeaaaain model for input termination.
Model_type I/O
Polarity   Non-Inverting
Enable   Active-Low
Vinl =  0.650V
Vinh =  0.850V
Vmeas =  0.750V
Cref =  30.000pF
Rref =  50.000
Vref =  0.750V
C_comp   5.000pF   4.000pF   5.500pF
[Temperature Range]   25.000   0.125k   -40.000
[Voltage Range]   1.500V   1.430V   1.580V
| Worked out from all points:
|   slope of the pulldown table from 0 to 0.225 V, typ, clamps not added: 29.5 ohm
|   slope of the pullup table from 0 to 0.225 V, typ, clamps not added: 31.7 ohm
|   GND clamp passes 1 mA (typ) near -0.15 V on its own axis
|   POWER clamp passes 1 mA (typ) near -0.17 V on its own axis
|   rising waveform, R_fixture 50.000, V_fixture 0.000: 20-80 % time 528ps typ, 593ps min, 641ps max; typ from 0.001 V to 1.12 V
|   rising waveform, R_fixture 50.000, V_fixture 0.750: 20-80 % time 382ps typ, 455ps min, 381ps max; typ from 0.253 V to 1.41 V
|   falling waveform, R_fixture 50.000, V_fixture 0.750: 20-80 % time 317ps typ, 345ps min, 350ps max; typ from 1.41 V to 0.253 V
|   falling waveform, R_fixture 50.000, V_fixture 0.000: 20-80 % time 219ps typ, 245ps min, 231ps max; typ from 1.12 V to 0.001 V
[Pulldown]
|Voltage   I(typ)   I(min)   I(max)
-1.5V     -12.24mA   -15.16mA   -3.116mA
-856mV    -12.24mA   -15.16mA   -3.091mA
-718mV    -11.49mA   -15.16mA   -2.735mA
-626mV    -10.47mA   -14.32mA   -2.18mA
-488mV    -8.076mA   -11.39mA   -594uA
-350mV    -4.287mA   -7.226mA   2.301mA
64mV      11.22mA    8.592mA    14.42mA
248mV     17.18mA    14.57mA    19.07mA
432mV     21.23mA    18.85mA    21.86mA
570mV     22.65mA    20.65mA    22.36mA
708mV     22.86mA    21.3mA     22.36mA
3V        22.86mA    21.32mA    22.36mA
[Pullup]
|Voltage   I(typ)   I(min)   I(max)
-1.5V     20.07mA    19.53mA    9.104mA
-956mV    20.07mA    19.53mA    9.085mA
-864mV    19.97mA    19.53mA    8.033mA
-772mV    18.26mA    19.53mA    6.731mA
-726mV    17.12mA    18.95mA    5.952mA
-542mV    11.4mA     13.59mA    2.002mA
-82mV     -6.636mA   -3.946mA   -11.1mA
148mV     -14.59mA   -11.68mA   -16.81mA
378mV     -20.28mA   -17.3mA    -20.52mA
562mV     -22.84mA   -20.08mA   -21.61mA
838mV     -23.72mA   -21.63mA   -21.62mA
3V        -23.72mA   -21.65mA   -21.62mA
[GND_clamp]
|Voltage   I(typ)   I(min)   I(max)
-1.5V     -423.6mA   -473.4mA   -391.3mA
-1.159V   -170.8mA   -226.4mA   -140.1mA
-1.128V   -150.6mA   -205.4mA   -123mA
-1.097V   -131.5mA   -185mA     -108.4mA
-1.035V   -97.76mA   -145.9mA   -88.03mA
-942mV    -62.68mA   -94.08mA   -70.99mA
-849mV    -45.44mA   -55.18mA   -56.59mA
-787mV    -37.67mA   -38mA      -47.37mA
-632mV    -20.99mA   -17.55mA   -26.32mA
-384mV    -4.202mA   -3.933mA   -4.89mA
19mV      0A         0A         0A
3V        0A         0A         0A
[POWER_clamp]
|Voltage   I(typ)   I(min)   I(max)
-1.5V     377.8mA    420.9mA    350.6mA
-1.166V   135.9mA    186.4mA    106mA
-1.104V   98.02mA    147mA      72.63mA
-1.042V   66.02mA    110.5mA    49.91mA
-1.011V   53.08mA    93.78mA    43.04mA
-949mV    34.63mA    64.31mA    34.62mA
-887mV    24.77mA    41.57mA    28.48mA
-825mV    19.16mA    26.4mA     22.89mA
-732mV    13.32mA    14.81mA    16.07mA
-546mV    6.068mA    6.58mA     7.125mA
-50mV     295.8uA    241.2uA    397.5uA
3V        -17.94mA   -11.75mA   -23.63mA
[Ramp]
| variable   typ   min   max
dV/dt_r   0.673/0.536n   0.601/0.595n   0.710/0.641n
dV/dt_f   0.590/0.563n   0.550/0.566n   0.623/0.735n
R_load = 50.000
[Rising Waveform]
R_fixture = 50.000
V_fixture = 0.000
V_fixture_min = 0.000
V_fixture_max = 0.000
|  time   V(typ)   V(min)   V(max)
0s        831uV      1.003mV    848.3uV
364ps     1.568mV    1.067mV    -6.6mV
508ps     10.12mV    1.306mV    409.7mV
608ps     193.5mV    -42.34uV   618mV
760ps     526.7mV    10.34mV    789mV
967ps     790.2mV    318.9mV    905.2mV
1.193ns   915.1mV    621.2mV    971.5mV
1.503ns   987.4mV    807mV      1.023V
2.858ns   1.07V      949.9mV    1.116V
30ns      1.123V     1.003V     1.183V
[Rising Waveform]
R_fixture = 50.000
V_fixture = 0.750
V_fixture_min = 0.713
V_fixture_max = 0.789
|  time   V(typ)   V(min)   V(max)
0s        253.1mV    246.4mV    297.3mV
351ps     253.4mV    246.5mV    301.9mV
468ps     265.6mV    246.6mV    774.8mV
559ps     523.3mV    245.8mV    1.028V
690ps     865.2mV    261.9mV    1.21V
810ps     1.072V     503.8mV    1.294V
1.041ns   1.238V     914.6mV    1.372V
1.26ns    1.295V     1.099V     1.407V
2.181ns   1.358V     1.244V     1.47V
30ns      1.411V     1.299V     1.532V
[Falling Waveform]
R_fixture = 50.000
V_fixture = 0.750
V_fixture_min = 0.713
V_fixture_max = 0.789
|  time   V(typ)   V(min)   V(max)
0s        1.411V     1.299V     1.532V
356ps     1.411V     1.299V     1.533V
471ps     1.403V     1.299V     1.047V
561ps     1.076V     1.3V       794.3mV
681ps     706.3mV    1.292V     615.4mV
788ps     544mV      1.016V     530.7mV
931ps     439mV      648.1mV    468.1mV
1.109ns   378.4mV    459mV      426.8mV
1.986ns   305.3mV    298.7mV    359.4mV
30ns      253.1mV    246.4mV    297.3mV
[Falling Waveform]
R_fixture = 50.000
V_fixture = 0.000
V_fixture_min = 0.000
V_fixture_max = 0.000
|  time   V(typ)   V(min)   V(max)
0s        1.123V     1.003V     1.183V
351ps     1.122V     1.003V     1.184V
461ps     1.112V     1.003V     545.3mV
581ps     515.5mV    1.007V     281.2mV
671ps     293.5mV    991.2mV    203.9mV
832ps     160.2mV    405mV      137.2mV
961ps     115.7mV    214.6mV    110.4mV
1.251ns   72.7mV     97.3mV     79.71mV
1.781ns   46.01mV    48.17mV    52.7mV
30ns      831uV      1.003mV    848.3uV
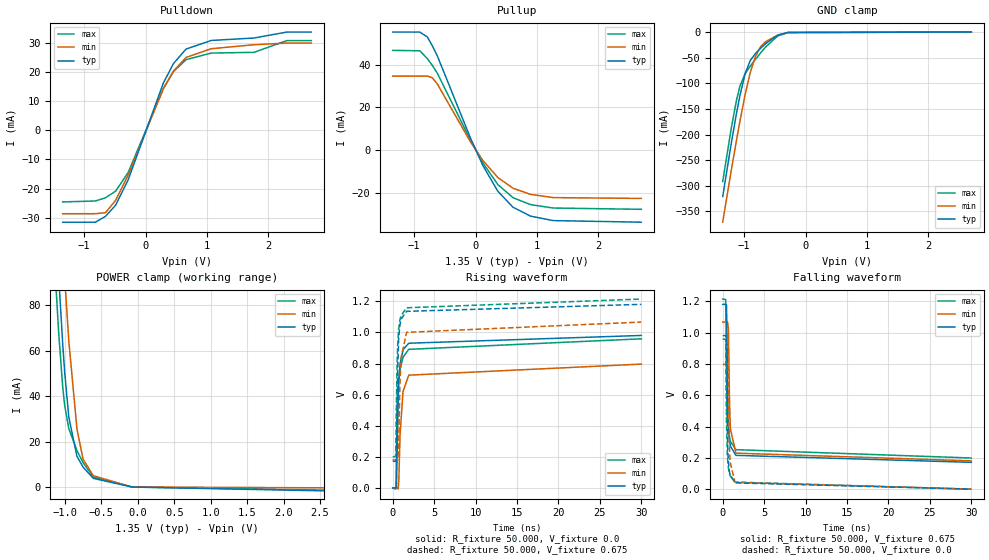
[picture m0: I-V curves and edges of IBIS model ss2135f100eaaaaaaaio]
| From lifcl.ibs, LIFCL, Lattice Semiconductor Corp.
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|Model ss2135f100eaaaaaaaio
[Model] ss2135f100eaaaaaaaio
| Clamp models do not include dynamic input termination. Please refer to
| the ss1135axxxeaaaaaaain model for input termination.
Model_type I/O
Polarity   Non-Inverting
Enable   Active-Low
Vinl =  0.575V
Vinh =  0.775V
Vmeas =  0.675V
Cref =  30.000pF
Rref =  50.000
Vref =  0.675V
C_comp   5.000pF   4.000pF   5.500pF
[Temperature Range]   25.000   0.125k   -40.000
[Voltage Range]   1.350V   1.280V   1.420V
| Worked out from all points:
|   slope of the pulldown table from 0 to 0.203 V, typ, clamps not added: 17.4 ohm
|   slope of the pullup table from 0 to 0.203 V, typ, clamps not added: 16.9 ohm
|   GND clamp passes 1 mA (typ) near -0.31 V on its own axis
|   POWER clamp passes 1 mA (typ) near -0.43 V on its own axis
|   rising waveform, R_fixture 50.000, V_fixture 0.0: 20-80 % time 327ps typ, 506ps min, 450ps max; typ from 0 V to 0.981 V
|   rising waveform, R_fixture 50.000, V_fixture 0.675: 20-80 % time 232ps typ, 347ps min, 284ps max; typ from 0.171 V to 1.18 V
|   falling waveform, R_fixture 50.000, V_fixture 0.675: 20-80 % time 205ps typ, 240ps min, 258ps max; typ from 1.18 V to 0.172 V
|   falling waveform, R_fixture 50.000, V_fixture 0.0: 20-80 % time 160ps typ, 188ps min, 189ps max; typ from 0.981 V to 0 V
[Pulldown]
|Voltage   I(typ)   I(min)   I(max)
-1.35V    -31.52mA   -28.61mA   -24.57mA
-817mV    -31.52mA   -28.61mA   -24.26mA
-653mV    -29.52mA   -28.27mA   -23.15mA
-489mV    -25.73mA   -24.06mA   -20.91mA
-284mV    -17.01mA   -15.39mA   -14.5mA
290mV     16.19mA    14.33mA    14.27mA
454mV     22.83mA    20.27mA    20.05mA
659mV     27.8mA     24.92mA    24.18mA
1.069V    30.75mA    27.92mA    26.43mA
1.766V    31.59mA    29.29mA    26.68mA
2.299V    33.62mA    29.85mA    30.69mA
2.7V      33.62mA    29.85mA    30.69mA
[Pullup]
|Voltage   I(typ)   I(min)   I(max)
-1.35V    55.32mA    34.66mA    46.74mA
-908mV    55.32mA    34.66mA    46.54mA
-785mV    52.99mA    34.66mA    42.83mA
-703mV    48.79mA    33.84mA    39.62mA
-621mV    43.98mA    30.83mA    35.9mA
-88mV     5.888mA    4.039mA    4.858mA
117mV     -7.248mA   -4.887mA   -6.056mA
363mV     -19.41mA   -12.97mA   -16.28mA
609mV     -26.91mA   -17.99mA   -22.42mA
896mV     -31.1mA    -20.88mA   -25.7mA
1.265V    -33.2mA    -22.4mA    -27.29mA
2.7V      -33.94mA   -22.78mA   -27.9mA
[GND_clamp]
|Voltage   I(typ)   I(min)   I(max)
-1.35V    -320.9mA   -371mA     -291.7mA
-1.21V    -216.8mA   -269.5mA   -187.2mA
-1.126V   -159mA     -211.3mA   -133.3mA
-1.07V    -124.2mA   -174.2mA   -105.6mA
-986mV    -81.78mA   -122.8mA   -81.18mA
-902mV    -55.61mA   -79.36mA   -66.72mA
-818mV    -41.95mA   -47.73mA   -53.44mA
-734mV    -31.67mA   -28.77mA   -40.78mA
-650mV    -22.47mA   -18.69mA   -29.01mA
-454mV    -6.221mA   -5.753mA   -7.69mA
-286mV    -734.4uA   -759.2uA   -785.5uA
2.7V      0A         0A         0A
[POWER_clamp]
|Voltage   I(typ)   I(min)   I(max)
-1.35V    276.5mA    320.5mA    251mA
-1.142V   128.3mA    176.6mA    100.9mA
-1.114V   110.5mA    158.5mA    83.9mA
-1.086V   93.5mA     140.9mA    68.53mA
-1.03V    63.21mA    107.6mA    44.18mA
-1.002V   50.42mA    92.11mA    35.83mA
-946mV    30.82mA    64.28mA    25.76mA
-834mV    13.57mA    25.52mA    16.1mA
-750mV    8.839mA    12.31mA    10.8mA
-610mV    3.896mA    5.035mA    4.505mA
-78mV     75.17uA    92.3uA     98.29uA
2.7V      -1.695mA   -291.3uA   -1.333mA
[Ramp]
| variable   typ   min   max
dV/dt_r   0.588/0.328n   0.478/0.506n   0.576/0.451n
dV/dt_f   0.587/0.311n   0.536/0.354n   0.587/0.445n
R_load = 50.000
[Rising Waveform]
R_fixture= 50.000
V_fixture= 0.0
V_fixture_min= 0.0
V_fixture_max= 0.0
|time   V(typ)   V(min)   V(max)
0s        5.449uV    216.2uV    716.2nV
375ps     683.4uV    261.8uV    -8.057mV
458ps     -185.5uV   291.2uV    235.2mV
548ps     258.6mV    759.8uV    475.9mV
666ps     585.8mV    -6.831mV   633.2mV
737ps     687.5mV    46.77mV    689.7mV
887ps     799.6mV    342.1mV    764.1mV
1.247ns   889.3mV    621.3mV    840.6mV
1.937ns   930.9mV    725.4mV    891.6mV
30ns      980.8mV    796.6mV    959.3mV
[Rising Waveform]
R_fixture= 50.000
V_fixture= 0.675
V_fixture_min= 0.642
V_fixture_max= 0.710
|time   V(typ)   V(min)   V(max)
0s        171.1mV    180.5mV    198.9mV
356ps     171.4mV    180.5mV    202.8mV
448ps     173.5mV    180.6mV    547.4mV
517ps     426.1mV    180.5mV    779.6mV
597ps     749.4mV    178.7mV    920.1mV
717ps     959mV      254.8mV    1.022V
857ps     1.045V     644.6mV    1.078V
1.007ns   1.086V     834.9mV    1.109V
1.677ns   1.136V     1.001V     1.159V
30ns      1.181V     1.067V     1.215V
[Falling Waveform]
R_fixture= 50.000
V_fixture= 0.675
V_fixture_min= 0.642
V_fixture_max= 0.710
|time   V(typ)   V(min)   V(max)
0s        1.181V     1.068V     1.215V
356ps     1.181V     1.068V     1.212V
457ps     1.178V     1.068V     772.1mV
487ps     1.096V     1.067V     665.9mV
587ps     590.6mV    1.069V     477.1mV
688ps     399.3mV    1.026V     389.6mV
827ps     308.9mV    542.3mV    330mV
937ps     274.7mV    382.6mV    304.8mV
1.597ns   216.2mV    230.4mV    252.7mV
30ns      171.7mV    181.2mV    199.4mV
[Falling Waveform]
R_fixture= 50.000
V_fixture= 0.0
V_fixture_min= 0.0
V_fixture_max= 0.0
|time   V(typ)   V(min)   V(max)
0s        981.4mV    797.6mV    959.8mV
356ps     981.2mV    797.4mV    957.4mV
450ps     983.9mV    797.5mV    443.2mV
557ps     407.1mV    799.1mV    219.8mV
619ps     243mV      805.8mV    170.1mV
678ps     179.7mV    764.9mV    139.5mV
788ps     120.3mV    323.9mV    104.8mV
878ps     93.93mV    177.6mV    87.73mV
1.488ns   40.54mV    43.39mV    45.78mV
30ns      485.3uV    801.9uV    326.8uV
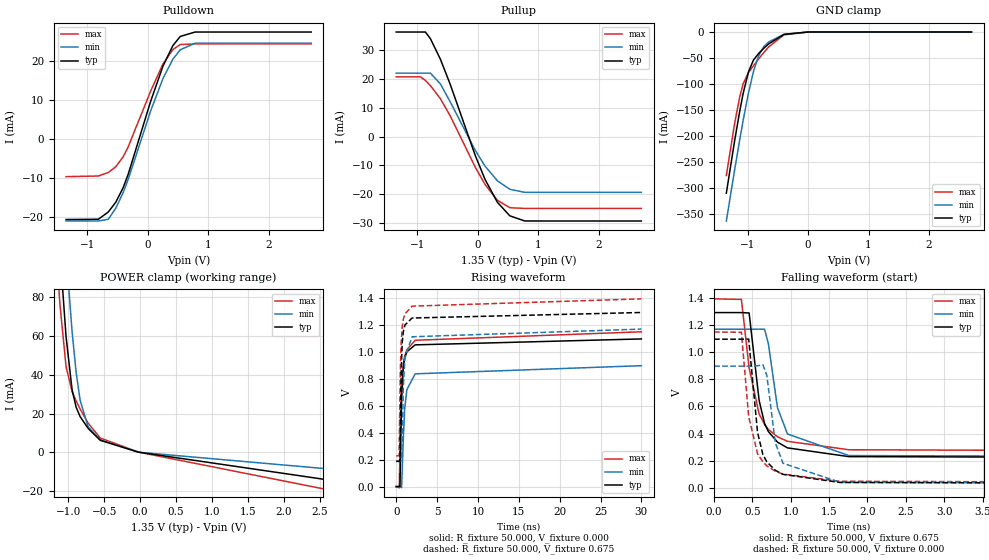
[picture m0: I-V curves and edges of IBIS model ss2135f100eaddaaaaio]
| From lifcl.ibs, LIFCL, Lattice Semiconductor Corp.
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|Model ss2135f100eaddaaaaio
[Model] ss2135f100eaddaaaaio
| Clamp models do not include dynamic input termination. Please refer to
| the ss1135axxxeaddaaaain model for input termination.
Model_type I/O
Polarity   Non-Inverting
Enable   Active-Low
Vinl =  0.575V
Vinh =  0.775V
Vmeas =  0.675V
Cref =  30.000pF
Rref =  50.000
Vref =  0.675V
C_comp   5.000pF   4.000pF   5.500pF
[Temperature Range]   25.000   0.125k   -40.000
[Voltage Range]   1.350V   1.280V   1.420V
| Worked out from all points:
|   slope of the pulldown table from 0 to 0.203 V, typ, clamps not added: 21.5 ohm
|   slope of the pullup table from 0 to 0.203 V, typ, clamps not added: 21.2 ohm
|   GND clamp passes 1 mA (typ) near -0.15 V on its own axis
|   POWER clamp passes 1 mA (typ) near -0.17 V on its own axis
|   rising waveform, R_fixture 50.000, V_fixture 0.000: 20-80 % time 327ps typ, 506ps min, 450ps max; typ from 0 V to 1.09 V
|   rising waveform, R_fixture 50.000, V_fixture 0.675: 20-80 % time 232ps typ, 347ps min, 284ps max; typ from 0.187 V to 1.29 V
|   falling waveform, R_fixture 50.000, V_fixture 0.675: 20-80 % time 205ps typ, 240ps min, 258ps max; typ from 1.29 V to 0.187 V
|   falling waveform, R_fixture 50.000, V_fixture 0.000: 20-80 % time 160ps typ, 188ps min, 189ps max; typ from 1.09 V to 0 V
[Pulldown]
|Voltage   I(typ)   I(min)   I(max)
-1.35V    -20.68mA   -21.06mA   -9.685mA
-817mV    -20.61mA   -21.06mA   -9.522mA
-653mV    -18.75mA   -20.61mA   -8.623mA
-530mV    -16.27mA   -17.81mA   -7.165mA
-407mV    -12.51mA   -13.77mA   -4.604mA
-325mV    -9.119mA   -10.43mA   -2.093mA
44mV      9.478mA    7.039mA    12.14mA
249mV     18.59mA    15.42mA    19.15mA
413mV     23.88mA    20.4mA     22.88mA
536mV     26.26mA    22.84mA    24.18mA
782mV     27.39mA    24.54mA    24.34mA
2.7V      27.39mA    24.54mA    24.34mA
[Pullup]
|Voltage   I(typ)   I(min)   I(max)
-1.35V    36.19mA    21.95mA    20.67mA
-949mV    36.19mA    21.95mA    20.67mA
-867mV    36.19mA    21.95mA    19.41mA
-785mV    33.89mA    21.95mA    17.63mA
-621mV    26.83mA    18.25mA    13.12mA
-457mV    18.05mA    11.99mA    7.118mA
-47mV     -6.393mA   -4.657mA   -10.48mA
117mV     -14.82mA   -10.23mA   -16.58mA
322mV     -22.77mA   -15.33mA   -22.07mA
527mV     -27.44mA   -18.26mA   -24.64mA
773mV     -29.23mA   -19.31mA   -24.88mA
2.7V      -29.24mA   -19.31mA   -24.88mA
[GND_clamp]
|Voltage   I(typ)   I(min)   I(max)
-1.35V    -309.8mA   -363.4mA   -275.8mA
-1.21V    -207.1mA   -262.8mA   -173.9mA
-1.126V   -150.5mA   -205.1mA   -123.2mA
-1.07V    -117mA     -168.5mA   -98.8mA
-986mV    -77.25mA   -118.1mA   -78.4mA
-902mV    -53.89mA   -76.04mA   -64.81mA
-818mV    -41.42mA   -46.02mA   -52mA
-734mV    -31.56mA   -28.41mA   -39.82mA
-650mV    -22.69mA   -19.03mA   -28.57mA
-398mV    -4.585mA   -4.332mA   -5.35mA
-6mV      -40.55uA   -29.88uA   -52.89uA
2.7V      0A         0A         0A
[POWER_clamp]
|Voltage   I(typ)   I(min)   I(max)
-1.35V    264.6mA    312.3mA    234.2mA
-1.17V    138mA      188.5mA    107.5mA
-1.142V   120.1mA    170.4mA    90.88mA
-1.114V   103.1mA    152.7mA    75.88mA
-1.03V    59.59mA    103.2mA    44.19mA
-946mV    32.22mA    62.05mA    31.33mA
-890mV    23.29mA    41.28mA    26.5mA
-834mV    18.42mA    26.8mA     22.3mA
-722mV    12.33mA    13.1mA     15mA
-554mV    6.226mA    6.542mA    7.404mA
-22mV     128.8uA    103.1uA    167.9uA
2.7V      -14.6mA    -8.747mA   -19.86mA
[Ramp]
| variable   typ   min   max
dV/dt_r   0.657/0.328n   0.538/0.506n   0.689/0.451n
dV/dt_f   0.629/0.311n   0.577/0.353n   0.638/0.445n
R_load = 50.000
[Rising Waveform]
R_fixture = 50.000
V_fixture = 0.000
V_fixture_min = 0.000
V_fixture_max = 0.000
|  time   V(typ)   V(min)   V(max)
0s        432.6uV    452.8uV    620.8uV
375ps     1.189mV    504.1uV    -9.02mV
458ps     220.5uV    537.1uV    282.1mV
538ps     246.8mV    989.9uV    546.7mV
657ps     635.2mV    -7.709mV   747.9mV
874ps     885.2mV    361mV      909.1mV
1.037ns   951.7mV    576.9mV    965.2mV
1.301ns   999.4mV    718.5mV    1.014V
2.317ns   1.051V     836.2mV    1.085V
30ns      1.095V     896.7mV    1.148V
[Rising Waveform]
R_fixture = 50.000
V_fixture = 0.675
V_fixture_min = 0.642
V_fixture_max = 0.710
|  time   V(typ)   V(min)   V(max)
0s        186.9mV    192.1mV    226.2mV
356ps     187.3mV    192.2mV    230.6mV
448ps     189.5mV    192.3mV    625.8mV
517ps     465.7mV    192.2mV    892.3mV
607ps     849.9mV    189.6mV    1.067V
737ps     1.068V     337.5mV    1.183V
877ps     1.151V     743.8mV    1.241V
1.067ns   1.198V     955.8mV    1.28V
1.937ns   1.25V      1.111V     1.338V
30ns      1.291V     1.168V     1.392V
[Falling Waveform]
R_fixture = 50.000
V_fixture = 0.675
V_fixture_min = 0.642
V_fixture_max = 0.710
|  time   V(typ)   V(min)   V(max)
0s        1.291V     1.168V     1.392V
356ps     1.291V     1.168V     1.388V
457ps     1.288V     1.168V     883.2mV
587ps     645mV      1.169V     544.8mV
658ps     474.9mV    1.168V     467.8mV
708ps     415mV      1.062V     431mV
827ps     337mV      589.6mV    376mV
957ps     294.7mV    397.1mV    343.2mV
1.758ns   230.3mV    238mV      280.9mV
30ns      186.9mV    192.1mV    226.2mV
[Falling Waveform]
R_fixture = 50.000
V_fixture = 0.000
V_fixture_min = 0.000
V_fixture_max = 0.000
|  time   V(typ)   V(min)   V(max)
0s        1.095V     896.7mV    1.148V
356ps     1.095V     896.4mV    1.146V
451ps     1.096V     896.6mV    525.7mV
567ps     407.7mV    899.4mV    251.5mV
637ps     244.2mV    906.8mV    191mV
688ps     191.9mV    828.8mV    162.2mV
798ps     130mV      333.1mV    122.9mV
898ps     99.78mV    181.9mV    101.7mV
1.642ns   40.14mV    40.86mV    48.99mV
30ns      432.6uV    452.8uV    620.8uV
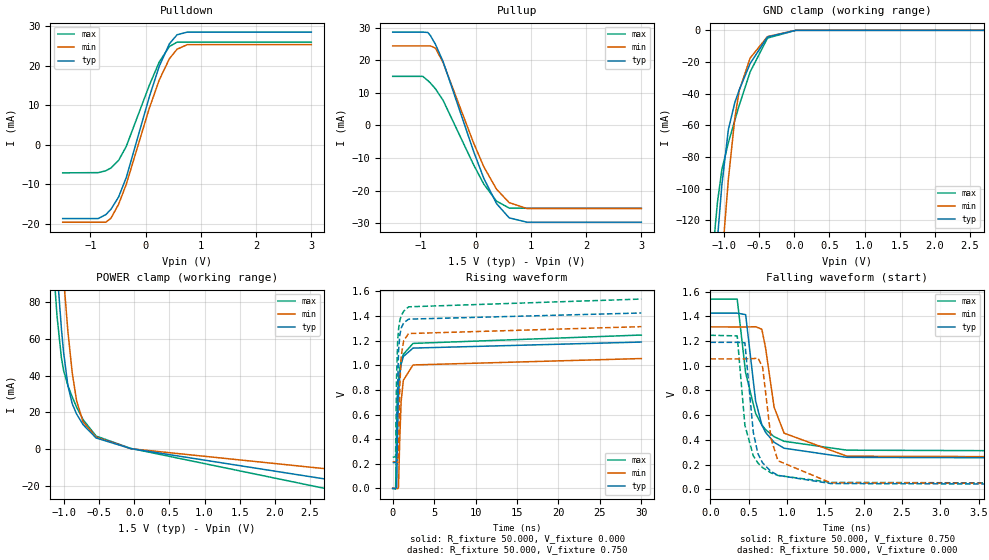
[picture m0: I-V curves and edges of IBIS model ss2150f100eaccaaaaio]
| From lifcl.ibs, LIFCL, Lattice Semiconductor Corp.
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|Model ss2150f100eaccaaaaio
[Model] ss2150f100eaccaaaaio
| Clamp models do not include dynamic input termination. Please refer to
| the ss1150axxxeaccaaaain model for input termination.
Model_type I/O
Polarity   Non-Inverting
Enable   Active-Low
Vinl =  0.650V
Vinh =  0.850V
Vmeas =  0.750V
Cref =  30.000pF
Rref =  50.000
Vref =  0.750V
C_comp   5.000pF   4.000pF   5.500pF
[Temperature Range]   25.000   0.125k   -40.000
[Voltage Range]   1.500V   1.430V   1.580V
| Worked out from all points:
|   slope of the pulldown table from 0 to 0.225 V, typ, clamps not added: 22.2 ohm
|   slope of the pullup table from 0 to 0.225 V, typ, clamps not added: 23.8 ohm
|   GND clamp passes 1 mA (typ) near -0.15 V on its own axis
|   POWER clamp passes 1 mA (typ) near -0.17 V on its own axis
|   rising waveform, R_fixture 50.000, V_fixture 0.000: 20-80 % time 352ps typ, 417ps min, 487ps max; typ from 0.001 V to 1.19 V
|   rising waveform, R_fixture 50.000, V_fixture 0.750: 20-80 % time 250ps typ, 300ps min, 296ps max; typ from 0.21 V to 1.43 V
|   falling waveform, R_fixture 50.000, V_fixture 0.750: 20-80 % time 217ps typ, 253ps min, 280ps max; typ from 1.43 V to 0.21 V
|   falling waveform, R_fixture 50.000, V_fixture 0.000: 20-80 % time 160ps typ, 189ps min, 192ps max; typ from 1.19 V to 0.001 V
[Pulldown]
|Voltage   I(typ)   I(min)   I(max)
-1.5V     -18.71mA   -19.64mA   -7.127mA
-856mV    -18.71mA   -19.64mA   -7.075mA
-718mV    -17.7mA    -19.64mA   -6.586mA
-626mV    -16.35mA   -18.62mA   -5.887mA
-488mV    -13.24mA   -15.08mA   -3.957mA
-350mV    -8.347mA   -10.05mA   -443.9uA
64mV      11.97mA    9.105mA    14.94mA
248mV     19.93mA    16.44mA    21mA
432mV     25.61mA    21.82mA    24.92mA
570mV     27.88mA    24.22mA    26mA
754mV     28.56mA    25.37mA    26.01mA
3V        28.56mA    25.38mA    26.01mA
[Pullup]
|Voltage   I(typ)   I(min)   I(max)
-1.5V     28.63mA    24.4mA     15.05mA
-956mV    28.63mA    24.4mA     15.05mA
-864mV    28.51mA    24.4mA     13.76mA
-818mV    27.58mA    24.4mA     13.01mA
-726mV    24.87mA    23.72mA    11.22mA
-588mV    19.58mA    19.28mA    7.699mA
-36mV     -7.957mA   -5.375mA   -12.06mA
148mV     -16.19mA   -12.66mA   -17.97mA
378mV     -23.95mA   -19.53mA   -23.2mA
608mV     -28.35mA   -23.68mA   -25.34mA
930mV     -29.68mA   -25.49mA   -25.41mA
3V        -29.68mA   -25.49mA   -25.41mA
[GND_clamp]
|Voltage   I(typ)   I(min)   I(max)
-1.5V     -423.6mA   -473.4mA   -391.3mA
-1.159V   -170.8mA   -226.4mA   -140.1mA
-1.128V   -150.6mA   -205.4mA   -123mA
-1.097V   -131.5mA   -185mA     -108.4mA
-1.035V   -97.76mA   -145.9mA   -88.03mA
-942mV    -62.68mA   -94.08mA   -70.99mA
-849mV    -45.44mA   -55.18mA   -56.59mA
-787mV    -37.67mA   -38mA      -47.37mA
-632mV    -20.99mA   -17.55mA   -26.32mA
-384mV    -4.202mA   -3.933mA   -4.89mA
19mV      0A         0A         0A
3V        0A         0A         0A
[POWER_clamp]
|Voltage   I(typ)   I(min)   I(max)
-1.5V     377.8mA    420.9mA    350.6mA
-1.166V   135.9mA    186.4mA    106mA
-1.104V   98.02mA    147mA      72.63mA
-1.042V   66.02mA    110.5mA    49.91mA
-1.011V   53.08mA    93.78mA    43.04mA
-949mV    34.63mA    64.31mA    34.62mA
-887mV    24.77mA    41.57mA    28.48mA
-825mV    19.16mA    26.4mA     22.89mA
-732mV    13.32mA    14.81mA    16.07mA
-546mV    6.068mA    6.58mA     7.125mA
-50mV     295.8uA    241.2uA    397.5uA
3V        -17.94mA   -11.75mA   -23.63mA
[Ramp]
| variable   typ   min   max
dV/dt_r   0.713/0.352n   0.632/0.416n   0.747/0.489n
dV/dt_f   0.691/0.362n   0.625/0.405n   0.682/0.548n
R_load = 50.000
[Rising Waveform]
R_fixture = 50.000
V_fixture = 0.000
V_fixture_min = 0.000
V_fixture_max = 0.000
|  time   V(typ)   V(min)   V(max)
0s        715.4uV    897.5uV    751.9uV
351ps     1.284mV    952uV      -5.487mV
478ps     8.443mV    1.053mV    535.6mV
619ps     538.9mV    -2.149mV   799.9mV
700ps     739.4mV    9.76mV     881.9mV
846ps     916.7mV    390.9mV    974.5mV
1.017ns   1.009V     707.4mV    1.036V
1.286ns   1.072V     878.8mV    1.09V
2.453ns   1.14V      1.003V     1.178V
30ns      1.189V     1.055V     1.246V
[Rising Waveform]
R_fixture = 50.000
V_fixture = 0.750
V_fixture_min = 0.713
V_fixture_max = 0.789
|  time   V(typ)   V(min)   V(max)
0s        210.1mV    215.9mV    255.5mV
346ps     210.3mV    215.9mV    255.9mV
458ps     220.6mV    216mV      892.6mV
599ps     866.3mV    213.7mV    1.199V
710ps     1.122V     291.2mV    1.297V
860ps     1.246V     833.4mV    1.365V
1.021ns   1.302V     1.074V     1.403V
1.333ns   1.346V     1.202V     1.44V
1.921ns   1.375V     1.258V     1.475V
30ns      1.425V     1.314V     1.538V
[Falling Waveform]
R_fixture = 50.000
V_fixture = 0.750
V_fixture_min = 0.713
V_fixture_max = 0.789
|  time   V(typ)   V(min)   V(max)
0s        1.425V     1.314V     1.538V
351ps     1.425V     1.313V     1.539V
461ps     1.413V     1.313V     941.1mV
591ps     714.2mV    1.315V     613.6mV
672ps     520.4mV    1.295V     520.1mV
721ps     459.9mV    1.143V     482mV
832ps     380.1mV    663.5mV    425.5mV
962ps     332mV      453.8mV    388.1mV
1.782ns   258.1mV    267.4mV    316.3mV
30ns      210.1mV    215.9mV    255.5mV
[Falling Waveform]
R_fixture = 50.000
V_fixture = 0.000
V_fixture_min = 0.000
V_fixture_max = 0.000
|  time   V(typ)   V(min)   V(max)
0s        1.189V     1.055V     1.246V
351ps     1.189V     1.055V     1.241V
451ps     1.185V     1.055V     518.5mV
561ps     459mV      1.057V     269.9mV
621ps     287.5mV    1.062V     212.7mV
682ps     213mV      988.8mV    174.6mV
792ps     143.7mV    408.9mV    132.5mV
882ps     112.6mV    230.7mV    111.5mV
1.572ns   46.05mV    51.7mV     55.63mV
30ns      715.4uV    897.5uV    751.9uV
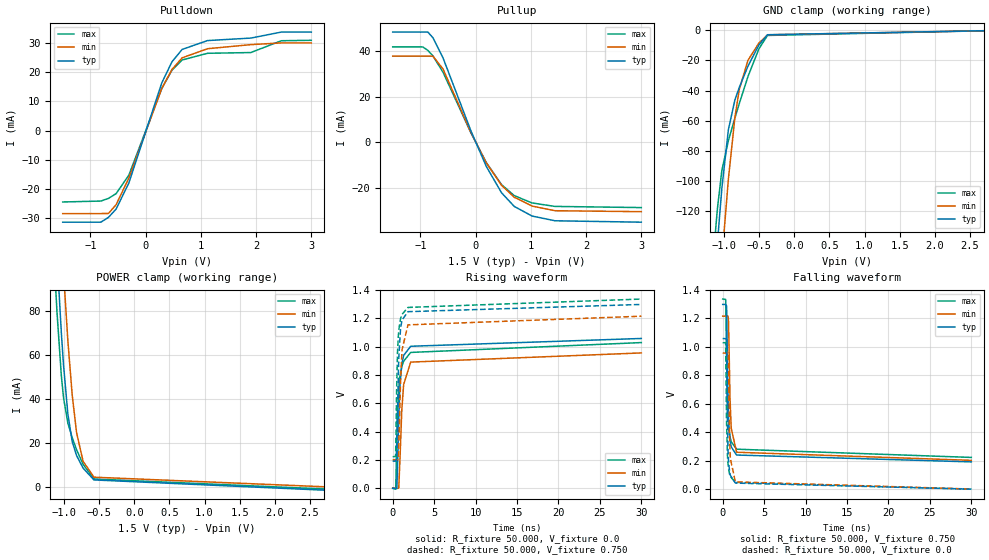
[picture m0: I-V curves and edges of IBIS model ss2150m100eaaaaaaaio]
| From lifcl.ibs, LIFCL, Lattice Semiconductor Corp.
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|Model ss2150m100eaaaaaaaio
[Model] ss2150m100eaaaaaaaio
| Clamp models do not include dynamic input termination. Please refer to
| the ss1150axxxeaaaaaaain model for input termination.
Model_type I/O
Polarity   Non-Inverting
Enable   Active-Low
Vinl =  0.650V
Vinh =  0.850V
Vmeas =  0.750V
Cref =  30.000pF
Rref =  50.000
Vref =  0.750V
C_comp   5.000pF   4.000pF   5.500pF
[Temperature Range]   25.000   0.125k   -40.000
[Voltage Range]   1.500V   1.430V   1.580V
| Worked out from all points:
|   slope of the pulldown table from 0 to 0.225 V, typ, clamps not added: 17.6 ohm
|   slope of the pullup table from 0 to 0.225 V, typ, clamps not added: 18.7 ohm
|   GND clamp passes 1 mA (typ) near -0.31 V on its own axis
|   POWER clamp passes 1 mA (typ) near -0.43 V on its own axis
|   rising waveform, R_fixture 50.000, V_fixture 0.0: 20-80 % time 419ps typ, 522ps min, 505ps max; typ from 0 V to 1.06 V
|   rising waveform, R_fixture 50.000, V_fixture 0.750: 20-80 % time 321ps typ, 403ps min, 317ps max; typ from 0.191 V to 1.3 V
|   falling waveform, R_fixture 50.000, V_fixture 0.750: 20-80 % time 245ps typ, 299ps min, 301ps max; typ from 1.3 V to 0.192 V
|   falling waveform, R_fixture 50.000, V_fixture 0.0: 20-80 % time 178ps typ, 217ps min, 206ps max; typ from 1.06 V to 0.001 V
[Pulldown]
|Voltage   I(typ)   I(min)   I(max)
-1.5V     -31.49mA   -28.52mA   -24.55mA
-810mV    -31.49mA   -28.52mA   -24.23mA
-672mV    -29.84mA   -28.5mA    -23.32mA
-534mV    -26.99mA   -25.49mA   -21.69mA
-304mV    -18.09mA   -16.39mA   -15.39mA
294mV     16.38mA    14.5mA     14.44mA
478mV     23.61mA    20.97mA    20.71mA
662mV     27.85mA    24.96mA    24.22mA
1.122V    30.89mA    28.09mA    26.52mA
1.904V    31.74mA    29.49mA    26.77mA
2.456V    33.8mA     30.08mA    30.83mA
3V        33.8mA     30.08mA    30.98mA
[Pullup]
|Voltage   I(typ)   I(min)   I(max)
-1.5V     48.28mA    37.75mA    41.78mA
-956mV    48.28mA    37.75mA    41.78mA
-864mV    48.28mA    37.75mA    40.27mA
-772mV    45.82mA    37.75mA    37.86mA
-588mV    36.9mA     32.06mA    30.64mA
-82mV     4.881mA    4.232mA    4.033mA
194mV     -10.55mA   -9.008mA   -8.855mA
470mV     -22.09mA   -18.82mA   -18.52mA
700mV     -28.07mA   -24.05mA   -23.33mA
1.022V    -32.27mA   -27.9mA    -26.54mA
1.436V    -34.35mA   -29.95mA   -28.06mA
3V        -34.97mA   -30.36mA   -28.57mA
[GND_clamp]
|Voltage   I(typ)   I(min)   I(max)
-1.5V     -437.6mA   -483.1mA   -411.3mA
-1.159V   -181.2mA   -234mA     -153.2mA
-1.128V   -160.4mA   -212.8mA   -134.5mA
-1.097V   -140.5mA   -192mA     -117.9mA
-1.035V   -104.9mA   -152.2mA   -93.08mA
-942mV    -66.01mA   -98.88mA   -73.31mA
-849mV    -46.26mA   -57.94mA   -58.29mA
-787mV    -38.01mA   -39.4mA    -48.69mA
-663mV    -23.84mA   -19.92mA   -30.76mA
-508mV    -9.791mA   -8.549mA   -12.41mA
-384mV    -2.92mA    -2.99mA    -3.392mA
3V        0A         0A         0A
[POWER_clamp]
|Voltage   I(typ)   I(min)   I(max)
-1.5V     391.5mA    430.3mA    369.8mA
-1.166V   144.9mA    193mA      117.4mA
-1.135V   124.5mA    172.6mA    97.69mA
-1.104V   105.1mA    152.8mA    79.63mA
-1.042V   70.22mA    115.2mA    50.64mA
-1.011V   55.5mA     97.74mA    40.7mA
-949mV    33.19mA    66.57mA    29.05mA
-887mV    20.7mA     41.83mA    22.48mA
-825mV    14.31mA    24.76mA    16.96mA
-732mV    8.589mA    11.69mA    10.31mA
-577mV    3.202mA    4.456mA    3.639mA
3V        -1.88mA    -305.7uA   -1.33mA
[Ramp]
| variable   typ   min   max
dV/dt_r   0.634/0.421n   0.573/0.525n   0.617/0.507n
dV/dt_f   0.647/0.393n   0.591/0.466n   0.642/0.571n
R_load = 50.000
[Rising Waveform]
R_fixture= 50.000
V_fixture= 0.0
V_fixture_min= 0.0
V_fixture_max= 0.0
|time   V(typ)   V(min)   V(max)
0s        11.5uV     367.1uV    1.902uV
364ps     802.7uV    412.3uV    -6.152mV
498ps     -2.509mV   611.5uV    362.4mV
598ps     180.4mV    -171.6uV   565.3mV
730ps     502mV      1.823mV    708.5mV
869ps     719.8mV    194.7mV    790.3mV
1.099ns   878.2mV    554.7mV    860.7mV
1.32ns    937.6mV    732.1mV    896.5mV
2.171ns   1.002V     890.3mV    958.5mV
30ns      1.057V     955mV      1.028V
[Rising Waveform]
R_fixture= 50.000
V_fixture= 0.750
V_fixture_min= 0.713
V_fixture_max= 0.789
|time   V(typ)   V(min)   V(max)
0s        191.3mV    201.8mV    222.7mV
351ps     191.5mV    201.8mV    224.5mV
469ps     208.2mV    201.9mV    683.2mV
578ps     517.3mV    200.5mV    957.6mV
680ps     804.5mV    210.9mV    1.077V
740ps     929mV      309.1mV    1.119V
949ps     1.13V      763.7mV    1.197V
1.129ns   1.187V     978.3mV    1.227V
1.841ns   1.246V     1.153V     1.276V
30ns      1.297V     1.214V     1.335V
[Falling Waveform]
R_fixture= 50.000
V_fixture= 0.750
V_fixture_min= 0.713
V_fixture_max= 0.789
|time   V(typ)   V(min)   V(max)
0s        1.297V     1.215V     1.335V
361ps     1.297V     1.215V     1.332V
471ps     1.287V     1.215V     894.2mV
619ps     691.4mV    1.218V     548.8mV
689ps     521.6mV    1.195V     470.6mV
748ps     439.3mV    1.051V     426.4mV
878ps     346.1mV    641.1mV    367.6mV
1.028ns   297.4mV    427.7mV    332.7mV
1.678ns   240mV      259.5mV    281mV
30ns      191.9mV    202.6mV    223.2mV
[Falling Waveform]
R_fixture= 50.000
V_fixture= 0.0
V_fixture_min= 0.0
V_fixture_max= 0.0
|time   V(typ)   V(min)   V(max)
0s        1.058V     956mV      1.028V
351ps     1.057V     955.8mV    1.029V
461ps     1.049V     955.8mV    477mV
571ps     473.7mV    958.7mV    237.9mV
641ps     272.8mV    961.8mV    177.6mV
698ps     201.9mV    881.4mV    146.8mV
828ps     124.5mV    362.8mV    105.8mV
918ps     97.72mV    216.4mV    89.53mV
1.528ns   43.02mV    51.67mV    47.85mV
30ns      532.3uV    1.083mV    356.1uV
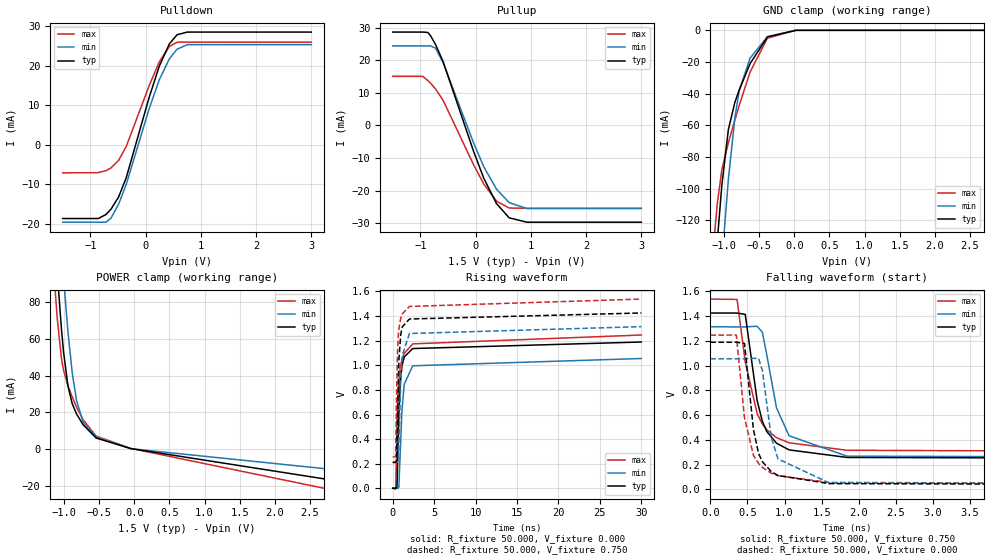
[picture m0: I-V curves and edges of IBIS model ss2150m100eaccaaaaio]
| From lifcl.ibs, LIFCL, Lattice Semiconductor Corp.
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|Model ss2150m100eaccaaaaio
[Model] ss2150m100eaccaaaaio
| Clamp models do not include dynamic input termination. Please refer to
| the ss1150axxxeaccaaaain model for input termination.
Model_type I/O
Polarity   Non-Inverting
Enable   Active-Low
Vinl =  0.650V
Vinh =  0.850V
Vmeas =  0.750V
Cref =  30.000pF
Rref =  50.000
Vref =  0.750V
C_comp   5.000pF   4.000pF   5.500pF
[Temperature Range]   25.000   0.125k   -40.000
[Voltage Range]   1.500V   1.430V   1.580V
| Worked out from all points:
|   slope of the pulldown table from 0 to 0.225 V, typ, clamps not added: 22.2 ohm
|   slope of the pullup table from 0 to 0.225 V, typ, clamps not added: 23.8 ohm
|   GND clamp passes 1 mA (typ) near -0.15 V on its own axis
|   POWER clamp passes 1 mA (typ) near -0.17 V on its own axis
|   rising waveform, R_fixture 50.000, V_fixture 0.000: 20-80 % time 419ps typ, 522ps min, 505ps max; typ from 0.001 V to 1.19 V
|   rising waveform, R_fixture 50.000, V_fixture 0.750: 20-80 % time 321ps typ, 403ps min, 316ps max; typ from 0.21 V to 1.43 V
|   falling waveform, R_fixture 50.000, V_fixture 0.750: 20-80 % time 245ps typ, 299ps min, 301ps max; typ from 1.43 V to 0.21 V
|   falling waveform, R_fixture 50.000, V_fixture 0.000: 20-80 % time 178ps typ, 217ps min, 206ps max; typ from 1.19 V to 0.001 V
[Pulldown]
|Voltage   I(typ)   I(min)   I(max)
-1.5V     -18.71mA   -19.64mA   -7.127mA
-856mV    -18.71mA   -19.64mA   -7.075mA
-718mV    -17.7mA    -19.64mA   -6.586mA
-626mV    -16.35mA   -18.62mA   -5.887mA
-488mV    -13.24mA   -15.08mA   -3.957mA
-350mV    -8.347mA   -10.05mA   -443.9uA
64mV      11.97mA    9.105mA    14.94mA
248mV     19.93mA    16.44mA    21mA
432mV     25.61mA    21.82mA    24.92mA
570mV     27.88mA    24.22mA    26mA
754mV     28.56mA    25.37mA    26.01mA
3V        28.56mA    25.38mA    26.01mA
[Pullup]
|Voltage   I(typ)   I(min)   I(max)
-1.5V     28.63mA    24.4mA     15.05mA
-956mV    28.63mA    24.4mA     15.05mA
-864mV    28.51mA    24.4mA     13.76mA
-818mV    27.58mA    24.4mA     13.01mA
-726mV    24.87mA    23.72mA    11.22mA
-588mV    19.58mA    19.28mA    7.699mA
-36mV     -7.957mA   -5.375mA   -12.06mA
148mV     -16.19mA   -12.66mA   -17.97mA
378mV     -23.95mA   -19.53mA   -23.2mA
608mV     -28.35mA   -23.68mA   -25.34mA
930mV     -29.68mA   -25.49mA   -25.41mA
3V        -29.68mA   -25.49mA   -25.41mA
[GND_clamp]
|Voltage   I(typ)   I(min)   I(max)
-1.5V     -423.6mA   -473.4mA   -391.3mA
-1.159V   -170.8mA   -226.4mA   -140.1mA
-1.128V   -150.6mA   -205.4mA   -123mA
-1.097V   -131.5mA   -185mA     -108.4mA
-1.035V   -97.76mA   -145.9mA   -88.03mA
-942mV    -62.68mA   -94.08mA   -70.99mA
-849mV    -45.44mA   -55.18mA   -56.59mA
-787mV    -37.67mA   -38mA      -47.37mA
-632mV    -20.99mA   -17.55mA   -26.32mA
-384mV    -4.202mA   -3.933mA   -4.89mA
19mV      0A         0A         0A
3V        0A         0A         0A
[POWER_clamp]
|Voltage   I(typ)   I(min)   I(max)
-1.5V     377.8mA    420.9mA    350.6mA
-1.166V   135.9mA    186.4mA    106mA
-1.104V   98.02mA    147mA      72.63mA
-1.042V   66.02mA    110.5mA    49.91mA
-1.011V   53.08mA    93.78mA    43.04mA
-949mV    34.63mA    64.31mA    34.62mA
-887mV    24.77mA    41.57mA    28.48mA
-825mV    19.16mA    26.4mA     22.89mA
-732mV    13.32mA    14.81mA    16.07mA
-546mV    6.068mA    6.58mA     7.125mA
-50mV     295.8uA    241.2uA    397.5uA
3V        -17.94mA   -11.75mA   -23.63mA
[Ramp]
| variable   typ   min   max
dV/dt_r   0.713/0.421n   0.632/0.525n   0.747/0.508n
dV/dt_f   0.691/0.393n   0.625/0.466n   0.682/0.571n
R_load = 50.000
[Rising Waveform]
R_fixture = 50.000
V_fixture = 0.000
V_fixture_min = 0.000
V_fixture_max = 0.000
|  time   V(typ)   V(min)   V(max)
0s        715.4uV    897.5uV    751.9uV
364ps     1.605mV    947.4uV    -6.704mV
509ps     8.202mV    1.24mV     474.4mV
618ps     260.8mV    -1.442mV   719.9mV
740ps     588.1mV    9.428mV    868.3mV
902ps     848.5mV    280.7mV    974.8mV
1.122ns   998mV      641.2mV    1.049V
1.393ns   1.068V     846.3mV    1.097V
2.419ns   1.136V     995.8mV    1.174V
30ns      1.189V     1.055V     1.246V
[Rising Waveform]
R_fixture = 50.000
V_fixture = 0.750
V_fixture_min = 0.713
V_fixture_max = 0.789
|  time   V(typ)   V(min)   V(max)
0s        210.1mV    215.9mV    255.5mV
351ps     210.4mV    215.9mV    257.6mV
469ps     228.7mV    216.1mV    786.8mV
588ps     601mV      214mV      1.121V
690ps     910.2mV    234.2mV    1.251V
758ps     1.053V     385.2mV    1.302V
971ps     1.252V     864.4mV    1.385V
1.16ns    1.312V     1.082V     1.418V
2.021ns   1.376V     1.258V     1.478V
30ns      1.425V     1.314V     1.538V
[Falling Waveform]
R_fixture = 50.000
V_fixture = 0.750
V_fixture_min = 0.713
V_fixture_max = 0.789
|  time   V(typ)   V(min)   V(max)
0s        1.425V     1.314V     1.538V
361ps     1.425V     1.313V     1.535V
471ps     1.414V     1.313V     1.03V
631ps     718.8mV    1.318V     612.6mV
701ps     550.2mV    1.271V     529.1mV
761ps     467.2mV    1.087V     480.8mV
892ps     372.6mV    658.4mV    417.2mV
1.062ns   318.3mV    432.3mV    375.5mV
1.842ns   257.3mV    267.7mV    315.1mV
30ns      210.1mV    215.9mV    255.5mV
[Falling Waveform]
R_fixture = 50.000
V_fixture = 0.000
V_fixture_min = 0.000
V_fixture_max = 0.000
|  time   V(typ)   V(min)   V(max)
0s        1.189V     1.055V     1.246V
351ps     1.189V     1.055V     1.247V
461ps     1.179V     1.055V     578.1mV
581ps     484.6mV    1.059V     275.3mV
651ps     289mV      1.058V     207.8mV
702ps     222.9mV    958.8mV    176mV
821ps     143.1mV    421.2mV    130.4mV
912ps     111.6mV    245.2mV    109.8mV
1.601ns   45.78mV    52.07mV    55.18mV
30ns      715.4uV    897.5uV    751.9uV
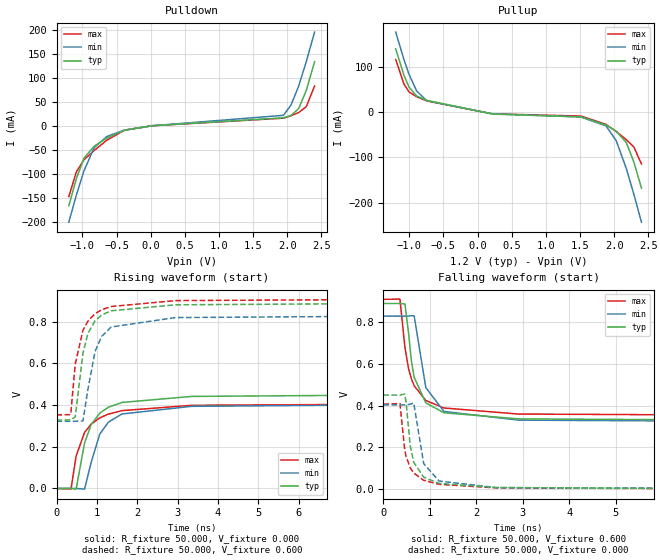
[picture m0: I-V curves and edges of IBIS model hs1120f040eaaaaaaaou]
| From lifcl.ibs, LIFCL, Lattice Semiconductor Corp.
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|Model hs1120f040eaaaaaaaou
[Model] hs1120f040eaaaaaaaou
Model_type Output
Polarity   Non-Inverting
Enable   Active-High
Vmeas =  0.600V
Cref =  20.000pF
Rref =  50.000
Vref =  0.600V
C_comp   5.000pF   4.000pF   5.500pF
[Temperature Range]   25.000   0.125k   -40.000
[Voltage Range]   1.200V   1.140V   1.260V
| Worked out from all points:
|   slope of the pulldown table from 0 to 0.18 V, typ, clamps not added: 56.1 ohm
|   slope of the pullup table from 0 to 0.18 V, typ, clamps not added: 47.9 ohm
|   rising waveform, R_fixture 50.000, V_fixture 0.000: 20-80 % time 491ps typ, 502ps min, 533ps max; typ from 0 V to 0.451 V
|   rising waveform, R_fixture 50.000, V_fixture 0.600: 20-80 % time 334ps typ, 368ps min, 358ps max; typ from 0.328 V to 0.889 V
|   falling waveform, R_fixture 50.000, V_fixture 0.600: 20-80 % time 292ps typ, 298ps min, 332ps max; typ from 0.889 V to 0.328 V
|   falling waveform, R_fixture 50.000, V_fixture 0.000: 20-80 % time 221ps typ, 234ps min, 242ps max; typ from 0.451 V to 0 V
[Pulldown]
|Voltage   I(typ)   I(min)   I(max)
-1.2V     -166.4mA   -200.7mA   -147.3mA
-1.089V   -109.6mA   -144mA     -95.8mA
-978mV    -67.28mA   -93.6mA    -70.51mA
-830mV    -42.37mA   -45.6mA    -51.46mA
-645mV    -25.47mA   -22.15mA   -29.96mA
-386mV    -8.996mA   -8.751mA   -8.931mA
21mV      392.3uA    362.8uA    376.9uA
1.945V    16.89mA    22.14mA    16.13mA
2.056V    21.9mA     43.93mA    21.31mA
2.167V    36.25mA    83.3mA     27.85mA
2.278V    73.74mA    133.9mA    40.14mA
2.4V      133.7mA    195.6mA    83.4mA
[Pullup]
|Voltage   I(typ)   I(min)   I(max)
-1.2V     139.5mA    176.3mA    115.9mA
-1.078V   80.7mA     115.2mA    61.56mA
-1.004V   54.78mA    82.9mA     44.18mA
-893mV    35.43mA    46.5mA     33.93mA
-745mV    25.88mA    25.03mA    24.45mA
217mV     -4.388mA   -3.905mA   -3.867mA
1.512V    -10.51mA   -10.77mA   -8.748mA
1.882V    -28.75mA   -30.61mA   -27.24mA
2.03V     -42.05mA   -62.93mA   -43.02mA
2.178V    -67.19mA   -124.3mA   -60.78mA
2.289V    -110.1mA   -181.3mA   -77.02mA
2.4V      -167.7mA   -242.7mA   -114.4mA
[Ramp]
| variable   typ   min   max
dV/dt_r   0.270/0.491n   0.242/0.510n   0.244/0.537n
dV/dt_f   0.261/0.471n   0.244/0.448n   0.253/0.541n
R_load = 50.000
[Rising Waveform]
R_fixture = 50.000
V_fixture = 0.000
V_fixture_min = 0.000
V_fixture_max = 0.000
|  time   V(typ)   V(min)   V(max)
0s        33.76uV    143.4uV    19.99uV
359ps     415.6uV    193.5uV    -3.125mV
485ps     -3.363mV   251.2uV    155.6mV
695ps     218.2mV    -3.245mV   268.8mV
856ps     305.7mV    123.8mV    308.4mV
1.071ns   361.2mV    260.6mV    338.8mV
1.284ns   389.6mV    317.8mV    356.7mV
1.621ns   412.6mV    357.4mV    373.4mV
3.35ns    441.6mV    394mV      398.9mV
10ns      450.5mV    403.5mV    406.2mV
[Rising Waveform]
R_fixture = 50.000
V_fixture = 0.600
V_fixture_min = 0.571
V_fixture_max = 0.631
|  time   V(typ)   V(min)   V(max)
0s        328.1mV    322.3mV    352.4mV
351ps     328.3mV    322.3mV    354.4mV
464ps     343.6mV    322.4mV    596.9mV
655ps     648.6mV    323.8mV    758.7mV
778ps     743.4mV    475.8mV    802.9mV
955ps     804.8mV    657.4mV    838.5mV
1.118ns   832.1mV    729.6mV    857.1mV
1.355ns   852.4mV    774.6mV    872.9mV
2.946ns   881.1mV    819.8mV    901.2mV
10ns      889.2mV    828.7mV    908.6mV
[Falling Waveform]
R_fixture = 50.000
V_fixture = 0.600
V_fixture_min = 0.571
V_fixture_max = 0.631
|  time   V(typ)   V(min)   V(max)
0s        889.2mV    828.7mV    908.6mV
356ps     889.1mV    828.6mV    910.2mV
464ps     886.8mV    828.7mV    677.7mV
543ps     744.4mV    828.8mV    575.6mV
603ps     613.9mV    831mV      528.5mV
663ps     535.4mV    829.1mV    495.1mV
913ps     413.3mV    486.5mV    424.7mV
1.303ns   365.7mV    372.3mV    388.7mV
2.911ns   336.5mV    330.5mV    359.6mV
10ns      328.1mV    322.3mV    352.4mV
[Falling Waveform]
R_fixture = 50.000
V_fixture = 0.000
V_fixture_min = 0.000
V_fixture_max = 0.000
|  time   V(typ)   V(min)   V(max)
0s        450.5mV    403.5mV    406.2mV
356ps     450.5mV    403.3mV    410.2mV
458ps     455.7mV    403.3mV    190.7mV
488ps     416.9mV    403.1mV    157.3mV
578ps     207.6mV    406.7mV    102.1mV
653ps     128.6mV    412.5mV    77.14mV
868ps     57.46mV    122.7mV    42.43mV
1.198ns   27.59mV    38.97mV    23.26mV
2.437ns   7.761mV    7.532mV    6.096mV
10ns      33.76uV    143.4uV    19.99uV
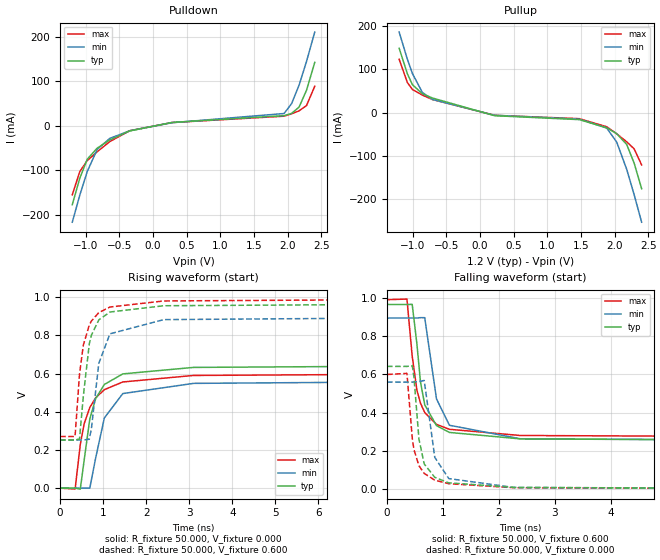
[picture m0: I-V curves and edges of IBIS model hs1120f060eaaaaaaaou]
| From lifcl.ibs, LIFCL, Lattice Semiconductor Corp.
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|Model hs1120f060eaaaaaaaou
[Model] hs1120f060eaaaaaaaou
Model_type Output
Polarity   Non-Inverting
Enable   Active-High
Vmeas =  0.600V
Cref =  20.000pF
Rref =  50.000
Vref =  0.600V
C_comp   5.000pF   4.000pF   5.500pF
[Temperature Range]   25.000   0.125k   -40.000
[Voltage Range]   1.200V   1.140V   1.260V
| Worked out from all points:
|   slope of the pulldown table from 0 to 0.18 V, typ, clamps not added: 35.1 ohm
|   slope of the pullup table from 0 to 0.18 V, typ, clamps not added: 30.6 ohm
|   rising waveform, R_fixture 50.000, V_fixture 0.000: 20-80 % time 376ps typ, 418ps min, 434ps max; typ from 0 V to 0.642 V
|   rising waveform, R_fixture 50.000, V_fixture 0.600: 20-80 % time 250ps typ, 286ps min, 267ps max; typ from 0.252 V to 0.966 V
|   falling waveform, R_fixture 50.000, V_fixture 0.600: 20-80 % time 216ps typ, 241ps min, 239ps max; typ from 0.966 V to 0.252 V
|   falling waveform, R_fixture 50.000, V_fixture 0.000: 20-80 % time 168ps typ, 190ps min, 180ps max; typ from 0.642 V to 0 V
[Pulldown]
|Voltage   I(typ)   I(min)   I(max)
-1.2V     -176.8mA   -216mA     -154.7mA
-1.089V   -117.8mA   -155.8mA   -102.7mA
-978mV    -74.86mA   -102.5mA   -77.86mA
-830mV    -49.9mA    -52.76mA   -58.1mA
-645mV    -31.77mA   -28.3mA    -35.55mA
-349mV    -11.48mA   -11.04mA   -10.97mA
280mV     7.639mA    6.979mA    7.418mA
1.945V    22.82mA    27.65mA    21.64mA
2.056V    27.9mA     49.87mA    26.93mA
2.167V    41.92mA    91.1mA     33.63mA
2.278V    79.92mA    144.5mA    45.57mA
2.4V      142.2mA    210.2mA    88.7mA
[Pullup]
|Voltage   I(typ)   I(min)   I(max)
-1.2V     148.6mA    185.8mA    123.2mA
-1.078V   89.8mA     123.3mA    69.62mA
-1.004V   64.82mA    90.6mA     53.68mA
-856mV    43.75mA    46.82mA    40.63mA
-708mV    33.94mA    30.67mA    30.47mA
217mV     -6.872mA   -5.864mA   -6.045mA
1.475V    -15.93mA   -14.71mA   -13.72mA
1.882V    -34.72mA   -35.42mA   -32.39mA
2.03V     -48.36mA   -67.72mA   -48.62mA
2.178V    -73.09mA   -130.2mA   -66.94mA
2.289V    -116.2mA   -188.9mA   -83.3mA
2.4V      -175.1mA   -252.3mA   -120.3mA
[Ramp]
| variable   typ   min   max
dV/dt_r   0.385/0.380n   0.336/0.415n   0.360/0.443n
dV/dt_f   0.378/0.342n   0.347/0.352n   0.379/0.399n
R_load = 50.000
[Rising Waveform]
R_fixture = 50.000
V_fixture = 0.000
V_fixture_min = 0.000
V_fixture_max = 0.000
|  time   V(typ)   V(min)   V(max)
0s        38.01uV    135.2uV    23.15uV
348ps     446.8uV    164.8uV    -4.367mV
468ps     -5.148mV   192.4uV    229.2mV
558ps     146.9mV    589.8uV    337.6mV
689ps     362.5mV    473.3uV    422.6mV
825ps     469.1mV    157.9mV    473.2mV
1.027ns   543.1mV    367.8mV    515.9mV
1.456ns   598.5mV    495.4mV    556.2mV
3.099ns   632.4mV    548.8mV    590.3mV
10ns      641.8mV    559.8mV    599.3mV
[Rising Waveform]
R_fixture = 50.000
V_fixture = 0.600
V_fixture_min = 0.571
V_fixture_max = 0.631
|  time   V(typ)   V(min)   V(max)
0s        251.8mV    252.4mV    270.8mV
346ps     252.1mV    252.4mV    270.1mV
450ps     258.1mV    252.4mV    597mV
538ps     481.4mV    252.4mV    748.7mV
677ps     755.2mV    256.2mV    854.2mV
727ps     801.6mV    312.8mV    875.6mV
898ps     881.1mV    653.5mV    919.5mV
1.157ns   922.5mV    808.3mV    948.6mV
2.407ns   955.3mV    882.7mV    980.4mV
10ns      965.5mV    894.6mV    990.3mV
[Falling Waveform]
R_fixture = 50.000
V_fixture = 0.600
V_fixture_min = 0.571
V_fixture_max = 0.631
|  time   V(typ)   V(min)   V(max)
0s        965.5mV    894.6mV    990.3mV
356ps     965.3mV    894.5mV    993.7mV
450ps     965.9mV    894.6mV    695.6mV
534ps     759.8mV    894.5mV    517.6mV
598ps     560.8mV    896.7mV    449.4mV
674ps     441mV      896.4mV    400.7mV
884ps     332.3mV    472mV      338.7mV
1.115ns   296.5mV    334.1mV    312.9mV
2.384ns   262.8mV    263.2mV    280.6mV
10ns      251.8mV    252.4mV    270.8mV
[Falling Waveform]
R_fixture = 50.000
V_fixture = 0.000
V_fixture_min = 0.000
V_fixture_max = 0.000
|  time   V(typ)   V(min)   V(max)
0s        641.8mV    559.8mV    599.3mV
356ps     641.6mV    559.6mV    605.3mV
452ps     645.2mV    559.7mV    263.7mV
481ps     585.7mV    559.4mV    207.3mV
571ps     261.2mV    562.8mV    122.1mV
665ps     131.7mV    568.1mV    82.32mV
854ps     61.57mV    166mV      46.86mV
1.104ns   33.13mV    55.35mV    28.57mV
2.267ns   9.245mV    8.905mV    7.546mV
10ns      38.01uV    135.2uV    23.15uV
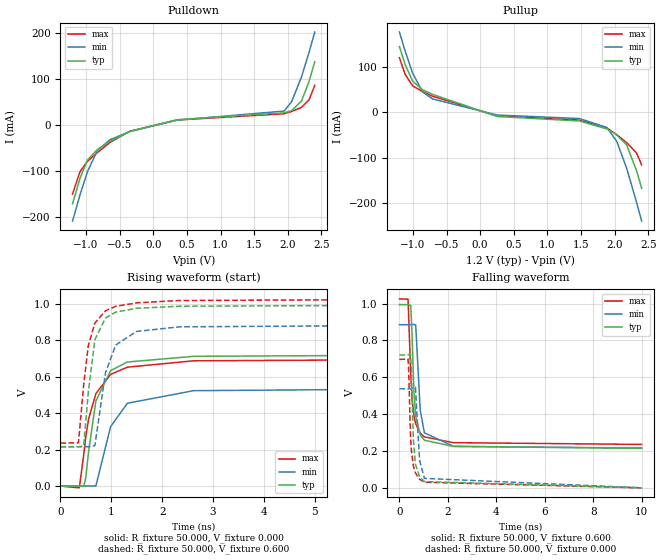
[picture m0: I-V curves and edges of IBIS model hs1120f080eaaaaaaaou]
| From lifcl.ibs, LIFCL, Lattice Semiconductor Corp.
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|Model hs1120f080eaaaaaaaou
[Model] hs1120f080eaaaaaaaou
Model_type Output
Polarity   Non-Inverting
Enable   Active-High
Vmeas =  0.600V
Cref =  20.000pF
Rref =  50.000
Vref =  0.600V
C_comp   5.000pF   4.000pF   5.500pF
[Temperature Range]   25.000   0.125k   -40.000
[Voltage Range]   1.200V   1.140V   1.260V
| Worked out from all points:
|   slope of the pulldown table from 0 to 0.18 V, typ, clamps not added: 27.4 ohm
|   slope of the pullup table from 0 to 0.18 V, typ, clamps not added: 25.5 ohm
|   rising waveform, R_fixture 50.000, V_fixture 0.000: 20-80 % time 298ps typ, 419ps min, 351ps max; typ from 0 V to 0.722 V
|   rising waveform, R_fixture 50.000, V_fixture 0.600: 20-80 % time 202ps typ, 289ps min, 226ps max; typ from 0.214 V to 0.995 V
|   falling waveform, R_fixture 50.000, V_fixture 0.600: 20-80 % time 171ps typ, 190ps min, 188ps max; typ from 0.995 V to 0.214 V
|   falling waveform, R_fixture 50.000, V_fixture 0.000: 20-80 % time 137ps typ, 156ps min, 148ps max; typ from 0.722 V to 0 V
[Pulldown]
|Voltage   I(typ)   I(min)   I(max)
-1.2V     -171mA     -208.4mA   -149.8mA
-1.089V   -115.3mA   -151.3mA   -101.1mA
-978mV    -75.7mA    -101mA     -78.43mA
-830mV    -52.86mA   -54.71mA   -59.48mA
-645mV    -35.14mA   -31.8mA    -37.67mA
-349mV    -14.23mA   -13.64mA   -13.17mA
354mV     11.86mA    10.87mA    11.16mA
1.945V    26.69mA    30.62mA    24.73mA
2.056V    31.4mA     50.81mA    29.73mA
2.204V    52.73mA    105.2mA    38.62mA
2.315V    95.1mA     158.3mA    55.1mA
2.4V      137.6mA    202.4mA    86.7mA
[Pullup]
|Voltage   I(typ)   I(min)   I(max)
-1.2V     143.8mA    175.7mA    119.5mA
-1.115V   104.4mA    133.7mA    82.8mA
-1.004V   67.92mA    85.7mA     57.67mA
-856mV    49.22mA    44.27mA    45.26mA
-708mV    39.03mA    29.01mA    34.96mA
254mV     -9.406mA   -6.294mA   -8.439mA
1.475V    -19.3mA    -13.91mA   -16.99mA
1.882V    -36.72mA   -33.49mA   -34.23mA
2.03V     -49.54mA   -64.04mA   -49.49mA
2.178V    -71.99mA   -123.2mA   -66.77mA
2.326V    -128.9mA   -198.3mA   -89.9mA
2.4V      -166.9mA   -238.6mA   -115.6mA
[Ramp]
| variable   typ   min   max
dV/dt_r   0.433/0.301n   0.323/0.423n   0.418/0.357n
dV/dt_f   0.437/0.249n   0.401/0.265n   0.438/0.295n
R_load = 50.000
[Rising Waveform]
R_fixture = 50.000
V_fixture = 0.000
V_fixture_min = 0.000
V_fixture_max = 0.000
|  time   V(typ)   V(min)   V(max)
0s        40.32uV    121.4uV    24.83uV
371ps     705.5uV    129.5uV    -9.51mV
457ps     -1.74mV    152.5uV    170.5mV
497ps     43.63mV    277.8uV    267.8mV
554ps     191mV      591uV      368.7mV
697ps     466.4mV    1.305mV    506.9mV
987ps     633.2mV    326.5mV    612.2mV
1.317ns   680mV      454.1mV    651.8mV
2.62ns    711.2mV    523mV      686.6mV
10ns      721.6mV    537.6mV    697.4mV
[Rising Waveform]
R_fixture = 50.000
V_fixture = 0.600
V_fixture_min = 0.571
V_fixture_max = 0.631
|  time   V(typ)   V(min)   V(max)
0s        214.5mV    215.9mV    235.8mV
354ps     214.8mV    216mV      237.1mV
457ps     220.4mV    216mV      555.1mV
547ps     511.6mV    215.9mV    768.9mV
677ps     802.2mV    221.7mV    893mV
886ps     920.7mV    621.3mV    960.9mV
1.087ns   953.3mV    773mV      985.1mV
1.496ns   974.3mV    847.4mV    1.004V
2.337ns   985.6mV    872.7mV    1.017V
10ns      994.7mV    885.8mV    1.026V
[Falling Waveform]
R_fixture = 50.000
V_fixture = 0.600
V_fixture_min = 0.571
V_fixture_max = 0.631
|  time   V(typ)   V(min)   V(max)
0s        994.7mV    885.8mV    1.026V
356ps     994.6mV    885.7mV    1.024V
467ps     990.4mV    885.8mV    615.8mV
520ps     831.6mV    885.6mV    484.5mV
598ps     521.7mV    888mV      392.4mV
671ps     389mV      884.3mV    347.9mV
860ps     287.2mV    420.3mV    296mV
1.03ns    258.7mV    298.7mV    276.9mV
2.23ns    224.8mV    225.5mV    245.3mV
10ns      214.5mV    215.9mV    235.8mV
[Falling Waveform]
R_fixture = 50.000
V_fixture = 0.000
V_fixture_min = 0.000
V_fixture_max = 0.000
|  time   V(typ)   V(min)   V(max)
0s        721.6mV    537.6mV    697.4mV
356ps     721.5mV    537.4mV    699.1mV
384ps     723.4mV    537.5mV    621.5mV
456ps     728.3mV    537.5mV    286.4mV
486ps     663.9mV    537.2mV    212.7mV
576ps     259.8mV    541mV      118mV
660ps     128.9mV    546.1mV    80.81mV
831ps     59.53mV    150.1mV    46.74mV
1.032ns   33.89mV    51.38mV    30.35mV
10ns      40.32uV    121.4uV    24.83uV
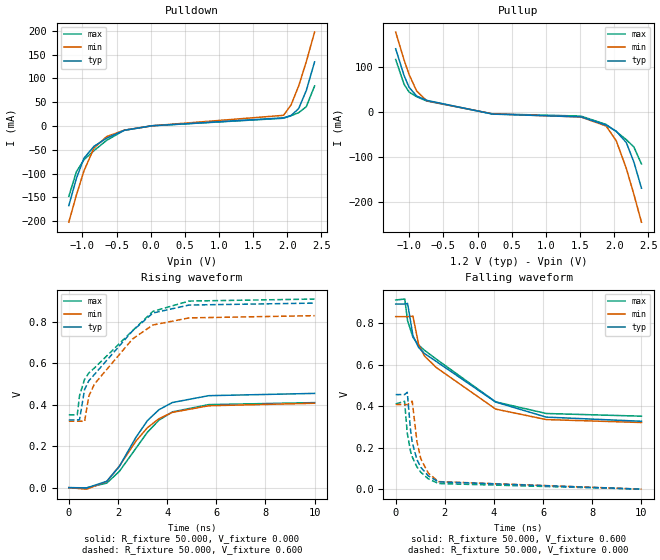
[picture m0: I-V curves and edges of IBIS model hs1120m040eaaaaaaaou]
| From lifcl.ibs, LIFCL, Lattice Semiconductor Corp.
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|Model hs1120m040eaaaaaaaou
[Model] hs1120m040eaaaaaaaou
Model_type Output
Polarity   Non-Inverting
Enable   Active-High
Vmeas =  0.600V
Cref =  20.000pF
Rref =  50.000
Vref =  0.600V
C_comp   5.000pF   4.000pF   5.500pF
[Temperature Range]   25.000   0.125k   -40.000
[Voltage Range]   1.200V   1.140V   1.260V
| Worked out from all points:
|   slope of the pulldown table from 0 to 0.18 V, typ, clamps not added: 55.6 ohm
|   slope of the pullup table from 0 to 0.18 V, typ, clamps not added: 47.4 ohm
|   rising waveform, R_fixture 50.000, V_fixture 0.000: 20-80 % time 1.55ns typ, 1.65ns min, 1.61ns max; typ from 0 V to 0.455 V
|   rising waveform, R_fixture 50.000, V_fixture 0.600: 20-80 % time 2.18ns typ, 1.9ns min, 2.43ns max; typ from 0.327 V to 0.891 V
|   falling waveform, R_fixture 50.000, V_fixture 0.600: 20-80 % time 3.14ns typ, 2.57ns min, 2.92ns max; typ from 0.891 V to 0.327 V
|   falling waveform, R_fixture 50.000, V_fixture 0.000: 20-80 % time 556ps typ, 521ps min, 590ps max; typ from 0.455 V to 0 V
[Pulldown]
|Voltage   I(typ)   I(min)   I(max)
-1.2V     -167.5mA   -202.4mA   -148.2mA
-1.089V   -110.4mA   -145.3mA   -96.4mA
-978mV    -67.78mA   -94.4mA    -70.93mA
-830mV    -42.69mA   -46.01mA   -51.77mA
-645mV    -25.66mA   -22.34mA   -30.14mA
-386mV    -9.063mA   -8.829mA   -8.985mA
21mV      395.2uA    366.1uA    379.3uA
1.945V    17.02mA    22.34mA    16.23mA
2.056V    22.06mA    44.32mA    21.44mA
2.167V    36.51mA    84.1mA     28.01mA
2.278V    74.29mA    135mA      40.38mA
2.4V      134.7mA    197.4mA    84mA
[Pullup]
|Voltage   I(typ)   I(min)   I(max)
-1.2V     141.2mA    178.5mA    117.3mA
-1.078V   81.8mA     116.6mA    62.3mA
-1.004V   55.44mA    83.9mA     44.71mA
-893mV    35.85mA    47.06mA    34.34mA
-745mV    26.19mA    25.33mA    24.75mA
217mV     -4.441mA   -3.952mA   -3.913mA
1.512V    -10.64mA   -10.9mA    -8.854mA
1.882V    -29.09mA   -30.98mA   -27.57mA
2.03V     -42.56mA   -63.69mA   -43.54mA
2.178V    -67.99mA   -125.7mA   -61.51mA
2.289V    -111.5mA   -183.5mA   -77.94mA
2.4V      -169.7mA   -245.6mA   -115.7mA
[Ramp]
| variable   typ   min   max
dV/dt_r   0.273/1.576n   0.244/1.700n   0.246/1.665n
dV/dt_f   0.262/3.062n   0.246/2.751n   0.255/3.005n
R_load = 50.000
[Rising Waveform]
R_fixture = 50.000
V_fixture = 0.000
V_fixture_min = 0.000
V_fixture_max = 0.000
|  time   V(typ)   V(min)   V(max)
0s        34.96uV    144.1uV    18.02uV
724ps     -1.455mV   -7.322mV   -882.4uV
1.545ns   30.81mV    30.27mV    22.06mV
2.057ns   103mV      104.2mV    78.72mV
2.722ns   241.2mV    223.4mV    188.7mV
3.199ns   323.9mV    289.6mV    267.7mV
3.669ns   376.5mV    333.1mV    326.1mV
4.213ns   411.1mV    363.5mV    365.9mV
5.69ns    444.2mV    395.5mV    401mV
10ns      455.2mV    407.6mV    410.7mV
[Rising Waveform]
R_fixture = 50.000
V_fixture = 0.600
V_fixture_min = 0.571
V_fixture_max = 0.631
|  time   V(typ)   V(min)   V(max)
0s        326.9mV    320.9mV    351.4mV
343ps     327.2mV    321mV      351.3mV
436ps     327.9mV    321mV      444.2mV
641ps     474.4mV    320.1mV    523.2mV
815ps     516.4mV    442.2mV    553.9mV
1.046ns   547.2mV    501mV      578.3mV
2.593ns   757.3mV    718.2mV    758mV
3.421ns   843.4mV    785.5mV    851.2mV
4.891ns   881.9mV    819.9mV    901.1mV
10ns      891.3mV    830.6mV    910.8mV
[Falling Waveform]
R_fixture = 50.000
V_fixture = 0.600
V_fixture_min = 0.571
V_fixture_max = 0.631
|  time   V(typ)   V(min)   V(max)
0s        891.3mV    830.6mV    910.8mV
370ps     891.4mV    830.5mV    915.2mV
484ps     894.2mV    830.5mV    810.7mV
703ps     738.4mV    832.8mV    731mV
935ps     681.8mV    695.9mV    693.7mV
1.173ns   652.8mV    640.9mV    668.5mV
1.643ns   615.4mV    586.4mV    626.8mV
4.068ns   419.3mV    385.5mV    420.3mV
6.124ns   346.9mV    335.1mV    364.3mV
10ns      326.9mV    320.9mV    351.4mV
[Falling Waveform]
R_fixture = 50.000
V_fixture = 0.000
V_fixture_min = 0.000
V_fixture_max = 0.000
|  time   V(typ)   V(min)   V(max)
0s        455.2mV    407.6mV    410.7mV
362ps     455.4mV    407.4mV    422.9mV
471ps     466.3mV    407.3mV    269.7mV
602ps     287.1mV    416.4mV    183.8mV
673ps     225.6mV    423.7mV    155.9mV
863ps     142.7mV    229.8mV    107.2mV
1.022ns   105.2mV    146.1mV    81.34mV
1.329ns   63.73mV    76.62mV    49.58mV
1.742ns   35.39mV    36.38mV    27.19mV
10ns      34.96uV    144.1uV    18.02uV
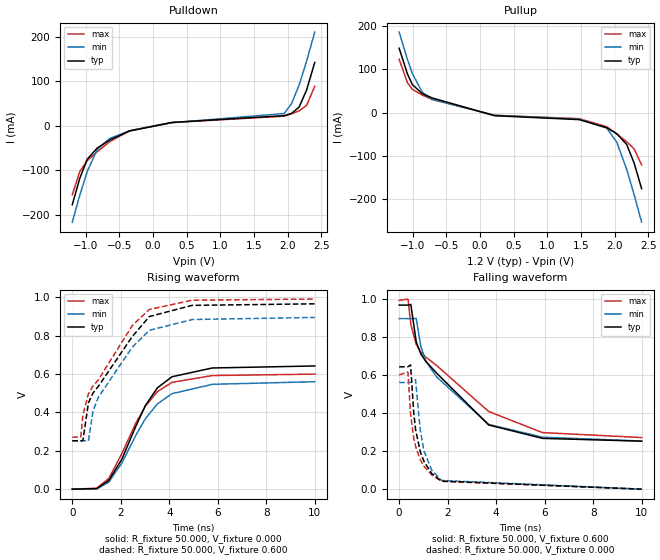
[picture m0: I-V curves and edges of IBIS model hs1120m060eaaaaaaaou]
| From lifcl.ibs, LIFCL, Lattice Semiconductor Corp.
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|Model hs1120m060eaaaaaaaou
[Model] hs1120m060eaaaaaaaou
Model_type Output
Polarity   Non-Inverting
Enable   Active-High
Vmeas =  0.600V
Cref =  20.000pF
Rref =  50.000
Vref =  0.600V
C_comp   5.000pF   4.000pF   5.500pF
[Temperature Range]   25.000   0.125k   -40.000
[Voltage Range]   1.200V   1.140V   1.260V
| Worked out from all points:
|   slope of the pulldown table from 0 to 0.18 V, typ, clamps not added: 35.1 ohm
|   slope of the pullup table from 0 to 0.18 V, typ, clamps not added: 30.6 ohm
|   rising waveform, R_fixture 50.000, V_fixture 0.000: 20-80 % time 1.48ns typ, 1.61ns min, 1.49ns max; typ from 0 V to 0.642 V
|   rising waveform, R_fixture 50.000, V_fixture 0.600: 20-80 % time 2.05ns typ, 1.82ns min, 1.97ns max; typ from 0.252 V to 0.966 V
|   falling waveform, R_fixture 50.000, V_fixture 0.600: 20-80 % time 2.44ns typ, 2.28ns min, 3.11ns max; typ from 0.966 V to 0.252 V
|   falling waveform, R_fixture 50.000, V_fixture 0.000: 20-80 % time 545ps typ, 512ps min, 602ps max; typ from 0.642 V to 0 V
[Pulldown]
|Voltage   I(typ)   I(min)   I(max)
-1.2V     -176.8mA   -216mA     -154.7mA
-1.089V   -117.8mA   -155.8mA   -102.7mA
-978mV    -74.86mA   -102.5mA   -77.86mA
-830mV    -49.9mA    -52.76mA   -58.1mA
-645mV    -31.77mA   -28.3mA    -35.55mA
-349mV    -11.48mA   -11.04mA   -10.97mA
280mV     7.639mA    6.979mA    7.418mA
1.945V    22.82mA    27.65mA    21.64mA
2.056V    27.9mA     49.86mA    26.93mA
2.167V    41.92mA    91.1mA     33.63mA
2.278V    79.92mA    144.5mA    45.57mA
2.4V      142.2mA    210.2mA    88.7mA
[Pullup]
|Voltage   I(typ)   I(min)   I(max)
-1.2V     148.6mA    185.8mA    123.2mA
-1.078V   89.8mA     123.3mA    69.62mA
-1.004V   64.82mA    90.6mA     53.68mA
-856mV    43.75mA    46.82mA    40.63mA
-708mV    33.94mA    30.67mA    30.47mA
217mV     -6.872mA   -5.864mA   -6.045mA
1.475V    -15.93mA   -14.71mA   -13.72mA
1.882V    -34.72mA   -35.42mA   -32.39mA
2.03V     -48.36mA   -67.72mA   -48.62mA
2.178V    -73.09mA   -130.2mA   -66.94mA
2.289V    -116.2mA   -188.9mA   -83.3mA
2.4V      -175.1mA   -252.3mA   -120.3mA
[Ramp]
| variable   typ   min   max
dV/dt_r   0.385/1.519n   0.336/1.674n   0.360/1.500n
dV/dt_f   0.378/2.594n   0.347/2.666n   0.379/3.146n
R_load = 50.000
[Rising Waveform]
R_fixture = 50.000
V_fixture = 0.000
V_fixture_min = 0.000
V_fixture_max = 0.000
|  time   V(typ)   V(min)   V(max)
0s        38.01uV    134.9uV    23.15uV
1.003ns   3.047mV    358.6uV    4.812mV
1.506ns   45.41mV    36.66mV    55.78mV
2.037ns   154mV      134.9mV    183.2mV
2.62ns    327.4mV    280.3mV    344.2mV
3.018ns   436.4mV    367.6mV    432.7mV
3.511ns   527.9mV    444.1mV    508.2mV
4.109ns   585.5mV    497.3mV    556.3mV
5.773ns   631.3mV    546.2mV    591.9mV
10ns      641.8mV    559.8mV    599.3mV
[Rising Waveform]
R_fixture = 50.000
V_fixture = 0.600
V_fixture_min = 0.571
V_fixture_max = 0.631
|  time   V(typ)   V(min)   V(max)
0s        251.8mV    252.4mV    270.8mV
351ps     252.2mV    252.4mV    272.1mV
438ps     252.7mV    252.4mV    386.2mV
666ps     449.5mV    251.8mV    497.4mV
856ps     501mV      407.4mV    537.9mV
1.076ns   535.9mV    479mV      569.5mV
2.474ns   794.9mV    739.6mV    852.3mV
3.179ns   899.3mV    827.5mV    936.3mV
4.941ns   957.4mV    883.8mV    984.3mV
10ns      965.5mV    894.6mV    990.3mV
[Falling Waveform]
R_fixture = 50.000
V_fixture = 0.600
V_fixture_min = 0.571
V_fixture_max = 0.631
|  time   V(typ)   V(min)   V(max)
0s        965.5mV    894.6mV    990.3mV
365ps     965.3mV    894.5mV    997.1mV
482ps     968.5mV    894.4mV    863.9mV
704ps     772.2mV    895.6mV    759.3mV
894ps     709.5mV    750mV      719.4mV
1.094ns   671.3mV    672.1mV    693.2mV
1.544ns   608.9mV    589.2mV    648.9mV
3.691ns   336.8mV    339.9mV    407.4mV
5.913ns   266.4mV    272.7mV    296.7mV
10ns      251.8mV    252.4mV    270.8mV
[Falling Waveform]
R_fixture = 50.000
V_fixture = 0.000
V_fixture_min = 0.000
V_fixture_max = 0.000
|  time   V(typ)   V(min)   V(max)
0s        641.8mV    559.8mV    599.3mV
362ps     641.8mV    559.6mV    614.7mV
471ps     651.7mV    559.5mV    391.8mV
601ps     403.1mV    569.6mV    268mV
674ps     315mV      575.1mV    226.3mV
871ps     196.4mV    308.9mV    154.4mV
1.026ns   145.1mV    199.8mV    119.9mV
1.341ns   82.29mV    100.2mV    75.08mV
1.744ns   42.45mV    45.81mV    41.1mV
10ns      38.01uV    134.9uV    23.15uV
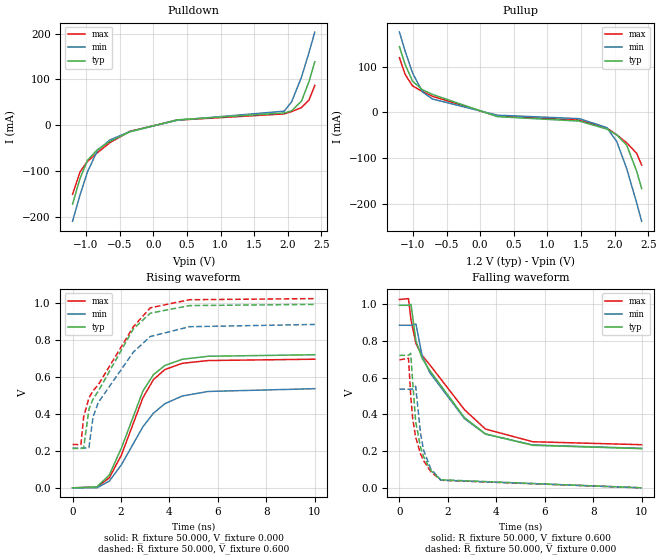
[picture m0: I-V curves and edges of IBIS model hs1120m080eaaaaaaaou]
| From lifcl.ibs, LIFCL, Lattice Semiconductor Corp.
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|Model hs1120m080eaaaaaaaou
[Model] hs1120m080eaaaaaaaou
Model_type Output
Polarity   Non-Inverting
Enable   Active-High
Vmeas =  0.600V
Cref =  20.000pF
Rref =  50.000
Vref =  0.600V
C_comp   5.000pF   4.000pF   5.500pF
[Temperature Range]   25.000   0.125k   -40.000
[Voltage Range]   1.200V   1.140V   1.260V
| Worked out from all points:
|   slope of the pulldown table from 0 to 0.18 V, typ, clamps not added: 27.3 ohm
|   slope of the pullup table from 0 to 0.18 V, typ, clamps not added: 25.5 ohm
|   rising waveform, R_fixture 50.000, V_fixture 0.000: 20-80 % time 1.33ns typ, 1.61ns min, 1.29ns max; typ from 0 V to 0.722 V
|   rising waveform, R_fixture 50.000, V_fixture 0.600: 20-80 % time 1.82ns typ, 1.81ns min, 2.02ns max; typ from 0.214 V to 0.995 V
|   falling waveform, R_fixture 50.000, V_fixture 0.600: 20-80 % time 2.14ns typ, 2.02ns min, 2.37ns max; typ from 0.995 V to 0.214 V
|   falling waveform, R_fixture 50.000, V_fixture 0.000: 20-80 % time 536ps typ, 501ps min, 590ps max; typ from 0.722 V to 0 V
[Pulldown]
|Voltage   I(typ)   I(min)   I(max)
-1.2V     -172mA     -209.5mA   -150.5mA
-1.089V   -116mA     -152mA     -101.6mA
-978mV    -76.15mA   -101.5mA   -78.8mA
-830mV    -53.18mA   -54.98mA   -59.76mA
-645mV    -35.35mA   -31.96mA   -37.85mA
-349mV    -14.32mA   -13.71mA   -13.23mA
354mV     11.93mA    10.92mA    11.21mA
1.945V    26.85mA    30.77mA    24.85mA
2.056V    31.59mA    51.06mA    29.87mA
2.204V    53.04mA    105.6mA    38.8mA
2.315V    95.7mA     159.2mA    55.36mA
2.4V      138.5mA    203.5mA    87mA
[Pullup]
|Voltage   I(typ)   I(min)   I(max)
-1.2V     143.8mA    175.7mA    119.5mA
-1.115V   104.4mA    133.7mA    82.8mA
-1.004V   67.92mA    85.7mA     57.67mA
-856mV    49.22mA    44.27mA    45.26mA
-708mV    39.03mA    29.01mA    34.96mA
254mV     -9.406mA   -6.294mA   -8.439mA
1.475V    -19.3mA    -13.91mA   -16.99mA
1.882V    -36.72mA   -33.49mA   -34.23mA
2.03V     -49.54mA   -64.04mA   -49.49mA
2.178V    -71.99mA   -123.2mA   -66.77mA
2.326V    -128.9mA   -198.3mA   -89.9mA
2.4V      -166.9mA   -238.6mA   -115.6mA
[Ramp]
| variable   typ   min   max
dV/dt_r   0.433/1.352n   0.323/1.676n   0.418/1.350n
dV/dt_f   0.438/2.309n   0.402/2.319n   0.439/2.482n
R_load = 50.000
[Rising Waveform]
R_fixture = 50.000
V_fixture = 0.000
V_fixture_min = 0.000
V_fixture_max = 0.000
|  time   V(typ)   V(min)   V(max)
0s        41.32uV    121.6uV    24.31uV
1.003ns   5.354mV    48.92uV    4.153mV
1.513ns   68.74mV    35.98mV    53.76mV
2.016ns   215.6mV    124.9mV    177.6mV
2.906ns   525.2mV    331.5mV    489mV
3.34ns    613.4mV    404.8mV    586.8mV
3.811ns   663.6mV    456.3mV    641.3mV
4.531ns   697mV      498mV      675.2mV
5.6ns     713.4mV    522.6mV    690.2mV
10ns      721.6mV    537.6mV    697.4mV
[Rising Waveform]
R_fixture = 50.000
V_fixture = 0.600
V_fixture_min = 0.571
V_fixture_max = 0.631
|  time   V(typ)   V(min)   V(max)
0s        213.6mV    215.2mV    235mV
346ps     214mV      215.2mV    234.3mV
457ps     214.4mV    215.3mV    383.6mV
676ps     425.8mV    217.7mV    487.6mV
847ps     481.7mV    385mV      526.5mV
1.066ns   524.9mV    463.6mV    559.2mV
2.507ns   861.2mV    735.4mV    872.9mV
3.209ns   947.1mV    820.4mV    976.1mV
4.83ns    988.1mV    873.7mV    1.02V
10ns      994.7mV    885.8mV    1.026V
[Falling Waveform]
R_fixture = 50.000
V_fixture = 0.600
V_fixture_min = 0.571
V_fixture_max = 0.631
|  time   V(typ)   V(min)   V(max)
0s        994.7mV    885.8mV    1.026V
374ps     994.6mV    885.7mV    1.031V
478ps     999.1mV    885.7mV    914.5mV
681ps     800.4mV    892.5mV    786.1mV
938ps     704.8mV    719mV      721.6mV
1.25ns    640.1mV    628.4mV    670.9mV
2.683ns   382.7mV    377.3mV    426.1mV
3.551ns   294mV      292.8mV    320.3mV
5.506ns   231.8mV    233.6mV    251.2mV
10ns      213.6mV    215.2mV    235mV
[Falling Waveform]
R_fixture = 50.000
V_fixture = 0.000
V_fixture_min = 0.000
V_fixture_max = 0.000
|  time   V(typ)   V(min)   V(max)
0s        721.6mV    537.6mV    697.4mV
374ps     722.7mV    537.3mV    706mV
466ps     732.9mV    537.4mV    501.7mV
550ps     571.2mV    538.9mV    374.5mV
670ps     361.1mV    553.7mV    276.6mV
870ps     221.8mV    297.6mV    185.2mV
1ns       170.1mV    204mV      147.6mV
1.294ns   94.47mV    103.3mV    88.31mV
1.714ns   44.03mV    41.88mV    41.39mV
10ns      41.32uV    121.6uV    24.31uV
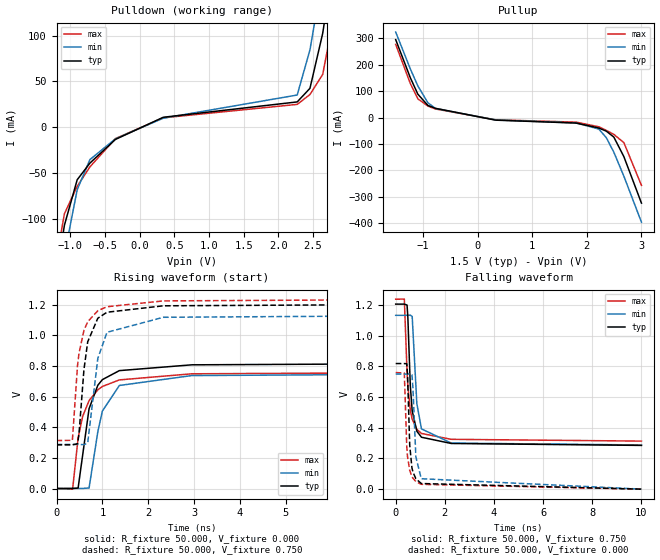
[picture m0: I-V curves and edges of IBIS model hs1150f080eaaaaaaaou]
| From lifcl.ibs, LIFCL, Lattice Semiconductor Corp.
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|Model hs1150f080eaaaaaaaou
[Model] hs1150f080eaaaaaaaou
Model_type Output
Polarity   Non-Inverting
Enable   Active-High
Vmeas =  0.750V
Cref =  30.000pF
Rref =  50.000
Vref =  0.750V
C_comp   5.000pF   4.000pF   5.500pF
[Temperature Range]   25.000   0.125k   -40.000
[Voltage Range]   1.500V   1.430V   1.580V
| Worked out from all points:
|   slope of the pulldown table from 0 to 0.225 V, typ, clamps not added: 29.8 ohm
|   slope of the pullup table from 0 to 0.225 V, typ, clamps not added: 31.2 ohm
|   rising waveform, R_fixture 50.000, V_fixture 0.000: 20-80 % time 311ps typ, 333ps min, 377ps max; typ from 0 V to 0.818 V
|   rising waveform, R_fixture 50.000, V_fixture 0.750: 20-80 % time 217ps typ, 245ps min, 234ps max; typ from 0.285 V to 1.21 V
|   falling waveform, R_fixture 50.000, V_fixture 0.750: 20-80 % time 189ps typ, 202ps min, 215ps max; typ from 1.21 V to 0.285 V
|   falling waveform, R_fixture 50.000, V_fixture 0.000: 20-80 % time 135ps typ, 149ps min, 147ps max; typ from 0.818 V to 0 V
[Pulldown]
|Voltage   I(typ)   I(min)   I(max)
-1.5V     -326.3mA   -350.1mA   -313mA
-1.224V   -172.9mA   -205.9mA   -153.5mA
-1.086V   -107mA     -139.4mA   -94.5mA
-902mV    -57.43mA   -68.43mA   -64.61mA
-718mV    -39.22mA   -35.37mA   -43.32mA
-350mV    -13.4mA    -12.73mA   -12.46mA
340mV     10.77mA    9.771mA    10.19mA
2.272V    27.53mA    35.06mA    24.84mA
2.456V    42.37mA    84.4mA     35.58mA
2.64V     102.4mA    165.2mA    57.58mA
2.778V    171mA      233.5mA    112.1mA
3V        293.1mA    349mA      235.4mA
[Pullup]
|Voltage   I(typ)   I(min)   I(max)
-1.5V     294.8mA    323.3mA    276.8mA
-1.232V   150.5mA    184mA      128.7mA
-1.094V   88.2mA     119.4mA    70.74mA
-910mV    45.66mA    55.61mA    43.29mA
-772mV    34.73mA    34.4mA     32.32mA
332mV     -10.06mA   -9.158mA   -8.746mA
1.804V    -20.96mA   -20.73mA   -17.46mA
2.218V    -39.78mA   -43.53mA   -35.02mA
2.356V    -51.58mA   -76.2mA    -48.65mA
2.494V    -74.1mA    -131.3mA   -63.92mA
2.678V    -148.1mA   -222.2mA   -95.1mA
3V        -324mA     -396.2mA   -256.9mA
[Ramp]
| variable   typ   min   max
dV/dt_r   0.491/0.313n   0.450/0.337n   0.456/0.377n
dV/dt_f   0.491/0.334n   0.452/0.332n   0.477/0.414n
R_load = 50.000
[Rising Waveform]
R_fixture = 50.000
V_fixture = 0.000
V_fixture_min = 0.000
V_fixture_max = 0.000
|  time   V(typ)   V(min)   V(max)
0s        64.49uV    261.8uV    35.41uV
351ps     396.9uV    285.8uV    -4.189mV
471ps     3.212mV    339.1uV    330.2mV
569ps     216mV      594.2uV    470.3mV
710ps     521.2mV    3.393mV    573.9mV
901ps     674.3mV    370.5mV    644.7mV
1ns       711mV      505.3mV    666.3mV
1.371ns   769.8mV    672.8mV    709.2mV
2.949ns   807.6mV    737.5mV    749mV
10ns      818.1mV    749.6mV    759.4mV
[Rising Waveform]
R_fixture = 50.000
V_fixture = 0.750
V_fixture_min = 0.713
V_fixture_max = 0.789
|  time   V(typ)   V(min)   V(max)
0s        285mV      287.9mV    313mV
346ps     285.2mV    287.9mV    314.7mV
458ps     292.3mV    288mV      802.4mV
490ps     356mV      288mV      882.3mV
598ps     776.4mV    286.2mV    1.032V
680ps     957.7mV    297.2mV    1.089V
901ps     1.112V     849.3mV    1.161V
1.101ns   1.151V     1.02V      1.187V
2.33ns    1.193V     1.118V     1.225V
10ns      1.205V     1.132V     1.237V
[Falling Waveform]
R_fixture = 50.000
V_fixture = 0.750
V_fixture_min = 0.713
V_fixture_max = 0.789
|  time   V(typ)   V(min)   V(max)
0s        1.205V     1.132V     1.237V
351ps     1.205V     1.132V     1.238V
463ps     1.199V     1.132V     760.7mV
494ps     1.122V     1.132V     674.5mV
594ps     675.8mV    1.133V     516.2mV
671ps     510.4mV    1.125V     456mV
861ps     377.6mV    556.4mV    389mV
1.049ns   338.2mV    392.7mV    362.8mV
2.261ns   297.6mV    300.1mV    324.6mV
10ns      285mV      287.9mV    313mV
[Falling Waveform]
R_fixture = 50.000
V_fixture = 0.000
V_fixture_min = 0.000
V_fixture_max = 0.000
|  time   V(typ)   V(min)   V(max)
0s        818.1mV    749.6mV    759.4mV
351ps     817.9mV    749.4mV    756.1mV
451ps     817mV      749.5mV    276.9mV
481ps     748.9mV    749.3mV    212.7mV
571ps     285.9mV    751.5mV    122.3mV
661ps     139.1mV    744.4mV    82.54mV
701ps     112.1mV    660.5mV    71.42mV
821ps     67.9mV     209.9mV    50.02mV
1.041ns   36.79mV    68.01mV    31.6mV
10ns      64.49uV    261.8uV    35.41uV
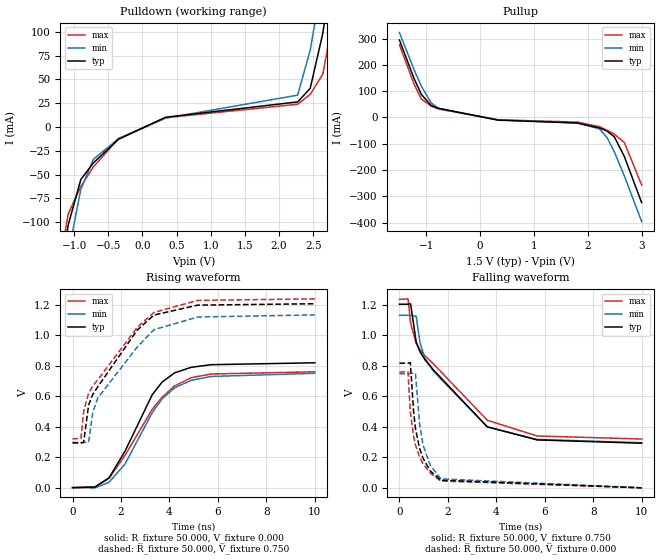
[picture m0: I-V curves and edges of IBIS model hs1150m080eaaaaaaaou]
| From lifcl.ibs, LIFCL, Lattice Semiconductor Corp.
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|Model hs1150m080eaaaaaaaou
[Model] hs1150m080eaaaaaaaou
Model_type Output
Polarity   Non-Inverting
Enable   Active-High
Vmeas =  0.750V
Cref =  30.000pF
Rref =  50.000
Vref =  0.750V
C_comp   5.000pF   4.000pF   5.500pF
[Temperature Range]   25.000   0.125k   -40.000
[Voltage Range]   1.500V   1.430V   1.580V
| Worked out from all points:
|   slope of the pulldown table from 0 to 0.225 V, typ, clamps not added: 31 ohm
|   slope of the pullup table from 0 to 0.225 V, typ, clamps not added: 31.2 ohm
|   rising waveform, R_fixture 50.000, V_fixture 0.000: 20-80 % time 1.56ns typ, 1.65ns min, 1.85ns max; typ from 0 V to 0.818 V
|   rising waveform, R_fixture 50.000, V_fixture 0.750: 20-80 % time 2.05ns typ, 2.08ns min, 2.22ns max; typ from 0.293 V to 1.21 V
|   falling waveform, R_fixture 50.000, V_fixture 0.750: 20-80 % time 2.42ns typ, 2.23ns min, 2.7ns max; typ from 1.21 V to 0.293 V
|   falling waveform, R_fixture 50.000, V_fixture 0.000: 20-80 % time 539ps typ, 515ps min, 594ps max; typ from 0.818 V to 0 V
[Pulldown]
|Voltage   I(typ)   I(min)   I(max)
-1.5V     -313.3mA   -335mA     -302.1mA
-1.224V   -165.9mA   -197mA     -148.1mA
-1.086V   -102.7mA   -133.4mA   -91.2mA
-902mV    -55.14mA   -65.48mA   -62.36mA
-718mV    -37.66mA   -33.85mA   -41.81mA
-350mV    -12.86mA   -12.18mA   -12.03mA
340mV     10.34mA    9.35mA     9.838mA
2.272V    26.43mA    33.55mA    23.97mA
2.456V    40.68mA    80.8mA     34.34mA
2.64V     98.3mA     158mA      55.57mA
2.778V    164.2mA    223.5mA    108.3mA
3V        281.4mA    334mA      227.2mA
[Pullup]
|Voltage   I(typ)   I(min)   I(max)
-1.5V     294.8mA    323.3mA    276.8mA
-1.232V   150.5mA    184mA      128.7mA
-1.094V   88.2mA     119.4mA    70.74mA
-910mV    45.66mA    55.61mA    43.29mA
-772mV    34.73mA    34.4mA     32.32mA
332mV     -10.06mA   -9.158mA   -8.746mA
1.804V    -20.96mA   -20.73mA   -17.46mA
2.218V    -39.78mA   -43.53mA   -35.02mA
2.356V    -51.58mA   -76.2mA    -48.65mA
2.494V    -74.1mA    -131.3mA   -63.92mA
2.678V    -148.1mA   -222.2mA   -95.1mA
3V        -324mA     -396.2mA   -256.9mA
[Ramp]
| variable   typ   min   max
dV/dt_r   0.491/1.572n   0.450/1.683n   0.456/1.873n
dV/dt_f   0.477/2.673n   0.438/2.569n   0.463/2.889n
R_load = 50.000
[Rising Waveform]
R_fixture = 50.000
V_fixture = 0.000
V_fixture_min = 0.000
V_fixture_max = 0.000
|  time   V(typ)   V(min)   V(max)
0s        63.87uV    256.7uV    34.88uV
929ps     4.145mV    -1.355mV   5.174mV
1.509ns   64.98mV    35.43mV    61.84mV
2.168ns   239.6mV    155.4mV    212mV
3.289ns   608.6mV    490.7mV    513.2mV
3.69ns    690.8mV    581.2mV    590.9mV
4.21ns    751.8mV    654.4mV    666.4mV
4.899ns   788.5mV    703.2mV    720.4mV
5.725ns   805.7mV    728.5mV    744.8mV
10ns      818.1mV    749.5mV    759.4mV
[Rising Waveform]
R_fixture = 50.000
V_fixture = 0.750
V_fixture_min = 0.713
V_fixture_max = 0.789
|  time   V(typ)   V(min)   V(max)
0s        292.9mV    296.1mV    320.5mV
346ps     293.1mV    296.2mV    321.7mV
458ps     296.3mV    296.3mV    500.6mV
661ps     539.6mV    297mV      617.1mV
831ps     609.8mV    490.5mV    665.8mV
1.039ns   660.2mV    586.7mV    706mV
2.672ns   1.033V     921.9mV    1.051V
3.361ns   1.131V     1.035V     1.148V
5.167ns   1.196V     1.118V     1.227V
10ns      1.205V     1.132V     1.237V
[Falling Waveform]
R_fixture = 50.000
V_fixture = 0.750
V_fixture_min = 0.713
V_fixture_max = 0.789
|  time   V(typ)   V(min)   V(max)
0s        1.205V     1.132V     1.237V
356ps     1.205V     1.132V     1.24V
461ps     1.207V     1.132V     1.081V
691ps     958.5mV    1.126V     947.6mV
851ps     892.7mV    951.4mV    904.4mV
1.051ns   841.5mV    850.8mV    867.6mV
1.412ns   772.3mV    763.4mV    811.9mV
3.629ns   400.3mV    399.3mV    443.3mV
5.685ns   314.4mV    318mV      340.2mV
10ns      292.9mV    296.1mV    320.5mV
[Falling Waveform]
R_fixture = 50.000
V_fixture = 0.000
V_fixture_min = 0.000
V_fixture_max = 0.000
|  time   V(typ)   V(min)   V(max)
0s        818.1mV    749.5mV    759.4mV
351ps     817.8mV    749.4mV    763.4mV
451ps     821.4mV    749.5mV    497.4mV
581ps     507mV      753.3mV    339.9mV
660ps     391mV      751.3mV    283mV
831ps     259.2mV    422.1mV    202mV
971ps     195.6mV    282.5mV    159.3mV
1.271ns   110.7mV    147.9mV    97.37mV
1.711ns   50.09mV    59.1mV     44.81mV
10ns      63.87uV    256.7uV    34.88uV
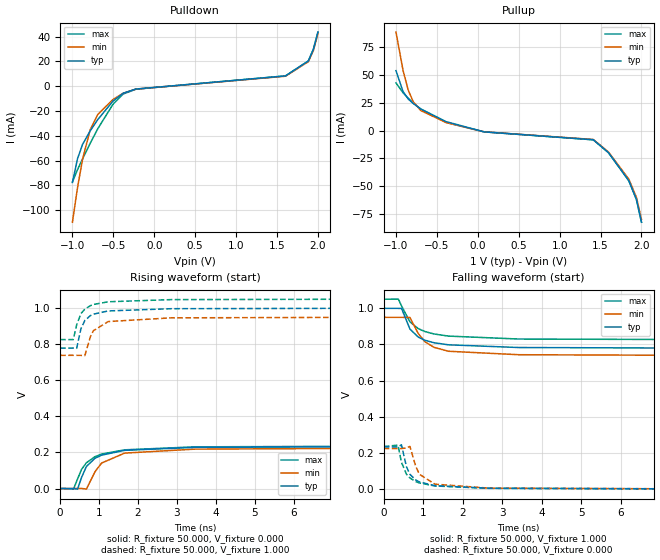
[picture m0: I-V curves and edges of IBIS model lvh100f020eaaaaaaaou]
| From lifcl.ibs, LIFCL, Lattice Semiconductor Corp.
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|Model lvh100f020eaaaaaaaou
[Model] lvh100f020eaaaaaaaou
Model_type Output
Polarity   Non-Inverting
Enable   Active-High
Vmeas =  0.500V
Cref =  0.0F
Rref =  1.000M
Vref =  0.0V
C_comp   5.000pF   4.000pF   5.500pF
[Temperature Range]   25.000   0.125k   -40.000
[Voltage Range]   1.000V   0.950V   1.050V
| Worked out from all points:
|   slope of the pulldown table from 0 to 0.15 V, typ, clamps not added: 107 ohm
|   slope of the pullup table from 0 to 0.15 V, typ, clamps not added: 74.6 ohm
|   rising waveform, R_fixture 50.000, V_fixture 0.000: 20-80 % time 556ps typ, 572ps min, 594ps max; typ from 0 V to 0.234 V
|   rising waveform, R_fixture 50.000, V_fixture 1.000: 20-80 % time 284ps typ, 317ps min, 314ps max; typ from 0.778 V to 1 V
|   falling waveform, R_fixture 50.000, V_fixture 1.000: 20-80 % time 528ps typ, 552ps min, 590ps max; typ from 1 V to 0.778 V
|   falling waveform, R_fixture 50.000, V_fixture 0.000: 20-80 % time 330ps typ, 348ps min, 350ps max; typ from 0.234 V to 0 V
[Pulldown]
|Voltage   I(typ)   I(min)   I(max)
-1V       -77.67mA   -109.7mA   -77.1mA
-938mV    -58.53mA   -81.92mA   -67.33mA
-876mV    -46.89mA   -58.86mA   -58.63mA
-783mV    -36mA      -35.1mA    -46.09mA
-690mV    -26.86mA   -22.73mA   -34.26mA
-504mV    -11.96mA   -10.67mA   -14.5mA
-380mV    -5.675mA   -5.627mA   -6.286mA
-225mV    -2.256mA   -2.289mA   -2.368mA
1.604V    8.365mA    8.114mA    8.365mA
1.883V    20.45mA    19.84mA    20.45mA
1.945V    29.87mA    28.98mA    29.87mA
2V        43.72mA    42.41mA    43.72mA
[Pullup]
|Voltage   I(typ)   I(min)   I(max)
-1V       54.04mA    88.72mA    42.94mA
-914mV    35.21mA    54.31mA    34.1mA
-852mV    28.59mA    36.79mA    29.36mA
-790mV    24.45mA    26.08mA    25.03mA
-697mV    19.52mA    18.1mA     19.35mA
-387mV    8.066mA    7.264mA    7.319mA
78mV      -1.134mA   -1.1mA     -1.134mA
1.411V    -8.238mA   -7.991mA   -8.238mA
1.597V    -19.87mA   -19.28mA   -19.87mA
1.845V    -45.03mA   -43.68mA   -45.03mA
1.938V    -61.85mA   -59.99mA   -61.85mA
2V        -82.45mA   -79.98mA   -82.45mA
[Ramp]
| variable   typ   min   max
dV/dt_r   0.140/0.565n   0.132/0.577n   0.146/0.602n
dV/dt_f   0.133/0.532n   0.128/0.548n   0.135/0.585n
R_load = 50.000
[Rising Waveform]
R_fixture = 50.000
V_fixture = 0.000
V_fixture_min = 0.000
V_fixture_max = 0.000
|  time   V(typ)   V(min)   V(max)
0s        323.7uV    438.5uV    441.7uV
345ps     590.7uV    548.2uV    -2.164mV
446ps     -3.209mV   474.3uV    52.21mV
548ps     60.57mV    798.1uV    105.8mV
675ps     122.6mV    -2.558mV   143.3mV
895ps     167.8mV    93.27mV    176.7mV
1.065ns   185.5mV    141.4mV    191.1mV
1.656ns   211.9mV    196.6mV    214.7mV
3.469ns   228.5mV    218.7mV    231.3mV
10ns      233.8mV    224.8mV    235.9mV
[Rising Waveform]
R_fixture = 50.000
V_fixture = 1.000
V_fixture_min = 0.950
V_fixture_max = 1.050
|  time   V(typ)   V(min)   V(max)
0s        778.3mV    738.2mV    825.6mV
336ps     778.5mV    738.4mV    825.3mV
424ps     777.1mV    738.3mV    907mV
534ps     885.5mV    738.1mV    969.4mV
635ps     931.5mV    737.1mV    994.4mV
775ps     957.9mV    840.1mV    1.013V
855ps     966.3mV    875mV      1.02V
1.234ns   984.3mV    925.3mV    1.035V
2.86ns    996.6mV    946mV      1.047V
10ns      999.9mV    949.9mV    1.05V
[Falling Waveform]
R_fixture = 50.000
V_fixture = 1.000
V_fixture_min = 0.950
V_fixture_max = 1.050
|  time   V(typ)   V(min)   V(max)
0s        999.9mV    949.9mV    1.05V
370ps     999.5mV    949.8mV    1.051V
452ps     999.2mV    949.9mV    1.013V
663ps     885.6mV    949.3mV    925.5mV
873ps     841mV      861.1mV    887.8mV
1.043ns   823.4mV    815.2mV    871.5mV
1.274ns   809.5mV    784.2mV    858.1mV
1.641ns   798.1mV    762.5mV    846.3mV
3.421ns   783.2mV    743.4mV    830.1mV
10ns      778.3mV    738.2mV    825.6mV
[Falling Waveform]
R_fixture = 50.000
V_fixture = 0.000
V_fixture_min = 0.000
V_fixture_max = 0.000
|  time   V(typ)   V(min)   V(max)
0s        233.8mV    224.8mV    235.9mV
362ps     233.9mV    224.5mV    243.8mV
449ps     245.5mV    224.6mV    149.3mV
577ps     123.8mV    228.2mV    82.95mV
664ps     82.13mV    236.4mV    62.29mV
814ps     50.75mV    125mV      41.96mV
904ps     40.39mV    82.9mV     34.49mV
1.297ns   19.56mV    27.96mV    18.11mV
2.673ns   5.528mV    5.958mV    4.788mV
10ns      323.7uV    438.5uV    441.7uV
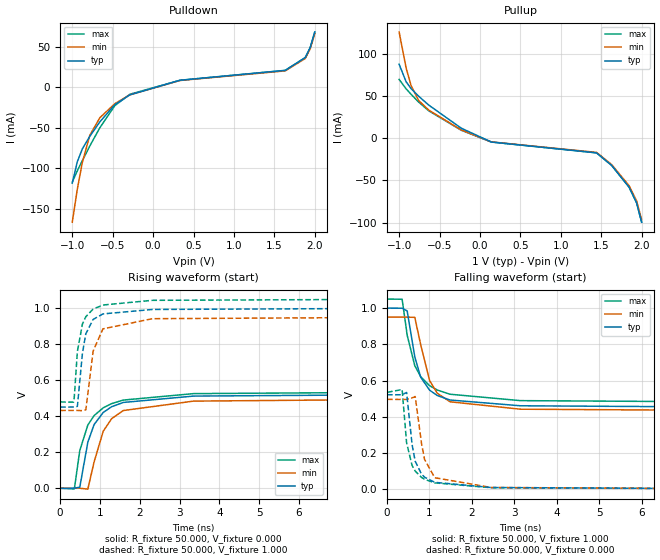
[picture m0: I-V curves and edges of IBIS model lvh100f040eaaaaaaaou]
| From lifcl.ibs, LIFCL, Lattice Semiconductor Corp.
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[Model] lvh100f040eaaaaaaaou
Model_type Output
Polarity   Non-Inverting
Enable   Active-High
Vmeas =  0.500V
Cref =  0.0F
Rref =  1.000M
Vref =  0.0V
C_comp   5.000pF   4.000pF   5.500pF
[Temperature Range]   25.000   0.125k   -40.000
[Voltage Range]   1.000V   0.950V   1.050V
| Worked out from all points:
|   slope of the pulldown table from 0 to 0.15 V, typ, clamps not added: 34.6 ohm
|   slope of the pullup table from 0 to 0.15 V, typ, clamps not added: 29.9 ohm
|   rising waveform, R_fixture 50.000, V_fixture 0.000: 20-80 % time 496ps typ, 533ps min, 542ps max; typ from 0 V to 0.521 V
|   rising waveform, R_fixture 50.000, V_fixture 1.000: 20-80 % time 210ps typ, 247ps min, 226ps max; typ from 0.451 V to 1 V
|   falling waveform, R_fixture 50.000, V_fixture 1.000: 20-80 % time 403ps typ, 408ps min, 468ps max; typ from 1 V to 0.451 V
|   falling waveform, R_fixture 50.000, V_fixture 0.000: 20-80 % time 229ps typ, 255ps min, 244ps max; typ from 0.521 V to 0 V
[Pulldown]
|Voltage   I(typ)   I(min)   I(max)
-1V       -118.4mA   -166.7mA   -117mA
-938mV    -92.07mA   -126.1mA   -103.2mA
-876mV    -76.13mA   -92.99mA   -90.66mA
-783mV    -60.46mA   -59.19mA   -72.49mA
-659mV    -42.67mA   -37.52mA   -49.88mA
-473mV    -21.27mA   -20.11mA   -22.48mA
-287mV    -9.194mA   -9.165mA   -8.478mA
333mV     8.82mA     8.556mA    8.82mA
1.635V    21.06mA    20.43mA    21.06mA
1.883V    36.89mA    35.78mA    36.89mA
1.945V    49.53mA    48.04mA    49.53mA
2V        68.4mA     66.35mA    68.4mA
[Pullup]
|Voltage   I(typ)   I(min)   I(max)
-1V       87.31mA    125.4mA    69.34mA
-914mV    66.65mA    82.99mA    58.26mA
-852mV    58.48mA    61.88mA    51.68mA
-759mV    49.52mA    44.49mA    42.61mA
-635mV    39.08mA    33.14mA    32.31mA
-232mV    11.7mA     9.634mA    9.279mA
140mV     -4.706mA   -4.564mA   -4.706mA
1.442V    -17.51mA   -16.98mA   -17.51mA
1.628V    -32.26mA   -31.3mA    -32.26mA
1.845V    -58.14mA   -56.4mA    -58.14mA
1.938V    -76.72mA   -74.42mA   -76.72mA
2V        -99.59mA   -96.6mA    -99.59mA
[Ramp]
| variable   typ   min   max
dV/dt_r   0.298/0.491n   0.298/0.534n   0.321/0.551n
dV/dt_f   0.329/0.404n   0.311/0.408n   0.343/0.474n
R_load = 50.000
[Rising Waveform]
R_fixture = 50.000
V_fixture = 0.000
V_fixture_min = 0.000
V_fixture_max = 0.000
|  time   V(typ)   V(min)   V(max)
0s        21.62uV    -9.741uV   -165.3uV
356ps     704.2uV    51.79uV    -3.543mV
493ps     5.798mV    288.6uV    209.3mV
695ps     255.7mV    -4.856mV   351.1mV
853ps     353.6mV    146.3mV    403.3mV
1.082ns   420.9mV    316.7mV    446.5mV
1.293ns   452.6mV    386.1mV    469.8mV
1.585ns   476.3mV    431.4mV    489.5mV
3.35ns    511.6mV    483.7mV    525.3mV
10ns      521.5mV    495.9mV    534.9mV
[Rising Waveform]
R_fixture = 50.000
V_fixture = 1.000
V_fixture_min = 0.950
V_fixture_max = 1.050
|  time   V(typ)   V(min)   V(max)
0s        450.7mV    431.9mV    479.3mV
336ps     451mV      432.1mV    477.9mV
355ps     450.7mV    432mV      505.4mV
433ps     454.8mV    432.1mV    759.8mV
559ps     747.6mV    430.5mV    911.1mV
645ps     857.3mV    435.6mV    952.2mV
829ps     937mV      761.8mV    994.4mV
1.075ns   967.6mV    884.6mV    1.017V
2.317ns   992.3mV    941.1mV    1.043V
10ns      999.9mV    950.2mV    1.05V
[Falling Waveform]
R_fixture = 50.000
V_fixture = 1.000
V_fixture_min = 0.950
V_fixture_max = 1.050
|  time   V(typ)   V(min)   V(max)
0s        999.9mV    950.2mV    1.05V
356ps     999.5mV    950.1mV    1.049V
475ps     984.4mV    950.2mV    849.8mV
654ps     730.5mV    949mV      681.8mV
795ps     617.2mV    796mV      620.7mV
1.004ns   546.5mV    599.1mV    571.4mV
1.184ns   517.1mV    529.7mV    547.4mV
1.484ns   492.3mV    482.6mV    524.3mV
3.142ns   460.5mV    441.6mV    488.9mV
10ns      450.7mV    431.9mV    479.3mV
[Falling Waveform]
R_fixture = 50.000
V_fixture = 0.000
V_fixture_min = 0.000
V_fixture_max = 0.000
|  time   V(typ)   V(min)   V(max)
0s        521.5mV    495.9mV    534.9mV
356ps     521.3mV    495.5mV    550.1mV
461ps     534mV      495.6mV    256.3mV
590ps     247.3mV    503.9mV    130.7mV
664ps     153.8mV    511.6mV    99.65mV
814ps     82.39mV    250.4mV    64.47mV
884ps     66.33mV    164.4mV    54.59mV
1.124ns   37.63mV    63mV       34.58mV
2.453ns   8.948mV    9.198mV    7.763mV
10ns      21.62uV    -9.741uV   -165.3uV
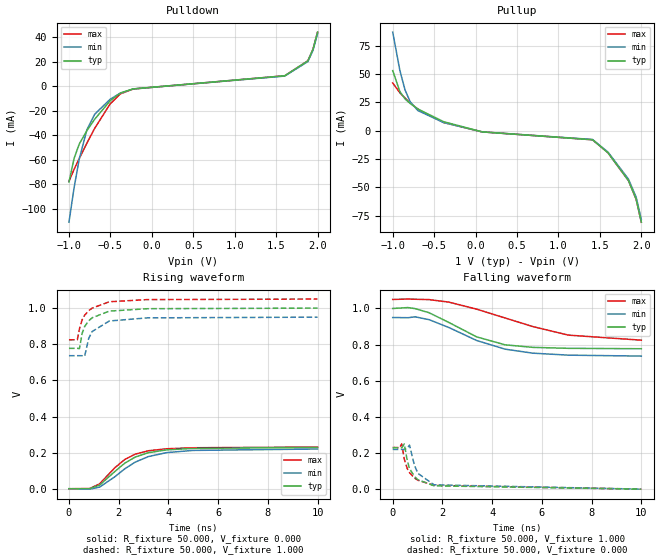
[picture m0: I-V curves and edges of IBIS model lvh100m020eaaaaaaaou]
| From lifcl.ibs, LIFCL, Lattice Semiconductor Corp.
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[Model] lvh100m020eaaaaaaaou
Model_type Output
Polarity   Non-Inverting
Enable   Active-High
Vmeas =  0.500V
Cref =  0.0F
Rref =  1.000M
Vref =  0.0V
C_comp   5.000pF   4.000pF   5.500pF
[Temperature Range]   25.000   0.125k   -40.000
[Voltage Range]   1.000V   0.950V   1.050V
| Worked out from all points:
|   slope of the pulldown table from 0 to 0.15 V, typ, clamps not added: 107 ohm
|   slope of the pullup table from 0 to 0.15 V, typ, clamps not added: 76.2 ohm
|   rising waveform, R_fixture 50.000, V_fixture 0.000: 20-80 % time 1.33ns typ, 1.5ns min, 1.17ns max; typ from 0 V to 0.229 V
|   rising waveform, R_fixture 50.000, V_fixture 1.000: 20-80 % time 550ps typ, 523ps min, 586ps max; typ from 0.777 V to 1 V
|   falling waveform, R_fixture 50.000, V_fixture 1.000: 20-80 % time 1.99ns typ, 2.32ns min, 3.3ns max; typ from 1 V to 0.777 V
|   falling waveform, R_fixture 50.000, V_fixture 0.000: 20-80 % time 532ps typ, 524ps min, 612ps max; typ from 0.229 V to 0 V
[Pulldown]
|Voltage   I(typ)   I(min)   I(max)
-1V       -78.05mA   -110.7mA   -77.47mA
-938mV    -58.82mA   -82.64mA   -67.66mA
-876mV    -47.13mA   -59.37mA   -58.92mA
-783mV    -36.18mA   -35.41mA   -46.31mA
-690mV    -27mA      -22.92mA   -34.43mA
-504mV    -12.02mA   -10.77mA   -14.57mA
-380mV    -5.703mA   -5.676mA   -6.316mA
-225mV    -2.268mA   -2.309mA   -2.379mA
1.604V    8.407mA    8.155mA    8.407mA
1.883V    20.55mA    19.94mA    20.55mA
1.945V    30.02mA    29.12mA    30.02mA
2V        43.93mA    42.62mA    43.93mA
[Pullup]
|Voltage   I(typ)   I(min)   I(max)
-1V       52.89mA    86.84mA    42.03mA
-914mV    34.47mA    53.16mA    33.37mA
-852mV    27.99mA    36.01mA    28.73mA
-790mV    23.94mA    25.53mA    24.5mA
-697mV    19.11mA    17.71mA    18.94mA
-387mV    7.895mA    7.11mA     7.164mA
78mV      -1.11mA    -1.077mA   -1.11mA
1.411V    -8.064mA   -7.822mA   -8.064mA
1.597V    -19.45mA   -18.87mA   -19.45mA
1.845V    -44.07mA   -42.75mA   -44.07mA
1.938V    -60.54mA   -58.72mA   -60.54mA
2V        -80.71mA   -78.29mA   -80.71mA
[Ramp]
| variable   typ   min   max
dV/dt_r   0.137/1.333n   0.132/1.513n   0.138/1.189n
dV/dt_f   0.134/2.036n   0.128/2.409n   0.135/3.308n
R_load = 50.000
[Rising Waveform]
R_fixture = 50.000
V_fixture = 0.000
V_fixture_min = 0.000
V_fixture_max = 0.000
|  time   V(typ)   V(min)   V(max)
0s        313.9uV    429.3uV    431.7uV
834ps     482.6uV    -2.043mV   1.482mV
1.232ns   20.21mV    9.402mV    27.31mV
1.852ns   96.48mV    67.18mV    117.4mV
2.244ns   141.8mV    110.5mV    162.1mV
2.662ns   175.4mV    147.4mV    191.4mV
3.189ns   199.7mV    178.1mV    210.4mV
3.933ns   215.4mV    200.4mV    221.5mV
4.991ns   223.5mV    212.4mV    227.1mV
10ns      229.1mV    220.3mV    231.1mV
[Rising Waveform]
R_fixture = 50.000
V_fixture = 1.000
V_fixture_min = 0.950
V_fixture_max = 1.050
|  time   V(typ)   V(min)   V(max)
0s        777.2mV    736.5mV    824.6mV
336ps     777.5mV    736.7mV    824.8mV
422ps     775.7mV    736.6mV    885.1mV
530ps     860.2mV    736.4mV    935.6mV
632ps     898.3mV    734.1mV    960.6mV
795ps     929.8mV    832.8mV    985.8mV
934ps     946.6mV    870.5mV    1V
1.622ns   983.3mV    928.6mV    1.035V
3.153ns   996.6mV    945.9mV    1.047V
10ns      999.9mV    949.9mV    1.05V
[Falling Waveform]
R_fixture = 50.000
V_fixture = 1.000
V_fixture_min = 0.950
V_fixture_max = 1.050
|  time   V(typ)   V(min)   V(max)
0s        999.9mV    949.9mV    1.05V
613ps     1.005V     948.9mV    1.052V
904ps     999mV      953.7mV    1.051V
1.464ns   976.4mV    938mV      1.049V
2.261ns   922.3mV    894.5mV    1.035V
3.377ns   842.8mV    822.8mV    996.1mV
4.519ns   798.9mV    774.9mV    947.4mV
5.641ns   784.7mV    752.6mV    899.6mV
7.067ns   779.5mV    741.7mV    852.5mV
10ns      777.2mV    736.5mV    824.6mV
[Falling Waveform]
R_fixture = 50.000
V_fixture = 0.000
V_fixture_min = 0.000
V_fixture_max = 0.000
|  time   V(typ)   V(min)   V(max)
0s        229.1mV    220.3mV    231.1mV
283ps     229mV      219.9mV    230.7mV
362ps     229.1mV    219.9mV    250.7mV
466ps     250.3mV    220mV      166.8mV
586ps     157.4mV    227mV      114mV
676ps     114.9mV    243.8mV    91.78mV
874ps     70.61mV    132.2mV    62.15mV
1.013ns   52.83mV    87.81mV    49.51mV
1.664ns   18.83mV    24.26mV    21.43mV
10ns      313.9uV    429.3uV    431.7uV
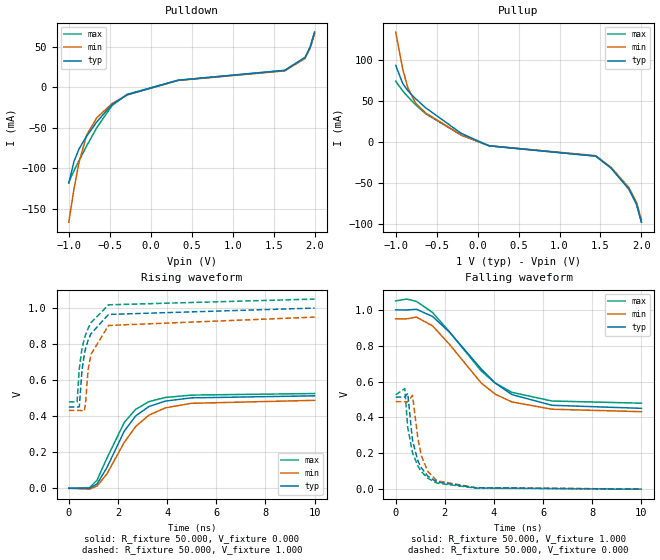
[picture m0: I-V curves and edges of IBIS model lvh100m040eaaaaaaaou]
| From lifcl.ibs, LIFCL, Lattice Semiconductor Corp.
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[Model] lvh100m040eaaaaaaaou
Model_type Output
Polarity   Non-Inverting
Enable   Active-High
Vmeas =  0.500V
Cref =  0.0F
Rref =  1.000M
Vref =  0.0V
C_comp   5.000pF   4.000pF   5.500pF
[Temperature Range]   25.000   0.125k   -40.000
[Voltage Range]   1.000V   0.950V   1.050V
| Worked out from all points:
|   slope of the pulldown table from 0 to 0.15 V, typ, clamps not added: 34.6 ohm
|   slope of the pullup table from 0 to 0.15 V, typ, clamps not added: 30.4 ohm
|   rising waveform, R_fixture 50.000, V_fixture 0.000: 20-80 % time 1.28ns typ, 1.47ns min, 1.22ns max; typ from 0 V to 0.513 V
|   rising waveform, R_fixture 50.000, V_fixture 1.000: 20-80 % time 550ps typ, 509ps min, 584ps max; typ from 0.451 V to 1 V
|   falling waveform, R_fixture 50.000, V_fixture 1.000: 20-80 % time 2.25ns typ, 2.03ns min, 2.19ns max; typ from 1 V to 0.451 V
|   falling waveform, R_fixture 50.000, V_fixture 0.000: 20-80 % time 544ps typ, 498ps min, 565ps max; typ from 0.513 V to 0 V
[Pulldown]
|Voltage   I(typ)   I(min)   I(max)
-1V       -118.4mA   -166.7mA   -117mA
-938mV    -92.07mA   -126.1mA   -103.2mA
-876mV    -76.13mA   -92.99mA   -90.66mA
-783mV    -60.46mA   -59.19mA   -72.49mA
-659mV    -42.67mA   -37.52mA   -49.88mA
-473mV    -21.27mA   -20.11mA   -22.48mA
-287mV    -9.194mA   -9.165mA   -8.478mA
333mV     8.82mA     8.556mA    8.82mA
1.635V    21.06mA    20.43mA    21.06mA
1.883V    36.89mA    35.78mA    36.89mA
1.945V    49.53mA    48.04mA    49.53mA
2V        68.4mA     66.35mA    68.4mA
[Pullup]
|Voltage   I(typ)   I(min)   I(max)
-1V       93.11mA    133.6mA    73.95mA
-914mV    71.08mA    88.51mA    62.13mA
-852mV    62.37mA    66mA       55.11mA
-759mV    52.81mA    47.45mA    45.45mA
-635mV    41.68mA    35.34mA    34.45mA
-201mV    10.63mA    8.725mA    8.452mA
140mV     -4.601mA   -4.463mA   -4.601mA
1.442V    -17.12mA   -16.61mA   -17.12mA
1.628V    -31.55mA   -30.6mA    -31.55mA
1.845V    -56.85mA   -55.15mA   -56.85mA
1.938V    -75.02mA   -72.77mA   -75.02mA
2V        -97.38mA   -94.46mA   -97.38mA
[Ramp]
| variable   typ   min   max
dV/dt_r   0.297/1.289n   0.293/1.487n   0.316/1.225n
dV/dt_f   0.329/2.344n   0.311/2.071n   0.342/2.247n
R_load = 50.000
[Rising Waveform]
R_fixture = 50.000
V_fixture = 0.000
V_fixture_min = 0.000
V_fixture_max = 0.000
|  time   V(typ)   V(min)   V(max)
0s        21.62uV    -12.77uV   -165.3uV
837ps     -114uV     -4.93mV    2.38mV
1.147ns   23.69mV    12.45mV    44.63mV
1.548ns   114.4mV    79.3mV     166.7mV
2.258ns   317.6mV    255.5mV    365.7mV
2.721ns   401.6mV    343.1mV    438.2mV
3.261ns   453.9mV    406mV      480.8mV
3.93ns    483.9mV    446.2mV    503.9mV
4.981ns   501.7mV    471.5mV    517.1mV
10ns      513.1mV    488mV      525.9mV
[Rising Waveform]
R_fixture = 50.000
V_fixture = 1.000
V_fixture_min = 0.950
V_fixture_max = 1.050
|  time   V(typ)   V(min)   V(max)
0s        450.7mV    431.9mV    479.3mV
336ps     451.1mV    432.1mV    478.9mV
427ps     451.9mV    432.1mV    665.3mV
534ps     650.5mV    431.2mV    772.9mV
630ps     743.5mV    428.7mV    828.7mV
681ps     774.4mV    471.4mV    851.2mV
781ps     819.3mV    654.9mV    886.4mV
901ps     857.4mV    743.1mV    918.9mV
1.615ns   964.7mV    903.6mV    1.018V
10ns      999.9mV    949.8mV    1.05V
[Falling Waveform]
R_fixture = 50.000
V_fixture = 1.000
V_fixture_min = 0.950
V_fixture_max = 1.050
|  time   V(typ)   V(min)   V(max)
0s        999.9mV    949.8mV    1.05V
449ps     999.2mV    949.8mV    1.06V
844ps     1.003V     959.4mV    1.047V
1.501ns   962.9mV    910.3mV    985.2mV
2.2ns     873.8mV    805.7mV    875mV
3.481ns   669.8mV    591.2mV    658.9mV
4.051ns   591.5mV    529.7mV    591.1mV
4.73ns    527.2mV    486mV      539.6mV
6.36ns    467.6mV    445.7mV    491.5mV
10ns      450.7mV    431.9mV    479.3mV
[Falling Waveform]
R_fixture = 50.000
V_fixture = 0.000
V_fixture_min = 0.000
V_fixture_max = 0.000
|  time   V(typ)   V(min)   V(max)
0s        513.1mV    488mV      525.9mV
369ps     513.9mV    487.5mV    560.9mV
490ps     534.2mV    487.1mV    343.8mV
684ps     271.2mV    523mV      202.8mV
904ps     157mV      282.8mV    128.4mV
1.041ns   119.2mV    187.5mV    98.46mV
1.304ns   72.85mV    99.3mV     61.22mV
1.671ns   40.18mV    46.85mV    34.01mV
3.251ns   7.631mV    7.987mV    5.786mV
10ns      21.62uV    -12.77uV   -165.3uV
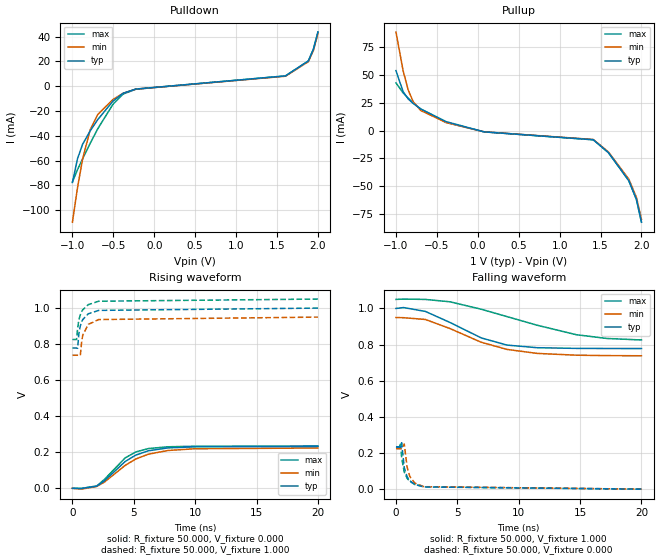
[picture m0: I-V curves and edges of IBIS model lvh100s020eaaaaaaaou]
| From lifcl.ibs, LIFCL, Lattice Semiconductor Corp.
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[Model] lvh100s020eaaaaaaaou
Model_type Output
Polarity   Non-Inverting
Enable   Active-High
Vmeas =  0.500V
Cref =  0.0F
Rref =  1.000M
Vref =  0.0V
C_comp   5.000pF   4.000pF   5.500pF
[Temperature Range]   25.000   0.125k   -40.000
[Voltage Range]   1.000V   0.950V   1.050V
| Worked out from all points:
|   slope of the pulldown table from 0 to 0.15 V, typ, clamps not added: 107 ohm
|   slope of the pullup table from 0 to 0.15 V, typ, clamps not added: 74.9 ohm
|   rising waveform, R_fixture 50.000, V_fixture 0.000: 20-80 % time 2.54ns typ, 2.91ns min, 2.16ns max; typ from 0 V to 0.233 V
|   rising waveform, R_fixture 50.000, V_fixture 1.000: 20-80 % time 573ps typ, 548ps min, 613ps max; typ from 0.778 V to 1 V
|   falling waveform, R_fixture 50.000, V_fixture 1.000: 20-80 % time 4.1ns typ, 4.79ns min, 7.13ns max; typ from 1 V to 0.778 V
|   falling waveform, R_fixture 50.000, V_fixture 0.000: 20-80 % time 570ps typ, 561ps min, 616ps max; typ from 0.233 V to 0 V
[Pulldown]
|Voltage   I(typ)   I(min)   I(max)
-1V       -77.67mA   -109.7mA   -77.1mA
-938mV    -58.53mA   -81.92mA   -67.33mA
-876mV    -46.89mA   -58.86mA   -58.63mA
-783mV    -36mA      -35.1mA    -46.09mA
-690mV    -26.86mA   -22.73mA   -34.26mA
-504mV    -11.96mA   -10.67mA   -14.5mA
-380mV    -5.675mA   -5.626mA   -6.286mA
-225mV    -2.256mA   -2.289mA   -2.368mA
1.604V    8.365mA    8.114mA    8.365mA
1.883V    20.45mA    19.84mA    20.45mA
1.945V    29.87mA    28.98mA    29.87mA
2V        43.72mA    42.41mA    43.72mA
[Pullup]
|Voltage   I(typ)   I(min)   I(max)
-1V       53.82mA    88.35mA    42.77mA
-914mV    35.07mA    54.09mA    33.96mA
-852mV    28.48mA    36.64mA    29.23mA
-790mV    24.35mA    25.97mA    24.93mA
-697mV    19.44mA    18.02mA    19.27mA
-387mV    8.033mA    7.234mA    7.289mA
78mV      -1.129mA   -1.095mA   -1.129mA
1.411V    -8.204mA   -7.958mA   -8.204mA
1.597V    -19.79mA   -19.2mA    -19.79mA
1.845V    -44.84mA   -43.5mA    -44.84mA
1.938V    -61.59mA   -59.75mA   -61.59mA
2V        -82.12mA   -79.65mA   -82.12mA
[Ramp]
| variable   typ   min   max
dV/dt_r   0.140/2.514n   0.132/2.889n   0.146/2.208n
dV/dt_f   0.133/4.122n   0.128/4.816n   0.135/7.146n
R_load = 50.000
[Rising Waveform]
R_fixture = 50.000
V_fixture = 0.000
V_fixture_min = 0.000
V_fixture_max = 0.000
|  time   V(typ)   V(min)   V(max)
0s        323.7uV    438.3uV    441.7uV
725ps     -600.6uV   -4.409mV   -239uV
1.979ns   12.1mV     10.56mV    13.38mV
2.6ns     41.7mV     34.31mV    49.27mV
4.301ns   149.2mV    127.8mV    169.1mV
5.159ns   184.5mV    162.9mV    201.9mV
6.191ns   208.6mV    189.7mV    220.9mV
7.787ns   224.4mV    210.1mV    230.7mV
9.95ns    230.5mV    219.7mV    233.6mV
20ns      232.9mV    223.9mV    235mV
[Rising Waveform]
R_fixture = 50.000
V_fixture = 1.000
V_fixture_min = 0.950
V_fixture_max = 1.050
|  time   V(typ)   V(min)   V(max)
0s        778.3mV    738.3mV    825.6mV
336ps     778.6mV    738.4mV    825.9mV
422ps     776.7mV    738.4mV    885.8mV
523ps     856.8mV    738.2mV    933.9mV
640ps     900.9mV    736.8mV    962.5mV
761ps     925mV      816.8mV    981.5mV
841ps     936.1mV    849.7mV    990.7mV
1.29ns    968.2mV    909.6mV    1.019V
2.143ns   987.2mV    936.4mV    1.038V
20ns      999.9mV    949.9mV    1.05V
[Falling Waveform]
R_fixture = 50.000
V_fixture = 1.000
V_fixture_min = 0.950
V_fixture_max = 1.050
|  time   V(typ)   V(min)   V(max)
0s        999.9mV    949.9mV    1.05V
613ps     1.005V     948.9mV    1.052V
2.39ns    983.8mV    939.2mV    1.05V
4.39ns    922.8mV    889.1mV    1.037V
6.945ns   837mV      813.1mV    995.8mV
9.049ns   797.4mV    773.4mV    954.9mV
11.51ns   782.9mV    751.3mV    907.1mV
14.7ns    779.1mV    741.5mV    854.7mV
17.19ns   778.5mV    739.2mV    834mV
20ns      778.3mV    738.3mV    825.6mV
[Falling Waveform]
R_fixture = 50.000
V_fixture = 0.000
V_fixture_min = 0.000
V_fixture_max = 0.000
|  time   V(typ)   V(min)   V(max)
0s        232.9mV    223.9mV    235mV
283ps     232.8mV    223.6mV    234.6mV
369ps     233.6mV    223.5mV    255.8mV
461ps     257.1mV    223.7mV    174.7mV
673ps     118.9mV    250.3mV    94.67mV
903ps     69.18mV    123.8mV    60.59mV
1.123ns   46.96mV    70.96mV    43.27mV
1.534ns   26.75mV    34.02mV    26.32mV
2.274ns   12.63mV    14.08mV    13.31mV
20ns      323.7uV    438.3uV    441.7uV
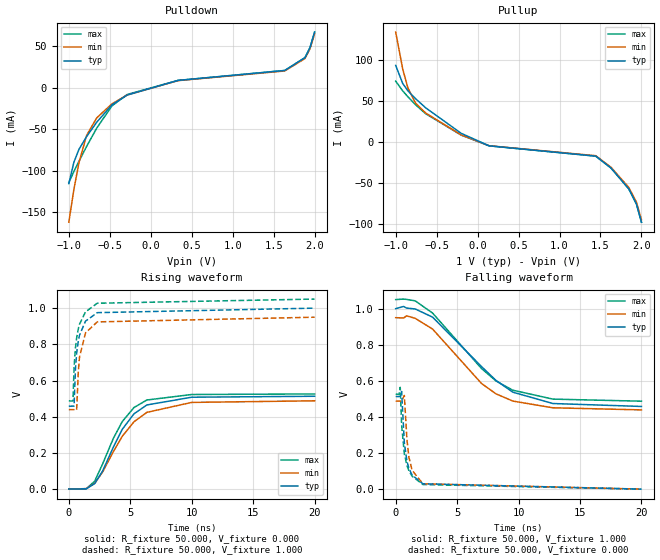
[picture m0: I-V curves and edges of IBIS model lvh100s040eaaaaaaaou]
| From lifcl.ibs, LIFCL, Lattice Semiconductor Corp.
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[Model] lvh100s040eaaaaaaaou
Model_type Output
Polarity   Non-Inverting
Enable   Active-High
Vmeas =  0.500V
Cref =  0.0F
Rref =  1.000M
Vref =  0.0V
C_comp   5.000pF   4.000pF   5.500pF
[Temperature Range]   25.000   0.125k   -40.000
[Voltage Range]   1.000V   0.950V   1.050V
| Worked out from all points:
|   slope of the pulldown table from 0 to 0.15 V, typ, clamps not added: 35.4 ohm
|   slope of the pullup table from 0 to 0.15 V, typ, clamps not added: 30.4 ohm
|   rising waveform, R_fixture 50.000, V_fixture 0.000: 20-80 % time 2.46ns typ, 2.83ns min, 2.32ns max; typ from 0 V to 0.513 V
|   rising waveform, R_fixture 50.000, V_fixture 1.000: 20-80 % time 572ps typ, 545ps min, 614ps max; typ from 0.458 V to 1 V
|   falling waveform, R_fixture 50.000, V_fixture 1.000: 20-80 % time 4.79ns typ, 4.26ns min, 4.61ns max; typ from 1 V to 0.458 V
|   falling waveform, R_fixture 50.000, V_fixture 0.000: 20-80 % time 570ps typ, 558ps min, 612ps max; typ from 0.513 V to 0 V
[Pulldown]
|Voltage   I(typ)   I(min)   I(max)
-1V       -115.6mA   -162mA     -114.4mA
-938mV    -89.86mA   -122.5mA   -100.9mA
-876mV    -74.31mA   -90.37mA   -88.63mA
-783mV    -59mA      -57.52mA   -70.87mA
-659mV    -41.64mA   -36.46mA   -48.76mA
-473mV    -20.76mA   -19.54mA   -21.98mA
-287mV    -8.973mA   -8.905mA   -8.289mA
333mV     8.608mA    8.35mA     8.608mA
1.635V    20.55mA    19.94mA    20.55mA
1.883V    36mA       34.92mA    36mA
1.945V    48.34mA    46.89mA    48.34mA
2V        66.76mA    64.75mA    66.76mA
[Pullup]
|Voltage   I(typ)   I(min)   I(max)
-1V       93.11mA    133.6mA    73.95mA
-914mV    71.08mA    88.51mA    62.13mA
-852mV    62.37mA    66mA       55.11mA
-759mV    52.81mA    47.45mA    45.45mA
-635mV    41.68mA    35.34mA    34.45mA
-201mV    10.63mA    8.725mA    8.452mA
140mV     -4.601mA   -4.463mA   -4.601mA
1.442V    -17.12mA   -16.61mA   -17.12mA
1.628V    -31.55mA   -30.6mA    -31.55mA
1.845V    -56.85mA   -55.15mA   -56.85mA
1.938V    -75.02mA   -72.77mA   -75.02mA
2V        -97.38mA   -94.46mA   -97.38mA
[Ramp]
| variable   typ   min   max
dV/dt_r   0.298/2.439n   0.293/2.812n   0.316/2.332n
dV/dt_f   0.324/4.811n   0.306/4.274n   0.338/4.620n
R_load = 50.000
[Rising Waveform]
R_fixture = 50.000
V_fixture = 0.000
V_fixture_min = 0.000
V_fixture_max = 0.000
|  time   V(typ)   V(min)   V(max)
0s        21.02uV    -25.79uV   -157.9uV
1.426ns   2.07mV     2.812mV    2.601mV
2.105ns   30.6mV     32.08mV    43.92mV
2.744ns   99.44mV    94.07mV    138.1mV
3.624ns   231.9mV    207mV      280.5mV
4.351ns   330.5mV    292.1mV    373.3mV
5.3ns     415.8mV    372mV      450.7mV
6.35ns    465mV      424.1mV    492.4mV
9.999ns   507.8mV    479.1mV    522.7mV
20ns      513.1mV    488mV      525.9mV
[Rising Waveform]
R_fixture = 50.000
V_fixture = 1.000
V_fixture_min = 0.950
V_fixture_max = 1.050
|  time   V(typ)   V(min)   V(max)
0s        458.1mV    439mV      487.2mV
336ps     458.5mV    439.1mV    486.8mV
426ps     458.9mV    439.1mV    669mV
538ps     660.8mV    438.1mV    779.6mV
636ps     751.3mV    437.4mV    834.6mV
775ps     819.7mV    652.2mV    886.2mV
868ps     849.8mV    728.2mV    910.6mV
1.358ns   928mV      863.1mV    979.2mV
2.315ns   974.9mV    923.9mV    1.027V
20ns      999.9mV    949.8mV    1.05V
[Falling Waveform]
R_fixture = 50.000
V_fixture = 1.000
V_fixture_min = 0.950
V_fixture_max = 1.050
|  time   V(typ)   V(min)   V(max)
0s        999.9mV    949.8mV    1.05V
643ps     1.012V     948.5mV    1.053V
894ps     1.003V     960mV      1.051V
1.591ns   998.1mV    946.1mV    1.043V
3.003ns   952.8mV    886.8mV    975.3mV
6.985ns   679mV      585.3mV    668.2mV
8.166ns   601.9mV    527.8mV    599mV
9.535ns   537.1mV    487.9mV    548mV
12.79ns   474.3mV    450.7mV    498.7mV
20ns      458.1mV    439mV      487.2mV
[Falling Waveform]
R_fixture = 50.000
V_fixture = 0.000
V_fixture_min = 0.000
V_fixture_max = 0.000
|  time   V(typ)   V(min)   V(max)
0s        513.1mV    488mV      525.9mV
283ps     513mV      487.7mV    525.3mV
370ps     514mV      487.5mV    564mV
482ps     541.2mV    487.2mV    356.7mV
704ps     256.5mV    518.9mV    195.7mV
914ps     155.3mV    276.6mV    131.4mV
1.072ns   115.9mV    178.3mV    102.5mV
1.334ns   78.05mV    104.8mV    71.6mV
2.214ns   29.68mV    29.77mV    25.36mV
20ns      21.02uV    -25.79uV   -157.9uV
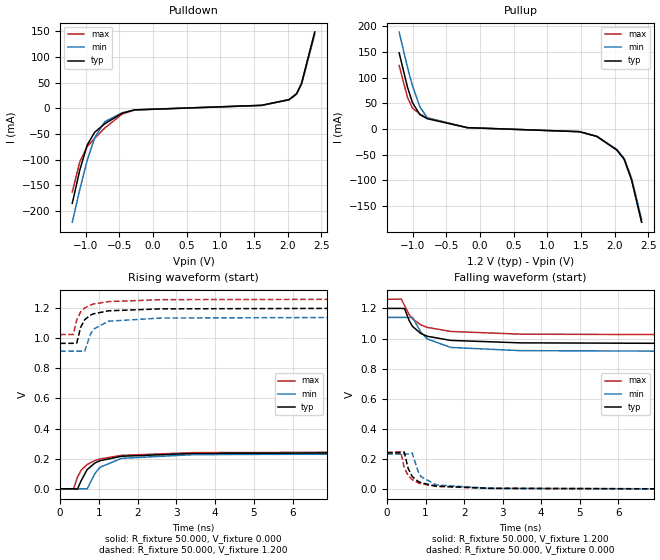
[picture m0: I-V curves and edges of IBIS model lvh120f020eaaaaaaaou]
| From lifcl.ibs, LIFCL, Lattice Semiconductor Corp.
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[Model] lvh120f020eaaaaaaaou
Model_type Output
Polarity   Non-Inverting
Enable   Active-High
Vmeas =  0.600V
Cref =  0.0F
Rref =  1.000M
Vref =  0.0V
C_comp   5.000pF   4.000pF   5.500pF
[Temperature Range]   25.000   0.125k   -40.000
[Voltage Range]   1.200V   1.140V   1.260V
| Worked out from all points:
|   slope of the pulldown table from 0 to 0.18 V, typ, clamps not added: 107 ohm
|   slope of the pullup table from 0 to 0.18 V, typ, clamps not added: 92.2 ohm
|   rising waveform, R_fixture 50.000, V_fixture 0.000: 20-80 % time 558ps typ, 540ps min, 580ps max; typ from 0 V to 0.24 V
|   rising waveform, R_fixture 50.000, V_fixture 1.200: 20-80 % time 310ps typ, 328ps min, 324ps max; typ from 0.966 V to 1.2 V
|   falling waveform, R_fixture 50.000, V_fixture 1.200: 20-80 % time 553ps typ, 574ps min, 612ps max; typ from 1.2 V to 0.966 V
|   falling waveform, R_fixture 50.000, V_fixture 0.000: 20-80 % time 332ps typ, 335ps min, 346ps max; typ from 0.241 V to 0 V
[Pulldown]
|Voltage   I(typ)   I(min)   I(max)
-1.2V     -185.3mA   -222.1mA   -163.3mA
-1.089V   -120.6mA   -158.4mA   -104.5mA
-978mV    -71.42mA   -101.4mA   -74.7mA
-867mV    -46.58mA   -57.11mA   -58.45mA
-719mV    -30.22mA   -26.19mA   -38.55mA
-460mV    -9.51mA    -8.803mA   -11.2mA
-275mV    -3.015mA   -3.114mA   -3.102mA
1.612V    5.843mA    5.667mA    5.843mA
2.019V    17.03mA    16.52mA    17.03mA
2.13V     28.43mA    27.57mA    28.43mA
2.204V    48.5mA     47.04mA    48.5mA
2.4V      148.7mA    144.2mA    148.7mA
[Pullup]
|Voltage   I(typ)   I(min)   I(max)
-1.2V     147.9mA    188.3mA    123.4mA
-1.078V   81.98mA    120.7mA    61.86mA
-1.004V   51.59mA    84.61mA    40.82mA
-893mV    27.85mA    43mA       29.06mA
-782mV    19.86mA    21.61mA    21.61mA
-190mV    2.572mA    2.372mA    2.456mA
1.475V    -5.352mA   -5.192mA   -5.352mA
1.734V    -14.51mA   -14.08mA   -14.51mA
2.03V     -40.75mA   -39.53mA   -40.75mA
2.141V    -58.9mA    -57.14mA   -58.9mA
2.252V    -99.4mA    -96.4mA    -99.4mA
2.4V      -181.3mA   -175.9mA   -181.3mA
[Ramp]
| variable   typ   min   max
dV/dt_r   0.146/0.561n   0.140/0.547n   0.147/0.579n
dV/dt_f   0.140/0.556n   0.135/0.571n   0.141/0.621n
R_load = 50.000
[Rising Waveform]
R_fixture = 50.000
V_fixture = 0.000
V_fixture_min = 0.000
V_fixture_max = 0.000
|  time   V(typ)   V(min)   V(max)
0s        7.053uV    59.47uV    264.8uV
346ps     204.4uV    173uV      -1.653mV
445ps     -2.583mV   109.9uV    76.66mV
543ps     54.17mV    291.4uV    123.8mV
694ps     126.9mV    -1.377mV   160.8mV
895ps     170.9mV    100.4mV    187.6mV
1.024ns   186.2mV    142.5mV    198.3mV
1.584ns   215.9mV    202.2mV    222mV
3.44ns    234.7mV    226.8mV    240mV
10ns      240.3mV    233.2mV    244.8mV
[Rising Waveform]
R_fixture = 50.000
V_fixture = 1.200
V_fixture_min = 1.140
V_fixture_max = 1.260
|  time   V(typ)   V(min)   V(max)
0s        965.8mV    913.8mV    1.024V
338ps     966mV      914mV      1.025V
427ps     966.9mV    913.9mV    1.121V
528ps     1.072V     913.6mV    1.175V
634ps     1.123V     913.7mV    1.201V
775ps     1.152V     1.022V     1.22V
858ps     1.162V     1.06V      1.227V
1.245ns   1.182V     1.113V     1.243V
2.601ns   1.195V     1.134V     1.256V
10ns      1.2V       1.14V      1.26V
[Falling Waveform]
R_fixture = 50.000
V_fixture = 1.200
V_fixture_min = 1.140
V_fixture_max = 1.260
|  time   V(typ)   V(min)   V(max)
0s        1.2V       1.14V      1.26V
370ps     1.2V       1.14V      1.262V
454ps     1.199V     1.14V      1.219V
574ps     1.119V     1.139V     1.159V
663ps     1.08V      1.14V      1.131V
873ps     1.034V     1.044V     1.091V
1.043ns   1.015V     997.1mV    1.074V
1.655ns   987.5mV    940.7mV    1.047V
3.459ns   971.3mV    919.6mV    1.029V
10ns      965.8mV    913.8mV    1.024V
[Falling Waveform]
R_fixture = 50.000
V_fixture = 0.000
V_fixture_min = 0.000
V_fixture_max = 0.000
|  time   V(typ)   V(min)   V(max)
0s        241mV      233.2mV    244.8mV
356ps     240.8mV    232.9mV    248.4mV
446ps     246.3mV    233.1mV    143.3mV
548ps     137.3mV    233.6mV    90mV
653ps     83.97mV    239.9mV    63.37mV
803ps     52.07mV    120.6mV    42.75mV
883ps     42.41mV    82.98mV    35.88mV
1.278ns   20.31mV    28mV       18.65mV
2.673ns   5.757mV    5.647mV    4.719mV
10ns      464uV      59.47uV    264.8uV
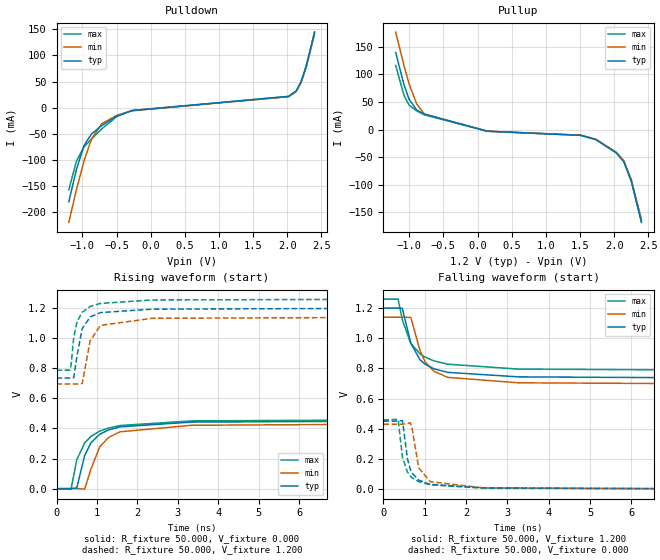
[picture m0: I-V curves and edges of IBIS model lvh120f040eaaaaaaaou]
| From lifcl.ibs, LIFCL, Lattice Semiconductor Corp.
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[Model] lvh120f040eaaaaaaaou
Model_type Output
Polarity   Non-Inverting
Enable   Active-High
Vmeas =  0.600V
Cref =  0.0F
Rref =  1.000M
Vref =  0.0V
C_comp   5.000pF   4.000pF   5.500pF
[Temperature Range]   25.000   0.125k   -40.000
[Voltage Range]   1.200V   1.140V   1.260V
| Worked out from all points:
|   slope of the pulldown table from 0 to 0.18 V, typ, clamps not added: 51.8 ohm
|   slope of the pullup table from 0 to 0.18 V, typ, clamps not added: 47.9 ohm
|   rising waveform, R_fixture 50.000, V_fixture 0.000: 20-80 % time 490ps typ, 501ps min, 533ps max; typ from 0 V to 0.451 V
|   rising waveform, R_fixture 50.000, V_fixture 1.200: 20-80 % time 229ps typ, 250ps min, 235ps max; typ from 0.735 V to 1.2 V
|   falling waveform, R_fixture 50.000, V_fixture 1.200: 20-80 % time 467ps typ, 449ps min, 541ps max; typ from 1.2 V to 0.735 V
|   falling waveform, R_fixture 50.000, V_fixture 0.000: 20-80 % time 221ps typ, 234ps min, 242ps max; typ from 0.451 V to 0 V
[Pulldown]
|Voltage   I(typ)   I(min)   I(max)
-1.2V     -180.2mA   -219.5mA   -157.6mA
-1.089V   -118.7mA   -157.5mA   -102.6mA
-978mV    -72.85mA   -102.3mA   -75.46mA
-867mV    -50.28mA   -60.01mA   -59.99mA
-719mV    -34.47mA   -30.88mA   -40.86mA
-497mV    -15.93mA   -14.83mA   -17.14mA
-275mV    -5.882mA   -5.851mA   -5.411mA
2.019V    21.52mA    20.87mA    21.52mA
2.13V     31.72mA    30.77mA    31.72mA
2.204V    49.93mA    48.43mA    49.93mA
2.278V    79.85mA    77.46mA    79.85mA
2.4V      144.7mA    140.4mA    144.7mA
[Pullup]
|Voltage   I(typ)   I(min)   I(max)
-1.2V     139.7mA    176.6mA    116.1mA
-1.078V   80.9mA     115.4mA    61.64mA
-1.004V   54.85mA    83mA       44.23mA
-893mV    35.47mA    46.56mA    33.97mA
-782mV    27.9mA     28.22mA    26.69mA
143mV     -3.072mA   -2.98mA    -3.072mA
1.512V    -10.52mA   -10.21mA   -10.52mA
1.734V    -18.28mA   -17.73mA   -18.28mA
2.03V     -42.1mA    -40.84mA   -42.1mA
2.141V    -57.94mA   -56.2mA    -57.94mA
2.252V    -93.7mA    -90.9mA    -93.7mA
2.4V      -167.9mA   -162.9mA   -167.9mA
[Ramp]
| variable   typ   min   max
dV/dt_r   0.271/0.491n   0.259/0.509n   0.275/0.541n
dV/dt_f   0.279/0.468n   0.267/0.448n   0.284/0.541n
R_load = 50.000
[Rising Waveform]
R_fixture = 50.000
V_fixture = 0.000
V_fixture_min = 0.000
V_fixture_max = 0.000
|  time   V(typ)   V(min)   V(max)
0s        32.99uV    -16.93uV   -211.7uV
359ps     414.7uV    36.68uV    -3.713mV
500ps     3.858mV    143.2uV    191.2mV
695ps     219mV      -3.576mV   303.5mV
855ps     305.9mV    132mV      347.9mV
1.07ns    361.6mV    278.4mV    382.4mV
1.281ns   389.8mV    339.2mV    402.4mV
1.571ns   410.6mV    377.7mV    419.3mV
3.343ns   442.1mV    420.9mV    450.2mV
10ns      451mV      431mV      458.5mV
[Rising Waveform]
R_fixture = 50.000
V_fixture = 1.200
V_fixture_min = 1.140
V_fixture_max = 1.260
|  time   V(typ)   V(min)   V(max)
0s        734.7mV    695.7mV    786.6mV
336ps     734.9mV    695.9mV    788.1mV
359ps     734.2mV    695.8mV    819mV
426ps     738.8mV    695.9mV    1.007V
509ps     888mV      695.6mV    1.111V
635ps     1.064V     698.2mV    1.172V
832ps     1.141V     982.5mV    1.211V
1.085ns   1.17V      1.085V     1.231V
2.365ns   1.193V     1.132V     1.254V
10ns      1.2V       1.14V      1.26V
[Falling Waveform]
R_fixture = 50.000
V_fixture = 1.200
V_fixture_min = 1.140
V_fixture_max = 1.260
|  time   V(typ)   V(min)   V(max)
0s        1.2V       1.14V      1.26V
356ps     1.2V       1.14V      1.26V
457ps     1.199V     1.14V      1.123V
663ps     967.7mV    1.138V     965.4mV
883ps     858.5mV    921.4mV    897.4mV
1.007ns   828.6mV    844mV      875.3mV
1.223ns   797.6mV    781.5mV    850.2mV
1.557ns   774mV      740.7mV    828.3mV
3.271ns   744.2mV    704.9mV    795.7mV
10ns      734.7mV    695.7mV    786.6mV
[Falling Waveform]
R_fixture = 50.000
V_fixture = 0.000
V_fixture_min = 0.000
V_fixture_max = 0.000
|  time   V(typ)   V(min)   V(max)
0s        451mV      431mV      458.5mV
356ps     450.9mV    430.8mV    463mV
461ps     454.4mV    430.8mV    210.8mV
581ps     202.9mV    434.7mV    113.6mV
653ps     128.7mV    440.6mV    86.86mV
693ps     106.4mV    403mV      76.18mV
854ps     59.94mV    141.8mV    49.25mV
1.133ns   31mV       49.19mV    28.8mV
2.433ns   7.791mV    7.893mV    6.673mV
10ns      32.99uV    -16.93uV   -211.7uV
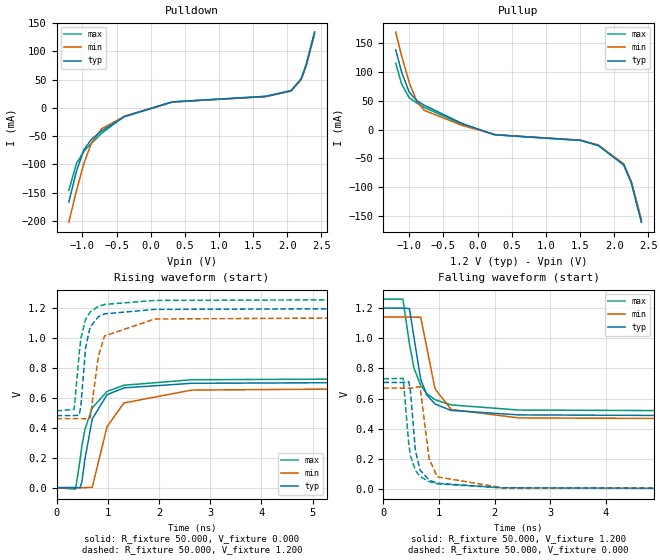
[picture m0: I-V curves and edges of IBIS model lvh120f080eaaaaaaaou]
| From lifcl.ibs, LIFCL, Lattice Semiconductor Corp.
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[Model] lvh120f080eaaaaaaaou
Model_type Output
Polarity   Non-Inverting
Enable   Active-High
Vmeas =  0.600V
Cref =  0.0F
Rref =  1.000M
Vref =  0.0V
C_comp   5.000pF   4.000pF   5.500pF
[Temperature Range]   25.000   0.125k   -40.000
[Voltage Range]   1.200V   1.140V   1.260V
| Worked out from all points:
|   slope of the pulldown table from 0 to 0.18 V, typ, clamps not added: 28.1 ohm
|   slope of the pullup table from 0 to 0.18 V, typ, clamps not added: 26.4 ohm
|   rising waveform, R_fixture 50.000, V_fixture 0.000: 20-80 % time 298ps typ, 418ps min, 351ps max; typ from 0 V to 0.707 V
|   rising waveform, R_fixture 50.000, V_fixture 1.200: 20-80 % time 145ps typ, 201ps min, 165ps max; typ from 0.481 V to 1.2 V
|   falling waveform, R_fixture 50.000, V_fixture 1.200: 20-80 % time 247ps typ, 262ps min, 297ps max; typ from 1.2 V to 0.481 V
|   falling waveform, R_fixture 50.000, V_fixture 0.000: 20-80 % time 137ps typ, 156ps min, 148ps max; typ from 0.707 V to 0 V
[Pulldown]
|Voltage   I(typ)   I(min)   I(max)
-1.2V     -166.9mA   -202.6mA   -146.3mA
-1.089V   -112.5mA   -147.1mA   -98.8mA
-978mV    -73.85mA   -98.2mA    -76.62mA
-867mV    -55.49mA   -61.71mA   -62.62mA
-719mV    -40.9mA    -37.09mA   -45mA
-386mV    -15.77mA   -15.06mA   -14.81mA
317mV     10.59mA    10.27mA    10.59mA
1.686V    20.44mA    19.83mA    20.44mA
2.056V    30.64mA    29.72mA    30.64mA
2.204V    51.44mA    49.9mA     51.44mA
2.278V    76.9mA     74.6mA     76.9mA
2.4V      134.3mA    130.3mA    134.3mA
[Pullup]
|Voltage   I(typ)   I(min)   I(max)
-1.2V     138.9mA    169.7mA    115.5mA
-1.115V   100.8mA    129.1mA    80mA
-1.004V   65.58mA    82.7mA     55.68mA
-893mV    50.42mA    49.87mA    46.37mA
-782mV    42.45mA    33.45mA    38.57mA
-227mV    10.6mA     7.326mA    9.265mA
254mV     -9.081mA   -8.809mA   -9.081mA
1.512V    -18.91mA   -18.34mA   -18.91mA
1.771V    -27.88mA   -27.05mA   -27.88mA
2.141V    -61.54mA   -59.7mA    -61.54mA
2.252V    -92.9mA    -90.1mA    -92.9mA
2.4V      -161.2mA   -156.4mA   -161.2mA
[Ramp]
| variable   typ   min   max
dV/dt_r   0.424/0.301n   0.383/0.422n   0.439/0.351n
dV/dt_f   0.431/0.249n   0.408/0.264n   0.448/0.295n
R_load = 50.000
[Rising Waveform]
R_fixture = 50.000
V_fixture = 0.000
V_fixture_min = 0.000
V_fixture_max = 0.000
|  time   V(typ)   V(min)   V(max)
0s        40.99uV    -223uV     -362.9uV
371ps     692.1uV    -215.5uV   -10.35mV
457ps     -1.61mV    -186.7uV   179.4mV
497ps     43.23mV    -30.8uV    281.6mV
554ps     188.2mV    358.9uV    387.4mV
697ps     457.9mV    1.41mV     532.2mV
987ps     620.8mV    407.4mV    642.6mV
1.317ns   666.6mV    565.8mV    684.1mV
2.64ns    697.2mV    651.7mV    720.8mV
10ns      707.3mV    669.6mV    731.9mV
[Rising Waveform]
R_fixture = 50.000
V_fixture = 1.200
V_fixture_min = 1.140
V_fixture_max = 1.260
|  time   V(typ)   V(min)   V(max)
0s        481.2mV    461.1mV    513mV
345ps     481.3mV    461.1mV    522.6mV
444ps     484.1mV    461.2mV    901.7mV
477ps     552.1mV    461.2mV    998.1mV
567ps     933.7mV    459.5mV    1.125V
657ps     1.074V     466.3mV    1.174V
817ps     1.142V     877.2mV    1.211V
937ps     1.161V     1.013V     1.224V
1.918ns   1.191V     1.127V     1.251V
10ns      1.2V       1.141V     1.26V
[Falling Waveform]
R_fixture = 50.000
V_fixture = 1.200
V_fixture_min = 1.140
V_fixture_max = 1.260
|  time   V(typ)   V(min)   V(max)
0s        1.2V       1.141V     1.26V
351ps     1.2V       1.141V     1.26V
468ps     1.197V     1.141V     964mV
552ps     1.001V     1.14V      800.5mV
671ps     727.8mV    1.139V     688mV
782ps     623.9mV    934.5mV    632.9mV
928ps     564.3mV    664.7mV    593.3mV
1.218ns   521.7mV    528.5mV    558.1mV
2.432ns   492.1mV    472.1mV    524.4mV
10ns      481.2mV    461.1mV    513mV
[Falling Waveform]
R_fixture = 50.000
V_fixture = 0.000
V_fixture_min = 0.000
V_fixture_max = 0.000
|  time   V(typ)   V(min)   V(max)
0s        707.3mV    669.6mV    731.9mV
356ps     707.1mV    669.4mV    733.6mV
457ps     712.9mV    669.5mV    296.8mV
486ps     650.5mV    669.1mV    222.8mV
576ps     254.8mV    673.8mV    123.5mV
660ps     126.3mV    680.1mV    84.45mV
822ps     60.22mV    201.8mV    49.85mV
970ps     38.53mV    81.32mV    35.44mV
2.141ns   8.943mV    8.834mV    8.012mV
10ns      40.99uV    -223uV     -362.9uV
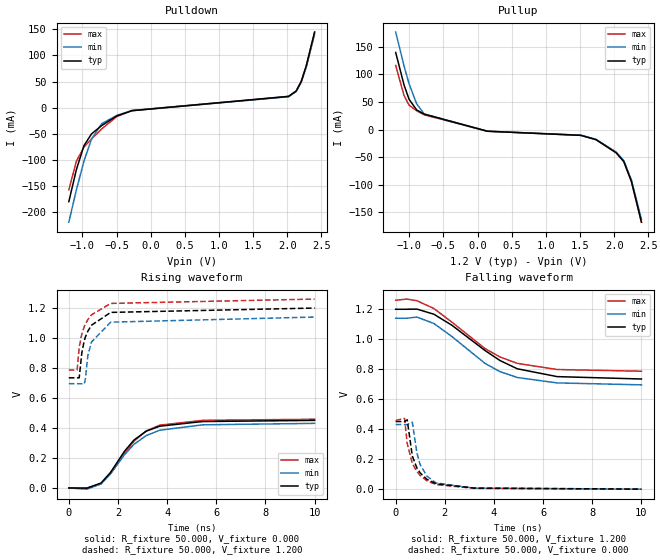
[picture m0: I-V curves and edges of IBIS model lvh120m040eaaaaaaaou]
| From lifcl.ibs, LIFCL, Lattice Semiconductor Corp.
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[Model] lvh120m040eaaaaaaaou
Model_type Output
Polarity   Non-Inverting
Enable   Active-High
Vmeas =  0.600V
Cref =  0.0F
Rref =  1.000M
Vref =  0.0V
C_comp   5.000pF   4.000pF   5.500pF
[Temperature Range]   25.000   0.125k   -40.000
[Voltage Range]   1.200V   1.140V   1.260V
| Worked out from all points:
|   slope of the pulldown table from 0 to 0.18 V, typ, clamps not added: 51.8 ohm
|   slope of the pullup table from 0 to 0.18 V, typ, clamps not added: 47.9 ohm
|   rising waveform, R_fixture 50.000, V_fixture 0.000: 20-80 % time 1.33ns typ, 1.44ns min, 1.34ns max; typ from 0 V to 0.451 V
|   rising waveform, R_fixture 50.000, V_fixture 1.200: 20-80 % time 551ps typ, 511ps min, 599ps max; typ from 0.735 V to 1.2 V
|   falling waveform, R_fixture 50.000, V_fixture 1.200: 20-80 % time 2.42ns typ, 2.2ns min, 2.36ns max; typ from 1.2 V to 0.735 V
|   falling waveform, R_fixture 50.000, V_fixture 0.000: 20-80 % time 543ps typ, 498ps min, 567ps max; typ from 0.451 V to 0 V
[Pulldown]
|Voltage   I(typ)   I(min)   I(max)
-1.2V     -180.2mA   -219.5mA   -157.6mA
-1.089V   -118.7mA   -157.5mA   -102.6mA
-978mV    -72.85mA   -102.3mA   -75.46mA
-867mV    -50.28mA   -60.01mA   -59.99mA
-719mV    -34.47mA   -30.88mA   -40.86mA
-497mV    -15.93mA   -14.83mA   -17.14mA
-275mV    -5.882mA   -5.85mA    -5.411mA
2.019V    21.52mA    20.87mA    21.52mA
2.13V     31.72mA    30.77mA    31.72mA
2.204V    49.93mA    48.43mA    49.93mA
2.278V    79.85mA    77.46mA    79.85mA
2.4V      144.7mA    140.4mA    144.7mA
[Pullup]
|Voltage   I(typ)   I(min)   I(max)
-1.2V     139.7mA    176.6mA    116.1mA
-1.078V   80.9mA     115.4mA    61.64mA
-1.004V   54.85mA    83mA       44.23mA
-893mV    35.47mA    46.56mA    33.97mA
-782mV    27.9mA     28.22mA    26.69mA
143mV     -3.072mA   -2.98mA    -3.072mA
1.512V    -10.52mA   -10.21mA   -10.52mA
1.734V    -18.28mA   -17.73mA   -18.28mA
2.03V     -42.1mA    -40.84mA   -42.1mA
2.141V    -57.94mA   -56.2mA    -57.94mA
2.252V    -93.7mA    -90.9mA    -93.7mA
2.4V      -167.9mA   -162.9mA   -167.9mA
[Ramp]
| variable   typ   min   max
dV/dt_r   0.271/1.340n   0.259/1.463n   0.275/1.363n
dV/dt_f   0.279/2.515n   0.267/2.303n   0.284/2.448n
R_load = 50.000
[Rising Waveform]
R_fixture = 50.000
V_fixture = 0.000
V_fixture_min = 0.000
V_fixture_max = 0.000
|  time   V(typ)   V(min)   V(max)
0s        32.99uV    -16.93uV   -211.7uV
735ps     -1.07mV    -7.856mV   -885uV
1.308ns   32.76mV    26.29mV    29.13mV
1.688ns   101.9mV    92.82mV    92.85mV
2.268ns   245.5mV    222.7mV    229.8mV
2.65ns    319.6mV    291mV      311.6mV
3.15ns    378.9mV    349.6mV    381mV
3.7ns     412.2mV    385.4mV    419.1mV
5.44ns    443.1mV    421.2mV    451.1mV
10ns      451mV      431mV      458.5mV
[Rising Waveform]
R_fixture = 50.000
V_fixture = 1.200
V_fixture_min = 1.140
V_fixture_max = 1.260
|  time   V(typ)   V(min)   V(max)
0s        734.7mV    695.7mV    786.6mV
336ps     735mV      695.9mV    786.7mV
423ps     734.9mV    695.9mV    937.5mV
528ps     899.7mV    695mV      1.027V
625ps     981.2mV    691.8mV    1.075V
675ps     1.007V     727.1mV    1.094V
775ps     1.046V     884.6mV    1.123V
925ps     1.086V     973.9mV    1.155V
1.704ns   1.171V     1.106V     1.231V
10ns      1.2V       1.14V      1.26V
[Falling Waveform]
R_fixture = 50.000
V_fixture = 1.200
V_fixture_min = 1.140
V_fixture_max = 1.260
|  time   V(typ)   V(min)   V(max)
0s        1.2V       1.14V      1.26V
450ps     1.2V       1.14V      1.268V
863ps     1.201V     1.148V     1.257V
1.553ns   1.167V     1.105V     1.205V
2.28ns    1.094V     1.019V     1.115V
3.635ns   924.8mV    838.7mV    937.7mV
4.244ns   857.9mV    783.9mV    881.6mV
4.948ns   802.9mV    744.7mV    838.9mV
6.57ns    750.6mV    708.6mV    798mV
10ns      734.7mV    695.7mV    786.6mV
[Falling Waveform]
R_fixture = 50.000
V_fixture = 0.000
V_fixture_min = 0.000
V_fixture_max = 0.000
|  time   V(typ)   V(min)   V(max)
0s        451mV      431mV      458.5mV
362ps     451.2mV    430.7mV    471.9mV
468ps     462.7mV    430.7mV    304.3mV
677ps     220.8mV    446.4mV    172.2mV
863ps     141.1mV    242.5mV    117.6mV
993ps     108.8mV    164.5mV    91.53mV
1.269ns   65.42mV    87.02mV    55.57mV
1.643ns   35.72mV    40.9mV     30.37mV
3.193ns   6.912mV    7.13mV     5.164mV
10ns      32.99uV    -16.93uV   -211.7uV
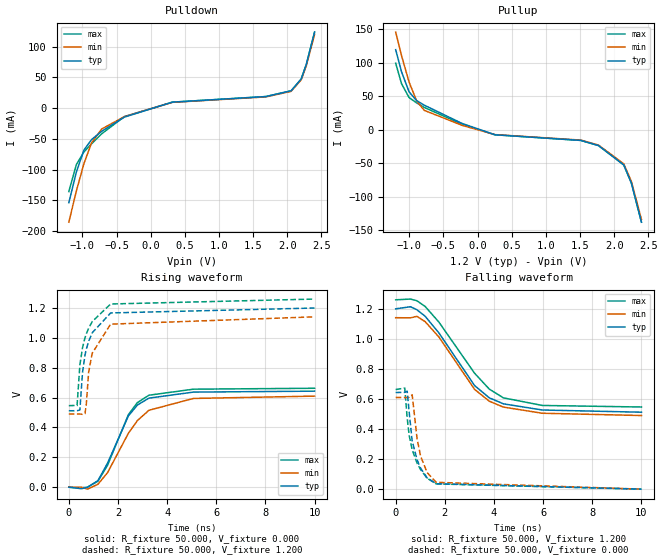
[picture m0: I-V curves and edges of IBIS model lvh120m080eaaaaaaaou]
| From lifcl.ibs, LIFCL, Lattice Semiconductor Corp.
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[Model] lvh120m080eaaaaaaaou
Model_type Output
Polarity   Non-Inverting
Enable   Active-High
Vmeas =  0.600V
Cref =  0.0F
Rref =  1.000M
Vref =  0.0V
C_comp   5.000pF   4.000pF   5.500pF
[Temperature Range]   25.000   0.125k   -40.000
[Voltage Range]   1.200V   1.140V   1.260V
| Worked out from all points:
|   slope of the pulldown table from 0 to 0.18 V, typ, clamps not added: 30.5 ohm
|   slope of the pullup table from 0 to 0.18 V, typ, clamps not added: 30.7 ohm
|   rising waveform, R_fixture 50.000, V_fixture 0.000: 20-80 % time 1.1ns typ, 1.38ns min, 1.06ns max; typ from 0 V to 0.643 V
|   rising waveform, R_fixture 50.000, V_fixture 1.200: 20-80 % time 536ps typ, 505ps min, 595ps max; typ from 0.512 V to 1.2 V
|   falling waveform, R_fixture 50.000, V_fixture 1.200: 20-80 % time 1.8ns typ, 1.73ns min, 1.92ns max; typ from 1.2 V to 0.512 V
|   falling waveform, R_fixture 50.000, V_fixture 0.000: 20-80 % time 502ps typ, 464ps min, 560ps max; typ from 0.643 V to 0 V
[Pulldown]
|Voltage   I(typ)   I(min)   I(max)
-1.2V     -153.9mA   -185.6mA   -135.8mA
-1.089V   -103.8mA   -134.7mA   -91.7mA
-978mV    -68.12mA   -90mA      -71.13mA
-867mV    -51.18mA   -56.52mA   -58.14mA
-719mV    -37.72mA   -33.97mA   -41.78mA
-386mV    -14.55mA   -13.79mA   -13.75mA
317mV     9.765mA    9.472mA    9.765mA
1.686V    18.86mA    18.29mA    18.86mA
2.056V    28.26mA    27.41mA    28.26mA
2.204V    47.45mA    46.03mA    47.45mA
2.278V    70.9mA     68.8mA     70.9mA
2.4V      123.8mA    120.1mA    123.8mA
[Pullup]
|Voltage   I(typ)   I(min)   I(max)
-1.2V     119.2mA    145.5mA    99mA
-1.115V   86.4mA     110.6mA    68.6mA
-1.004V   56.25mA    70.9mA     47.76mA
-893mV    43.25mA    42.77mA    39.77mA
-782mV    36.41mA    28.69mA    33.08mA
-227mV    9.091mA    6.284mA    7.947mA
254mV     -7.789mA   -7.556mA   -7.789mA
1.512V    -16.22mA   -15.73mA   -16.22mA
1.771V    -23.91mA   -23.2mA    -23.91mA
2.141V    -52.78mA   -51.2mA    -52.78mA
2.252V    -79.7mA    -77.3mA    -79.7mA
2.4V      -138.3mA   -134.2mA   -138.3mA
[Ramp]
| variable   typ   min   max
dV/dt_r   0.386/1.117n   0.383/1.394n   0.398/1.083n
dV/dt_f   0.413/1.839n   0.391/1.780n   0.428/1.960n
R_load = 50.000
[Rising Waveform]
R_fixture = 50.000
V_fixture = 0.000
V_fixture_min = 0.000
V_fixture_max = 0.000
|  time   V(typ)   V(min)   V(max)
0s        38.48uV    -255.3uV   -316.6uV
517ps     -10.18mV   118.2uV    -3.667mV
757ps     -781.2uV   -13.18mV   -92.21uV
1.187ns   44.7mV     19.79mV    39.73mV
1.576ns   161mV      97.57mV    147.2mV
2.425ns   477.9mV    361.5mV    486.1mV
2.791ns   550.5mV    446.3mV    566.5mV
3.26ns    596.5mV    515.2mV    616.1mV
5.07ns    636.9mV    594.4mV    656.5mV
10ns      643.2mV    610mV      662.6mV
[Rising Waveform]
R_fixture = 50.000
V_fixture = 1.200
V_fixture_min = 1.140
V_fixture_max = 1.260
|  time   V(typ)   V(min)   V(max)
0s        511.9mV    489.8mV    546.5mV
336ps     512.2mV    489.8mV    547.1mV
450ps     517.5mV    490mV      818.8mV
557ps     767.1mV    488.1mV    933.6mV
656ps     883.5mV    492.4mV    999mV
707ps     921.4mV    545.4mV    1.025V
807ps     977.1mV    770.7mV    1.065V
952ps     1.034V     897.2mV    1.109V
1.701ns   1.167V     1.092V     1.227V
10ns      1.2V       1.141V     1.26V
[Falling Waveform]
R_fixture = 50.000
V_fixture = 1.200
V_fixture_min = 1.140
V_fixture_max = 1.260
|  time   V(typ)   V(min)   V(max)
0s        1.2V       1.141V     1.26V
601ps     1.214V     1.14V      1.265V
861ps     1.194V     1.15V      1.254V
1.197ns   1.151V     1.115V     1.216V
1.761ns   1.039V     1.012V     1.111V
3.211ns   689.1mV    663.8mV    771.1mV
3.811ns   607.3mV    584.9mV    665.3mV
4.381ns   567.7mV    546mV      607.6mV
5.965ns   526.6mV    505mV      556.9mV
10ns      511.9mV    489.8mV    546.5mV
[Falling Waveform]
R_fixture = 50.000
V_fixture = 0.000
V_fixture_min = 0.000
V_fixture_max = 0.000
|  time   V(typ)   V(min)   V(max)
0s        643.2mV    610mV      662.6mV
370ps     643.8mV    609.6mV    672.4mV
468ps     651.9mV    609.6mV    472.2mV
548ps     513.4mV    611.2mV    357.6mV
670ps     321.6mV    627.9mV    262.4mV
871ps     194.4mV    335.2mV    172.7mV
1.011ns   140.9mV    221.2mV    130.2mV
1.277ns   74.91mV    110.6mV    72.91mV
1.647ns   35.83mV    45.3mV     34.7mV
10ns      38.48uV    -255.3uV   -316.6uV
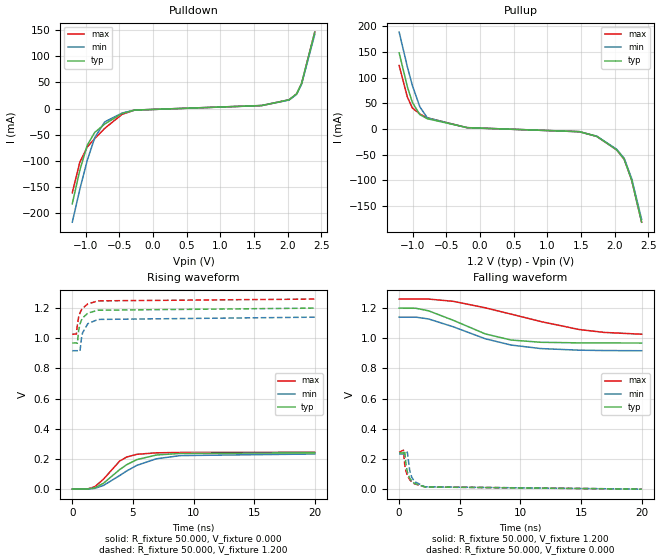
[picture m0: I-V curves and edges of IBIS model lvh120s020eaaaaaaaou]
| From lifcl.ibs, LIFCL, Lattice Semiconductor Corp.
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[Model] lvh120s020eaaaaaaaou
Model_type Output
Polarity   Non-Inverting
Enable   Active-High
Vmeas =  0.600V
Cref =  0.0F
Rref =  1.000M
Vref =  0.0V
C_comp   5.000pF   4.000pF   5.500pF
[Temperature Range]   25.000   0.125k   -40.000
[Voltage Range]   1.200V   1.140V   1.260V
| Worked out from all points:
|   slope of the pulldown table from 0 to 0.18 V, typ, clamps not added: 108 ohm
|   slope of the pullup table from 0 to 0.18 V, typ, clamps not added: 92.2 ohm
|   rising waveform, R_fixture 50.000, V_fixture 0.000: 20-80 % time 2.51ns typ, 3.16ns min, 1.7ns max; typ from 0 V to 0.241 V
|   rising waveform, R_fixture 50.000, V_fixture 1.200: 20-80 % time 571ps typ, 548ps min, 610ps max; typ from 0.969 V to 1.2 V
|   falling waveform, R_fixture 50.000, V_fixture 1.200: 20-80 % time 4.2ns typ, 4.96ns min, 7.25ns max; typ from 1.2 V to 0.969 V
|   falling waveform, R_fixture 50.000, V_fixture 0.000: 20-80 % time 571ps typ, 549ps min, 610ps max; typ from 0.241 V to 0 V
[Pulldown]
|Voltage   I(typ)   I(min)   I(max)
-1.2V     -182.9mA   -218.3mA   -161.8mA
-1.089V   -119mA     -155.7mA   -103.5mA
-978mV    -70.5mA    -99.7mA    -73.97mA
-867mV    -45.98mA   -56.14mA   -57.88mA
-719mV    -29.83mA   -25.74mA   -38.17mA
-460mV    -9.387mA   -8.653mA   -11.09mA
-275mV    -2.976mA   -3.061mA   -3.072mA
1.612V    5.767mA    5.594mA    5.767mA
2.019V    16.81mA    16.3mA     16.81mA
2.13V     28.06mA    27.22mA    28.06mA
2.204V    47.87mA    46.44mA    47.87mA
2.4V      146.8mA    142.4mA    146.8mA
[Pullup]
|Voltage   I(typ)   I(min)   I(max)
-1.2V     147.9mA    188.3mA    123.4mA
-1.078V   81.98mA    120.7mA    61.86mA
-1.004V   51.59mA    84.61mA    40.82mA
-893mV    27.85mA    43mA       29.06mA
-782mV    19.86mA    21.61mA    21.61mA
-190mV    2.572mA    2.372mA    2.456mA
1.475V    -5.352mA   -5.192mA   -5.352mA
1.734V    -14.51mA   -14.08mA   -14.51mA
2.03V     -40.75mA   -39.53mA   -40.75mA
2.141V    -58.9mA    -57.14mA   -58.9mA
2.252V    -99.4mA    -96.4mA    -99.4mA
2.4V      -181.3mA   -175.9mA   -181.3mA
[Ramp]
| variable   typ   min   max
dV/dt_r   0.146/2.498n   0.140/3.174n   0.147/1.768n
dV/dt_f   0.139/4.209n   0.134/4.974n   0.139/7.255n
R_load = 50.000
[Rising Waveform]
R_fixture = 50.000
V_fixture = 0.000
V_fixture_min = 0.000
V_fixture_max = 0.000
|  time   V(typ)   V(min)   V(max)
0s        7.053uV    46.35uV    271.1uV
1.275ns   742.8uV    311.3uV    1.713mV
1.87ns    9.365mV    5.632mV    16.83mV
2.578ns   39.47mV    24.87mV    66.72mV
3.911ns   129.9mV    90.44mV    186.4mV
4.49ns    162.3mV    120.8mV    213mV
5.33ns    195.9mV    158mV      231mV
6.945ns   226.5mV    201.6mV    240.9mV
8.925ns   236.9mV    222.6mV    243.3mV
20ns      240.7mV    233.2mV    244.8mV
[Rising Waveform]
R_fixture = 50.000
V_fixture = 1.200
V_fixture_min = 1.140
V_fixture_max = 1.260
|  time   V(typ)   V(min)   V(max)
0s        968.7mV    917.6mV    1.027V
335ps     969.1mV    917.7mV    1.028V
421ps     966.7mV    917.7mV    1.089V
522ps     1.05V      917.4mV    1.139V
635ps     1.095V     915mV      1.168V
765ps     1.122V     1.003V     1.189V
845ps     1.134V     1.036V     1.199V
1.284ns   1.167V     1.097V     1.228V
2.124ns   1.186V     1.125V     1.248V
20ns      1.2V       1.14V      1.26V
[Falling Waveform]
R_fixture = 50.000
V_fixture = 1.200
V_fixture_min = 1.140
V_fixture_max = 1.260
|  time   V(typ)   V(min)   V(max)
0s        1.2V       1.14V      1.26V
1.383ns   1.199V     1.14V      1.26V
2.434ns   1.182V     1.128V     1.26V
4.47ns    1.119V     1.076V     1.245V
7.107ns   1.029V     996.8mV    1.202V
9.239ns   988.4mV    955.2mV    1.16V
11.68ns   973.6mV    931.9mV    1.111V
14.86ns   969.6mV    921.2mV    1.058V
16.91ns   969mV      918.9mV    1.039V
20ns      968.7mV    917.6mV    1.027V
[Falling Waveform]
R_fixture = 50.000
V_fixture = 0.000
V_fixture_min = 0.000
V_fixture_max = 0.000
|  time   V(typ)   V(min)   V(max)
0s        241mV      233.2mV    244.8mV
356ps     240.6mV    232.9mV    258.9mV
454ps     255.3mV    233.1mV    166.6mV
562ps     165.6mV    234.8mV    119.4mV
673ps     114.8mV    246mV      91.95mV
874ps     72.01mV    122.2mV    62.67mV
1.043ns   52.84mV    78.71mV    48.07mV
1.273ns   37.23mV    49.98mV    35.39mV
2.123ns   14.46mV    15.78mV    15.11mV
20ns      169.3uV    46.35uV    271.1uV
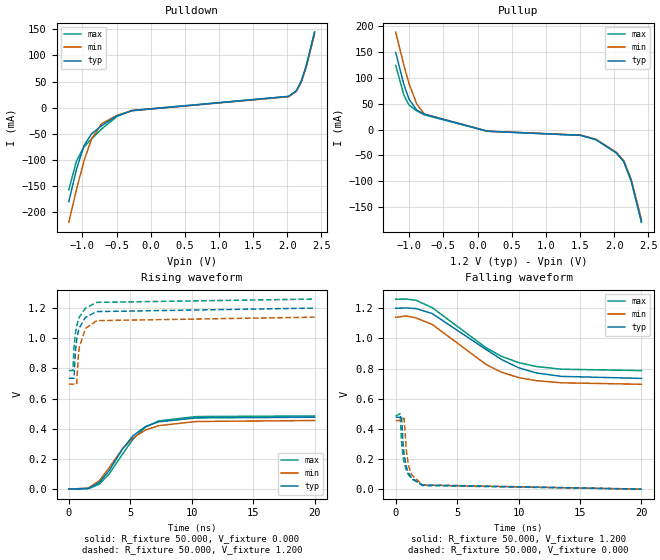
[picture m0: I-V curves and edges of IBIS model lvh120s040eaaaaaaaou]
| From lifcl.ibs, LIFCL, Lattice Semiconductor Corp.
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[Model] lvh120s040eaaaaaaaou
Model_type Output
Polarity   Non-Inverting
Enable   Active-High
Vmeas =  0.600V
Cref =  0.0F
Rref =  1.000M
Vref =  0.0V
C_comp   5.000pF   4.000pF   5.500pF
[Temperature Range]   25.000   0.125k   -40.000
[Voltage Range]   1.200V   1.140V   1.260V
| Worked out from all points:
|   slope of the pulldown table from 0 to 0.18 V, typ, clamps not added: 51.8 ohm
|   slope of the pullup table from 0 to 0.18 V, typ, clamps not added: 44.9 ohm
|   rising waveform, R_fixture 50.000, V_fixture 0.000: 20-80 % time 2.56ns typ, 2.79ns min, 2.63ns max; typ from 0 V to 0.477 V
|   rising waveform, R_fixture 50.000, V_fixture 1.200: 20-80 % time 569ps typ, 544ps min, 614ps max; typ from 0.735 V to 1.2 V
|   falling waveform, R_fixture 50.000, V_fixture 1.200: 20-80 % time 5.14ns typ, 4.61ns min, 4.94ns max; typ from 1.2 V to 0.735 V
|   falling waveform, R_fixture 50.000, V_fixture 0.000: 20-80 % time 563ps typ, 547ps min, 607ps max; typ from 0.477 V to 0 V
[Pulldown]
|Voltage   I(typ)   I(min)   I(max)
-1.2V     -180.2mA   -219.5mA   -157.6mA
-1.089V   -118.7mA   -157.5mA   -102.6mA
-978mV    -72.85mA   -102.3mA   -75.46mA
-867mV    -50.28mA   -60.01mA   -59.99mA
-719mV    -34.47mA   -30.88mA   -40.86mA
-497mV    -15.93mA   -14.83mA   -17.14mA
-275mV    -5.882mA   -5.85mA    -5.411mA
2.019V    21.52mA    20.87mA    21.52mA
2.13V     31.72mA    30.77mA    31.72mA
2.204V    49.93mA    48.43mA    49.93mA
2.278V    79.85mA    77.46mA    79.85mA
2.4V      144.7mA    140.4mA    144.7mA
[Pullup]
|Voltage   I(typ)   I(min)   I(max)
-1.2V     149.1mA    188.4mA    123.9mA
-1.078V   86.3mA     123.1mA    65.77mA
-1.004V   58.53mA    88.6mA     47.2mA
-893mV    37.85mA    49.68mA    36.25mA
-782mV    29.77mA    30.11mA    28.48mA
143mV     -3.278mA   -3.179mA   -3.278mA
1.512V    -11.23mA   -10.89mA   -11.23mA
1.734V    -19.5mA    -18.92mA   -19.5mA
2.03V     -44.92mA   -43.58mA   -44.92mA
2.141V    -61.82mA   -59.96mA   -61.82mA
2.252V    -100mA     -97mA      -100mA
2.4V      -179.1mA   -173.7mA   -179.1mA
[Ramp]
| variable   typ   min   max
dV/dt_r   0.286/2.573n   0.273/2.778n   0.301/2.658n
dV/dt_f   0.279/5.201n   0.267/4.617n   0.284/4.965n
R_load = 50.000
[Rising Waveform]
R_fixture = 50.000
V_fixture = 0.000
V_fixture_min = 0.000
V_fixture_max = 0.000
|  time   V(typ)   V(min)   V(max)
0s        34.41uV    -16.93uV   -211.7uV
1.585ns   5.047mV    6.769mV    2.447mV
2.478ns   43.7mV     55.19mV    32.44mV
3.275ns   122mV      141.3mV    100mV
4.391ns   268.1mV    270.4mV    234.8mV
5.23ns    354.1mV    340.2mV    332mV
6.234ns   414.6mV    391.2mV    410.7mV
7.305ns   446.4mV    420.6mV    452.2mV
10.37ns   472.1mV    448.4mV    481mV
20ns      476.8mV    455mV      485.2mV
[Rising Waveform]
R_fixture = 50.000
V_fixture = 1.200
V_fixture_min = 1.140
V_fixture_max = 1.260
|  time   V(typ)   V(min)   V(max)
0s        734.7mV    695.7mV    786.6mV
333ps     735mV      695.9mV    785.3mV
423ps     734.6mV    695.9mV    937.3mV
534ps     906.9mV    694.7mV    1.031V
635ps     987mV      694.2mV    1.079V
765ps     1.043V     873.9mV    1.12V
847ps     1.067V     937.5mV    1.139V
1.354ns   1.139V     1.065V     1.2V
2.273ns   1.177V     1.117V     1.238V
20ns      1.2V       1.14V      1.26V
[Falling Waveform]
R_fixture = 50.000
V_fixture = 1.200
V_fixture_min = 1.140
V_fixture_max = 1.260
|  time   V(typ)   V(min)   V(max)
0s        1.2V       1.14V      1.26V
843ps     1.202V     1.149V     1.261V
1.653ns   1.198V     1.136V     1.253V
2.969ns   1.165V     1.093V     1.204V
7.353ns   926.7mV    827.5mV    938.2mV
8.594ns   861mV      776.2mV    881.7mV
10.01ns   804.8mV    739.9mV    839.2mV
11.47ns   770.4mV    719.3mV    813mV
13.5ns    747.9mV    705.4mV    795.6mV
20ns      734.7mV    695.7mV    786.6mV
[Falling Waveform]
R_fixture = 50.000
V_fixture = 0.000
V_fixture_min = 0.000
V_fixture_max = 0.000
|  time   V(typ)   V(min)   V(max)
0s        476.8mV    455mV      485.2mV
362ps     477mV      454.7mV    500.7mV
473ps     488.5mV    454.7mV    317.2mV
603ps     300.3mV    465.3mV    217.1mV
683ps     230.1mV    470.9mV    180.7mV
874ps     146.5mV    247.7mV    125.1mV
1.033ns   108.8mV    160.2mV    96.94mV
1.294ns   73.11mV    95.73mV    67.75mV
2.183ns   27.79mV    27.46mV    23.81mV
20ns      34.41uV    -16.93uV   -211.7uV
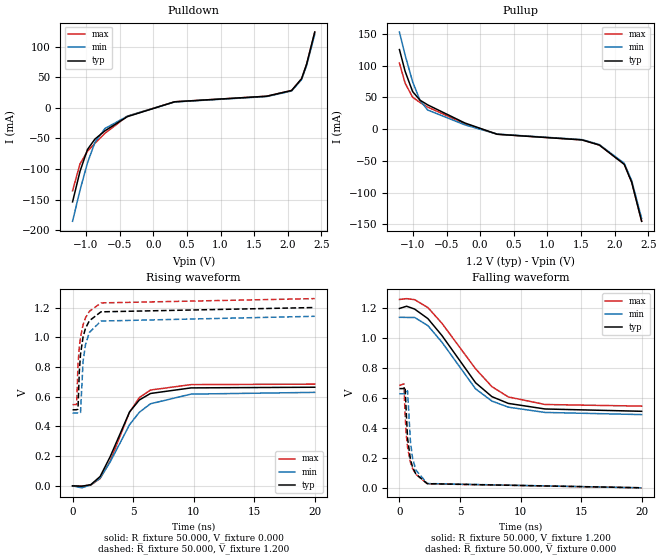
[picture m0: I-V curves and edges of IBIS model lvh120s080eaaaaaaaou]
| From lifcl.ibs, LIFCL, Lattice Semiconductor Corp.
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[Model] lvh120s080eaaaaaaaou
Model_type Output
Polarity   Non-Inverting
Enable   Active-High
Vmeas =  0.600V
Cref =  0.0F
Rref =  1.000M
Vref =  0.0V
C_comp   5.000pF   4.000pF   5.500pF
[Temperature Range]   25.000   0.125k   -40.000
[Voltage Range]   1.200V   1.140V   1.260V
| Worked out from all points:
|   slope of the pulldown table from 0 to 0.18 V, typ, clamps not added: 30.5 ohm
|   slope of the pullup table from 0 to 0.18 V, typ, clamps not added: 29.3 ohm
|   rising waveform, R_fixture 50.000, V_fixture 0.000: 20-80 % time 2.22ns typ, 2.74ns min, 2.13ns max; typ from 0 V to 0.664 V
|   rising waveform, R_fixture 50.000, V_fixture 1.200: 20-80 % time 569ps typ, 542ps min, 612ps max; typ from 0.512 V to 1.2 V
|   falling waveform, R_fixture 50.000, V_fixture 1.200: 20-80 % time 3.85ns typ, 3.69ns min, 4.12ns max; typ from 1.2 V to 0.512 V
|   falling waveform, R_fixture 50.000, V_fixture 0.000: 20-80 % time 561ps typ, 546ps min, 604ps max; typ from 0.664 V to 0 V
[Pulldown]
|Voltage   I(typ)   I(min)   I(max)
-1.2V     -153.9mA   -185.6mA   -135.8mA
-1.089V   -103.8mA   -134.7mA   -91.7mA
-978mV    -68.12mA   -90mA      -71.13mA
-867mV    -51.18mA   -56.52mA   -58.14mA
-719mV    -37.72mA   -33.97mA   -41.78mA
-386mV    -14.55mA   -13.79mA   -13.75mA
317mV     9.765mA    9.472mA    9.765mA
1.686V    18.86mA    18.29mA    18.86mA
2.056V    28.26mA    27.41mA    28.26mA
2.204V    47.45mA    46.03mA    47.45mA
2.278V    70.9mA     68.8mA     70.9mA
2.4V      123.8mA    120.1mA    123.8mA
[Pullup]
|Voltage   I(typ)   I(min)   I(max)
-1.2V     125.1mA    152.7mA    103.9mA
-1.115V   90.7mA     116.1mA    72mA
-1.004V   59.02mA    74.4mA     50.12mA
-893mV    45.38mA    44.88mA    41.74mA
-782mV    38.2mA     30.11mA    34.71mA
-227mV    9.539mA    6.593mA    8.339mA
254mV     -8.173mA   -7.928mA   -8.173mA
1.512V    -17.02mA   -16.51mA   -17.02mA
1.771V    -25.09mA   -24.34mA   -25.09mA
2.141V    -55.39mA   -53.73mA   -55.39mA
2.252V    -83.6mA    -81.1mA    -83.6mA
2.4V      -145.1mA   -140.7mA   -145.1mA
[Ramp]
| variable   typ   min   max
dV/dt_r   0.398/2.229n   0.384/2.743n   0.411/2.141n
dV/dt_f   0.413/3.886n   0.391/3.715n   0.428/4.132n
R_load = 50.000
[Rising Waveform]
R_fixture = 50.000
V_fixture = 0.000
V_fixture_min = 0.000
V_fixture_max = 0.000
|  time   V(typ)   V(min)   V(max)
0s        38.48uV    -255.3uV   -316.6uV
756ps     -2.344mV   -13.3mV    -1.784mV
1.497ns   7.524mV    6.349mV    4.883mV
2.277ns   63.05mV    52.75mV    49.23mV
3.098ns   194.8mV    159.7mV    165.1mV
4.711ns   498.2mV    412.3mV    496mV
5.516ns   577.9mV    495.3mV    593.9mV
6.435ns   621.7mV    552.3mV    644.8mV
9.776ns   659.2mV    617.3mV    681.2mV
20ns      663.6mV    629.1mV    684.6mV
[Rising Waveform]
R_fixture = 50.000
V_fixture = 1.200
V_fixture_min = 1.140
V_fixture_max = 1.260
|  time   V(typ)   V(min)   V(max)
0s        511.9mV    489.8mV    546.5mV
336ps     512.2mV    489.8mV    547mV
449ps     516.9mV    490mV      817.2mV
557ps     767.3mV    488mV      933.6mV
657ps     884.7mV    492.7mV    999.6mV
867ps     1.002V     837.2mV    1.084V
1.069ns   1.06V      950.3mV    1.131V
1.387ns   1.111V     1.032V     1.174V
2.346ns   1.171V     1.109V     1.231V
20ns      1.2V       1.141V     1.26V
[Falling Waveform]
R_fixture = 50.000
V_fixture = 1.200
V_fixture_min = 1.140
V_fixture_max = 1.260
|  time   V(typ)   V(min)   V(max)
0s        1.2V       1.141V     1.26V
592ps     1.215V     1.14V      1.266V
1.252ns   1.196V     1.14V      1.259V
2.351ns   1.132V     1.085V     1.206V
3.509ns   1.019V     974.2mV    1.101V
6.29ns    702.7mV    661.7mV    795.9mV
7.64ns    609.7mV    580mV      676.6mV
8.993ns   564.7mV    539.6mV    608mV
12.02ns   527.4mV    504.2mV    557.4mV
20ns      511.9mV    489.8mV    546.5mV
[Falling Waveform]
R_fixture = 50.000
V_fixture = 0.000
V_fixture_min = 0.000
V_fixture_max = 0.000
|  time   V(typ)   V(min)   V(max)
0s        663.6mV    629.1mV    684.6mV
370ps     664.1mV    628.7mV    695.6mV
467ps     674.3mV    628.8mV    491.2mV
550ps     526.7mV    630.5mV    368.1mV
670ps     332.8mV    649.1mV    271.8mV
911ps     188.9mV    306.1mV    169.9mV
1.08ns    139.3mV    201mV      130.3mV
1.351ns   92.77mV    119.3mV    90.96mV
2.297ns   27.41mV    28.49mV    27.01mV
20ns      38.48uV    -255.3uV   -316.6uV
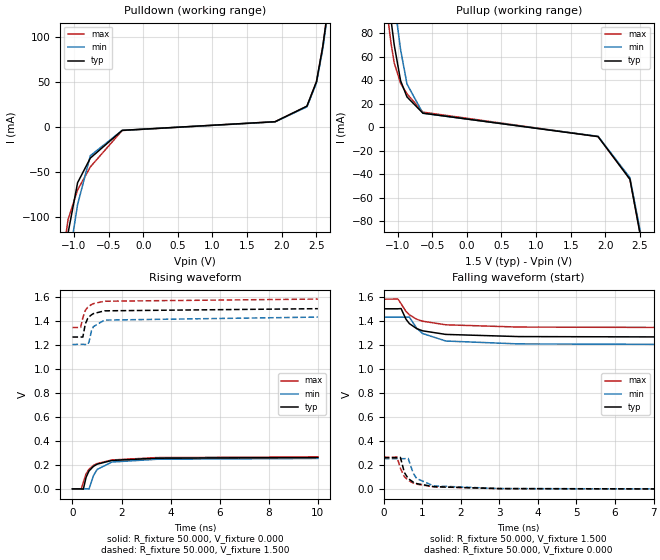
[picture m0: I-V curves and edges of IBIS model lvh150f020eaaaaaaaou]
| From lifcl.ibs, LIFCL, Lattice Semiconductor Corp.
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[Model] lvh150f020eaaaaaaaou
Model_type Output
Polarity   Non-Inverting
Enable   Active-High
Vmeas =  0.750V
Cref =  0.0F
Rref =  1.000M
Vref =  0.0V
C_comp   5.000pF   4.000pF   5.500pF
[Temperature Range]   25.000   0.125k   -40.000
[Voltage Range]   1.500V   1.430V   1.580V
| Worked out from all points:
|   slope of the pulldown table from 0 to 0.225 V, typ, clamps not added: 110 ohm
|   slope of the pullup table from 0 to 0.225 V, typ, clamps not added: 114 ohm
|   rising waveform, R_fixture 50.000, V_fixture 0.000: 20-80 % time 537ps typ, 524ps min, 586ps max; typ from 0 V to 0.261 V
|   rising waveform, R_fixture 50.000, V_fixture 1.500: 20-80 % time 333ps typ, 334ps min, 366ps max; typ from 1.26 V to 1.5 V
|   falling waveform, R_fixture 50.000, V_fixture 1.500: 20-80 % time 559ps typ, 592ps min, 621ps max; typ from 1.5 V to 1.26 V
|   falling waveform, R_fixture 50.000, V_fixture 0.000: 20-80 % time 324ps typ, 334ps min, 346ps max; typ from 0.262 V to 0.001 V
[Pulldown]
|Voltage   I(typ)   I(min)   I(max)
-1.5V     -381.2mA   -398.5mA   -369.5mA
-1.224V   -198.4mA   -231.2mA   -177.7mA
-1.086V   -117.9mA   -153.6mA   -102.9mA
-948mV    -61.75mA   -86mA      -69.76mA
-764mV    -34.4mA    -31.77mA   -44.22mA
-304mV    -3.563mA   -3.619mA   -3.717mA
1.904V    6.038mA    5.856mA    6.038mA
2.364V    23.29mA    22.59mA    23.29mA
2.502V    50.57mA    49.05mA    50.57mA
2.594V    90.1mA     87.4mA     90.1mA
2.732V    168.6mA    163.5mA    168.6mA
3V        342.5mA    332.2mA    342.5mA
[Pullup]
|Voltage   I(typ)   I(min)   I(max)
-1.5V     341.5mA    374.7mA    322.6mA
-1.186V   141.4mA    182mA      117.9mA
-1.14V    115.3mA    155.9mA    92.8mA
-1.094V   91.2mA     130.7mA    71.23mA
-1.048V   69.93mA    107mA      54.61mA
-956mV    39.5mA     65.87mA    37.33mA
-864mV    25.74mA    36.76mA    28.41mA
-634mV    11.91mA    11.82mA    12.78mA
1.896V    -8.049mA   -7.808mA   -8.049mA
2.356V    -44.37mA   -43.04mA   -44.37mA
2.586V    -117.1mA   -113.6mA   -117.1mA
3V        -379mA     -367.6mA   -379mA
[Ramp]
| variable   typ   min   max
dV/dt_r   0.158/0.547n   0.152/0.521n   0.159/0.588n
dV/dt_f   0.142/0.556n   0.137/0.590n   0.142/0.634n
R_load = 50.000
[Rising Waveform]
R_fixture = 50.000
V_fixture = 0.000
V_fixture_min = 0.000
V_fixture_max = 0.000
|  time   V(typ)   V(min)   V(max)
0s        31.62uV    109.6uV    354.2uV
361ps     290.4uV    197.3uV    -982.3uV
444ps     -2.289mV   157.8uV    55.84mV
558ps     97.09mV    315.3uV    126.8mV
676ps     149.1mV    -934uV     163.4mV
856ps     187.3mV    110.2mV    195mV
1.008ns   205.8mV    161.9mV    211.2mV
1.608ns   236.7mV    223.3mV    240.7mV
3.442ns   255.4mV    246.7mV    260.6mV
10ns      261.3mV    253.4mV    266mV
[Rising Waveform]
R_fixture = 50.000
V_fixture = 1.500
V_fixture_min = 1.430
V_fixture_max = 1.580
|  time   V(typ)   V(min)   V(max)
0s        1.264V     1.202V     1.343V
336ps     1.264V     1.203V     1.344V
424ps     1.264V     1.203V     1.425V
527ps     1.374V     1.202V     1.486V
626ps     1.42V      1.202V     1.512V
677ps     1.432V     1.224V     1.521V
776ps     1.449V     1.317V     1.534V
857ps     1.459V     1.351V     1.542V
1.307ns   1.482V     1.405V     1.562V
10ns      1.5V       1.43V      1.58V
[Falling Waveform]
R_fixture = 50.000
V_fixture = 1.500
V_fixture_min = 1.430
V_fixture_max = 1.580
|  time   V(typ)   V(min)   V(max)
0s        1.5V       1.43V      1.58V
369ps     1.5V       1.43V      1.581V
450ps     1.502V     1.43V      1.542V
577ps     1.414V     1.43V      1.479V
665ps     1.377V     1.431V     1.45V
857ps     1.335V     1.338V     1.413V
1.007ns   1.317V     1.295V     1.397V
1.61ns    1.287V     1.232V     1.367V
3.503ns   1.269V     1.208V     1.348V
10ns      1.264V     1.202V     1.343V
[Falling Waveform]
R_fixture = 50.000
V_fixture = 0.000
V_fixture_min = 0.000
V_fixture_max = 0.000
|  time   V(typ)   V(min)   V(max)
0s        262.1mV    253.4mV    266mV
346ps     261.8mV    253.2mV    266.5mV
433ps     264.1mV    253.4mV    173.3mV
536ps     139mV      253.6mV    104.1mV
635ps     88.58mV    255.4mV    73.49mV
765ps     58.62mV    133.1mV    51.21mV
855ps     46.4mV     88.42mV    41.59mV
1.295ns   20.81mV    27.51mV    19.9mV
2.993ns   5.045mV    4.978mV    4.129mV
10ns      522.2uV    109.6uV    354.2uV
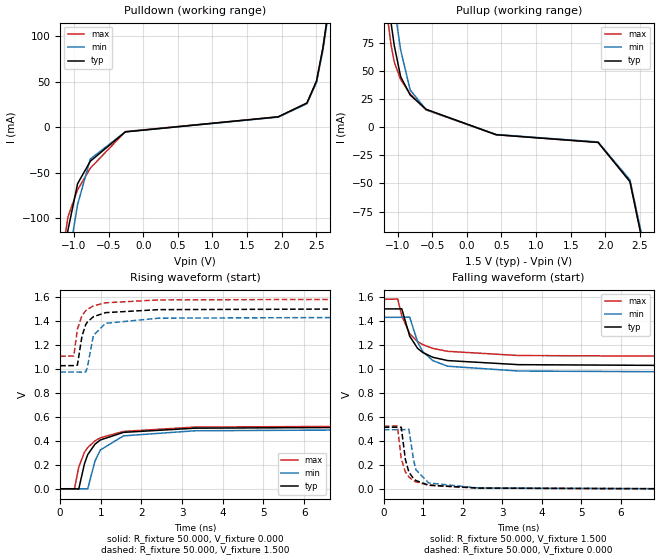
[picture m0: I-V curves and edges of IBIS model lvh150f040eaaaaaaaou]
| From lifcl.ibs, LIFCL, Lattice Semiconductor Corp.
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[Model] lvh150f040eaaaaaaaou
Model_type Output
Polarity   Non-Inverting
Enable   Active-High
Vmeas =  0.750V
Cref =  0.0F
Rref =  1.000M
Vref =  0.0V
C_comp   5.000pF   4.000pF   5.500pF
[Temperature Range]   25.000   0.125k   -40.000
[Voltage Range]   1.500V   1.430V   1.580V
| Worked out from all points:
|   slope of the pulldown table from 0 to 0.225 V, typ, clamps not added: 54.8 ohm
|   slope of the pullup table from 0 to 0.225 V, typ, clamps not added: 56 ohm
|   rising waveform, R_fixture 50.000, V_fixture 0.000: 20-80 % time 484ps typ, 460ps min, 544ps max; typ from 0 V to 0.515 V
|   rising waveform, R_fixture 50.000, V_fixture 1.500: 20-80 % time 234ps typ, 239ps min, 259ps max; typ from 1.02 V to 1.5 V
|   falling waveform, R_fixture 50.000, V_fixture 1.500: 20-80 % time 536ps typ, 520ps min, 593ps max; typ from 1.5 V to 1.02 V
|   falling waveform, R_fixture 50.000, V_fixture 0.000: 20-80 % time 220ps typ, 226ps min, 243ps max; typ from 0.515 V to 0 V
[Pulldown]
|Voltage   I(typ)   I(min)   I(max)
-1.5V     -358.2mA   -381.8mA   -344.9mA
-1.224V   -187.6mA   -222.6mA   -167mA
-1.086V   -112.9mA   -148.8mA   -98.5mA
-948mV    -62.28mA   -85.2mA    -69.02mA
-764mV    -37.5mA    -35.09mA   -45.15mA
-258mV    -5.249mA   -5.157mA   -4.87mA
1.95V     11.37mA    11.03mA    11.37mA
2.364V    26.55mA    25.75mA    26.55mA
2.502V    50.62mA    49.1mA     50.62mA
2.594V    86.8mA     84.2mA     86.8mA
2.732V    159.4mA    154.6mA    159.4mA
3V        321.9mA    312.2mA    321.9mA
[Pullup]
|Voltage   I(typ)   I(min)   I(max)
-1.5V     334.2mA    366.8mA    315.2mA
-1.186V   140.5mA    179.9mA    117.2mA
-1.094V   92.7mA     130.5mA    73.11mA
-1.048V   72.68mA    107.9mA    57.95mA
-956mV    44.92mA    68.74mA    42.37mA
-818mV    28.55mA    33.04mA    29.55mA
-588mV    15.88mA    15.55mA    15.32mA
424mV     -6.746mA   -6.543mA   -6.746mA
1.896V    -13.58mA   -13.17mA   -13.58mA
2.356V    -48.31mA   -46.87mA   -48.31mA
2.586V    -116.3mA   -112.8mA   -116.3mA
3V        -369.7mA   -358.6mA   -369.7mA
[Ramp]
| variable   typ   min   max
dV/dt_r   0.309/0.493n   0.296/0.462n   0.315/0.551n
dV/dt_f   0.285/0.532n   0.275/0.520n   0.287/0.596n
R_load = 50.000
[Rising Waveform]
R_fixture = 50.000
V_fixture = 0.000
V_fixture_min = 0.000
V_fixture_max = 0.000
|  time   V(typ)   V(min)   V(max)
0s        60.93uV    340.6uV    -199.2uV
351ps     323.9uV    399.3uV    -3.154mV
457ps     -2.723mV   384.9uV    180.6mV
597ps     207.2mV    -190.7uV   303.7mV
677ps     283.8mV    -1.001mV   342.9mV
856ps     371.2mV    230.2mV    398.9mV
988ps     406.6mV    323.2mV    424.7mV
1.557ns   469.8mV    440.7mV    477.7mV
3.321ns   504.8mV    483.3mV    514.1mV
10ns      515.5mV    494.8mV    524.1mV
[Rising Waveform]
R_fixture = 50.000
V_fixture = 1.500
V_fixture_min = 1.430
V_fixture_max = 1.580
|  time   V(typ)   V(min)   V(max)
0s        1.025V     972.1mV    1.103V
336ps     1.026V     972.3mV    1.106V
424ps     1.03V      972.3mV    1.329V
537ps     1.271V     970.8mV    1.443V
627ps     1.366V     972.8mV    1.482V
667ps     1.388V     1.007V     1.494V
817ps     1.433V     1.277V     1.523V
1.118ns   1.467V     1.378V     1.549V
2.427ns   1.492V     1.421V     1.573V
10ns      1.5V       1.43V      1.58V
[Falling Waveform]
R_fixture = 50.000
V_fixture = 1.500
V_fixture_min = 1.430
V_fixture_max = 1.580
|  time   V(typ)   V(min)   V(max)
0s        1.5V       1.43V      1.58V
356ps     1.5V       1.43V      1.582V
457ps     1.501V     1.43V      1.442V
657ps     1.273V     1.432V     1.294V
857ps     1.172V     1.225V     1.228V
987ps     1.137V     1.145V     1.203V
1.246ns   1.097V     1.069V     1.171V
1.619ns   1.07V      1.023V     1.147V
3.416ns   1.036V     983mV      1.112V
10ns      1.025V     972.1mV    1.103V
[Falling Waveform]
R_fixture = 50.000
V_fixture = 0.000
V_fixture_min = 0.000
V_fixture_max = 0.000
|  time   V(typ)   V(min)   V(max)
0s        515.5mV    494.8mV    524.1mV
346ps     515.2mV    494.5mV    524.6mV
444ps     515.5mV    494.7mV    252.3mV
547ps     248.8mV    495.7mV    143.8mV
637ps     141.8mV    497.6mV    101.2mV
757ps     86.82mV    240.3mV    69.9mV
817ps     71.31mV    160mV      59.85mV
1.137ns   33.57mV    51.32mV    32.13mV
2.407ns   8.947mV    9.298mV    7.78mV
10ns      60.93uV    340.6uV    -199.2uV
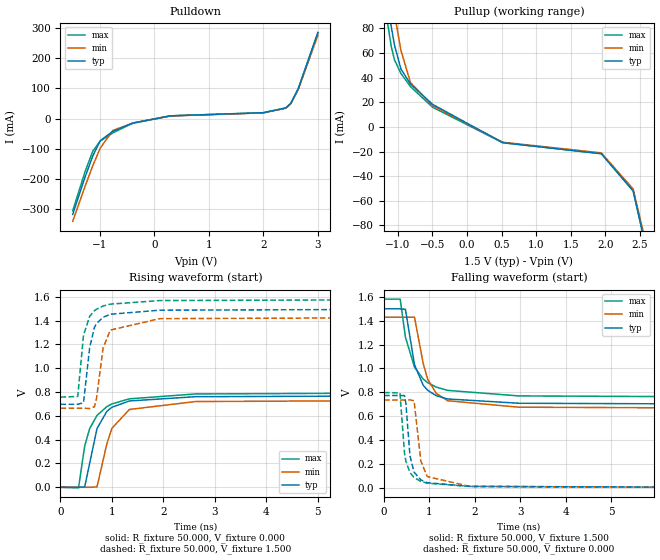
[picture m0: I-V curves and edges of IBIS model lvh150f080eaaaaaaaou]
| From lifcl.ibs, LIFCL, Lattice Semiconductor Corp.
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[Model] lvh150f080eaaaaaaaou
Model_type Output
Polarity   Non-Inverting
Enable   Active-High
Vmeas =  0.750V
Cref =  0.0F
Rref =  1.000M
Vref =  0.0V
C_comp   5.000pF   4.000pF   5.500pF
[Temperature Range]   25.000   0.125k   -40.000
[Voltage Range]   1.500V   1.430V   1.580V
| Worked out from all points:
|   slope of the pulldown table from 0 to 0.225 V, typ, clamps not added: 30.7 ohm
|   slope of the pullup table from 0 to 0.225 V, typ, clamps not added: 34 ohm
|   rising waveform, R_fixture 50.000, V_fixture 0.000: 20-80 % time 311ps typ, 333ps min, 377ps max; typ from 0 V to 0.774 V
|   rising waveform, R_fixture 50.000, V_fixture 1.500: 20-80 % time 163ps typ, 184ps min, 167ps max; typ from 0.698 V to 1.5 V
|   falling waveform, R_fixture 50.000, V_fixture 1.500: 20-80 % time 328ps typ, 329ps min, 417ps max; typ from 1.5 V to 0.698 V
|   falling waveform, R_fixture 50.000, V_fixture 0.000: 20-80 % time 135ps typ, 149ps min, 147ps max; typ from 0.774 V to 0 V
[Pulldown]
|Voltage   I(typ)   I(min)   I(max)
-1.5V     -317.3mA   -339.9mA   -305.2mA
-1.27V    -191.9mA   -222.5mA   -173.7mA
-1.132V   -123.7mA   -156.1mA   -107.8mA
-994mV    -73mA      -97.2mA    -74.1mA
-764mV    -42.16mA   -39.16mA   -47.27mA
-396mV    -15.24mA   -14.44mA   -14.48mA
294mV     9.291mA    9.012mA    9.291mA
1.996V    19.65mA    19.06mA    19.65mA
2.41V     35.42mA    34.35mA    35.42mA
2.502V    50.45mA    48.93mA    50.45mA
2.64V     99.5mA     96.5mA     99.5mA
3V        285mA      276.4mA    285mA
[Pullup]
|Voltage   I(typ)   I(min)   I(max)
-1.5V     270.5mA    296.8mA    254.1mA
-1.186V   117.5mA    148.3mA    97.8mA
-1.094V   81mA       109.7mA    64.93mA
-1.048V   66.37mA    92mA       54.42mA
-956mV    47.16mA    62.34mA    43.5mA
-818mV    34.79mA    36.11mA    32.74mA
-496mV    18.28mA    17.11mA    15.93mA
516mV     -12.8mA    -12.42mA   -12.8mA
1.942V    -21.71mA   -21.06mA   -21.71mA
2.402V    -51.93mA   -50.37mA   -51.93mA
2.586V    -97.2mA    -94.3mA    -97.2mA
3V        -297.4mA   -288.5mA   -297.4mA
[Ramp]
| variable   typ   min   max
dV/dt_r   0.464/0.312n   0.441/0.337n   0.479/0.376n
dV/dt_f   0.481/0.334n   0.459/0.332n   0.494/0.414n
R_load = 50.000
[Rising Waveform]
R_fixture = 50.000
V_fixture = 0.000
V_fixture_min = 0.000
V_fixture_max = 0.000
|  time   V(typ)   V(min)   V(max)
0s        65.26uV    -267.6uV   -371.3uV
351ps     378.8uV    -244uV     -4.787mV
471ps     3.114mV    -191.8uV   347.3mV
569ps     205.1mV    57.77uV    494.5mV
710ps     493.4mV    2.903mV    603.4mV
901ps     637.9mV    364.1mV    677.8mV
1ns       672.5mV    496.1mV    700.5mV
1.339ns   725.5mV    653.9mV    743.2mV
2.62ns    761mV      720.4mV    784.2mV
10ns      773.6mV    735.2mV    798.5mV
[Rising Waveform]
R_fixture = 50.000
V_fixture = 1.500
V_fixture_min = 1.430
V_fixture_max = 1.580
|  time   V(typ)   V(min)   V(max)
0s        697.7mV    664.5mV    757.8mV
336ps     697.8mV    664.6mV    763.2mV
448ps     710.1mV    664.8mV    1.277V
568ps     1.175V     661.9mV    1.437V
659ps     1.342V     676.6mV    1.483V
701ps     1.376V     747.4mV    1.496V
830ps     1.429V     1.174V     1.523V
970ps     1.454V     1.321V     1.539V
1.928ns   1.488V     1.417V     1.569V
10ns      1.5V       1.43V      1.581V
[Falling Waveform]
R_fixture = 50.000
V_fixture = 1.500
V_fixture_min = 1.430
V_fixture_max = 1.580
|  time   V(typ)   V(min)   V(max)
0s        1.5V       1.43V      1.581V
356ps     1.5V       1.43V      1.581V
471ps     1.496V     1.43V      1.263V
671ps     1.032V     1.43V      1.011V
862ps     860.2mV    1.043V     911.5mV
961ps     817.2mV    909.5mV    881.1mV
1.151ns   771.6mV    791.1mV    843.8mV
1.401ns   744.4mV    729.6mV    816.3mV
2.969ns   708.7mV    675.6mV    770mV
10ns      697.7mV    664.5mV    757.8mV
[Falling Waveform]
R_fixture = 50.000
V_fixture = 0.000
V_fixture_min = 0.000
V_fixture_max = 0.000
|  time   V(typ)   V(min)   V(max)
0s        773.6mV    735.2mV    798.5mV
351ps     773.5mV    735.1mV    794.9mV
451ps     772.6mV    735.2mV    290.7mV
481ps     708.1mV    735mV      223.2mV
571ps     270.1mV    737.1mV    128.2mV
661ps     131.5mV    730.1mV    86.39mV
811ps     66.54mV    224.9mV    53.59mV
951ps     43.14mV    94.07mV    38.85mV
1.891ns   12.01mV    11.93mV    11.16mV
10ns      65.26uV    -267.6uV   -371.3uV
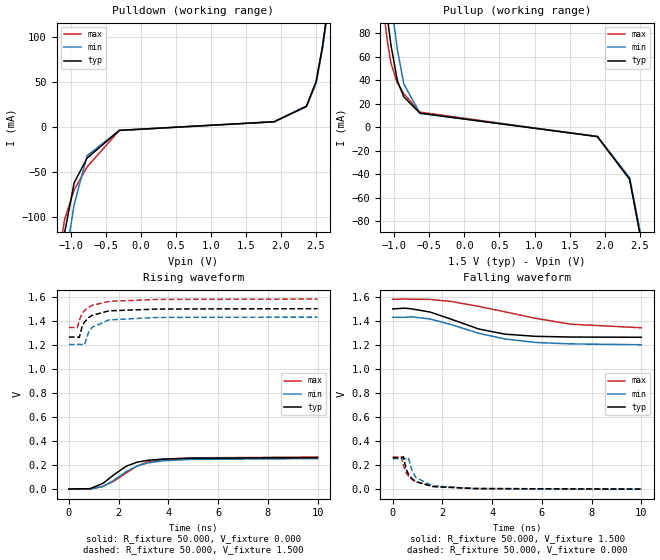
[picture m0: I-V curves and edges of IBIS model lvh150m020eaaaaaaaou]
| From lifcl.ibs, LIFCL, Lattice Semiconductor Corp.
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[Model] lvh150m020eaaaaaaaou
Model_type Output
Polarity   Non-Inverting
Enable   Active-High
Vmeas =  0.750V
Cref =  0.0F
Rref =  1.000M
Vref =  0.0V
C_comp   5.000pF   4.000pF   5.500pF
[Temperature Range]   25.000   0.125k   -40.000
[Voltage Range]   1.500V   1.430V   1.580V
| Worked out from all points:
|   slope of the pulldown table from 0 to 0.225 V, typ, clamps not added: 110 ohm
|   slope of the pullup table from 0 to 0.225 V, typ, clamps not added: 114 ohm
|   rising waveform, R_fixture 50.000, V_fixture 0.000: 20-80 % time 1.11ns typ, 1.27ns min, 1.27ns max; typ from 0 V to 0.261 V
|   rising waveform, R_fixture 50.000, V_fixture 1.500: 20-80 % time 537ps typ, 516ps min, 594ps max; typ from 1.26 V to 1.5 V
|   falling waveform, R_fixture 50.000, V_fixture 1.500: 20-80 % time 2.06ns typ, 2.45ns min, 3.37ns max; typ from 1.5 V to 1.26 V
|   falling waveform, R_fixture 50.000, V_fixture 0.000: 20-80 % time 533ps typ, 522ps min, 603ps max; typ from 0.262 V to 0.001 V
[Pulldown]
|Voltage   I(typ)   I(min)   I(max)
-1.5V     -381.2mA   -398.5mA   -369.5mA
-1.224V   -198.4mA   -231.2mA   -177.7mA
-1.086V   -117.9mA   -153.6mA   -102.9mA
-948mV    -61.75mA   -86mA      -69.76mA
-764mV    -34.4mA    -31.77mA   -44.22mA
-304mV    -3.563mA   -3.619mA   -3.717mA
1.904V    6.038mA    5.856mA    6.038mA
2.364V    23.29mA    22.59mA    23.29mA
2.502V    50.57mA    49.05mA    50.57mA
2.594V    90.1mA     87.4mA     90.1mA
2.732V    168.6mA    163.5mA    168.6mA
3V        342.5mA    332.2mA    342.5mA
[Pullup]
|Voltage   I(typ)   I(min)   I(max)
-1.5V     341.5mA    374.7mA    322.6mA
-1.186V   141.4mA    182mA      117.9mA
-1.14V    115.3mA    155.9mA    92.8mA
-1.094V   91.2mA     130.7mA    71.23mA
-1.048V   69.93mA    107mA      54.61mA
-956mV    39.5mA     65.87mA    37.33mA
-864mV    25.74mA    36.76mA    28.41mA
-634mV    11.91mA    11.82mA    12.78mA
1.896V    -8.049mA   -7.808mA   -8.049mA
2.356V    -44.37mA   -43.04mA   -44.37mA
2.586V    -117.1mA   -113.6mA   -117.1mA
3V        -379mA     -367.6mA   -379mA
[Ramp]
| variable   typ   min   max
dV/dt_r   0.158/1.150n   0.152/1.295n   0.159/1.302n
dV/dt_f   0.142/2.117n   0.137/2.528n   0.142/3.392n
R_load = 50.000
[Rising Waveform]
R_fixture = 50.000
V_fixture = 0.000
V_fixture_min = 0.000
V_fixture_max = 0.000
|  time   V(typ)   V(min)   V(max)
0s        31.62uV    109.6uV    354.2uV
848ps     3.182mV    -1.025mV   1.503mV
1.367ns   47.24mV    21.45mV    21.97mV
1.777ns   113.8mV    69.46mV    61.35mV
2.297ns   189.3mV    144.7mV    133.3mV
2.729ns   222.7mV    189.9mV    190.1mV
3.16ns    238.7mV    216.6mV    224.6mV
3.781ns   249.1mV    235.3mV    247mV
4.868ns   255.8mV    246.4mV    259.2mV
10ns      261.1mV    253.4mV    266mV
[Rising Waveform]
R_fixture = 50.000
V_fixture = 1.500
V_fixture_min = 1.430
V_fixture_max = 1.580
|  time   V(typ)   V(min)   V(max)
0s        1.264V     1.202V     1.343V
334ps     1.264V     1.203V     1.343V
417ps     1.261V     1.203V     1.403V
527ps     1.35V      1.202V     1.459V
626ps     1.39V      1.199V     1.485V
786ps     1.425V     1.302V     1.511V
927ps     1.444V     1.345V     1.527V
1.607ns   1.482V     1.407V     1.561V
3.556ns   1.497V     1.427V     1.577V
10ns      1.5V       1.43V      1.58V
[Falling Waveform]
R_fixture = 50.000
V_fixture = 1.500
V_fixture_min = 1.430
V_fixture_max = 1.580
|  time   V(typ)   V(min)   V(max)
0s        1.5V       1.43V      1.58V
497ps     1.506V     1.43V      1.582V
735ps     1.501V     1.435V     1.581V
1.504ns   1.474V     1.416V     1.579V
2.315ns   1.417V     1.372V     1.563V
3.461ns   1.333V     1.297V     1.521V
4.511ns   1.29V      1.25V      1.476V
5.741ns   1.272V     1.221V     1.422V
7.154ns   1.266V     1.209V     1.373V
10ns      1.264V     1.202V     1.343V
[Falling Waveform]
R_fixture = 50.000
V_fixture = 0.000
V_fixture_min = 0.000
V_fixture_max = 0.000
|  time   V(typ)   V(min)   V(max)
0s        262.1mV    253.4mV    266mV
346ps     261.7mV    253.2mV    269.9mV
433ps     269.3mV    253.4mV    197.3mV
537ps     168.7mV    253.6mV    138mV
635ps     122.8mV    261.1mV    107.8mV
779ps     86.87mV    152.6mV    79.94mV
934ps     63.01mV    96.88mV    61.02mV
1.606ns   21.76mV    26.51mV    25.35mV
3.301ns   5.001mV    5.265mV    5.014mV
10ns      532.5uV    109.6uV    354.2uV
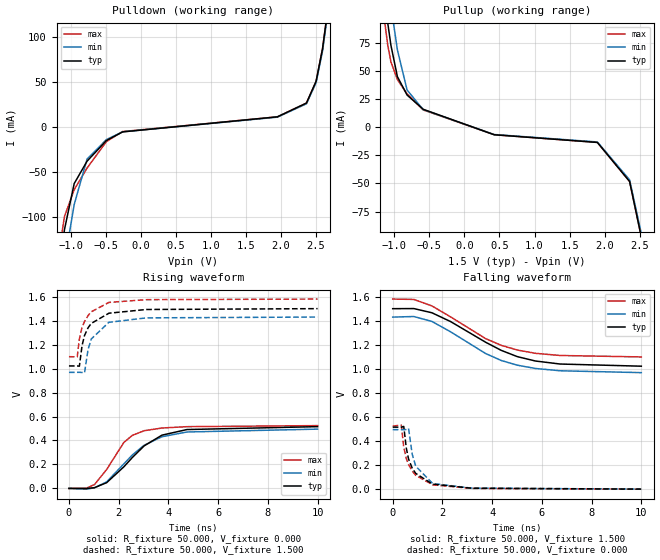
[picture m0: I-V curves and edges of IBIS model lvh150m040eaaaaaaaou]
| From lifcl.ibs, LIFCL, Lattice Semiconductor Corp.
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[Model] lvh150m040eaaaaaaaou
Model_type Output
Polarity   Non-Inverting
Enable   Active-High
Vmeas =  0.750V
Cref =  0.0F
Rref =  1.000M
Vref =  0.0V
C_comp   5.000pF   4.000pF   5.500pF
[Temperature Range]   25.000   0.125k   -40.000
[Voltage Range]   1.500V   1.430V   1.580V
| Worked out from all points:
|   slope of the pulldown table from 0 to 0.225 V, typ, clamps not added: 54.3 ohm
|   slope of the pullup table from 0 to 0.225 V, typ, clamps not added: 56 ohm
|   rising waveform, R_fixture 50.000, V_fixture 0.000: 20-80 % time 1.57ns typ, 1.57ns min, 1.04ns max; typ from 0 V to 0.515 V
|   rising waveform, R_fixture 50.000, V_fixture 1.500: 20-80 % time 551ps typ, 511ps min, 560ps max; typ from 1.02 V to 1.5 V
|   falling waveform, R_fixture 50.000, V_fixture 1.500: 20-80 % time 2.57ns typ, 2.39ns min, 2.45ns max; typ from 1.5 V to 1.02 V
|   falling waveform, R_fixture 50.000, V_fixture 0.000: 20-80 % time 546ps typ, 508ps min, 573ps max; typ from 0.515 V to 0 V
[Pulldown]
|Voltage   I(typ)   I(min)   I(max)
-1.5V     -361.3mA   -385.8mA   -347.6mA
-1.224V   -189.2mA   -224.9mA   -168.3mA
-1.086V   -113.8mA   -150.3mA   -99.3mA
-948mV    -62.81mA   -86.1mA    -69.57mA
-764mV    -37.82mA   -35.45mA   -45.51mA
-488mV    -14.9mA    -13.82mA   -16.03mA
-258mV    -5.294mA   -5.21mA    -4.909mA
1.95V     11.47mA    11.12mA    11.47mA
2.364V    26.78mA    25.97mA    26.78mA
2.502V    51.05mA    49.51mA    51.05mA
2.594V    87.5mA     84.9mA     87.5mA
3V        324.7mA    315mA      324.7mA
[Pullup]
|Voltage   I(typ)   I(min)   I(max)
-1.5V     334.2mA    366.8mA    315.2mA
-1.186V   140.5mA    179.9mA    117.2mA
-1.094V   92.7mA     130.5mA    73.11mA
-1.048V   72.68mA    107.9mA    57.95mA
-956mV    44.92mA    68.74mA    42.37mA
-818mV    28.55mA    33.04mA    29.55mA
-588mV    15.88mA    15.55mA    15.32mA
424mV     -6.746mA   -6.543mA   -6.746mA
1.896V    -13.58mA   -13.17mA   -13.58mA
2.356V    -48.31mA   -46.87mA   -48.31mA
2.586V    -116.3mA   -112.8mA   -116.3mA
3V        -369.7mA   -358.6mA   -369.7mA
[Ramp]
| variable   typ   min   max
dV/dt_r   0.309/1.614n   0.296/1.589n   0.315/1.100n
dV/dt_f   0.287/2.626n   0.277/2.486n   0.289/2.547n
R_load = 50.000
[Rising Waveform]
R_fixture = 50.000
V_fixture = 0.000
V_fixture_min = 0.000
V_fixture_max = 0.000
|  time   V(typ)   V(min)   V(max)
0s        60.93uV    340.6uV    -204uV
696ps     -1.299mV   -6.237mV   1.662mV
1.029ns   6.351mV    5.101mV    32.35mV
1.517ns   48.14mV    54.86mV    158.2mV
2.208ns   180.2mV    204.6mV    383.9mV
2.548ns   257.7mV    278.9mV    442.6mV
3.025ns   355mV      360.3mV    481.5mV
3.738ns   444.3mV    431.1mV    504mV
4.745ns   491.2mV    470.9mV    515.3mV
10ns      515.5mV    494.8mV    524.1mV
[Rising Waveform]
R_fixture = 50.000
V_fixture = 1.500
V_fixture_min = 1.430
V_fixture_max = 1.580
|  time   V(typ)   V(min)   V(max)
0s        1.022V     968.4mV    1.099V
333ps     1.022V     968.6mV    1.098V
419ps     1.02V      968.7mV    1.248V
527ps     1.192V     967.5mV    1.343V
626ps     1.276V     963.8mV    1.393V
768ps     1.34V      1.16V      1.442V
898ps     1.377V     1.247V     1.474V
1.607ns   1.462V     1.386V     1.552V
3.111ns   1.493V     1.423V     1.575V
10ns      1.5V       1.43V      1.58V
[Falling Waveform]
R_fixture = 50.000
V_fixture = 1.500
V_fixture_min = 1.430
V_fixture_max = 1.580
|  time   V(typ)   V(min)   V(max)
0s        1.5V       1.43V      1.58V
849ps     1.501V     1.435V     1.577V
1.578ns   1.466V     1.394V     1.523V
2.327ns   1.393V     1.308V     1.432V
3.739ns   1.221V     1.127V     1.251V
4.371ns   1.153V     1.069V     1.195V
5.02ns    1.101V     1.03V      1.156V
5.743ns   1.065V     1.003V     1.129V
6.735ns   1.04V      983.9mV    1.111V
10ns      1.022V     968.4mV    1.099V
[Falling Waveform]
R_fixture = 50.000
V_fixture = 0.000
V_fixture_min = 0.000
V_fixture_max = 0.000
|  time   V(typ)   V(min)   V(max)
0s        515.5mV    494.8mV    524.1mV
346ps     515mV      494.5mV    532.5mV
444ps     521.3mV    494.7mV    350.6mV
547ps     341.2mV    495.8mV    254.7mV
637ps     250.5mV    504.6mV    204.7mV
787ps     173.3mV    288mV      149.8mV
927ps     130.4mV    190.6mV    114.6mV
1.607ns   41.35mV    46.78mV    35.98mV
3.169ns   7.893mV    8.406mV    5.978mV
10ns      60.93uV    340.6uV    -204uV
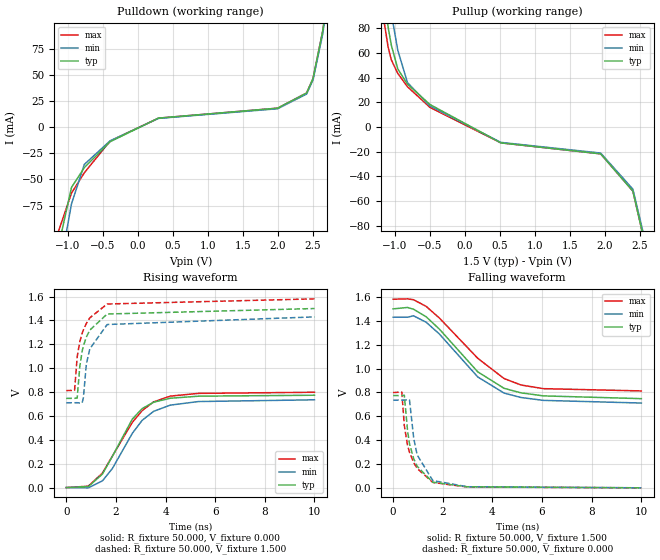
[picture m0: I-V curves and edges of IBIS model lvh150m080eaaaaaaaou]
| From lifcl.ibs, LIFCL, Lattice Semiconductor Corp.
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[Model] lvh150m080eaaaaaaaou
Model_type Output
Polarity   Non-Inverting
Enable   Active-High
Vmeas =  0.750V
Cref =  0.0F
Rref =  1.000M
Vref =  0.0V
C_comp   5.000pF   4.000pF   5.500pF
[Temperature Range]   25.000   0.125k   -40.000
[Voltage Range]   1.500V   1.430V   1.580V
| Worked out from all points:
|   slope of the pulldown table from 0 to 0.225 V, typ, clamps not added: 33.4 ohm
|   slope of the pullup table from 0 to 0.225 V, typ, clamps not added: 34 ohm
|   rising waveform, R_fixture 50.000, V_fixture 0.000: 20-80 % time 1.25ns typ, 1.36ns min, 1.45ns max; typ from 0 V to 0.774 V
|   rising waveform, R_fixture 50.000, V_fixture 1.500: 20-80 % time 538ps typ, 516ps min, 581ps max; typ from 0.747 V to 1.5 V
|   falling waveform, R_fixture 50.000, V_fixture 1.500: 20-80 % time 2.08ns typ, 1.99ns min, 2.24ns max; typ from 1.5 V to 0.747 V
|   falling waveform, R_fixture 50.000, V_fixture 0.000: 20-80 % time 512ps typ, 486ps min, 572ps max; typ from 0.774 V to 0 V
[Pulldown]
|Voltage   I(typ)   I(min)   I(max)
-1.5V     -291.6mA   -309.8mA   -281.8mA
-1.27V    -176.2mA   -202.8mA   -160.3mA
-1.132V   -113.7mA   -142.2mA   -99.4mA
-948mV    -57.73mA   -73.5mA    -63.19mA
-764mV    -38.74mA   -35.69mA   -43.63mA
-396mV    -14.01mA   -13.16mA   -13.36mA
294mV     8.536mA    8.28mA     8.536mA
1.996V    18.06mA    17.52mA    18.06mA
2.41V     32.54mA    31.57mA    32.54mA
2.502V    46.35mA    44.96mA    46.35mA
2.64V     91.5mA     88.8mA     91.5mA
3V        261.8mA    253.9mA    261.8mA
[Pullup]
|Voltage   I(typ)   I(min)   I(max)
-1.5V     270.5mA    296.8mA    254.1mA
-1.186V   117.5mA    148.3mA    97.8mA
-1.094V   81mA       109.7mA    64.93mA
-1.048V   66.37mA    92mA       54.42mA
-956mV    47.16mA    62.34mA    43.5mA
-818mV    34.79mA    36.11mA    32.74mA
-496mV    18.28mA    17.11mA    15.93mA
516mV     -12.8mA    -12.42mA   -12.8mA
1.942V    -21.71mA   -21.06mA   -21.71mA
2.402V    -51.93mA   -50.37mA   -51.93mA
2.586V    -97.2mA    -94.3mA    -97.2mA
3V        -297.4mA   -288.5mA   -297.4mA
[Ramp]
| variable   typ   min   max
dV/dt_r   0.464/1.261n   0.441/1.390n   0.479/1.464n
dV/dt_f   0.452/2.122n   0.432/2.007n   0.461/2.313n
R_load = 50.000
[Rising Waveform]
R_fixture = 50.000
V_fixture = 0.000
V_fixture_min = 0.000
V_fixture_max = 0.000
|  time   V(typ)   V(min)   V(max)
0s        61.38uV    -313.3uV   -329.7uV
888ps     7.937mV    -2.492mV   11.47mV
1.458ns   112.5mV    56.1mV     121.3mV
1.861ns   262.8mV    160.3mV    264.7mV
2.663ns   573.8mV    454.5mV    546.3mV
3.058ns   661.5mV    563mV      644.4mV
3.521ns   715.1mV    638.7mV    718.1mV
4.189ns   748.2mV    690.6mV    766.1mV
5.33ns    765.6mV    720.7mV    789.1mV
10ns      773.6mV    735.2mV    798.5mV
[Rising Waveform]
R_fixture = 50.000
V_fixture = 1.500
V_fixture_min = 1.430
V_fixture_max = 1.580
|  time   V(typ)   V(min)   V(max)
0s        747.4mV    710.6mV    812.2mV
336ps     747.7mV    710.6mV    814.8mV
441ps     750.2mV    710.9mV    1.095V
548ps     1.016V     708.5mV    1.224V
640ps     1.142V     708.3mV    1.292V
691ps     1.186V     754mV      1.321V
811ps     1.261V     1.035V     1.375V
950ps     1.319V     1.162V     1.422V
1.648ns   1.454V     1.366V     1.538V
10ns      1.5V       1.43V      1.581V
[Falling Waveform]
R_fixture = 50.000
V_fixture = 1.500
V_fixture_min = 1.430
V_fixture_max = 1.580
|  time   V(typ)   V(min)   V(max)
0s        1.5V       1.43V      1.581V
581ps     1.512V     1.43V      1.584V
821ps     1.497V     1.442V     1.577V
1.331ns   1.434V     1.388V     1.521V
1.861ns   1.331V     1.29V      1.424V
3.409ns   972.5mV    929.5mV    1.086V
4.47ns    834mV      794.1mV    916.1mV
5.148ns   796.3mV    757.3mV    862.1mV
6.054ns   770.7mV    733mV      831.2mV
10ns      747.4mV    710.6mV    812.2mV
[Falling Waveform]
R_fixture = 50.000
V_fixture = 0.000
V_fixture_min = 0.000
V_fixture_max = 0.000
|  time   V(typ)   V(min)   V(max)
0s        773.6mV    735.2mV    798.5mV
351ps     773.3mV    735.1mV    802.6mV
451ps     776.7mV    735.2mV    522.7mV
581ps     479.4mV    738.9mV    357.1mV
660ps     369.7mV    736.9mV    297.3mV
831ps     243.5mV    413.4mV    210.7mV
971ps     179.4mV    274.9mV    161.8mV
1.599ns   46.74mV    60.84mV    45mV
2.989ns   8.515mV    8.978mV    6.923mV
10ns      61.38uV    -313.3uV   -329.7uV
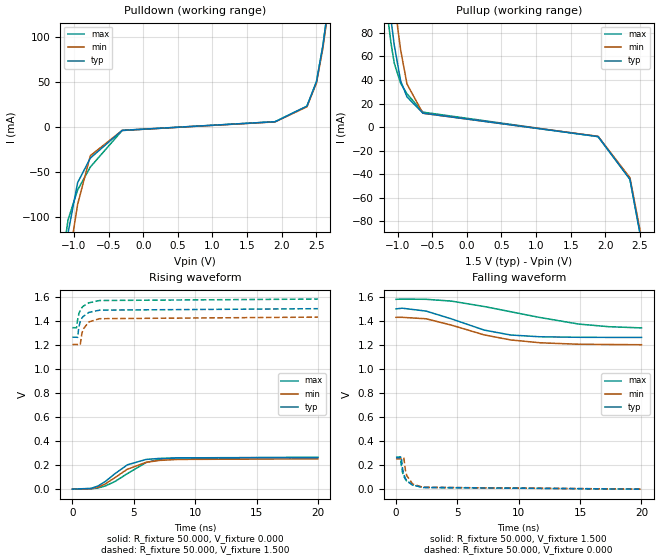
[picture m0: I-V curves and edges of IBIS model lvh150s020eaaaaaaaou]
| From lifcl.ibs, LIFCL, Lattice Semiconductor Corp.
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[Model] lvh150s020eaaaaaaaou
Model_type Output
Polarity   Non-Inverting
Enable   Active-High
Vmeas =  0.750V
Cref =  0.0F
Rref =  1.000M
Vref =  0.0V
C_comp   5.000pF   4.000pF   5.500pF
[Temperature Range]   25.000   0.125k   -40.000
[Voltage Range]   1.500V   1.430V   1.580V
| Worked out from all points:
|   slope of the pulldown table from 0 to 0.225 V, typ, clamps not added: 110 ohm
|   slope of the pullup table from 0 to 0.225 V, typ, clamps not added: 114 ohm
|   rising waveform, R_fixture 50.000, V_fixture 0.000: 20-80 % time 2.1ns typ, 2.46ns min, 2.5ns max; typ from 0 V to 0.262 V
|   rising waveform, R_fixture 50.000, V_fixture 1.500: 20-80 % time 569ps typ, 544ps min, 613ps max; typ from 1.26 V to 1.5 V
|   falling waveform, R_fixture 50.000, V_fixture 1.500: 20-80 % time 4.24ns typ, 5.06ns min, 7.3ns max; typ from 1.5 V to 1.26 V
|   falling waveform, R_fixture 50.000, V_fixture 0.000: 20-80 % time 562ps typ, 549ps min, 607ps max; typ from 0.262 V to 0 V
[Pulldown]
|Voltage   I(typ)   I(min)   I(max)
-1.5V     -382mA     -398.8mA   -370.9mA
-1.224V   -198.8mA   -231.5mA   -178.5mA
-1.086V   -118.1mA   -153.7mA   -103.3mA
-948mV    -61.9mA    -86.2mA    -70.06mA
-764mV    -34.48mA   -31.79mA   -44.41mA
-304mV    -3.572mA   -3.622mA   -3.733mA
1.904V    6.052mA    5.87mA     6.052mA
2.364V    23.34mA    22.64mA    23.34mA
2.502V    50.69mA    49.17mA    50.69mA
2.594V    90.4mA     87.7mA     90.4mA
2.732V    169.1mA    164mA      169.1mA
3V        343.3mA    333mA      343.3mA
[Pullup]
|Voltage   I(typ)   I(min)   I(max)
-1.5V     340.1mA    373.1mA    321.3mA
-1.186V   140.8mA    181.2mA    117.4mA
-1.14V    114.9mA    155.2mA    92.3mA
-1.094V   90.9mA     130.2mA    70.93mA
-1.048V   69.63mA    106.6mA    54.37mA
-956mV    39.33mA    65.59mA    37.17mA
-864mV    25.63mA    36.6mA     28.29mA
-634mV    11.86mA    11.77mA    12.72mA
1.896V    -8.015mA   -7.774mA   -8.015mA
2.356V    -44.18mA   -42.85mA   -44.18mA
2.586V    -116.6mA   -113.1mA   -116.6mA
3V        -377.3mA   -366mA     -377.3mA
[Ramp]
| variable   typ   min   max
dV/dt_r   0.157/2.142n   0.151/2.452n   0.159/2.555n
dV/dt_f   0.142/4.252n   0.137/5.059n   0.143/7.304n
R_load = 50.000
[Rising Waveform]
R_fixture = 50.000
V_fixture = 0.000
V_fixture_min = 0.000
V_fixture_max = 0.000
|  time   V(typ)   V(min)   V(max)
0s        58.69uV    104uV      362.5uV
1.528ns   6.909mV    4.444mV    2.505mV
2.087ns   26.42mV    17.26mV    9.993mV
2.681ns   63.86mV    43.71mV    26.84mV
3.448ns   127.6mV    95.29mV    62.75mV
4.48ns    202.6mV    166mV      129.6mV
6.001ns   247.1mV    223.1mV    221.6mV
7.104ns   255.9mV    239mV      249mV
8.605ns   259.8mV    247.3mV    260.1mV
20ns      262.4mV    252.4mV    264.9mV
[Rising Waveform]
R_fixture = 50.000
V_fixture = 1.500
V_fixture_min = 1.430
V_fixture_max = 1.580
|  time   V(typ)   V(min)   V(max)
0s        1.263V     1.202V     1.342V
334ps     1.263V     1.203V     1.342V
420ps     1.261V     1.202V     1.405V
528ps     1.35V      1.202V     1.459V
636ps     1.393V     1.2V       1.486V
766ps     1.421V     1.291V     1.508V
858ps     1.434V     1.328V     1.519V
1.338ns   1.469V     1.39V      1.549V
2.217ns   1.488V     1.417V     1.568V
20ns      1.5V       1.43V      1.58V
[Falling Waveform]
R_fixture = 50.000
V_fixture = 1.500
V_fixture_min = 1.430
V_fixture_max = 1.580
|  time   V(typ)   V(min)   V(max)
0s        1.5V       1.43V      1.58V
497ps     1.506V     1.43V      1.582V
2.452ns   1.482V     1.418V     1.58V
4.521ns   1.417V     1.365V     1.565V
7.181ns   1.324V     1.284V     1.52V
9.329ns   1.283V     1.242V     1.477V
11.76ns   1.268V     1.218V     1.428V
14.89ns   1.264V     1.206V     1.374V
17.33ns   1.263V     1.204V     1.352V
20ns      1.263V     1.202V     1.342V
[Falling Waveform]
R_fixture = 50.000
V_fixture = 0.000
V_fixture_min = 0.000
V_fixture_max = 0.000
|  time   V(typ)   V(min)   V(max)
0s        262.4mV    252.4mV    264.9mV
346ps     262mV      252.1mV    269.2mV
433ps     270.4mV    252.3mV    197mV
537ps     169.4mV    252.5mV    137.8mV
635ps     123.1mV    260.8mV    107.7mV
775ps     88.01mV    154.9mV    80.53mV
877ps     71.59mV    112.4mV    67.09mV
1.355ns   34.3mV     43.23mV    34.59mV
2.206ns   14.03mV    15.17mV    15.25mV
20ns      58.69uV    104uV      362.5uV
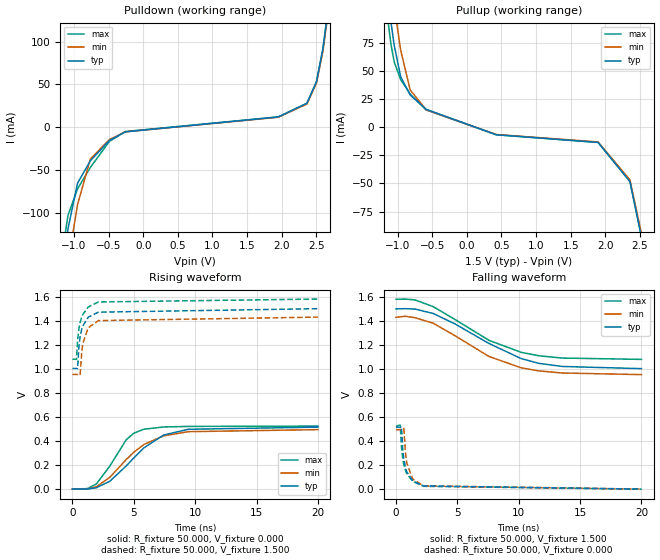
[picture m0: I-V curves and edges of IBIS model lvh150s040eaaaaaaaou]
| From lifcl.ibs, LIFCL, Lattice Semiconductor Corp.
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[Model] lvh150s040eaaaaaaaou
Model_type Output
Polarity   Non-Inverting
Enable   Active-High
Vmeas =  0.750V
Cref =  0.0F
Rref =  1.000M
Vref =  0.0V
C_comp   5.000pF   4.000pF   5.500pF
[Temperature Range]   25.000   0.125k   -40.000
[Voltage Range]   1.500V   1.430V   1.580V
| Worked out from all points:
|   slope of the pulldown table from 0 to 0.225 V, typ, clamps not added: 52.2 ohm
|   slope of the pullup table from 0 to 0.225 V, typ, clamps not added: 56 ohm
|   rising waveform, R_fixture 50.000, V_fixture 0.000: 20-80 % time 3.21ns typ, 3.19ns min, 1.97ns max; typ from 0 V to 0.515 V
|   rising waveform, R_fixture 50.000, V_fixture 1.500: 20-80 % time 568ps typ, 544ps min, 611ps max; typ from 1 V to 1.5 V
|   falling waveform, R_fixture 50.000, V_fixture 1.500: 20-80 % time 5.43ns typ, 4.98ns min, 5.14ns max; typ from 1.5 V to 1 V
|   falling waveform, R_fixture 50.000, V_fixture 0.000: 20-80 % time 559ps typ, 544ps min, 606ps max; typ from 0.515 V to 0 V
[Pulldown]
|Voltage   I(typ)   I(min)   I(max)
-1.5V     -375.9mA   -405mA     -360mA
-1.224V   -196.9mA   -236.1mA   -174.2mA
-1.086V   -118.5mA   -157.8mA   -102.9mA
-948mV    -65.35mA   -90.4mA    -72.03mA
-764mV    -39.35mA   -37.22mA   -47.13mA
-488mV    -15.5mA    -14.51mA   -16.6mA
-258mV    -5.508mA   -5.47mA    -5.083mA
1.95V     11.93mA    11.57mA    11.93mA
2.364V    27.86mA    27.03mA    27.86mA
2.502V    53.11mA    51.52mA    53.11mA
2.594V    91mA       88.3mA     91mA
3V        337.8mA    327.7mA    337.8mA
[Pullup]
|Voltage   I(typ)   I(min)   I(max)
-1.5V     334.2mA    366.8mA    315.2mA
-1.186V   140.5mA    179.9mA    117.2mA
-1.094V   92.7mA     130.5mA    73.11mA
-1.048V   72.68mA    107.9mA    57.95mA
-956mV    44.92mA    68.74mA    42.37mA
-818mV    28.55mA    33.04mA    29.55mA
-588mV    15.88mA    15.55mA    15.32mA
424mV     -6.746mA   -6.543mA   -6.746mA
1.896V    -13.58mA   -13.17mA   -13.58mA
2.356V    -48.31mA   -46.87mA   -48.31mA
2.586V    -116.3mA   -112.8mA   -116.3mA
3V        -369.7mA   -358.6mA   -369.7mA
[Ramp]
| variable   typ   min   max
dV/dt_r   0.309/3.231n   0.296/3.213n   0.315/2.014n
dV/dt_f   0.298/5.467n   0.287/4.991n   0.300/5.158n
R_load = 50.000
[Rising Waveform]
R_fixture = 50.000
V_fixture = 0.000
V_fixture_min = 0.000
V_fixture_max = 0.000
|  time   V(typ)   V(min)   V(max)
0s        59.51uV    338.2uV    -234.1uV
1.227ns   828.9uV    1.887mV    4.59mV
1.946ns   11.53mV    19.69mV    42.82mV
3.051ns   65.77mV    98.49mV    192.4mV
4.381ns   192.5mV    245.6mV    410mV
4.989ns   258.3mV    305.9mV    464mV
5.83ns    343.5mV    371.4mV    498.3mV
7.435ns   450.2mV    443.4mV    516.8mV
9.441ns   497.5mV    477.6mV    521.4mV
20ns      515.5mV    494.8mV    524.1mV
[Rising Waveform]
R_fixture = 50.000
V_fixture = 1.500
V_fixture_min = 1.430
V_fixture_max = 1.580
|  time   V(typ)   V(min)   V(max)
0s        1.003V     953.1mV    1.08V
334ps     1.003V     953.3mV    1.079V
417ps     1V         953.4mV    1.231V
527ps     1.18V      952.1mV    1.333V
627ps     1.268V     948.1mV    1.385V
756ps     1.329V     1.137V     1.43V
837ps     1.355V     1.208V     1.45V
1.286ns   1.429V     1.341V     1.514V
2.116ns   1.471V     1.401V     1.556V
20ns      1.5V       1.43V      1.58V
[Falling Waveform]
R_fixture = 50.000
V_fixture = 1.500
V_fixture_min = 1.430
V_fixture_max = 1.580
|  time   V(typ)   V(min)   V(max)
0s        1.5V       1.43V      1.58V
727ps     1.502V     1.439V     1.582V
1.547ns   1.499V     1.427V     1.575V
3.031ns   1.462V     1.381V     1.519V
4.79ns    1.376V     1.278V     1.413V
7.583ns   1.212V     1.104V     1.238V
10.19ns   1.087V     1.01V      1.139V
11.63ns   1.047V     984.2mV    1.11V
13.55ns   1.021V     966.6mV    1.091V
20ns      1.003V     953.1mV    1.08V
[Falling Waveform]
R_fixture = 50.000
V_fixture = 0.000
V_fixture_min = 0.000
V_fixture_max = 0.000
|  time   V(typ)   V(min)   V(max)
0s        515.5mV    494.8mV    524.1mV
346ps     515mV      494.5mV    533.6mV
444ps     521.9mV    494.7mV    351.5mV
547ps     341.9mV    495.8mV    255.4mV
637ps     251mV      505.5mV    205.3mV
780ps     176.5mV    297mV      153.3mV
879ps     143.9mV    216.3mV    128.6mV
1.367ns   67.93mV    83.19mV    64.91mV
2.257ns   27.23mV    26.69mV    23.4mV
20ns      59.51uV    338.2uV    -234.1uV
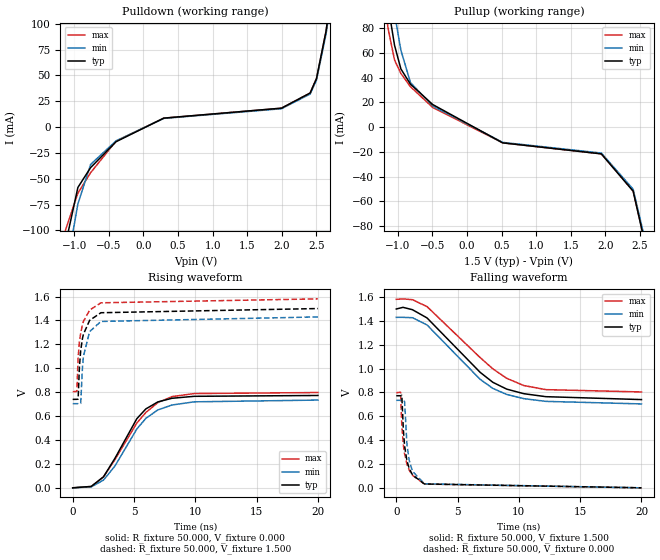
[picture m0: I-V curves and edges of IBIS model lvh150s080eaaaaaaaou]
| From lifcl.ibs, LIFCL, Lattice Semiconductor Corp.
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[Model] lvh150s080eaaaaaaaou
Model_type Output
Polarity   Non-Inverting
Enable   Active-High
Vmeas =  0.750V
Cref =  0.0F
Rref =  1.000M
Vref =  0.0V
C_comp   5.000pF   4.000pF   5.500pF
[Temperature Range]   25.000   0.125k   -40.000
[Voltage Range]   1.500V   1.430V   1.580V
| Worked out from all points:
|   slope of the pulldown table from 0 to 0.225 V, typ, clamps not added: 32.9 ohm
|   slope of the pullup table from 0 to 0.225 V, typ, clamps not added: 34.1 ohm
|   rising waveform, R_fixture 50.000, V_fixture 0.000: 20-80 % time 2.61ns typ, 2.82ns min, 3.04ns max; typ from 0 V to 0.773 V
|   rising waveform, R_fixture 50.000, V_fixture 1.500: 20-80 % time 568ps typ, 545ps min, 610ps max; typ from 0.74 V to 1.5 V
|   falling waveform, R_fixture 50.000, V_fixture 1.500: 20-80 % time 4.42ns typ, 4.22ns min, 4.78ns max; typ from 1.5 V to 0.74 V
|   falling waveform, R_fixture 50.000, V_fixture 0.000: 20-80 % time 555ps typ, 545ps min, 601ps max; typ from 0.773 V to 0 V
[Pulldown]
|Voltage   I(typ)   I(min)   I(max)
-1.5V     -295.2mA   -313.9mA   -285.3mA
-1.27V    -178.5mA   -205.5mA   -162.4mA
-1.132V   -115.1mA   -144.2mA   -100.7mA
-948mV    -58.46mA   -74.4mA    -63.98mA
-764mV    -39.23mA   -36.17mA   -44.18mA
-396mV    -14.18mA   -13.34mA   -13.53mA
294mV     8.644mA    8.385mA    8.644mA
1.996V    18.29mA    17.74mA    18.29mA
2.41V     32.95mA    31.96mA    32.95mA
2.502V    46.94mA    45.53mA    46.94mA
2.64V     92.7mA     89.9mA     92.7mA
3V        265.2mA    257.2mA    265.2mA
[Pullup]
|Voltage   I(typ)   I(min)   I(max)
-1.5V     270mA      296.1mA    253.6mA
-1.186V   117.3mA    148mA      97.6mA
-1.14V    98.1mA     128.2mA    79.5mA
-1.048V   66.23mA    91.8mA     54.31mA
-956mV    47.06mA    62.21mA    43.41mA
-818mV    34.72mA    36.03mA    32.67mA
-496mV    18.24mA    17.08mA    15.9mA
516mV     -12.78mA   -12.39mA   -12.78mA
1.942V    -21.67mA   -21.02mA   -21.67mA
2.402V    -51.82mA   -50.27mA   -51.82mA
2.586V    -97mA      -94.1mA    -97mA
3V        -296.8mA   -287.9mA   -296.8mA
[Ramp]
| variable   typ   min   max
dV/dt_r   0.463/2.622n   0.441/2.853n   0.479/3.051n
dV/dt_f   0.456/4.427n   0.436/4.230n   0.466/4.797n
R_load = 50.000
[Rising Waveform]
R_fixture = 50.000
V_fixture = 0.000
V_fixture_min = 0.000
V_fixture_max = 0.000
|  time   V(typ)   V(min)   V(max)
0s        63.14uV    -308.4uV   -331uV
1.51ns    11.48mV    7.496mV    10.98mV
2.508ns   91.9mV     64.4mV     90.16mV
3.432ns   244.6mV    180.4mV    233.8mV
5.23ns    578.3mV    491.8mV    542.2mV
5.965ns   660.1mV    581.3mV    630.3mV
6.941ns   718.6mV    651.5mV    712.9mV
8.097ns   749.2mV    692.9mV    763mV
9.915ns   765.6mV    719.4mV    788.6mV
20ns      772.6mV    734.2mV    797.3mV
[Rising Waveform]
R_fixture = 50.000
V_fixture = 1.500
V_fixture_min = 1.430
V_fixture_max = 1.580
|  time   V(typ)   V(min)   V(max)
0s        740.1mV    703.7mV    804.1mV
336ps     740.4mV    703.8mV    806.4mV
441ps     742.7mV    704mV      1.089V
549ps     1.014V     701.5mV    1.22V
651ps     1.149V     705.6mV    1.295V
791ps     1.247V     999.1mV    1.363V
871ps     1.284V     1.1V       1.391V
1.378ns   1.401V     1.307V     1.487V
2.299ns   1.465V     1.392V     1.548V
20ns      1.5V       1.43V      1.581V
[Falling Waveform]
R_fixture = 50.000
V_fixture = 1.500
V_fixture_min = 1.430
V_fixture_max = 1.580
|  time   V(typ)   V(min)   V(max)
0s        1.5V       1.43V      1.581V
551ps     1.514V     1.43V      1.585V
1.32ns    1.494V     1.427V     1.578V
2.51ns    1.425V     1.366V     1.52V
6.835ns   969.3mV    910.4mV    1.093V
7.875ns   885.1mV    834.2mV    998.2mV
9.007ns   827.8mV    783mV      918.5mV
10.4ns    789.6mV    748mV      858mV
12.2ns    764.5mV    725.1mV    823.5mV
20ns      740.1mV    703.7mV    804.1mV
[Falling Waveform]
R_fixture = 50.000
V_fixture = 0.000
V_fixture_min = 0.000
V_fixture_max = 0.000
|  time   V(typ)   V(min)   V(max)
0s        772.6mV    734.2mV    797.3mV
351ps     772.3mV    734.1mV    802.2mV
451ps     776.2mV    734.2mV    522.4mV
580ps     481.2mV    737.9mV    357.8mV
681ps     349mV      721mV      284.1mV
871ps     226mV      362.1mV    198.1mV
1.06ns    160.2mV    228.1mV    147.6mV
1.331ns   107.5mV    137.3mV    103.8mV
2.299ns   32.04mV    33.48mV    31.28mV
20ns      63.14uV    -308.4uV   -331uV
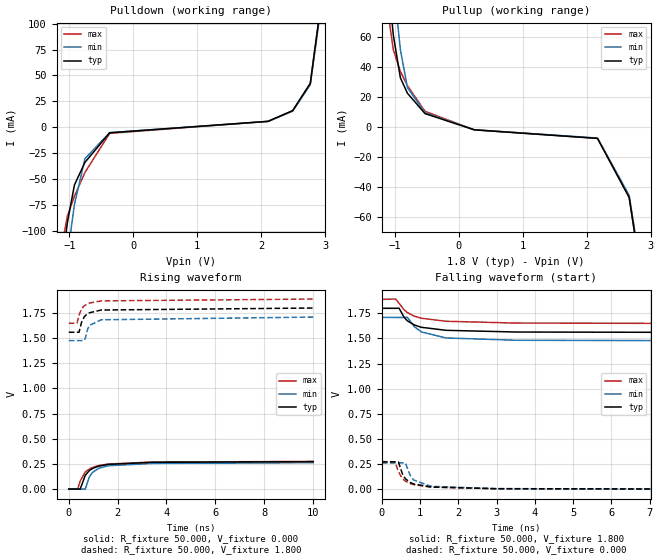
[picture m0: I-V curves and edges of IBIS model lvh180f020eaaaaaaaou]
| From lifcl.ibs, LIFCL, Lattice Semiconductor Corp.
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[Model] lvh180f020eaaaaaaaou
Model_type Output
Polarity   Non-Inverting
Enable   Active-High
Vmeas =  0.900V
Cref =  0.0F
Rref =  1.000M
Vref =  0.0V
C_comp   5.000pF   4.000pF   5.500pF
[Temperature Range]   25.000   0.125k   -40.000
[Voltage Range]   1.800V   1.710V   1.890V
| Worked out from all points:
|   slope of the pulldown table from 0 to 0.27 V, typ, clamps not added: 111 ohm
|   slope of the pullup table from 0 to 0.27 V, typ, clamps not added: 137 ohm
|   rising waveform, R_fixture 50.000, V_fixture 0.000: 20-80 % time 548ps typ, 506ps min, 585ps max; typ from 0 V to 0.272 V
|   rising waveform, R_fixture 50.000, V_fixture 1.800: 20-80 % time 371ps typ, 354ps min, 370ps max; typ from 1.56 V to 1.8 V
|   falling waveform, R_fixture 50.000, V_fixture 1.800: 20-80 % time 569ps typ, 601ps min, 628ps max; typ from 1.8 V to 1.56 V
|   falling waveform, R_fixture 50.000, V_fixture 0.000: 20-80 % time 329ps typ, 334ps min, 346ps max; typ from 0.272 V to 0 V
[Pulldown]
|Voltage   I(typ)   I(min)   I(max)
-1.8V     -596.9mA   -586.3mA   -599.1mA
-1.14V    -149.8mA   -183.1mA   -130.3mA
-1.085V   -119mA     -153mA     -104.1mA
-1.03V    -92.1mA    -124.4mA   -85.91mA
-920mV    -55.83mA   -74.71mA   -66.66mA
-755mV    -33.93mA   -30.38mA   -43.67mA
-370mV    -5.457mA   -5.328mA   -6.03mA
2.105V    5.615mA    5.447mA    5.615mA
2.49V     15.9mA     15.42mA    15.9mA
2.765V    42.22mA    40.96mA    42.22mA
2.985V    143.4mA    139.1mA    143.4mA
3.6V      555.3mA    538.6mA    555.3mA
[Pullup]
|Voltage   I(typ)   I(min)   I(max)
-1.8V     561.9mA    586.2mA    549.8mA
-1.13V    113.6mA    155.2mA    92.2mA
-1.075V   85.04mA    124.6mA    67.76mA
-1.02V    61.14mA    96.8mA     51.55mA
-910mV    32.88mA    51.58mA    37.04mA
-800mV    22.6mA     26.38mA    27.65mA
-525mV    9.027mA    9.575mA    10.54mA
245mV     -1.8mA     -1.746mA   -1.8mA
2.17V     -7.494mA   -7.269mA   -7.494mA
2.665V    -46.88mA   -45.48mA   -46.88mA
2.83V     -93mA      -90.2mA    -93mA
3.6V      -603.4mA   -585.3mA   -603.4mA
[Ramp]
| variable   typ   min   max
dV/dt_r   0.163/0.563n   0.157/0.513n   0.164/0.586n
dV/dt_f   0.145/0.572n   0.140/0.594n   0.145/0.636n
R_load = 50.000
[Rising Waveform]
R_fixture = 50.000
V_fixture = 0.000
V_fixture_min = 0.000
V_fixture_max = 0.000
|  time   V(typ)   V(min)   V(max)
0s        158.4uV    242.9uV    440.7uV
364ps     409.7uV    327.6uV    -93.19uV
467ps     -1.159mV   302.8uV    79.37mV
677ps     136.6mV    -1.076mV   169.7mV
837ps     182.6mV    117.8mV    199.2mV
966ps     203.6mV    164.7mV    214.4mV
1.226ns   228mV      206.2mV    233.5mV
1.607ns   245mV      231.6mV    248.6mV
3.441ns   265.9mV    254.9mV    269mV
10ns      272.3mV    261.8mV    274.6mV
[Rising Waveform]
R_fixture = 50.000
V_fixture = 1.800
V_fixture_min = 1.710
V_fixture_max = 1.890
|  time   V(typ)   V(min)   V(max)
0s        1.559V     1.476V     1.648V
336ps     1.559V     1.476V     1.649V
420ps     1.559V     1.476V     1.728V
527ps     1.66V      1.476V     1.793V
626ps     1.709V     1.476V     1.82V
677ps     1.724V     1.498V     1.829V
776ps     1.743V     1.593V     1.843V
857ps     1.753V     1.628V     1.85V
1.328ns   1.78V      1.683V     1.871V
10ns      1.8V       1.71V      1.889V
[Falling Waveform]
R_fixture = 50.000
V_fixture = 1.800
V_fixture_min = 1.710
V_fixture_max = 1.890
|  time   V(typ)   V(min)   V(max)
0s        1.8V       1.71V      1.889V
362ps     1.8V       1.709V     1.892V
450ps     1.801V     1.709V     1.85V
577ps     1.714V     1.709V     1.787V
665ps     1.676V     1.712V     1.758V
855ps     1.633V     1.615V     1.721V
1.035ns   1.611V     1.565V     1.701V
1.675ns   1.581V     1.505V     1.671V
3.513ns   1.564V     1.482V     1.653V
10ns      1.559V     1.476V     1.648V
[Falling Waveform]
R_fixture = 50.000
V_fixture = 0.000
V_fixture_min = 0.000
V_fixture_max = 0.000
|  time   V(typ)   V(min)   V(max)
0s        272.3mV    261.8mV    274.6mV
346ps     272.1mV    261.6mV    271.7mV
433ps     269.8mV    261.8mV    174.7mV
537ps     153.5mV    262mV      105.5mV
615ps     103.8mV    261.1mV    79.89mV
745ps     66mV       134.5mV    55.05mV
829ps     52.25mV    91.74mV    45.07mV
1.285ns   21.79mV    28.28mV    20.75mV
2.98ns    4.928mV    5.11mV     4.362mV
10ns      158.4uV    242.9uV    440.7uV
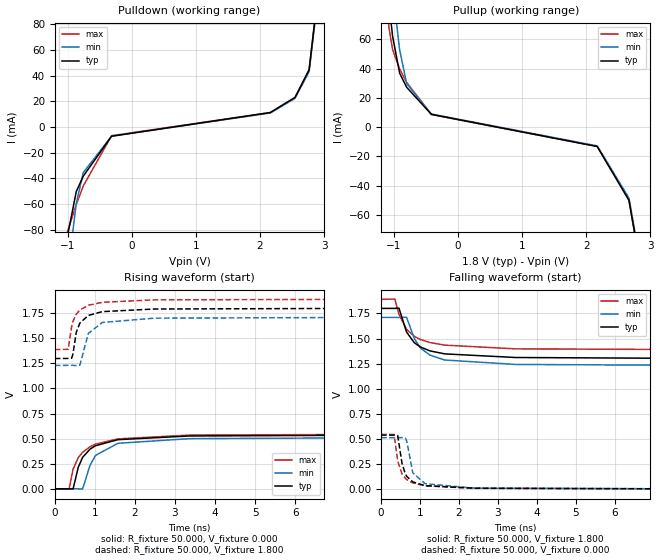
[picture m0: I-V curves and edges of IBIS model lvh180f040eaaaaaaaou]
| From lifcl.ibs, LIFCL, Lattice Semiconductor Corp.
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[Model] lvh180f040eaaaaaaaou
Model_type Output
Polarity   Non-Inverting
Enable   Active-High
Vmeas =  0.900V
Cref =  0.0F
Rref =  1.000M
Vref =  0.0V
C_comp   5.000pF   4.000pF   5.500pF
[Temperature Range]   25.000   0.125k   -40.000
[Voltage Range]   1.800V   1.710V   1.890V
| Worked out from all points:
|   slope of the pulldown table from 0 to 0.27 V, typ, clamps not added: 53.8 ohm
|   slope of the pullup table from 0 to 0.27 V, typ, clamps not added: 67.5 ohm
|   rising waveform, R_fixture 50.000, V_fixture 0.000: 20-80 % time 499ps typ, 474ps min, 552ps max; typ from 0 V to 0.538 V
|   rising waveform, R_fixture 50.000, V_fixture 1.800: 20-80 % time 258ps typ, 275ps min, 277ps max; typ from 1.3 V to 1.8 V
|   falling waveform, R_fixture 50.000, V_fixture 1.800: 20-80 % time 562ps typ, 554ps min, 607ps max; typ from 1.8 V to 1.3 V
|   falling waveform, R_fixture 50.000, V_fixture 0.000: 20-80 % time 224ps typ, 229ps min, 243ps max; typ from 0.538 V to 0 V
[Pulldown]
|Voltage   I(typ)   I(min)   I(max)
-1.8V     -575.4mA   -586.4mA   -572mA
-1.195V   -177.9mA   -215.9mA   -156.2mA
-1.14V    -146.3mA   -184.9mA   -126.3mA
-1.03V    -92.1mA    -126.8mA   -85.63mA
-865mV    -50.17mA   -59.32mA   -60.26mA
-755mV    -38.12mA   -35.34mA   -45.76mA
-315mV    -7.094mA   -7.021mA   -6.651mA
2.16V     11.37mA    11.03mA    11.37mA
2.545V    23.1mA     22.41mA    23.1mA
2.765V    44.6mA     43.26mA    44.6mA
2.985V    139.6mA    135.4mA    139.6mA
3.6V      535.2mA    519.1mA    535.2mA
[Pullup]
|Voltage   I(typ)   I(min)   I(max)
-1.8V     534.2mA    557.6mA    522.2mA
-1.185V   140.4mA    179.7mA    117.9mA
-1.13V    110.7mA    149.4mA    89.8mA
-1.075V   83.98mA    120.8mA    67.47mA
-1.02V    62.09mA    94.5mA     52.97mA
-910mV    36.84mA    52.76mA    39.66mA
-800mV    27.16mA    29.72mA    30.5mA
-415mV    8.725mA    8.931mA    8.602mA
2.17V     -13.19mA   -12.79mA   -13.19mA
2.665V    -49.83mA   -48.33mA   -49.83mA
2.83V     -91.4mA    -88.7mA    -91.4mA
3.6V      -573.4mA   -556.2mA   -573.4mA
[Ramp]
| variable   typ   min   max
dV/dt_r   0.323/0.504n   0.309/0.476n   0.328/0.552n
dV/dt_f   0.301/0.559n   0.291/0.556n   0.302/0.601n
R_load = 50.000
[Rising Waveform]
R_fixture = 50.000
V_fixture = 0.000
V_fixture_min = 0.000
V_fixture_max = 0.000
|  time   V(typ)   V(min)   V(max)
0s        138uV      786.5uV    -151.5uV
356ps     397.4uV    842.3uV    -2.564mV
457ps     -246.8uV   830.8uV    196.6mV
587ps     216.6mV    700.1uV    312.2mV
696ps     314.7mV    -750.6uV   365.6mV
877ps     395.1mV    231.6mV    419.9mV
1.016ns   430mV      333.4mV    446.1mV
1.577ns   490.3mV    454mV      498mV
3.362ns   527mV      500.4mV    535.7mV
10ns      538.5mV    513mV      546.2mV
[Rising Waveform]
R_fixture = 50.000
V_fixture = 1.800
V_fixture_min = 1.710
V_fixture_max = 1.890
|  time   V(typ)   V(min)   V(max)
0s        1.298V     1.229V     1.387V
334ps     1.299V     1.23V      1.39V
419ps     1.301V     1.23V      1.614V
451ps     1.338V     1.23V      1.665V
537ps     1.56V      1.228V     1.74V
626ps     1.651V     1.231V     1.781V
837ps     1.727V     1.548V     1.828V
1.187ns   1.765V     1.657V     1.858V
2.488ns   1.791V     1.7V       1.882V
10ns      1.8V       1.71V      1.89V
[Falling Waveform]
R_fixture = 50.000
V_fixture = 1.800
V_fixture_min = 1.710
V_fixture_max = 1.890
|  time   V(typ)   V(min)   V(max)
0s        1.8V       1.71V      1.89V
356ps     1.8V       1.71V      1.893V
460ps     1.803V     1.71V      1.739V
655ps     1.565V     1.712V     1.591V
855ps     1.458V     1.5V       1.522V
1.015ns   1.415V     1.404V     1.49V
1.255ns   1.377V     1.335V     1.46V
1.639ns   1.347V     1.286V     1.434V
3.459ns   1.311V     1.242V     1.397V
10ns      1.298V     1.229V     1.387V
[Falling Waveform]
R_fixture = 50.000
V_fixture = 0.000
V_fixture_min = 0.000
V_fixture_max = 0.000
|  time   V(typ)   V(min)   V(max)
0s        538.5mV    513mV      546.2mV
336ps     538.1mV    512.8mV    543.8mV
428ps     534.1mV    513mV      280.2mV
539ps     256.1mV    513.2mV    150.6mV
625ps     150.4mV    511.2mV    107.4mV
665ps     124.8mV    473mV      93.79mV
815ps     72.53mV    162.7mV    61.6mV
1.129ns   34.86mV    54.52mV    33.56mV
2.395ns   9.422mV    9.973mV    8.206mV
10ns      138uV      786.5uV    -151.5uV
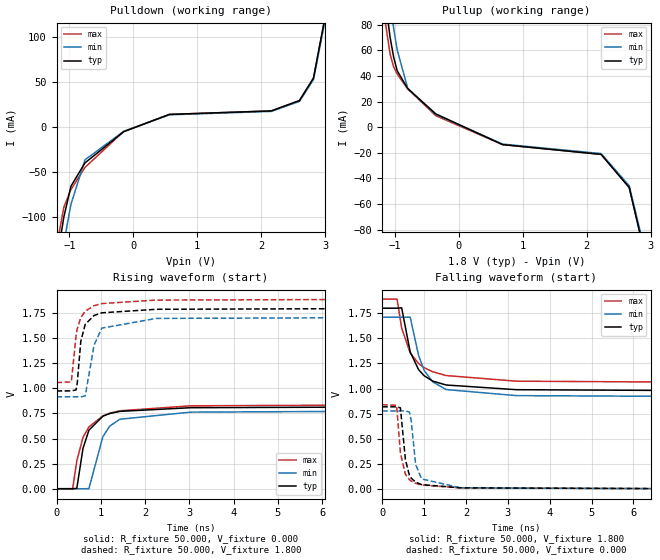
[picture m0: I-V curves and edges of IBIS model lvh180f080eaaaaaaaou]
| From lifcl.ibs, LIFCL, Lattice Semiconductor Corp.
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[Model] lvh180f080eaaaaaaaou
Model_type Output
Polarity   Non-Inverting
Enable   Active-High
Vmeas =  0.900V
Cref =  0.0F
Rref =  1.000M
Vref =  0.0V
C_comp   5.000pF   4.000pF   5.500pF
[Temperature Range]   25.000   0.125k   -40.000
[Voltage Range]   1.800V   1.710V   1.890V
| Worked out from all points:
|   slope of the pulldown table from 0 to 0.27 V, typ, clamps not added: 32.7 ohm
|   slope of the pullup table from 0 to 0.27 V, typ, clamps not added: 41.7 ohm
|   rising waveform, R_fixture 50.000, V_fixture 0.000: 20-80 % time 322ps typ, 360ps min, 428ps max; typ from 0 V to 0.819 V
|   rising waveform, R_fixture 50.000, V_fixture 1.800: 20-80 % time 159ps typ, 221ps min, 193ps max; typ from 0.975 V to 1.8 V
|   falling waveform, R_fixture 50.000, V_fixture 1.800: 20-80 % time 435ps typ, 422ps min, 527ps max; typ from 1.8 V to 0.975 V
|   falling waveform, R_fixture 50.000, V_fixture 0.000: 20-80 % time 141ps typ, 150ps min, 148ps max; typ from 0.819 V to 0 V
[Pulldown]
|Voltage   I(typ)   I(min)   I(max)
-1.8V     -467.8mA   -473.5mA   -468.7mA
-1.195V   -147.3mA   -176.6mA   -130.8mA
-1.085V   -99.4mA    -128.3mA   -88.6mA
-975mV    -65.56mA   -85.7mA    -69.21mA
-755mV    -39.63mA   -36.22mA   -44.64mA
-150mV    -5.086mA   -4.689mA   -4.763mA
565mV     14.1mA     13.67mA    14.1mA
2.16V     17.98mA    17.44mA    17.98mA
2.6V      29.41mA    28.53mA    29.41mA
2.82V     54.39mA    52.76mA    54.39mA
2.985V    116mA      112.5mA    116mA
3.6V      435mA      421.9mA    435mA
[Pullup]
|Voltage   I(typ)   I(min)   I(max)
-1.8V     412.2mA    430.3mA    402mA
-1.185V   111.7mA    141.3mA    93.5mA
-1.075V   70.1mA     96.9mA     56.9mA
-1.02V    54.69mA    77.3mA     47.05mA
-965mV    44.06mA    60.4mA     41.47mA
-800mV    30.07mA    30.39mA    29.87mA
-360mV    10.32mA    9.758mA    8.902mA
685mV     -13.65mA   -13.24mA   -13.65mA
2.225V    -21.26mA   -20.63mA   -21.26mA
2.665V    -47.14mA   -45.73mA   -47.14mA
2.885V    -93.9mA    -91.1mA    -93.9mA
3.6V      -441.5mA   -428.3mA   -441.5mA
[Ramp]
| variable   typ   min   max
dV/dt_r   0.491/0.321n   0.467/0.360n   0.504/0.430n
dV/dt_f   0.495/0.436n   0.476/0.425n   0.500/0.532n
R_load = 50.000
[Rising Waveform]
R_fixture = 50.000
V_fixture = 0.000
V_fixture_min = 0.000
V_fixture_max = 0.000
|  time   V(typ)   V(min)   V(max)
0s        110.4uV    -229.5uV   -284.8uV
363ps     451.2uV    -208.6uV   -4.497mV
458ps     2.872mV    -187.4uV   277.1mV
598ps     401.8mV    -654.5uV   512.1mV
732ps     583.9mV    1.202mV    615.8mV
1.047ns   723.3mV    519.4mV    726.4mV
1.202ns   749.6mV    624.4mV    752.5mV
1.431ns   771.2mV    692.7mV    777.1mV
3.033ns   807.8mV    763.7mV    826.6mV
10ns      819.1mV    778mV      840.1mV
[Rising Waveform]
R_fixture = 50.000
V_fixture = 1.800
V_fixture_min = 1.710
V_fixture_max = 1.890
|  time   V(typ)   V(min)   V(max)
0s        975.1mV    916.7mV    1.058V
334ps     975.3mV    916.7mV    1.065V
441ps     985.1mV    916.9mV    1.522V
468ps     1.053V     916.9mV    1.594V
548ps     1.469V     914.4mV    1.706V
648ps     1.639V     925.9mV    1.77V
848ps     1.727V     1.431V     1.825V
1.022ns   1.754V     1.601V     1.846V
2.253ns   1.789V     1.698V     1.881V
10ns      1.8V       1.71V      1.891V
[Falling Waveform]
R_fixture = 50.000
V_fixture = 1.800
V_fixture_min = 1.710
V_fixture_max = 1.890
|  time   V(typ)   V(min)   V(max)
0s        1.8V       1.71V      1.891V
356ps     1.8V       1.71V      1.891V
466ps     1.804V     1.71V      1.604V
670ps     1.365V     1.711V     1.355V
870ps     1.189V     1.331V     1.25V
1.001ns   1.129V     1.183V     1.209V
1.206ns   1.075V     1.068V     1.168V
1.529ns   1.036V     990.6mV    1.13V
3.206ns   989.4mV    930.4mV    1.074V
10ns      975.1mV    916.7mV    1.058V
[Falling Waveform]
R_fixture = 50.000
V_fixture = 0.000
V_fixture_min = 0.000
V_fixture_max = 0.000
|  time   V(typ)   V(min)   V(max)
0s        819.1mV    778mV      840.1mV
346ps     818.9mV    777.8mV    834mV
436ps     808.9mV    777.9mV    360.5mV
556ps     294mV      778.8mV    146.5mV
650ps     138.7mV    766.8mV    94.95mV
691ps     110.9mV    691.6mV    81.39mV
800ps     69.68mV    245.7mV    58.03mV
941ps     45.03mV    101.6mV    41.71mV
1.876ns   12.77mV    12.72mV    12.06mV
10ns      110.4uV    -229.5uV   -284.8uV
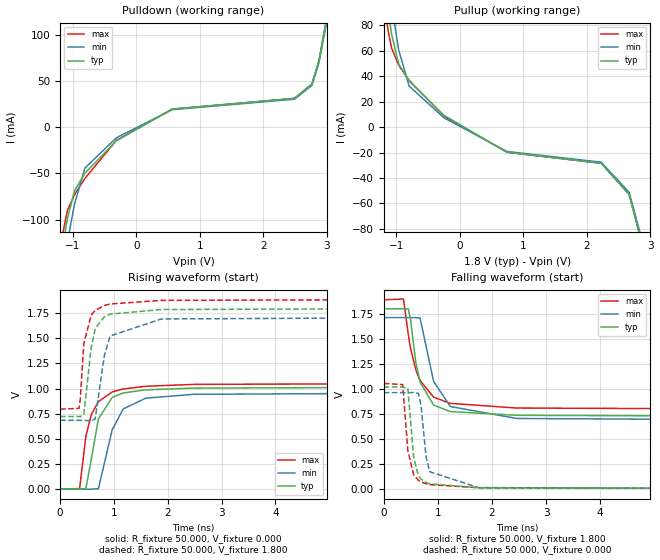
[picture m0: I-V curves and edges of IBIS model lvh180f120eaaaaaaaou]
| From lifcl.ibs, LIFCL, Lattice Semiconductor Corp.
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[Model] lvh180f120eaaaaaaaou
Model_type Output
Polarity   Non-Inverting
Enable   Active-High
Vmeas =  0.900V
Cref =  0.0F
Rref =  1.000M
Vref =  0.0V
C_comp   5.000pF   4.000pF   5.500pF
[Temperature Range]   25.000   0.125k   -40.000
[Voltage Range]   1.800V   1.710V   1.890V
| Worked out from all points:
|   slope of the pulldown table from 0 to 0.27 V, typ, clamps not added: 23.9 ohm
|   slope of the pullup table from 0 to 0.27 V, typ, clamps not added: 30.4 ohm
|   rising waveform, R_fixture 50.000, V_fixture 0.000: 20-80 % time 245ps typ, 320ps min, 266ps max; typ from 0 V to 1.02 V
|   rising waveform, R_fixture 50.000, V_fixture 1.800: 20-80 % time 155ps typ, 197ps min, 133ps max; typ from 0.722 V to 1.8 V
|   falling waveform, R_fixture 50.000, V_fixture 1.800: 20-80 % time 249ps typ, 350ps min, 321ps max; typ from 1.8 V to 0.722 V
|   falling waveform, R_fixture 50.000, V_fixture 0.000: 20-80 % time 101ps typ, 134ps min, 111ps max; typ from 1.02 V to 0 V
[Pulldown]
|Voltage   I(typ)   I(min)   I(max)
-1.8V     -446.5mA   -453mA     -445.9mA
-1.195V   -143mA     -169.9mA   -127.2mA
-1.085V   -98.6mA    -123.8mA   -89.9mA
-975mV    -68.8mA    -83.6mA    -73.2mA
-810mV    -49.78mA   -44.19mA   -55.42mA
-315mV    -14.76mA   -11.51mA   -14.36mA
565mV     19.49mA    18.9mA     19.49mA
2.49V     31.09mA    30.16mA    31.09mA
2.765V    46.6mA     45.2mA     46.6mA
2.875V    71.6mA     69.5mA     71.6mA
2.985V    112.9mA    109.5mA    112.9mA
3.6V      415mA      402.5mA    415mA
[Pullup]
|Voltage   I(typ)   I(min)   I(max)
-1.8V     403.7mA    420.1mA    393.5mA
-1.185V   112.1mA    139mA      94.9mA
-1.13V    91mA       116.8mA    76mA
-1.075V   73mA       96mA       62.13mA
-965mV    49.72mA    60.86mA    48.81mA
-800mV    36.34mA    32.32mA    36.85mA
-250mV    9.276mA    7.286mA    8.704mA
740mV     -19.74mA   -19.15mA   -19.74mA
2.225V    -28.43mA   -27.58mA   -28.43mA
2.665V    -52.94mA   -51.36mA   -52.94mA
2.885V    -95mA      -92.1mA    -95mA
3.6V      -431.6mA   -418.7mA   -431.6mA
[Ramp]
| variable   typ   min   max
dV/dt_r   0.611/0.244n   0.579/0.318n   0.633/0.269n
dV/dt_f   0.647/0.253n   0.617/0.355n   0.663/0.325n
R_load = 50.000
[Rising Waveform]
R_fixture = 50.000
V_fixture = 0.000
V_fixture_min = 0.000
V_fixture_max = 0.000
|  time   V(typ)   V(min)   V(max)
0s        101.1uV    -1.731mV   45.58uV
361ps     612.1uV    -1.716mV   3.746mV
478ps     3.691mV    -1.628mV   524.7mV
578ps     293.1mV    -1.573mV   738.3mV
711ps     697.8mV    2.489mV    868.7mV
967ps     910.4mV    588mV      965.4mV
1.172ns   955.8mV    796.6mV    995.4mV
1.592ns   986.9mV    904mV      1.022V
2.479ns   1.004V     942mV      1.041V
10ns      1.018V     962.6mV    1.054V
[Rising Waveform]
R_fixture = 50.000
V_fixture = 1.800
V_fixture_min = 1.710
V_fixture_max = 1.890
|  time   V(typ)   V(min)   V(max)
0s        721.7mV    683.2mV    793.7mV
351ps     721.3mV    683.2mV    802.9mV
373ps     719.7mV    683.2mV    888.3mV
440ps     738.6mV    683.5mV    1.448V
577ps     1.407V     678.4mV    1.731V
651ps     1.596V     697.4mV    1.777V
821ps     1.714V     1.327V     1.826V
928ps     1.74V      1.522V     1.841V
1.881ns   1.786V     1.692V     1.877V
10ns      1.8V       1.712V     1.89V
[Falling Waveform]
R_fixture = 50.000
V_fixture = 1.800
V_fixture_min = 1.710
V_fixture_max = 1.890
|  time   V(typ)   V(min)   V(max)
0s        1.8V       1.712V     1.89V
365ps     1.8V       1.712V     1.897V
455ps     1.798V     1.712V     1.54V
495ps     1.692V     1.712V     1.406V
594ps     1.26V      1.712V     1.19V
672ps     1.068V     1.707V     1.083V
922ps     837.7mV    1.074V     917.2mV
1.232ns   773.5mV    823.5mV    855.3mV
2.465ns   735.9mV    704.1mV    808.4mV
10ns      721.7mV    683.2mV    793.7mV
[Falling Waveform]
R_fixture = 50.000
V_fixture = 0.000
V_fixture_min = 0.000
V_fixture_max = 0.000
|  time   V(typ)   V(min)   V(max)
0s        1.018V     962.6mV    1.054V
350ps     1.018V     962.5mV    1.043V
446ps     1.005V     962.6mV    384.9mV
555ps     307.4mV    963.5mV    138.4mV
642ps     131.6mV    953.7mV    87.2mV
692ps     98.24mV    825.8mV    70.91mV
782ps     65.34mV    322.4mV    52.56mV
852ps     50.83mV    171.6mV    43.65mV
1.754ns   12.83mV    14.04mV    12.34mV
10ns      101.1uV    -1.731mV   45.58uV
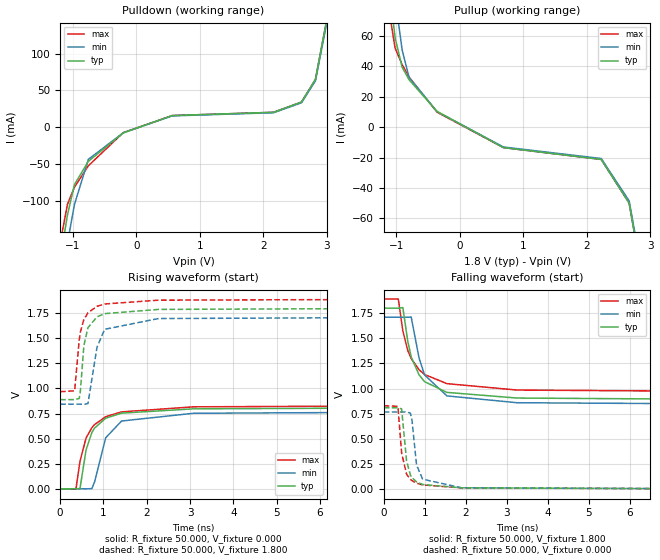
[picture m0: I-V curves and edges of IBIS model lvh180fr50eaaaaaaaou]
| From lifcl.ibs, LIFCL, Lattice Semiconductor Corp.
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[Model] lvh180fr50eaaaaaaaou
Model_type Output
Polarity   Non-Inverting
Enable   Active-High
Vmeas =  0.900V
Cref =  0.0F
Rref =  1.000M
Vref =  0.0V
C_comp   5.000pF   4.000pF   5.500pF
[Temperature Range]   25.000   0.125k   -40.000
[Voltage Range]   1.800V   1.710V   1.890V
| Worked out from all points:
|   slope of the pulldown table from 0 to 0.27 V, typ, clamps not added: 29.1 ohm
|   slope of the pullup table from 0 to 0.27 V, typ, clamps not added: 42.2 ohm
|   rising waveform, R_fixture 50.000, V_fixture 0.000: 20-80 % time 356ps typ, 375ps min, 428ps max; typ from 0 V to 0.809 V
|   rising waveform, R_fixture 50.000, V_fixture 1.800: 20-80 % time 172ps typ, 228ps min, 192ps max; typ from 0.888 V to 1.8 V
|   falling waveform, R_fixture 50.000, V_fixture 1.800: 20-80 % time 458ps typ, 431ps min, 538ps max; typ from 1.8 V to 0.888 V
|   falling waveform, R_fixture 50.000, V_fixture 0.000: 20-80 % time 145ps typ, 152ps min, 153ps max; typ from 0.809 V to 0 V
[Pulldown]
|Voltage   I(typ)   I(min)   I(max)
-1.8V     -567.1mA   -586mA     -558.7mA
-1.195V   -178.1mA   -218.3mA   -155.6mA
-1.085V   -119.7mA   -158.2mA   -105.2mA
-975mV    -78.23mA   -105.4mA   -81.84mA
-755mV    -46.51mA   -43.76mA   -52.55mA
-205mV    -7.828mA   -7.588mA   -7.437mA
565mV     15.8mA     15.33mA    15.8mA
2.16V     20.23mA    19.62mA    20.23mA
2.6V      34.17mA    33.15mA    34.17mA
2.82V     64.99mA    63.04mA    64.99mA
2.985V    140.2mA    136mA      140.2mA
3.6V      527.4mA    511.6mA    527.4mA
[Pullup]
|Voltage   I(typ)   I(min)   I(max)
-1.8V     453.6mA    473.7mA    442.9mA
-1.185V   122.1mA    155.2mA    102.9mA
-1.13V    97.6mA     130mA      80.2mA
-1.02V    58.64mA    84.5mA     51.83mA
-910mV    39.35mA    50.82mA    41.1mA
-800mV    31.1mA     32.59mA    32.9mA
-360mV    10.31mA    10.26mA    9.806mA
685mV     -13.45mA   -13.04mA   -13.45mA
2.225V    -21.23mA   -20.6mA    -21.23mA
2.665V    -49.94mA   -48.45mA   -49.94mA
2.885V    -102.4mA   -99.3mA    -102.4mA
3.6V      -485.9mA   -471.3mA   -485.9mA
[Ramp]
| variable   typ   min   max
dV/dt_r   0.485/0.355n   0.461/0.374n   0.498/0.428n
dV/dt_f   0.547/0.463n   0.525/0.435n   0.554/0.543n
R_load = 50.000
[Rising Waveform]
R_fixture = 50.000
V_fixture = 0.000
V_fixture_min = 0.000
V_fixture_max = 0.000
|  time   V(typ)   V(min)   V(max)
0s        116.5uV    562.3uV    -151.7uV
364ps     481.2uV    585.5uV    -3.24mV
458ps     2.746mV    605.6uV    274.1mV
599ps     389.2mV    110.2uV    506.9mV
732ps     560.7mV    2.299mV    608.3mV
792ps     603.9mV    64.62mV    638.9mV
1.052ns   703.6mV    508.5mV    718.4mV
1.418ns   753.8mV    675.5mV    766.4mV
3.08ns    796.8mV    752.7mV    816.8mV
10ns      809.3mV    767.2mV    829.6mV
[Rising Waveform]
R_fixture = 50.000
V_fixture = 1.800
V_fixture_min = 1.710
V_fixture_max = 1.890
|  time   V(typ)   V(min)   V(max)
0s        888.3mV    843.3mV    967.3mV
334ps     888.5mV    843.4mV    976.2mV
441ps     900.2mV    843.7mV    1.484V
468ps     978.1mV    843.6mV    1.563V
548ps     1.428V     840.6mV    1.686V
642ps     1.605V     849.5mV    1.753V
852ps     1.713V     1.412V     1.818V
1.028ns   1.745V     1.589V     1.841V
2.271ns   1.787V     1.696V     1.879V
10ns      1.8V       1.71V      1.89V
[Falling Waveform]
R_fixture = 50.000
V_fixture = 1.800
V_fixture_min = 1.710
V_fixture_max = 1.890
|  time   V(typ)   V(min)   V(max)
0s        1.8V       1.71V      1.89V
356ps     1.8V       1.71V      1.89V
466ps     1.805V     1.71V      1.573V
586ps     1.471V     1.71V      1.379V
670ps     1.315V     1.711V     1.299V
860ps     1.137V     1.306V     1.188V
996ps     1.069V     1.135V     1.14V
1.54ns    962mV      927.2mV    1.049V
3.25ns    905.8mV    859.3mV    985.3mV
10ns      888.3mV    843.3mV    967.3mV
[Falling Waveform]
R_fixture = 50.000
V_fixture = 0.000
V_fixture_min = 0.000
V_fixture_max = 0.000
|  time   V(typ)   V(min)   V(max)
0s        809.3mV    767.2mV    829.6mV
346ps     809.1mV    767mV      823.5mV
436ps     797.7mV    767.1mV    361.7mV
556ps     283.9mV    768mV      149.3mV
650ps     139.9mV    755.4mV    97.19mV
690ps     113.6mV    681.5mV    83.67mV
800ps     72.19mV    239.6mV    59.54mV
950ps     46.06mV    98.88mV    42.05mV
1.896ns   13.18mV    13.63mV    12.21mV
10ns      116.5uV    562.3uV    -151.7uV
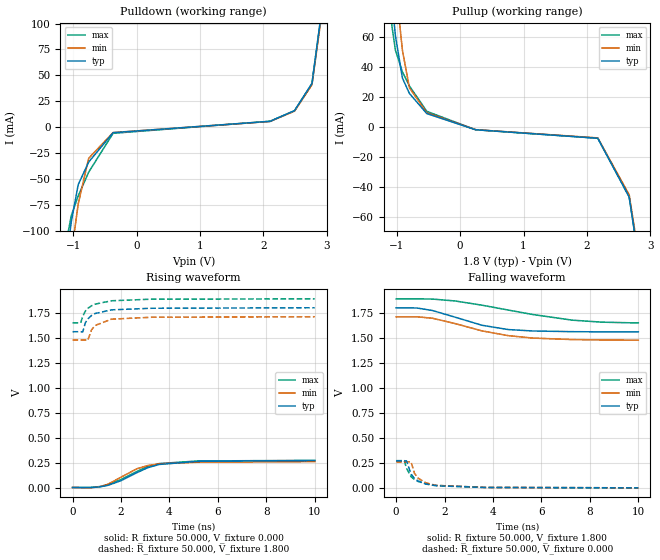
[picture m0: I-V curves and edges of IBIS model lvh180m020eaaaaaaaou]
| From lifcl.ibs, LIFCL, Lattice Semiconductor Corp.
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[Model] lvh180m020eaaaaaaaou
Model_type Output
Polarity   Non-Inverting
Enable   Active-High
Vmeas =  0.900V
Cref =  0.0F
Rref =  1.000M
Vref =  0.0V
C_comp   5.000pF   4.000pF   5.500pF
[Temperature Range]   25.000   0.125k   -40.000
[Voltage Range]   1.800V   1.710V   1.890V
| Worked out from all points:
|   slope of the pulldown table from 0 to 0.27 V, typ, clamps not added: 112 ohm
|   slope of the pullup table from 0 to 0.27 V, typ, clamps not added: 139 ohm
|   rising waveform, R_fixture 50.000, V_fixture 0.000: 20-80 % time 1.46ns typ, 1.27ns min, 1.43ns max; typ from 0 V to 0.27 V
|   rising waveform, R_fixture 50.000, V_fixture 1.800: 20-80 % time 555ps typ, 516ps min, 591ps max; typ from 1.56 V to 1.8 V
|   falling waveform, R_fixture 50.000, V_fixture 1.800: 20-80 % time 2.07ns typ, 2.46ns min, 3.38ns max; typ from 1.8 V to 1.56 V
|   falling waveform, R_fixture 50.000, V_fixture 0.000: 20-80 % time 534ps typ, 526ps min, 602ps max; typ from 0.27 V to 0 V
[Pulldown]
|Voltage   I(typ)   I(min)   I(max)
-1.8V     -594.7mA   -582.9mA   -597.6mA
-1.14V    -149.2mA   -182.1mA   -130mA
-1.085V   -118.6mA   -152.1mA   -103.8mA
-1.03V    -91.8mA    -123.7mA   -85.71mA
-920mV    -55.62mA   -74.28mA   -66.5mA
-755mV    -33.8mA    -30.2mA    -43.57mA
-370mV    -5.436mA   -5.297mA   -6.016mA
2.105V    5.594mA    5.426mA    5.594mA
2.49V     15.84mA    15.37mA    15.84mA
2.765V    42.06mA    40.8mA     42.06mA
2.985V    142.9mA    138.6mA    142.9mA
3.6V      553.2mA    536.6mA    553.2mA
[Pullup]
|Voltage   I(typ)   I(min)   I(max)
-1.8V     556.2mA    580.5mA    544.4mA
-1.13V    112.6mA    153.6mA    91.2mA
-1.075V   84.2mA     123.5mA    67.08mA
-1.02V    60.53mA    95.7mA     51.03mA
-910mV    32.55mA    51.07mA    36.67mA
-800mV    22.37mA    26.11mA    27.37mA
-525mV    8.937mA    9.48mA     10.43mA
245mV     -1.782mA   -1.729mA   -1.782mA
2.17V     -7.419mA   -7.197mA   -7.419mA
2.665V    -46.41mA   -45.02mA   -46.41mA
2.83V     -92.1mA    -89.3mA    -92.1mA
3.6V      -597.4mA   -579.5mA   -597.4mA
[Ramp]
| variable   typ   min   max
dV/dt_r   0.162/1.489n   0.155/1.294n   0.163/1.457n
dV/dt_f   0.144/2.108n   0.139/2.538n   0.144/3.399n
R_load = 50.000
[Rising Waveform]
R_fixture = 50.000
V_fixture = 0.000
V_fixture_min = 0.000
V_fixture_max = 0.000
|  time   V(typ)   V(min)   V(max)
0s        157uV      234.5uV    443.2uV
736ps     -226.4uV   -3.368mV   598.3uV
1.127ns   6.221mV    7.949mV    9.562mV
1.467ns   22.15mV    33.6mV     29.31mV
1.988ns   67.02mV    101.6mV    78.75mV
2.652ns   148.2mV    187.4mV    160.3mV
3.11ns    198.9mV    220.3mV    210.7mV
3.579ns   230.9mV    237.4mV    240.1mV
5.183ns   262.1mV    253.7mV    265.8mV
10ns      269.7mV    259.3mV    271.9mV
[Rising Waveform]
R_fixture = 50.000
V_fixture = 1.800
V_fixture_min = 1.710
V_fixture_max = 1.890
|  time   V(typ)   V(min)   V(max)
0s        1.56V      1.477V     1.649V
334ps     1.56V      1.477V     1.649V
421ps     1.558V     1.477V     1.714V
527ps     1.648V     1.477V     1.766V
626ps     1.688V     1.473V     1.793V
786ps     1.723V     1.579V     1.82V
927ps     1.742V     1.622V     1.836V
1.607ns   1.779V     1.686V     1.87V
3.267ns   1.795V     1.705V     1.886V
10ns      1.8V       1.71V      1.889V
[Falling Waveform]
R_fixture = 50.000
V_fixture = 1.800
V_fixture_min = 1.710
V_fixture_max = 1.890
|  time   V(typ)   V(min)   V(max)
0s        1.8V       1.71V      1.889V
855ps     1.799V     1.711V     1.89V
1.507ns   1.773V     1.696V     1.888V
2.434ns   1.707V     1.643V     1.869V
3.543ns   1.626V     1.57V      1.827V
4.634ns   1.583V     1.522V     1.778V
5.63ns    1.569V     1.498V     1.734V
7.276ns   1.562V     1.483V     1.677V
8.506ns   1.56V      1.479V     1.657V
10ns      1.56V      1.477V     1.649V
[Falling Waveform]
R_fixture = 50.000
V_fixture = 0.000
V_fixture_min = 0.000
V_fixture_max = 0.000
|  time   V(typ)   V(min)   V(max)
0s        269.7mV    259.3mV    271.9mV
336ps     269.3mV    259.1mV    272.5mV
428ps     269.7mV    259.3mV    196.7mV
615ps     138mV      261.3mV    112.3mV
755ps     95.92mV    147mV      83.62mV
905ps     69.42mV    96.94mV    64.13mV
1.23ns    38.12mV    49.93mV    40.32mV
1.655ns   20.86mV    24.56mV    24.3mV
3.661ns   3.735mV    4.305mV    4.001mV
10ns      157uV      234.5uV    443.2uV
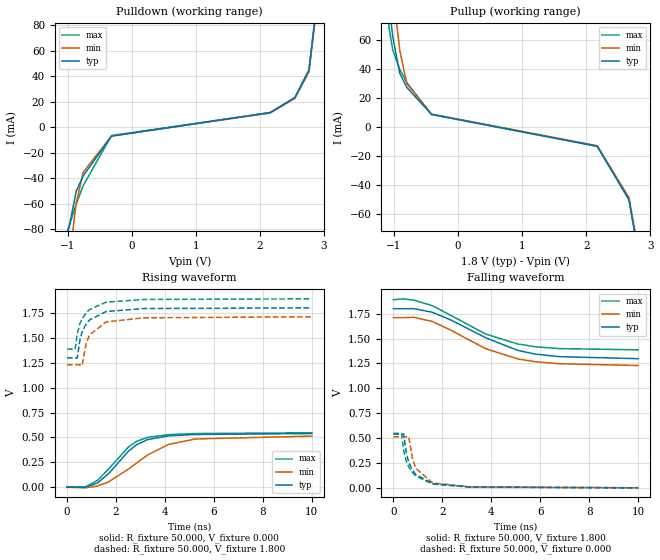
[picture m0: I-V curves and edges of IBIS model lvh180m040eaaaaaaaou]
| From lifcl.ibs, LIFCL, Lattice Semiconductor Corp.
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[Model] lvh180m040eaaaaaaaou
Model_type Output
Polarity   Non-Inverting
Enable   Active-High
Vmeas =  0.900V
Cref =  0.0F
Rref =  1.000M
Vref =  0.0V
C_comp   5.000pF   4.000pF   5.500pF
[Temperature Range]   25.000   0.125k   -40.000
[Voltage Range]   1.800V   1.710V   1.890V
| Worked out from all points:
|   slope of the pulldown table from 0 to 0.27 V, typ, clamps not added: 53.8 ohm
|   slope of the pullup table from 0 to 0.27 V, typ, clamps not added: 67.5 ohm
|   rising waveform, R_fixture 50.000, V_fixture 0.000: 20-80 % time 1.29ns typ, 1.9ns min, 1.26ns max; typ from 0 V to 0.539 V
|   rising waveform, R_fixture 50.000, V_fixture 1.800: 20-80 % time 534ps typ, 527ps min, 561ps max; typ from 1.3 V to 1.8 V
|   falling waveform, R_fixture 50.000, V_fixture 1.800: 20-80 % time 2.61ns typ, 2.46ns min, 2.48ns max; typ from 1.8 V to 1.3 V
|   falling waveform, R_fixture 50.000, V_fixture 0.000: 20-80 % time 550ps typ, 515ps min, 575ps max; typ from 0.539 V to 0 V
[Pulldown]
|Voltage   I(typ)   I(min)   I(max)
-1.8V     -575.9mA   -586.4mA   -572.6mA
-1.195V   -178.2mA   -215.9mA   -156.4mA
-1.14V    -146.4mA   -184.9mA   -126.5mA
-1.03V    -92.1mA    -126.8mA   -85.71mA
-865mV    -50.21mA   -59.31mA   -60.31mA
-755mV    -38.15mA   -35.33mA   -45.8mA
-315mV    -7.101mA   -7.02mA    -6.657mA
2.16V     11.38mA    11.04mA    11.38mA
2.545V    23.12mA    22.43mA    23.12mA
2.765V    44.64mA    43.3mA     44.64mA
2.985V    139.8mA    135.6mA    139.8mA
3.6V      535.8mA    519.7mA    535.8mA
[Pullup]
|Voltage   I(typ)   I(min)   I(max)
-1.8V     534.8mA    558.2mA    522.8mA
-1.185V   140.5mA    179.8mA    117.9mA
-1.13V    110.8mA    149.6mA    89.9mA
-1.075V   84.06mA    120.9mA    67.53mA
-1.02V    62.15mA    94.7mA     53.03mA
-910mV    36.88mA    52.81mA    39.7mA
-800mV    27.18mA    29.74mA    30.53mA
-415mV    8.734mA    8.94mA     8.611mA
2.17V     -13.2mA    -12.8mA    -13.2mA
2.665V    -49.88mA   -48.38mA   -49.88mA
2.83V     -91.5mA    -88.8mA    -91.5mA
3.6V      -573.8mA   -556.6mA   -573.8mA
[Ramp]
| variable   typ   min   max
dV/dt_r   0.323/1.324n   0.309/1.932n   0.328/1.278n
dV/dt_f   0.301/2.656n   0.291/2.535n   0.302/2.563n
R_load = 50.000
[Rising Waveform]
R_fixture = 50.000
V_fixture = 0.000
V_fixture_min = 0.000
V_fixture_max = 0.000
|  time   V(typ)   V(min)   V(max)
0s        137.9uV    785.9uV    -152.1uV
746ps     671.7uV    -5.708mV   4.302mV
1.237ns   41.61mV    12.17mV    67.72mV
1.687ns   134.2mV    52.84mV    180.2mV
2.516ns   363.3mV    183.8mV    405mV
2.85ns    428.1mV    245.2mV    461.6mV
3.3ns     479mV      325mV      501mV
4.161ns   516.1mV    431mV      528.3mV
5.234ns   529.4mV    484.5mV    538.8mV
10ns      539mV      513.4mV    546.7mV
[Rising Waveform]
R_fixture = 50.000
V_fixture = 1.800
V_fixture_min = 1.710
V_fixture_max = 1.890
|  time   V(typ)   V(min)   V(max)
0s        1.298V     1.229V     1.387V
333ps     1.298V     1.23V      1.385V
419ps     1.296V     1.23V      1.543V
528ps     1.479V     1.228V     1.643V
616ps     1.559V     1.221V     1.69V
776ps     1.636V     1.439V     1.748V
917ps     1.678V     1.528V     1.783V
1.597ns   1.763V     1.659V     1.857V
3.148ns   1.793V     1.7V       1.884V
10ns      1.8V       1.71V      1.89V
[Falling Waveform]
R_fixture = 50.000
V_fixture = 1.800
V_fixture_min = 1.710
V_fixture_max = 1.890
|  time   V(typ)   V(min)   V(max)
0s        1.8V       1.71V      1.89V
383ps     1.8V       1.71V      1.899V
835ps     1.801V     1.714V     1.887V
1.59ns    1.764V     1.672V     1.83V
2.338ns   1.688V     1.585V     1.734V
3.761ns   1.509V     1.399V     1.546V
5.07ns    1.382V     1.296V     1.446V
5.794ns   1.344V     1.267V     1.418V
6.786ns   1.318V     1.247V     1.399V
10ns      1.298V     1.229V     1.387V
[Falling Waveform]
R_fixture = 50.000
V_fixture = 0.000
V_fixture_min = 0.000
V_fixture_max = 0.000
|  time   V(typ)   V(min)   V(max)
0s        539mV      513.4mV    546.7mV
333ps     538.5mV    513.2mV    548.5mV
421ps     541.5mV    513.4mV    371.8mV
529ps     350.9mV    513.3mV    265.3mV
625ps     255.5mV    514.1mV    210.5mV
785ps     173.7mV    284.6mV    151.7mV
919ps     133mV      195.7mV    118mV
1.604ns   42.62mV    48.99mV    37.21mV
3.154ns   8.336mV    9.147mV    6.306mV
10ns      137.9uV    785.9uV    -152.1uV
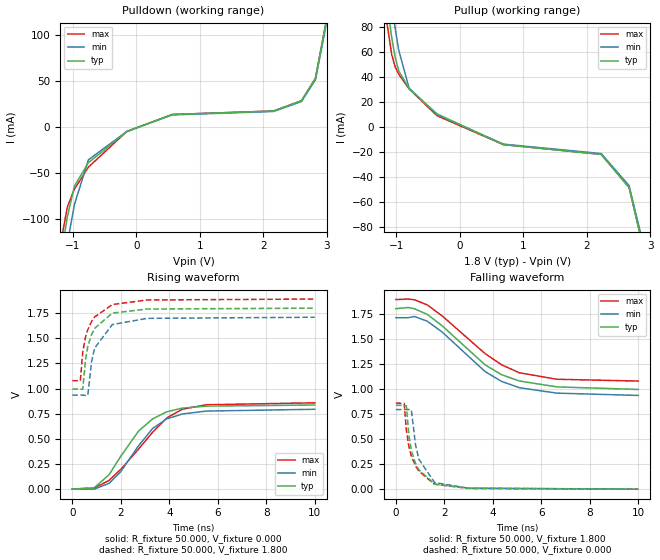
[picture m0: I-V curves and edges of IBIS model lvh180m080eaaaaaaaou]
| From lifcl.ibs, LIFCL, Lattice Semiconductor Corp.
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[Model] lvh180m080eaaaaaaaou
Model_type Output
Polarity   Non-Inverting
Enable   Active-High
Vmeas =  0.900V
Cref =  0.0F
Rref =  1.000M
Vref =  0.0V
C_comp   5.000pF   4.000pF   5.500pF
[Temperature Range]   25.000   0.125k   -40.000
[Voltage Range]   1.800V   1.710V   1.890V
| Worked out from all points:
|   slope of the pulldown table from 0 to 0.27 V, typ, clamps not added: 33.5 ohm
|   slope of the pullup table from 0 to 0.27 V, typ, clamps not added: 40.5 ohm
|   rising waveform, R_fixture 50.000, V_fixture 0.000: 20-80 % time 1.56ns typ, 1.52ns min, 1.89ns max; typ from 0 V to 0.836 V
|   rising waveform, R_fixture 50.000, V_fixture 1.800: 20-80 % time 531ps typ, 527ps min, 591ps max; typ from 0.994 V to 1.8 V
|   falling waveform, R_fixture 50.000, V_fixture 1.800: 20-80 % time 2.38ns typ, 2.27ns min, 2.45ns max; typ from 1.8 V to 0.994 V
|   falling waveform, R_fixture 50.000, V_fixture 0.000: 20-80 % time 525ps typ, 497ps min, 574ps max; typ from 0.836 V to 0 V
[Pulldown]
|Voltage   I(typ)   I(min)   I(max)
-1.8V     -455.8mA   -464.1mA   -455.9mA
-1.195V   -143.5mA   -173.1mA   -127.2mA
-1.085V   -96.8mA    -125.7mA   -86.3mA
-975mV    -63.89mA   -84mA      -67.31mA
-755mV    -38.62mA   -35.5mA    -43.42mA
-150mV    -4.956mA   -4.596mA   -4.633mA
565mV     13.74mA    13.32mA    13.74mA
2.16V     17.52mA    17mA       17.52mA
2.6V      28.66mA    27.8mA     28.66mA
2.82V     53mA       51.41mA    53mA
2.985V    113.1mA    109.7mA    113.1mA
3.6V      423.8mA    411.1mA    423.8mA
[Pullup]
|Voltage   I(typ)   I(min)   I(max)
-1.8V     423.8mA    442.4mA    413.3mA
-1.185V   114.8mA    145.2mA    96mA
-1.075V   72.1mA     99.6mA     58.48mA
-1.02V    56.22mA    79.4mA     48.37mA
-965mV    45.28mA    62.08mA    42.62mA
-800mV    30.91mA    31.23mA    30.7mA
-360mV    10.61mA    10.03mA    9.151mA
685mV     -14.03mA   -13.61mA   -14.03mA
2.225V    -21.86mA   -21.2mA    -21.86mA
2.665V    -48.46mA   -47.01mA   -48.46mA
2.885V    -96.4mA    -93.5mA    -96.4mA
3.6V      -453.8mA   -440.2mA   -453.8mA
[Ramp]
| variable   typ   min   max
dV/dt_r   0.502/1.570n   0.476/1.567n   0.515/1.928n
dV/dt_f   0.483/2.463n   0.465/2.370n   0.488/2.551n
R_load = 50.000
[Rising Waveform]
R_fixture = 50.000
V_fixture = 0.000
V_fixture_min = 0.000
V_fixture_max = 0.000
|  time   V(typ)   V(min)   V(max)
0s        109.1uV    -189.3uV   -295.4uV
899ps     11.2mV     -1.7mV     7.657mV
1.512ns   140.7mV    55.3mV     84.69mV
2.002ns   326.5mV    173.3mV    196.2mV
2.729ns   575.5mV    429mV      396.1mV
3.311ns   697.6mV    602.2mV    564.5mV
3.898ns   768.8mV    698.2mV    707.9mV
4.541ns   805.3mV    747mV      794.5mV
5.52ns    825.2mV    775.8mV    838.6mV
10ns      836.2mV    793.8mV    858.2mV
[Rising Waveform]
R_fixture = 50.000
V_fixture = 1.800
V_fixture_min = 1.710
V_fixture_max = 1.890
|  time   V(typ)   V(min)   V(max)
0s        994.1mV    934.7mV    1.078V
333ps     994.5mV    934.9mV    1.079V
431ps     991.7mV    935mV      1.362V
548ps     1.289V     931.6mV    1.515V
639ps     1.419V     931.4mV    1.586V
798ps     1.539V     1.27V      1.669V
922ps     1.599V     1.403V     1.713V
1.65ns    1.751V     1.637V     1.836V
3.085ns   1.792V     1.699V     1.882V
10ns      1.8V       1.71V      1.891V
[Falling Waveform]
R_fixture = 50.000
V_fixture = 1.800
V_fixture_min = 1.710
V_fixture_max = 1.890
|  time   V(typ)   V(min)   V(max)
0s        1.8V       1.71V      1.891V
502ps     1.812V     1.71V      1.896V
770ps     1.799V     1.722V     1.889V
1.298ns   1.743V     1.675V     1.837V
1.901ns   1.631V     1.569V     1.73V
3.68ns    1.24V      1.173V     1.352V
4.358ns   1.142V     1.075V     1.241V
5.09ns    1.079V     1.012V     1.161V
6.644ns   1.02V      957.5mV    1.096V
10ns      994.1mV    934.7mV    1.078V
[Falling Waveform]
R_fixture = 50.000
V_fixture = 0.000
V_fixture_min = 0.000
V_fixture_max = 0.000
|  time   V(typ)   V(min)   V(max)
0s        836.2mV    793.8mV    858.2mV
343ps     835.8mV    793.7mV    855.9mV
433ps     831.4mV    793.8mV    589.7mV
541ps     530.8mV    794.2mV    418.7mV
641ps     384.7mV    788.9mV    328.7mV
811ps     256.9mV    443.1mV    232.6mV
951ps     191.8mV    297.7mV    179.4mV
1.599ns   49.92mV    65.68mV    48.74mV
2.989ns   9.162mV    9.768mV    7.5mV
10ns      109.1uV    -189.3uV   -295.4uV
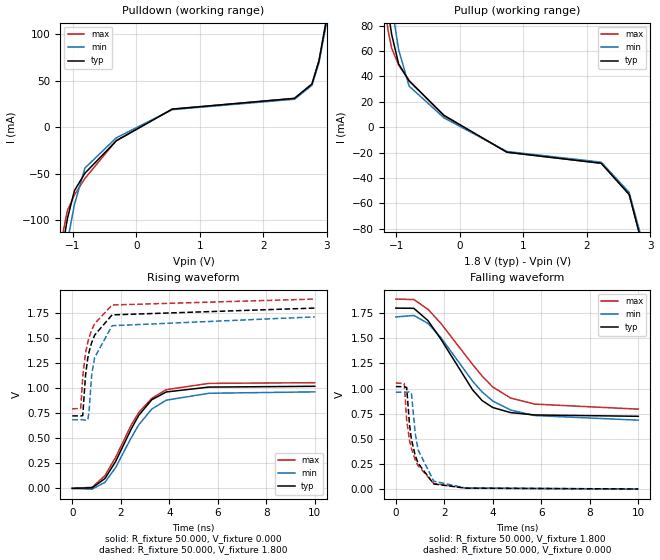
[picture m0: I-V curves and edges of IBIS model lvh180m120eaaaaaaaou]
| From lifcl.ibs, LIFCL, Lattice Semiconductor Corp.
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[Model] lvh180m120eaaaaaaaou
Model_type Output
Polarity   Non-Inverting
Enable   Active-High
Vmeas =  0.900V
Cref =  0.0F
Rref =  1.000M
Vref =  0.0V
C_comp   5.000pF   4.000pF   5.500pF
[Temperature Range]   25.000   0.125k   -40.000
[Voltage Range]   1.800V   1.710V   1.890V
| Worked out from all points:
|   slope of the pulldown table from 0 to 0.27 V, typ, clamps not added: 23.9 ohm
|   slope of the pullup table from 0 to 0.27 V, typ, clamps not added: 30.4 ohm
|   rising waveform, R_fixture 50.000, V_fixture 0.000: 20-80 % time 1.35ns typ, 1.44ns min, 1.46ns max; typ from 0 V to 1.02 V
|   rising waveform, R_fixture 50.000, V_fixture 1.800: 20-80 % time 545ps typ, 512ps min, 576ps max; typ from 0.723 V to 1.8 V
|   falling waveform, R_fixture 50.000, V_fixture 1.800: 20-80 % time 1.72ns typ, 2.05ns min, 2.23ns max; typ from 1.8 V to 0.723 V
|   falling waveform, R_fixture 50.000, V_fixture 0.000: 20-80 % time 505ps typ, 489ps min, 566ps max; typ from 1.02 V to 0 V
[Pulldown]
|Voltage   I(typ)   I(min)   I(max)
-1.8V     -445.4mA   -451.9mA   -445.5mA
-1.195V   -142.7mA   -169.4mA   -127mA
-1.085V   -98.4mA    -123.5mA   -89.8mA
-975mV    -68.5mA    -83.4mA    -73.1mA
-810mV    -49.66mA   -44.08mA   -55.35mA
-315mV    -14.72mA   -11.48mA   -14.34mA
565mV     19.44mA    18.86mA    19.44mA
2.49V     31.02mA    30.09mA    31.02mA
2.765V    46.49mA    45.09mA    46.49mA
2.875V    71.4mA     69.3mA     71.4mA
2.985V    112.7mA    109.3mA    112.7mA
3.6V      414.1mA    401.7mA    414.1mA
[Pullup]
|Voltage   I(typ)   I(min)   I(max)
-1.8V     404.1mA    420.6mA    393.9mA
-1.185V   112.3mA    139.1mA    95mA
-1.13V    91.1mA     116.9mA    76mA
-1.075V   73.1mA     96.1mA     62.2mA
-965mV    49.78mA    60.93mA    48.87mA
-800mV    36.38mA    32.35mA    36.89mA
-250mV    9.287mA    7.294mA    8.714mA
740mV     -19.76mA   -19.17mA   -19.76mA
2.225V    -28.46mA   -27.61mA   -28.46mA
2.665V    -53.01mA   -51.41mA   -53.01mA
2.885V    -95.1mA    -92.2mA    -95.1mA
3.6V      -432.1mA   -419.1mA   -432.1mA
[Ramp]
| variable   typ   min   max
dV/dt_r   0.611/1.362n   0.579/1.458n   0.633/1.480n
dV/dt_f   0.646/1.755n   0.616/2.076n   0.662/2.257n
R_load = 50.000
[Rising Waveform]
R_fixture = 50.000
V_fixture = 0.000
V_fixture_min = 0.000
V_fixture_max = 0.000
|  time   V(typ)   V(min)   V(max)
0s        101.8uV    -1.73mV    55.78uV
819ps     4.658mV    -8.347mV   10.43mV
1.348ns   98.19mV    60.23mV    126.8mV
1.788ns   268.4mV    207.4mV    310.2mV
2.428ns   591.4mV    504.1mV    630.6mV
2.741ns   729mV      634.1mV    757.7mV
3.279ns   884.8mV    791.7mV    899mV
3.875ns   962.3mV    880.1mV    985.3mV
5.635ns   1.011V     949.4mV    1.048V
10ns      1.019V     963.3mV    1.055V
[Rising Waveform]
R_fixture = 50.000
V_fixture = 1.800
V_fixture_min = 1.710
V_fixture_max = 1.890
|  time   V(typ)   V(min)   V(max)
0s        723.4mV    684.8mV    794.7mV
346ps     723.3mV    684.9mV    796.8mV
431ps     725.6mV    685.2mV    1.112V
549ps     1.135V     681.3mV    1.356V
641ps     1.302V     683.3mV    1.461V
691ps     1.361V     763mV      1.505V
798ps     1.454V     1.13V      1.579V
922ps     1.53V      1.306V     1.644V
1.641ns   1.732V     1.624V     1.831V
10ns      1.8V       1.712V     1.89V
[Falling Waveform]
R_fixture = 50.000
V_fixture = 1.800
V_fixture_min = 1.710
V_fixture_max = 1.890
|  time   V(typ)   V(min)   V(max)
0s        1.8V       1.712V     1.89V
742ps     1.798V     1.727V     1.885V
1.325ns   1.676V     1.648V     1.788V
1.855ns   1.492V     1.508V     1.649V
3.17ns    984.9mV    1.071V     1.238V
3.561ns   879.5mV    965.2mV    1.123V
3.999ns   810.6mV    875.2mV    1.015V
4.739ns   760mV      785.1mV    904.3mV
5.725ns   736.8mV    730.9mV    844.5mV
10ns      723.4mV    684.8mV    794.7mV
[Falling Waveform]
R_fixture = 50.000
V_fixture = 0.000
V_fixture_min = 0.000
V_fixture_max = 0.000
|  time   V(typ)   V(min)   V(max)
0s        1.019V     963.3mV    1.055V
346ps     1.018V     963.1mV    1.049V
446ps     1.01V      963.2mV    686.7mV
565ps     637.6mV    965.2mV    483mV
642ps     493.6mV    956.3mV    402.4mV
800ps     333.4mV    553.2mV    290.7mV
915ps     258.1mV    390.2mV    233.4mV
1.562ns   49.91mV    77.93mV    55.52mV
2.879ns   8.742mV    9.84mV     8.295mV
10ns      101.8uV    -1.73mV    55.78uV
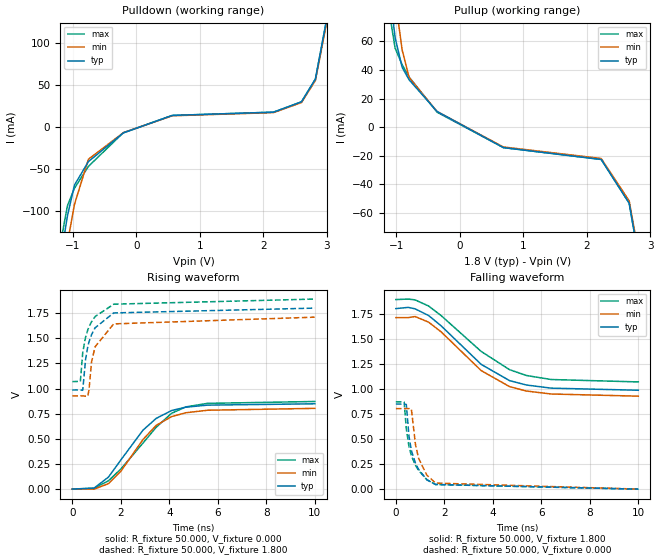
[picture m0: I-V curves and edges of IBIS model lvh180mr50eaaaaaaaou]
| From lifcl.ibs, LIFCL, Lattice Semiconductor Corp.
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[Model] lvh180mr50eaaaaaaaou
Model_type Output
Polarity   Non-Inverting
Enable   Active-High
Vmeas =  0.900V
Cref =  0.0F
Rref =  1.000M
Vref =  0.0V
C_comp   5.000pF   4.000pF   5.500pF
[Temperature Range]   25.000   0.125k   -40.000
[Voltage Range]   1.800V   1.710V   1.890V
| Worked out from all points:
|   slope of the pulldown table from 0 to 0.27 V, typ, clamps not added: 33.1 ohm
|   slope of the pullup table from 0 to 0.27 V, typ, clamps not added: 39.6 ohm
|   rising waveform, R_fixture 50.000, V_fixture 0.000: 20-80 % time 1.67ns typ, 1.56ns min, 1.89ns max; typ from 0 V to 0.848 V
|   rising waveform, R_fixture 50.000, V_fixture 1.800: 20-80 % time 535ps typ, 526ps min, 591ps max; typ from 0.986 V to 1.8 V
|   falling waveform, R_fixture 50.000, V_fixture 1.800: 20-80 % time 2.26ns typ, 2.18ns min, 2.46ns max; typ from 1.8 V to 0.986 V
|   falling waveform, R_fixture 50.000, V_fixture 0.000: 20-80 % time 522ps typ, 494ps min, 574ps max; typ from 0.848 V to 0 V
[Pulldown]
|Voltage   I(typ)   I(min)   I(max)
-1.8V     -499.1mA   -510.8mA   -495.9mA
-1.195V   -156.8mA   -190.3mA   -138.1mA
-1.085V   -105.4mA   -137.9mA   -93.5mA
-975mV    -68.84mA   -91.9mA    -72.63mA
-755mV    -40.93mA   -38.14mA   -46.64mA
-205mV    -6.889mA   -6.613mA   -6.6mA
565mV     13.91mA    13.49mA    13.91mA
2.16V     17.8mA     17.27mA    17.8mA
2.6V      30.07mA    29.17mA    30.07mA
2.82V     57.19mA    55.48mA    57.19mA
2.985V    123.3mA    119.6mA    123.3mA
3.6V      464mA      450.1mA    464mA
[Pullup]
|Voltage   I(typ)   I(min)   I(max)
-1.8V     483.2mA    504.5mA    471.7mA
-1.185V   130mA      165.3mA    109.6mA
-1.13V    103.9mA    138.4mA    85.4mA
-1.02V    62.46mA    90.1mA     55.21mA
-910mV    41.91mA    54.13mA    43.78mA
-800mV    33.13mA    34.71mA    35.04mA
-360mV    10.98mA    10.93mA    10.45mA
685mV     -14.32mA   -13.89mA   -14.32mA
2.225V    -22.62mA   -21.94mA   -22.62mA
2.665V    -53.2mA    -51.6mA    -53.2mA
2.885V    -109mA     -105.7mA   -109mA
3.6V      -517.6mA   -502.1mA   -517.6mA
[Ramp]
| variable   typ   min   max
dV/dt_r   0.509/1.671n   0.483/1.607n   0.523/1.927n
dV/dt_f   0.488/2.308n   0.470/2.265n   0.493/2.476n
R_load = 50.000
[Rising Waveform]
R_fixture = 50.000
V_fixture = 0.000
V_fixture_min = 0.000
V_fixture_max = 0.000
|  time   V(typ)   V(min)   V(max)
0s        106.1uV    504.6uV    -88.43uV
899ps     9.928mV    -785.1uV   8.031mV
1.492ns   119.2mV    53.96mV    82.3mV
2.011ns   292.2mV    179.6mV    201.7mV
2.915ns   585.7mV    492.7mV    457.5mV
3.459ns   702.8mV    633.5mV    614.4mV
4.095ns   781.2mV    721mV      753.7mV
4.679ns   814.6mV    759mV      817.3mV
5.581ns   835.1mV    784.3mV    852.7mV
10ns      848.4mV    802.9mV    871.3mV
[Rising Waveform]
R_fixture = 50.000
V_fixture = 1.800
V_fixture_min = 1.710
V_fixture_max = 1.890
|  time   V(typ)   V(min)   V(max)
0s        986mV      927mV      1.069V
333ps     986.5mV    927mV      1.071V
431ps     982.8mV    927.3mV    1.357V
548ps     1.288V     923.5mV    1.511V
639ps     1.417V     923mV      1.582V
692ps     1.466V     991.3mV    1.615V
792ps     1.534V     1.261V     1.663V
942ps     1.605V     1.416V     1.716V
1.708ns   1.752V     1.643V     1.839V
10ns      1.8V       1.71V      1.89V
[Falling Waveform]
R_fixture = 50.000
V_fixture = 1.800
V_fixture_min = 1.710
V_fixture_max = 1.890
|  time   V(typ)   V(min)   V(max)
0s        1.8V       1.71V      1.89V
512ps     1.812V     1.71V      1.895V
791ps     1.798V     1.721V     1.887V
1.35ns    1.731V     1.665V     1.826V
1.873ns   1.627V     1.567V     1.729V
3.519ns   1.244V     1.182V     1.373V
4.69ns    1.082V     1.022V     1.191V
5.39ns    1.038V     978mV      1.133V
6.404ns   1.007V     948.6mV    1.093V
10ns      986mV      927mV      1.069V
[Falling Waveform]
R_fixture = 50.000
V_fixture = 0.000
V_fixture_min = 0.000
V_fixture_max = 0.000
|  time   V(typ)   V(min)   V(max)
0s        848.4mV    802.9mV    871.3mV
343ps     847.9mV    802.8mV    868.9mV
432ps     843.6mV    802.9mV    601.3mV
542ps     526.7mV    803.3mV    424.1mV
641ps     385.3mV    797.5mV    333.8mV
811ps     258.1mV    442.6mV    236.2mV
941ps     196.5mV    305.8mV    185.6mV
1.281ns   93.32mV    139.6mV    93.79mV
1.641ns   46.25mV    60.36mV    46.27mV
10ns      106.1uV    504.6uV    -88.43uV
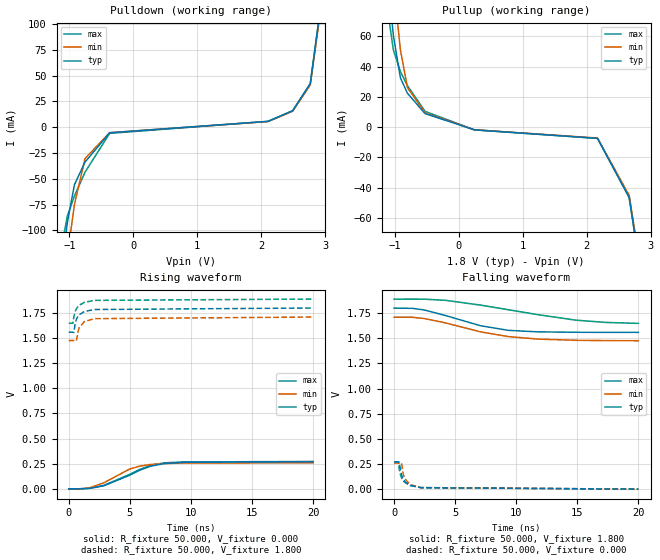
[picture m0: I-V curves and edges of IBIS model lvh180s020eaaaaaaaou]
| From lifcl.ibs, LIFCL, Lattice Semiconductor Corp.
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[Model] lvh180s020eaaaaaaaou
Model_type Output
Polarity   Non-Inverting
Enable   Active-High
Vmeas =  0.900V
Cref =  0.0F
Rref =  1.000M
Vref =  0.0V
C_comp   5.000pF   4.000pF   5.500pF
[Temperature Range]   25.000   0.125k   -40.000
[Voltage Range]   1.800V   1.710V   1.890V
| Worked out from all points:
|   slope of the pulldown table from 0 to 0.27 V, typ, clamps not added: 112 ohm
|   slope of the pullup table from 0 to 0.27 V, typ, clamps not added: 139 ohm
|   rising waveform, R_fixture 50.000, V_fixture 0.000: 20-80 % time 2.97ns typ, 2.5ns min, 2.94ns max; typ from 0 V to 0.27 V
|   rising waveform, R_fixture 50.000, V_fixture 1.800: 20-80 % time 569ps typ, 544ps min, 612ps max; typ from 1.56 V to 1.8 V
|   falling waveform, R_fixture 50.000, V_fixture 1.800: 20-80 % time 4.25ns typ, 5.07ns min, 7.3ns max; typ from 1.8 V to 1.56 V
|   falling waveform, R_fixture 50.000, V_fixture 0.000: 20-80 % time 563ps typ, 550ps min, 605ps max; typ from 0.27 V to 0 V
[Pulldown]
|Voltage   I(typ)   I(min)   I(max)
-1.8V     -596.5mA   -588.3mA   -599.3mA
-1.14V    -149.6mA   -183.8mA   -130.4mA
-1.085V   -118.9mA   -153.6mA   -104mA
-1.03V    -92.1mA    -124.8mA   -85.94mA
-920mV    -55.8mA    -74.97mA   -66.68mA
-755mV    -33.91mA   -30.48mA   -43.69mA
-370mV    -5.454mA   -5.346mA   -6.032mA
2.105V    5.612mA    5.443mA    5.612mA
2.49V     15.89mA    15.41mA    15.89mA
2.765V    42.2mA     40.93mA    42.2mA
2.985V    143.4mA    139.1mA    143.4mA
3.6V      555mA      538.3mA    555mA
[Pullup]
|Voltage   I(typ)   I(min)   I(max)
-1.8V     556.2mA    580.5mA    544.4mA
-1.13V    112.6mA    153.6mA    91.2mA
-1.075V   84.2mA     123.5mA    67.08mA
-1.02V    60.53mA    95.7mA     51.03mA
-910mV    32.55mA    51.06mA    36.67mA
-800mV    22.37mA    26.11mA    27.37mA
-525mV    8.937mA    9.479mA    10.43mA
245mV     -1.782mA   -1.729mA   -1.782mA
2.17V     -7.419mA   -7.197mA   -7.419mA
2.665V    -46.41mA   -45.02mA   -46.41mA
2.83V     -92.1mA    -89.3mA    -92.1mA
3.6V      -597.4mA   -579.5mA   -597.4mA
[Ramp]
| variable   typ   min   max
dV/dt_r   0.162/3.011n   0.155/2.520n   0.163/2.968n
dV/dt_f   0.145/4.262n   0.140/5.079n   0.145/7.314n
R_load = 50.000
[Rising Waveform]
R_fixture = 50.000
V_fixture = 0.000
V_fixture_min = 0.000
V_fixture_max = 0.000
|  time   V(typ)   V(min)   V(max)
0s        158.1uV    257.1uV    444.8uV
726ps     -510.9uV   -3.504mV   -11.28uV
1.678ns   3.756mV    8.812mV    4.704mV
2.88ns    30.06mV    60.14mV    35.09mV
4.957ns   134mV      195.2mV    142mV
5.794ns   184.1mV    225.5mV    192mV
6.68ns    224.2mV    242.1mV    233.5mV
7.795ns   250.7mV    251.5mV    258.1mV
9.425ns   264mV      256.4mV    268.1mV
20ns      269.7mV    259.3mV    271.9mV
[Rising Waveform]
R_fixture = 50.000
V_fixture = 1.800
V_fixture_min = 1.710
V_fixture_max = 1.890
|  time   V(typ)   V(min)   V(max)
0s        1.559V     1.476V     1.648V
334ps     1.559V     1.476V     1.648V
420ps     1.556V     1.476V     1.712V
528ps     1.648V     1.476V     1.766V
626ps     1.688V     1.472V     1.792V
766ps     1.719V     1.568V     1.816V
858ps     1.733V     1.605V     1.827V
1.277ns   1.765V     1.665V     1.856V
2.096ns   1.785V     1.694V     1.876V
20ns      1.8V       1.71V      1.889V
[Falling Waveform]
R_fixture = 50.000
V_fixture = 1.800
V_fixture_min = 1.710
V_fixture_max = 1.890
|  time   V(typ)   V(min)   V(max)
0s        1.8V       1.71V      1.889V
1.478ns   1.798V     1.709V     1.89V
2.458ns   1.782V     1.697V     1.889V
4.25ns    1.725V     1.652V     1.877V
7.073ns   1.625V     1.564V     1.83V
9.356ns   1.579V     1.517V     1.784V
11.77ns   1.564V     1.492V     1.735V
14.89ns   1.56V      1.48V      1.68V
17.31ns   1.559V     1.477V     1.658V
20ns      1.559V     1.476V     1.648V
[Falling Waveform]
R_fixture = 50.000
V_fixture = 0.000
V_fixture_min = 0.000
V_fixture_max = 0.000
|  time   V(typ)   V(min)   V(max)
0s        269.7mV    259.3mV    271.9mV
336ps     269.2mV    259.1mV    272.6mV
426ps     270.2mV    259.3mV    198.5mV
499ps     215.2mV    258.9mV    152.6mV
615ps     138.1mV    261.6mV    112.6mV
745ps     98.53mV    153mV      85.49mV
874ps     75.12mV    104.7mV    67.77mV
1.32ns    37.25mV    45.1mV     36.48mV
2.195ns   14.74mV    15.55mV    15.7mV
20ns      158.1uV    257.1uV    444.8uV
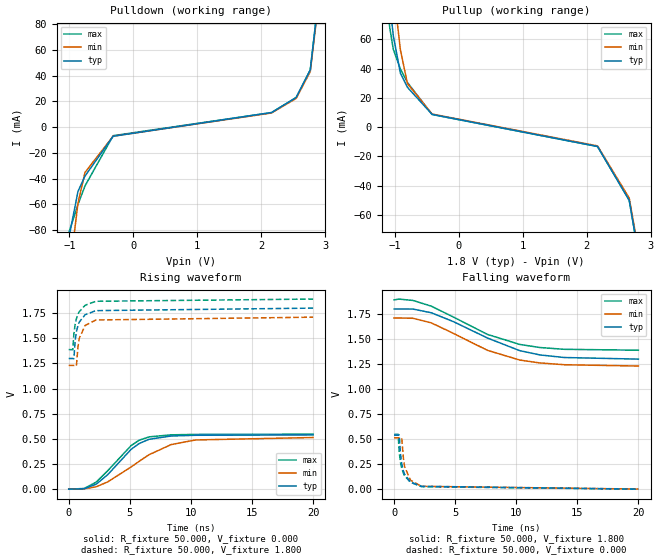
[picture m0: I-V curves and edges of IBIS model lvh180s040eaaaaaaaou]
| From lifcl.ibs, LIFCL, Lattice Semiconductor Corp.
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[Model] lvh180s040eaaaaaaaou
Model_type Output
Polarity   Non-Inverting
Enable   Active-High
Vmeas =  0.900V
Cref =  0.0F
Rref =  1.000M
Vref =  0.0V
C_comp   5.000pF   4.000pF   5.500pF
[Temperature Range]   25.000   0.125k   -40.000
[Voltage Range]   1.800V   1.710V   1.890V
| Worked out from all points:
|   slope of the pulldown table from 0 to 0.27 V, typ, clamps not added: 53.9 ohm
|   slope of the pullup table from 0 to 0.27 V, typ, clamps not added: 67.5 ohm
|   rising waveform, R_fixture 50.000, V_fixture 0.000: 20-80 % time 2.6ns typ, 4.02ns min, 2.54ns max; typ from 0 V to 0.539 V
|   rising waveform, R_fixture 50.000, V_fixture 1.800: 20-80 % time 567ps typ, 547ps min, 610ps max; typ from 1.3 V to 1.8 V
|   falling waveform, R_fixture 50.000, V_fixture 1.800: 20-80 % time 5.5ns typ, 5.11ns min, 5.17ns max; typ from 1.8 V to 1.3 V
|   falling waveform, R_fixture 50.000, V_fixture 0.000: 20-80 % time 561ps typ, 549ps min, 603ps max; typ from 0.539 V to 0 V
[Pulldown]
|Voltage   I(typ)   I(min)   I(max)
-1.8V     -574.7mA   -585.3mA   -571.8mA
-1.195V   -177.7mA   -215.5mA   -156.2mA
-1.14V    -146.2mA   -184.6mA   -126.3mA
-1.03V    -92mA      -126.5mA   -85.59mA
-865mV    -50.11mA   -59.21mA   -60.22mA
-755mV    -38.07mA   -35.27mA   -45.74mA
-315mV    -7.086mA   -7.007mA   -6.648mA
2.16V     11.36mA    11.02mA    11.36mA
2.545V    23.08mA    22.38mA    23.08mA
2.765V    44.55mA    43.21mA    44.55mA
2.985V    139.6mA    135.4mA    139.6mA
3.6V      534.6mA    518.6mA    534.6mA
[Pullup]
|Voltage   I(typ)   I(min)   I(max)
-1.8V     534.8mA    558.2mA    522.8mA
-1.185V   140.5mA    179.8mA    117.9mA
-1.13V    110.8mA    149.6mA    89.9mA
-1.075V   84.06mA    120.9mA    67.53mA
-1.02V    62.15mA    94.7mA     53.03mA
-910mV    36.88mA    52.81mA    39.7mA
-800mV    27.18mA    29.74mA    30.53mA
-415mV    8.734mA    8.939mA    8.611mA
2.17V     -13.2mA    -12.8mA    -13.2mA
2.665V    -49.88mA   -48.38mA   -49.88mA
2.83V     -91.5mA    -88.8mA    -91.5mA
3.6V      -573.8mA   -556.6mA   -573.8mA
[Ramp]
| variable   typ   min   max
dV/dt_r   0.323/2.626n   0.309/4.025n   0.328/2.546n
dV/dt_f   0.300/5.549n   0.291/5.122n   0.301/5.194n
R_load = 50.000
[Rising Waveform]
R_fixture = 50.000
V_fixture = 0.000
V_fixture_min = 0.000
V_fixture_max = 0.000
|  time   V(typ)   V(min)   V(max)
0s        136.7uV    786.1uV    -148.8uV
1.268ns   3.97mV     2.525mV    6.768mV
2.257ns   49.93mV    24.04mV    70.78mV
3.191ns   144.2mV    72.39mV    183.3mV
5.1ns     395.2mV    220.5mV    432.5mV
5.765ns   453.9mV    277mV      486.9mV
6.575ns   495.8mV    342.4mV    519.8mV
8.379ns   528.4mV    443.1mV    540.1mV
10.38ns   535.8mV    489.2mV    544.2mV
20ns      539mV      513.4mV    546.7mV
[Rising Waveform]
R_fixture = 50.000
V_fixture = 1.800
V_fixture_min = 1.710
V_fixture_max = 1.890
|  time   V(typ)   V(min)   V(max)
0s        1.299V     1.23V      1.388V
334ps     1.299V     1.23V      1.387V
419ps     1.297V     1.23V      1.543V
526ps     1.477V     1.229V     1.641V
627ps     1.566V     1.225V     1.694V
756ps     1.628V     1.416V     1.739V
858ps     1.66V      1.499V     1.764V
1.338ns   1.734V     1.627V     1.828V
2.217ns   1.775V     1.682V     1.868V
20ns      1.8V       1.71V      1.89V
[Falling Waveform]
R_fixture = 50.000
V_fixture = 1.800
V_fixture_min = 1.710
V_fixture_max = 1.890
|  time   V(typ)   V(min)   V(max)
0s        1.8V       1.71V      1.89V
383ps     1.8V       1.71V      1.899V
1.555ns   1.799V     1.707V     1.885V
3.05ns    1.762V     1.661V     1.828V
4.831ns   1.675V     1.558V     1.721V
7.64ns    1.51V      1.387V     1.546V
10.28ns   1.384V     1.29V      1.446V
11.93ns   1.341V     1.261V     1.415V
13.94ns   1.315V     1.243V     1.397V
20ns      1.299V     1.23V      1.388V
[Falling Waveform]
R_fixture = 50.000
V_fixture = 0.000
V_fixture_min = 0.000
V_fixture_max = 0.000
|  time   V(typ)   V(min)   V(max)
0s        539mV      513.4mV    546.7mV
333ps     538.5mV    513.2mV    548.8mV
421ps     541.9mV    513.4mV    372mV
529ps     351.3mV    513.2mV    265.5mV
629ps     252.9mV    512.6mV    208.9mV
765ps     181.7mV    307.3mV    158.6mV
859ps     149.8mV    227.7mV    134.3mV
1.339ns   71.53mV    89.58mV    68.68mV
2.245ns   28.47mV    28.43mV    24.53mV
20ns      136.7uV    786.1uV    -148.8uV
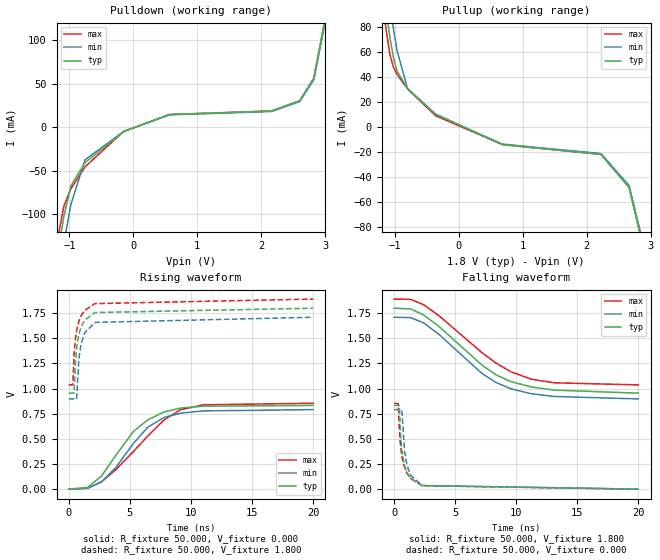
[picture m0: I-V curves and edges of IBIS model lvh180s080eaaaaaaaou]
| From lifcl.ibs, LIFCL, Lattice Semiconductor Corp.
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[Model] lvh180s080eaaaaaaaou
Model_type Output
Polarity   Non-Inverting
Enable   Active-High
Vmeas =  0.900V
Cref =  0.0F
Rref =  1.000M
Vref =  0.0V
C_comp   5.000pF   4.000pF   5.500pF
[Temperature Range]   25.000   0.125k   -40.000
[Voltage Range]   1.800V   1.710V   1.890V
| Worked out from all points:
|   slope of the pulldown table from 0 to 0.27 V, typ, clamps not added: 31.8 ohm
|   slope of the pullup table from 0 to 0.27 V, typ, clamps not added: 40.7 ohm
|   rising waveform, R_fixture 50.000, V_fixture 0.000: 20-80 % time 3.27ns typ, 3.18ns min, 4.11ns max; typ from 0 V to 0.833 V
|   rising waveform, R_fixture 50.000, V_fixture 1.800: 20-80 % time 567ps typ, 549ps min, 610ps max; typ from 0.955 V to 1.8 V
|   falling waveform, R_fixture 50.000, V_fixture 1.800: 20-80 % time 5ns typ, 4.76ns min, 5.23ns max; typ from 1.8 V to 0.955 V
|   falling waveform, R_fixture 50.000, V_fixture 0.000: 20-80 % time 555ps typ, 548ps min, 599ps max; typ from 0.833 V to 0 V
[Pulldown]
|Voltage   I(typ)   I(min)   I(max)
-1.8V     -480.5mA   -490mA     -478mA
-1.195V   -151.2mA   -182.8mA   -133.3mA
-1.085V   -102.1mA   -132.8mA   -90.4mA
-975mV    -67.35mA   -88.7mA    -70.58mA
-755mV    -40.72mA   -37.48mA   -45.52mA
-150mV    -5.225mA   -4.853mA   -4.857mA
565mV     14.48mA    14.05mA    14.48mA
2.16V     18.47mA    17.92mA    18.47mA
2.6V      30.21mA    29.31mA    30.21mA
2.82V     55.87mA    54.2mA     55.87mA
2.985V    119.2mA    115.6mA    119.2mA
3.6V      446.7mA    433.3mA    446.7mA
[Pullup]
|Voltage   I(typ)   I(min)   I(max)
-1.8V     421.6mA    440.1mA    411.1mA
-1.185V   114.2mA    144.4mA    95.5mA
-1.075V   71.7mA     99.1mA     58.18mA
-1.02V    55.92mA    79mA       48.12mA
-965mV    45.05mA    61.76mA    42.4mA
-800mV    30.75mA    31.07mA    30.54mA
-360mV    10.55mA    9.977mA    9.103mA
685mV     -13.96mA   -13.54mA   -13.96mA
2.225V    -21.74mA   -21.09mA   -21.74mA
2.665V    -48.21mA   -46.76mA   -48.21mA
2.885V    -95.9mA    -93mA      -95.9mA
3.6V      -451.4mA   -437.9mA   -451.4mA
[Ramp]
| variable   typ   min   max
dV/dt_r   0.500/3.285n   0.475/3.227n   0.513/4.120n
dV/dt_f   0.507/5.030n   0.488/4.778n   0.513/5.240n
R_load = 50.000
[Rising Waveform]
R_fixture = 50.000
V_fixture = 0.000
V_fixture_min = 0.000
V_fixture_max = 0.000
|  time   V(typ)   V(min)   V(max)
0s        110.8uV    -182.3uV   -338.1uV
1.528ns   16.44mV    7.902mV    8.434mV
2.684ns   130.7mV    72.71mV    72.04mV
3.829ns   331.5mV    211.9mV    191.2mV
5.28ns    572.3mV    452.8mV    372.4mV
6.454ns   688.4mV    615mV      527.4mV
7.806ns   768.1mV    713.4mV    688.6mV
9.159ns   806.4mV    756mV      790.6mV
11.02ns   825mV      778.6mV    839mV
20ns      832.9mV    790.8mV    854.7mV
[Rising Waveform]
R_fixture = 50.000
V_fixture = 1.800
V_fixture_min = 1.710
V_fixture_max = 1.890
|  time   V(typ)   V(min)   V(max)
0s        954.9mV    897.4mV    1.037V
333ps     955.3mV    897.5mV    1.038V
441ps     959mV      897.9mV    1.354V
548ps     1.264V     894.1mV    1.495V
642ps     1.403V     894.5mV    1.572V
831ps     1.542V     1.298V     1.669V
999ps     1.611V     1.438V     1.721V
1.299ns   1.68V      1.554V     1.778V
2.149ns   1.757V     1.659V     1.846V
20ns      1.8V       1.71V      1.891V
[Falling Waveform]
R_fixture = 50.000
V_fixture = 1.800
V_fixture_min = 1.710
V_fixture_max = 1.890
|  time   V(typ)   V(min)   V(max)
0s        1.8V       1.71V      1.891V
1.36ns    1.793V     1.706V     1.888V
2.449ns   1.731V     1.652V     1.833V
3.699ns   1.616V     1.537V     1.723V
7.184ns   1.235V     1.152V     1.359V
8.347ns   1.137V     1.061V     1.254V
9.575ns   1.069V     997.7mV    1.167V
11.23ns   1.017V     949.4mV    1.094V
13.1ns    985.3mV    922mV      1.058V
20ns      954.9mV    897.4mV    1.037V
[Falling Waveform]
R_fixture = 50.000
V_fixture = 0.000
V_fixture_min = 0.000
V_fixture_max = 0.000
|  time   V(typ)   V(min)   V(max)
0s        832.9mV    790.8mV    854.7mV
346ps     832.5mV    790.7mV    850.2mV
432ps     829.6mV    790.8mV    590.1mV
541ps     529mV      791.1mV    417.3mV
642ps     382.4mV    785.5mV    326.9mV
861ps     232.4mV    376mV      213.4mV
1.052ns   165.5mV    240.1mV    158.4mV
1.362ns   107mV      136.9mV    106.4mV
2.3ns     34.55mV    36.4mV     33.86mV
20ns      110.8uV    -182.3uV   -338.1uV
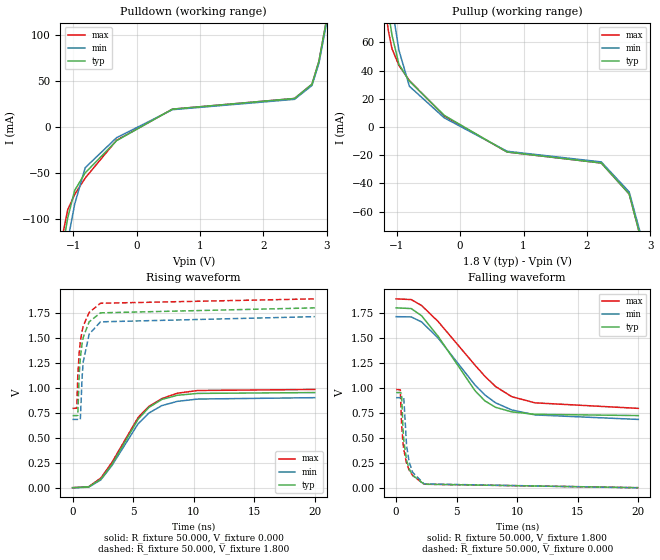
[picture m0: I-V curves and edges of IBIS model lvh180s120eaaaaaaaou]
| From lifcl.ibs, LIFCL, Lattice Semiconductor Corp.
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[Model] lvh180s120eaaaaaaaou
Model_type Output
Polarity   Non-Inverting
Enable   Active-High
Vmeas =  0.900V
Cref =  0.0F
Rref =  1.000M
Vref =  0.0V
C_comp   5.000pF   4.000pF   5.500pF
[Temperature Range]   25.000   0.125k   -40.000
[Voltage Range]   1.800V   1.710V   1.890V
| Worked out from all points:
|   slope of the pulldown table from 0 to 0.27 V, typ, clamps not added: 23.9 ohm
|   slope of the pullup table from 0 to 0.27 V, typ, clamps not added: 33.9 ohm
|   rising waveform, R_fixture 50.000, V_fixture 0.000: 20-80 % time 2.91ns typ, 3.03ns min, 3.08ns max; typ from 0 V to 0.952 V
|   rising waveform, R_fixture 50.000, V_fixture 1.800: 20-80 % time 567ps typ, 549ps min, 609ps max; typ from 0.722 V to 1.8 V
|   falling waveform, R_fixture 50.000, V_fixture 1.800: 20-80 % time 3.69ns typ, 4.32ns min, 4.79ns max; typ from 1.8 V to 0.722 V
|   falling waveform, R_fixture 50.000, V_fixture 0.000: 20-80 % time 553ps typ, 548ps min, 597ps max; typ from 0.952 V to 0 V
[Pulldown]
|Voltage   I(typ)   I(min)   I(max)
-1.8V     -446.5mA   -453mA     -445.9mA
-1.195V   -143mA     -169.9mA   -127.2mA
-1.085V   -98.6mA    -123.8mA   -89.9mA
-975mV    -68.8mA    -83.6mA    -73.2mA
-810mV    -49.78mA   -44.19mA   -55.42mA
-315mV    -14.76mA   -11.51mA   -14.36mA
565mV     19.49mA    18.9mA     19.49mA
2.49V     31.09mA    30.16mA    31.09mA
2.765V    46.6mA     45.2mA     46.6mA
2.875V    71.6mA     69.5mA     71.6mA
2.985V    112.9mA    109.5mA    112.9mA
3.6V      415mA      402.5mA    415mA
[Pullup]
|Voltage   I(typ)   I(min)   I(max)
-1.8V     361.7mA    376.4mA    352.5mA
-1.185V   100.5mA    124.5mA    85mA
-1.13V    81.5mA     104.6mA    68mA
-1.075V   65.4mA     86mA       55.66mA
-965mV    44.55mA    54.52mA    43.73mA
-800mV    32.55mA    28.95mA    33.01mA
-250mV    8.31mA     6.527mA    7.798mA
740mV     -17.68mA   -17.15mA   -17.68mA
2.225V    -25.47mA   -24.71mA   -25.47mA
2.665V    -47.43mA   -46.01mA   -47.43mA
2.885V    -85.1mA    -82.5mA    -85.1mA
3.6V      -386.6mA   -375mA     -386.6mA
[Ramp]
| variable   typ   min   max
dV/dt_r   0.571/2.926n   0.542/3.041n   0.590/3.099n
dV/dt_f   0.647/3.715n   0.617/4.333n   0.663/4.805n
R_load = 50.000
[Rising Waveform]
R_fixture = 50.000
V_fixture = 0.000
V_fixture_min = 0.000
V_fixture_max = 0.000
|  time   V(typ)   V(min)   V(max)
0s        102.6uV    -1.732mV   45.58uV
1.327ns   7.795mV    5.075mV    9.156mV
2.337ns   84.91mV    78.56mV    96.81mV
3.249ns   232.3mV    221.9mV    252.5mV
5.417ns   685.5mV    640.3mV    703.6mV
6.304ns   803.6mV    747.4mV    813.9mV
7.374ns   883.2mV    821.6mV    891.8mV
8.655ns   925mV      864.2mV    945.4mV
10.34ns   943.7mV    887.1mV    972.9mV
20ns      952mV      901mV      983mV
[Rising Waveform]
R_fixture = 50.000
V_fixture = 1.800
V_fixture_min = 1.710
V_fixture_max = 1.890
|  time   V(typ)   V(min)   V(max)
0s        721.7mV    683.2mV    793.7mV
346ps     721.6mV    683.2mV    795.6mV
431ps     723.4mV    683.5mV    1.111V
549ps     1.134V     679.6mV    1.356V
642ps     1.302V     681.5mV    1.461V
791ps     1.447V     1.112V     1.572V
881ps     1.505V     1.26V      1.618V
1.369ns   1.66V      1.536V     1.754V
2.303ns   1.75V      1.66V      1.846V
20ns      1.8V       1.712V     1.89V
[Falling Waveform]
R_fixture = 50.000
V_fixture = 1.800
V_fixture_min = 1.710
V_fixture_max = 1.890
|  time   V(typ)   V(min)   V(max)
0s        1.8V       1.712V     1.89V
1.245ns   1.793V     1.709V     1.883V
2.108ns   1.72V      1.659V     1.823V
3.47ns    1.515V     1.497V     1.663V
6.51ns    971.5mV    1.028V     1.227V
7.325ns   869.4mV    928.4mV    1.116V
8.215ns   804.3mV    849.4mV    1.012V
9.549ns   758.8mV    778mV      910.9mV
11.47ns   734.5mV    728.3mV    849.2mV
20ns      721.7mV    683.2mV    793.7mV
[Falling Waveform]
R_fixture = 50.000
V_fixture = 0.000
V_fixture_min = 0.000
V_fixture_max = 0.000
|  time   V(typ)   V(min)   V(max)
0s        952mV      901mV      983mV
344ps     951.7mV    900.9mV    979.7mV
446ps     943.6mV    901mV      639.7mV
565ps     595.9mV    902.8mV    450mV
632ps     474.9mV    900mV      383.6mV
862ps     275.4mV    422mV      244.2mV
1.075ns   187.8mV    258.2mV    175.8mV
1.361ns   125mV      154.1mV    122.4mV
2.305ns   34.49mV    37.59mV    34.78mV
20ns      102.6uV    -1.732mV   45.58uV
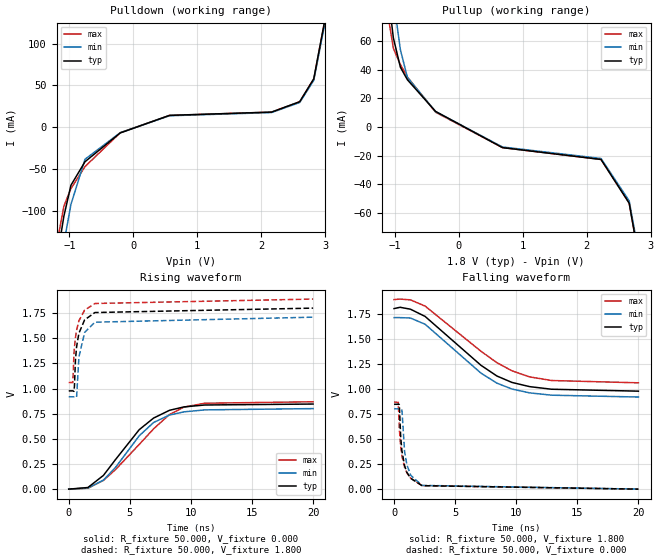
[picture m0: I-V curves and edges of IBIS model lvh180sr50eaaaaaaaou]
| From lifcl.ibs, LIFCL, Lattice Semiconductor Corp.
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[Model] lvh180sr50eaaaaaaaou
Model_type Output
Polarity   Non-Inverting
Enable   Active-High
Vmeas =  0.900V
Cref =  0.0F
Rref =  1.000M
Vref =  0.0V
C_comp   5.000pF   4.000pF   5.500pF
[Temperature Range]   25.000   0.125k   -40.000
[Voltage Range]   1.800V   1.710V   1.890V
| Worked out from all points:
|   slope of the pulldown table from 0 to 0.27 V, typ, clamps not added: 32.7 ohm
|   slope of the pullup table from 0 to 0.27 V, typ, clamps not added: 39.8 ohm
|   rising waveform, R_fixture 50.000, V_fixture 0.000: 20-80 % time 3.53ns typ, 3.26ns min, 4.11ns max; typ from 0 V to 0.846 V
|   rising waveform, R_fixture 50.000, V_fixture 1.800: 20-80 % time 567ps typ, 549ps min, 610ps max; typ from 0.977 V to 1.8 V
|   falling waveform, R_fixture 50.000, V_fixture 1.800: 20-80 % time 4.76ns typ, 4.57ns min, 5.22ns max; typ from 1.8 V to 0.977 V
|   falling waveform, R_fixture 50.000, V_fixture 0.000: 20-80 % time 555ps typ, 547ps min, 599ps max; typ from 0.846 V to 0 V
[Pulldown]
|Voltage   I(typ)   I(min)   I(max)
-1.8V     -505.2mA   -515.5mA   -503.2mA
-1.195V   -158.7mA   -192mA     -140.2mA
-1.085V   -106.7mA   -139.2mA   -94.7mA
-975mV    -69.7mA    -92.7mA    -73.71mA
-755mV    -41.44mA   -38.5mA    -47.33mA
-205mV    -6.974mA   -6.675mA   -6.699mA
565mV     14.08mA    13.66mA    14.08mA
2.16V     18.02mA    17.48mA    18.02mA
2.6V      30.45mA    29.53mA    30.45mA
2.82V     57.91mA    56.17mA    57.91mA
2.985V    124.9mA    121.2mA    124.9mA
3.6V      469.8mA    455.7mA    469.8mA
[Pullup]
|Voltage   I(typ)   I(min)   I(max)
-1.8V     481.4mA    502.8mA    470.1mA
-1.185V   129.6mA    164.8mA    109.2mA
-1.13V    103.6mA    138mA      85.1mA
-1.02V    62.25mA    89.7mA     55.02mA
-910mV    41.77mA    53.95mA    43.63mA
-800mV    33.02mA    34.6mA     34.93mA
-360mV    10.94mA    10.9mA     10.41mA
685mV     -14.28mA   -13.85mA   -14.28mA
2.225V    -22.54mA   -21.86mA   -22.54mA
2.665V    -53.02mA   -51.43mA   -53.02mA
2.885V    -108.6mA   -105.3mA   -108.6mA
3.6V      -515.8mA   -500.3mA   -515.8mA
[Ramp]
| variable   typ   min   max
dV/dt_r   0.508/3.546n   0.482/3.296n   0.521/4.120n
dV/dt_f   0.494/4.772n   0.475/4.589n   0.498/5.233n
R_load = 50.000
[Rising Waveform]
R_fixture = 50.000
V_fixture = 0.000
V_fixture_min = 0.000
V_fixture_max = 0.000
|  time   V(typ)   V(min)   V(max)
0s        114.2uV    551uV      -72.53uV
1.569ns   16.32mV    9.934mV    9.965mV
2.839ns   136.8mV    90.03mV    87.21mV
3.828ns   294.2mV    216.1mV    194.5mV
5.77ns    591.5mV    530.8mV    444.7mV
6.945ns   706.9mV    662.8mV    599.7mV
8.246ns   784mV      736.9mV    742.3mV
9.428ns   817.7mV    768.5mV    815.8mV
11.14ns   836.8mV    788.3mV    854.3mV
20ns      846.3mV    800.9mV    869mV
[Rising Waveform]
R_fixture = 50.000
V_fixture = 1.800
V_fixture_min = 1.710
V_fixture_max = 1.890
|  time   V(typ)   V(min)   V(max)
0s        976.9mV    918.3mV    1.06V
333ps     977.3mV    918.4mV    1.06V
429ps     972.1mV    918.6mV    1.346V
468ps     1.028V     918.9mV    1.412V
548ps     1.282V     914.7mV    1.506V
642ps     1.416V     914.9mV    1.58V
832ps     1.55V      1.314V     1.674V
1.298ns   1.683V     1.558V     1.78V
2.142ns   1.756V     1.66V      1.846V
20ns      1.8V       1.71V      1.89V
[Falling Waveform]
R_fixture = 50.000
V_fixture = 1.800
V_fixture_min = 1.710
V_fixture_max = 1.890
|  time   V(typ)   V(min)   V(max)
0s        1.8V       1.71V      1.89V
491ps     1.813V     1.71V      1.895V
1.341ns   1.794V     1.706V     1.887V
2.541ns   1.722V     1.644V     1.825V
7.111ns   1.235V     1.157V     1.375V
8.416ns   1.128V     1.057V     1.261V
9.645ns   1.064V     998.3mV    1.18V
11.1ns    1.022V     959.8mV    1.119V
12.9ns    996.1mV    936.8mV    1.083V
20ns      976.9mV    918.3mV    1.06V
[Falling Waveform]
R_fixture = 50.000
V_fixture = 0.000
V_fixture_min = 0.000
V_fixture_max = 0.000
|  time   V(typ)   V(min)   V(max)
0s        846.3mV    800.9mV    869mV
346ps     845.9mV    800.7mV    864.4mV
429ps     844mV      800.9mV    607.6mV
542ps     525.6mV    801.3mV    423.2mV
641ps     384.6mV    795.7mV    333.3mV
861ps     234.3mV    376.7mV    217.2mV
1.051ns   167.4mV    242.2mV    161.5mV
1.362ns   108.1mV    138.5mV    108.4mV
2.291ns   34.92mV    37.6mV     34.95mV
20ns      114.2uV    551uV      -72.53uV
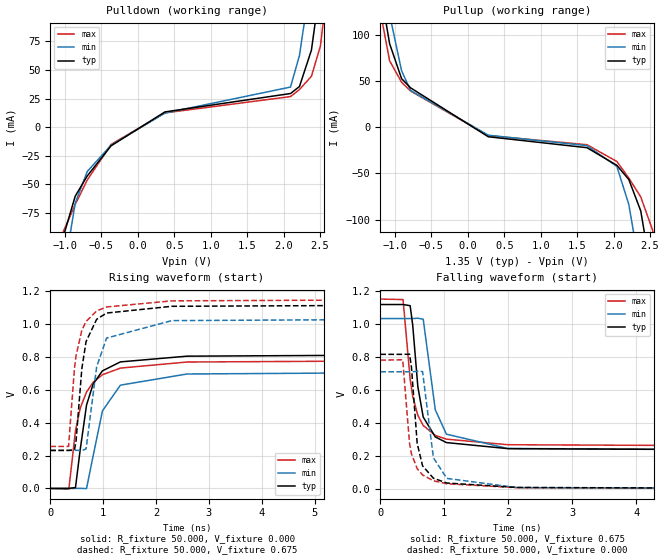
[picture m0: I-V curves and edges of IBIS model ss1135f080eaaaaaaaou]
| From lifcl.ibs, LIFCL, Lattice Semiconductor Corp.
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[Model] ss1135f080eaaaaaaaou
Model_type Output
Polarity   Non-Inverting
Enable   Active-High
Vmeas =  0.675V
Cref =  30.000pF
Rref =  50.000
Vref =  0.675V
C_comp   5.000pF   4.000pF   5.500pF
[Temperature Range]   25.000   0.125k   -40.000
[Voltage Range]   1.350V   1.280V   1.420V
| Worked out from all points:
|   slope of the pulldown table from 0 to 0.203 V, typ, clamps not added: 25.7 ohm
|   slope of the pullup table from 0 to 0.203 V, typ, clamps not added: 25.7 ohm
|   rising waveform, R_fixture 50.000, V_fixture 0.000: 20-80 % time 296ps typ, 349ps min, 353ps max; typ from 0 V to 0.816 V
|   rising waveform, R_fixture 50.000, V_fixture 0.675: 20-80 % time 203ps typ, 247ps min, 220ps max; typ from 0.231 V to 1.12 V
|   falling waveform, R_fixture 50.000, V_fixture 0.675: 20-80 % time 177ps typ, 194ps min, 200ps max; typ from 1.12 V to 0.231 V
|   falling waveform, R_fixture 50.000, V_fixture 0.000: 20-80 % time 134ps typ, 152ps min, 147ps max; typ from 0.816 V to 0 V
[Pulldown]
|Voltage   I(typ)   I(min)   I(max)
-1.35V    -277.3mA   -315.7mA   -254.1mA
-1.145V   -153.3mA   -194.8mA   -131.7mA
-1.022V   -95.8mA    -129.9mA   -91.2mA
-858mV    -60.27mA   -66.38mA   -67.52mA
-694mV    -42.7mA    -38.82mA   -46.28mA
-366mV    -16.29mA   -15.7mA    -15.06mA
372mV     13.29mA    12.25mA    12.43mA
2.094V    29.34mA    34.99mA    26.68mA
2.217V    35.47mA    62.59mA    32.81mA
2.381V    67.25mA    133.4mA    44.4mA
2.504V    124.1mA    199.9mA    70.74mA
2.7V      240.2mA    315mA      175mA
[Pullup]
|Voltage   I(typ)   I(min)   I(max)
-1.35V    235.7mA    270.5mA    212.2mA
-1.195V   147.7mA    184mA      123.1mA
-1.072V   90.3mA     122mA      71.84mA
-908mV    52.49mA    60.97mA    48.62mA
-785mV    42.56mA    39.71mA    39.12mA
281mV     -10.4mA    -8.72mA    -9.156mA
1.634V    -22.24mA   -20.02mA   -19.01mA
2.044V    -41.33mA   -42.48mA   -37.17mA
2.208V    -56.68mA   -83.7mA    -55.1mA
2.372V    -90.7mA    -159.1mA   -75.52mA
2.536V    -168.2mA   -250.1mA   -111.9mA
2.7V      -265mA     -347.3mA   -197.5mA
[Ramp]
| variable   typ   min   max
dV/dt_r   0.490/0.296n   0.426/0.346n   0.469/0.355n
dV/dt_f   0.499/0.285n   0.460/0.289n   0.496/0.351n
R_load = 50.000
[Rising Waveform]
R_fixture = 50.000
V_fixture = 0.000
V_fixture_min = 0.000
V_fixture_max = 0.000
|  time   V(typ)   V(min)   V(max)
0s        16.67uV    136.1uV    7.524uV
351ps     414.8uV    160.6uV    -4.363mV
477ps     5.224mV    240.8uV    351.3mV
567ps     237.6mV    570.1uV    488.4mV
686ps     507.1mV    -812.5uV   586.3mV
812ps     635.6mV    199.9mV    645.3mV
987ps     714.7mV    471.3mV    691.1mV
1.326ns   769.1mV    627.7mV    731.5mV
2.587ns   803.9mV    695.6mV    768.4mV
10ns      816.4mV    710.7mV    781.2mV
[Rising Waveform]
R_fixture = 50.000
V_fixture = 0.675
V_fixture_min = 0.642
V_fixture_max = 0.710
|  time   V(typ)   V(min)   V(max)
0s        230.8mV    231.8mV    255.2mV
346ps     231mV      231.8mV    255.5mV
457ps     234.2mV    231.9mV    728.1mV
487ps     286.5mV    231.9mV    806.4mV
597ps     727.9mV    230.1mV    961.1mV
677ps     892.7mV    240.2mV    1.015V
877ps     1.028V     739mV      1.079V
1.065ns   1.066V     914mV      1.103V
2.298ns   1.107V     1.02V      1.14V
10ns      1.118V     1.033V     1.151V
[Falling Waveform]
R_fixture = 50.000
V_fixture = 0.675
V_fixture_min = 0.642
V_fixture_max = 0.710
|  time   V(typ)   V(min)   V(max)
0s        1.118V     1.033V     1.151V
356ps     1.118V     1.033V     1.148V
467ps     1.111V     1.033V     665.9mV
507ps     992.8mV    1.033V     562.3mV
587ps     621mV      1.035V     446.8mV
671ps     436.6mV    1.029V     385.4mV
860ps     316.3mV    480.3mV    325.2mV
1.033ns   282.1mV    333mV      302.8mV
1.997ns   245.4mV    246.1mV    269.1mV
10ns      230.8mV    231.8mV    255.2mV
[Falling Waveform]
R_fixture = 50.000
V_fixture = 0.000
V_fixture_min = 0.000
V_fixture_max = 0.000
|  time   V(typ)   V(min)   V(max)
0s        816.4mV    710.7mV    781.2mV
351ps     816.2mV    710.5mV    783.4mV
457ps     817.3mV    710.6mV    277.7mV
487ps     739.6mV    710.3mV    214.2mV
577ps     276.8mV    713.8mV    124.1mV
661ps     141.2mV    711.8mV    86.05mV
830ps     66.5mV     190.5mV    50.79mV
1.04ns    37.16mV    65.12mV    32.76mV
2.137ns   10.31mV    9.662mV    8.904mV
10ns      16.67uV    136.1uV    7.524uV
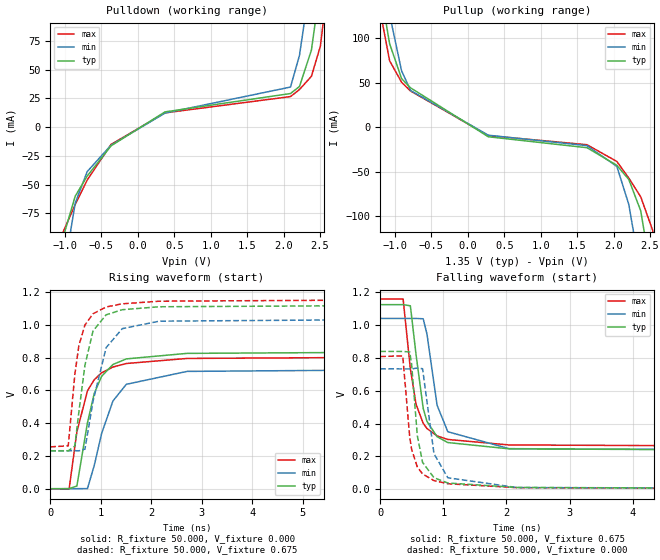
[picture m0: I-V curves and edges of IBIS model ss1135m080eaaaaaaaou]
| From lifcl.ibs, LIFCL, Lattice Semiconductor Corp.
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|Model ss1135m080eaaaaaaaou
[Model] ss1135m080eaaaaaaaou
Model_type Output
Polarity   Non-Inverting
Enable   Active-High
Vmeas =  0.675V
Cref =  30.000pF
Rref =  50.000
Vref =  0.675V
C_comp   5.000pF   4.000pF   5.500pF
[Temperature Range]   25.000   0.125k   -40.000
[Voltage Range]   1.350V   1.280V   1.420V
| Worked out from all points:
|   slope of the pulldown table from 0 to 0.203 V, typ, clamps not added: 25.7 ohm
|   slope of the pullup table from 0 to 0.203 V, typ, clamps not added: 24.7 ohm
|   rising waveform, R_fixture 50.000, V_fixture 0.000: 20-80 % time 372ps typ, 469ps min, 375ps max; typ from 0 V to 0.839 V
|   rising waveform, R_fixture 50.000, V_fixture 0.675: 20-80 % time 282ps typ, 359ps min, 247ps max; typ from 0.231 V to 1.12 V
|   falling waveform, R_fixture 50.000, V_fixture 0.675: 20-80 % time 206ps typ, 235ps min, 218ps max; typ from 1.12 V to 0.231 V
|   falling waveform, R_fixture 50.000, V_fixture 0.000: 20-80 % time 150ps typ, 172ps min, 158ps max; typ from 0.839 V to 0 V
[Pulldown]
|Voltage   I(typ)   I(min)   I(max)
-1.35V    -276.8mA   -315.1mA   -253.5mA
-1.145V   -153mA     -194.4mA   -131.5mA
-1.022V   -95.6mA    -129.7mA   -91mA
-858mV    -60.14mA   -66.23mA   -67.37mA
-694mV    -42.61mA   -38.74mA   -46.18mA
-366mV    -16.25mA   -15.67mA   -15.03mA
372mV     13.27mA    12.22mA    12.4mA
2.094V    29.28mA    34.92mA    26.62mA
2.217V    35.4mA     62.46mA    32.74mA
2.381V    67.11mA    133.1mA    44.3mA
2.504V    123.8mA    199.5mA    70.58mA
2.7V      239.7mA    314.4mA    174.6mA
[Pullup]
|Voltage   I(typ)   I(min)   I(max)
-1.35V    245mA      281.2mA    220.6mA
-1.195V   153.6mA    191.3mA    127.9mA
-1.072V   93.9mA     126.8mA    74.67mA
-908mV    54.56mA    63.37mA    50.53mA
-785mV    44.24mA    41.27mA    40.66mA
281mV     -10.8mA    -9.064mA   -9.517mA
1.634V    -23.12mA   -20.81mA   -19.75mA
2.044V    -42.95mA   -44.16mA   -38.63mA
2.208V    -58.91mA   -87mA      -57.27mA
2.372V    -94.3mA    -165.3mA   -78.5mA
2.536V    -174.9mA   -259.9mA   -116.3mA
2.7V      -275.5mA   -360.9mA   -205.2mA
[Ramp]
| variable   typ   min   max
dV/dt_r   0.500/0.378n   0.436/0.470n   0.480/0.381n
dV/dt_f   0.498/0.328n   0.459/0.353n   0.495/0.374n
R_load = 50.000
[Rising Waveform]
R_fixture = 50.000
V_fixture = 0.000
V_fixture_min = 0.000
V_fixture_max = 0.000
|  time   V(typ)   V(min)   V(max)
0s        18.55uV    138.8uV    7.384uV
373ps     721.7uV    161.4uV    -2.579mV
527ps     16.52mV    531.5uV    346.8mV
737ps     402.6mV    844.9uV    597.9mV
872ps     582.6mV    142.9mV    665.8mV
1.017ns   686.1mV    336.8mV    707.7mV
1.242ns   758.7mV    535.8mV    743.1mV
1.507ns   792.7mV    637.6mV    764.6mV
2.71ns    826.4mV    716.4mV    795.5mV
10ns      839.2mV    732.8mV    808.1mV
[Rising Waveform]
R_fixture = 50.000
V_fixture = 0.675
V_fixture_min = 0.642
V_fixture_max = 0.710
|  time   V(typ)   V(min)   V(max)
0s        231.1mV    232.1mV    255.6mV
356ps     231.4mV    232.1mV    262mV
487ps     261mV      232.3mV    698.6mV
567ps     469.4mV    231.5mV    874mV
687ps     754.4mV    241.6mV    999.7mV
847ps     963.2mV    534mV      1.068V
1.107ns   1.062V     861.4mV    1.11V
1.427ns   1.093V     977.4mV    1.129V
2.157ns   1.111V     1.023V     1.145V
10ns      1.124V     1.04V      1.158V
[Falling Waveform]
R_fixture = 50.000
V_fixture = 0.675
V_fixture_min = 0.642
V_fixture_max = 0.710
|  time   V(typ)   V(min)   V(max)
0s        1.124V     1.04V      1.158V
362ps     1.124V     1.04V      1.158V
477ps     1.117V     1.04V      732.4mV
567ps     819.5mV    1.04V      517.3mV
680ps     492.9mV    1.038V     401mV
740ps     412.8mV    944.9mV    369.3mV
900ps     319.7mV    511.9mV    324.4mV
1.07ns    284mV      349.9mV    302.8mV
2.04ns    245.7mV    246.8mV    269.4mV
10ns      231.1mV    232.1mV    255.6mV
[Falling Waveform]
R_fixture = 50.000
V_fixture = 0.000
V_fixture_min = 0.000
V_fixture_max = 0.000
|  time   V(typ)   V(min)   V(max)
0s        839.2mV    732.8mV    808.1mV
356ps     839mV      732.6mV    812.1mV
467ps     835.5mV    732.6mV    316.1mV
497ps     759.4mV    732.3mV    241.7mV
587ps     326.4mV    738.1mV    135.3mV
670ps     163.5mV    733.9mV    92.68mV
851ps     69.67mV    216mV      52.12mV
1.071ns   37.61mV    69.21mV    33.07mV
2.167ns   10.51mV    9.948mV    9.087mV
10ns      18.55uV    138.8uV    7.384uV
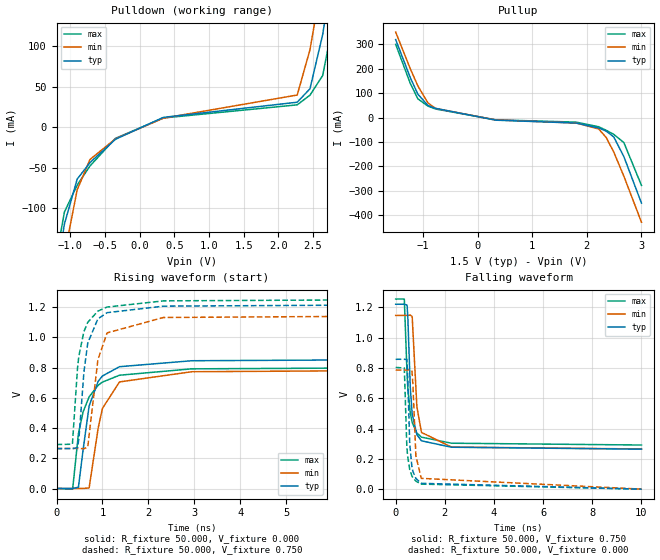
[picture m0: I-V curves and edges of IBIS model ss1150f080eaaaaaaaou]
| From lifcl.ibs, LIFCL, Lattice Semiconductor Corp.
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|Model ss1150f080eaaaaaaaou
[Model] ss1150f080eaaaaaaaou
Model_type Output
Polarity   Non-Inverting
Enable   Active-High
Vmeas =  0.750V
Cref =  30.000pF
Rref =  50.000
Vref =  0.750V
C_comp   5.000pF   4.000pF   5.500pF
[Temperature Range]   25.000   0.125k   -40.000
[Voltage Range]   1.500V   1.430V   1.580V
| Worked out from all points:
|   slope of the pulldown table from 0 to 0.225 V, typ, clamps not added: 26.6 ohm
|   slope of the pullup table from 0 to 0.225 V, typ, clamps not added: 28.9 ohm
|   rising waveform, R_fixture 50.000, V_fixture 0.000: 20-80 % time 310ps typ, 333ps min, 377ps max; typ from 0 V to 0.857 V
|   rising waveform, R_fixture 50.000, V_fixture 0.750: 20-80 % time 217ps typ, 245ps min, 234ps max; typ from 0.264 V to 1.22 V
|   falling waveform, R_fixture 50.000, V_fixture 0.750: 20-80 % time 189ps typ, 202ps min, 215ps max; typ from 1.22 V to 0.264 V
|   falling waveform, R_fixture 50.000, V_fixture 0.000: 20-80 % time 135ps typ, 149ps min, 147ps max; typ from 0.857 V to 0 V
[Pulldown]
|Voltage   I(typ)   I(min)   I(max)
-1.5V     -365.1mA   -396.5mA   -347.3mA
-1.224V   -193.4mA   -233.1mA   -170.4mA
-1.086V   -119.7mA   -157.8mA   -104.9mA
-902mV    -64.26mA   -77.49mA   -71.71mA
-718mV    -43.88mA   -40.05mA   -48.08mA
-350mV    -14.99mA   -14.41mA   -13.83mA
340mV     12.05mA    11.06mA    11.31mA
2.272V    30.8mA     39.7mA     27.56mA
2.456V    47.4mA     95.6mA     39.49mA
2.64V     114.5mA    187mA      63.9mA
2.778V    191.3mA    264.5mA    124.5mA
3V        327.9mA    395.2mA    261.3mA
[Pullup]
|Voltage   I(typ)   I(min)   I(max)
-1.5V     318.1mA    348.8mA    298.7mA
-1.232V   162.4mA    198.5mA    138.9mA
-1.094V   95.3mA     128.9mA    76.32mA
-910mV    49.26mA    59.99mA    46.7mA
-772mV    37.47mA    37.11mA    34.86mA
332mV     -10.85mA   -9.881mA   -9.436mA
1.804V    -22.61mA   -22.37mA   -18.83mA
2.218V    -42.92mA   -46.96mA   -37.78mA
2.356V    -55.64mA   -82.2mA    -52.49mA
2.494V    -79.8mA    -141.7mA   -68.96mA
2.678V    -159.8mA   -239.7mA   -102.5mA
3V        -349.5mA   -427.4mA   -277.2mA
[Ramp]
| variable   typ   min   max
dV/dt_r   0.514/0.312n   0.471/0.337n   0.482/0.377n
dV/dt_f   0.529/0.334n   0.490/0.332n   0.517/0.414n
R_load = 50.000
[Rising Waveform]
R_fixture = 50.000
V_fixture = 0.000
V_fixture_min = 0.000
V_fixture_max = 0.000
|  time   V(typ)   V(min)   V(max)
0s        67.51uV    273.4uV    36.32uV
351ps     416uV      298.5uV    -4.402mV
477ps     8.113mV    371.3uV    362.2mV
578ps     254.8mV    459.8uV    506.9mV
710ps     546.3mV    3.658mV    607mV
907ps     709.3mV    400.3mV    683.4mV
1ns       744.8mV    530.3mV    704.6mV
1.371ns   806.3mV    705.4mV    749.9mV
2.944ns   845.7mV    773mV      792mV
10ns      856.8mV    785.7mV    803.1mV
[Rising Waveform]
R_fixture = 50.000
V_fixture = 0.750
V_fixture_min = 0.713
V_fixture_max = 0.789
|  time   V(typ)   V(min)   V(max)
0s        263.8mV    265.1mV    291.2mV
346ps     263.9mV    265.1mV    293mV
457ps     270.5mV    265.2mV    798mV
487ps     327.7mV    265.2mV    877.8mV
597ps     772.3mV    263.3mV    1.039V
680ps     963.2mV    274.8mV    1.1V
901ps     1.123V     852.2mV    1.174V
1.1ns     1.164V     1.03V      1.201V
2.328ns   1.207V     1.132V     1.242V
10ns      1.22V      1.146V     1.254V
[Falling Waveform]
R_fixture = 50.000
V_fixture = 0.750
V_fixture_min = 0.713
V_fixture_max = 0.789
|  time   V(typ)   V(min)   V(max)
0s        1.22V      1.146V     1.254V
351ps     1.22V      1.146V     1.254V
463ps     1.214V     1.146V     757.2mV
494ps     1.133V     1.146V     667.5mV
594ps     669.4mV    1.148V     502.8mV
671ps     497.7mV    1.139V     440.1mV
861ps     359.9mV    545mV      370.3mV
1.049ns   319mV      374.4mV    343.1mV
2.269ns   276.7mV    277.8mV    303.2mV
10ns      263.8mV    265.1mV    291.2mV
[Falling Waveform]
R_fixture = 50.000
V_fixture = 0.000
V_fixture_min = 0.000
V_fixture_max = 0.000
|  time   V(typ)   V(min)   V(max)
0s        856.8mV    785.7mV    803.1mV
351ps     856.6mV    785.5mV    799.5mV
451ps     855.6mV    785.6mV    292.6mV
481ps     784.1mV    785.4mV    224.8mV
571ps     299.1mV    787.7mV    129.3mV
661ps     145.6mV    780.2mV    87.25mV
701ps     117.4mV    692mV      75.5mV
821ps     71.09mV    219.7mV    52.89mV
1.041ns   38.53mV    71.24mV    33.41mV
10ns      67.51uV    273.4uV    36.32uV
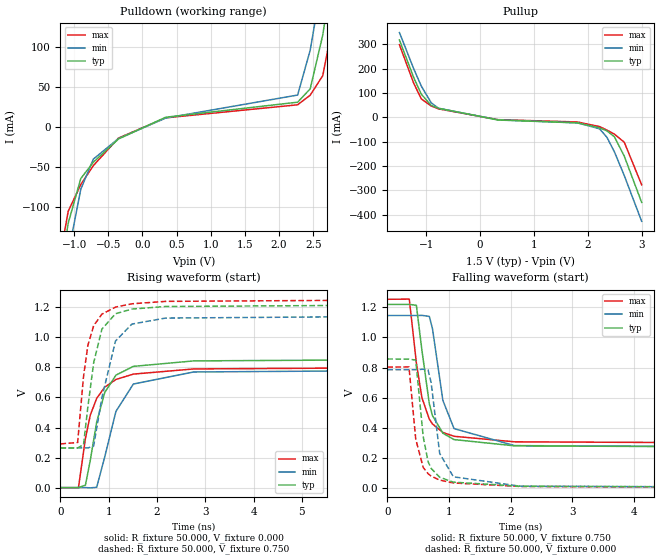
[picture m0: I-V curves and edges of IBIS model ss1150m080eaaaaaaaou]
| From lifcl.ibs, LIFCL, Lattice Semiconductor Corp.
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|Model ss1150m080eaaaaaaaou
[Model] ss1150m080eaaaaaaaou
Model_type Output
Polarity   Non-Inverting
Enable   Active-High
Vmeas =  0.750V
Cref =  30.000pF
Rref =  50.000
Vref =  0.750V
C_comp   5.000pF   4.000pF   5.500pF
[Temperature Range]   25.000   0.125k   -40.000
[Voltage Range]   1.500V   1.430V   1.580V
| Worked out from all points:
|   slope of the pulldown table from 0 to 0.225 V, typ, clamps not added: 26.6 ohm
|   slope of the pullup table from 0 to 0.225 V, typ, clamps not added: 28.9 ohm
|   rising waveform, R_fixture 50.000, V_fixture 0.000: 20-80 % time 383ps typ, 445ps min, 399ps max; typ from 0 V to 0.857 V
|   rising waveform, R_fixture 50.000, V_fixture 0.750: 20-80 % time 290ps typ, 355ps min, 260ps max; typ from 0.264 V to 1.22 V
|   falling waveform, R_fixture 50.000, V_fixture 0.750: 20-80 % time 220ps typ, 248ps min, 235ps max; typ from 1.22 V to 0.264 V
|   falling waveform, R_fixture 50.000, V_fixture 0.000: 20-80 % time 153ps typ, 173ps min, 159ps max; typ from 0.857 V to 0 V
[Pulldown]
|Voltage   I(typ)   I(min)   I(max)
-1.5V     -365.1mA   -396.5mA   -347.3mA
-1.224V   -193.4mA   -233.1mA   -170.4mA
-1.086V   -119.7mA   -157.8mA   -104.9mA
-902mV    -64.26mA   -77.49mA   -71.71mA
-718mV    -43.88mA   -40.05mA   -48.08mA
-350mV    -14.99mA   -14.41mA   -13.83mA
340mV     12.05mA    11.06mA    11.31mA
2.272V    30.8mA     39.7mA     27.56mA
2.456V    47.4mA     95.6mA     39.49mA
2.64V     114.5mA    187mA      63.9mA
2.778V    191.3mA    264.5mA    124.5mA
3V        327.9mA    395.2mA    261.3mA
[Pullup]
|Voltage   I(typ)   I(min)   I(max)
-1.5V     318.1mA    348.8mA    298.7mA
-1.232V   162.4mA    198.5mA    138.9mA
-1.094V   95.3mA     128.9mA    76.32mA
-910mV    49.26mA    59.99mA    46.7mA
-772mV    37.47mA    37.11mA    34.86mA
332mV     -10.85mA   -9.881mA   -9.436mA
1.804V    -22.61mA   -22.37mA   -18.83mA
2.218V    -42.92mA   -46.96mA   -37.78mA
2.356V    -55.64mA   -82.2mA    -52.49mA
2.494V    -79.8mA    -141.7mA   -68.96mA
2.678V    -159.8mA   -239.7mA   -102.5mA
3V        -349.5mA   -427.4mA   -277.2mA
[Ramp]
| variable   typ   min   max
dV/dt_r   0.514/0.391n   0.471/0.443n   0.482/0.398n
dV/dt_f   0.529/0.375n   0.490/0.402n   0.517/0.438n
R_load = 50.000
[Rising Waveform]
R_fixture = 50.000
V_fixture = 0.000
V_fixture_min = 0.000
V_fixture_max = 0.000
|  time   V(typ)   V(min)   V(max)
0s        67.51uV    273.4uV    36.32uV
373ps     667.6uV    296.1uV    -268.3uV
518ps     16.51mV    563.1uV    328.6mV
618ps     182mV      -1.227mV   482.2mV
751ps     436.5mV    2.402mV    594.5mV
918ps     633.6mV    205.5mV    668.5mV
1.15ns    748.6mV    507.8mV    719.7mV
1.511ns   806.8mV    689.4mV    755.4mV
2.76ns    843.1mV    769.4mV    789.7mV
10ns      856.8mV    785.7mV    803.1mV
[Rising Waveform]
R_fixture = 50.000
V_fixture = 0.750
V_fixture_min = 0.713
V_fixture_max = 0.789
|  time   V(typ)   V(min)   V(max)
0s        263.8mV    265.1mV    291.2mV
356ps     263.9mV    265.1mV    300.6mV
478ps     286.4mV    265.2mV    739.2mV
568ps     536.9mV    264.2mV    946.3mV
688ps     830mV      277.3mV    1.077V
858ps     1.054V     598.1mV    1.154V
1.141ns   1.157V     975.7mV    1.201V
1.481ns   1.188V     1.088V     1.223V
2.178ns   1.205V     1.128V     1.239V
10ns      1.22V      1.146V     1.254V
[Falling Waveform]
R_fixture = 50.000
V_fixture = 0.750
V_fixture_min = 0.713
V_fixture_max = 0.789
|  time   V(typ)   V(min)   V(max)
0s        1.22V      1.146V     1.254V
356ps     1.22V      1.146V     1.255V
471ps     1.214V     1.146V     830mV
561ps     915.3mV    1.147V     599.2mV
681ps     558.7mV    1.14V      456.5mV
732ps     480.6mV    1.059V     424.8mV
901ps     363.3mV    581.3mV    368.6mV
1.082ns   321mV      394mV      342.9mV
2.061ns   279.5mV    281.1mV    306.2mV
10ns      263.8mV    265.1mV    291.2mV
[Falling Waveform]
R_fixture = 50.000
V_fixture = 0.000
V_fixture_min = 0.000
V_fixture_max = 0.000
|  time   V(typ)   V(min)   V(max)
0s        856.8mV    785.7mV    803.1mV
351ps     856.5mV    785.5mV    804mV
461ps     849.2mV    785.6mV    323.1mV
581ps     343mV      789mV      136.4mV
661ps     174.2mV    784.4mV    94.09mV
711ps     129.1mV    697.9mV    77.8mV
849ps     70.66mV    229.2mV    51.49mV
1.071ns   37.99mV    73.57mV    32.64mV
2.16ns    10.82mV    10.74mV    9.102mV
10ns      67.51uV    273.4uV    36.32uV
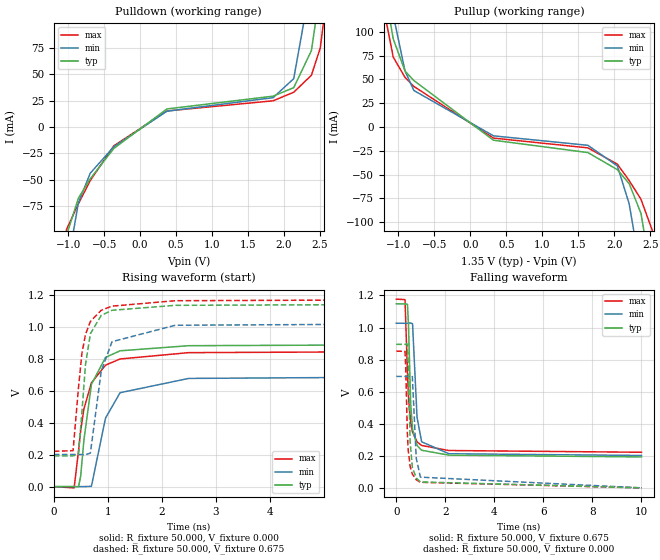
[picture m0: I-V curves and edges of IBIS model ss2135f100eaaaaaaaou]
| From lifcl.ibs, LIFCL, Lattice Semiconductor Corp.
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|Model ss2135f100eaaaaaaaou
[Model] ss2135f100eaaaaaaaou
Model_type Output
Polarity   Non-Inverting
Enable   Active-High
Vmeas =  0.675V
Cref =  30.000pF
Rref =  50.000
Vref =  0.675V
C_comp   5.000pF   4.000pF   5.500pF
[Temperature Range]   25.000   0.125k   -40.000
[Voltage Range]   1.350V   1.280V   1.420V
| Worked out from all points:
|   slope of the pulldown table from 0 to 0.203 V, typ, clamps not added: 20.1 ohm
|   slope of the pullup table from 0 to 0.203 V, typ, clamps not added: 21.4 ohm
|   rising waveform, R_fixture 50.000, V_fixture 0.000: 20-80 % time 235ps typ, 348ps min, 299ps max; typ from 0 V to 0.895 V
|   rising waveform, R_fixture 50.000, V_fixture 0.675: 20-80 % time 170ps typ, 248ps min, 200ps max; typ from 0.193 V to 1.15 V
|   falling waveform, R_fixture 50.000, V_fixture 0.675: 20-80 % time 141ps typ, 170ps min, 173ps max; typ from 1.15 V to 0.193 V
|   falling waveform, R_fixture 50.000, V_fixture 0.000: 20-80 % time 112ps typ, 136ps min, 130ps max; typ from 0.895 V to 0 V
[Pulldown]
|Voltage   I(typ)   I(min)   I(max)
-1.35V    -286.4mA   -327.1mA   -261.6mA
-1.145V   -160mA     -202.5mA   -136.9mA
-1.022V   -102.3mA   -136.2mA   -96.9mA
-858mV    -67.52mA   -71.71mA   -72.75mA
-694mV    -49.19mA   -43.9mA    -50.82mA
-366mV    -20.38mA   -18.73mA   -17.94mA
372mV     17.04mA    14.91mA    15.15mA
1.848V    29.15mA    27.73mA    24.75mA
2.135V    37.19mA    45.74mA    32.86mA
2.381V    72.32mA    139.1mA    48.95mA
2.504V    129.5mA    207.4mA    74.75mA
2.7V      248.1mA    326mA      180.5mA
[Pullup]
|Voltage   I(typ)   I(min)   I(max)
-1.35V    230.2mA    261mA      206.2mA
-1.195V   146.2mA    177.5mA    121mA
-1.072V   92.6mA     117.7mA    73.45mA
-908mV    58.73mA    58.81mA    52.08mA
-785mV    48.73mA    38.3mA     42.56mA
322mV     -13.96mA   -9.372mA   -11.74mA
1.634V    -26.94mA   -19.31mA   -22mA
2.044V    -44.9mA    -40.98mA   -39.13mA
2.208V    -59.57mA   -80.7mA    -56.34mA
2.372V    -90.7mA    -153.4mA   -75.99mA
2.536V    -164.1mA   -241.2mA   -110mA
2.7V      -257mA     -334.9mA   -191.4mA
[Ramp]
| variable   typ   min   max
dV/dt_r   0.537/0.235n   0.417/0.348n   0.512/0.306n
dV/dt_f   0.587/0.206n   0.505/0.244n   0.554/0.289n
R_load = 50.000
[Rising Waveform]
R_fixture = 50.000
V_fixture = 0.000
V_fixture_min = 0.000
V_fixture_max = 0.000
|  time   V(typ)   V(min)   V(max)
0s        17.43uV    124uV      7.288uV
376ps     629.6uV    138.8uV    -7.53mV
458ps     -566.9uV   172.1uV    226.6mV
497ps     66.57mV    305.9uV    352mV
557ps     291.2mV    634.7uV    487.8mV
696ps     642.3mV    2.22mV     651.3mV
957ps     811.1mV    430.3mV    762.6mV
1.227ns   852.7mV    589.6mV    801.4mV
2.497ns   884.7mV    679.3mV    841.1mV
10ns      895.1mV    695mV      852.8mV
[Rising Waveform]
R_fixture = 50.000
V_fixture = 0.675
V_fixture_min = 0.642
V_fixture_max = 0.710
|  time   V(typ)   V(min)   V(max)
0s        192.9mV    201.9mV    222mV
356ps     193.2mV    201.9mV    225.8mV
456ps     204mV      202mV      618.5mV
518ps     459.3mV    202mV      831.8mV
587ps     767.6mV    200.7mV    956.5mV
677ps     959.8mV    211mV      1.037V
877ps     1.075V     724.1mV    1.107V
1.077ns   1.107V     909.8mV    1.133V
2.247ns   1.138V     1.013V     1.167V
10ns      1.148V     1.027V     1.177V
[Falling Waveform]
R_fixture = 50.000
V_fixture = 0.675
V_fixture_min = 0.642
V_fixture_max = 0.710
|  time   V(typ)   V(min)   V(max)
0s        1.148V     1.027V     1.177V
356ps     1.147V     1.027V     1.174V
457ps     1.145V     1.027V     716.1mV
498ps     1.014V     1.027V     564.9mV
587ps     529.3mV    1.028V     406.9mV
664ps     365mV      1.023V     346.7mV
847ps     264.4mV    439.7mV    287.2mV
1.034ns   234.5mV    287.2mV    264.5mV
2.144ns   204mV      212.8mV    232.9mV
10ns      192.9mV    201.9mV    222mV
[Falling Waveform]
R_fixture = 50.000
V_fixture = 0.000
V_fixture_min = 0.000
V_fixture_max = 0.000
|  time   V(typ)   V(min)   V(max)
0s        895.1mV    695mV      852.8mV
356ps     895mV      694.8mV    851.1mV
388ps     896.9mV    694.9mV    736.2mV
451ps     896.7mV    694.9mV    347.5mV
487ps     779.3mV    694.7mV    234.8mV
567ps     283.5mV    697.2mV    133.1mV
654ps     129.2mV    698.7mV    87.29mV
814ps     61.21mV    185.1mV    50.89mV
984ps     36.97mV    66.78mV    34.58mV
10ns      17.43uV    124uV      7.288uV
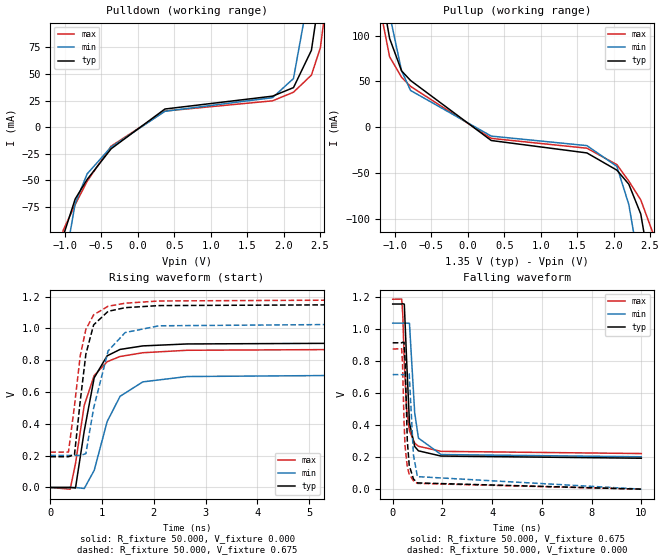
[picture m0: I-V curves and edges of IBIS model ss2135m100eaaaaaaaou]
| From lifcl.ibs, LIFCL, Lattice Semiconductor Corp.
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|Model ss2135m100eaaaaaaaou
[Model] ss2135m100eaaaaaaaou
Model_type Output
Polarity   Non-Inverting
Enable   Active-High
Vmeas =  0.675V
Cref =  30.000pF
Rref =  50.000
Vref =  0.675V
C_comp   5.000pF   4.000pF   5.500pF
[Temperature Range]   25.000   0.125k   -40.000
[Voltage Range]   1.350V   1.280V   1.420V
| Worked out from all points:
|   slope of the pulldown table from 0 to 0.203 V, typ, clamps not added: 20.1 ohm
|   slope of the pullup table from 0 to 0.203 V, typ, clamps not added: 20.5 ohm
|   rising waveform, R_fixture 50.000, V_fixture 0.000: 20-80 % time 305ps typ, 469ps min, 344ps max; typ from 0 V to 0.912 V
|   rising waveform, R_fixture 50.000, V_fixture 0.675: 20-80 % time 238ps typ, 360ps min, 252ps max; typ from 0.193 V to 1.15 V
|   falling waveform, R_fixture 50.000, V_fixture 0.675: 20-80 % time 163ps typ, 206ps min, 191ps max; typ from 1.15 V to 0.193 V
|   falling waveform, R_fixture 50.000, V_fixture 0.000: 20-80 % time 126ps typ, 153ps min, 140ps max; typ from 0.912 V to 0 V
[Pulldown]
|Voltage   I(typ)   I(min)   I(max)
-1.35V    -286.4mA   -327.1mA   -261.6mA
-1.145V   -160mA     -202.5mA   -136.9mA
-1.022V   -102.3mA   -136.2mA   -96.9mA
-858mV    -67.52mA   -71.71mA   -72.75mA
-694mV    -49.19mA   -43.9mA    -50.82mA
-366mV    -20.38mA   -18.73mA   -17.94mA
372mV     17.04mA    14.91mA    15.15mA
1.848V    29.15mA    27.73mA    24.75mA
2.135V    37.19mA    45.74mA    32.86mA
2.381V    72.32mA    139.1mA    48.95mA
2.504V    129.5mA    207.4mA    74.75mA
2.7V      248.1mA    326mA      180.5mA
[Pullup]
|Voltage   I(typ)   I(min)   I(max)
-1.35V    240.6mA    272.8mA    215.6mA
-1.195V   152.8mA    185.5mA    126.5mA
-1.072V   96.8mA     123mA      76.78mA
-908mV    61.39mA    61.47mA    54.44mA
-785mV    50.93mA    40.04mA    44.48mA
322mV     -14.59mA   -9.796mA   -12.27mA
1.634V    -28.16mA   -20.19mA   -23mA
2.044V    -46.93mA   -42.83mA   -40.9mA
2.208V    -62.26mA   -84.4mA    -58.89mA
2.372V    -94.8mA    -160.3mA   -79.43mA
2.536V    -171.5mA   -252.2mA   -114.9mA
2.7V      -268.6mA   -350.1mA   -200mA
[Ramp]
| variable   typ   min   max
dV/dt_r   0.547/0.305n   0.428/0.481n   0.524/0.348n
dV/dt_f   0.587/0.239n   0.505/0.297n   0.554/0.316n
R_load = 50.000
[Rising Waveform]
R_fixture = 50.000
V_fixture = 0.000
V_fixture_min = 0.000
V_fixture_max = 0.000
|  time   V(typ)   V(min)   V(max)
0s        17.43uV    124uV      7.288uV
384ps     520.8uV    132.3uV    -10.59mV
487ps     -3.096mV   285.5uV    150.6mV
656ps     355.7mV    -6.347mV   516.6mV
848ps     689.6mV    107.5mV    703.6mV
1.098ns   827.2mV    414.1mV    790.2mV
1.347ns   867.5mV    572.6mV    823.1mV
1.787ns   889.7mV    663.7mV    846.7mV
2.64ns    901.9mV    697.2mV    862.2mV
10ns      912.3mV    714.2mV    873.7mV
[Rising Waveform]
R_fixture = 50.000
V_fixture = 0.675
V_fixture_min = 0.642
V_fixture_max = 0.710
|  time   V(typ)   V(min)   V(max)
0s        192.9mV    201.9mV    222mV
351ps     193.3mV    201.9mV    222.5mV
467ps     205.5mV    202.1mV    512mV
578ps     541.1mV    200.9mV    826.9mV
687ps     837.8mV    212.7mV    993.6mV
837ps     1.022V     498.2mV    1.085V
1.117ns   1.107V     858.5mV    1.139V
1.447ns   1.13V      973.8mV    1.158V
2.099ns   1.143V     1.016V     1.172V
10ns      1.154V     1.035V     1.184V
[Falling Waveform]
R_fixture = 50.000
V_fixture = 0.675
V_fixture_min = 0.642
V_fixture_max = 0.710
|  time   V(typ)   V(min)   V(max)
0s        1.154V     1.035V     1.184V
362ps     1.154V     1.035V     1.185V
406ps     1.156V     1.035V     1.084V
467ps     1.153V     1.035V     788.4mV
559ps     805.6mV    1.035V     502.4mV
674ps     412.6mV    1.034V     363.6mV
884ps     266.2mV    476.3mV    287mV
1.034ns   239mV      318.5mV    267.5mV
1.944ns   206.4mV    215.9mV    235.7mV
10ns      192.9mV    201.9mV    222mV
[Falling Waveform]
R_fixture = 50.000
V_fixture = 0.000
V_fixture_min = 0.000
V_fixture_max = 0.000
|  time   V(typ)   V(min)   V(max)
0s        912.3mV    714.2mV    873.7mV
362ps     912.3mV    713.9mV    875.2mV
396ps     915.5mV    714mV      775.6mV
457ps     915.4mV    714mV      414.7mV
497ps     804.6mV    713.6mV    268.4mV
587ps     302.3mV    719.3mV    138.2mV
664ps     148.6mV    718.7mV    93.87mV
834ps     63.73mV    212.8mV    52.11mV
994ps     38.96mV    78.21mV    36.04mV
10ns      17.43uV    124uV      7.288uV
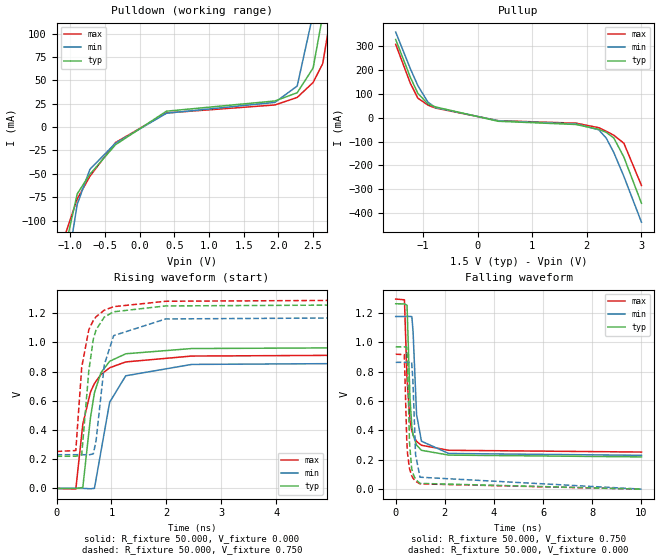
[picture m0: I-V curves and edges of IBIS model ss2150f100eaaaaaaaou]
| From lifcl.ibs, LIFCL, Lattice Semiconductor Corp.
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|Model ss2150f100eaaaaaaaou
[Model] ss2150f100eaaaaaaaou
Model_type Output
Polarity   Non-Inverting
Enable   Active-High
Vmeas =  0.750V
Cref =  30.000pF
Rref =  50.000
Vref =  0.750V
C_comp   5.000pF   4.000pF   5.500pF
[Temperature Range]   25.000   0.125k   -40.000
[Voltage Range]   1.500V   1.430V   1.580V
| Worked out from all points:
|   slope of the pulldown table from 0 to 0.225 V, typ, clamps not added: 20.8 ohm
|   slope of the pullup table from 0 to 0.225 V, typ, clamps not added: 22.9 ohm
|   rising waveform, R_fixture 50.000, V_fixture 0.000: 20-80 % time 248ps typ, 294ps min, 311ps max; typ from 0 V to 0.97 V
|   rising waveform, R_fixture 50.000, V_fixture 0.750: 20-80 % time 181ps typ, 219ps min, 199ps max; typ from 0.22 V to 1.26 V
|   falling waveform, R_fixture 50.000, V_fixture 0.750: 20-80 % time 146ps typ, 176ps min, 187ps max; typ from 1.26 V to 0.22 V
|   falling waveform, R_fixture 50.000, V_fixture 0.000: 20-80 % time 111ps typ, 134ps min, 132ps max; typ from 0.97 V to 0 V
[Pulldown]
|Voltage   I(typ)   I(min)   I(max)
-1.5V     -377mA     -410.6mA   -356.7mA
-1.132V   -149mA     -189.6mA   -127.7mA
-902mV    -71.47mA   -82.81mA   -76.94mA
-718mV    -50.41mA   -45.1mA    -52.59mA
-350mV    -18.85mA   -17.24mA   -16.52mA
386mV     17.08mA    14.89mA    15.19mA
1.95V     28.02mA    26.48mA    23.75mA
2.272V    36.84mA    44.03mA    31.81mA
2.502V    63.37mA    121.7mA    47.87mA
2.64V     119.9mA    194.2mA    68.02mA
2.778V    198.3mA    274.2mA    128.9mA
3V        338.5mA    409mA      268.7mA
[Pullup]
|Voltage   I(typ)   I(min)   I(max)
-1.5V     326.9mA    357.8mA    306.3mA
-1.232V   168.7mA    204.6mA    143.8mA
-1.094V   101.5mA    133.8mA    81.4mA
-910mV    57.19mA    64.68mA    52.41mA
-772mV    44.78mA    41.83mA    40.01mA
378mV     -15.24mA   -12.99mA   -12.83mA
1.804V    -28.72mA   -26.31mA   -23.22mA
2.218V    -49mA      -50.86mA   -42.12mA
2.356V    -61.86mA   -85.9mA    -57.07mA
2.494V    -85.3mA    -146.1mA   -73.85mA
2.678V    -165mA     -245.8mA   -107.1mA
3V        -358.2mA   -437.4mA   -283.8mA
[Ramp]
| variable   typ   min   max
dV/dt_r   0.582/0.251n   0.519/0.299n   0.552/0.317n
dV/dt_f   0.605/0.235n   0.547/0.273n   0.591/0.344n
R_load = 50.000
[Rising Waveform]
R_fixture = 50.000
V_fixture = 0.000
V_fixture_min = 0.000
V_fixture_max = 0.000
|  time   V(typ)   V(min)   V(max)
0s        68.2uV     255.9uV    36.73uV
351ps     528.8uV    273.1uV    -5.008mV
478ps     6.14mV     370.8uV    438.8mV
618ps     485.2mV    -2.267mV   659.6mV
690ps     654.5mV    458.3uV    718.3mV
808ps     792.2mV    252.1mV    779.6mV
967ps     870.4mV    590.2mV    825.9mV
1.26ns    921.6mV    771mV      865.8mV
2.46ns    957.4mV    848.7mV    906mV
10ns      970.5mV    864.6mV    920.2mV
[Rising Waveform]
R_fixture = 50.000
V_fixture = 0.750
V_fixture_min = 0.713
V_fixture_max = 0.789
|  time   V(typ)   V(min)   V(max)
0s        220mV      230.8mV    253.1mV
351ps     220.3mV    230.8mV    259.4mV
458ps     229.4mV    231mV      828.7mV
588ps     806mV      229.3mV    1.087V
670ps     1.022V     236.9mV    1.15V
720ps     1.086V     328.7mV    1.175V
870ps     1.173V     847.3mV    1.22V
1.04ns    1.209V     1.046V     1.244V
1.988ns   1.249V     1.16V      1.281V
10ns      1.264V     1.177V     1.296V
[Falling Waveform]
R_fixture = 50.000
V_fixture = 0.750
V_fixture_min = 0.713
V_fixture_max = 0.789
|  time   V(typ)   V(min)   V(max)
0s        1.264V     1.177V     1.296V
356ps     1.263V     1.177V     1.291V
461ps     1.254V     1.177V     752.9mV
581ps     621.5mV    1.178V     468.3mV
658ps     424.4mV    1.176V     397.5mV
708ps     369.8mV    1.071V     369.6mV
849ps     300mV      509.1mV    325.9mV
1.049ns   265mV      327mV      299.3mV
2.158ns   232.3mV    243.3mV    265.1mV
10ns      220mV      230.8mV    253.1mV
[Falling Waveform]
R_fixture = 50.000
V_fixture = 0.000
V_fixture_min = 0.000
V_fixture_max = 0.000
|  time   V(typ)   V(min)   V(max)
0s        970.5mV    864.6mV    920.2mV
351ps     970.3mV    864.4mV    917.1mV
451ps     967.8mV    864.5mV    329.3mV
481ps     874.5mV    864.3mV    244.3mV
561ps     320.8mV    866mV      140.5mV
649ps     142.1mV    864.6mV    92.04mV
698ps     107.7mV    749.6mV    76.2mV
809ps     66.86mV    236.2mV    54mV
988ps     39.37mV    81.56mV    36.26mV
10ns      68.2uV     255.9uV    36.73uV
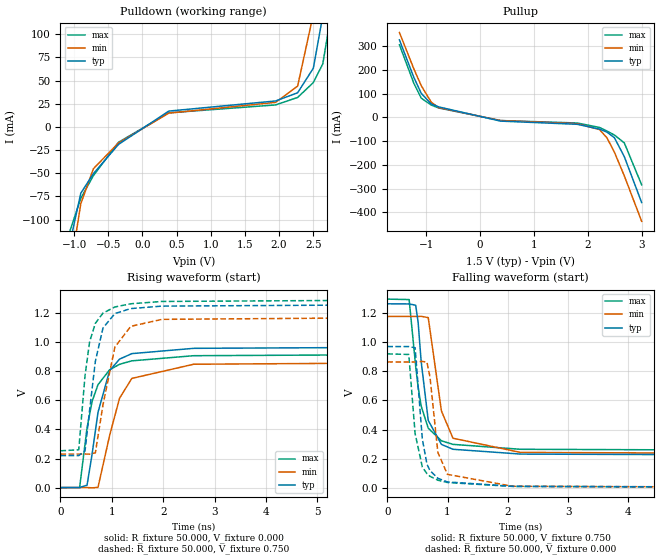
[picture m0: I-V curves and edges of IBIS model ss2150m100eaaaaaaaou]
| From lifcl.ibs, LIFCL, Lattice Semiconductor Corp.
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|Model ss2150m100eaaaaaaaou
[Model] ss2150m100eaaaaaaaou
Model_type Output
Polarity   Non-Inverting
Enable   Active-High
Vmeas =  0.750V
Cref =  30.000pF
Rref =  50.000
Vref =  0.750V
C_comp   5.000pF   4.000pF   5.500pF
[Temperature Range]   25.000   0.125k   -40.000
[Voltage Range]   1.500V   1.430V   1.580V
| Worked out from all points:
|   slope of the pulldown table from 0 to 0.225 V, typ, clamps not added: 20.8 ohm
|   slope of the pullup table from 0 to 0.225 V, typ, clamps not added: 22.9 ohm
|   rising waveform, R_fixture 50.000, V_fixture 0.000: 20-80 % time 316ps typ, 400ps min, 332ps max; typ from 0 V to 0.97 V
|   rising waveform, R_fixture 50.000, V_fixture 0.750: 20-80 % time 250ps typ, 316ps min, 223ps max; typ from 0.22 V to 1.26 V
|   falling waveform, R_fixture 50.000, V_fixture 0.750: 20-80 % time 173ps typ, 218ps min, 209ps max; typ from 1.26 V to 0.22 V
|   falling waveform, R_fixture 50.000, V_fixture 0.000: 20-80 % time 126ps typ, 156ps min, 146ps max; typ from 0.97 V to 0 V
[Pulldown]
|Voltage   I(typ)   I(min)   I(max)
-1.5V     -377mA     -410.6mA   -356.7mA
-1.132V   -149mA     -189.6mA   -127.7mA
-902mV    -71.47mA   -82.81mA   -76.94mA
-718mV    -50.41mA   -45.1mA    -52.59mA
-350mV    -18.85mA   -17.24mA   -16.52mA
386mV     17.08mA    14.89mA    15.19mA
1.95V     28.02mA    26.48mA    23.75mA
2.272V    36.84mA    44.03mA    31.81mA
2.502V    63.37mA    121.7mA    47.87mA
2.64V     119.9mA    194.2mA    68.02mA
2.778V    198.3mA    274.2mA    128.9mA
3V        338.5mA    409mA      268.7mA
[Pullup]
|Voltage   I(typ)   I(min)   I(max)
-1.5V     326.9mA    357.8mA    306.3mA
-1.232V   168.7mA    204.6mA    143.8mA
-1.094V   101.5mA    133.8mA    81.4mA
-910mV    57.19mA    64.68mA    52.41mA
-772mV    44.78mA    41.83mA    40.01mA
378mV     -15.24mA   -12.99mA   -12.83mA
1.804V    -28.72mA   -26.31mA   -23.22mA
2.218V    -49mA      -50.86mA   -42.12mA
2.356V    -61.86mA   -85.9mA    -57.07mA
2.494V    -85.3mA    -146.1mA   -73.85mA
2.678V    -165mA     -245.8mA   -107.1mA
3V        -358.2mA   -437.4mA   -283.8mA
[Ramp]
| variable   typ   min   max
dV/dt_r   0.582/0.321n   0.519/0.405n   0.552/0.337n
dV/dt_f   0.605/0.272n   0.547/0.336n   0.591/0.366n
R_load = 50.000
[Rising Waveform]
R_fixture = 50.000
V_fixture = 0.000
V_fixture_min = 0.000
V_fixture_max = 0.000
|  time   V(typ)   V(min)   V(max)
0s        68.2uV     255.9uV    36.73uV
373ps     802.3uV    271.8uV    409.2uV
518ps     16.53mV    598.4uV    411.2mV
617ps     231.6mV    -1.67mV    593.6mV
731ps     517.5mV    1.645mV    707.6mV
958ps     804.6mV    359.1mV    810.4mV
1.151ns   883.5mV    614.9mV    847.8mV
1.39ns    921.3mV    751mV      871.7mV
2.594ns   957.7mV    848.3mV    907mV
10ns      970.5mV    864.6mV    920.2mV
[Rising Waveform]
R_fixture = 50.000
V_fixture = 0.750
V_fixture_min = 0.713
V_fixture_max = 0.789
|  time   V(typ)   V(min)   V(max)
0s        220mV      230.8mV    253.1mV
356ps     220.3mV    230.8mV    260.1mV
478ps     251mV      231mV      768.3mV
568ps     533.2mV    230mV      1.003V
680ps     869mV      239.6mV    1.13V
828ps     1.097V     568.7mV    1.2V
1.06ns    1.197V     966.3mV    1.242V
1.369ns   1.231V     1.109V     1.264V
1.978ns   1.248V     1.157V     1.28V
10ns      1.264V     1.177V     1.296V
[Falling Waveform]
R_fixture = 50.000
V_fixture = 0.750
V_fixture_min = 0.713
V_fixture_max = 0.789
|  time   V(typ)   V(min)   V(max)
0s        1.264V     1.177V     1.296V
362ps     1.263V     1.177V     1.293V
471ps     1.254V     1.177V     833.7mV
511ps     1.138V     1.177V     692.9mV
562ps     866.8mV    1.178V     562.1mV
679ps     463.2mV    1.169V     409.7mV
898ps     298.5mV    528.1mV    323.2mV
1.089ns   265mV      340.9mV    298.7mV
2.211ns   232.1mV    243.4mV    264.9mV
10ns      220mV      230.8mV    253.1mV
[Falling Waveform]
R_fixture = 50.000
V_fixture = 0.000
V_fixture_min = 0.000
V_fixture_max = 0.000
|  time   V(typ)   V(min)   V(max)
0s        970.5mV    864.6mV    920.2mV
356ps     970.4mV    864.4mV    916mV
461ps     962.4mV    864.4mV    373.4mV
581ps     335.4mV    868.2mV    142.9mV
658ps     162.3mV    863.2mV    97.15mV
708ps     118.6mV    761.6mV    79.34mV
839ps     65.75mV    243mV      52.55mV
998ps     40.62mV    92.71mV    36.85mV
2.081ns   10.77mV    10.86mV    9.749mV
10ns      68.2uV     255.9uV    36.73uV
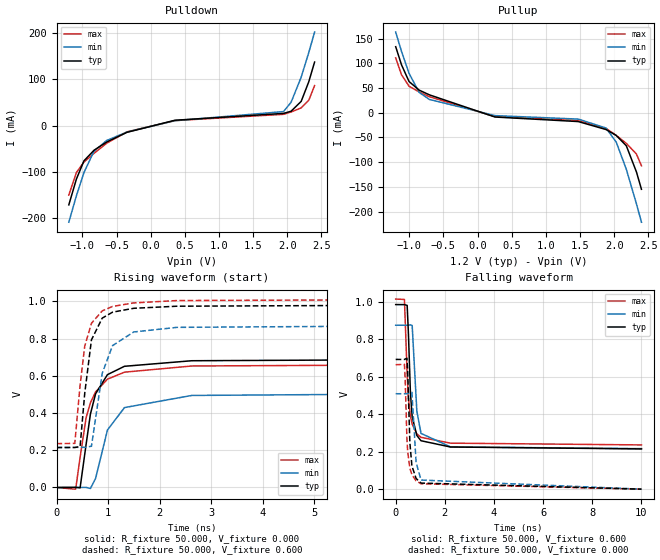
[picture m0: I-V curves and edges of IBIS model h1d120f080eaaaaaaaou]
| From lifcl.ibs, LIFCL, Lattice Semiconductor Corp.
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|Model h1d120f080eaaaaaaaou
[Model] h1d120f080eaaaaaaaou
Model_type Output
Polarity   Non-Inverting
Enable   Active-High
Vmeas =  0.600V
Cref =  20.000pF
Rref =  50.000
Vref =  0.600V
C_comp   5.000pF   4.000pF   5.500pF
[Temperature Range]   25.000   0.125k   -40.000
[Voltage Range]   1.200V   1.140V   1.260V
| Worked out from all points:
|   slope of the pulldown table from 0 to 0.18 V, typ, clamps not added: 27.4 ohm
|   slope of the pullup table from 0 to 0.18 V, typ, clamps not added: 27.4 ohm
|   rising waveform, R_fixture 50.000, V_fixture 0.000: 20-80 % time 298ps typ, 419ps min, 351ps max; typ from 0 V to 0.691 V
|   rising waveform, R_fixture 50.000, V_fixture 0.600: 20-80 % time 202ps typ, 289ps min, 226ps max; typ from 0.214 V to 0.984 V
|   falling waveform, R_fixture 50.000, V_fixture 0.600: 20-80 % time 171ps typ, 190ps min, 188ps max; typ from 0.984 V to 0.214 V
|   falling waveform, R_fixture 50.000, V_fixture 0.000: 20-80 % time 137ps typ, 156ps min, 148ps max; typ from 0.691 V to 0 V
[Pulldown]
|Voltage   I(typ)   I(min)   I(max)
-1.2V     -171mA     -208.4mA   -149.8mA
-1.089V   -115.3mA   -151.3mA   -101.1mA
-978mV    -75.7mA    -101mA     -78.43mA
-830mV    -52.86mA   -54.71mA   -59.48mA
-645mV    -35.14mA   -31.8mA    -37.67mA
-349mV    -14.23mA   -13.64mA   -13.17mA
354mV     11.86mA    10.87mA    11.16mA
1.945V    26.69mA    30.62mA    24.73mA
2.056V    31.4mA     50.81mA    29.73mA
2.204V    52.73mA    105.2mA    38.62mA
2.315V    95.1mA     158.3mA    55.1mA
2.4V      137.6mA    202.4mA    86.7mA
[Pullup]
|Voltage   I(typ)   I(min)   I(max)
-1.2V     133.6mA    163.2mA    111mA
-1.115V   97mA       124.2mA    76.9mA
-1.004V   63.07mA    79.6mA     53.56mA
-856mV    45.71mA    41.11mA    42.03mA
-708mV    36.25mA    26.94mA    32.46mA
254mV     -8.734mA   -5.845mA   -7.837mA
1.475V    -17.92mA   -12.92mA   -15.78mA
1.882V    -34.1mA    -31.1mA    -31.79mA
2.03V     -46mA      -59.47mA   -45.96mA
2.178V    -66.85mA   -114.4mA   -62mA
2.326V    -119.7mA   -184.2mA   -83.5mA
2.4V      -155mA     -221.6mA   -107.4mA
[Ramp]
| variable   typ   min   max
dV/dt_r   0.415/0.301n   0.305/0.423n   0.398/0.357n
dV/dt_f   0.437/0.249n   0.401/0.265n   0.438/0.295n
R_load = 50.000
[Rising Waveform]
R_fixture = 50.000
V_fixture = 0.000
V_fixture_min = 0.000
V_fixture_max = 0.000
|  time   V(typ)   V(min)   V(max)
0s        40.32uV    121.4uV    24.83uV
371ps     677.7uV    129uV      -9.045mV
457ps     -1.665mV   150.9uV    162.1mV
574ps     233.1mV    435uV      376.4mV
657ps     394.7mV    -5.363mV   455.2mV
757ps     503.8mV    48.63mV    514mV
987ps     606.7mV    308.9mV    582.3mV
1.317ns   651.6mV    429.6mV    620mV
2.62ns    681.4mV    494.8mV    653.1mV
10ns      691.4mV    508.6mV    663.3mV
[Rising Waveform]
R_fixture = 50.000
V_fixture = 0.600
V_fixture_min = 0.571
V_fixture_max = 0.631
|  time   V(typ)   V(min)   V(max)
0s        214.5mV    215.9mV    235.8mV
354ps     214.8mV    216mV      237mV
457ps     220.3mV    216mV      550.1mV
547ps     507.3mV    215.9mV    760.5mV
677ps     793.8mV    221.6mV    882.7mV
886ps     910.6mV    614mV      949.5mV
1.087ns   942.7mV    763mV      973.3mV
1.496ns   963.4mV    836.1mV    992.2mV
2.337ns   974.6mV    860.9mV    1.005V
10ns      983.6mV    873.8mV    1.013V
[Falling Waveform]
R_fixture = 50.000
V_fixture = 0.600
V_fixture_min = 0.571
V_fixture_max = 0.631
|  time   V(typ)   V(min)   V(max)
0s        983.6mV    873.8mV    1.013V
356ps     983.4mV    873.7mV    1.011V
467ps     979.3mV    873.7mV    609.8mV
520ps     822.7mV    873.6mV    480.5mV
598ps     517.3mV    875.9mV    390mV
671ps     386.5mV    872.3mV    346.1mV
860ps     286.1mV    416.6mV    295mV
1.03ns    258.1mV    297.2mV    276.2mV
2.23ns    224.7mV    225.3mV    245.2mV
10ns      214.5mV    215.9mV    235.8mV
[Falling Waveform]
R_fixture = 50.000
V_fixture = 0.000
V_fixture_min = 0.000
V_fixture_max = 0.000
|  time   V(typ)   V(min)   V(max)
0s        691.4mV    508.6mV    663.3mV
356ps     691.3mV    508.4mV    665mV
384ps     693.1mV    508.5mV    591.1mV
456ps     697.8mV    508.5mV    272.5mV
486ps     636.1mV    508.3mV    202.3mV
576ps     249mV      511.8mV    112.2mV
660ps     123.5mV    516.6mV    76.87mV
831ps     57.03mV    142mV      44.46mV
1.032ns   32.47mV    48.62mV    28.87mV
10ns      40.32uV    121.4uV    24.83uV
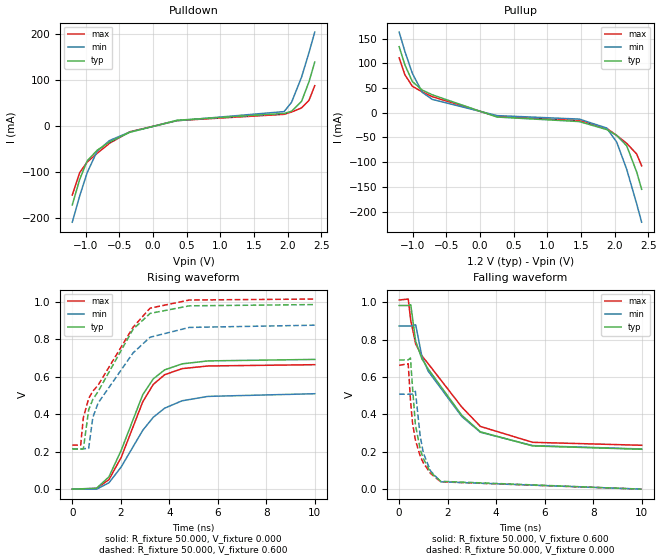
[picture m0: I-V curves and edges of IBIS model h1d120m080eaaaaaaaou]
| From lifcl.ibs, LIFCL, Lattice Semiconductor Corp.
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|Model h1d120m080eaaaaaaaou
[Model] h1d120m080eaaaaaaaou
Model_type Output
Polarity   Non-Inverting
Enable   Active-High
Vmeas =  0.600V
Cref =  20.000pF
Rref =  50.000
Vref =  0.600V
C_comp   5.000pF   4.000pF   5.500pF
[Temperature Range]   25.000   0.125k   -40.000
[Voltage Range]   1.200V   1.140V   1.260V
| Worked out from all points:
|   slope of the pulldown table from 0 to 0.18 V, typ, clamps not added: 27.3 ohm
|   slope of the pullup table from 0 to 0.18 V, typ, clamps not added: 27.4 ohm
|   rising waveform, R_fixture 50.000, V_fixture 0.000: 20-80 % time 1.33ns typ, 1.61ns min, 1.29ns max; typ from 0 V to 0.691 V
|   rising waveform, R_fixture 50.000, V_fixture 0.600: 20-80 % time 1.82ns typ, 1.81ns min, 2.02ns max; typ from 0.214 V to 0.984 V
|   falling waveform, R_fixture 50.000, V_fixture 0.600: 20-80 % time 2.14ns typ, 2.02ns min, 2.37ns max; typ from 0.984 V to 0.214 V
|   falling waveform, R_fixture 50.000, V_fixture 0.000: 20-80 % time 536ps typ, 501ps min, 590ps max; typ from 0.691 V to 0 V
[Pulldown]
|Voltage   I(typ)   I(min)   I(max)
-1.2V     -172mA     -209.5mA   -150.5mA
-1.089V   -116mA     -152mA     -101.6mA
-978mV    -76.15mA   -101.5mA   -78.8mA
-830mV    -53.18mA   -54.98mA   -59.76mA
-645mV    -35.35mA   -31.96mA   -37.85mA
-349mV    -14.32mA   -13.71mA   -13.23mA
354mV     11.93mA    10.92mA    11.21mA
1.945V    26.85mA    30.77mA    24.85mA
2.056V    31.59mA    51.06mA    29.87mA
2.204V    53.04mA    105.6mA    38.8mA
2.315V    95.7mA     159.2mA    55.36mA
2.4V      138.5mA    203.5mA    87mA
[Pullup]
|Voltage   I(typ)   I(min)   I(max)
-1.2V     133.6mA    163.2mA    111mA
-1.115V   97mA       124.2mA    76.9mA
-1.004V   63.07mA    79.6mA     53.56mA
-856mV    45.71mA    41.11mA    42.03mA
-708mV    36.25mA    26.94mA    32.46mA
254mV     -8.734mA   -5.845mA   -7.837mA
1.475V    -17.92mA   -12.92mA   -15.78mA
1.882V    -34.1mA    -31.1mA    -31.79mA
2.03V     -46mA      -59.47mA   -45.96mA
2.178V    -66.85mA   -114.4mA   -62mA
2.326V    -119.7mA   -184.2mA   -83.5mA
2.4V      -155mA     -221.6mA   -107.4mA
[Ramp]
| variable   typ   min   max
dV/dt_r   0.415/1.352n   0.305/1.676n   0.398/1.350n
dV/dt_f   0.438/2.309n   0.402/2.319n   0.439/2.482n
R_load = 50.000
[Rising Waveform]
R_fixture = 50.000
V_fixture = 0.000
V_fixture_min = 0.000
V_fixture_max = 0.000
|  time   V(typ)   V(min)   V(max)
0s        41.32uV    121.6uV    24.31uV
1.003ns   5.132mV    52.84uV    3.951mV
1.513ns   65.86mV    34.05mV    51.13mV
2.016ns   206.6mV    118.2mV    168.9mV
2.906ns   503.2mV    313.6mV    465.2mV
3.34ns    587.7mV    383mV      558.2mV
3.811ns   635.8mV    431.7mV    610mV
4.531ns   667.8mV    471.1mV    642.3mV
5.6ns     683.5mV    494.4mV    656.5mV
10ns      691.4mV    508.6mV    663.3mV
[Rising Waveform]
R_fixture = 50.000
V_fixture = 0.600
V_fixture_min = 0.571
V_fixture_max = 0.631
|  time   V(typ)   V(min)   V(max)
0s        213.6mV    215.2mV    235mV
346ps     214mV      215.2mV    234.3mV
457ps     214.4mV    215.3mV    381.3mV
676ps     422.8mV    217.6mV    483.7mV
847ps     477.9mV    381.9mV    521.9mV
1.066ns   520.5mV    459.1mV    554.1mV
2.507ns   852mV      726.1mV    862.9mV
3.209ns   936.6mV    809.6mV    964.5mV
4.83ns    977mV      861.9mV    1.008V
10ns      983.6mV    873.8mV    1.013V
[Falling Waveform]
R_fixture = 50.000
V_fixture = 0.600
V_fixture_min = 0.571
V_fixture_max = 0.631
|  time   V(typ)   V(min)   V(max)
0s        983.6mV    873.8mV    1.013V
374ps     983.5mV    873.6mV    1.018V
478ps     987.9mV    873.7mV    903.9mV
681ps     792mV      880.4mV    777.5mV
938ps     697.8mV    709.9mV    713.9mV
1.198ns   643.6mV    631.9mV    671.9mV
2.58ns    396mV      389.4mV    440.3mV
3.351ns   307mV      304.8mV    335.9mV
5.506ns   231.6mV    233.3mV    250.9mV
10ns      213.6mV    215.2mV    235mV
[Falling Waveform]
R_fixture = 50.000
V_fixture = 0.000
V_fixture_min = 0.000
V_fixture_max = 0.000
|  time   V(typ)   V(min)   V(max)
0s        691.4mV    508.6mV    663.3mV
374ps     692.4mV    508.4mV    671.5mV
466ps     702.2mV    508.4mV    477.2mV
550ps     547.3mV    509.8mV    356.2mV
670ps     345.9mV    523.8mV    263.1mV
870ps     212.5mV    281.5mV    176.1mV
1ns       163mV      193mV      140.4mV
1.294ns   90.52mV    97.78mV    84mV
1.714ns   42.19mV    39.62mV    39.37mV
10ns      41.32uV    121.6uV    24.31uV
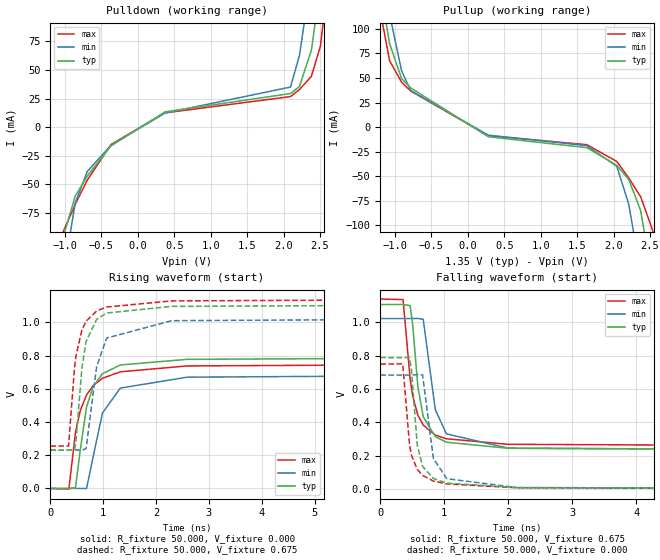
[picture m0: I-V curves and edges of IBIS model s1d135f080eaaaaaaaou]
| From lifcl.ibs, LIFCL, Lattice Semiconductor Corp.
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|Model s1d135f080eaaaaaaaou
[Model] s1d135f080eaaaaaaaou
Model_type Output
Polarity   Non-Inverting
Enable   Active-High
Vmeas =  0.675V
Cref =  30.000pF
Rref =  50.000
Vref =  0.675V
C_comp   5.000pF   4.000pF   5.500pF
[Temperature Range]   25.000   0.125k   -40.000
[Voltage Range]   1.350V   1.280V   1.420V
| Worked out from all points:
|   slope of the pulldown table from 0 to 0.203 V, typ, clamps not added: 25.7 ohm
|   slope of the pullup table from 0 to 0.203 V, typ, clamps not added: 27.3 ohm
|   rising waveform, R_fixture 50.000, V_fixture 0.000: 20-80 % time 296ps typ, 349ps min, 353ps max; typ from 0 V to 0.789 V
|   rising waveform, R_fixture 50.000, V_fixture 0.675: 20-80 % time 203ps typ, 247ps min, 220ps max; typ from 0.231 V to 1.11 V
|   falling waveform, R_fixture 50.000, V_fixture 0.675: 20-80 % time 177ps typ, 194ps min, 200ps max; typ from 1.11 V to 0.231 V
|   falling waveform, R_fixture 50.000, V_fixture 0.000: 20-80 % time 134ps typ, 152ps min, 147ps max; typ from 0.789 V to 0 V
[Pulldown]
|Voltage   I(typ)   I(min)   I(max)
-1.35V    -277.3mA   -315.7mA   -254.1mA
-1.145V   -153.3mA   -194.8mA   -131.7mA
-1.022V   -95.8mA    -129.9mA   -91.2mA
-858mV    -60.27mA   -66.38mA   -67.52mA
-694mV    -42.7mA    -38.82mA   -46.28mA
-366mV    -16.29mA   -15.7mA    -15.06mA
372mV     13.29mA    12.25mA    12.43mA
2.094V    29.34mA    34.99mA    26.68mA
2.217V    35.47mA    62.59mA    32.81mA
2.381V    67.25mA    133.4mA    44.4mA
2.504V    124.1mA    199.9mA    70.74mA
2.7V      240.2mA    315mA      175mA
[Pullup]
|Voltage   I(typ)   I(min)   I(max)
-1.35V    221.7mA    254.5mA    199.7mA
-1.195V   139mA      173.1mA    115.8mA
-1.072V   84.9mA     114.8mA    67.58mA
-908mV    49.38mA    57.36mA    45.74mA
-785mV    40.04mA    37.36mA    36.8mA
281mV     -9.779mA   -8.204mA   -8.613mA
1.634V    -20.92mA   -18.84mA   -17.88mA
2.044V    -38.88mA   -39.96mA   -34.97mA
2.208V    -53.32mA   -78.7mA    -51.84mA
2.372V    -85.3mA    -149.6mA   -71.05mA
2.536V    -158.3mA   -235.3mA   -105.3mA
2.7V      -249.3mA   -326.7mA   -185.8mA
[Ramp]
| variable   typ   min   max
dV/dt_r   0.473/0.296n   0.410/0.346n   0.450/0.355n
dV/dt_f   0.499/0.285n   0.460/0.289n   0.496/0.351n
R_load = 50.000
[Rising Waveform]
R_fixture = 50.000
V_fixture = 0.000
V_fixture_min = 0.000
V_fixture_max = 0.000
|  time   V(typ)   V(min)   V(max)
0s        16.67uV    136.1uV    7.524uV
351ps     401.5uV    159.7uV    -4.187mV
477ps     5.05mV     236.9uV    337.2mV
567ps     229.6mV    554uV      468.8mV
686ps     490.2mV    -777.2uV   562.7mV
812ps     614.4mV    192.5mV    619.3mV
987ps     690.8mV    453.8mV    663.3mV
1.326ns   743.4mV    604.3mV    702.1mV
2.587ns   777.1mV    669.8mV    737.5mV
10ns      789.2mV    684.3mV    749.7mV
[Rising Waveform]
R_fixture = 50.000
V_fixture = 0.675
V_fixture_min = 0.642
V_fixture_max = 0.710
|  time   V(typ)   V(min)   V(max)
0s        230.8mV    231.8mV    255.2mV
346ps     231mV      231.8mV    255.5mV
457ps     234.1mV    231.9mV    722.1mV
487ps     285.8mV    231.9mV    799.3mV
597ps     722.2mV    230.1mV    952.1mV
677ps     885mV      240.1mV    1.006V
877ps     1.018V     732.4mV    1.068V
1.065ns   1.056V     905.2mV    1.092V
2.298ns   1.096V     1.01V      1.129V
10ns      1.107V     1.023V     1.14V
[Falling Waveform]
R_fixture = 50.000
V_fixture = 0.675
V_fixture_min = 0.642
V_fixture_max = 0.710
|  time   V(typ)   V(min)   V(max)
0s        1.107V     1.023V     1.14V
356ps     1.107V     1.023V     1.137V
467ps     1.101V     1.023V     660.7mV
507ps     983.9mV    1.023V     558.4mV
587ps     616.4mV    1.024V     444.3mV
671ps     434.2mV    1.019V     383.8mV
860ps     315.3mV    477.1mV    324.3mV
1.033ns   281.5mV    331.7mV    302.2mV
1.997ns   245.2mV    245.9mV    269mV
10ns      230.8mV    231.8mV    255.2mV
[Falling Waveform]
R_fixture = 50.000
V_fixture = 0.000
V_fixture_min = 0.000
V_fixture_max = 0.000
|  time   V(typ)   V(min)   V(max)
0s        789.2mV    684.3mV    749.7mV
351ps     788.9mV    684.1mV    751.9mV
457ps     790mV      684.1mV    266.5mV
487ps     714.9mV    683.9mV    205.5mV
577ps     267.6mV    687.2mV    119.1mV
661ps     136.5mV    685.3mV    82.59mV
830ps     64.28mV    183.5mV    48.74mV
1.04ns    35.92mV    62.7mV     31.44mV
2.137ns   9.97mV     9.308mV    8.546mV
10ns      16.67uV    136.1uV    7.524uV
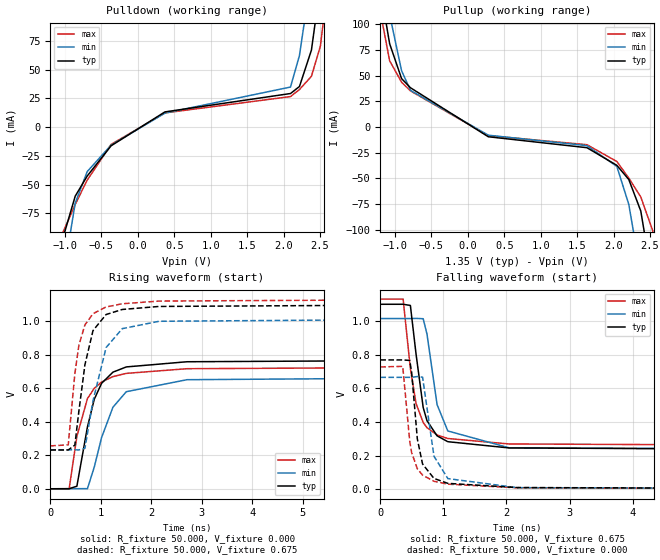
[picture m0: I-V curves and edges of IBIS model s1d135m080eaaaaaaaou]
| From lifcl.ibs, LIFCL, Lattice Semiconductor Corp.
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|Model s1d135m080eaaaaaaaou
[Model] s1d135m080eaaaaaaaou
Model_type Output
Polarity   Non-Inverting
Enable   Active-High
Vmeas =  0.675V
Cref =  30.000pF
Rref =  50.000
Vref =  0.675V
C_comp   5.000pF   4.000pF   5.500pF
[Temperature Range]   25.000   0.125k   -40.000
[Voltage Range]   1.350V   1.280V   1.420V
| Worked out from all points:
|   slope of the pulldown table from 0 to 0.203 V, typ, clamps not added: 25.7 ohm
|   slope of the pullup table from 0 to 0.203 V, typ, clamps not added: 28.6 ohm
|   rising waveform, R_fixture 50.000, V_fixture 0.000: 20-80 % time 372ps typ, 469ps min, 375ps max; typ from 0 V to 0.769 V
|   rising waveform, R_fixture 50.000, V_fixture 0.675: 20-80 % time 282ps typ, 359ps min, 247ps max; typ from 0.231 V to 1.1 V
|   falling waveform, R_fixture 50.000, V_fixture 0.675: 20-80 % time 206ps typ, 235ps min, 218ps max; typ from 1.1 V to 0.231 V
|   falling waveform, R_fixture 50.000, V_fixture 0.000: 20-80 % time 150ps typ, 172ps min, 158ps max; typ from 0.769 V to 0 V
[Pulldown]
|Voltage   I(typ)   I(min)   I(max)
-1.35V    -276.8mA   -315.1mA   -253.5mA
-1.145V   -153mA     -194.4mA   -131.5mA
-1.022V   -95.6mA    -129.7mA   -91mA
-858mV    -60.14mA   -66.23mA   -67.37mA
-694mV    -42.61mA   -38.74mA   -46.18mA
-366mV    -16.25mA   -15.67mA   -15.03mA
372mV     13.27mA    12.22mA    12.4mA
2.094V    29.28mA    34.92mA    26.62mA
2.217V    35.4mA     62.46mA    32.74mA
2.381V    67.11mA    133.1mA    44.3mA
2.504V    123.8mA    199.5mA    70.58mA
2.7V      239.7mA    314.4mA    174.6mA
[Pullup]
|Voltage   I(typ)   I(min)   I(max)
-1.35V    212.2mA    243.6mA    191mA
-1.195V   133.1mA    165.7mA    110.8mA
-1.072V   81.3mA     109.8mA    64.67mA
-908mV    47.25mA    54.89mA    43.77mA
-785mV    38.31mA    35.75mA    35.22mA
281mV     -9.358mA   -7.85mA    -8.243mA
1.634V    -20.02mA   -18.02mA   -17.11mA
2.044V    -37.2mA    -38.24mA   -33.46mA
2.208V    -51.03mA   -75.3mA    -49.61mA
2.372V    -81.6mA    -143.1mA   -67.99mA
2.536V    -151.5mA   -225.1mA   -100.8mA
2.7V      -238.6mA   -312.6mA   -177.7mA
[Ramp]
| variable   typ   min   max
dV/dt_r   0.461/0.378n   0.399/0.470n   0.436/0.381n
dV/dt_f   0.498/0.328n   0.459/0.353n   0.495/0.374n
R_load = 50.000
[Rising Waveform]
R_fixture = 50.000
V_fixture = 0.000
V_fixture_min = 0.000
V_fixture_max = 0.000
|  time   V(typ)   V(min)   V(max)
0s        18.69uV    135.4uV    6.823uV
373ps     663.1uV    156uV      -2.32mV
527ps     15.14mV    491.9uV    312mV
737ps     369mV      776.4uV    538mV
872ps     533.9mV    129.8mV    599.1mV
1.017ns   628.7mV    305.7mV    636.8mV
1.242ns   695.3mV    486.4mV    668.6mV
1.507ns   726.4mV    578.8mV    688mV
2.71ns    757.3mV    650.3mV    715.8mV
10ns      769mV      665.2mV    727.1mV
[Rising Waveform]
R_fixture = 50.000
V_fixture = 0.675
V_fixture_min = 0.642
V_fixture_max = 0.710
|  time   V(typ)   V(min)   V(max)
0s        231.1mV    232.1mV    255.6mV
356ps     231.4mV    232.1mV    261.8mV
487ps     260.2mV    232.3mV    685.3mV
567ps     462.9mV    231.5mV    855.4mV
687ps     740.1mV    241.3mV    977.3mV
847ps     943.1mV    524.9mV    1.044V
1.107ns   1.039V     842.3mV    1.084V
1.427ns   1.069V     954.7mV    1.103V
2.157ns   1.087V     998.6mV    1.119V
10ns      1.1V       1.015V     1.131V
[Falling Waveform]
R_fixture = 50.000
V_fixture = 0.675
V_fixture_min = 0.642
V_fixture_max = 0.710
|  time   V(typ)   V(min)   V(max)
0s        1.1V       1.015V     1.131V
362ps     1.1V       1.015V     1.131V
477ps     1.093V     1.015V     718mV
567ps     803.4mV    1.016V     509.5mV
680ps     485.7mV    1.014V     396.6mV
740ps     407.8mV    923.3mV    365.9mV
900ps     317.3mV    503.4mV    322.3mV
1.07ns    282.5mV    346.3mV    301.4mV
2.04ns    245.3mV    246.3mV    269mV
10ns      231.1mV    232.1mV    255.6mV
[Falling Waveform]
R_fixture = 50.000
V_fixture = 0.000
V_fixture_min = 0.000
V_fixture_max = 0.000
|  time   V(typ)   V(min)   V(max)
0s        769mV      665.2mV    727.1mV
356ps     768.9mV    665.1mV    730.7mV
467ps     765.7mV    665.1mV    284.4mV
497ps     695.9mV    664.8mV    217.5mV
587ps     299.2mV    670.1mV    121.7mV
670ps     149.8mV    666.2mV    83.39mV
851ps     63.84mV    196.1mV    46.9mV
1.071ns   34.46mV    62.83mV    29.76mV
2.167ns   9.635mV    9.04mV     8.176mV
10ns      18.69uV    135.4uV    6.823uV
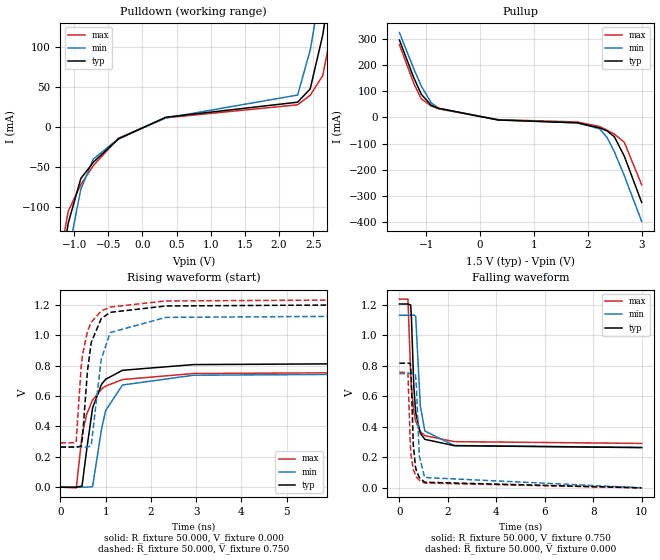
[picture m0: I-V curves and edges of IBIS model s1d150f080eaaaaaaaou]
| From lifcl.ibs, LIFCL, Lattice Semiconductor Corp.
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|Model s1d150f080eaaaaaaaou
[Model] s1d150f080eaaaaaaaou
Model_type Output
Polarity   Non-Inverting
Enable   Active-High
Vmeas =  0.750V
Cref =  30.000pF
Rref =  50.000
Vref =  0.750V
C_comp   5.000pF   4.000pF   5.500pF
[Temperature Range]   25.000   0.125k   -40.000
[Voltage Range]   1.500V   1.430V   1.580V
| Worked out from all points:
|   slope of the pulldown table from 0 to 0.225 V, typ, clamps not added: 26.6 ohm
|   slope of the pullup table from 0 to 0.225 V, typ, clamps not added: 31.3 ohm
|   rising waveform, R_fixture 50.000, V_fixture 0.000: 20-80 % time 310ps typ, 333ps min, 377ps max; typ from 0 V to 0.817 V
|   rising waveform, R_fixture 50.000, V_fixture 0.750: 20-80 % time 217ps typ, 245ps min, 234ps max; typ from 0.264 V to 1.21 V
|   falling waveform, R_fixture 50.000, V_fixture 0.750: 20-80 % time 189ps typ, 202ps min, 215ps max; typ from 1.21 V to 0.264 V
|   falling waveform, R_fixture 50.000, V_fixture 0.000: 20-80 % time 135ps typ, 149ps min, 147ps max; typ from 0.817 V to 0 V
[Pulldown]
|Voltage   I(typ)   I(min)   I(max)
-1.5V     -365.1mA   -396.5mA   -347.3mA
-1.224V   -193.4mA   -233.1mA   -170.4mA
-1.086V   -119.7mA   -157.8mA   -104.9mA
-902mV    -64.26mA   -77.49mA   -71.71mA
-718mV    -43.88mA   -40.05mA   -48.08mA
-350mV    -14.99mA   -14.41mA   -13.83mA
340mV     12.05mA    11.06mA    11.31mA
2.272V    30.8mA     39.7mA     27.56mA
2.456V    47.4mA     95.6mA     39.49mA
2.64V     114.5mA    187mA      63.9mA
2.778V    191.3mA    264.5mA    124.5mA
3V        327.9mA    395.2mA    261.3mA
[Pullup]
|Voltage   I(typ)   I(min)   I(max)
-1.5V     294.3mA    322.7mA    276.4mA
-1.232V   150.2mA    183.7mA    128.5mA
-1.094V   88.1mA     119.2mA    70.61mA
-910mV    45.57mA    55.51mA    43.21mA
-772mV    34.67mA    34.34mA    32.26mA
332mV     -10.04mA   -9.142mA   -8.731mA
1.804V    -20.92mA   -20.69mA   -17.42mA
2.218V    -39.71mA   -43.45mA   -34.95mA
2.356V    -51.48mA   -76.1mA    -48.57mA
2.494V    -73.9mA    -131.1mA   -63.81mA
2.678V    -147.8mA   -221.8mA   -94.9mA
3V        -323.4mA   -395.5mA   -256.5mA
[Ramp]
| variable   typ   min   max
dV/dt_r   0.490/0.312n   0.449/0.337n   0.455/0.377n
dV/dt_f   0.529/0.334n   0.490/0.332n   0.517/0.414n
R_load = 50.000
[Rising Waveform]
R_fixture = 50.000
V_fixture = 0.000
V_fixture_min = 0.000
V_fixture_max = 0.000
|  time   V(typ)   V(min)   V(max)
0s        67.51uV    273.4uV    36.32uV
351ps     399.9uV    297.4uV    -4.155mV
477ps     7.741mV    366.7uV    342mV
578ps     243mV      451uV      478.8mV
710ps     521.1mV    3.499mV    573.2mV
907ps     676.5mV    381.4mV    645.4mV
1ns       710.3mV    505.3mV    665.4mV
1.371ns   769mV      672.2mV    708.2mV
2.944ns   806.6mV    736.6mV    747.9mV
10ns      817.1mV    748.7mV    758.4mV
[Rising Waveform]
R_fixture = 50.000
V_fixture = 0.750
V_fixture_min = 0.713
V_fixture_max = 0.789
|  time   V(typ)   V(min)   V(max)
0s        263.8mV    265.1mV    291.2mV
346ps     263.9mV    265.1mV    293mV
457ps     270.4mV    265.2mV    789.1mV
487ps     326.6mV    265.2mV    867.5mV
597ps     764.2mV    263.3mV    1.026V
680ps     952.1mV    274.6mV    1.085V
901ps     1.109V     842.2mV    1.159V
1.1ns     1.15V      1.017V     1.185V
2.328ns   1.192V     1.117V     1.225V
10ns      1.205V     1.131V     1.237V
[Falling Waveform]
R_fixture = 50.000
V_fixture = 0.750
V_fixture_min = 0.713
V_fixture_max = 0.789
|  time   V(typ)   V(min)   V(max)
0s        1.205V     1.131V     1.237V
351ps     1.205V     1.131V     1.237V
463ps     1.199V     1.131V     749mV
494ps     1.119V     1.131V     660.9mV
594ps     663mV      1.133V     499mV
671ps     494mV      1.125V     437.5mV
861ps     358.3mV    540.2mV    368.9mV
1.049ns   318.1mV    372.5mV    342.2mV
2.269ns   276.5mV    277.5mV    303mV
10ns      263.8mV    265.1mV    291.2mV
[Falling Waveform]
R_fixture = 50.000
V_fixture = 0.000
V_fixture_min = 0.000
V_fixture_max = 0.000
|  time   V(typ)   V(min)   V(max)
0s        817.1mV    748.7mV    758.4mV
351ps     817mV      748.6mV    755mV
451ps     816mV      748.7mV    276.4mV
481ps     747.9mV    748.5mV    212.3mV
571ps     285.3mV    750.6mV    122.1mV
661ps     138.9mV    743.5mV    82.4mV
701ps     111.9mV    659.4mV    71.31mV
821ps     67.8mV     209.4mV    49.95mV
1.041ns   36.75mV    67.9mV     31.55mV
10ns      67.51uV    273.4uV    36.32uV
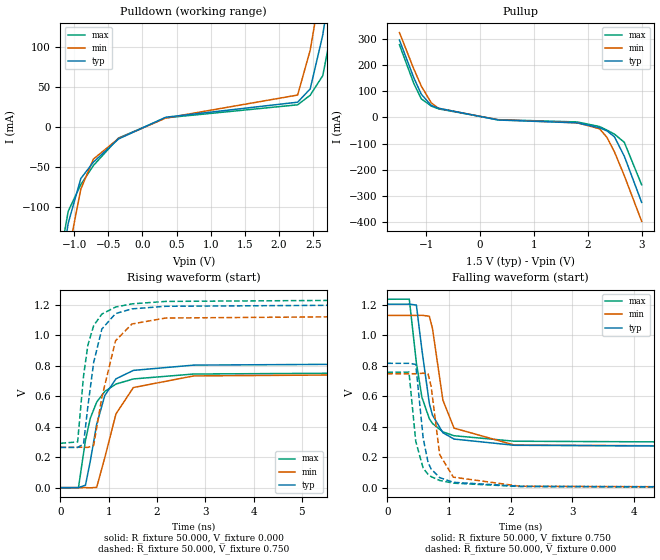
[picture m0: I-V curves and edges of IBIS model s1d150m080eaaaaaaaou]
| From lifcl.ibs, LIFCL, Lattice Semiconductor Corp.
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|Model s1d150m080eaaaaaaaou
[Model] s1d150m080eaaaaaaaou
Model_type Output
Polarity   Non-Inverting
Enable   Active-High
Vmeas =  0.750V
Cref =  30.000pF
Rref =  50.000
Vref =  0.750V
C_comp   5.000pF   4.000pF   5.500pF
[Temperature Range]   25.000   0.125k   -40.000
[Voltage Range]   1.500V   1.430V   1.580V
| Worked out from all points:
|   slope of the pulldown table from 0 to 0.225 V, typ, clamps not added: 26.6 ohm
|   slope of the pullup table from 0 to 0.225 V, typ, clamps not added: 31.3 ohm
|   rising waveform, R_fixture 50.000, V_fixture 0.000: 20-80 % time 383ps typ, 445ps min, 399ps max; typ from 0 V to 0.817 V
|   rising waveform, R_fixture 50.000, V_fixture 0.750: 20-80 % time 290ps typ, 355ps min, 260ps max; typ from 0.264 V to 1.21 V
|   falling waveform, R_fixture 50.000, V_fixture 0.750: 20-80 % time 220ps typ, 248ps min, 235ps max; typ from 1.21 V to 0.264 V
|   falling waveform, R_fixture 50.000, V_fixture 0.000: 20-80 % time 153ps typ, 173ps min, 159ps max; typ from 0.817 V to 0 V
[Pulldown]
|Voltage   I(typ)   I(min)   I(max)
-1.5V     -365.1mA   -396.5mA   -347.3mA
-1.224V   -193.4mA   -233.1mA   -170.4mA
-1.086V   -119.7mA   -157.8mA   -104.9mA
-902mV    -64.26mA   -77.49mA   -71.71mA
-718mV    -43.88mA   -40.05mA   -48.08mA
-350mV    -14.99mA   -14.41mA   -13.83mA
340mV     12.05mA    11.06mA    11.31mA
2.272V    30.8mA     39.7mA     27.56mA
2.456V    47.4mA     95.6mA     39.49mA
2.64V     114.5mA    187mA      63.9mA
2.778V    191.3mA    264.5mA    124.5mA
3V        327.9mA    395.2mA    261.3mA
[Pullup]
|Voltage   I(typ)   I(min)   I(max)
-1.5V     294.3mA    322.7mA    276.4mA
-1.232V   150.2mA    183.7mA    128.5mA
-1.094V   88.1mA     119.2mA    70.61mA
-910mV    45.57mA    55.51mA    43.21mA
-772mV    34.67mA    34.34mA    32.26mA
332mV     -10.04mA   -9.142mA   -8.731mA
1.804V    -20.92mA   -20.69mA   -17.42mA
2.218V    -39.71mA   -43.45mA   -34.95mA
2.356V    -51.48mA   -76.1mA    -48.57mA
2.494V    -73.9mA    -131.1mA   -63.81mA
2.678V    -147.8mA   -221.8mA   -94.9mA
3V        -323.4mA   -395.5mA   -256.5mA
[Ramp]
| variable   typ   min   max
dV/dt_r   0.490/0.391n   0.449/0.443n   0.455/0.398n
dV/dt_f   0.529/0.375n   0.490/0.402n   0.517/0.438n
R_load = 50.000
[Rising Waveform]
R_fixture = 50.000
V_fixture = 0.000
V_fixture_min = 0.000
V_fixture_max = 0.000
|  time   V(typ)   V(min)   V(max)
0s        67.51uV    273.4uV    36.32uV
373ps     639.9uV    295uV      -251.4uV
518ps     15.75mV    549.5uV    310.3mV
618ps     173.6mV    -1.157mV   455.4mV
751ps     416.3mV    2.302mV    561.4mV
918ps     604.3mV    195.8mV    631.3mV
1.15ns    714mV      483.9mV    679.7mV
1.511ns   769.5mV    657mV      713.4mV
2.76ns    804.1mV    733.2mV    745.7mV
10ns      817.1mV    748.7mV    758.4mV
[Rising Waveform]
R_fixture = 50.000
V_fixture = 0.750
V_fixture_min = 0.713
V_fixture_max = 0.789
|  time   V(typ)   V(min)   V(max)
0s        263.8mV    265.1mV    291.2mV
356ps     263.9mV    265.1mV    300.4mV
478ps     286mV      265.2mV    731.3mV
568ps     532.6mV    264.2mV    934.8mV
688ps     821mV      277.1mV    1.063V
858ps     1.041V     592.5mV    1.139V
1.141ns   1.142V     963.7mV    1.185V
1.481ns   1.173V     1.074V     1.206V
2.178ns   1.19V      1.113V     1.222V
10ns      1.205V     1.131V     1.237V
[Falling Waveform]
R_fixture = 50.000
V_fixture = 0.750
V_fixture_min = 0.713
V_fixture_max = 0.789
|  time   V(typ)   V(min)   V(max)
0s        1.205V     1.131V     1.237V
356ps     1.205V     1.131V     1.238V
471ps     1.199V     1.131V     820.5mV
561ps     904.9mV    1.132V     593.8mV
681ps     554mV      1.126V     453.6mV
732ps     477.1mV    1.046V     422.5mV
901ps     361.7mV    575.9mV    367.3mV
1.082ns   320.1mV    391.8mV    342mV
2.061ns   279.3mV    280.8mV    306mV
10ns      263.8mV    265.1mV    291.2mV
[Falling Waveform]
R_fixture = 50.000
V_fixture = 0.000
V_fixture_min = 0.000
V_fixture_max = 0.000
|  time   V(typ)   V(min)   V(max)
0s        817.1mV    748.7mV    758.4mV
351ps     816.9mV    748.5mV    759.2mV
461ps     809.9mV    748.6mV    305.1mV
581ps     327.1mV    751.9mV    128.9mV
661ps     166.1mV    747.5mV    88.86mV
711ps     123.1mV    665.1mV    73.47mV
849ps     67.4mV     218.4mV    48.63mV
1.071ns   36.23mV    70.12mV    30.83mV
2.16ns    10.32mV    10.25mV    8.598mV
10ns      67.51uV    273.4uV    36.32uV
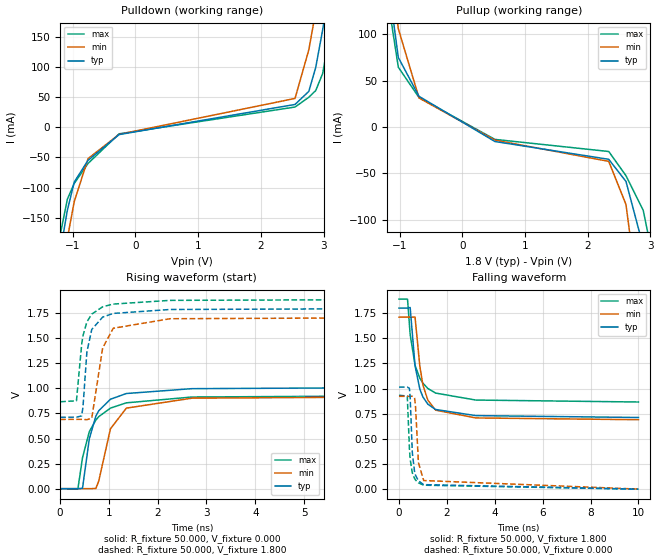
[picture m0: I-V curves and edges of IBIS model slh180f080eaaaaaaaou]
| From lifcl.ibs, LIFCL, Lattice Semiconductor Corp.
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|Model slh180f080eaaaaaaaou
[Model] slh180f080eaaaaaaaou
Model_type Output
Polarity   Non-Inverting
Enable   Active-High
Vmeas =  0.900V
Cref =  0.0F
Rref =  1.000M
Vref =  0.0V
C_comp   5.000pF   4.000pF   5.500pF
[Temperature Range]   25.000   0.125k   -40.000
[Voltage Range]   1.800V   1.710V   1.890V
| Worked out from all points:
|   slope of the pulldown table from 0 to 0.27 V, typ, clamps not added: 23.6 ohm
|   slope of the pullup table from 0 to 0.27 V, typ, clamps not added: 30.3 ohm
|   rising waveform, R_fixture 50.000, V_fixture 0.000: 20-80 % time 322ps typ, 360ps min, 428ps max; typ from 0 V to 1.01 V
|   rising waveform, R_fixture 50.000, V_fixture 1.800: 20-80 % time 159ps typ, 221ps min, 193ps max; typ from 0.713 V to 1.8 V
|   falling waveform, R_fixture 50.000, V_fixture 1.800: 20-80 % time 435ps typ, 422ps min, 527ps max; typ from 1.8 V to 0.713 V
|   falling waveform, R_fixture 50.000, V_fixture 0.000: 20-80 % time 141ps typ, 150ps min, 148ps max; typ from 1.01 V to 0 V
[Pulldown]
|Voltage   I(typ)   I(min)   I(max)
-1.8V     -648.3mA   -680.5mA   -631mA
-1.195V   -204.1mA   -253.8mA   -176mA
-1.085V   -137.7mA   -184.3mA   -119.3mA
-975mV    -90.87mA   -123.2mA   -93.17mA
-755mV    -54.94mA   -52.05mA   -60.1mA
-260mV    -12.31mA   -11.97mA   -11.06mA
2.545V    37.57mA    47.54mA    33.32mA
2.765V    59.28mA    128.1mA    49.49mA
2.875V    98.8mA     191.8mA    60.56mA
2.985V    160.8mA    261.8mA    88.66mA
3.15V     271.8mA    373.1mA    184.5mA
3.6V      602.8mA    691.1mA    521.3mA
[Pullup]
|Voltage   I(typ)   I(min)   I(max)
-1.8V     566.5mA    591.4mA    552.5mA
-1.35V    256.8mA    295.3mA    232.6mA
-1.24V    186.4mA    227mA      161mA
-1.02V    75.16mA    106.2mA    64.66mA
-690mV    33.26mA    31.49mA    31.95mA
520mV     -15.5mA    -14mA      -13.22mA
2.335V    -34.71mA   -36.93mA   -26.28mA
2.61V     -58.6mA    -83.45mA   -52.36mA
2.885V    -128.8mA   -225.3mA   -89.8mA
3.05V     -225.6mA   -329.7mA   -144.4mA
3.16V     -298.3mA   -402.1mA   -210.4mA
3.6V      -606.7mA   -700.4mA   -522.1mA
[Ramp]
| variable   typ   min   max
dV/dt_r   0.609/0.321n   0.554/0.360n   0.560/0.430n
dV/dt_f   0.668/0.436n   0.627/0.425n   0.638/0.532n
R_load = 50.000
[Rising Waveform]
R_fixture = 50.000
V_fixture = 0.000
V_fixture_min = 0.000
V_fixture_max = 0.000
|  time   V(typ)   V(min)   V(max)
0s        123.1uV    588.1uV    52.8uV
363ps     572.1uV    612.8uV    -4.618mV
458ps     3.571mV    638uV      308.1mV
598ps     497.8mV    92.61uV    569mV
732ps     723.5mV    2.285mV    684.1mV
791ps     776.8mV    76.08mV    718.1mV
1.031ns   891.8mV    597mV      803.1mV
1.357ns   948.6mV    803.1mV    855.8mV
2.7ns     997mV      902.1mV    913.8mV
10ns      1.015V     923.1mV    933.1mV
[Rising Waveform]
R_fixture = 50.000
V_fixture = 1.800
V_fixture_min = 1.710
V_fixture_max = 1.890
|  time   V(typ)   V(min)   V(max)
0s        712.5mV    690.6mV    866.5mV
334ps     712.7mV    690.7mV    875.8mV
441ps     725.7mV    691mV      1.437V
468ps     814.6mV    691mV      1.525V
548ps     1.363V     687.7mV    1.662V
648ps     1.587V     702.5mV    1.74V
871ps     1.71V      1.402V     1.813V
1.088ns   1.747V     1.599V     1.84V
2.253ns   1.786V     1.694V     1.877V
10ns      1.8V       1.71V      1.89V
[Falling Waveform]
R_fixture = 50.000
V_fixture = 1.800
V_fixture_min = 1.710
V_fixture_max = 1.890
|  time   V(typ)   V(min)   V(max)
0s        1.8V       1.71V      1.89V
356ps     1.8V       1.71V      1.889V
466ps     1.806V     1.71V      1.538V
670ps     1.226V     1.711V     1.232V
870ps     994.5mV    1.223V     1.103V
1.001ns   915.8mV    1.032V     1.053V
1.206ns   844.8mV    884.7mV    1.001V
1.529ns   792.1mV    785.6mV    955.4mV
3.206ns   731.3mV    708.2mV    886mV
10ns      712.5mV    690.6mV    866.5mV
[Falling Waveform]
R_fixture = 50.000
V_fixture = 0.000
V_fixture_min = 0.000
V_fixture_max = 0.000
|  time   V(typ)   V(min)   V(max)
0s        1.015V     923.1mV    933.1mV
346ps     1.015V     923mV      926.4mV
436ps     1.002V     923.1mV    400.6mV
466ps     914.4mV    923mV      298.5mV
556ps     364.3mV    924.1mV    163mV
650ps     171.9mV    909.9mV    105.8mV
691ps     137.4mV    820.8mV    90.74mV
811ps     82.96mV    264.1mV    62.93mV
1.03ns    45.14mV    85.82mV    39.5mV
10ns      123.1uV    588.1uV    52.8uV
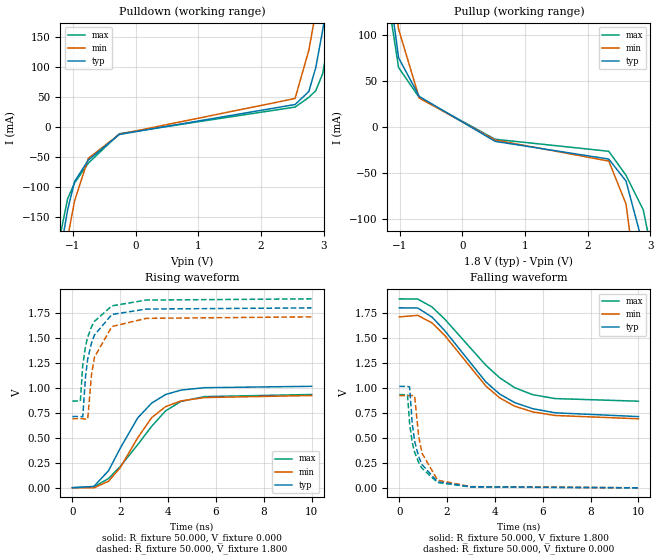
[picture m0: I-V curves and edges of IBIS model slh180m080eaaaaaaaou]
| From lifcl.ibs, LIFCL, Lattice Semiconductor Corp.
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|Model slh180m080eaaaaaaaou
[Model] slh180m080eaaaaaaaou
Model_type Output
Polarity   Non-Inverting
Enable   Active-High
Vmeas =  0.900V
Cref =  0.0F
Rref =  1.000M
Vref =  0.0V
C_comp   5.000pF   4.000pF   5.500pF
[Temperature Range]   25.000   0.125k   -40.000
[Voltage Range]   1.800V   1.710V   1.890V
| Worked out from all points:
|   slope of the pulldown table from 0 to 0.27 V, typ, clamps not added: 23.6 ohm
|   slope of the pullup table from 0 to 0.27 V, typ, clamps not added: 30.3 ohm
|   rising waveform, R_fixture 50.000, V_fixture 0.000: 20-80 % time 1.56ns typ, 1.52ns min, 1.89ns max; typ from 0 V to 1.01 V
|   rising waveform, R_fixture 50.000, V_fixture 1.800: 20-80 % time 531ps typ, 527ps min, 592ps max; typ from 0.713 V to 1.8 V
|   falling waveform, R_fixture 50.000, V_fixture 1.800: 20-80 % time 2.38ns typ, 2.27ns min, 2.45ns max; typ from 1.8 V to 0.713 V
|   falling waveform, R_fixture 50.000, V_fixture 0.000: 20-80 % time 525ps typ, 497ps min, 574ps max; typ from 1.01 V to 0 V
[Pulldown]
|Voltage   I(typ)   I(min)   I(max)
-1.8V     -648.3mA   -680.5mA   -631mA
-1.195V   -204.1mA   -253.8mA   -176mA
-1.085V   -137.7mA   -184.3mA   -119.3mA
-975mV    -90.87mA   -123.2mA   -93.17mA
-755mV    -54.94mA   -52.05mA   -60.1mA
-260mV    -12.31mA   -11.97mA   -11.06mA
2.545V    37.57mA    47.54mA    33.32mA
2.765V    59.28mA    128.1mA    49.49mA
2.875V    98.8mA     191.8mA    60.56mA
2.985V    160.8mA    261.8mA    88.66mA
3.15V     271.8mA    373.1mA    184.5mA
3.6V      602.8mA    691.1mA    521.3mA
[Pullup]
|Voltage   I(typ)   I(min)   I(max)
-1.8V     566.5mA    591.4mA    552.5mA
-1.35V    256.8mA    295.3mA    232.6mA
-1.24V    186.4mA    227mA      161mA
-1.02V    75.16mA    106.2mA    64.66mA
-690mV    33.26mA    31.49mA    31.95mA
520mV     -15.5mA    -14mA      -13.22mA
2.335V    -34.71mA   -36.93mA   -26.28mA
2.61V     -58.6mA    -83.45mA   -52.36mA
2.885V    -128.8mA   -225.3mA   -89.8mA
3.05V     -225.6mA   -329.7mA   -144.4mA
3.16V     -298.3mA   -402.1mA   -210.4mA
3.6V      -606.7mA   -700.4mA   -522.1mA
[Ramp]
| variable   typ   min   max
dV/dt_r   0.609/1.570n   0.554/1.567n   0.560/1.928n
dV/dt_f   0.666/2.463n   0.624/2.370n   0.636/2.551n
R_load = 50.000
[Rising Waveform]
R_fixture = 50.000
V_fixture = 0.000
V_fixture_min = 0.000
V_fixture_max = 0.000
|  time   V(typ)   V(min)   V(max)
0s        123.1uV    589.2uV    52.8uV
899ps     13.6mV     -1.166mV   8.699mV
1.512ns   170.7mV    65.06mV    92.42mV
2.002ns   396.2mV    202.1mV    213.6mV
2.729ns   698.5mV    499.3mV    430.9mV
3.311ns   846.6mV    700.4mV    613.9mV
3.898ns   932.9mV    812mV      769.7mV
4.541ns   977.2mV    868.7mV    863.9mV
5.52ns    1.001V     902.2mV    911.8mV
10ns      1.015V     923.1mV    933.1mV
[Rising Waveform]
R_fixture = 50.000
V_fixture = 1.800
V_fixture_min = 1.710
V_fixture_max = 1.890
|  time   V(typ)   V(min)   V(max)
0s        712.5mV    690.6mV    866.5mV
333ps     713mV      690.7mV    868mV
431ps     709.2mV    691mV      1.224V
548ps     1.111V     686.6mV    1.416V
639ps     1.286V     686.3mV    1.506V
798ps     1.448V     1.131V     1.61V
922ps     1.528V     1.306V     1.665V
1.65ns    1.734V     1.613V     1.82V
3.085ns   1.788V     1.695V     1.878V
10ns      1.8V       1.71V      1.89V
[Falling Waveform]
R_fixture = 50.000
V_fixture = 1.800
V_fixture_min = 1.710
V_fixture_max = 1.890
|  time   V(typ)   V(min)   V(max)
0s        1.8V       1.71V      1.89V
770ps     1.799V     1.725V     1.888V
1.368ns   1.708V     1.65V      1.809V
1.901ns   1.572V     1.524V     1.687V
3.62ns    1.059V     1.018V     1.226V
4.201ns   937.7mV    899.4mV    1.1V
4.829ns   852mV      816.4mV    1.001V
5.571ns   792mV      760.2mV    932.3mV
6.505ns   750.8mV    724mV      893mV
10ns      712.5mV    690.6mV    866.5mV
[Falling Waveform]
R_fixture = 50.000
V_fixture = 0.000
V_fixture_min = 0.000
V_fixture_max = 0.000
|  time   V(typ)   V(min)   V(max)
0s        1.015V     923.1mV    933.1mV
343ps     1.014V     922.9mV    930.6mV
433ps     1.009V     923.1mV    641.3mV
541ps     644.2mV    923.5mV    455.4mV
641ps     466.8mV    917.4mV    357.6mV
811ps     311.7mV    515.6mV    253.2mV
951ps     232.8mV    346.6mV    195.4mV
1.599ns   60.58mV    77.12mV    53.35mV
2.989ns   11.11mV    12.16mV    8.525mV
10ns      123.1uV    589.2uV    52.8uV
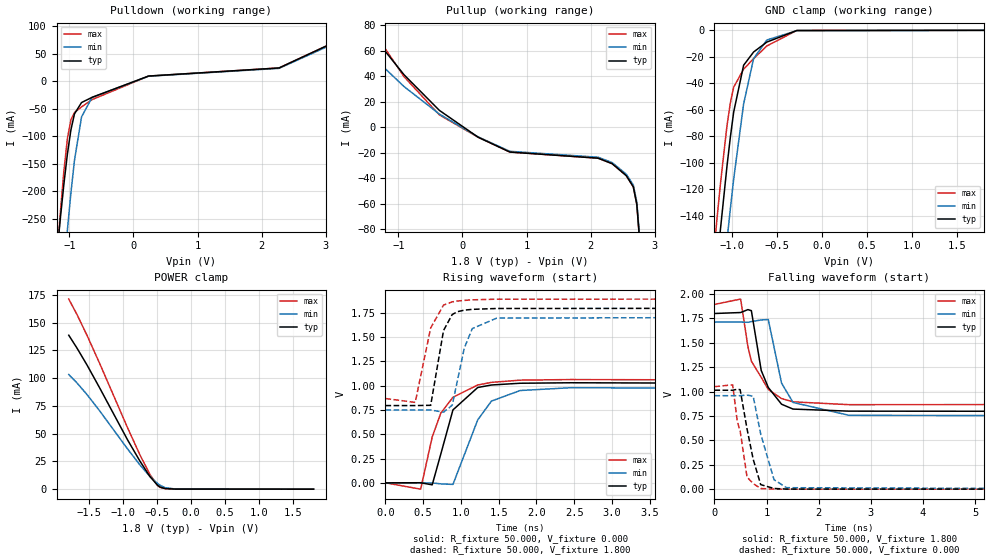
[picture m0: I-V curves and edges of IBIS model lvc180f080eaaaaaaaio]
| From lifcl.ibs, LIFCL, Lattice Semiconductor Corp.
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[Model] lvc180f080eaaaaaaaio
Model_type I/O
Polarity   Non-Inverting
Enable   Active-Low
Vinl =  0.630V
Vinh =  1.170V
Vmeas =  0.900V
Cref =  0.0F
Rref =  1.000M
Vref =  0.0V
C_comp   5.000pF   4.000pF   5.500pF
[Temperature Range]   25.000   0.125k   -40.000
[Voltage Range]   1.800V   1.710V   1.890V
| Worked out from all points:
|   slope of the pulldown table from 0 to 0.27 V, typ, clamps not added: 25.1 ohm
|   slope of the pullup table from 0 to 0.27 V, typ, clamps not added: 31.2 ohm
|   GND clamp passes 1 mA (typ) near -0.37 V on its own axis
|   POWER clamp passes 1 mA (typ) near -0.42 V on its own axis
|   rising waveform, R_fixture 50.000, V_fixture 0.000: 20-80 % time 227ps typ, 289ps min, 291ps max; typ from 0 V to 1.01 V
|   rising waveform, R_fixture 50.000, V_fixture 1.800: 20-80 % time 130ps typ, 175ps min, 166ps max; typ from 0.796 V to 1.8 V
|   falling waveform, R_fixture 50.000, V_fixture 1.800: 20-80 % time 328ps typ, 278ps min, 385ps max; typ from 1.8 V to 0.796 V
|   falling waveform, R_fixture 50.000, V_fixture 0.000: 20-80 % time 210ps typ, 271ps min, 184ps max; typ from 1.01 V to 0 V
[GND_clamp]
|Voltage   I(typ)   I(min)   I(max)
-1.8V     -665.5mA   -701.9mA   -644.7mA
-1.208V   -203.2mA   -259.3mA   -168.6mA
-1.171V   -176.5mA   -233.3mA   -141.8mA
-1.134V   -150.7mA   -207.7mA   -116.3mA
-1.06V    -102.3mA   -158.3mA   -71.8mA
-1.023V   -80.78mA   -134.8mA   -54.83mA
-986mV    -61.78mA   -112.4mA   -42.93mA
-875mV    -26.33mA   -55.53mA   -29.29mA
-764mV    -16.38mA   -21.41mA   -21.4mA
-616mV    -8.858mA   -7.288mA   -11.79mA
-283mV    -142.7uA   -287uA     -113.6uA
1.8V      0A         0A         0A
[POWER_clamp]
|Voltage   I(typ)   I(min)   I(max)
-1.8V     138.7mA    103.3mA    171.3mA
-1.678V   127mA      95.65mA    157.2mA
-1.53V    111.7mA    85.11mA    138.4mA
-1.345V   91.17mA    70.52mA    113.2mA
-938mV    44.71mA    36.47mA    55.67mA
-753mV    25.22mA    21.78mA    30.82mA
-605mV    11.26mA    11.4mA     13.08mA
-494mV    3.49mA     5.157mA    3.227mA
-457mV    1.898mA    3.519mA    1.512mA
-383mV    542.5uA    1.315mA    536.2uA
-235mV    73.61uA    152.3uA    57.83uA
1.8V      0A         0A         0A
[Pulldown]
|Voltage   I(typ)   I(min)   I(max)
-1.8V     -1.123A    -1.448A    -1.379A
-1.195V   -315.4mA   -500.8mA   -322.9mA
-1.14V    -249.2mA   -420.7mA   -238.5mA
-1.085V   -187mA     -343.4mA   -163mA
-1.03V    -131.9mA   -270mA     -104mA
-975mV    -88.04mA   -202.5mA   -69.67mA
-920mV    -59.22mA   -143.8mA   -56.86mA
-810mV    -38.63mA   -64.78mA   -46.55mA
-645mV    -29.15mA   -29.22mA   -33.27mA
235mV     9.566mA    9.279mA    9.566mA
2.27V     24.3mA     23.57mA    24.3mA
3.6V      96.4mA     93.5mA     96.4mA
[Pullup]
|Voltage   I(typ)   I(min)   I(max)
-1.8V     97mA       74.36mA    106.2mA
-910mV    41.1mA     31.86mA    39.59mA
-360mV    13.18mA    10.28mA    9.638mA
245mV     -7.923mA   -7.685mA   -7.923mA
740mV     -19.57mA   -18.99mA   -19.57mA
2.115V    -24.37mA   -23.64mA   -24.37mA
2.335V    -28.69mA   -27.83mA   -28.69mA
2.555V    -38.07mA   -36.93mA   -38.07mA
2.665V    -46.88mA   -45.47mA   -46.88mA
2.72V     -60.75mA   -58.92mA   -60.75mA
2.83V     -131.6mA   -127.7mA   -131.6mA
3.6V      -1.109A    -1.075A    -1.109A
[Ramp]
| variable   typ   min   max
dV/dt_r   0.608/0.227n   0.575/0.288n   0.630/0.291n
dV/dt_f   0.602/0.326n   0.577/0.278n   0.614/0.387n
R_load = 50.000
[Rising Waveform]
R_fixture = 50.000
V_fixture = 0.000
V_fixture_min = 0.000
V_fixture_max = 0.000
|  time   V(typ)   V(min)   V(max)
0s        66.63uV    -469.7uV   428.7uV
466ps     1.402mV    -519.1uV   -64.84mV
619ps     -20.31mV   -249.4uV   472.7mV
734ps     300.2mV    -10.52mV   719.9mV
894ps     751.6mV    -15.85mV   881.6mV
1.222ns   982.1mV    648.5mV    1.008V
1.404ns   1.008V     842.4mV    1.035V
1.784ns   1.026V     951mV      1.058V
2.454ns   1.031V     980mV      1.064V
10ns      1.014V     958.1mV    1.05V
[Rising Waveform]
R_fixture = 50.000
V_fixture = 1.800
V_fixture_min = 1.710
V_fixture_max = 1.890
|  time   V(typ)   V(min)   V(max)
0s        796mV      750.1mV    868.6mV
394ps     796.1mV    749.8mV    828.8mV
599ps     798.8mV    750.3mV    1.596V
769ps     1.569V     728.2mV    1.831V
884ps     1.734V     799.4mV    1.864V
954ps     1.763V     1.057V     1.873V
1.044ns   1.779V     1.388V     1.879V
1.15ns    1.787V     1.589V     1.885V
1.474ns   1.796V     1.697V     1.892V
10ns      1.8V       1.712V     1.893V
[Falling Waveform]
R_fixture = 50.000
V_fixture = 1.800
V_fixture_min = 1.710
V_fixture_max = 1.890
|  time   V(typ)   V(min)   V(max)
0s        1.8V       1.712V     1.893V
502ps     1.81V      1.712V     1.948V
642ps     1.84V      1.71V      1.46V
708ps     1.829V     1.717V     1.311V
897ps     1.216V     1.734V     1.146V
1.032ns   1.042V     1.738V     1.022V
1.287ns   870.1mV    1.086V     928.2mV
1.507ns   820.4mV    888.3mV    894.6mV
2.582ns   799.2mV    756.3mV    865.5mV
10ns      796mV      750.1mV    868.6mV
[Falling Waveform]
R_fixture = 50.000
V_fixture = 0.000
V_fixture_min = 0.000
V_fixture_max = 0.000
|  time   V(typ)   V(min)   V(max)
0s        1.014V     958.1mV    1.05V
349ps     1.013V     957.8mV    1.069V
440ps     1.024V     957.9mV    689.1mV
493ps     1.019V     957.9mV    596.3mV
625ps     617mV      963.7mV    123.3mV
743ps     305.8mV    952.3mV    56.53mV
887ps     45.93mV    564.3mV    6.433mV
1.143ns   6.751mV    96.23mV    -256uV
1.383ns   431.9uV    14.61mV    -438.9uV
10ns      66.63uV    -469.7uV   428.7uV
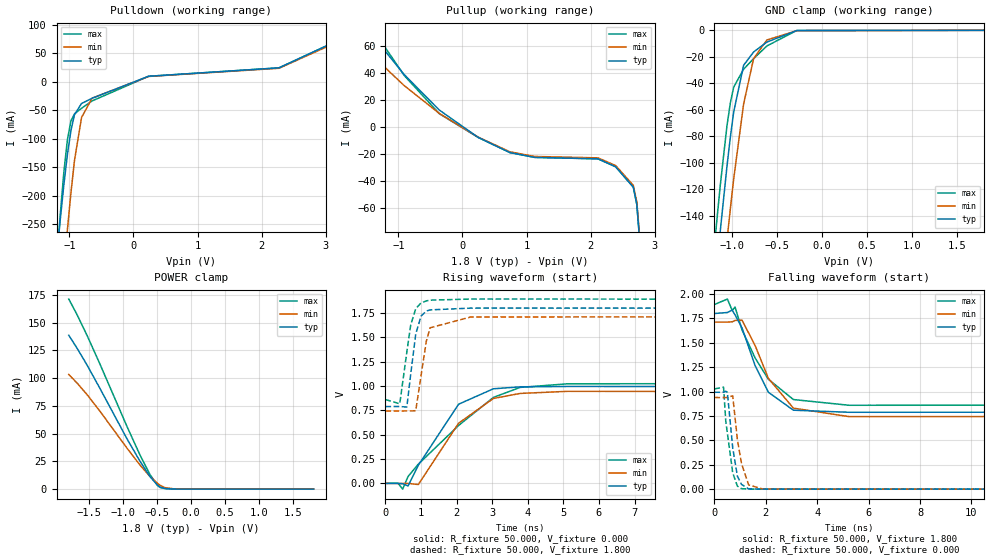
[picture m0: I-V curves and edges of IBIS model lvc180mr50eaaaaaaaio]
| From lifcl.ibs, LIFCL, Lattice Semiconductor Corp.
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[Model] lvc180mr50eaaaaaaaio
Model_type I/O
Polarity   Non-Inverting
Enable   Active-Low
Vinl =  0.630V
Vinh =  1.170V
Vmeas =  0.900V
Cref =  0.0F
Rref =  1.000M
Vref =  0.0V
C_comp   5.000pF   4.000pF   5.500pF
[Temperature Range]   25.000   0.125k   -40.000
[Voltage Range]   1.800V   1.710V   1.890V
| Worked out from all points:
|   slope of the pulldown table from 0 to 0.27 V, typ, clamps not added: 25 ohm
|   slope of the pullup table from 0 to 0.27 V, typ, clamps not added: 32.3 ohm
|   GND clamp passes 1 mA (typ) near -0.37 V on its own axis
|   POWER clamp passes 1 mA (typ) near -0.42 V on its own axis
|   rising waveform, R_fixture 50.000, V_fixture 0.000: 20-80 % time 1.06ns typ, 1.16ns min, 1.83ns max; typ from 0 V to 0.993 V
|   rising waveform, R_fixture 50.000, V_fixture 1.800: 20-80 % time 213ps typ, 239ps min, 242ps max; typ from 0.789 V to 1.8 V
|   falling waveform, R_fixture 50.000, V_fixture 1.800: 20-80 % time 952ps typ, 1.14ns min, 1.28ns max; typ from 1.8 V to 0.789 V
|   falling waveform, R_fixture 50.000, V_fixture 0.000: 20-80 % time 275ps typ, 309ps min, 268ps max; typ from 0.993 V to 0 V
[GND_clamp]
|Voltage   I(typ)   I(min)   I(max)
-1.8V     -665.5mA   -701.9mA   -644.7mA
-1.208V   -203.2mA   -259.3mA   -168.6mA
-1.171V   -176.5mA   -233.3mA   -141.8mA
-1.134V   -150.7mA   -207.7mA   -116.3mA
-1.06V    -102.3mA   -158.3mA   -71.8mA
-1.023V   -80.78mA   -134.8mA   -54.83mA
-986mV    -61.78mA   -112.4mA   -42.93mA
-875mV    -26.33mA   -55.53mA   -29.29mA
-764mV    -16.38mA   -21.41mA   -21.4mA
-616mV    -8.858mA   -7.288mA   -11.79mA
-283mV    -142.7uA   -287uA     -113.6uA
1.8V      0A         0A         0A
[POWER_clamp]
|Voltage   I(typ)   I(min)   I(max)
-1.8V     138.7mA    103.3mA    171.3mA
-1.678V   127mA      95.65mA    157.2mA
-1.53V    111.7mA    85.11mA    138.4mA
-1.345V   91.17mA    70.52mA    113.2mA
-938mV    44.71mA    36.47mA    55.67mA
-753mV    25.22mA    21.78mA    30.82mA
-605mV    11.26mA    11.4mA     13.08mA
-494mV    3.49mA     5.157mA    3.227mA
-457mV    1.898mA    3.519mA    1.512mA
-383mV    542.5uA    1.315mA    536.2uA
-235mV    73.61uA    152.3uA    57.83uA
1.8V      0A         0A         0A
[Pulldown]
|Voltage   I(typ)   I(min)   I(max)
-1.8V     -1.08A     -1.388A    -1.33A
-1.195V   -303.6mA   -480.3mA   -311.8mA
-1.14V    -239.9mA   -403.5mA   -230.5mA
-1.085V   -180.2mA   -329.4mA   -157.9mA
-1.03V    -127.4mA   -259.2mA   -101.4mA
-975mV    -85.32mA   -194.6mA   -68.58mA
-920mV    -57.77mA   -138.3mA   -56.42mA
-810mV    -38.12mA   -62.78mA   -46.5mA
-645mV    -28.94mA   -28.78mA   -33.65mA
235mV     9.585mA    9.298mA    9.585mA
2.27V     24.38mA    23.65mA    24.38mA
3.6V      93.7mA     90.9mA     93.7mA
[Pullup]
|Voltage   I(typ)   I(min)   I(max)
-1.8V     91.7mA     71.06mA    101.1mA
-910mV    39.18mA    30.97mA    38.56mA
-360mV    12.69mA    10.18mA    9.975mA
245mV     -7.638mA   -7.409mA   -7.638mA
740mV     -18.9mA    -18.34mA   -18.9mA
1.125V    -22.49mA   -21.82mA   -22.49mA
2.115V    -23.57mA   -22.86mA   -23.57mA
2.39V     -29.49mA   -28.6mA    -29.49mA
2.665V    -44.62mA   -43.28mA   -44.62mA
2.72V     -57.53mA   -55.81mA   -57.53mA
2.83V     -123.7mA   -120mA     -123.7mA
3.6V      -1.039A    -1.008A    -1.039A
[Ramp]
| variable   typ   min   max
dV/dt_r   0.596/1.065n   0.564/1.163n   0.616/1.834n
dV/dt_f   0.606/0.953n   0.581/1.135n   0.618/1.276n
R_load = 50.000
[Rising Waveform]
R_fixture = 50.000
V_fixture = 0.000
V_fixture_min = 0.000
V_fixture_max = 0.000
|  time   V(typ)   V(min)   V(max)
0s        66.03uV    -521.6uV   750.4uV
351ps     55.7uV     -815.7uV   3.133mV
482ps     -2.908mV   -543.1uV   -59.25mV
634ps     -26.49mV   -253.1uV   70.87mV
923ps     186.2mV    -11.7mV    197.9mV
2.054ns   813mV      618mV      594.6mV
3.033ns   971.8mV    872.2mV    883.2mV
3.784ns   991.1mV    923.9mV    985.8mV
5.13ns    995.7mV    945.5mV    1.023V
20ns      992.9mV    938.8mV    1.027V
[Rising Waveform]
R_fixture = 50.000
V_fixture = 1.800
V_fixture_min = 1.710
V_fixture_max = 1.890
|  time   V(typ)   V(min)   V(max)
0s        789.2mV    744.2mV    861.1mV
401ps     789.4mV    743.8mV    817.5mV
600ps     784.3mV    744.4mV    1.349V
709ps     1.122V     744.2mV    1.627V
850ps     1.534V     746.2mV    1.794V
1ns       1.719V     1.108V     1.854V
1.149ns   1.77V      1.462V     1.874V
1.254ns   1.782V     1.598V     1.882V
2.396ns   1.8V       1.709V     1.893V
20ns      1.8V       1.712V     1.892V
[Falling Waveform]
R_fixture = 50.000
V_fixture = 1.800
V_fixture_min = 1.710
V_fixture_max = 1.890
|  time   V(typ)   V(min)   V(max)
0s        1.8V       1.712V     1.892V
504ps     1.81V      1.712V     1.948V
692ps     1.835V     1.715V     1.831V
802ps     1.786V     1.729V     1.866V
1.072ns   1.653V     1.732V     1.633V
1.581ns   1.267V     1.473V     1.345V
2.099ns   992.8mV    1.135V     1.126V
3.072ns   808.8mV    829.9mV    918.1mV
5.24ns    787.6mV    743.1mV    859.4mV
20ns      789.2mV    744.2mV    861.1mV
[Falling Waveform]
R_fixture = 50.000
V_fixture = 0.000
V_fixture_min = 0.000
V_fixture_max = 0.000
|  time   V(typ)   V(min)   V(max)
0s        992.9mV    938.8mV    1.027V
354ps     992.5mV    938.5mV    1.045V
441ps     1.003V     938.7mV    695.8mV
502ps     994mV      938.6mV    575.6mV
711ps     423.8mV    956.4mV    167.7mV
892ps     133.7mV    509.5mV    30.93mV
1.056ns   47.67mV    259.4mV    4.685mV
1.332ns   2.216mV    42.88mV    548.3uV
1.892ns   175.1uV    771.5uV    323.4uV
20ns      66.03uV    -521.6uV   750.4uV
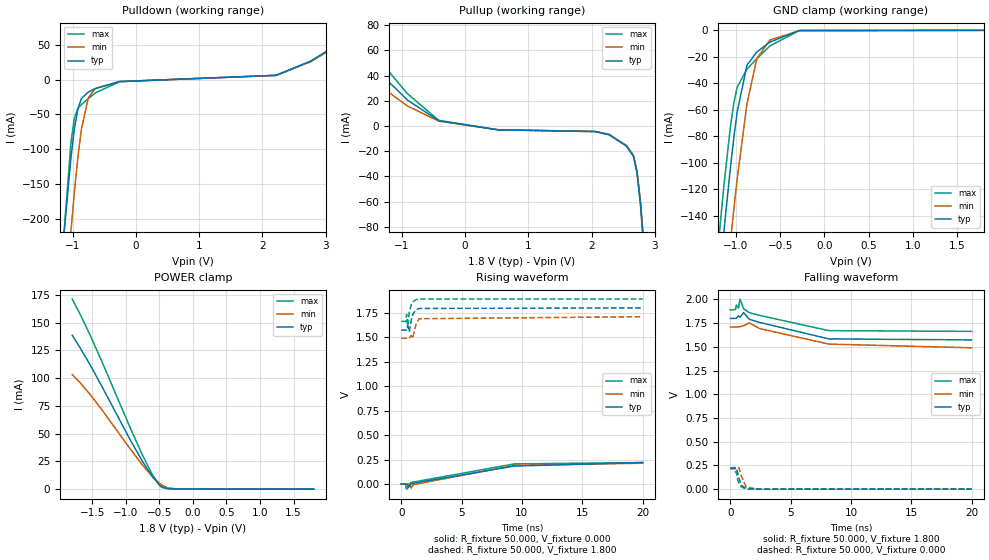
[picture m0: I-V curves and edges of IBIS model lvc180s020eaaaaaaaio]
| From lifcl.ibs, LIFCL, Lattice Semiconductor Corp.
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[Model] lvc180s020eaaaaaaaio
Model_type I/O
Polarity   Non-Inverting
Enable   Active-Low
Vinl =  0.630V
Vinh =  1.170V
Vmeas =  0.900V
Cref =  0.0F
Rref =  1.000M
Vref =  0.0V
C_comp   5.000pF   4.000pF   5.500pF
[Temperature Range]   25.000   0.125k   -40.000
[Voltage Range]   1.800V   1.710V   1.890V
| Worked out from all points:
|   slope of the pulldown table from 0 to 0.27 V, typ, clamps not added: 105 ohm
|   slope of the pullup table from 0 to 0.27 V, typ, clamps not added: 152 ohm
|   GND clamp passes 1 mA (typ) near -0.37 V on its own axis
|   POWER clamp passes 1 mA (typ) near -0.42 V on its own axis
|   rising waveform, R_fixture 50.000, V_fixture 0.000: 20-80 % time 5.47ns typ, 4.91ns min, 5.21ns max; typ from 0 V to 0.22 V
|   rising waveform, R_fixture 50.000, V_fixture 1.800: 20-80 % time 261ps typ, 278ps min, 241ps max; typ from 1.57 V to 1.8 V
|   falling waveform, R_fixture 50.000, V_fixture 1.800: 20-80 % time 4.04ns typ, 4.47ns min, 4.43ns max; typ from 1.8 V to 1.57 V
|   falling waveform, R_fixture 50.000, V_fixture 0.000: 20-80 % time 323ps typ, 359ps min, 330ps max; typ from 0.22 V to 0 V
[GND_clamp]
|Voltage   I(typ)   I(min)   I(max)
-1.8V     -665.5mA   -701.9mA   -644.7mA
-1.208V   -203.2mA   -259.3mA   -168.6mA
-1.171V   -176.5mA   -233.3mA   -141.8mA
-1.134V   -150.7mA   -207.7mA   -116.3mA
-1.06V    -102.3mA   -158.3mA   -71.8mA
-1.023V   -80.78mA   -134.8mA   -54.83mA
-986mV    -61.78mA   -112.4mA   -42.93mA
-875mV    -26.33mA   -55.53mA   -29.29mA
-764mV    -16.38mA   -21.41mA   -21.4mA
-616mV    -8.858mA   -7.288mA   -11.79mA
-283mV    -142.7uA   -287uA     -113.6uA
1.8V      0A         0A         0A
[POWER_clamp]
|Voltage   I(typ)   I(min)   I(max)
-1.8V     138.7mA    103.3mA    171.3mA
-1.678V   127mA      95.65mA    157.2mA
-1.53V    111.7mA    85.11mA    138.4mA
-1.345V   91.17mA    70.52mA    113.2mA
-938mV    44.71mA    36.47mA    55.67mA
-753mV    25.22mA    21.78mA    30.82mA
-605mV    11.26mA    11.4mA     13.08mA
-494mV    3.49mA     5.157mA    3.227mA
-457mV    1.898mA    3.519mA    1.512mA
-383mV    542.5uA    1.315mA    536.2uA
-235mV    73.61uA    152.3uA    57.83uA
1.8V      0A         0A         0A
[Pulldown]
|Voltage   I(typ)   I(min)   I(max)
-1.8V     -1.023A    -1.199A    -1.31A
-1.14V    -222.4mA   -344.6mA   -222.3mA
-1.03V    -113.2mA   -218.6mA   -90.97mA
-975mV    -71.04mA   -161.9mA   -55.48mA
-920mV    -42.35mA   -112mA     -41.66mA
-865mV    -27.27mA   -71.92mA   -36.05mA
-755mV    -17.88mA   -26.29mA   -27.26mA
-645mV    -12.94mA   -12.68mA   -19.14mA
-260mV    -2.838mA   -2.717mA   -2.912mA
2.215V    6.236mA    6.049mA    6.236mA
2.765V    26.66mA    25.86mA    26.66mA
3.6V      73.71mA    71.5mA     73.71mA
[Pullup]
|Voltage   I(typ)   I(min)   I(max)
-1.8V     64.13mA    48.54mA    78.9mA
-910mV    20.55mA    15.86mA    25.57mA
-415mV    4.154mA    3.826mA    4.468mA
520mV     -3.053mA   -2.961mA   -3.053mA
2.06V     -4.457mA   -4.323mA   -4.457mA
2.28V     -6.921mA   -6.713mA   -6.921mA
2.555V    -16.01mA   -15.53mA   -16.01mA
2.665V    -24.11mA   -23.39mA   -24.11mA
2.72V     -37.19mA   -36.07mA   -37.19mA
2.775V    -62.11mA   -60.25mA   -62.11mA
2.83V     -98.7mA    -95.7mA    -98.7mA
3.6V      -890.9mA   -864.2mA   -890.9mA
[Ramp]
| variable   typ   min   max
dV/dt_r   0.132/5.478n   0.128/4.907n   0.132/5.203n
dV/dt_f   0.136/4.050n   0.133/4.479n   0.136/4.437n
R_load = 50.000
[Rising Waveform]
R_fixture = 50.000
V_fixture = 0.000
V_fixture_min = 0.000
V_fixture_max = 0.000
|  time   V(typ)   V(min)   V(max)
0s        42.3uV     -194.3uV   289.1uV
354ps     -15.16uV   -323.7uV   1.497mV
407ps     97.38uV    -356.9uV   -45.75mV
478ps     -1.262mV   -251.2uV   -51.84mV
596ps     -36.81mV   -127.6uV   -10.21mV
705ps     -12.08mV   -28.63uV   8.118mV
824ps     1.786mV    -41.47mV   14.73mV
984ps     8.087mV    -5.898mV   20.17mV
9.376ns   184.3mV    191mV      206.3mV
20ns      220.1mV    213.5mV    220.2mV
[Rising Waveform]
R_fixture = 50.000
V_fixture = 1.800
V_fixture_min = 1.710
V_fixture_max = 1.890
|  time   V(typ)   V(min)   V(max)
0s        1.573V     1.49V      1.663V
363ps     1.573V     1.489V     1.661V
444ps     1.573V     1.49V      1.733V
530ps     1.618V     1.49V      1.612V
665ps     1.556V     1.49V      1.753V
834ps     1.677V     1.518V     1.838V
944ps     1.732V     1.488V     1.861V
1.234ns   1.783V     1.637V     1.884V
1.488ns   1.794V     1.689V     1.89V
20ns      1.8V       1.71V      1.89V
[Falling Waveform]
R_fixture = 50.000
V_fixture = 1.800
V_fixture_min = 1.710
V_fixture_max = 1.890
|  time   V(typ)   V(min)   V(max)
0s        1.8V       1.71V      1.89V
435ps     1.8V       1.71V      1.894V
501ps     1.802V     1.71V      1.941V
681ps     1.827V     1.71V      1.909V
811ps     1.812V     1.713V     2.004V
1.109ns   1.862V     1.723V     1.902V
1.581ns   1.79V      1.753V     1.86V
2.422ns   1.758V     1.693V     1.832V
8.16ns    1.584V     1.529V     1.671V
20ns      1.573V     1.49V      1.663V
[Falling Waveform]
R_fixture = 50.000
V_fixture = 0.000
V_fixture_min = 0.000
V_fixture_max = 0.000
|  time   V(typ)   V(min)   V(max)
0s        220.1mV    213.5mV    220.2mV
367ps     219.9mV    213.3mV    227.2mV
444ps     226.3mV    213.3mV    178.4mV
492ps     226.3mV    213.3mV    181.2mV
623ps     169.5mV    215.8mV    91.62mV
717ps     116.1mV    225.3mV    65.26mV
908ps     42.54mV    141.1mV    24.12mV
1.303ns   5.931mV    24.51mV    -180.3uV
2.197ns   -983.4uV   -953.3uV   -1.151mV
20ns      42.3uV     -194.3uV   289.1uV
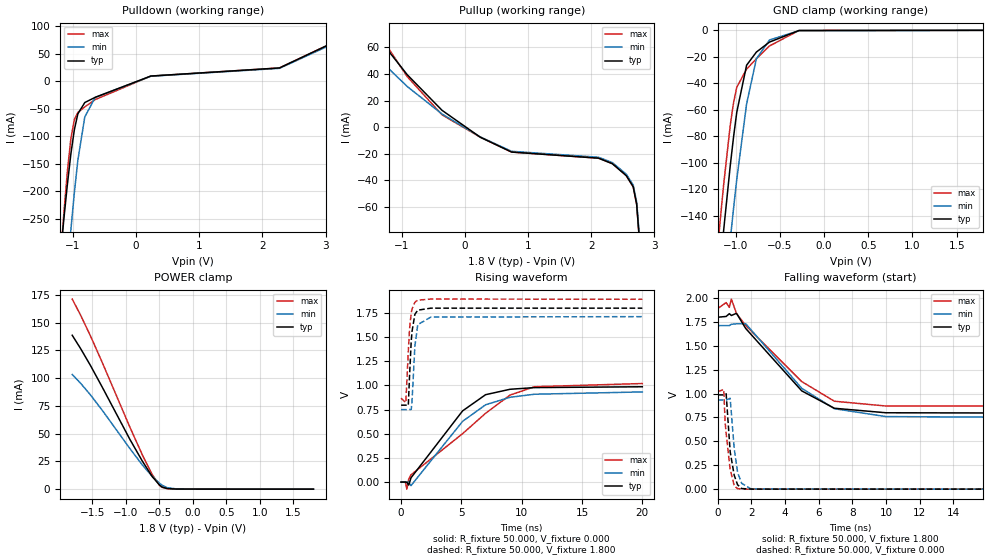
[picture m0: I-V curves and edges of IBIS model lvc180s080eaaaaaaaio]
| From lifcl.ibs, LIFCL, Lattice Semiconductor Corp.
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[Model] lvc180s080eaaaaaaaio
Model_type I/O
Polarity   Non-Inverting
Enable   Active-Low
Vinl =  0.630V
Vinh =  1.170V
Vmeas =  0.900V
Cref =  0.0F
Rref =  1.000M
Vref =  0.0V
C_comp   5.000pF   4.000pF   5.500pF
[Temperature Range]   25.000   0.125k   -40.000
[Voltage Range]   1.800V   1.710V   1.890V
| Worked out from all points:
|   slope of the pulldown table from 0 to 0.27 V, typ, clamps not added: 25.1 ohm
|   slope of the pullup table from 0 to 0.27 V, typ, clamps not added: 32.6 ohm
|   GND clamp passes 1 mA (typ) near -0.37 V on its own axis
|   POWER clamp passes 1 mA (typ) near -0.42 V on its own axis
|   rising waveform, R_fixture 50.000, V_fixture 0.000: 20-80 % time 3.79ns typ, 4.1ns min, 5.83ns max; typ from 0 V to 0.987 V
|   rising waveform, R_fixture 50.000, V_fixture 1.800: 20-80 % time 267ps typ, 286ps min, 290ps max; typ from 0.796 V to 1.8 V
|   falling waveform, R_fixture 50.000, V_fixture 1.800: 20-80 % time 3.13ns typ, 3.18ns min, 3.55ns max; typ from 1.8 V to 0.796 V
|   falling waveform, R_fixture 50.000, V_fixture 0.000: 20-80 % time 324ps typ, 330ps min, 330ps max; typ from 0.987 V to 0 V
[GND_clamp]
|Voltage   I(typ)   I(min)   I(max)
-1.8V     -665.5mA   -701.9mA   -644.7mA
-1.208V   -203.2mA   -259.3mA   -168.6mA
-1.171V   -176.5mA   -233.3mA   -141.8mA
-1.134V   -150.7mA   -207.7mA   -116.3mA
-1.06V    -102.3mA   -158.3mA   -71.8mA
-1.023V   -80.78mA   -134.8mA   -54.83mA
-986mV    -61.78mA   -112.4mA   -42.93mA
-875mV    -26.33mA   -55.53mA   -29.29mA
-764mV    -16.38mA   -21.41mA   -21.4mA
-616mV    -8.858mA   -7.288mA   -11.79mA
-283mV    -142.7uA   -287uA     -113.6uA
1.8V      0A         0A         0A
[POWER_clamp]
|Voltage   I(typ)   I(min)   I(max)
-1.8V     138.7mA    103.3mA    171.3mA
-1.678V   127mA      95.65mA    157.2mA
-1.53V    111.7mA    85.11mA    138.4mA
-1.345V   91.17mA    70.52mA    113.2mA
-938mV    44.71mA    36.47mA    55.67mA
-753mV    25.22mA    21.78mA    30.82mA
-605mV    11.26mA    11.4mA     13.08mA
-494mV    3.49mA     5.157mA    3.227mA
-457mV    1.898mA    3.519mA    1.512mA
-383mV    542.5uA    1.315mA    536.2uA
-235mV    73.61uA    152.3uA    57.83uA
1.8V      0A         0A         0A
[Pulldown]
|Voltage   I(typ)   I(min)   I(max)
-1.8V     -1.123A    -1.448A    -1.379A
-1.195V   -315.4mA   -500.8mA   -322.9mA
-1.14V    -249.2mA   -420.7mA   -238.5mA
-1.085V   -187mA     -343.4mA   -163mA
-1.03V    -131.9mA   -270mA     -104mA
-975mV    -88.04mA   -202.5mA   -69.67mA
-920mV    -59.22mA   -143.8mA   -56.86mA
-810mV    -38.63mA   -64.77mA   -46.55mA
-645mV    -29.15mA   -29.22mA   -33.27mA
235mV     9.566mA    9.279mA    9.566mA
2.27V     24.3mA     23.57mA    24.3mA
3.6V      96.4mA     93.5mA     96.4mA
[Pullup]
|Voltage   I(typ)   I(min)   I(max)
-1.8V     92.7mA     71.09mA    101.5mA
-910mV    39.29mA    30.46mA    37.85mA
-360mV    12.6mA     9.83mA     9.214mA
245mV     -7.574mA   -7.347mA   -7.574mA
740mV     -18.71mA   -18.15mA   -18.71mA
2.115V    -23.29mA   -22.6mA    -23.29mA
2.335V    -27.43mA   -26.61mA   -27.43mA
2.555V    -36.39mA   -35.3mA    -36.39mA
2.665V    -44.81mA   -43.47mA   -44.81mA
2.72V     -58.07mA   -56.33mA   -58.07mA
2.83V     -125.8mA   -122mA     -125.8mA
3.6V      -1.06A     -1.028A    -1.06A
[Ramp]
| variable   typ   min   max
dV/dt_r   0.592/3.795n   0.560/4.120n   0.612/5.831n
dV/dt_f   0.602/3.125n   0.577/3.181n   0.614/3.556n
R_load = 50.000
[Rising Waveform]
R_fixture = 50.000
V_fixture = 0.000
V_fixture_min = 0.000
V_fixture_max = 0.000
|  time   V(typ)   V(min)   V(max)
0s        66.63uV    -469.7uV   428.7uV
355ps     61.74uV    -730.1uV   2.389mV
480ps     -2.076mV   -489.7uV   -73.09mV
634ps     -30.91mV   -244.9uV   29.96mV
824ps     44.51mV    -36.4mV    75.64mV
5.1ns     736.8mV    628.9mV    501mV
7.01ns    904.7mV    800.4mV    712.4mV
9.034ns   960.5mV    877.7mV    900.3mV
11.06ns   977.9mV    909.2mV    987mV
20ns      986.6mV    933.2mV    1.02V
[Rising Waveform]
R_fixture = 50.000
V_fixture = 1.800
V_fixture_min = 1.710
V_fixture_max = 1.890
|  time   V(typ)   V(min)   V(max)
0s        796mV      750.1mV    868.6mV
393ps     796.1mV    749.8mV    822mV
600ps     792.6mV    750.3mV    1.349V
704ps     1.1V       751.2mV    1.586V
844ps     1.462V     751.6mV    1.75V
904ps     1.555V     826.2mV    1.79V
1.145ns   1.736V     1.405V     1.861V
1.384ns   1.779V     1.629V     1.883V
2.474ns   1.8V       1.708V     1.894V
20ns      1.8V       1.712V     1.892V
[Falling Waveform]
R_fixture = 50.000
V_fixture = 1.800
V_fixture_min = 1.710
V_fixture_max = 1.890
|  time   V(typ)   V(min)   V(max)
0s        1.8V       1.712V     1.892V
495ps     1.808V     1.712V     1.953V
685ps     1.837V     1.712V     1.903V
804ps     1.818V     1.726V     1.99V
1.107ns   1.841V     1.731V     1.839V
1.657ns   1.682V     1.732V     1.713V
4.985ns   1.029V     1.056V     1.126V
6.927ns   846.6mV    841.9mV    920.3mV
10ns      799.4mV    759.4mV    870mV
20ns      796mV      750.1mV    868.6mV
[Falling Waveform]
R_fixture = 50.000
V_fixture = 0.000
V_fixture_min = 0.000
V_fixture_max = 0.000
|  time   V(typ)   V(min)   V(max)
0s        986.6mV    933.2mV    1.02V
349ps     986.3mV    932.9mV    1.044V
434ps     995mV      933mV      698.3mV
493ps     999.1mV    933mV      585.6mV
733ps     390.7mV    950.7mV    205.7mV
974ps     144.2mV    421mV      33.62mV
1.173ns   45.67mV    175.6mV    5.455mV
1.415ns   5.929mV    61.13mV    66.23uV
1.972ns   40.98uV    2.247mV    -513uV
20ns      66.63uV    -469.7uV   428.7uV
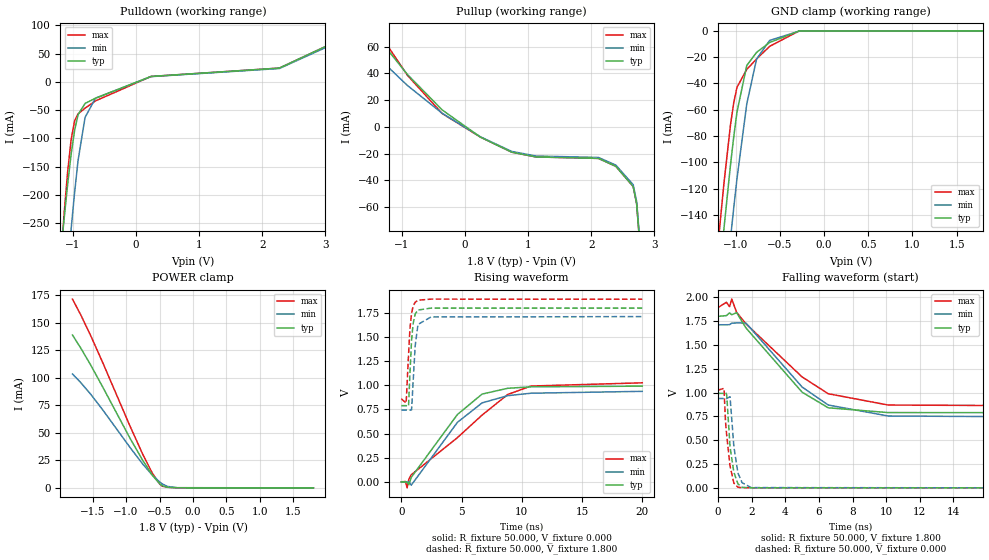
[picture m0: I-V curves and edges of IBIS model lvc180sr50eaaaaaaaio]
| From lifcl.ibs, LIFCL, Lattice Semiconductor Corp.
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[Model] lvc180sr50eaaaaaaaio
Model_type I/O
Polarity   Non-Inverting
Enable   Active-Low
Vinl =  0.630V
Vinh =  1.170V
Vmeas =  0.900V
Cref =  0.0F
Rref =  1.000M
Vref =  0.0V
C_comp   5.000pF   4.000pF   5.500pF
[Temperature Range]   25.000   0.125k   -40.000
[Voltage Range]   1.800V   1.710V   1.890V
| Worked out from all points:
|   slope of the pulldown table from 0 to 0.27 V, typ, clamps not added: 25 ohm
|   slope of the pullup table from 0 to 0.27 V, typ, clamps not added: 32.4 ohm
|   GND clamp passes 1 mA (typ) near -0.37 V on its own axis
|   POWER clamp passes 1 mA (typ) near -0.42 V on its own axis
|   rising waveform, R_fixture 50.000, V_fixture 0.000: 20-80 % time 3.66ns typ, 3.83ns min, 5.66ns max; typ from 0 V to 0.992 V
|   rising waveform, R_fixture 50.000, V_fixture 1.800: 20-80 % time 266ps typ, 284ps min, 278ps max; typ from 0.789 V to 1.8 V
|   falling waveform, R_fixture 50.000, V_fixture 1.800: 20-80 % time 3.02ns typ, 3.23ns min, 3.87ns max; typ from 1.8 V to 0.789 V
|   falling waveform, R_fixture 50.000, V_fixture 0.000: 20-80 % time 323ps typ, 325ps min, 342ps max; typ from 0.992 V to 0 V
[GND_clamp]
|Voltage   I(typ)   I(min)   I(max)
-1.8V     -665.5mA   -701.9mA   -644.7mA
-1.208V   -203.2mA   -259.3mA   -168.6mA
-1.171V   -176.5mA   -233.3mA   -141.8mA
-1.134V   -150.7mA   -207.7mA   -116.3mA
-1.06V    -102.3mA   -158.3mA   -71.8mA
-1.023V   -80.78mA   -134.8mA   -54.83mA
-986mV    -61.78mA   -112.4mA   -42.93mA
-875mV    -26.33mA   -55.53mA   -29.29mA
-764mV    -16.38mA   -21.41mA   -21.4mA
-616mV    -8.858mA   -7.288mA   -11.79mA
-283mV    -142.7uA   -287uA     -113.6uA
1.8V      0A         0A         0A
[POWER_clamp]
|Voltage   I(typ)   I(min)   I(max)
-1.8V     138.7mA    103.3mA    171.3mA
-1.678V   127mA      95.65mA    157.2mA
-1.53V    111.7mA    85.11mA    138.4mA
-1.345V   91.17mA    70.52mA    113.2mA
-938mV    44.71mA    36.47mA    55.67mA
-753mV    25.22mA    21.78mA    30.82mA
-605mV    11.26mA    11.4mA     13.08mA
-494mV    3.49mA     5.157mA    3.227mA
-457mV    1.898mA    3.519mA    1.512mA
-383mV    542.5uA    1.315mA    536.2uA
-235mV    73.61uA    152.3uA    57.83uA
1.8V      0A         0A         0A
[Pulldown]
|Voltage   I(typ)   I(min)   I(max)
-1.8V     -1.08A     -1.388A    -1.33A
-1.195V   -303.6mA   -480.3mA   -311.8mA
-1.14V    -239.9mA   -403.5mA   -230.5mA
-1.085V   -180.2mA   -329.4mA   -157.9mA
-1.03V    -127.4mA   -259.2mA   -101.4mA
-975mV    -85.32mA   -194.6mA   -68.58mA
-920mV    -57.77mA   -138.3mA   -56.42mA
-810mV    -38.12mA   -62.78mA   -46.5mA
-645mV    -28.94mA   -28.78mA   -33.65mA
235mV     9.585mA    9.298mA    9.585mA
2.27V     24.38mA    23.65mA    24.38mA
3.6V      93.7mA     90.9mA     93.7mA
[Pullup]
|Voltage   I(typ)   I(min)   I(max)
-1.8V     91.5mA     70.91mA    100.9mA
-910mV    39.09mA    30.91mA    38.48mA
-360mV    12.66mA    10.15mA    9.954mA
245mV     -7.622mA   -7.393mA   -7.622mA
740mV     -18.86mA   -18.3mA    -18.86mA
1.125V    -22.44mA   -21.77mA   -22.44mA
2.115V    -23.52mA   -22.82mA   -23.52mA
2.39V     -29.43mA   -28.54mA   -29.43mA
2.665V    -44.52mA   -43.19mA   -44.52mA
2.72V     -57.41mA   -55.69mA   -57.41mA
2.83V     -123.4mA   -119.7mA   -123.4mA
3.6V      -1.037A    -1.006A    -1.037A
[Ramp]
| variable   typ   min   max
dV/dt_r   0.595/3.664n   0.563/3.830n   0.615/5.668n
dV/dt_f   0.606/3.024n   0.581/3.238n   0.618/3.871n
R_load = 50.000
[Rising Waveform]
R_fixture = 50.000
V_fixture = 0.000
V_fixture_min = 0.000
V_fixture_max = 0.000
|  time   V(typ)   V(min)   V(max)
0s        66.03uV    -521.6uV   750.4uV
351ps     55.77uV    -815.7uV   3.137mV
480ps     -2.061mV   -547.6uV   -62.26mV
634ps     -29.63mV   -254.3uV   29.92mV
824ps     46.3mV     -34.81mV   72.97mV
4.662ns   698.5mV    617mV      458.6mV
6.71ns    909.5mV    818.4mV    692.3mV
8.84ns    969.5mV    893.1mV    905.4mV
10.76ns   984.3mV    918.2mV    992.5mV
20ns      991.6mV    937.7mV    1.026V
[Rising Waveform]
R_fixture = 50.000
V_fixture = 1.800
V_fixture_min = 1.710
V_fixture_max = 1.890
|  time   V(typ)   V(min)   V(max)
0s        789.2mV    744.2mV    861.1mV
401ps     789.4mV    743.8mV    815.2mV
600ps     783.6mV    744.4mV    1.316V
714ps     1.112V     743.2mV    1.583V
853ps     1.471V     745.6mV    1.748V
984ps     1.64V      1.045V     1.821V
1.154ns   1.739V     1.411V     1.861V
1.384ns   1.78V      1.631V     1.882V
2.463ns   1.8V       1.708V     1.893V
20ns      1.8V       1.712V     1.892V
[Falling Waveform]
R_fixture = 50.000
V_fixture = 1.800
V_fixture_min = 1.710
V_fixture_max = 1.890
|  time   V(typ)   V(min)   V(max)
0s        1.8V       1.712V     1.892V
494ps     1.808V     1.712V     1.948V
684ps     1.837V     1.713V     1.902V
814ps     1.817V     1.729V     1.981V
1.105ns   1.839V     1.731V     1.842V
1.661ns   1.678V     1.73V      1.721V
5ns       1.004V     1.058V     1.164V
6.554ns   839.9mV    869.3mV    987.7mV
10.12ns   789.9mV    753.9mV    869.1mV
20ns      789.2mV    744.2mV    861.1mV
[Falling Waveform]
R_fixture = 50.000
V_fixture = 0.000
V_fixture_min = 0.000
V_fixture_max = 0.000
|  time   V(typ)   V(min)   V(max)
0s        991.6mV    937.7mV    1.026V
354ps     991.2mV    937.4mV    1.044V
441ps     1.002V     937.5mV    698.2mV
514ps     977.7mV    937.4mV    549.2mV
711ps     429.8mV    956.7mV    228.9mV
941ps     162mV      431mV      49.17mV
1.182ns   41.55mV    154.5mV    6.055mV
1.432ns   4.939mV    53.61mV    592.5uV
1.971ns   60.49uV    2.08mV     -16.79uV
20ns      66.03uV    -521.6uV   750.4uV
